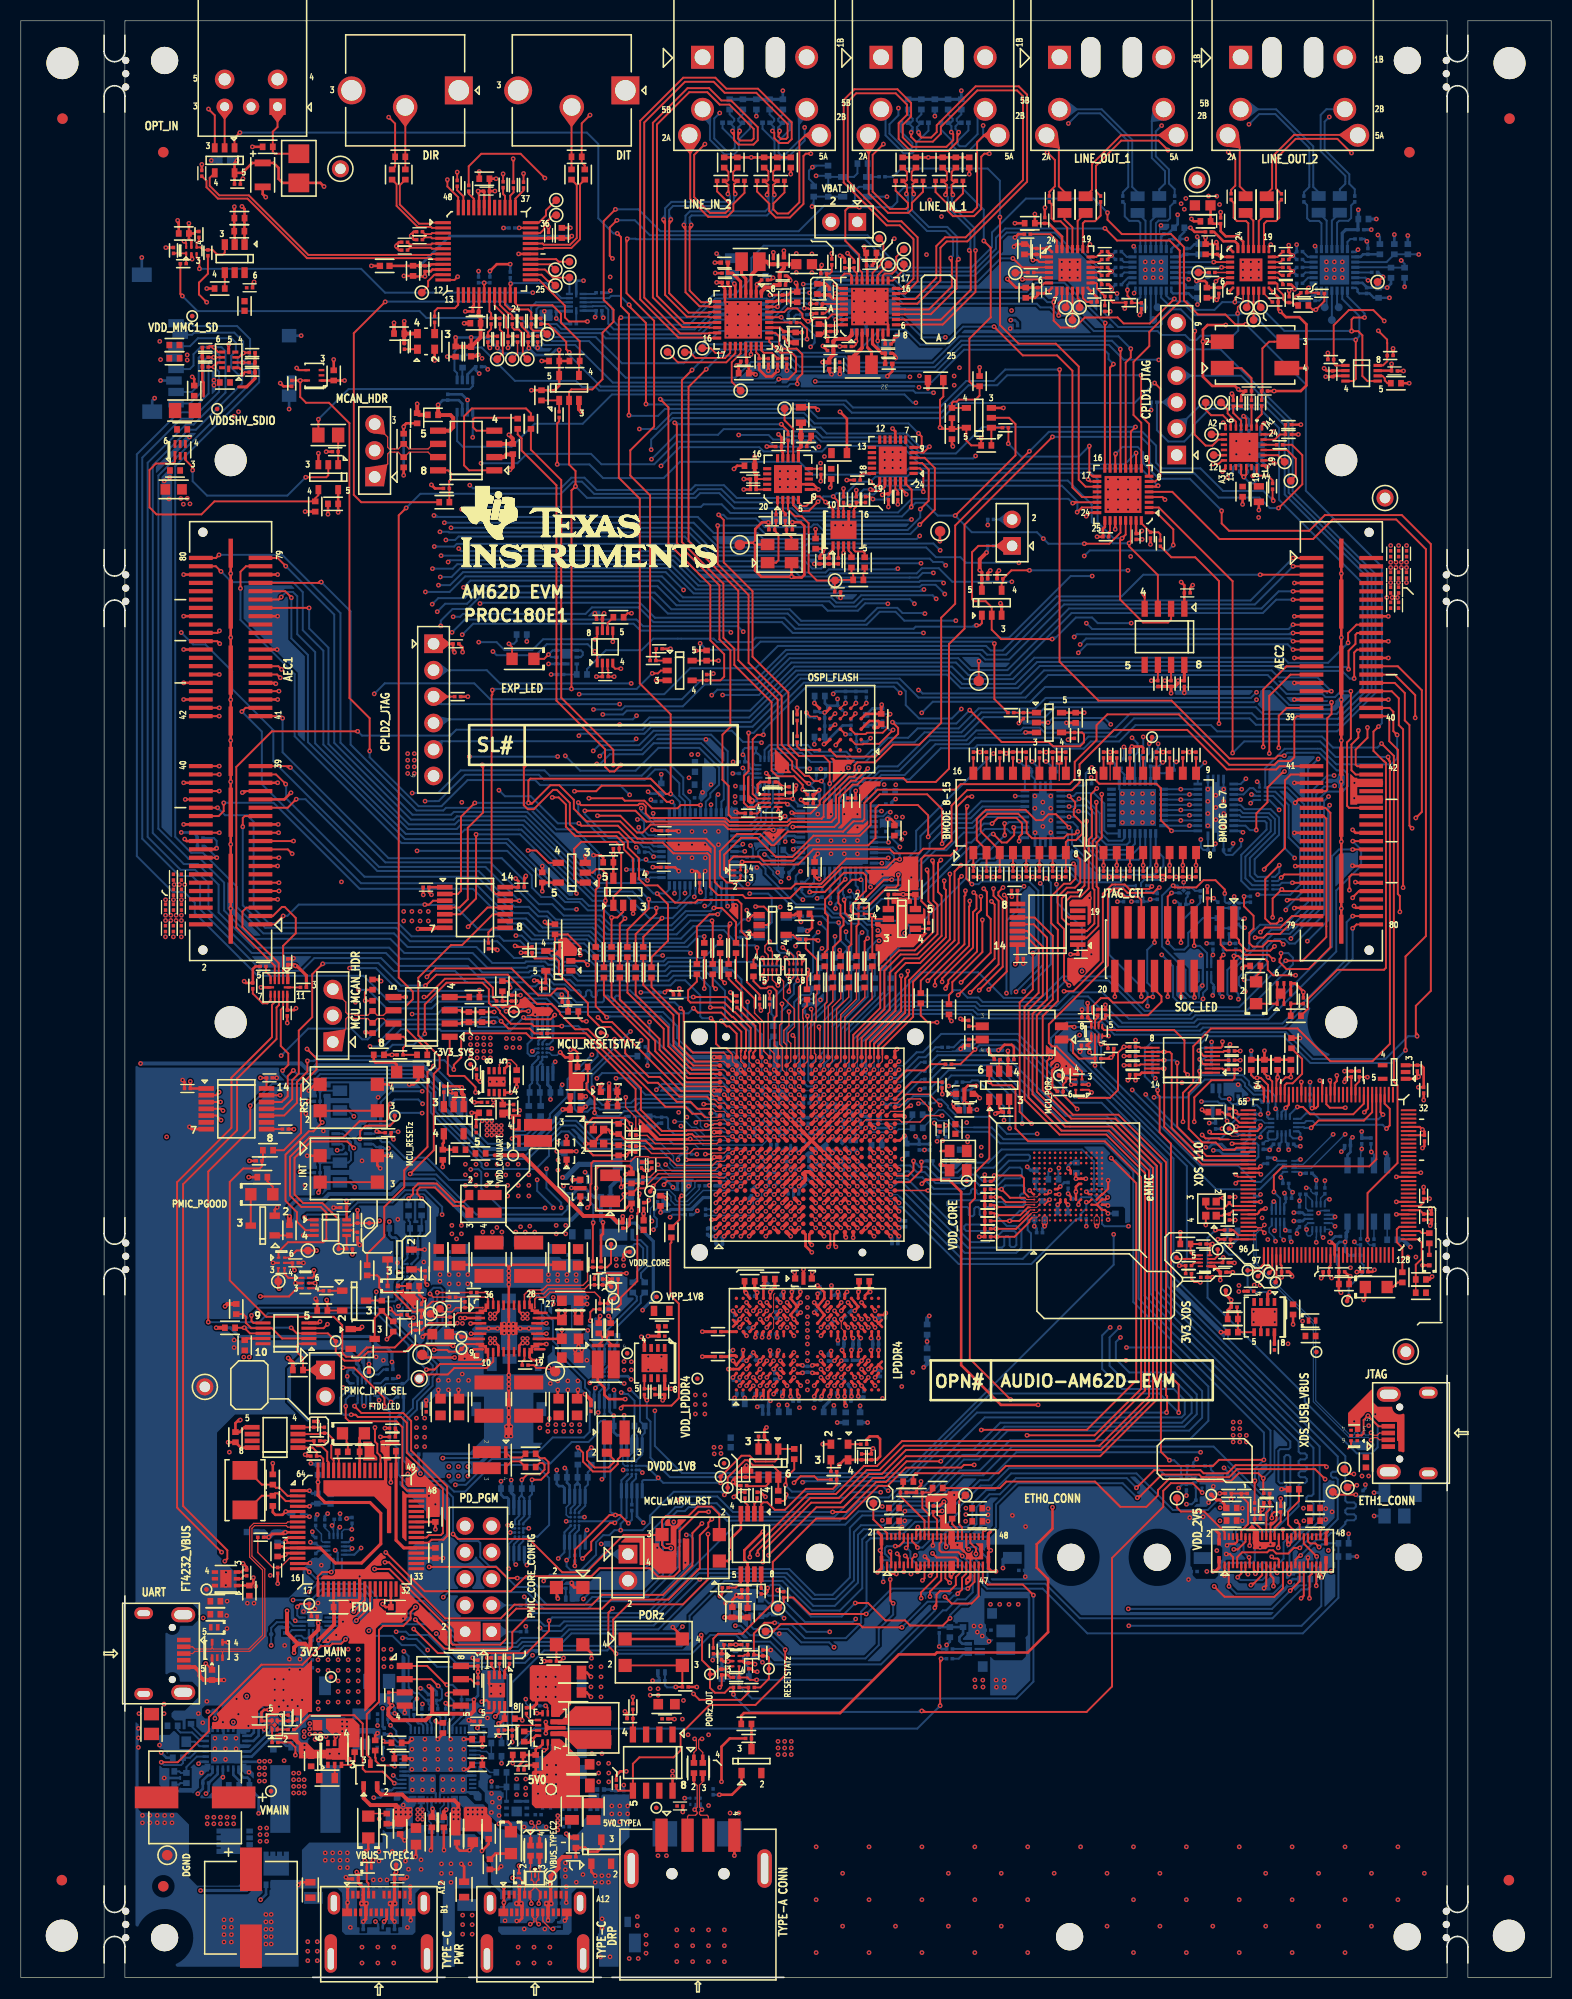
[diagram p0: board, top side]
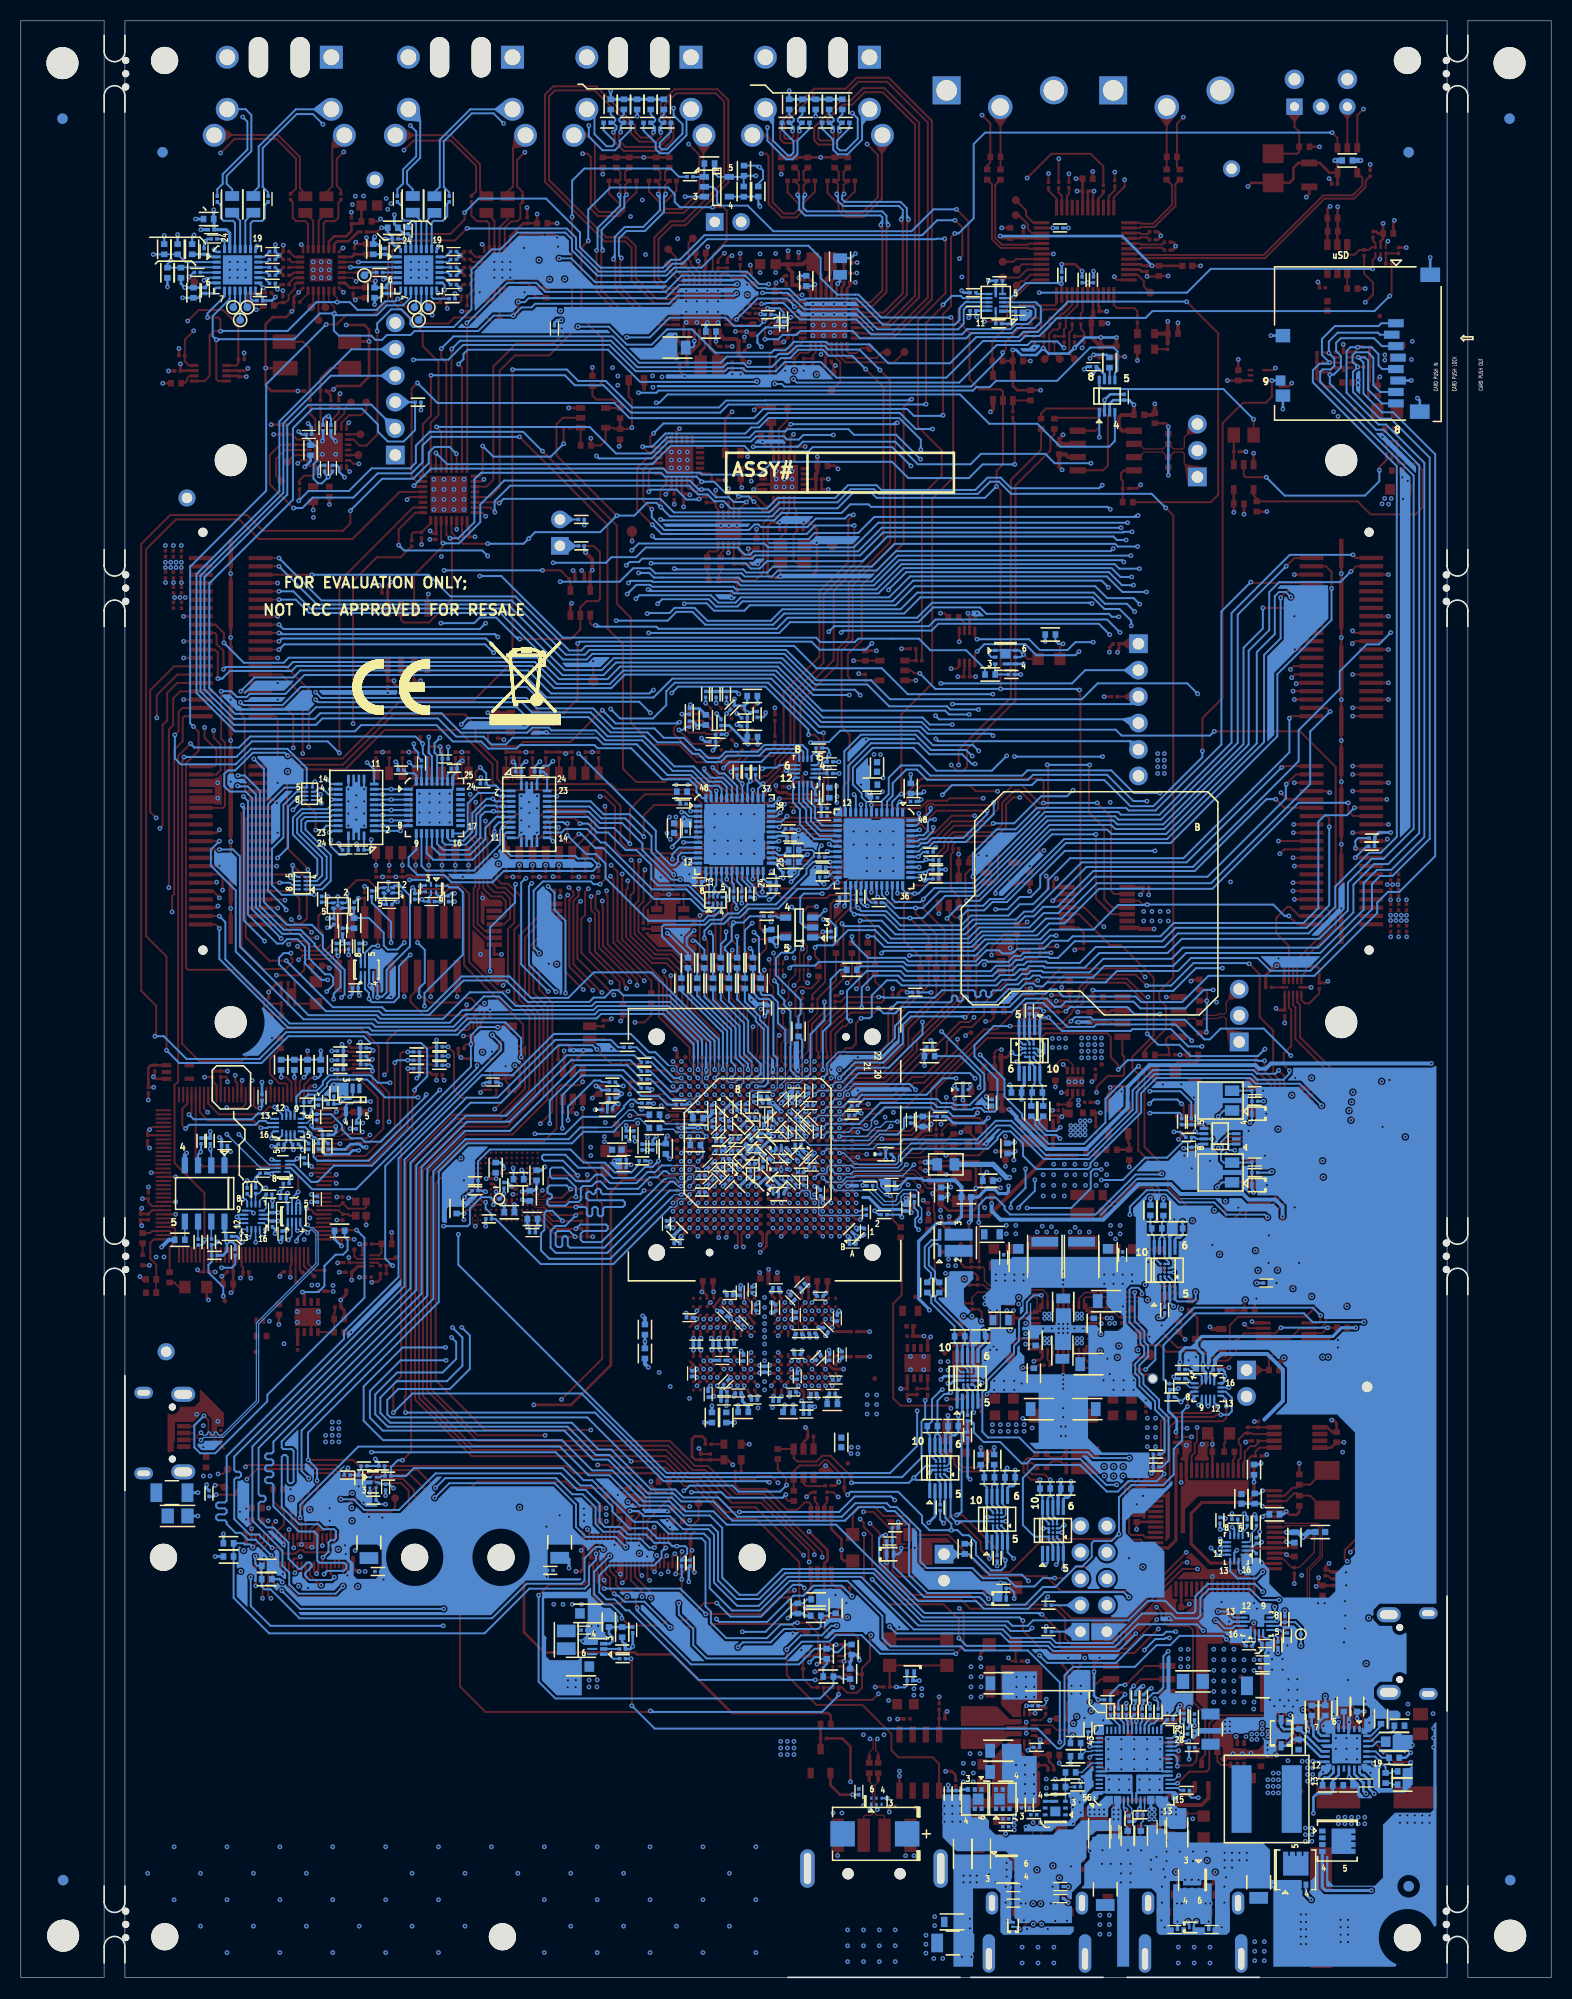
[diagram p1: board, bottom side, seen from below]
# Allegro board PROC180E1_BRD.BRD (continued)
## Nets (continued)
VCC3V3_TA: C136.1 C236.2 C391.2 C393.2 C394.2 C409.2 C529.2 R126.2 R127.2 R128.2 R129.2 R130.2 R131.2 R132.2 R133.2 R134.2 R135.2 R136.2 R137.2 R138.2 R139.2 R140.2 R141.2 R285.1 R439.2 R457.2 R461.2 R507.1 R511.1 R513.1 R516.1 R524.1 R526.1 R578.2 R582.1 R583.1 R643.2 U23.5(VCC) U51.8(VCCB) U81.1(VCCA) U82.27(VCCP) U82.31(VCC) U83.1(VCCA) U107.8(VCCB)
VCC3V3_XDS: C147.1 C192.1 C208.1 C221.1 C222.1 C231.2 C232.1 C234.1 C235.2 C241.1 C243.1 C430.2 C469.2 C473.2 C488.1 C500.2 C515.2 R118.1 R119.1 R236.1 R237.1 R241.1 R246.2 R277.2 R280.1 R306.1 R510.1 R512.1 R515.1 R517.1 R519.1 R520.2 R521.2 R522.2 R523.2 R525.1 R549.2 R551.1 R552.1 TP68.1(TP) U25.8(VCCB) U40.14(VCC) U48.7(VDD#7) U48.8(VDDA) U48.16(VDD#16) U48.26(VDD#26) U48.28(VDD#28) U48.39(VDD#39) U48.47(VDD#47) U48.51(VDD#51) U48.52(VDD#52) U48.69(VDD#69) U48.79(VDD#79) U48.90(VDD#90) U48.101(VDD#101) U48.113(VDD#113) U48.122(VDD#122) U51.1(VCCA) U55.3(OUT1) U55.4(OUT2) U97.2(VCCB) U102.8(VCCB) U107.1(VCCA) U109.8(VCCB)
VCC_0V85: C246.1 R587.1 U56.25(VOUT_LDO3)
VCC_1V8_FT4232: C263.1 C280.2 C281.2 C599.2 U64.12(VCORE#12) U64.37(VCORE#37) U64.49(VREGOUT) U64.64(VCORE#64)
VCC_1V8_IOVDD: C71.1 C74.1 C84.1 C85.1 C109.1 C166.1 C173.1 C340.1 C418.1 R20.1 R23.1 R60.1 R62.1 R67.1 R78.2 R90.2 R162.1 R413.2 R416.2 U7.27(IOVDD) U8.27(IOVDD) U14.5(VCC) U33.5(VCC) U35.5(VCC) U75.5(VCC) U89.5(VCC)
VCC_3V3_AVDD: C52.1 C53.2 C63.1 C68.1 C86.1 C90.1 C97.2 C98.1 FL2.2 L2.1 L3.1 U7.1(AVDD) U7.3(BSTVDD) U8.1(AVDD) U8.3(BSTVDD)
VCC_3V3_FT4232: C262.2 C264.2 C275.2 C285.1 C288.2 C289.2 C575.2 C612.2 C618.2 FL17.2 FL18.2 LD7.2(ANODE) R321.2 R328.2 R333.2 U61.8(VCC) U64.20(VCCIO#20) U64.31(VCCIO#31) U64.42(VCCIO#42) U64.50(VREGIN) U64.56(VCCIO#56) U66.1(OUT) U117.2(VCCB) U125.2(VCCB) U126.2(VCCB)
VCC_3V3_MAIN: C197.1 C199.2 C204.1 C230.2 C253.1 C255.1 C538.1 C546.1 C547.1 C555.1 C561.1 C565.1 C572.1 C576.1 C619.2 C621.2 C624.1 FL15.1 R240.1 R282.1 R302.2 R318.2 R371.1 R643.1 R659.2 R663.2 R668.2 TP80.1(TP) TP102.1(TP) U42.1(VIN1) U42.2(VIN2) U42.4(VBIAS) U46.1(IN) U52.5(VCC) U54.5(VCC) U56.3(VCCA) U56.12(PVIN_B3) U56.16(PVIN_B4) U56.18(VIO) U56.20(PVIN_LDO12) U56.30(PVIN_B2) U56.34(PVIN_B1) U57.10(VCC) U59.8(IN)
VCC_3V3_MAIN_PG: R640.1 R668.1 U54.3(B) U128.21(PG)
VCC_3V3_SYS: C28.1 C33.2 C37.1 C99.1 C113.1 C122.2 C123.1 C126.2 C127.1 C131.1 C132.1 C140.1 C143.1 C145.1 C150.2 C152.1 C153.1 C154.1 C156.1 C159.1 C165.2 C169.1 C178.1 C181.2 C183.1 C184.2 C185.2 C186.2 C187.2 C189.2 C191.2 C194.1 C268.2 C271.1 C274.1 C277.1 C279.1 C293.1 C298.1 C375.1 C377.1 C380.1 C392.2 C398.1 C399.1 C402.1 C403.1 C411.1 C413.1 C414.2 C415.2 C416.2 C419.2 C420.2 C427.1 C455.2 C470.2 C478.2 C498.1 C504.1 C511.2 C519.2 C520.1 C523.2 C525.1 C528.2 C560.1 C598.1 C601.1 C602.1 C604.1 C620.1 FL1.1 FL2.1 FL3.1 J8.1 J11.1 J14.5 J18.44 J18.46 J19.44 J19.46 R17.2 R18.2 R56.1 R58.1 R91.2 R92.2 R98.2 R99.1 R106.2 R115.1 R120.1 R142.1 R180.2 R211.1 R212.1 R220.1 R222.1 R225.1 R251.3 R259.1 R260.2 R288.1 R291.1 R292.2 R301.1 R324.2 R339.1 R342.1 R343.2 R344.1 R347.1 R351.2 R353.1 R354.1 R356.1 R360.1 R362.2 R363.2 R368.1 R396.1 R437.1 R440.2 R455.2 R459.1 R460.1 R469.1 R471.1 R473.1 R480.1 R482.1 R485.2 R533.2 R534.2 R536.2 R550.1 R554.2 R559.1 R597.2 R598.1 R601.2 R602.2 R603.1 R615.1 R616.2 R617.2 R620.2 R625.2 R629.2 R630.2 R638.2 R641.2 R645.1 TP48.1(TP) U2.5(VCC) U4.1(VIN) U11.7(VCCB) U17.3(VCC) U18.21(VCCP) U18.23(VCCI) U19.5(VCC) U21.27(VCCP) U21.31(VCC) U22.1(VDD) U22.3(VREF) U24.7(VCCB) U25.1(VCCA) U29.1(VCCA) U32.14(VCCB) U34.14(VCCB) U36.5(VCC) U37.11(VCCB) U38.3(VCC) U38.5(SHDN/VIO) U39.1(VCCA) U39.8(VCCB) U42.7(VOUT1) U42.8(VOUT2) U44.4(V+) U45.14(VCCB) U49.E6(VCC#E6) U49.F5(VCC#F5) U49.J10(VCC#J10) U49.K9(VCC#K9) U56.9(VMON1) U63.4(V+) U68.5(VCC) U70.8(VCC) U78.11(VCCB) U79.7(VCCB) U80.3(VCCA) U84.1(VCC#1) U84.25(VCC#25) U84.39(VCCIO0#39) U84.46(VCCIO0#46) U85.1(VCC#1) U85.25(VCC#25) U85.39(VCCIO0#39) U85.46(VCCIO0#46) U86.5(VCC) U87.5(VCC) U88.5(VCC) U90.1(VCCA) U90.8(VCCB) U91.6(VS) U92.B1(VS) U93.5(VCC) U97.3(VCCA) U98.8(VCC) U102.1(VCCA) U109.1(VCCA) U110.2(VCCB) U110.3(VCCA) U113.B1(VS) U114.6(VS) U115.B1(VS) U115.B3(A0) U116.2(A0) U116.6(VS) U118.2(A0) U118.6(VS) U119.B1(VS) U119.B3(A0) U120.5(VCC) U121.B1(VS) U121.C3(A1) U122.1(A1) U122.6(VS) U123.B1(VS) U123.B3(A0) U123.C3(A1) U124.1(A1) U124.2(A0) U124.6(VS) U127.6(VIN)
VCC_3V3_SYS_EN: R244.2 R245.2 U42.3(ON)
VCC_3V3_SYS_N: R251.1 R539.2
VCC_3V3_SYS_P: R251.4 R540.2
VCC_5V0: C115.1 C119.1 C128.1 C129.1 C130.1 C133.1 C134.1 C135.1 C170.1 C171.1 C172.1 C174.1 C175.1 C176.1 C297.1 C299.1 C311.1 C313.1 C314.1 C317.1 C318.1 C630.1 C633.1 C639.1 J12.2 J12.4 J12.6 J13.2 J13.4 J13.6 Q9.4(D1) Q9.7(D2) R387.2 R392.1 R543.1 R665.1 R676.1 TP103.1(TP) U16.2(IN) U72.7(VOUT) U74.2(IN1) U74.3(IN2)
VCC_5V0_EN: R647.2 U72.14(EN)
VCC_5V0_FB: C313.2 R391.1 R392.2 U72.5(FB)
VCC_5V0_PG: R388.2 U86.3(B)
VCC_CORE: C226.1 C227.1 C228.1 C229.1 C532.1 C533.1 C534.1 C535.1 C536.1 C537.1 L4.2 L5.2 R265.4 R577.1
VCC_CORE_N: R265.2 R572.2
VCC_CORE_P: R265.3 R571.2
VCC_LM5141: C627.1 D15.2(ANODE) U128.10(VCC)
VCC_SDIO: C108.1 R77.1 U16.5(OUT2) U16.6(OUT1)
VDD1_LPDDR4_1V8: C237.1 C539.1 C543.2 C551.1 C554.1 C571.1 C578.1 C581.1 C588.1 C591.1 C594.2 C596.1 FL16.2 U58.F1(VDD1#F1) U58.F12(VDD1#F12) U58.G4(VDD1#G4) U58.G9(VDD1#G9) U58.T4(VDD1#T4) U58.T9(VDD1#T9) U58.U1(VDD1#U1) U58.U12(VDD1#U12)
VDD_0V85_N: R581.1 R585.2
VDD_0V85_P: R581.4 R584.2
VDD_1V8_N: R311.2 R316.4
VDD_1V8_P: R310.2 R316.1
VDD_2V5: C272.1 C273.1 C276.1 C278.1 C614.1 C615.1 C616.1 J18.4 J18.6 J19.4 J19.6 L11.2 R634.1 R637.2 TP92.1(TP)
VDD_2V5_FB: C615.2 R632.1 R634.2 U127.3(FB)
VDD_CANUART: C224.1 C499.1 R257.2 TP52.1(TP) U47.H9(VDD_CANUART)
VDD_CORE: C441.1 C445.1 C448.1 C460.1 C462.1 C468.1 C477.1 C494.1 C657.1(IN/OUT) C657.3(OUT/IN) C658.1(IN/OUT) C658.3(OUT/IN) C659.1(IN/OUT) C659.3(OUT/IN) C660.1(IN/OUT) C660.3(OUT/IN) C661.1(IN/OUT) C661.3(OUT/IN) C662.1(IN/OUT) C662.3(OUT/IN) C663.1(IN/OUT) C663.3(OUT/IN) FL7.1 FL8.1 FL14.2 R265.1 TP53.1(TP) U47.J9(VDD_CORE#J9) U47.J11(VDD_CORE#J11) U47.J13(VDD_CORE#J13) U47.J15(VDD_CORE#J15) U47.K14(VDD_CORE#K14) U47.L9(VDD_CORE#L9) U47.L11(VDD_CORE#L11) U47.L13(VDD_CORE#L13) U47.M12(VDD_CORE#M12) U47.N11(VDD_CORE#N11) U47.N13(VDD_CORE#N13) U47.P10(VDD_CORE#P10) U47.P14(VDD_CORE#P14) U47.R9(VDD_CORE#R9) U47.R15(VDD_CORE#R15) U47.T16(VDD_CORE#T16) U47.U15(VDD_CORE#U15) U56.4(FB_B1)
VDD_CORE_0V85: R577.2 R581.3 R587.2
VDD_CORE_ALERT: R586.1 U113.A3(ALERT) U114.3(ALERT)
VDD_CORE_N: C524.2 R572.1 U113.D1(BUS) U113.D2(IN-) U114.8(VBUS) U114.9(IN-)
VDD_CORE_P: C524.1 R571.1 U113.D3(IN+) U114.10(IN+)
VDD_CORE_REG_SW1: L4.1 U56.33(SW_B1)
VDD_CORE_REG_SW2: L5.1 U56.31(SW_B2)
VDD_LPDDR4: C238.1 C239.1 C522.1 C526.1 C530.1 C531.1 C540.1 C541.2 C542.1 C544.1 C545.2 C548.1 C549.1 C550.1 C552.1 C553.1 C556.1 C557.1 C558.1 C562.1 C563.1 C564.1 C566.1 C567.1 C568.1 C569.1 C570.1 C573.1 C577.1 C579.1 C580.1 C582.1 C583.1 C584.2 C585.1 C586.1 C587.2 C589.1 C590.1 C595.1 C664.1(IN/OUT) C664.3(OUT/IN) C665.1(IN/OUT) C665.3(OUT/IN) C666.1(IN/OUT) C666.3(OUT/IN) C667.1(IN/OUT) C667.3(OUT/IN) C668.1(IN/OUT) C668.3(OUT/IN) C669.1(IN/OUT) C669.3(OUT/IN) C670.1(IN/OUT) C670.3(OUT/IN) R312.1 R315.1 R327.4 R589.2 R594.2 R595.2 TP83.1(TP) U47.A2(VDDS_DDR#A2) U47.AA1(VDDS_DDR#AA1) U47.AB2(VDDS_DDR#AB2) U47.B1(VDDS_DDR#B1) U47.J7(VDDS_DDR#J7) U47.K8(VDDS_DDR#K8) U47.L7(VDDS_DDR#L7) U47.L8(VDDS_DDR_C) U47.M8(VDDS_DDR#M8) U47.N7(VDDS_DDR#N7) U47.P8(VDDS_DDR#P8) U56.22(FB_B4) U58.A4(VDD2#A4) U58.A9(VDD2#A9) U58.AA3(VDDQ#AA3) U58.AA5(VDDQ#AA5) U58.AA8(VDDQ#AA8) U58.AA10(VDDQ#AA10) U58.AB4(VDD2#AB4) U58.AB9(VDD2#AB9) U58.B3(VDDQ#B3) U58.B5(VDDQ#B5) U58.B8(VDDQ#B8) U58.B10(VDDQ#B10) U58.D1(VDDQ#D1) U58.D5(VDDQ#D5) U58.D8(VDDQ#D8) U58.D12(VDDQ#D12) U58.F3(VDDQ#F3) U58.F5(VDD2#F5) U58.F8(VDD2#F8) U58.F10(VDDQ#F10) U58.H1(VDD2#H1) U58.H5(VDD2#H5) U58.H8(VDD2#H8) U58.H12(VDD2#H12) U58.K1(VDD2#K1) U58.K3(VDD2#K3) U58.K10(VDD2#K10) U58.K12(VDD2#K12) U58.N1(VDD2#N1) U58.N3(VDD2#N3) U58.N10(VDD2#N10) U58.N12(VDD2#N12) U58.R1(VDD2#R1) U58.R5(VDD2#R5) U58.R8(VDD2#R8) U58.R12(VDD2#R12) U58.U3(VDDQ#U3) U58.U5(VDD2#U5) U58.U8(VDD2#U8) U58.U10(VDDQ#U10) U58.W1(VDDQ#W1) U58.W5(VDDQ#W5) U58.W8(VDDQ#W8) U58.W12(VDDQ#W12)
VDD_LPDDR4_ALERT: R619.1 U121.A3(ALERT) U122.3(ALERT)
VDD_LPDDR4_N: C600.2 R599.1 U121.D1(BUS) U121.D2(IN-) U122.8(VBUS) U122.9(IN-)
VDD_LPDDR4_P: C600.1 R600.1 U121.D3(IN+) U122.10(IN+)
VDD_MMC1: C69.1 FL4.1 U4.5(QOD) U4.6(VOUT)
VDD_MMC1_SD: C88.2 C93.2 FL4.2 J26.4(VDD) TP21.1(TP)
VDDA1V8: C254.1 C290.1 FL10.2 R316.2 U56.19(VOUT_LDO1)
VDDA_1V8: C198.1(IN/OUT) C198.3(OUT/IN) C202.1 C423.1 C424.1 C431.1 C439.1 C442.1(IN/OUT) C442.3(OUT/IN) C483.1 C486.1 FL6.1 FL9.1 FL13.1 R316.3 TP79.1(TP) U47.G18(VDDA_TEMP1) U47.L10(VDDA_TEMP2) U47.P16(VDDA_TEMP0) U47.T10(VDDA_1P8_USB)
VDDA_1V8_ALERT: R608.1 U118.3(ALERT) U119.A3(ALERT)
VDDA_1V8_FB1: C456.1 C459.1 C463.1 C464.1 C480.1 C485.1 C501.1 FL13.2 U47.J10(VDDA_MCU) U47.K10(VDDA_PLL4) U47.K13(VDDA_PLL3) U47.M13(VDDA_PLL2) U47.N9(VDDA_PLL0) U47.R11(VDDA_PLL1)
VDDA_1V8_FB2: C206.1 C467.1 FL6.2 U47.T12(VDDA_1P8_CSIRX0)
VDDA_1V8_FB_OSC: C219.1 C508.1 FL9.2 U47.J8(VDDS_OSC0)
VDDA_1V8_N: C597.2 R311.1 U118.8(VBUS) U118.9(IN-) U119.D1(BUS) U119.D2(IN-)
VDDA_1V8_P: C597.1 R310.1 U118.10(IN+) U119.D3(IN+)
VDDA_CORE_CSI: C472.1 C474.1 C475.1 C479.1 FL7.2 U47.T11(VDDA_CORE_CSIRX0)
VDDA_CORE_USB: C487.1 C495.1 C497.1 FL8.2 U47.T9(VDDA_CORE_USB)
VDDA_DDR_PLL0: C211.1 C212.1 C491.1 FL14.1 U47.M9(VDDA_DDR_PLL0)
VDDA_LM5141: C625.2 U128.1(DEMB) U128.2(VDDA) U128.5(DITH) U128.19(FB)
VDDA_SYS_MON: C449.2 R543.2 R545.1 U47.H12(VMON_VSYS)
VDDC_1V2: C233.1 C240.1 C516.2 U48.87(VDDC#87) U48.115(VDDC#115)
VDDIM: C521.1 C527.1 U49.C2(VDDIM)
VDDR_CORE: C214.1(IN/OUT) C214.3(OUT/IN) C447.1 C465.1 C466.1 C481.1(IN/OUT) C481.3(OUT/IN) C490.1 C493.1 C505.1 R272.1 R581.2 TP60.1(TP) U47.J14(VDDR_CORE#J14) U47.K12(VDDR_CORE#K12) U47.M10(VDDR_CORE#M10) U47.M14(VDDR_CORE#M14) U47.P9(VDDR_CORE#P9) U47.P12(VDDR_CORE#P12)
VDDR_CORE_ALERT: R596.1 U115.A3(ALERT) U116.3(ALERT)
VDDR_CORE_N: C559.2 R585.1 U115.D1(BUS) U115.D2(IN-) U116.8(VBUS) U116.9(IN-)
VDDR_CORE_P: C559.1 R584.1 U115.D3(IN+) U116.10(IN+)
VDDSHV_SDIO: C103.2 C201.1 R54.2 R55.2 R57.2 R64.2 R65.2 R66.2 R71.1 R77.2 R243.1 TP35.1(TP) U10.10(VCC)
VDDSHV_SDIO_EN: R19.1 U16.3(EN2) U19.2(B)
VINT_LDO: C249.1 TP74.1(TP) U56.7(VOUT_LDOVINT)
1588_SFD_1: J18.38 TP93.1(TP)
1588_SFD_2: J19.38 TP87.1(TP)
ADCIN1: R679.2 R681.1 U129.6(ADCIN1)
ADCIN2: R678.2 R682.1 U129.10(ADCIN2)
ADDR0_IO_EXP: R107.1 U21.26(ADDR)
ADDR1_IO_EXP: R94.1 U18.18(ADDR)
AUDIO_EXT_REFCLK0: R470.1 R538.2
AUDIO_EXT_REFCLK1: R466.1 R506.2
AUDIO_EXT_REFCLK1__R: R506.1 U47.K17(GPMC0_WPN)
BOOTMODE0: RA5.1 U81.14(B8)
BOOTMODE1: RA5.2 U81.15(B7)
BOOTMODE2: RA5.3 U81.16(B6)
BOOTMODE3: RA5.4 U81.17(B5)
BOOTMODE4: RA6.4 U81.18(B4)
BOOTMODE5: RA6.3 U81.19(B3)
BOOTMODE6: RA6.2 U81.20(B2)
BOOTMODE7: RA6.1 U81.21(B1)
BOOTMODE8: RA7.1 U83.14(B8)
BOOTMODE9: RA7.2 U83.15(B7)
BOOTMODE10: RA7.3 U83.16(B6)
BOOTMODE11: RA7.4 U83.17(B5)
BOOTMODE12: RA1.2 U83.18(B4)
BOOTMODE13: RA2.2 U83.19(B3)
BOOTMODE14: RA1.1 U83.20(B2)
BOOTMODE15: RA2.1 U83.21(B1)
BOOTMODE_I2C_EN: R578.1 U107.5(EN)
BOOTMODE_I2C_SCL: R579.1 R583.2 TP71.1(TP) U82.29(SCL)
BOOTMODE_I2C_SDA: R580.1 R582.2 TP45.1(TP) U82.30(SDA)
BOOTMODEON: R112.2 U23.4(Y) U81.22(O\E\) U83.22(O\E\)
BUF_BOOTMODE_I2C0_SCL: R119.2 U25.7(SCLB) U48.82(PL1)
BUF_BOOTMODE_I2C0_SDA: R118.2 U25.6(SDAB) U48.81(PL0)
BUF_BOOTMODE_I2C_SCL: R552.2 U48.49(PG0) U107.2(SCLA)
BUF_BOOTMODE_I2C_SDA: R551.2 U48.50(PG1) U107.3(SDAA)
BUF_TEST_GPIO1: R519.2 U40.1(1A) U48.74(PM4)
BUF_TEST_GPIO2: R280.2 U48.73(PM5) U51.2(A1)
BUF_TEST_GPIO3: R515.2 U40.3(2A) U48.72(PM6)
BUF_TEST_GPIO4: R510.2 U40.5(3A) U48.71(PM7)
BUF_TEST_PORZN: R512.2 U40.9(4A) U48.77(PM1)
BUF_TEST_POWERDOWN: R525.2 U40.13(6A) U48.78(PM0)
BUF_TEST_WARMRESETN: R517.2 U40.11(5A) U48.76(PM2)
CAN_IO_3V3: C510.1 C512.1 C574.2 FL15.2 R309.2 R322.1 R326.1 R590.2 R592.1 R593.1 TP82.1(TP) U47.H8(VDDSHV_CANUART) U117.3(VCCA)
CAP_VDDS0: C454.1 U47.G13(CAP_VDDS0)
CAP_VDDS1: C434.1 U47.K16(CAP_VDDS1)
CAP_VDDS2: C446.1 U47.T14(CAP_VDDS2)
CAP_VDDS3: C432.1 U47.M16(CAP_VDDS3)
CAP_VDDS4: C507.1 U47.R8(CAP_VDDS4)
CAP_VDDS5: C443.1 U47.G15(CAP_VDDS5)
CAP_VDDS6: C435.1 U47.J16(CAP_VDDS6)
CAP_VDDS_CANUART: C509.1 U47.G8(CAP_VDDS_CANUART)
CAP_VDDS_MCU: C484.1 U47.G10(CAP_VDDS_MCU)
CLK_GEN_XI: R104.1 U20.1(XA)
CLK_GEN_XO: R105.1 U20.2(XB)
CLKOUT0: R336.2 R337.2 U65.1(CLKIN)
CLKOUT_OSC: R336.1 U62.3(OUT)
CLOCK_GENERATOR_SUPPLY: C112.1 C114.1 C116.1 C117.1 C118.1 C120.1 R92.1 U20.10(VDDOB) U20.14(VDDOD) U20.18(VDDOC) U20.20(VDD)
COMP_LM5141: C632.1 R670.1 U128.20(COMP)
CORE_CONFIG: R371.2 SW7.3 TP76.1(TP) U56.8(GPIO3)
CP_GEMAC_CPTS0_HW1TSPUSH: U47.B15(SPI0_D0) U85.2(PL2A)
CP_GEMAC_CPTS0_HW2TSPUSH: U47.E15(SPI0_D1) U85.8(PL3B)
CPLD1_1V8_BANK_SUPPLY: C155.1 C158.1 C406.1 C407.1 C412.1 FL12.2 U84.6(VCCIO3) U84.13(VCCIO2#13) U84.22(VCCIO2#22) U84.30(VCCIO1)
CPLD1_DONE: R142.2 U21.12(P13) U84.37(PT9D)
CPLD1_INTN: R460.2 U21.13(P14) U84.38(PT9C)
CPLD1_JTAGENB: R458.1 U18.3(P02) U84.41(PT9A)
CPLD1_PROGRAMN: R459.2 U18.4(P03) U84.40(PT9B)
CPLD1_TCK: J8.2 U84.45(PT7A)
CPLD1_TDI: J8.4 U84.47(PT6D)
CPLD1_TDO: J8.5 U84.48(PT6C)
CPLD1_TMS: J8.3 R437.2 U84.44(PT7B)
CPLD2_1V8_BANK_SUPPLY: C163.1 C397.1 C400.1 C401.1 C404.1 C405.1 C410.1 FL11.2 U85.6(VCCIO3) U85.13(VCCIO2#13) U85.22(VCCIO2#22) U85.30(VCCIO1)
CPLD2_DONE: R473.2 U21.10(P11) U85.37(PT9D)
CPLD2_INTN: R471.2 U21.11(P12) U85.38(PT9C)
CPLD2_JTAGENB: R467.1 U18.5(P04) U85.41(PT9A)
CPLD2_PROGRAMN: R469.2 U18.6(P05) U85.40(PT9B)
CPLD2_TCK: J11.2 U85.45(PT7A)
CPLD2_TDI: J11.4 U85.47(PT6D)
CPLD2_TDO: J11.5 U85.48(PT6C)
CPLD2_TMS: J11.3 R120.2 U85.44(PT7B)
CPLD/EXP1_MCASP0_ACLKR: J12.78 R174.2 R484.1
CPLD/EXP1_MCASP0_AFSR: J12.80 R189.2 U85.36(PR3C)
CPLD/EXP1_MCASP0_AFSX: J12.79 R173.2 U85.34(PR5A)
CPLD/EXP1_MCASP0_AXR0: J12.67 R188.2 U85.32(PR5C)
CPLD/EXP2_MCASP2_ACLKR: J13.43 R179.1 RA2.4 U33.2(A)
CPLD/EXP2_MCASP2_ACLKX: J13.37 R178.1 RA2.3 U84.23(PB9A)
CPLD/EXP2_MCASP2_AFSR: J13.41 R497.2 RA1.4 U85.21(PB4D)
CPLD/EXP2_MCASP2_AFSX: J13.39 R193.2 RA1.3 U85.24(PB9B)
CPLD/EXP2_MCASP2_AXR0: J13.27 R191.2 RA7.8 U84.14(PB2A)
CPLD/EXP2_MCASP2_AXR1: J13.29 R498.2 RA7.7 U84.15(PB2B)
CPLD/EXP2_MCASP2_AXR3: J13.28 R192.2 RA7.5 U84.16(PB2C)
CPLD/EXP2_MCASP2_AXR4: J13.30 R176.2 RA5.8 U84.17(PB2D)
CPLD/EXP2_MCASP2_AXR14: J13.70 R486.2 R500.2
CPLD/EXP2_MCASP2_AXR15: J13.72 R165.2 R190.2
CPLD_CDCE_CLKOUT_1: R89.1 U84.32(PR5C)
CPLD_CDCE_CLKOUT_2: R95.1 U84.34(PR5A)
CPLD_CLOCKIN: R87.1 U84.33(PR5B)
CPLD_CPSW_RGMII1_BCLK: J18.48 U29.3(A2)
CPLD_CPSW_RGMII1_BCLK_1V8: U29.6(B2) U84.35(PR3D)
CPLD_CPSW_RGMII1_COL: J18.14 U80.7(1A2)
CPLD_CPSW_RGMII1_COL_1V8: U80.14(1B2) U85.15(PB2B)
CPLD_CPSW_RGMII1_CRS: J18.30 U80.6(1A1)
CPLD_CPSW_RGMII1_CRS_1V8: U80.15(1B1) U85.14(PB2A)
CPLD_CPSW_RGMII2_BCLK: J19.48 U29.2(A1)
CPLD_CPSW_RGMII2_BCLK_1V8: U29.7(B1) U84.36(PR3C)
CPLD_CPSW_RGMII2_COL: J19.14 U80.9(2A2)
CPLD_CPSW_RGMII2_COL_1V8: U80.12(2B2) U85.17(PB2D)
CPLD_CPSW_RGMII2_CRS: J19.30 U80.8(2A1)
CPLD_CPSW_RGMII2_CRS_1V8: U80.13(2B1) U85.16(PB2C)
CPLD_ECAP0_APWM_OUT: U47.C16(SPI0_CS1) U85.11(PL5A)
CPLD_ECAP1_APWM_OUT: U47.E14(UART0_RXD) U85.12(PL5B)
CPLD_ECAP2_APWM_OUT: U47.D15(UART0_TXD) U85.7(PL3A)
CPLD_MCASP1_AFSR: J12.41 R169.2 U85.27(PR6C)
CPLD_MCASP1_AFSX: J12.39 R182.2 U85.26(PR6D)
CPLD_MCASP2_AFSR_R: R497.1 U47.T20(GPMC0_AD14)
CPLD_OBSCLK0: R209.2 RA7.6 U84.12(PL5B)
CPLD_OBSCLK0_R: R209.1 U47.R20(GPMC0_AD10)
CPLD_OBSCLK1: R204.2 U84.29(PR6A)
CPLD_UART0_RXD: R361.2 TP97.1(TP) U85.18(PB4A) U126.8(2A1)
CPLD_UART0_TXD: R631.2 TP117.1(TP) U85.19(PB4B) U126.6(1A1)
CPSW_ETH_INTN: R621.1 U32.11(B3)
CPSW_ETH_INTN_1V8: R205.1 U32.4(A3)
CPSW_RGMII1_BRD_CONN_DET: J18.36 R355.2
CPSW_RGMII1_ETH1_CLK: J18.28 R359.2
CPSW_RGMII1_MDC: J18.20 R338.2 R342.2
CPSW_RGMII1_MDIO: J18.22 R340.2 R343.1
CPSW_RGMII1_RD0: J18.23 U47.AB16(RGMII1_RD0)
CPSW_RGMII1_RD1: J18.25 U47.V15(RGMII1_RD1)
CPSW_RGMII1_RD2: J18.27 U47.W15(RGMII1_RD2)
CPSW_RGMII1_RD3: J18.29 U47.V14(RGMII1_RD3)
CPSW_RGMII1_RESETN: J18.12 R373.1 U68.4(Y)
CPSW_RGMII1_RX_DV: J18.45 U47.AA15(RGMII1_RX_CTL)
CPSW_RGMII1_RXC: J18.19 U47.AA16(RGMII1_RXC)
CPSW_RGMII1_TD0: J18.7 R530.2
CPSW_RGMII1_TD1: J18.9 R535.2
CPSW_RGMII1_TD2: J18.11 R537.2
CPSW_RGMII1_TD3: J18.13 R529.2
CPSW_RGMII1_TX_EN: J18.35 U47.W16(RGMII1_TX_CTL)
CPSW_RGMII1_TXC: J18.3 R239.2
CPSW_RGMII2_BRD_CONN_DET: J19.36 R341.2
CPSW_RGMII2_ETH2_CLK: J19.28 R358.2
CPSW_RGMII2_MDC: J19.20 R352.2 R356.2
CPSW_RGMII2_MDIO: J19.22 R345.2 R351.1
CPSW_RGMII2_RD0: J19.23 U47.AA21(RGMII2_RD0)
CPSW_RGMII2_RD1: J19.25 U47.Y20(RGMII2_RD1)
CPSW_RGMII2_RD2: J19.27 U47.AB21(RGMII2_RD2)
CPSW_RGMII2_RD3: J19.29 U47.AB20(RGMII2_RD3)
CPSW_RGMII2_RSTN: J19.12 R607.1 U120.4(Y)
CPSW_RGMII2_RX_DV: J19.45 U47.W18(RGMII2_RX_CTL)
CPSW_RGMII2_RXC: J19.19 U47.AA20(RGMII2_RXC)
CPSW_RGMII2_TD0: J19.7 R509.2
CPSW_RGMII2_TD1: J19.9 R518.2
CPSW_RGMII2_TD2: J19.11 R527.2
CPSW_RGMII2_TD3: J19.13 R528.2
CPSW_RGMII2_TX_EN: J19.35 U47.Y19(RGMII2_TX_CTL)
CPSW_RGMII2_TXC: J19.3 R228.2
CPSW_RGMII2_TXC_R: R228.1 U47.AB19(RGMII2_TXC)
CPSW_RGMII_INTN: J18.10 J19.10 R344.2 R346.1 R346.2 R620.1 R621.2
CPSW_RGMII_TXC_R: R239.1 U47.AB17(RGMII1_TXC)
CS_LM5141: C634.1 R667.1 U128.18(CS)
DAC_LAT_CTRL: R101.2 U18.2(P01)
DEBOUNCE_GPIO_INT_MCU_SOC: C489.2 D11.2 Q7.2(S) R559.2 SW5.2 SW5.3 U98.3(2A)
DEBOUNCE_MCU_RESETZ: C609.2 D12.2 R615.2 SW6.2 SW6.3 U98.1(1A)
DEBOUNCE_SOC_PORZ: C622.2 D14.2 R375.2 SW8.2 SW8.3 U50.1(1A)
DEBOUNCE_SOC_WARMRESETN: C425.2 D10.2 Q6.2(S) R532.2 SW4.2 SW4.3 U50.3(2A)
DIR: R461.1 U81.2(DIR) U83.2(DIR)
DIX4192_MCASP0_ACLKR: R481.2 U85.28(PR6B)
DIX4192_MCASP0_ACLKX: R14.2 U31.4(Y)
DIX4192_MCASP0_AFSR: R11.2 U85.35(PR3D)
DIX4192_MCASP0_AFSX: R15.2 U85.33(PR5B)
DIX4192_MCASP0_AXR0: R16.2 U85.31(PR5D)
DIX4192_MCASP0_AXR1: R13.2 U30.4(Y)
DIX_3V3_SYS: C9.1 C36.1 C39.1 C58.1 C59.1 C339.1 FL3.2 L1.1 R12.1 U1.5(VCC) U3.9(VCC) U3.33(VDD33)
DIX_ADDR0: R40.2 R49.1 R50.2
DIX_ADDR1: R43.2 R47.2 R48.1
DIX_BLS: R417.2 U3.35(BLS)
DIX_INT: U21.8(P07) U78.8(B3)
DIX_INT_1V8: R424.1 U3.23(I\N\T\) U78.4(A3)
DIX_MCLK: R463.2 U3.25(MCLK)
DIX_OP_IN_N: C4.1 U3.8(RX4-)
DIX_OP_IN_P: U1.4(Y) U3.7(RX4+)
DIX_RESETN: R59.1 U3.24(R\S\T\) U13.4(Y)
DIX_RVD_CLK: U3.12(RXCKO) U84.9(PL3C)
DIX_RX1: C8.2 J5.2 R1.1
DIX_RX1_N: C7.1 U3.2(RX1-)
DIX_RX1_P: C8.1 U3.1(RX1+)
DIX_RX2_N: C40.1 U3.4(RX2-)
DIX_RX2_P: C34.1 U3.3(RX2+)
DIX_RX3_N: C44.1 U3.6(RX3-)
DIX_RX3_P: C41.1 U3.5(RX3+)
DIX_TX: C5.2 J6.2 R2.1
DIX_TX_N: C6.1 U3.31(TX-)
DIX_TX_P: C5.1 U3.32(TX+)
DRAIN1: U129.8(DRAIN1_1) U129.15(DRAIN1_2) U129.19(DRAIN1_3) U129.58(DRAIN1_4)
DRAIN2: U129.7(DRAIN2_1) U129.52(DRAIN2_2) U129.56(DRAIN2_3) U129.57(DRAIN2_4)
EEPROM_A0: R370.1 U70.1(A0)
EEPROM_A1: R369.1 U70.2(A1)
EEPROM_A2: R368.2 U70.3(A2)
EEPROM_WP: J20.1 R617.1 U70.7(WP)
EMMC_RSTN: R117.2 U26.4(Y) U49.K5(RST_N)
EN_LM5141_ON: R661.1 U128.23(EN)
EXP1_CLK_IN: J12.33 U84.3(PL2B)
EXP1_CLK_OUT: J12.47 U84.2(PL2A)
EXP1_GPIO0_1: J12.24 U47.K22(OSPI0_LBCLKO)
EXP1_GPIO0_13: J12.32 U47.K20(OSPI0_CSN2)
EXP1_GPIO0_14: J12.34 U47.G20(OSPI0_CSN3)
EXP1_GPIO0_31: J12.38 U47.N22(GPMC0_CLK)
EXP1_GPIO0_32: J12.40 U47.L18(GPMC0_ADVN_ALE)
EXP1_GPIO0_33: J12.42 U47.L17(GPMC0_OEN_REN)
EXP1_GPIO0_34: J12.44 U47.K19(GPMC0_WEN)
EXP1_GPIO0_35: J12.52 U47.L19(GPMC0_BE0N_CLE)
EXP1_GPIO0_37: J12.51 R201.2
EXP1_GPIO0_37_R: R201.1 U47.R18(GPMC0_WAIT0)
EXP1_GPIO0_38: J12.53 U47.R17(GPMC0_WAIT1)
EXP1_I2C2_SCL: J12.18 R465.2 U47.M22(GPMC0_CSN2)
EXP1_I2C2_SDA: J12.20 R464.2 U47.M20(GPMC0_CSN3)
EXP1_MCASP0_ACLKX: J12.77 R172.2 U31.2(A)
EXP1_MCASP0_AXR1: J12.69 R186.2 U30.2(A)
EXP1_MCASP0_AXR2: J12.71 R187.2
EXP1_MCASP0_AXR3: J12.73 R171.2
EXP1_MCASP1_ACLKR: J12.43 R185.2
EXP1_MCASP1_ACLKX: J12.37 R184.2
EXP1_MCASP1_AXR0: J12.27 R496.2
EXP1_MCASP1_AXR1: J12.29 R183.2
EXP1_MCASP1_AXR2: J12.28 R167.2
EXP1_MCASP1_AXR3: J12.30 R168.2
EXP1_TIMESTAMP0_IN: J12.9 U85.4(PL2C)
EXP1_TIMESTAMP1_IN: J12.11 U85.5(PL2D)
EXP2_CLK_IN: J13.33 U84.8(PL3B)
EXP2_CLK_OUT: J13.47 U84.7(PL3A)
EXP2_EHRPWM0_A: J13.3 U47.D16(SPI0_CS0)
EXP2_EHRPWM1_A: J13.5 U47.A17(SPI0_CLK)
EXP2_GPIO0_45: J13.42 U47.U22(GPIO0_45)
EXP2_GPIO0_46: J13.44 U47.U21(GPIO0_46)
EXP2_GPIO0_47: J13.51 U47.U20(GPIO0_47)
EXP2_GPIO0_48: J13.53 U47.U19(GPIO0_48)
EXP2_GPIO0_55: J13.77 U47.W22(GPIO0_55)
EXP2_GPIO0_56: J13.79 U47.W21(GPIO0_56)
EXP2_GPIO0_57: J13.78 U47.W20(GPIO0_57)
EXP2_GPIO0_58: J13.80 U47.W19(GPIO0_58)
EXP2_MCASP2_AXR5: J13.32 R499.2 RA5.7
EXP2_MCASP2_AXR5_R: R499.1 U47.N20(GPMC0_AD1)
EXP2_MCASP2_AXR6: J13.34 R493.2 RA5.6
EXP2_MCASP2_AXR6_R: R493.1 U47.N19(GPMC0_AD2)
EXP2_MCASP2_AXR7: J13.38 R494.2 RA5.5
EXP2_MCASP2_AXR7_R: R494.1 U47.N18(GPMC0_AD3)
EXP2_MCASP2_AXR8: J13.40 R495.2 RA6.5
EXP2_MCASP2_AXR8_R: R495.1 U47.N17(GPMC0_AD4)
EXP2_MCASP2_AXR9: J13.67 R492.2 RA6.6
EXP2_MCASP2_AXR9_R: R492.1 U47.P18(GPMC0_AD5)
EXP2_MCASP2_AXR10: J13.69 R491.2 RA6.7
EXP2_MCASP2_AXR10_R: R491.1 U47.P19(GPMC0_AD6)
EXP2_MCASP2_AXR11: J13.71 R177.2 RA6.8
EXP2_MCASP2_AXR11_R: R177.1 U47.P21(GPMC0_AD7)
EXP2_MCASP2_AXR12: J13.73 R501.2
EXP2_MCASP2_AXR12_R: R501.1 U47.M18(GPMC0_BE1N)
EXP2_MCASP2_AXR13: J13.68 R502.2
EXP2_MCASP2_AXR13_R: R502.1 U47.K18(GPMC0_DIR)
EXP2_MCU_SPI1_CS2: R563.1 U37.8(B3)
EXP2_MCU_SPI1_CS2_1V8: J13.24 U37.4(A3)
EXP2_TIMESTAMP0_IN: J13.9 U85.9(PL3C)
EXP2_TIMESTAMP1_IN: J13.11 U85.10(PL3D)
EXT_CLKOUT0: R170.1 R337.1
EXT_CLKOUT0_R: R170.2 R175.2 U47.B16(EXT_REFCLK1)
EXT_REFCLK1: R175.1 U84.28(PR6B)
EXT_VMON2_1: J18.2 TP95.1(TP)
EXT_VMON2_2: J19.2 TP94.1(TP)
FT4232_CPLD_UART0_RX_3V3: U64.26(BDBUS0) U126.13(2B1)
FT4232_CPLD_UART0_TX_3V3: U64.27(BDBUS1) U126.15(1B1)
FT4232_DO: R321.1 R323.2 U61.4(DO)
FT4232_EECLK: R328.1 U61.2(CLK) U64.62(EECLK)
FT4232_EECS: R333.1 U61.1(CS) U64.63(EECS)
FT4232_EEDATA: R323.1 U61.3(DI) U64.61(EEDATA)
FT4232_MCU_UART0_RX_3V3: U64.48(DDBUS0) U117.13(2B1)
FT4232_MCU_UART0_TX_3V3: U64.52(DDBUS1) U117.15(1B1)
FT4232_REF: R609.2 U64.6(REF)
FT4232_RESET: C282.2 R357.1 U64.14(R\E\S\E\T\)
FT4232_SOC_UART4_RX_3V3: U64.16(ADBUS0) U125.13(2B1)
FT4232_SOC_UART4_TX_3V3: U64.17(ADBUS1) U125.15(1B1)
FT4232_USB_DM: J22.2(D-) U64.7(DM) U67.5(IO2)
FT4232_USB_DP: J22.3(D+) U64.8(DP) U67.3(IO1)
FT4232_USB_VBUS: C287.2 C291.2 C295.1 D3.2 J22.1(VBUS) TP96.1(TP) U66.4(EN) U66.6(IN) U67.1(VCC)
FT4232_WKUP_UART0_RX_3V3: U64.38(CDBUS0) U117.12(2B2)
FT4232_WKUP_UART0_TX_3V3: U64.39(CDBUS1) U117.14(1B2)
FT_PWREN#: R330.1 U64.60(P\W\R\E\N\)
GPIO1_23_INTN: R108.1 R547.2 U79.1(B2)
GPIO1_23_INTN_1V8: U47.Y22(GPIO0_60) U79.4(A2)
GPIO2_BUF_EN: R277.1 R278.2 U51.5(OE)
GPIO_CPSW1_RST: R364.1 U21.2(P01)
GPIO_CPSW2_RST: R604.1 U21.1(P00)
GPIO_DIX_RST: R79.1 U21.6(P05)
GPIO_EMMC_RSTN: R116.1 U21.9(P10)
GPIO_MCU_SOC: R546.1 R547.1 U98.5(2Y)
GPIO_MCU_SOC_INTN: R546.2 R563.2 U47.B9(MCU_MCAN1_RX)
GPIO_OSPI_RSTN: R121.1 U47.G19(OSPI0_CSN1)
GPIO_PCM1_RST: R84.1 U21.17(P20)
GPIO_PCM2_RST: R414.1 U21.19(P22)
HB_LM5141: C629.2 D15.1(CATHODE) U128.11(HB)
HO_LM5141: R671.1 U128.13(HO)
HOL_LM5141: R671.2 U128.14(HOL) U131.4(GATE)
HW/SW_CTRL_SEL: R83.2 R85.1 U15.23(HW_SW_CTRL)
I2C0_SCL_R: R195.1 R200.2 R204.1 U47.D17(I2C0_SCL)
I2C_ADDR0_A0: J18.47 R641.1 R642.2
I2C_ADDR0_A2: J18.37 R638.1 R639.2
I2C_ADDR1_A0: J19.47 R628.2 R630.1
I2C_ADDR1_A2: J19.37 R626.2 R629.1
INA_ALERT: R305.2 R505.2 R586.2 R596.2 R597.1 R608.2 R619.2 TP46.1(TP)
IO_EXP0_INTN: R106.1 R108.2 U21.32(I\N\T\)
IO_EXP1_INTN: R98.1 U18.22(I\N\T\)
IO_EXP_ADDR: R456.1 U82.26(ADDR)
IO_EXP_OPT_EN: R12.2 U1.1(O\E\) U21.7(P06)
IO_EXP_TEST_LED: R441.1 U21.24(P27)
IO_MCAN0_STB: R102.2 U21.21(P24)
IO_MCAN1_STB: R223.2 U21.22(P25)
JTAG_CTI_RTCK: J14.9 R476.1
JTAG_CTI_TCK: J14.11 R485.1 R487.1 U87.1(B) U88.1(B)
JTAG_DIR: R569.2 U110.4(1DIR) U110.5(2DIR)
JTAG_EMU0: J14.13 R211.2 U39.7(B1)
JTAG_EMU1: J14.14 R212.2 U39.6(B2)
JTAG_EMU_RSTN: J14.15 R482.2 U86.6(C)
JTAG_TCK: R483.1 U110.14(1B2)
JTAG_TDI: J14.3 U110.12(2B2)
JTAG_TDIS: J14.4 R490.2
JTAG_TDO: J14.7 U90.7(B1)
JTAG_TMS: J14.1 U110.13(2B1)
JTAG_TRST#: J14.2 R489.2 U110.15(1B1)
LDO_1V8: C303.1 U129.35(LDO_1V8)
LDO_3V3: C292.1 C300.2 C319.2 R374.1 R378.1 R644.1 R646.1 R658.1 R660.1 R664.1 R678.1 R679.1 U69.8(VCC) U71.5(VCC) U129.9(LDO_3V3)
LO_LM5141: R650.1 U128.8(LO)
LOL_LM5141: R649.1 U128.7(LOL)
LPDDR4_CA0: U47.J5(DDR0_A0) U58.H2(CA0_A) U58.R2(CA0_B)
LPDDR4_CA1: U47.J2(DDR0_A1) U58.J2(CA1_A) U58.P2(CA1_B)
LPDDR4_CA2: U47.J4(DDR0_A2) U58.H9(CA2_A) U58.R9(CA2_B)
LPDDR4_CA3: U47.L4(DDR0_A3) U58.H10(CA3_A) U58.R10(CA3_B)
LPDDR4_CA4: U47.J1(DDR0_A4) U58.H11(CA4_A) U58.R11(CA4_B)
LPDDR4_CA5: U47.K5(DDR0_A5) U58.J11(CA5_A) U58.P11(CA5_B)
LPDDR4_CAL0: R573.1 U47.H6(DDR0_CAL0)
LPDDR4_CK_N: U47.L1(DDR0_CK0_N) U58.J9(CK_C_A) U58.P9(CK_C_B)
LPDDR4_CK_P: U47.M1(DDR0_CK0) U58.J8(CK_T_A) U58.P8(CK_T_B)
LPDDR4_CKE0: U47.P3(DDR0_CKE0) U58.J4(CKE0_A) U58.P4(CKE0_B)
LPDDR4_CKE1: U47.P5(DDR0_CKE1) U58.J5(CKE1_A) U58.P5(CKE1_B)
LPDDR4_CS0_A: U47.J6(DDR0_CS0_N) U58.H4(CS0_A)
LPDDR4_CS0_B: U47.M6(DDR0_RAS_N) U58.R4(CS0_B)
LPDDR4_CS1_A: U47.N4(DDR0_CS1_N) U58.H3(CS1_A)
LPDDR4_CS1_B: U47.M5(DDR0_CAS_N) U58.R3(CS1_B)
LPDDR4_DMI0: U47.C2(DDR0_DM0) U58.C3(DMI0_A)
LPDDR4_DMI1: U47.F3(DDR0_DM1) U58.C10(DMI1_A)
LPDDR4_DMI2: U47.U1(DDR0_DM2) U58.Y3(DMI0_B)
LPDDR4_DMI3: U47.W3(DDR0_DM3) U58.Y10(DMI1_B)
LPDDR4_DQ0: U47.A5(DDR0_DQ0) U58.B2(DQ0_A)
LPDDR4_DQ1: U47.B4(DDR0_DQ1) U58.C2(DQ1_A)
LPDDR4_DQ2: U47.B6(DDR0_DQ2) U58.E2(DQ2_A)
LPDDR4_DQ3: U47.D5(DDR0_DQ3) U58.F2(DQ3_A)
LPDDR4_DQ4: U47.C5(DDR0_DQ4) U58.F4(DQ4_A)
LPDDR4_DQ5: U47.C3(DDR0_DQ5) U58.E4(DQ5_A)
LPDDR4_DQ6: U47.B2(DDR0_DQ6) U58.C4(DQ6_A)
LPDDR4_DQ7: U47.A3(DDR0_DQ7) U58.B4(DQ7_A)
LPDDR4_DQ8: U47.E2(DDR0_DQ8) U58.B11(DQ8_A)
LPDDR4_DQ9: U47.F5(DDR0_DQ9) U58.C11(DQ9_A)
LPDDR4_DQ10: U47.E6(DDR0_DQ10) U58.E11(DQ10_A)
LPDDR4_DQ11: U47.G2(DDR0_DQ11) U58.F11(DQ11_A)
LPDDR4_DQ12: U47.G6(DDR0_DQ12) U58.F9(DQ12_A)
LPDDR4_DQ13: U47.G4(DDR0_DQ13) U58.E9(DQ13_A)
LPDDR4_DQ14: U47.E4(DDR0_DQ14) U58.C9(DQ14_A)
LPDDR4_DQ15: U47.D3(DDR0_DQ15) U58.B9(DQ15_A)
LPDDR4_DQ16: U47.T6(DDR0_DQ16) U58.AA2(DQ0_B)
LPDDR4_DQ17: U47.T4(DDR0_DQ17) U58.Y2(DQ1_B)
LPDDR4_DQ18: U47.U5(DDR0_DQ18) U58.V2(DQ2_B)
LPDDR4_DQ19: U47.R5(DDR0_DQ19) U58.U2(DQ3_B)
LPDDR4_DQ20: U47.P2(DDR0_DQ20) U58.U4(DQ4_B)
LPDDR4_DQ21: U47.R3(DDR0_DQ21) U58.V4(DQ5_B)
LPDDR4_DQ22: U47.T2(DDR0_DQ22) U58.Y4(DQ6_B)
LPDDR4_DQ23: U47.U3(DDR0_DQ23) U58.AA4(DQ7_B)
LPDDR4_DQ24: U47.Y2(DDR0_DQ24) U58.AA11(DQ8_B)
LPDDR4_DQ25: U47.V2(DDR0_DQ25) U58.Y11(DQ9_B)
LPDDR4_DQ26: U47.V4(DDR0_DQ26) U58.V11(DQ10_B)
LPDDR4_DQ27: U47.W5(DDR0_DQ27) U58.U11(DQ11_B)
LPDDR4_DQ28: U47.Y4(DDR0_DQ28) U58.U9(DQ12_B)
LPDDR4_DQ29: U47.AA3(DDR0_DQ29) U58.V9(DQ13_B)
LPDDR4_DQ30: U47.AA5(DDR0_DQ30) U58.Y9(DQ14_B)
LPDDR4_DQ31: U47.AB4(DDR0_DQ31) U58.AA9(DQ15_B)
LPDDR4_DQS0_N: U47.C1(DDR0_DQS0_N) U58.E3(DQS0_C_A)
LPDDR4_DQS0_P: U47.D1(DDR0_DQS0) U58.D3(DQS0_T_A)
LPDDR4_DQS1_N: U47.F1(DDR0_DQS1_N) U58.E10(DQS1_C_A)
LPDDR4_DQS1_P: U47.G1(DDR0_DQS1) U58.D10(DQS1_T_A)
LPDDR4_DQS2_N: U47.P1(DDR0_DQS2_N) U58.V3(DQS0_C_B)
LPDDR4_DQS2_P: U47.R1(DDR0_DQS2) U58.W3(DQS0_T_B)
LPDDR4_DQS3_N: U47.Y1(DDR0_DQS3_N) U58.V10(DQS1_C_B)
LPDDR4_DQS3_P: U47.W1(DDR0_DQS3) U58.W10(DQS1_T_B)
LPDDR4_ODT_CA_A: R595.1 U58.G2(ODT_CA_A)
LPDDR4_ODT_CA_B: R594.1 U58.T2(ODT_CA_B)
LPDDR4_RESET_N: R588.2 R589.1 U47.P6(DDR0_RESET0_N) U58.T11(RESET_N)
LPDDR4_ZQ0: R315.2 U58.A5(ZQ0)
LPDDR4_ZQ1: R312.2 U58.A8(ZQ1)
MCAN0_CAN_H: J9.1 R93.1 U17.7(CANH)
MCAN0_CAN_L: J9.3 R88.2 U17.6(CANL)
MCAN0_RX: R81.1 U47.C18(MCAN0_RX)
MCAN0_RX_R: R81.2 U17.4(RXD)
MCAN0_STB: R96.2 R102.1 U17.8(STB)
MCAN0_T: C107.1 R88.1 R93.2
MCAN0_TX: R82.2 U47.B17(MCAN0_TX)
MCAN0_TX_R: R82.1 U17.1(TXD)
MCAN1_CAN_H: J15.1 R215.1 U38.7(CANH)
MCAN1_CAN_L: J15.3 R208.2 U38.6(CANL)
MCAN1_RX_R: R199.2 U38.4(RXD)
MCAN1_STB: R222.2 R223.1 U38.8(STB)
MCAN1_T: C180.1 R208.1 R215.2
MCAN1_TX_R: R273.1 U38.1(TXD)
MCASP0_ACLKR_R: R481.1 U3.48(BCKB)
MCASP0_ACLKX_R: R14.1 U3.37(BCKA)
MCASP0_AFSR_R: R11.1 U3.47(LRCKB)
MCASP0_AFSX_R: R15.1 U3.38(LRCKA)
MCASP0_AXR0_R: R16.1 U3.45(SDOUTB)
MCASP0_AXR1_R: R13.1 U3.39(SDINA)
MCASP2_ACLKR_R: R179.2 U47.T21(GPMC0_AD15)
MCASP2_ACLKX_R: R178.2 U47.R21(GPMC0_AD13)
MCASP2_AFSX_R: R193.1 U47.T22(GPMC0_AD12)
MCASP2_AXR0_R: R191.1 U47.P22(GPMC0_AD8)
MCASP2_AXR1_R: R498.1 U47.R19(GPMC0_AD9)
MCASP2_AXR3_R: R192.1 U47.R22(GPMC0_AD11)
MCASP2_AXR4_R: R176.1 U47.N21(GPMC0_AD0)
MCASP2_AXR14_R: R500.1 U47.M19(GPMC0_CSN0)
MCASP2_AXR15_R: R190.1 U47.M21(GPMC0_CSN1)
MCU_I2C0_SCL: C188.1 R234.1 R296.1 R598.2
MCU_I2C0_SDA: C182.1 R210.1 R294.1 R603.2
MCU_INTN: R299.1 U47.B10(WKUP_CLKOUT0)
MCU_MCAN0_RX: R199.1 U47.E8(MCU_MCAN0_RX)
MCU_MCAN0_TX: R273.2 U47.C7(MCU_MCAN0_TX)
MCU_OSC0_XI: R249.2 R252.2 U47.A12(MCU_OSC0_XI)
MCU_OSC0_XO: R253.2 R254.2 U47.A11(MCU_OSC0_XO)
MCU_PORZ: R238.1 R242.2 TP49.1(TP) U43.4(Y) U47.A7(MCU_PORZ)
MCU_RESETSTATZ: TP47.1(TP) U47.D14(MCU_RESETSTATZ)
MCU_RESETZ: R550.2 TP50.1(TP) U47.C12(MCU_RESETZ) U98.7(1Y)
MCU_SAFETY_ERRORZ_1V8: TP54.1(TP) U32.5(A4) U47.B8(MCU_ERRORN)
MCU_SAFETY_ERRORZ_3V3: R281.1 U32.10(B4)
MCU_SPI0_CLK: R216.2 U45.13(B1)
MCU_SPI0_CLK_1V8: J12.17 U45.2(A1)
MCU_SPI0_CS0: U45.12(B2) U47.E11(MCU_SPI0_CS0)
MCU_SPI0_CS0_1V8: J12.23 U45.3(A2)
MCU_SPI0_D0: U45.11(B3) U47.A15(MCU_SPI0_D0)
MCU_SPI0_D0_1V8: J12.19 U45.4(A3)
MCU_SPI0_D1: U45.10(B4) U47.B12(MCU_SPI0_D1)
MCU_SPI0_D1_1V8: J12.21 U45.5(A4)
MCU_SPI1_CLK: R574.2 U34.13(B1)
MCU_SPI1_CLK_1V8: J13.17 U34.2(A1)
MCU_SPI1_CS0: U34.12(B2) U47.C10(WKUP_UART0_CTSN)
MCU_SPI1_CS0_1V8: J13.23 U34.3(A2)
MCU_SPI1_D0: U34.11(B3) U47.B11(MCU_UART0_CTSN)
MCU_SPI1_D0_1V8: J13.19 U34.4(A3)
MCU_SPI1_D1: U34.10(B4) U47.D10(MCU_UART0_RTSN)
MCU_SPI1_D1_1V8: J13.21 U34.5(A4)
MCU_TIMER_IO1: U37.10(B1) U47.C11(MCU_SPI0_CS1)
MCU_TIMER_IO1_1V8: J12.3 U37.2(A1)
MCU_TIMER_IO2: R570.1 U37.9(B2)
MCU_TIMER_IO2_1V8: J12.5 U37.3(A2)
MCU_UART0_RX_3V3: R326.2 U47.D8(MCU_UART0_RXD) U117.8(2A1)
MCU_UART0_TX_3V3: R592.2 U47.F8(MCU_UART0_TXD) U117.6(1A1)
MIC1_BIAS: C3.1 C329.1 C379.1 R7.1 R8.1 R9.1 R10.1 R405.1 R406.1 R407.1 R408.1 U7.6(MICBIAS)
MIC2_BIAS: C2.1 C330.1 C363.1 R3.1 R4.1 R5.1 R6.1 R409.1 R410.1 R411.1 R412.1 U8.6(MICBIAS)
MMC0_CLK: R558.1 R561.1 R565.2 U49.M6(CLK)
MMC1_CLK: J26.5(CLK) R54.1 R202.1 R207.1 U10.6(IO4)
MMC1_CLK_R: R207.2 U47.E22(MMC1_CLK)
MMC1_CMD: J26.3(CMD) R66.1 U10.1(IO1) U47.C21(MMC1_CMD)
MMC1_D0: J26.7(DAT0) R65.1 U10.8(IO6) U47.B22(MMC1_DAT0)
MMC1_D1: J26.8(DAT1) R57.1 U10.7(IO5) U47.D21(MMC1_DAT1)
MMC1_D2: J26.1(DAT2) R64.1 U10.2(IO2) U47.C22(MMC1_DAT2)
MMC1_D3: J26.2(CD/DAT3) R55.1 U10.3(IO3) U47.D22(MMC1_DAT3)
MMC1_SD_EN: R21.1 U21.4(P03)
MMC1_SD_LS_EN: R17.1 R19.2 U2.4(Y) U4.3(ON)
MMC1_SDCD: J26.9(CD) R70.1 U12.5(IO2) U47.E18(MMC1_SDCD)
MODE_SELECT: R425.1 R426.1 U3.18(CPM)
OPT_RX: MOD1.3(VOUT) U1.2(A)
OSC0: C217.2 U48.88(OSC0) Y5.3
OSC1: C223.2 U48.89(OSC1) Y5.1
OSPI0_CSN0: R206.2 U47.H21(OSPI0_CSN0)
OSPI_CLK: R197.1 R451.1 U28.B2(CK)
OSPI_CS: R206.1 R447.1 U28.C2(CS#)
OSPI_DQ0: R446.1 RA3.1 U28.D3(DQ0)
OSPI_DQ1: R450.1 RA3.2 U28.D2(DQ1)
OSPI_DQ2: R452.1 RA3.3 U28.C4(DQ2)
OSPI_DQ3: R449.1 RA3.4 U28.D4(DQ3)
OSPI_DQ4: R448.1 RA4.1 U28.D5(DQ4)
OSPI_DQ5: R445.1 RA4.2 U28.E3(DQ5)
OSPI_DQ6: R444.1 RA4.3 U28.E2(DQ6)
OSPI_DQ7: R443.1 RA4.4 U28.E1(DQ7)
OSPI_DQS: R453.1 U28.C3(DS)
OSPI_DQS_SOC: R453.2 R454.1 R504.1 U47.L21(OSPI0_DQS)
OSPI_INTN: R123.1 R125.1
OSPI_RSTN: R124.1 U27.4(Y) U28.A4(RESET#)
P2_PP_EXT_ENABLE: R669.1 U129.49(GPIO17/PP_EXT2)
PCM1_ADDR_0: R20.2 R26.1 U7.24(ADDR0_SCLK)
PCM1_ADDR_1: R22.1 R23.2 U7.23(ADDR1_MISO)
PCM1_AREG: C89.1 C378.1 U7.2(AREG)
PCM1_BSTOUT: C92.2 C96.1 U7.5(BSTOUT)
PCM1_DREG: C81.1 C82.1 U7.32(DREG)
PCM1_GPIO1: R34.2 R432.1 U7.28(GPIO1)
PCM1_IN1N: C17.2 R9.2 U7.10(IN1M)
PCM1_IN1P: C18.2 R10.2 U7.9(IN1P)
PCM1_IN2N: C15.2 R7.2 U7.12(IN2M)
PCM1_IN2P: C16.2 R8.2 U7.11(IN2P)
PCM1_IN3N: C334.2 R408.2 U7.14(IN3M)
PCM1_IN3P: C333.2 R407.2 U7.13(IN3P)
PCM1_IN4N: C332.2 R406.2 U7.16(IN4M)
PCM1_IN4P: C331.2 R405.2 U7.15(IN4P)
PCM1_INT: U21.15(P16) U78.10(B1)
PCM1_INT_1V8: R34.1 U78.2(A1)
PCM1_MCASP2_AXR14: R38.2 U7.29(SDOUT)
PCM1_RESETN: R68.2 R78.1 U7.22(SHDNZ) U14.4(Y)
PCM1_VREF: C87.1 U7.7(VREF)
PCM2_ADDR_0: R62.2 R63.1 U8.24(ADDR0_SCLK)
PCM2_ADDR_1: R60.2 R61.1 U8.23(ADDR1_MISO)
PCM2_AREG: C64.1 C368.1 U8.2(AREG)
PCM2_BSTOUT: C54.1 C60.2 U8.5(BSTOUT)
PCM2_IN1N: C13.2 R5.2 U8.10(IN1M)
PCM2_IN1P: C14.2 R6.2 U8.9(IN1P)
PCM2_IN2N: C11.2 R3.2 U8.12(IN2M)
PCM2_IN2P: C12.2 R4.2 U8.11(IN2P)
PCM2_IN3N: C338.2 R412.2 U8.14(IN3M)
PCM2_IN3P: C337.2 R411.2 U8.13(IN3P)
PCM2_IN4N: C336.2 R410.2 U8.16(IN4M)
PCM2_IN4P: C335.2 R409.2 U8.15(IN4P)
PCM2_INT: U21.16(P17) U78.9(B2)
PCM2_INT_1V8: R46.1 U78.3(A2)
PCM2_MCASP2_AXR14: R431.2 R433.1
PCM2_RESETN: R415.2 R416.1 U8.22(SHDNZ) U75.4(Y)
PCM2_VREF: C65.1 U8.7(VREF)
PCM6240_BUF_EN: R488.1 U35.1(OE) U84.10(PL3D) U89.1(OE)
PCM6240_MCASP2_ACLKR: R163.2 U7.30(BCLK) U8.30(BCLK)
PCM6240_MCASP2_AFSR: R468.2 U7.31(FSYNC) U8.31(FSYNC)
PCM6240_MCASP2_AXR14: R38.1 R431.1 U89.2(A)
PCM6240_MCASP2_AXR15: R435.1 U35.2(A)
PD_GPIO0: R674.2 U129.16(GPIO0)
PD_HRESET: C301.1 R662.1 U129.44(HRESET)
PD_I2C_IRQ: R645.2 R655.1 U21.23(P26)
PD_MS_I2C1_IRQ: R660.2 U129.29(I\2\C\1\_\I\R\Q\)
PD_MS_I2C1_SCL: R633.1 R664.2 U129.27(I2C1_SCL)
PD_MS_I2C1_SDA: R627.1 R658.2 U129.28(I2C1_SDA)
PD_S_I2C2_IRQ: R655.2 U129.34(I\2\C\2\_\I\R\Q\)
PD_S_I2C2_SCL: R657.2 U129.32(I2C2_SCL)
PD_S_I2C2_SDA: R656.2 U129.33(I2C2_SDA)
PD_SPI_CLK: J21.7 R652.2 U69.6(CLK)
PD_SPI_MISO: J21.5 R644.2 R654.2 U69.2(DO(IO1))
PD_SPI_MOSI: J21.8 R653.2 U69.5(DI(IO0))
PD_SPI_SS: J21.9 R646.2 R651.2 U69.1(C\S\)
PD_VIN_3V3: C320.2 U129.5(VIN_3V3)
PMIC_ADC_IN: TP84.1(TP) U56.11(GPIO5)
PMIC_EN: R317.2 U56.17(EN/PB/VSENSE)
PMIC_ENABLE: U54.6(C) U57.4(A)
PMIC_I2C_SCL: R297.2 TP72.1(TP) U56.1(SCL_I2C1/SCK_SPI)
PMIC_I2C_SDA: R307.2 TP73.1(TP) U56.2(SDA_I2C1/SDI_SPI)
PMIC_INT_B: R288.2 R299.2 R300.2 TP70.1(TP) U56.27(I\N\T\/EN_DRV)
PMIC_INTN: R300.1 U36.2(A)
PMIC_INTN_1V8: R164.1 R205.2 U36.4(Y) U47.F17(EXTINTN)
PMIC_LPM_EN0: R309.1 TP75.1(TP) U47.D12(PMIC_LPM_EN0) U57.3(A1) U57.8(B0)
PMIC_LPM_SEL: J16.1 R318.1 U57.1(SEL)
PMIC_NSLEEP: U56.10(GPIO4) U57.6(B)
PMIC_POWERGOOD: R290.1 U86.1(A)
PMIC_RSTOUT: R286.1 R290.2 R291.2 TP67.1(TP) U56.28(R\S\T\O\U\T\)
PORT1_15W: R386.1 U71.2(A)
PORT2_15W: R390.1 U71.1(B)
PORZ_OUT: R372.1 R376.2 TP101.1(TP) U2.6(C) U32.12(B2) U68.3(B) U120.3(B)
PORZ_OUT_1V8: J12.1 J13.1 U32.3(A2) U47.F18(PORZ_OUT)
PP1_CABLE: C309.1 U129.25(PP1_CABLE)
PP2_CABLE: C631.1 R665.2 U129.46(PP2_CABLE)
PRI/SEC_REF_SEL: R75.2 R76.1 U15.4(REFSEL)
RES_LM5141: C626.1 U128.24(RES)
RESETSTATZ: R365.1 R366.1 R377.2 R605.1 TP100.1(TP) U2.3(B) U13.2(B) U14.2(B) U18.24(R\E\S\E\T\) U21.28(R\E\S\E\T\) U26.2(B) U27.2(B) U32.13(B1) U75.2(B)
RESETSTATZ_1V8: U15.8(PDN) U32.2(A1) U47.F19(RESETSTATZ) U84.11(PL5A) U85.3(PL2B)
RGMII1_INH: J18.26 R353.2 TP65.1(TP) U52.3(B)
RGMII1_RX_ER: J18.39 TP99.1(TP)
RGMII1_RX_LINK: J18.43 R360.2 TP98.1(TP)
RGMII2_INH: J19.26 R354.2 TP59.1(TP) U52.6(C)
RGMII2_RX_ER: J19.39 TP89.1(TP)
RGMII2_RX_LINK: J19.43 R347.2 TP91.1(TP)
RT_LM5141: R648.1 U128.4(RT)
RXCKI: R39.2 U3.13(RXCKI)
RXCKI_OSC: R39.1 U9.3(OUT)
SEC_REF_N: R74.1 U15.2(SECREF_N)
SEC_REF_P: R73.1 U15.1(SECREF_P)
SEL_XDS: U39.5(OE) U93.4(Y) U97.1(1\O\E\) U97.16(2\O\E\) U109.4(O\E\)
SEL_XDS110_INV: J14.8 R531.2 R536.1 U87.2(A) U88.2(A) U90.4(O\E\) U93.2(A) U102.5(OE) U110.1(1\O\E\) U110.16(2\O\E\)
SIL5351B_VC: C139.1 R110.2 R113.2 TP43.1(TP) U20.3(VC)
SOC_CLKIN: R249.1 R349.2
SOC_DVDD1V8: C196.1(IN/OUT) C196.3(OUT/IN) C200.1 C422.1(IN/OUT) C422.3(OUT/IN) C426.1 C429.1 C433.1 C437.1 C440.1 C444.1 C453.1 C457.1 C461.1 C502.1 C506.1 FL16.1 R334.3 TP86.1(TP) U47.F12(VMON_1P8_SOC) U47.G14(VDDSHV0#G14) U47.H13(VDDSHV0#H13) U47.H16(VDDSHV6#H16) U47.H17(VDDSHV6#H17) U47.K15(VDDSHV1#K15) U47.L15(VDDSHV3#L15) U47.L16(VDDSHV1#L16) U47.M15(VDDSHV3#M15) U47.N15(VDDSHV3#N15) U47.T8(VDDSHV4#T8) U47.U8(VDDSHV4#U8) U56.24(FB_B3)
SOC_DVDD1V8_N: C603.2 R335.1 U123.D1(BUS) U123.D2(IN-) U124.8(VBUS) U124.9(IN-)
SOC_DVDD1V8_P: C603.1 R331.1 U123.D3(IN+) U124.10(IN+)
SOC_DVDD3V3: C210.1(IN/OUT) C210.3(OUT/IN) C450.1 C451.1 C452.1 C458.1 C471.1 C476.1 C482.1(IN/OUT) C482.3(OUT/IN) C492.1 C496.1 R251.2 U47.F9(VMON_3P3_SOC) U47.G11(VDDSHV_MCU#G11) U47.H10(VDDSHV_MCU#H10) U47.R13(VDDSHV2#R13) U47.T13(VDDSHV2#T13) U47.U10(VDDA_3P3_USB) U47.U13(VDDSHV2#U13)
SOC_DVDD3V3_N: C428.2 R539.1 U91.8(VBUS) U91.9(IN-) U92.D1(BUS) U92.D2(IN-)
SOC_DVDD3V3_P: C428.1 R540.1 U91.10(IN+) U92.D3(IN+)
SOC_EMU0: R225.2 SW3.1 U39.2(A1) U47.C13(EMU0) U102.2(A1)
SOC_EMU1: R220.2 SW3.2 U39.3(A2) U47.E10(EMU1) U102.3(A2)
SOC_GPIO1_49: R213.1 U47.D18(MMC1_SDWP)
SOC_I2C0_SCL: J18.40 J19.40 R56.2 R332.1 R622.2 R625.1 U11.8(SCL_B) U18.19(SCL) U20.4(SCL) U21.29(SCL) U22.9(SCL) U25.2(SCLA) U44.1(SCL) U84.43(PT8C) U85.43(PT8C)
SOC_I2C0_SCL_1V8: R51.2 R195.2 U5.7(SCL) U6.7(SCL) U7.25(SCL_MOSI) U8.25(SCL_MOSI) U11.5(SCL_A) U15.12(SCL/GPIO3) U76.7(SCL) U77.7(SCL)
SOC_I2C0_SCL_R1: R332.2 R657.1 TP88.1(TP) U63.1(SCL) U70.6(SCL) U91.1(A1) U91.5(SCL) U92.A1(SCL) U92.C3(A1) U113.A1(SCL) U114.5(SCL) U115.A1(SCL) U116.5(SCL) U118.1(A1) U118.5(SCL) U119.A1(SCL) U119.C3(A1) U121.A1(SCL) U121.B3(A0) U122.2(A0) U122.5(SCL) U123.A1(SCL) U124.5(SCL)
SOC_I2C0_SDA: J18.42 J19.42 R58.2 R350.1 R616.1 R618.2 U11.1(SDA_B) U18.20(SDA) U20.5(SDA) U21.30(SDA) U22.10(SDA) U25.3(SDAA) U44.6(SDA) U84.42(PT8D) U85.42(PT8D)
SOC_I2C0_SDA_1V8: R45.2 R514.2 U5.8(SDA) U6.8(SDA) U7.26(SDA_SSZ) U8.26(SDA_SSZ) U11.4(SDA_A) U15.19(SDA/GPIO2) U76.8(SDA) U77.8(SDA)
SOC_I2C0_SDA_R1: R350.2 R656.1 TP90.1(TP) U63.6(SDA) U70.5(SDA) U91.4(SDA) U92.A2(SDA) U113.A2(SDA) U114.4(SDA) U115.A2(SDA) U116.4(SDA) U118.4(SDA) U119.A2(SDA) U121.A2(SDA) U122.4(SDA) U123.A2(SDA) U124.4(SDA)
SOC_I2C1_SCL: J13.18 R503.2 U47.C17(I2C1_SCL)
SOC_I2C1_SDA: J13.20 R198.2 U47.E17(I2C1_SDA)
SOC_MMC0_CLK: R558.2 U47.AB7(MMC0_CLK)
SOC_MMC0_CMD: R575.2 U47.Y6(MMC0_CMD) U49.M5(CMD)
SOC_MMC0_DAT0: R269.2 U47.AA6(MMC0_DAT0) U49.A3(DAT0)
SOC_MMC0_DAT1: R266.2 U47.AB6(MMC0_DAT1) U49.A4(DAT1)
SOC_MMC0_DAT2: R263.2 U47.Y7(MMC0_DAT2) U49.A5(DAT2)
SOC_MMC0_DAT3: R275.2 U47.AA7(MMC0_DAT3) U49.B2(DAT3)
SOC_MMC0_DAT4: R270.2 U47.Y8(MMC0_DAT4) U49.B3(DAT4)
SOC_MMC0_DAT5: R267.2 U47.W7(MMC0_DAT5) U49.B4(DAT5)
SOC_MMC0_DAT6: R264.2 U47.W9(MMC0_DAT6) U49.B5(DAT6)
SOC_MMC0_DAT7: R262.2 U47.AB8(MMC0_DAT7) U49.B6(DAT7)
SOC_OSPI_CLK: R197.2 U47.L22(OSPI0_CLK)
SOC_OSPI_DQ0: RA3.8 U47.J21(OSPI0_D0)
SOC_OSPI_DQ1: RA3.7 U47.J18(OSPI0_D1)
SOC_OSPI_DQ2: RA3.6 U47.J19(OSPI0_D2)
SOC_OSPI_DQ3: RA3.5 U47.H18(OSPI0_D3)
SOC_OSPI_DQ4: RA4.8 U47.K21(OSPI0_D4)
SOC_OSPI_DQ5: RA4.7 U47.H19(OSPI0_D5)
SOC_OSPI_DQ6: RA4.6 U47.J20(OSPI0_D6)
SOC_OSPI_DQ7: RA4.5 U47.J22(OSPI0_D7)
SOC_PORZ: R480.2 U43.3(B) U86.4(Y)
SOC_PORZ_PB: R268.2 TP55.1(TP) U43.1(A) U50.7(1Y)
SOC_RGMII_MDC: R338.1 R352.1 R548.2
SOC_RGMII_MDIO: R340.1 R345.1 R541.2
SOC_TCK: R534.1 R544.1 R566.1 U47.A14(TCK)
SOC_TDI: R554.1 U47.A16(TDI) U97.6(1A1) U110.9(2A2)
SOC_TDO: R542.1 U90.2(A1) U109.2(A1)
SOC_TMS: R533.1 U47.B14(TMS) U97.8(2A1) U110.8(2A1)
SOC_TRST#: R564.1 U47.F15(TRSTN) U97.9(2A2) U110.6(1A1)
SOC_USB0_DM: L10.4(OUT2) R400.1 U47.AA10(USB0_DM)
SOC_USB0_DP: L10.1(IN1) R399.1 U47.AA9(USB0_DP)
SOC_USB0_DRVVBUS: U24.5(A1) U47.C20(USB0_DRVVBUS)
SOC_USB0_DRVVBUS_3V3: R673.1 R674.1 U24.8(B1)
SOC_USB0_RCALIB: R553.1 U47.W10(USB0_RCALIB)
SOC_USB0_VBUS: R398.1 R560.1 U47.V8(USB0_VBUS)
SOC_USB1_DM: L9.1(IN1) R393.1 U47.Y11(USB1_DM)
SOC_USB1_DP: L9.4(OUT2) R394.1 U47.Y10(USB1_DP)
SOC_USB1_DRVVBUS: U24.4(A2) U47.D19(USB1_DRVVBUS)
SOC_USB1_DRVVBUS_3V3: R379.1 U24.1(B2)
SOC_USB1_RCALIB: R557.1 U47.U7(USB1_RCALIB)
SOC_USB1_VBUS: R384.1 R567.1 U47.V6(USB1_VBUS)
SOC_VDDSHV5_SDIO: C436.1 C438.1 R243.2 U47.G16(VDDSHV5#G16) U47.H15(VDDSHV5#H15)
SOC_WARM_RESETZ: R279.1 TP57.1(TP) U47.E19(RESET_REQZ) U50.5(2Y)
SPI_HOLDN: R374.2 U69.7(H\O\L\D\(IO3))
SPI_WPN: R378.2 U69.3(W\P\(IO2))
SS_LM5141: C628.1 U128.22(SS)
SW_2V5: L11.1 U127.5(SW)
SW_LM5141: C629.1 L12.1 Q11.5(D) U128.12(SW) U131.1(S1) U131.2(S2) U131.3(S3)
SYS_BOOTMODE0: R153.1 SW2.1 U81.10(A8) U82.1(P00)
SYS_BOOTMODE1: R154.1 SW2.2 U81.9(A7) U82.2(P01)
SYS_BOOTMODE2: R155.1 SW2.3 U81.8(A6) U82.3(P02)
SYS_BOOTMODE3: R156.1 SW2.4 U81.7(A5) U82.4(P03)
SYS_BOOTMODE4: R157.1 SW2.5 U81.6(A4) U82.5(P04)
SYS_BOOTMODE5: R158.1 SW2.6 U81.5(A3) U82.6(P05)
SYS_BOOTMODE6: R159.1 SW2.7 U81.4(A2) U82.7(P06)
SYS_BOOTMODE7: R160.1 SW2.8 U81.3(A1) U82.8(P07)
SYS_BOOTMODE8: R145.1 SW1.1 U82.9(P10) U83.10(A8)
SYS_BOOTMODE9: R146.1 SW1.2 U82.10(P11) U83.9(A7)
SYS_BOOTMODE10: R147.1 SW1.3 U82.11(P12) U83.8(A6)
SYS_BOOTMODE11: R148.1 SW1.4 U82.12(P13) U83.7(A5)
SYS_BOOTMODE12: R149.1 SW1.5 U82.13(P14) U83.6(A4)
SYS_BOOTMODE13: R150.1 SW1.6 U82.14(P15) U83.5(A3)
SYS_BOOTMODE14: R151.1 SW1.7 U82.15(P16) U83.4(A2)
SYS_BOOTMODE15: R152.1 SW1.8 U82.16(P17) U83.3(A1)
SYSBOOT_BUF_ENZ: R376.1 R377.1 U23.1(A)
TAD1_ADDR1: R29.2 R37.2 U5.13(ADDR)
TAD1_DREG_OUT: C42.1 C45.1 U5.1(DREG)
TAD1_GPI1: R31.1 U5.12(GPI1)
TAD1_MICBIAS: C66.1 U5.14(MICBIAS)
TAD1_VREF: C38.1 U5.24(VREF)
TAD2_ADDR2: R33.2 R36.2 U77.13(ADDR)
TAD2_DREG_OUT: C356.1 C358.1 U77.1(DREG)
TAD2_GPI1: R429.1 U77.12(GPI1)
TAD2_MICBIAS: C370.1 U77.14(MICBIAS)
TAD2_VREF: C354.1 U77.24(VREF)
TAD3_ADDR3: R30.1 R35.1 U6.13(ADDR)
TAD3_DREG_OUT: C43.1 C46.1 U6.1(DREG)
TAD3_GPI3: R32.1 U6.12(GPI1)
TAD3_MICBIAS: C67.1 U6.14(MICBIAS)
TAD3_VREF: C35.1 U6.24(VREF)
TAD4_ADDR4: R27.1 R28.1 U76.13(ADDR)
TAD4_DREG_OUT: C355.1 C357.1 U76.1(DREG)
TAD4_GPI4: R430.1 U76.12(GPI1)
TAD4_MICBIAS: C369.1 U76.14(MICBIAS)
TAD4_VREF: C353.1 U76.24(VREF)
TAD5212_1_DIN: R479.1 U5.5(DIN)
TAD5212_1_DIN_R: R479.2 U84.18(PB4A)
TAD5212_2_DIN: R478.1 U77.5(DIN)
TAD5212_2_DIN_R: R478.2 U84.19(PB4B)
TAD5212_3_DIN: R477.1 U6.5(DIN)
TAD5212_3_DIN_R: R477.2 U84.20(PB4C)
TAD5212_4_DIN: R475.1 U76.5(DIN)
TAD5212_4_DIN_R: R475.2 U84.21(PB4D)
TAD5212_MCASP2_ACLKX: R418.2 R419.1 R474.1 U5.2(BCLK) U6.2(BCLK) U76.2(BCLK) U77.2(BCLK)
TAD5212_MCASP2_AFSX: R422.2 R423.1 R472.2 U5.3(FSYNC) U6.3(FSYNC) U76.3(FSYNC) U77.3(FSYNC)
TCA6424_EXP_INT: R457.1 U82.32(I\N\T\)
TEST_GPIO1: Q7.1(G) R235.1 R526.2
TEST_GPIO2: R283.1 R285.2 U21.18(P21)
TEST_GPIO3: J10.1 R227.1 R439.1 R516.2 U23.2(B)
TEST_GPIO4: R221.1 R511.2 U82.28(R\E\S\E\T\)
TEST_PORZN: R219.1 R507.2 U43.6(C)
TEST_POWERDOWN: R233.1 R524.2 R647.1 U52.1(A)
TEST_WARMRESETN: Q6.1(G) R224.1 R513.2
TIMER_IO7: J13.52 U47.C15(UART0_RTSN)
TM4C129_TCK: TP66.1(TP) U48.100(PC0/TCK/SWCLK)
TM4C129_TDI: TP64.1(TP) U48.98(PC2/TDI)
TM4C129_TDO: TP62.1(TP) U48.97(PC3/TDO/SWO)
TM4C129_TMS: TP63.1(TP) U48.99(PC1/TMS/SWDIO)
TMP1_ADD0: R226.1 U44.5(ADD0)
TMP1_ADD1: R247.1 U44.3(ADD1)
TMP2_ADD0: R339.2 U63.5(ADD0)
TMP2_ADD1: R325.1 U63.3(ADD1)
TPS65224_EN: Q4.2(S) R303.1 R317.1 TP81.1(TP)
UART4_RXD: R612.2 U47.T19(GPIO0_49) U125.8(2A1)
UART4_TXD: R611.2 U47.U18(GPIO0_50) U125.6(1A1)
UART5_RXD: J12.62 U47.V22(GPIO0_51)
UART5_TXD: J12.60 U47.V21(GPIO0_52)
UART6_RXD: J13.62 U47.V19(GPIO0_53)
UART6_TXD: J13.60 U47.V18(GPIO0_54)
UART_SHIELD: J22.6(SH1) J22.7(SH2) J22.8(SH3) J22.9(SH4) R385.2
USB_TYPEA_EARTH: C656.1 J23.SH1 J23.SH2 R683.1
USB_TYPEA_OC_INDICATION: R396.2 U21.14(P15) U74.5(O\C\)
USB_TYPEACONN_DM: J23.2(D-) L9.2(IN2) R393.2 U130.2(D-)
USB_TYPEACONN_DP: J23.3(D+) L9.3(OUT1) R394.2 U130.1(D+)
USB_TYPEC1_EARTH: C648.1 J24.SH1 J24.SH2 J24.SH3 J24.SH4 R404.1
USB_TYPEC2_EARTH: C651.1 J25.SH1 J25.SH2 J25.SH3 J25.SH4 R403.1
USBC_CONN1_CC1: C307.1 D7.1(CATHODE) J24.A5(CC1) U129.24(C1_CC1)
USBC_CONN1_CC2: C306.1 D17.1(CATHODE) J24.B5(CC2) U129.26(C1_CC2)
USBC_CONN2_CC1: C305.1 D8.1(CATHODE) J25.A5(CC1) U129.45(C2_CC1)
USBC_CONN2_CC2: C312.1 D16.1(CATHODE) J25.B5(CC2) U129.47(C2_CC2)
USBC_CONN2_DM: D9.3(IO2) J25.A7(D-_1) J25.B7(D-_2) L10.3(OUT1) R400.2
USBC_CONN2_DP: D9.2(IO1) J25.A6(D+_1) J25.B6(D+_2) L10.2(IN2) R399.2
VMAIN: C294.1 C296.1 C310.1 C315.1 C328.1 C623.1 C636.1 R380.1 R395.1 R661.2 TP104.1(TP) U72.12(VIN) U73.1(VOUT) U128.15(VIN) U131.5(D1)
VMAIN_EN: R381.1 R382.1 U71.4(Y)
VMAIN_PD: C302.1 C322.1 C323.1 C324.1 U73.6(VIN) U129.1(PP_HV2) U129.11(PP_HV1)
VPHY_3V3_FT4232: C606.2 FL17.1 U64.4(VPHY)
VPLL_3V3_FT4232: C607.2 FL18.1 R357.2 U64.9(VPLL)
VPP_1V8: C218.1 C513.1 C517.1 R304.2 TP69.1(TP) U47.F7(VPP)
VPP_EN: R319.1 U21.5(P04)
VPP_SUPPLY: C247.2 C251.2 R304.1 U59.1(OUT)
VSEL_MMC1_SDIO: R103.2 U16.1(EN1) U19.4(Y)
VSEL_SD_SOC: R86.1 U79.8(B1)
VSEL_SD_SOC_1V8: U47.Y21(GPIO0_59) U79.5(A1)
WD_DISABLE: R281.2 R282.2 TP56.1(TP) U56.29(GPIO6)
WKUP_I2C0_SCL: C245.1 R284.1 R297.1 R301.2
WKUP_I2C0_SCL_RC: R284.2 U47.D13(WKUP_I2C0_SCL)
WKUP_I2C0_SDA: C248.1 R256.1 R259.2 R307.1
WKUP_I2C0_SDA_RC: R256.2 U47.E13(WKUP_I2C0_SDA)
WKUP_LFOSCO_XI: C216.2 R568.1 U47.A8(WKUP_LFOSC0_XI) Y4.1
WKUP_LFOSCO_XO: C213.2 R261.2 R568.2 Y4.2
WKUP_UART0_RX_3V3: R322.2 U47.C9(WKUP_UART0_RXD) U117.9(2A2)
WKUP_UART0_TX_3V3: R593.2 U47.E9(WKUP_UART0_TXD) U117.7(1A2)
XDS110_DIR: R555.2 U97.4(1DIR) U97.5(2DIR)
XDS110_EMU0: R237.2 U48.42(PF0) U102.7(B1)
XDS110_EMU1: R236.2 U48.43(PF1) U102.6(B2)
XDS110_TCK: U48.35(PA2/SSI0CLK) U97.14(1B2)
XDS110_TDI: U48.38(PA5/SSI0XDAT1) U97.15(1B1)
XDS110_TDO: U48.37(PA4/SSI0XDAT0) U109.7(B1)
XDS110_TMS: U48.36(PA3/SSI0FSS) U97.13(2B1)
XDS110_TRST#: U48.40(PA6) U97.12(2B2)
XDS_GPIO1: R235.2 U40.2(1Y)
XDS_GPIO2: R283.2 U51.7(B1)
XDS_GPIO3: R227.2 U40.4(2Y)
XDS_GPIO4: R221.2 U40.6(3Y)
XDS_PORZN: R219.2 U40.8(4Y)
XDS_POWERDOWN: R233.2 U40.12(6Y)
XDS_RSTN: R549.1 R556.1 TP51.1(TP) U48.70(R\S\T\)
XDS_SHIELD: C605.2 J17.6(SH1) J17.7(SH2) J17.8(SH3) J17.9(SH4) R610.2
XDS_USB_DM: J17.2(D-) U48.93(PL7/USB0DM)
XDS_USB_DP: J17.3(D+) U48.94(PL6/USB0DP)
XDS_USB_ID: J17.4(ID) R271.2 U60.2(IO2)
XDS_USB_VBUS: C244.1 C250.1 C267.1 D1.2 J17.1(VBUS) R295.1 R314.1 R576.1 TP78.1(TP) U55.1(IN1) U55.2(IN2) U60.6(VCC)
XDS_VREF: C190.1 C215.2 R241.2 U41.3(CATHODE) U48.9(VREFA+)
XDS_WARMRESETN: R224.2 U40.10(5Y)
ZENER_CLAMP: D2.3(C) R298.1 R308.1
N16848941: R115.2 R116.2 U26.1(A)
N16856152: C270.1 U64.3(OSCO) Y6.2
N16856224: C269.1 U64.2(OSCI) Y6.1
N16857368: C283.2 U66.2(NR/FB)
N16878497: R562.1 TP116.1(TP) U49.H5(DS)
N16880083: R18.1 R21.2 U2.1(A)
N16956459: R121.2 R122.1 U27.1(A)
N16994873: R483.2 U88.4(Y)
N16994875: R476.2 U87.4(Y)
N16995245: C417.1 R487.2
N16997746: R218.1 U48.59(RBAIS)
N17030208: R544.2 U97.7(1A2)
N17031262: LD9.2(ANODE) R402.2
N17078974: J10.2 R438.2
N17269599: R363.1 R366.2 U68.6(C)
N17269609: R362.1 R364.2 R367.1 U68.1(A)
N17378539: LD7.1(CATHODE) R330.2
N17479799: R314.2 U55.8(EN)
N17479805: C243.2 R306.2 R313.1 U55.5(NR/FB)
N17479881: C203.2 R246.1 U48.68(VBAT)
N17481587: LD5.2(ANODE) R287.2
N17481598: C225.2 R576.2 U48.96(PB1/USB0VBUS)
N17481613: R271.1 U48.95(PB0/USB0ID)
N17481619: R289.1 R295.2 U48.1(PD0/AIN15)
N17481621: R232.2 R520.1 U48.60(PK7)
N17481627: R276.1 U48.3(PD2/AIN13)
N17481631: LD3.2(ANODE) R276.2
N17481633: R229.2 R523.1 U48.63(PK4)
N17481635: R231.2 R521.1 U48.61(PK6)
N17481637: R287.1 U48.4(PD3/AIN12)
N17481641: R230.2 R522.1 U48.62(PK5)
N17824845: R654.1 U129.36(SPI_MISO/GPIO8)
N17824852: R653.1 U129.37(SPI_MOSI/GPIO9)
N17824859: R652.1 U129.38(SPI_CLK/GPIO10)
N17824866: R651.1 U129.39(S\P\I\_\S\S\/GPIO11)
N19741013: R390.2 U129.18(GPIO2)
N19806973: R566.2 U110.7(1A2)
N20199452: D4.3(C) R384.2 R389.1
N20506305: L8.1 U72.11(L1)
N20506307: L8.2 U72.9(L2)
N20506359: R387.1 R388.1 U72.2(PG)
N20506388: R666.1 U72.6(FB2)
N20506392: R380.2 U72.1(PS/SYNC)
N20506511: C304.1 U72.3(VAUX)
N21761024: R261.1 U47.A9(WKUP_LFOSC0_XO)
N21784165: R548.1 U47.V12(MDIO0_MDC)
N21784176: R541.1 U47.V13(MDIO0_MDIO)
N22498870: R602.1 R605.2 U120.6(C)
N22498881: R601.1 R604.2 R606.1 U120.1(A)
N22682556: J21.1 R633.2
N22682559: J21.3 R627.2
N24305910: R296.2 U56.36(GPIO2)
N24305927: R294.2 U56.35(GPIO1)
N24306091: R293.1 U54.4(Y)
N24306101: Q4.1(G) R293.2
N24306157: D5.3(K) R308.2
N24306190: Q4.3(D) R298.2
N24307593: R302.1 U57.2(A0) U57.7(B1)
N24478126: C70.1 U4.4(CT)
N24517110: R214.2 SW3.3
N24517112: R217.2 SW3.4
N24582539: R379.2 R383.1 U74.4(EN)
N24591228: R274.2 U50.6(3A)
N24605604: C18.1 J2.5A
N24605606: C16.1 J2.2A
N24605709: R84.2 R90.1 U14.1(A)
N24605835: TP5.1(TP) U7.20(GPIO2)
N24605846: L3.2 U7.4(BSTSW)
N24605909: C333.1 J2.5B
N24606047: TP8.1(TP) U7.19(GPI1)
N24606049: TP9.1(TP) U7.17(GPI2)
N24606166: C331.1 J2.2B
N24612310: R40.1 R41.1 U3.19(C\S\/A0)
N24612323: R42.1 R43.1 U3.21(CDIN/A1)
N24612337: R42.2 TP30.1(TP)
N24612352: R41.2 TP28.1(TP)
N24612373: R44.1 R45.1 U3.22(CDOUT/SDA)
N24612400: R44.2 TP24.1(TP)
N24612414: TP4.1(TP) U3.34(AESOUT)
N24612459: TP16.1(TP) U3.11(L\O\C\K\)
N24612593: R52.2 TP29.1(TP)
N24612656: TP13.1(TP) U3.27(GPO2)
N24612672: TP10.1(TP) U3.28(GPO3)
N24612674: TP7.1(TP) U3.29(GPO4)
N24612683: TP15.1(TP) U3.26(GPO1)
N24612758: R51.1 R52.1 U3.20(CCLK/SCL)
N24612803: TP3.1(TP) U3.36(SYNC)
N24614507: R72.1 R79.2 U13.1(A)
N24847876: R421.1 U77.4(DOUT)
N24847884: C348.1 J3.5B
N24847886: C347.1 J3.2B
N24847888: C347.2 U77.21(OUT2P)
N24847892: C344.2 U77.19(OUT1M)
N24847894: C343.2 U77.22(OUT2M)
N24847910: C348.2 U77.20(OUT1P)
N24847912: TP113.1(TP) U77.11(GPO1)
N24847957: C367.1 U77.15(IN1P)
N24847963: C365.1 U77.16(IN1M)
N24847969: C362.1 U77.17(IN2P)
N24847975: C360.1 U77.18(IN2M)
N24847993: TP112.1(TP) U77.9(GPIO1)
N24847995: TP115.1(TP) U77.10(GPIO2)
N24848039: R24.1 U5.4(DOUT)
N24848041: C25.1 J3.5A
N24848043: C24.1 J3.2A
N24848045: C24.2 U5.21(OUT2P)
N24848047: C23.2 U5.19(OUT1M)
N24848049: C22.2 U5.22(OUT2M)
N24848518: C25.2 U5.20(OUT1P)
N24848523: TP18.1(TP) U5.11(GPO1)
N24848568: C61.1 U5.15(IN1P)
N24848574: C56.1 U5.16(IN1M)
N24848580: C50.1 U5.17(IN2P)
N24848586: C47.1 U5.18(IN2M)
N24848600: R24.2 TP12.1(TP)
N24848612: R421.2 TP109.1(TP)
N24848616: TP17.1(TP) U5.9(GPIO1)
N24848618: TP22.1(TP) U5.10(GPIO2)
N24851304: R420.1 U76.4(DOUT)
N24851306: R420.2 TP14.1(TP)
N24851312: C346.1 J4.5B
N24851314: C345.1 J4.2B
N24851316: C345.2 U76.21(OUT2P)
N24851320: C342.2 U76.19(OUT1M)
N24851322: C341.2 U76.22(OUT2M)
N24851338: C346.2 U76.20(OUT1P)
N24851340: TP111.1(TP) U76.11(GPO1)
N24851385: C366.1 U76.15(IN1P)
N24851391: C364.1 U76.16(IN1M)
N24851397: C361.1 U76.17(IN2P)
N24851403: C359.1 U76.18(IN2M)
N24851421: TP110.1(TP) U76.9(GPIO1)
N24851423: TP114.1(TP) U76.10(GPIO2)
N24851452: R25.1 U6.4(DOUT)
N24851454: R25.2 TP11.1(TP)
N24851456: C27.1 J4.5A
N24851458: C26.1 J4.2A
N24851460: C26.2 U6.21(OUT2P)
N24851462: C21.2 U6.19(OUT1M)
N24851464: C20.2 U6.22(OUT2M)
N24851486: C27.2 U6.20(OUT1P)
N24851488: TP20.1(TP) U6.11(GPO1)
N24851535: C62.1 U6.15(IN1P)
N24851541: C57.1 U6.16(IN1M)
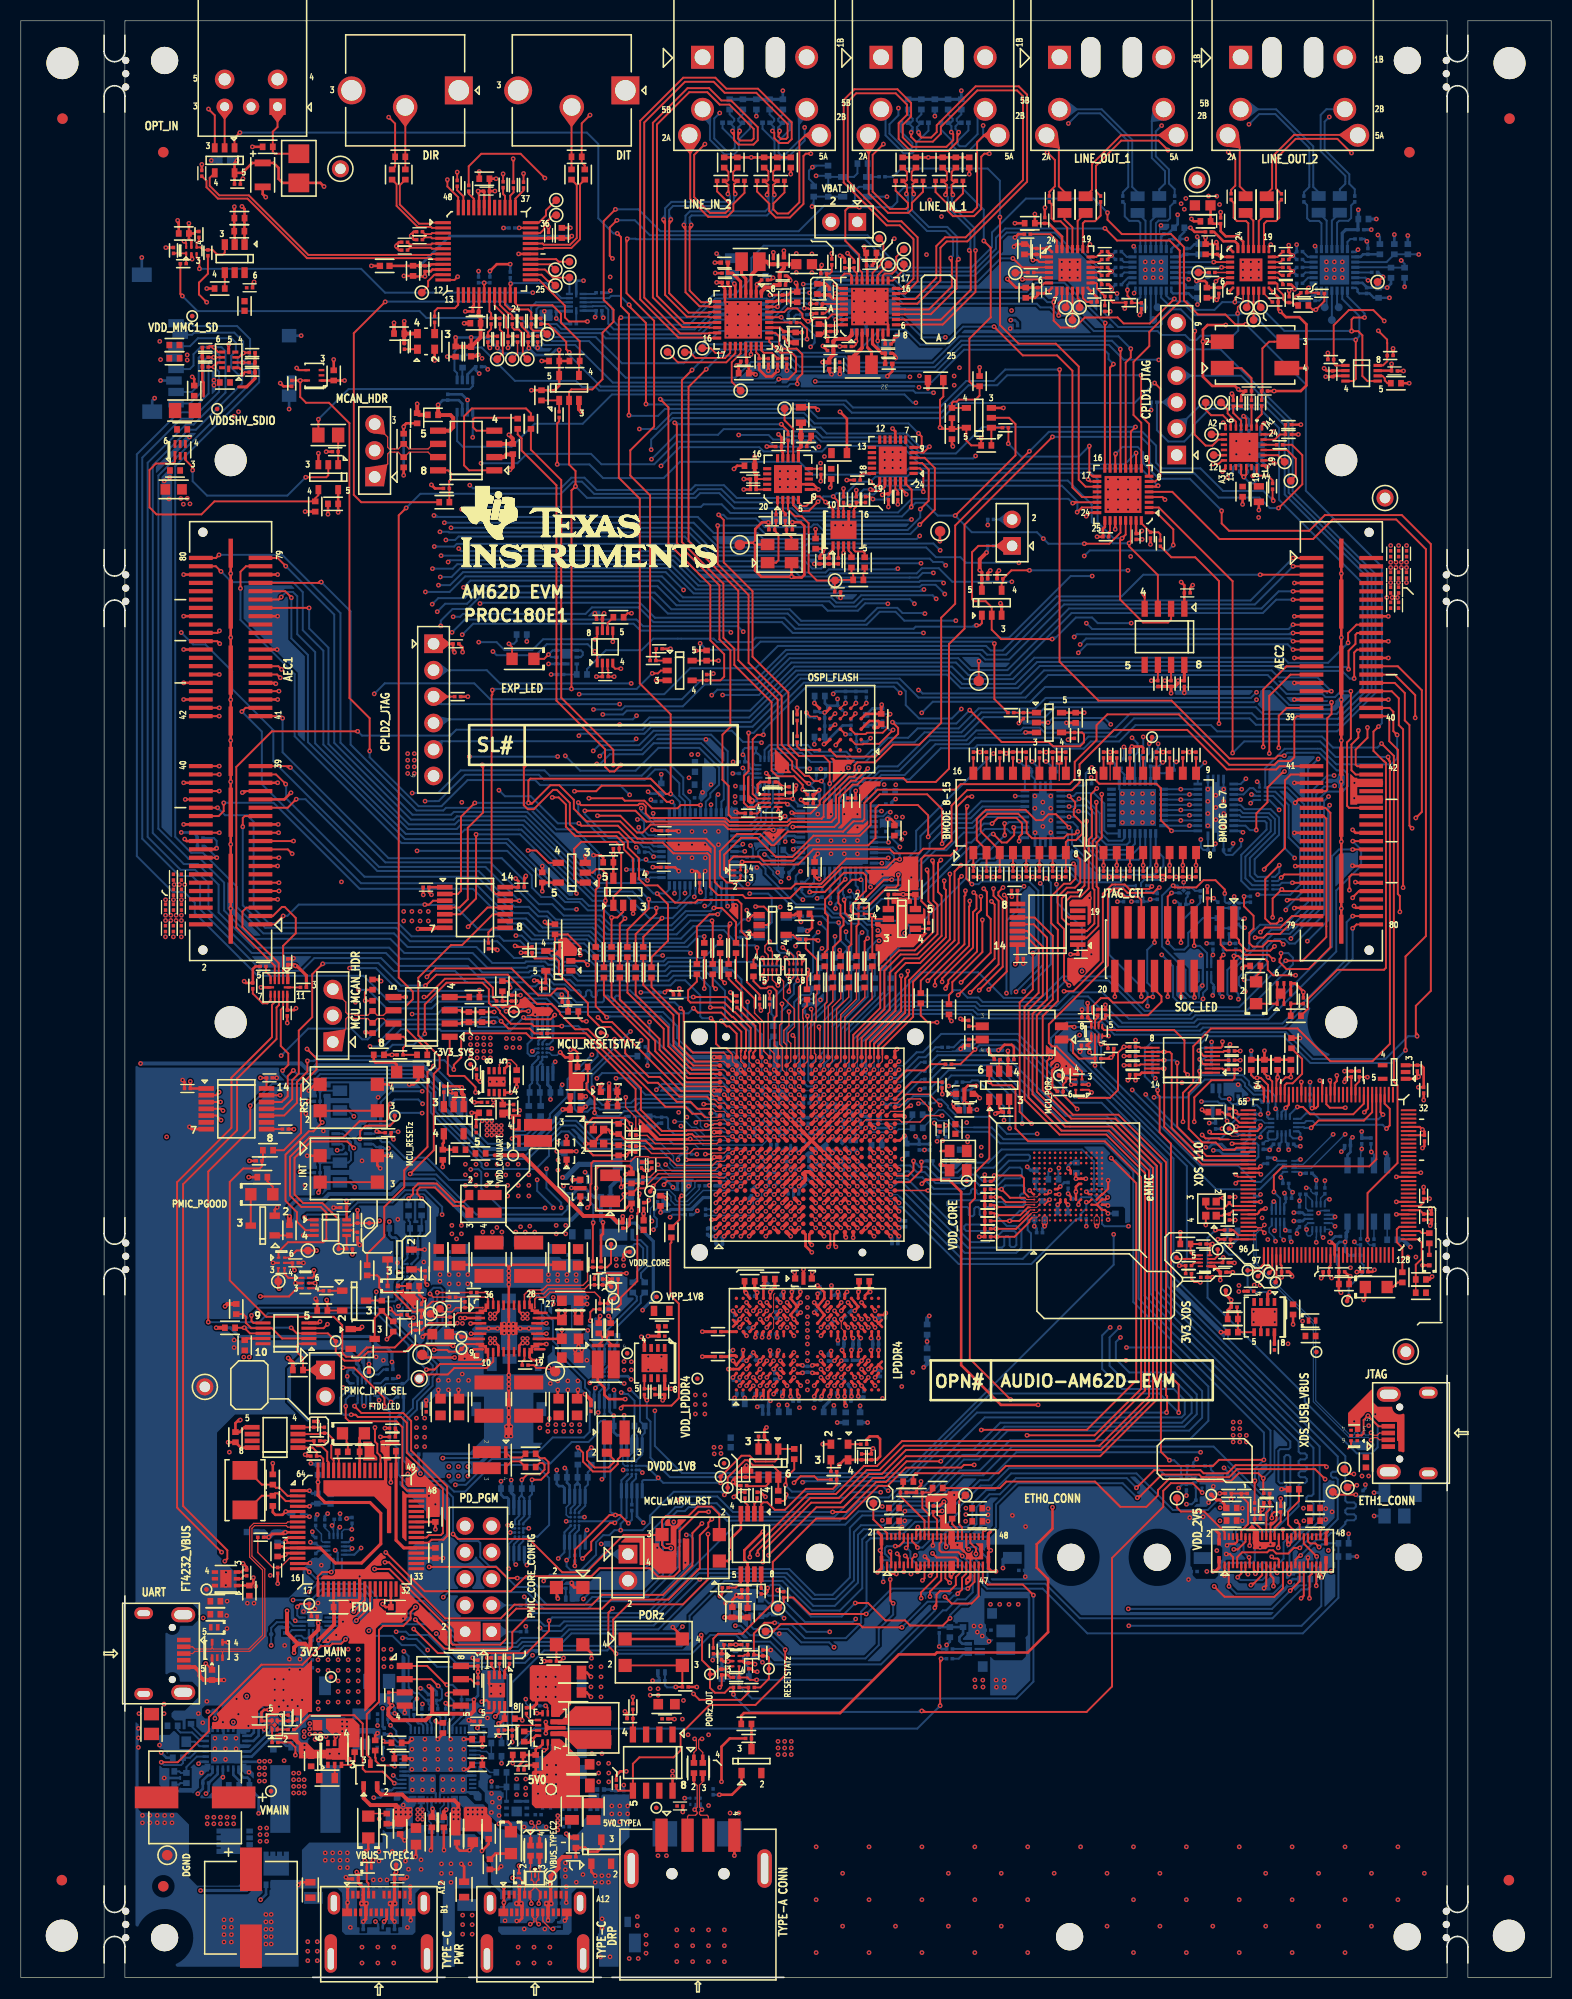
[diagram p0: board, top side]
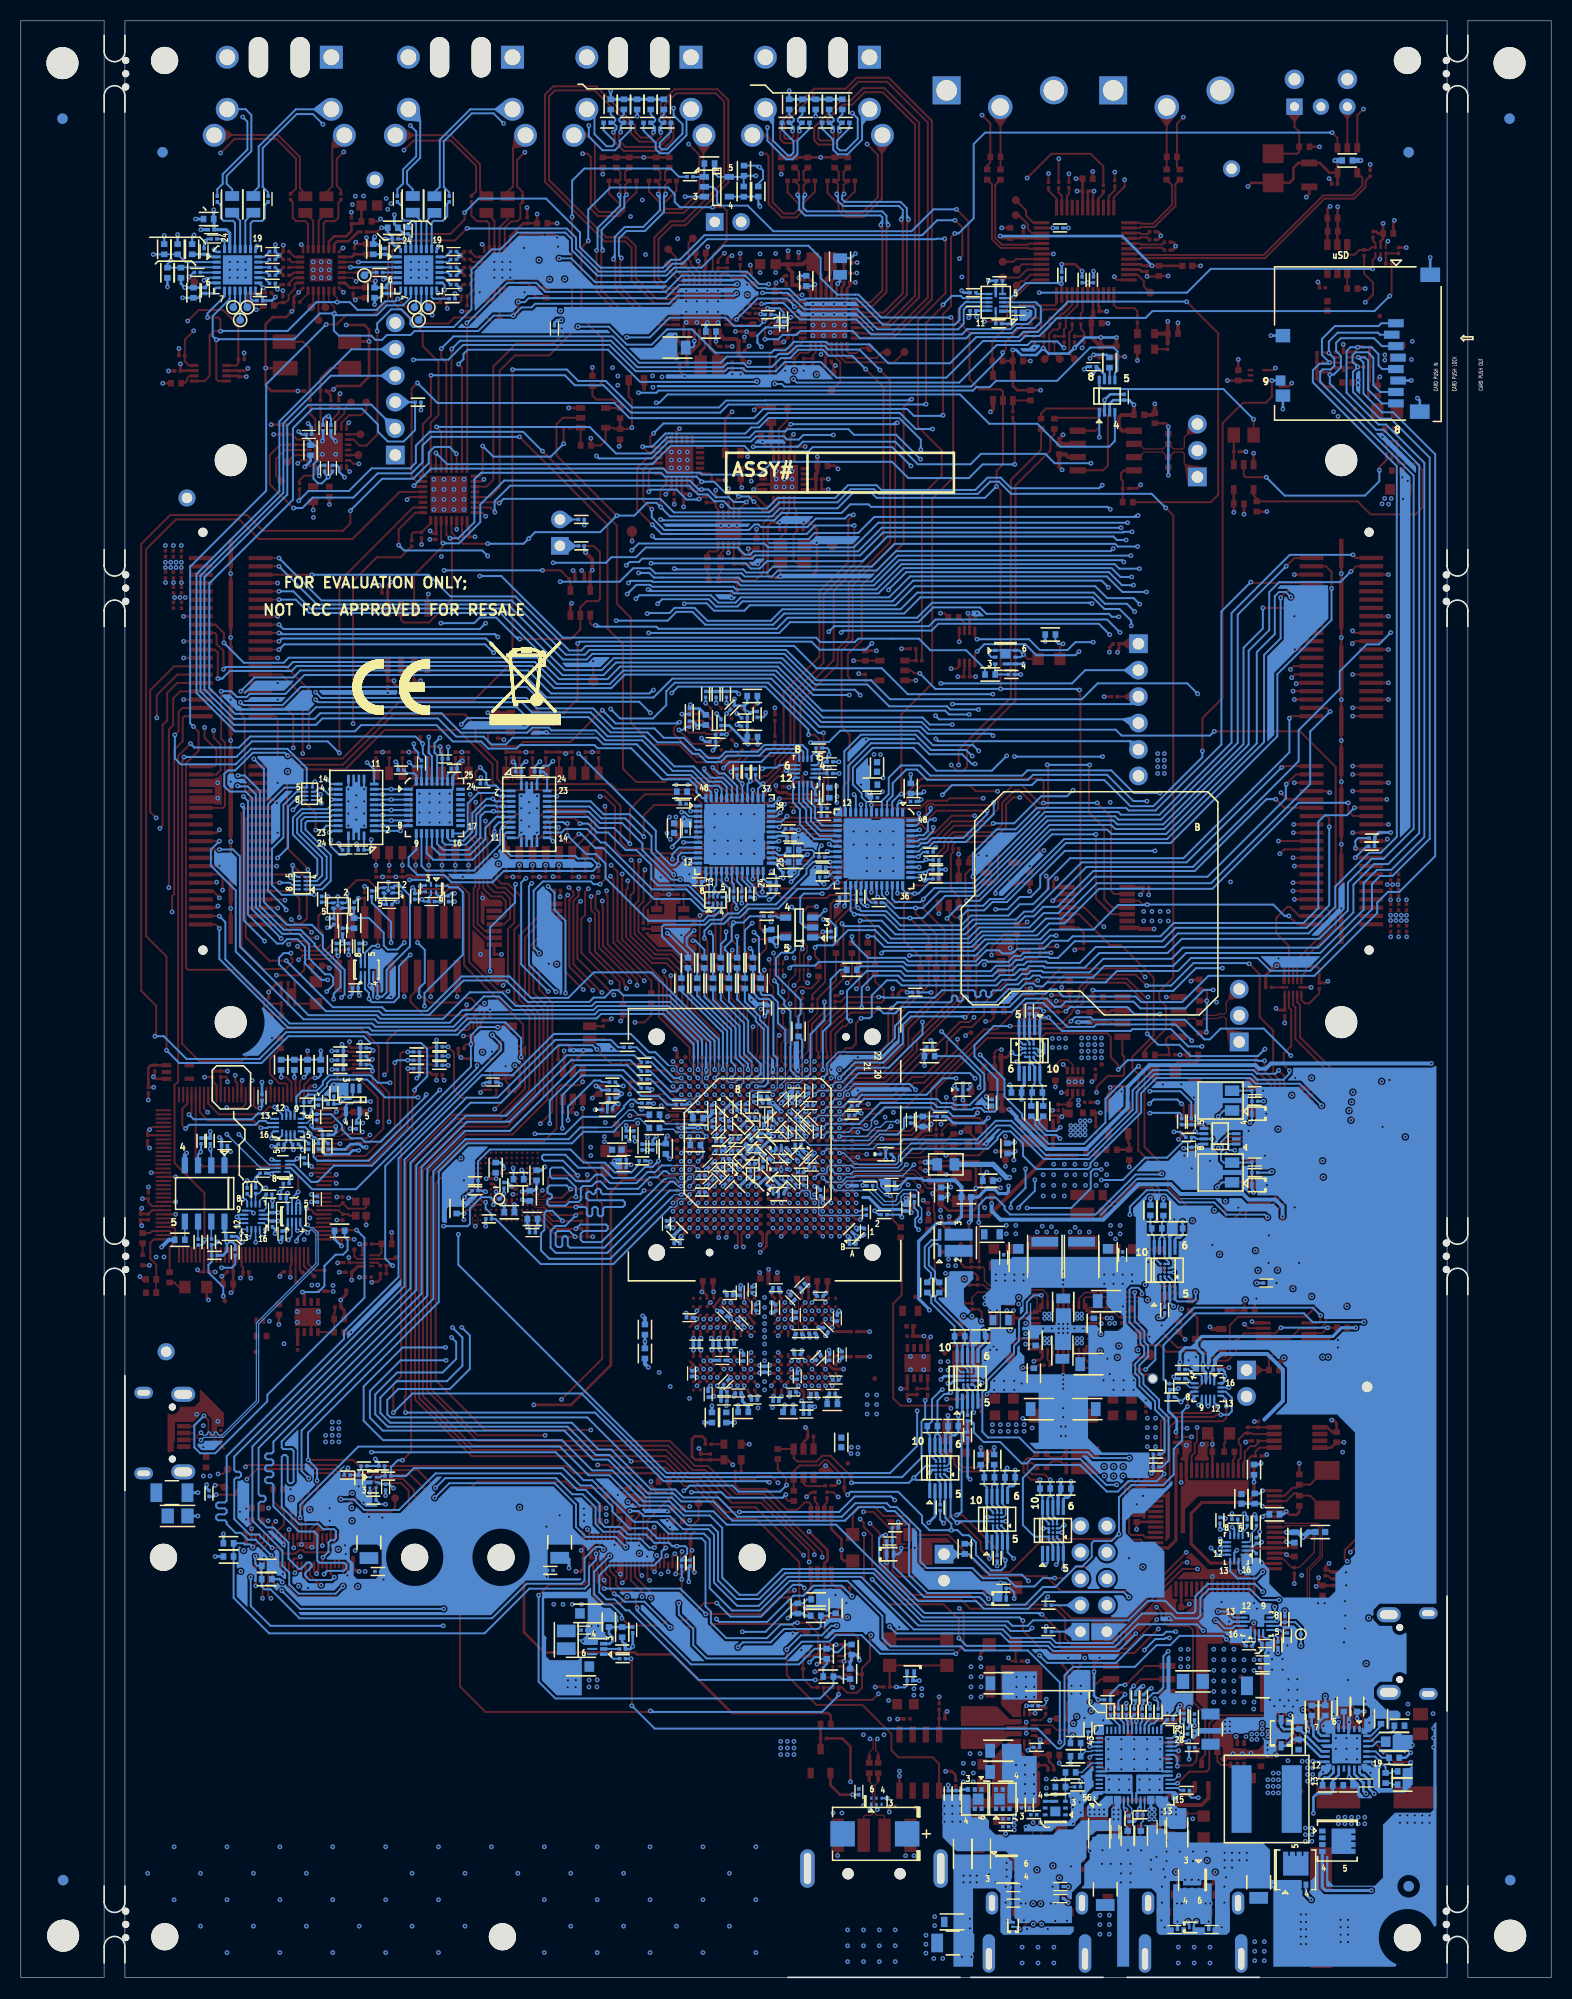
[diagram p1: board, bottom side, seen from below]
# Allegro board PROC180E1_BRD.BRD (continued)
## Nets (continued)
N24851547: C51.1 U6.17(IN2P)
N24851553: C48.1 U6.18(IN2M)
N24851571: TP19.1(TP) U6.9(GPIO1)
N24851573: TP23.1(TP) U6.10(GPIO2)
N25026172: R169.1 U47.G22(MMC2_CMD)
N25026194: R185.1 U47.H22(MMC2_CLK)
N25124626: R496.1 U47.E20(MMC2_DAT0)
N25124643: R183.1 U47.F21(MMC2_DAT1)
N25124756: R182.1 U47.E21(MMC2_SDWP)
N25128465: R167.1 U47.F20(MMC2_DAT2)
N25128467: R168.1 U47.G21(MMC2_DAT3)
N25521527: TP6.1(TP) U7.18(GPIO3)
N25809420: C610.1 J18.SH1 J18.SH2 J18.SH3 J18.SH4 R623.2
N25815350: C611.1 J19.SH1 J19.SH2 J19.SH3 J19.SH4 R624.2
N25906633: R250.2 U98.6(3A)
N26034689: R640.2 U127.1(EN)
N26038083: C635.1 R670.2
N26038197: Q11.4(G) R649.2 R650.2
N26038205: L12.2 R663.1 R667.2
N26038227: C634.2 R659.1 U128.17(VOUT)
N26228423: U52.4(Y) U54.1(A)
N26271323: R386.2 U129.17(GPIO1)
N26451841: R472.1 U85.23(PB9A)
N26451883: R468.1 U85.20(PB4C)
N26455193: R455.1 U80.4(1DIR) U80.5(2DIR)
N26455313: R462.2 U80.1(1\O\E\) U80.16(2\O\E\)
N26461930: R143.1 U29.4(O\E\)
N26517285: R463.1 U84.31(PR5D)
N26567066: R474.2 U84.24(PB9B)
N26593111: R86.2 R91.1 U19.1(A)
N26594023: C193.1 U42.6(CT)
N26608860: R184.1 U47.F22(MMC2_SDCD)
N26609186: R574.1 U47.C8(WKUP_UART0_RTSN)
N27056893: R484.2 U85.29(PR6A)
N27107689: C308.1 U73.3(CT)
N27107697: R382.2 U73.5(EN/UVLO)
N27107782: R395.2 U73.2(QOD)
N27108105: LD8.2(ANODE) R397.2
N27116765: R319.2 R320.1 U59.5(EN)
N27118410: R240.2 U46.3(EN)
N27118414: R255.2 R258.1 U46.4(FB)
N27118438: C207.1 R255.1 R257.1 U46.5(OUT)
N27128284: R329.1 U62.1(OE/NC)
N27128639: R348.1 U65.2(1G)
N27128753: R349.1 U65.3(Y0)
N27128755: R358.1 U65.5(Y2)
N27128757: R359.1 U65.8(Y1)
N27132714: R137.1 SW2.13
N27132716: R136.1 SW2.14
N27132718: R135.1 SW2.15
N27132720: R134.1 SW2.16
N27132816: R131.1 SW1.11
N27132818: R130.1 SW1.12
N27132820: R129.1 SW1.13
N27132822: R128.1 SW1.14
N27132824: R133.1 SW1.9
N27132826: R132.1 SW1.10
N27132828: R127.1 SW1.15
N27132836: R126.1 SW1.16
N27133243: R141.1 SW2.9
N27133247: R140.1 SW2.10
N27133249: R139.1 SW2.11
N27133251: R138.1 SW2.12
N27148451: R125.2 U28.A5(INT#)
N27152136: R530.1 U47.Y17(RGMII1_TD0)
N27152138: R535.1 U47.V16(RGMII1_TD1)
N27152140: R537.1 U47.Y16(RGMII1_TD2)
N27152142: R529.1 U47.AA17(RGMII1_TD3)
N27152150: R509.1 U47.AA19(RGMII2_TD0)
N27152152: R518.1 U47.Y18(RGMII2_TD1)
N27152154: R527.1 U47.AA18(RGMII2_TD2)
N27152156: R528.1 U47.W17(RGMII2_TD3)
N27153825: R188.1 U47.B20(MCASP0_AXR0)
N27153827: R186.1 U47.B18(MCASP0_AXR1)
N27153829: R187.1 U47.B19(MCASP0_AXR2)
N27153831: R171.1 U47.C19(MCASP0_AXR3)
N27153833: R189.1 U47.B21(MCASP0_AFSR)
N27153850: R173.1 U47.A20(MCASP0_AFSX)
N27153866: R172.1 U47.A19(MCASP0_ACLKX)
N27153868: R174.1 U47.A21(MCASP0_ACLKR)
N27154979: R542.2 U47.C14(TDO)
N27158706: R508.2 R514.1 U47.E16(I2C0_SDA)
N27158712: R538.1 U47.F14(UART0_CTSN)
N27161108: D6.3(C) R398.2 R401.1
N27162147: C640.1 Q8.1(S1) Q8.2(S2) Q8.5(S3) Q8.6(S4) Q8.8(S5) Q9.1(S1) Q9.2(S2) Q9.5(S3) Q9.6(S4) Q9.8(S5) R680.1
N27162183: C317.2 C318.2 C638.2 C639.2 C640.2 Q8.3(G) Q9.3(G) R675.2 R676.2 R677.1 R680.2
N27162293: Q10.1(D1) Q10.2(D2) Q10.5(D3) Q10.6(D4) Q10.8(D5) R677.2
N27162479: Q10.3(G) R669.2 R672.1 R673.2
N27166782: R166.2 U32.8(OE)
N27170778: LD6.2(ANODE) R324.1
N27173972: Q1.3(G) R203.2 R213.2
N27173989: Q5.3(G) R441.2 R442.2
N27174010: LD10.1(CATHODE) Q5.1(D1) Q5.2(D2) Q5.5(D3) Q5.6(D4) Q5.8(D5)
N27174034: LD1.1(CATHODE) Q1.1(D1) Q1.2(D2) Q1.5(D3) Q1.6(D4) Q1.8(D5)
N27174097: LD1.2(ANODE) R180.1
N27174144: LD10.2(ANODE) R440.1
N27175754: R95.2 U15.18(OUT2_P)
N27175817: C104.2 R74.2 Y1.1
N27175821: C105.1 R73.2 Y1.3
N27175987: C121.1 C382.1 C383.1 C384.1 C385.1 C386.1 C387.1 R97.1 U15.3(VDD_REF) U15.15(VDDO_34) U15.16(VDDO_12) U15.24(VDD_VCO)
N27176057: TP36.1(TP) U15.7(OUT0)
N27176072: R89.2 U15.22(OUT1_P)
N27176107: TP39.1(TP) U15.21(OUT1_N)
N27176638: TP37.1(TP) U15.11(GPIO4)
N27176640: TP38.1(TP) U15.20(GPIO1)
N27177966: R87.2 U20.13(CLK0)
N27177989: C124.1 R104.2 Y2.1
N27177993: C125.2 R105.2 Y2.3
N27178052: R109.1 U22.2(A0)
N27178112: R99.2 U22.8(A1)
N27178169: R110.1 U22.4(VOUT0)
N27178171: R111.1 U22.5(VOUT1)
N27178190: R111.2 R113.1
N27178282: TP34.1(TP) U20.12(CLK1)
N27178331: R100.1 R101.1 U22.6(L\A\T\/HVC)
N27178482: C110.1 C111.1 R80.1 U20.11(VDDOA)
N27201903: R114.2 U24.6(OE)
N27212070: R248.1 U45.8(OE)
N27212579: R161.1 U34.8(OE)
N27213236: R196.1 U37.12(OE)
N27224404: R432.2 R433.2 R435.2 U8.29(SDOUT)
N27224468: C337.1 J1.5B
N27224561: L2.2 U8.4(BSTSW)
N27224667: C335.1 J1.2B
N27224751: TP27.1(TP) U8.18(GPIO3)
N27224753: TP31.1(TP) U8.20(GPIO2)
N27224897: C14.1 J1.5A
N27225024: C77.1 C78.1 U8.32(DREG)
N27225078: C12.1 J1.2A
N27225127: TP26.1(TP) U8.19(GPI1)
N27225129: TP25.1(TP) U8.17(GPI2)
N27225150: R46.2 U8.28(GPIO1)
N27226002: R413.1 R414.2 U75.1(A)
N27236897: R163.1 U33.4(Y)
N27236901: R486.1 U89.4(Y)
N27236905: R165.1 U35.4(Y)
N27237106: R162.2 U33.1(OE)
N27239473: R591.2 U117.5(2DIR)
N27239479: R590.1 U117.4(1DIR)
N27239926: R635.2 U126.5(2DIR)
N27239932: R636.1 U126.4(1DIR)
N27240077: R613.2 U125.5(2DIR)
N27240083: R614.1 U125.4(1DIR)
N27243596: TP61.1(TP) U51.6(B2)
N27243598: TP58.1(TP) U51.3(A2)
N27248134: R579.2 U107.7(SCLB)
N27248136: R580.2 U107.6(SDAB)
N27283175: R234.2 U47.E12(MCU_I2C0_SCL)
N27283177: R210.2 U47.D9(MCU_I2C0_SDA)
N27283214: C205.2 R252.1 Y3.1
N27283220: C209.2 R253.1 Y3.3
N27283414: R570.2 U47.D7(MCU_MCAN1_TX)
N27283542: R216.1 U47.B13(MCU_SPI0_CLK)
N27289636: R181.2 U37.5(A4)
N27290261: R194.1 U37.7(B4)
N27380200: R427.2 U78.5(A4)
N27380212: R428.1 U78.7(B4)
N27380351: R434.1 U78.12(OE)
N27381124: R436.2 U79.6(OE)
N27417083: R470.2 U84.26(PR6D)
N27417117: R466.2 U84.27(PR6C)
N27566274: LD2.1(CATHODE) Q2.3(COLLECTOR)
N27566278: LD2.2(ANODE) R260.1
N27566306: Q2.1(BASE) R272.2
N27566380: LD4.2(ANODE) R292.1
N27566388: LD4.1(CATHODE) Q3.3(D)
N27566452: C613.2 D13.2 SW7.2
N27570222: R144.2 U30.1(OE) U31.1(OE)
N27570724: R69.2 U11.6(OE)
N27571220: R53.1 U9.1(OE/NC)
N271759124: TP32.1(TP) U15.5(PRIREF_P)
N271759125: TP33.1(TP) U15.6(PRIREF_N)
N275664200: Q3.1(G) R286.2

Pads without a net: D2 2; D4 2; D6 2; J12 13 14 48 54 55 56 59 61 63 64 68 70 72 74; J13 13 14 48 54 55 56 59 61 63 64 74; J14 17 18 19; J21 4 6; J22 4; J24 A2 A3 A6 A7 A8 A10 A11 B2 B3 B6 B7 B8 B10 B11; J25 A2 A3 A8 A10 A11 B2 B3 B8 B10 B11; MOD1 4 5; U3 14 15 40 41 46; U10 4 9; U12 2 3; U15 9 10 13 14 17; U18 1 7 8 10 11 12 13 14 15 16 17; U20 8 9 15 16 17 19; U21 3 20; U25 5; U28 A2 A3 B1 B5 C5; U32 6 9; U34 6 9; U36 1; U41 2 4 5; U45 6 9; U47 AA12 AA13 AA22 AB10 AB11 AB13 AB14 C6 D6 E7 F6 F10 G7 H2 H3 H5 H7 K2 K3 K6 L2 L5 L6 M2 M3 N2 N3 N5 N6 P4 R7 T18 U11 U17 V10 V11 V17 W12 W13 Y13 Y14; U48 2 5 6 11 12 13 14 15 18 19 20 21 22 23 24 25 27 29 30 31 32 33 34 41 44 45 46 53 54 56 57 65 67 75 83 84 85 86 91 92 102 103 104 105 106 107 108 109 110 111 112 116 117 118 119 120 121 123 124 125 126 127 128; U49 A1 A2 A7 A8 A9 A10 A11 A12 A13 A14 B1 B7 B8 B9 B10 B11 B12 B13 B14 C1 C3 C5 C7 C8 C9 C10 C11 C12 C13 C14 D1 D2 D3 D4 D12 D13 D14 E1 E2 E3 E5 E8 E9 E10 E12 E13 E14 F1 F2 F3 F10 F12 F13 F14 G1 G2 G3 G10 G12 G13 G14 H1 H2 H3 H12 H13 H14 J1 J2 J3 J12 J13 J14 K1 K2 K3 K6 K7 K10 K12 K13 K14 L1 L2 L3 L12 L13 L14 M1 M2 M3 M7 M8 M9 M10 M11 M12 M13 M14 N1 N3 N6 N7 N8 N9 N10 N11 N12 N13 N14 P1 P2 P7 P8 P9 P10 P11 P12 P13 P14; U50 2; U55 7; U58 A1 A2 A11 A12 AA1 AA12 AB1 AB2 AB11 AB12 B1 B12 G11 K5 K8 N5 N8; U59 2 3 6 7; U60 1 4 5; U61 6 7; U64 18 19 21 22 23 24 28 29 30 32 33 34 36 40 41 43 44 45 46 53 54 55 57 58 59; U65 7; U66 5; U67 2; U82 17 18 19 20 21 22 23 24; U84 4 5; U92 B2 C2; U93 1; U98 2; U113 B2 C2; U115 B2 C2; U119 B2 C2; U121 B2 C2; U123 B2 C2; U129 21 22 23 30 31 40 41 42 43 48 50 53 54 55; U130 3 5

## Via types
v1: diameter 0.457, hole 0.203, TOP to BOTTOM, 3916 vias

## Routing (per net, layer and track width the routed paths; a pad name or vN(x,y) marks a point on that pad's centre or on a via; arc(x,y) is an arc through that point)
AVDD_3V3_DAC: length 21.1
  TOP w0.254: U5.23 100.01,167.23 98.74,168.5 C29.1 98.35,168.51 C32.1 v1(97.41,169.4) ; FL1.2 114.28,170.22 C31.1 114.51,168.47 C30.1 115.25,167.75 115.74,167.26 116.9,167.26 117.41,166.75 U6.23
  BOTTOM w0.254: U77.23 109.53,167.22 C352.1 110.19,167.48 C350.1 111.12,168.42 v1(111.12,169.33)
  BOTTOM w0.305: v1(128.47,169.81) C349.1 128.44,168.88 C351.1 127.26,167.89 126.93,167.56 U76.23
  vias: v1(114.08,171.13) v1(114.88,171.11) v1(115.15,170.31)
DGND: length 1511.6
  TOP w0.081: 103.1,72.41 v1(103.35,72.16) 103.6,72.41 103.6,72.97 U49.N2 103.1,72.97 103.1,72.41
  TOP w0.102: v1(23.39,23.81) 23.39,23.95 23.68,24.25 U71.3
  TOP w0.145: R48.2 v1(49.64,156.54) ; v1(45.06,156.53) 44.87,156.73 R49.2
  TOP w0.178: v1(98.82,74.71) 98.35,74.23 U49.C4
  TOP w0.191: J14.12 v1(110.17,94.2) ; C6.2 54.17,174.06 53.88,174.34 R2.2 53.88,178.11 v1(54.68,178.91) ; C23.1 103.27,171.57 103.27,174.03 105.69,176.45 109.28,176.45 v1(110.19,175.54) ; v1(98.58,175.34) 99.33,174.59 99.33,172.06 98.79,171.52 C22.1 ; C111.2 75.49,147.24 v1(75.76,147.51) 75.91,147.66 C110.2 ; v1(75.89,175.2) 75.4,175.2 75.18,174.97 75.18,170.36 73.87,169.06 72.52,169.06 71.89,169.68 71.89,170.39 70.72,171.56 C13.1 ; v1(116.7,83.16) 116.66,83.16 116.37,83.45 C203.1 ; v1(115.98,175.36) 116.66,174.68 116.66,172.12 116.26,171.72 C20.1 ; v1(127.82,175.26) 126.46,176.62 122.46,176.62 120.57,174.73 120.57,171.85 C21.1 ; C7.2 35.95,173.97 R1.2 35.95,178.08 v1(35.34,178.7) ; U39.4 v1(104.49,90.43) ; v1(18.02,179.49) 18.63,178.88 U1.3 ; v1(82.86,176.12) 81.82,175.08 81.82,171.55 83.49,169.89 85.02,169.89 85.21,170.08 85.21,170.45 84.03,171.64 C15.1 ; J14.20 v1(105.09,94.2) ; TP44.1 92.01,126.43 v1(92.03,126.45) ; 119.12,62.6 U55.6 ; v1(115.51,74.87) 115.18,74.87 Y5.2 ; v1(65.72,176.12) 64.68,175.08 64.68,171.02 66.19,169.51 67.69,169.51 68.06,169.88 68.06,170.39 66.88,171.57 C11.1 ; C194.2 v1(24.58,86.41) ; Y5.4 v1(113.83,72.28) ; U40.7 115.28,89.3 115.42,89.45 v1(115.42,89.89) ; C17.1 87.87,171.51 89.04,170.34 89.04,169.7 89.54,169.2 91.56,169.2 92.25,169.88 92.25,174.9 92.55,175.2 v1(93.03,175.2) ; J14.16 v1(107.63,94.2) ; J14.10 v1(111.44,94.2)
  TOP w0.203: J18.1 83.21,39.05 83.51,38.75 v1(84.1,38.75) 84.01,38.84 J18.5 ; J18.18 86.41,43.01 v1(86.16,43.25) 86.01,43.1 J18.16 ; J19.34 122.04,41.84 v1(121.77,41.58) 121.64,41.71 J19.32 ; v1(96.9,75.6) 97.28,75.22 U49.A6 ; v1(123.64,40.33) J19.41 ; J19.1 115.64,39.02 115.63,39.02 v1(115.63,38.6) ; J18.24 v1(87.61,41.48) ; J19.16 118.44,41.71 118.84,41.31 v1(119.04,41.31) 119.04,41.68 118.84,41.88 J19.18 ; v1(58.61,81.97) 58.01,82.56 54.94,82.56 54.25,81.87 v1(54.25,80.09) 54.25,79.69 54.98,78.97 C209.1 ; U48.17 v1(134.48,77.3) ; J19.8 116.84,41.85 116.63,41.65 116.01,41.65 v1(115.87,41.5) ; U48.55 v1(123,86.02) ; v1(84.65,43.25) 84.42,43.02 84.42,42.7 84.41,42.69 J18.8 ; v1(104.44,76.57) 104.44,75.75 103.91,75.22 U49.P6 U49.N5 ; U48.48 125.8,86.12 v1(125.74,86.18) ; v1(59.55,81.97) 59.76,81.97 61.2,80.53 64.28,80.53 v1(64.3,80.54) ; C140.2 112.32,133.5 v1(112.57,133.74) ; C266.1 81.7,50.28 C265.2 81.7,50.65 v1(81.86,50.81) ; D8.2 v1(47.86,10.71) ; v1(86.83,40.42) 87.02,40.23 87.04,40.23 87.22,40.06 87.22,39.63 J18.21 ; U29.5 72.75,112 v1(72.77,111.98) ; U48.80 118.95,77.3 v1(119.12,77.14) ; v1(114.46,70.45) 114.24,70.23 114.24,70.2 114.2,70.16 U51.4 ; Y3.4 55.99,81.26 55.33,80.6 55.33,80.43 Y3.2 ; v1(119.41,37.38) 119.64,37.61 J19.21 ; U48.58 121.8,83.82 v1(121.5,83.52) ; v1(86.13,38.96) 86.01,39.08 J18.15 ; v1(116.7,83.16) 116.7,83.12 116.92,82.9 U48.66 ; SW6.4 61.59,40.81 v1(61.14,41.26) ; U24.2 55.86,124.96 C144.2 v1(55.28,124.96) ; U52.2 v1(24.22,68.64) ; J18.41 91.21,38.39 v1(90.97,38.16) ; J18.34 89.61,41.75 89.81,41.55 v1(89.96,41.55) 89.81,41.4 89.52,41.4 89.21,41.72 J18.32 ; J19.31 121.64,38.93 v1(121.83,38.74) 122.04,38.94 J19.33 ; U25.4 107.95,132.8 v1(107.86,132.89) ; R372.2 67.32,28.04 v1(67.12,27.85) ; U58.V1 79.78,55.82 v1(79.79,55.81) ; C230.1 v1(27.15,68.64) ; D9.1 v1(49.39,10.33) ; J18.31 89.21,38.93 v1(89.4,38.74) 89.61,38.94 J18.33 ; C205.1 57.48,81.01 58.13,80.37 60.03,80.37 60.79,79.61 v1(63.92,79.61) ; v1(115.78,40.66) 116.14,40.66 116.44,40.37 J19.5 ; v1(26.5,154.61) 26.7,154.4 U12.4 ; J19.24 v1(120.04,41.59) ; U48.10 v1(132.12,74.5) ; J19.17 118.84,39.02 v1(118.59,38.77) 118.44,38.92 J19.15 ; R365.2 v1(72.03,31.44)
  TOP w0.229: U3.44 44.01,171.51 v1(43.92,171.6) ; U5.A4 102.49,166.28 v1(102.69,166.48) ; v1(98.65,166.14) 98.6,166.09 C45.2 97.53,166.11 97.07,166.11 96.67,166.51 C42.2 ; R37.1 v1(104.64,160.04) ; v1(38.82,163.4) 37.73,163.4 C59.2 v1(36.79,163.45) ; R36.1 107.63,159.84 v1(107.48,159.69)
  TOP w0.254: U42.5 46.47,87.29 v1(46.88,87.7) ; C319.1 39.48,12.3 v1(39.38,12.2) ; v1(67.86,160.76) 67.64,160.98 U8.8 67.64,162.23 67.36,162.51 C65.2 ; U72.4 49.49,23.21 v1(49.09,22.82) 48.82,22.54 48.46,22.54 C304.2 ; SW5.1 v1(27.51,78.93) ; C63.2 73.65,163.46 73.9,163.2 v1(73.9,163.02) 73.71,163.02 73.45,162.77 C68.2 ; C212.2 60.36,77.5 v1(60.12,77.5) 59.88,77.5 C211.2 ; U64.51 C263.2 ; v1(78.36,158.12) C81.2 77.31,158.12 v1(77.29,158.1) 77.23,158.1 76.98,157.85 C82.2 ; C224.2 58.16,71.97 58.48,72.29 58.48,72.88 v1(58.65,73.05) ; C300.1 22.11,24.64 21.86,24.38 v1(21.86,24.15) ; v1(51.8,88.86) 52.29,88.38 C188.2 ; U61.5 21.48,52.84 21.03,52.38 C262.1 20.62,53.24 20.92,53.54 v1(21.08,53.54) ; v1(95.49,167.15) 95.81,167.46 C38.2 ; v1(84.88,80.84) 84.43,80.39 U47.AB12 ; v1(83.08,158.98) 83.31,158.76 U7.8 ; C29.2 98.36,170 v1(98.38,170.02) ; U36.3 52.25,98.6 v1(51.96,98.88) ; v1(70.74,29.36) 70.44,29.36 70.16,29.64 C293.2 ; v1(38.66,103.99) 38.64,104.01 C164.2 ; C195.2 15.72,86.02 v1(15.54,86.2) ; v1(74.44,143.17) 74.71,143.44 U20.7 76.11,143.44 v1(76.61,142.94) U20.6 ; U58.G12 v1(72.96,64.83) ; C55.2 81.94,164.63 v1(81.94,164.87) 82.19,165.12 C49.2 ; J13.22 v1(131.36,128.35) ; v1(134.64,79.66) 134.82,79.85 C208.2 ; C92.1 83.78,156.02 84.04,155.77 v1(84.04,155.57) ; v1(80.11,64.03) U58.W11 80.11,64.83 U58.V12 ; C104.1 117.64,152.4 ; 117.64,152.4 117.11,152.4 v1(116.95,152.56) 116.63,152.88 114.44,152.88 113.55,153.77 v1(113.55,157.15) ; 117.64,152.4 117.23,151.98 R76.2 ; J12.31 25.31,113.16 v1(25.95,113.8) ; U58.C1 v1(70.36,56.83) ; J24.B1 v1(37.44,5.48) ; C145.2 42.43,127.75 v1(42.43,127.31) ; U45.7 16.41,81.49 v1(16.2,81.71) ; R217.1 90.63,89.54 v1(90.28,89.19) ; U64.10 25.67,42.25 25.41,42 v1(25.41,41.83) 25.49,41.75 U64.11 ; J12.26 v1(15.64,110.76) ; J13.16 v1(131.36,130.75) ; v1(69.44,143.94) C118.2 C120.2 v1(69.44,142.94) ; v1(53.25,64.06) 53.25,63.46 C246.2 53.89,63.46 v1(53.89,64.06) ; v1(95.88,105.73) 95.69,105.73 95.67,105.72 R148.2 ; C288.1 31.02,35.8 31.28,36.06 v1(31.65,36.06) ; U66.3 21.19,38.94 21.39,39.14 C283.1 21.71,39.39 v1(21.33,39.76) ; v1(33.13,12.08) 33.38,12.33 LD8.1 ; C303.2 40.54,23.37 v1(40.05,22.88) ; U69.4 v1(36.87,25.41) ; C292.2 43.62,30.47 v1(43.39,30.69) ; J17.5 130.61,53.59 v1(130.1,54.09) ; v1(45.92,14.75) 46.11,14.94 46.82,14.94 47.07,14.69 LD9.1 ; v1(128.98,65.08) 129.14,65.24 LD5.1 ; v1(54.39,64.68) 53.89,64.68 C242.2 53.89,65.32 v1(54.39,65.32) ; v1(46.87,62.33) v1(46.44,62.33) v1(45.78,62.33) ; v1(46.87,62.33) v1(46.87,62.76) U56.32 v1(46.87,66.56) v1(46.87,66.99) v1(46.87,67.42) v1(46.87,67.86) 46.87,68.2 ; v1(46.87,62.33) v1(47.3,62.33) v1(47.97,62.33) ; v1(46.87,62.33) v1(46.87,61.9) U56.14 v1(46.87,57.85) v1(46.87,57.42) v1(46.87,56.99) v1(46.87,56.55) 46.87,55.52 ; U35.3 70.25,100.14 v1(69.95,100.44) ; U27.3 v1(96.52,119.59) ; R147.2 v1(93.4,105.72) R146.2 ; C54.2 v1(66.67,164.73) ; v1(37.39,7.18) J24.A12 v1(37.39,8.7) ; SW8.1 SW8.4 63.55,32.72 v1(62.62,33.64) ; U58.K2 v1(74.91,56.83) ; J13.36 v1(131.36,122.75) ; R250.1 35.57,80.73 v1(35.8,80.5) ; C42.2 95.64,166.51 v1(95.4,166.27) ; C218.2 61.5,75.03 61.78,75.03 v1(61.99,74.82) ; U5.A2 v1(98.62,161.88) 98.5,161.77 C72.2 97.68,161.6 97.42,161.35 C75.2 ; v1(58.66,73.69) C216.1 58.62,74.35 57.93,73.66 55.51,73.66 55.26,73.91 v1(55.26,75.82) 55.26,77.68 55.51,77.94 58.48,77.94 58.66,77.76 C213.1 58.21,77.25 v1(58.1,77.14) ; C244.2 v1(122.21,62.72) ; 122.14,163.89 121.79,164.24 C57.2 ; 122.14,163.89 121.79,163.54 C62.2 ; 122.14,163.89 v1(122.17,163.89) ; J12.45 v1(24.67,122.76) ; v1(77.23,162.62) 77.41,162.62 77.66,162.37 C74.2 ; v1(83.09,63.81) 83.08,63.81 82.9,63.63 U58.AB10 ; v1(104.79,162.16) 104.79,162.36 104.53,162.62 C66.2 ; C4.2 v1(17.39,174.16) ; C32.2 v1(95.48,168.51) ; C124.2 71.86,139.71 v1(71.8,139.77) 71.18,139.77 70.55,139.13 v1(70.55,137.82) ; v1(16.46,165.07) 16.46,165.29 16.38,165.36 U2.2 ; 46.87,68.2 46.62,68.46 42.13,68.46 C227.2 ; 46.87,68.2 47.13,68.46 51.61,68.46 C228.2 ; v1(67.09,17.54) 68.3,17.54 69.23,18.47 D4.1 ; v1(79.95,61.41) 79.78,61.57 U58.V8 ; C40.2 37.75,166.93 37.5,167.19 v1(37.5,167.31) 37.5,167.44 37.75,167.7 C34.2 ; v1(83.56,100.12) 83.33,100.35 U33.3 ; v1(15.06,168.79) 15.17,168.69 C37.2 ; v1(34.6,95.7) 34.45,95.86 C180.2 ; U58.A3 v1(68.41,57.63) ; 50.43,23.67 v1(50.43,23.44) ; 50.43,23.67 50.43,24.28 ; 50.43,23.67 50.72,23.96 50.74,23.96 ; U38.2 42.24,91.63 42.37,91.76 C184.1 C185.1 v1(45.41,91.76) ; v1(75.56,100.51) 75.58,100.53 75.71,100.53 76,100.82 76,101.93 C173.2 ; C178.2 v1(96.29,97.37) ; v1(77.04,156.72) 77.48,156.28 C90.2 ; v1(54.77,26.94) 54.34,27.36 C296.2 ; U18.9 84,148.52 v1(83.73,148.78) ; v1(122.17,165.41) 122.14,165.41 ; 122.14,165.41 121.79,165.76 C48.2 v1(121.79,166.4) ; 122.14,165.41 121.79,165.06 C51.2 ; v1(56.51,85.86) C196.2 v1(56.51,84.28) ; v1(53.25,60.29) 53.25,59.86 C254.2 53.89,59.86 v1(53.89,60.28) ; v1(48.17,24.69) 48,24.85 C298.2 ; v1(28.32,65.19) 28.47,65.04 R303.2 ; v1(70.55,137.82) 70.53,137.8 70.53,135.15 71.13,134.55 v1(74.03,134.55) ; v1(70.55,137.82) 70.72,137.65 Y2.4 ; v1(70.55,137.82) 69.27,137.82 TP42.1 ; v1(40.96,155.7) 40.97,155.69 C91.2 ; 50.43,24.28 50.74,23.96 ; 50.43,24.28 v1(50.43,24.52) ; 50.74,23.96 U72.10 ; U68.2 67.97,30.38 v1(67.93,30.34) 67.49,30.34 R367.2 ; R31.2 103.38,161.41 v1(102.92,161.87) U5.A3 ; C181.1 v1(50,94.99) ; U11.2 126.05,154.35 C101.2 125.43,154.33 v1(125.19,154.58) ; R258.2 v1(40.53,77.85) ; U58.N4 76.07,58.83 v1(76.03,58.79) ; v1(43.92,171.6) C19.2 44.51,171.54 U3.43 ; C307.2 34.04,23.23 v1(34.26,23.45) ; C186.1 v1(101.93,92.98) ; 119.12,62.6 119.44,62.92 U55.9 119.95,63.43 v1(120.45,62.93) ; U28.E5 v1(76.22,122.41) ; v1(35.24,78.93) SW5.4 34.25,77.99 v1(34.53,77.71) ; U58.T1 v1(78.48,55.81) ; C240.2 127.58,67.23 v1(127.7,67.34) 127.59,67.34 C233.2 ; C105.2 v1(120.38,152.39) 122.95,152.39 123.49,152.93 v1(123.49,154.6) ; v1(74.03,134.55) 74.1,134.48 75.01,134.48 75.26,134.74 75.26,139.43 74.9,139.79 v1(74.11,139.79) C125.1 ; v1(74.03,134.55) Y2.2 ; C282.1 v1(24.67,37.82) ; C209.1 v1(58.14,78.97) 58.46,79.28 R254.1 ; U64.47 v1(39.2,46.25) ; R245.1 46.79,82.87 v1(47,82.66) ; v1(31.39,8.7) J24.A1 v1(31.39,7.18) 31.34,7.13 J24.B12 ; R85.2 v1(122.71,148.22) ; J12.57 v1(24.62,127.56) ; Y3.4 56.44,81.44 v1(56.7,81.18) 56.87,81.01 C205.1 ; C249.2 38.85,61.79 v1(38.6,61.53) ; v1(93.61,82.96) 93.76,83.11 R247.2 93.98,83.5 U44.2 ; U58.K11 v1(74.91,64.83) ; U58.K11 U58.J12 74.07,65.37 74.07,65.84 v1(74.06,65.85) ; U58.K11 U58.J10 v1(74.26,63.23) U58.K9 ; C294.2 54.36,29.27 v1(54.77,28.87) ; v1(55.01,107.79) 55.71,107.79 55.94,107.57 C157.2 ; v1(37.56,20.95) 37.48,21.03 C309.2 ; v1(128.06,102.92) 128.23,102.75 J13.76 ; U64.35 39.12,40.25 39.14,40.27 C281.1 v1(40.55,40.27) ; R203.1 v1(123.2,94.65) 123.2,94.7 122.41,95.48 Q1.4 Q1.7 ; C100.2 68.95,154.64 v1(68.75,154.84) 68.91,154.84 69.16,155.1 C95.2 ; v1(26.65,8.87) 26.91,9.13 R404.2 ; v1(69.66,65.76) 69.65,65.7 U58.C12 ; R373.2 68.17,28.81 67.93,29.05 R372.2 ; J13.49 122.73,113.15 v1(122.41,112.83) ; U58.Y8 v1(80.76,62.43) U58.W9 ; U49.E7 99.6,75.72 v1(99.85,75.97) ; U58.D2 v1(70.36,57.63) ; v1(37.42,62.63) 37.48,62.63 37.57,62.72 C248.2 38.12,62.72 38.28,62.88 C245.2 ; v1(43.25,61.83) U56.6 ; R143.2 68.79,111.84 v1(68.65,111.98) ; v1(55.17,9.76) 54.8,10.14 D6.1 ; C231.1 121.86,67.78 122.12,67.52 v1(122.12,67.33) ; v1(76.93,164.5) 76.84,164.41 R26.2 ; R30.2 v1(121.83,162.04) ; C207.2 43.74,82.78 C204.2 v1(43.31,83.05) ; v1(122.34,162.16) 122.29,162.21 122.29,162.36 122.03,162.62 C67.2 ; SW6.1 67.92,39.99 68.17,40.24 v1(68.17,41.07) 68.17,42.09 69.16,43.08 U65.4 ; C290.2 68.35,36.26 68.75,36.66 v1(68.75,36.72) 68.99,36.48 C286.1 C284.1 ; J12.81 v1(20.16,102.69) J12.82 v1(20.16,108.85) J12.83 v1(20.16,114.86) J12.84 v1(20.16,118.82) J12.85 v1(20.16,122.74) J12.86 v1(20.16,128.72) J12.87 v1(20.16,134.86) J12.88 ; U58.D4 v1(71.01,59.23) U58.E5 ; v1(54.25,83.64) 53.97,83.36 C201.2 ; R63.2 v1(73.58,154.35) ; U64.1 v1(27.72,46.75) ; U58.J1 v1(73.93,55.81) ; U57.9 21.66,61.36 C253.2 ; v1(37.56,22.88) 37.22,22.53 C306.2 ; J13.81 v1(126.84,134.86) J13.82 v1(126.84,128.72) J13.83 v1(126.84,122.74) J13.84 v1(126.84,118.82) J13.85 v1(126.84,114.86) J13.86 v1(126.84,109.11) J13.87 v1(126.84,102.69) J13.88 ; C151.1 73.25,114.37 v1(73.21,114.33) 72.71,114.83 C150.1 ; TP41.1 88.28,138.89 v1(88.28,137.97) ; v1(83.24,111.27) 83.59,111.27 83.91,110.95 C155.2 ; U58.E1 71.33,55.8 v1(71.2,55.67) ; v1(71.63,52.82) 71.42,52.61 71.42,51.98 R325.2 71.42,51.81 71.81,51.42 U63.2 ; U15.A2 115.72,149.13 v1(115.49,149.35) ; U58.D9 v1(70.36,62.43) U58.C8 ; C139.2 v1(78.74,132.52) ; U58.G3 v1(72.96,57.63) ; v1(37.92,11.57) 37.96,11.61 C324.2 ; U22.7 79.52,139.72 v1(79.75,139.49) ; U58.Y12 81.08,65.49 81.44,65.85 v1(81.59,65.85) ; C50.2 104.39,165.06 104.74,165.41 ; v1(40.65,12.21) 40.63,12.24 C320.1 ; C109.2 89.44,147.17 v1(89.53,147.07) ; R68.1 92.1,154.66 v1(92.1,154.67) ; C322.2 43.42,12.53 v1(43.1,12.21) 43.05,12.16 42.17,12.16 41.89,12.44 C325.2 ; v1(68.5,144.91) 68.81,145.21 C114.2 ; C215.1 v1(134.75,75.92) ; D7.2 33.67,11.08 v1(33.84,11.26) ; U3.16 43.51,160.6 43.42,160.51 C79.2 v1(42.69,160.05) ; v1(123.49,154.6) 123.49,158.81 122.81,159.49 121.52,159.49 v1(120.97,160.05) 120.78,160.24 R32.2 120.78,161.41 v1(120.32,161.87) U6.A3 ; v1(123.49,154.6) 123.3,154.6 123.29,154.59 Y1.4 ; C316.2 63.6,15.89 v1(63.58,15.88) ; R145.2 v1(92.09,105.72) ; C323.2 44.94,12.8 v1(44.29,12.14) ; R355.1 89.46,46.15 v1(89.65,46.34) ; v1(72.77,60.23) 72.63,60.09 U58.G5 ; v1(92.95,89.07) 92.95,88.89 93.5,88.34 R226.2 ; U70.4 44.98,28.21 v1(45.18,28) ; R381.2 26.52,25.97 v1(26.59,26.05) ; C126.1 v1(107.71,138.14) ; U58.N2 v1(76.21,56.83) ; J12.36 v1(15.64,114.76) ; R230.1 R231.1 R232.1 ; R230.1 R229.1 ; R230.1 v1(119.46,89.01) ; C206.2 88.03,81.78 v1(87.74,82.07) ; U50.4 v1(27.12,71.27) ; R274.1 32.34,70.57 v1(32.55,70.36) ; R109.2 C132.2 C131.2 76.22,135.79 v1(76.22,135.79) ; v1(135.38,72.21) 135.51,72.34 C222.2 C221.2 ; R152.2 v1(99.73,105.72) R151.2 ; LD3.1 v1(134.65,68.4) ; C257.2 42.04,55.64 v1(42.04,56.44) ; v1(127.91,106.79) 127.95,106.75 J13.66 ; C94.2 v1(50.02,155.28) ; C321.2 36.43,13.59 v1(36.87,13.15) ; C156.2 63.13,110.15 v1(63.2,110.08) ; J13.26 v1(131.36,126.75) ; v1(115.75,158.73) 113.99,158.73 113.55,158.3 v1(113.55,157.15) ; v1(128.33,67.76) 128.34,67.78 C234.2 ; U19.3 v1(28.58,146.42) ; v1(128.1,114.75) 128.1,114.75 J13.46 ; J13.57 v1(122.33,109.95) ; C232.2 125.09,67.35 v1(124.91,67.17) ; 104.74,165.41 104.39,165.76 C47.2 ; 104.74,165.41 v1(104.77,165.41) ; J12.22 15.93,109.16 v1(15.74,109.35) ; U62.2 v1(77.03,51.21) ; U64.13 25.55,40.75 v1(25.41,40.61) 25.23,40.43 C280.1 ; C214.2 52.91,75.82 v1(52.89,75.84) ; C98.2 77.65,154.23 v1(77.88,154) ; J12.58 v1(15.64,127.56) ; U15.A4 119.61,145.23 v1(119.73,145.11) ; J12.35 v1(24.67,114.76) ; J12.65 v1(24.67,130.76) ; v1(40.11,56.44) 40.11,55.79 C256.2 ; C1.2 v1(22.24,175.85) ; U49.J5 v1(101.35,75.47) 101.35,75.94 101.63,76.22 U49.K8 ; R103.1 v1(27.31,140.81) ; R156.2 R157.2 109.31,105.72 109.48,105.89 109.86,105.89 110.03,105.72 R158.2 v1(110.98,105.72) R159.2 v1(112.25,105.72) R160.2 ; C190.2 134.14,86.63 v1(134.26,86.5) 134.08,86.32 U41.1 ; C10.2 44.03,173.48 v1(44.03,173.48) ; C2.2 v1(73.96,173.23) ; J18.17 86.41,39.24 v1(86.13,38.96) ; v1(103.37,138.39) R107.2 103.94,139.15 104.13,139.34 U21.25 ; C61.2 104.39,163.54 104.74,163.89 ; C187.1 101.87,89.05 v1(101.74,88.92) ; v1(76.53,66.46) 77.18,65.81 U58.P12 U58.N11 ; U58.P3 v1(76.86,58.43) ; v1(42.31,10.9) 42.58,10.63 R403.2 ; C182.2 52.01,94.35 v1(51.96,94.4) ; v1(83.23,153.82) 83.71,154.3 C96.2 ; v1(125.71,70.64) 125.92,70.64 126.2,70.36 U48.114 ; v1(106.34,86.18) 106.51,86.36 C192.2 ; v1(74.94,113.12) 75.3,112.77 C154.2 ; U48.64 119.4,85.38 119.15,85.63 v1(118.76,85.63) ; U58.D11 v1(70.36,64.03) ; U28.C1 81.5,120.69 82.35,120.69 C149.1 ; U47.R6 v1(78.76,75.19) ; C116.2 76.86,143.76 v1(76.83,143.73) ; Y3.2 v1(54.25,80.09) ; U28.B3 v1(78.28,118.38) ; C153.2 80.2,111.91 v1(80.36,111.74) ; v1(53.36,79.36) C210.2 v1(51.48,79.36) ; v1(27.79,39.8) 27.74,39.75 U64.15 ; C76.2 114.67,161.35 v1(114.87,161.15) 115.08,161.35 C73.2 ; J13.31 v1(122.33,124.35) ; C162.2 v1(50.09,106.75) ; J23.4 v1(68.54,11.69) ; v1(113.55,157.15) 114.05,157.15 114.07,157.13 Y1.2 ; U58.N9 U58.P10 U58.N11 ; J13.50 128.21,113.15 v1(128.08,113.28) ; v1(78.66,156.67) C89.2 ; v1(122.32,102.72) 122.35,102.75 J13.75 ; v1(42.54,19.98) 42.91,19.98 C312.2 ; v1(24.63,73.97) 24.38,73.72 Q2.2 ; C87.2 83.88,157.2 83.88,157.48 84.08,157.69 v1(84.16,157.69) ; v1(63.92,78.54) 66.36,78.54 v1(66.61,78.79) ; C146.2 65.33,127.47 65.31,127.44 v1(64.82,127.44) ; v1(115.42,144.66) 115.72,144.95 U15.A3 ; U3.10 39.54,164.07 39.36,163.89 38.84,163.89 C58.2 v1(38.82,163.4) ; U4.2 20.54,167.7 C33.1 20.5,168.99 C28.2 v1(20.51,170.1) ; U49.G5 100.35,74.47 v1(100.6,74.22) ; v1(71.21,61.48) 71.21,61.91 U58.E8 ; U58.T12 v1(78.48,65.85) ; C60.1 66.72,163.72 v1(66.7,163.73) ; v1(93.91,89.07) 93.97,89.07 94.49,89.59 95.17,89.59 95.39,89.38 C189.1 ; C69.2 22.26,162.73 v1(22.41,162.87) ; R71.2 16.66,153.56 v1(16.46,153.76) ; R370.2 v1(46.39,30.69) R369.2 ; C36.2 v1(52.79,168.07) ; J13.45 v1(122.33,114.75) ; U58.G10 v1(72.96,64.03) ; U3.30 v1(47.81,165.57) ; R155.2 R154.2 v1(104.55,105.72) R153.2 ; R150.2 v1(97.2,105.72) R149.2 ; C122.1 v1(83.34,141.26) ; v1(82.38,61.41) U58.AB8 ; J12.46 v1(15.64,122.76) ; U58.Y1 v1(80.76,56.83) U58.W2 ; v1(52.91,37.89) 52.91,37.7 53.16,37.45 SW7.1 ; U37.6 v1(23.06,95.1) ; C41.2 36.32,166.7 36.07,166.44 v1(36.07,166.31) 36.07,166.19 36.32,165.93 C44.2 ; C225.1 v1(114.98,70.9) ; C84.2 v1(73.71,157.12) ; U58.T5 v1(78.16,59.23) ; C31.2 112.67,168.7 v1(112.44,168.93) ; R278.1 v1(114.46,70.45) ; v1(119.4,149.27) 119.22,149.09 U15.A1 ; U58.K4 75.05,58.83 v1(75.09,58.79) ; C152.2 79.42,112.07 v1(79.09,111.74) ; v1(53.51,56.44) 53.51,55.66 C259.2 ; C199.1 v1(43.56,84.06) ; C159.2 62.83,106.64 v1(63.2,106.27) ; U26.3 v1(61.03,124.6) ; C270.2 24.2,44.69 24.45,44.43 25.13,44.43 v1(25.45,44.75) U64.5 ; U58.AB3 v1(82.06,57.63) ; v1(21.45,95.69) 21.61,95.53 R194.2 22.29,95.53 22.29,96.87 22.54,97.12 R181.1 ; C169.2 v1(113.98,104.81) ; v1(122.42,106.75) J13.65 ; C123.2 v1(29.5,140.55) ; C163.2 65.19,106.02 64.93,106.27 v1(64.47,106.27) ; C305.2 v1(42.54,22.88) ; U72.15 v1(49.57,25.36) ; U9.2 v1(39.75,155.33) ; v1(72.26,163.27) 72.05,163.07 C64.2 ; v1(76.55,107.93) 76.25,107.63 C158.2 ; C197.2 41.43,84.92 v1(41.26,85.09) ; U58.J3 v1(74.26,58.43) ; v1(104.43,74.14) 104.35,74.22 U49.P4 ; U58.A10 v1(68.41,64.03) ; U31.3 v1(58.81,102.19) ; C86.2 v1(77.49,157.6) ; 104.74,163.89 104.39,164.24 C56.2 ; 104.74,163.89 v1(104.77,163.89) ; C258.2 51.58,55.66 v1(51.58,56.44) ; U10.5 v1(19.97,156.87) ; U34.7 102.39,103.11 102.65,103.37 v1(102.65,103.69) ; C148.2 v1(100.44,120.51) ; R94.2 v1(79.33,143.84) ; U58.T3 v1(78.16,57.63) ; v1(78.48,61.19) U58.T8 ; C268.1 69.61,49.06 v1(69.7,49.15) ; R218.2 122.86,90.24 v1(122.87,90.23) ; v1(71.36,66.44) 71.36,66.41 71.33,66.38 U58.E12 ; v1(85.53,105.67) 85.93,105.27 C166.2 ; U30.3 v1(54.22,107.74) ; v1(54.82,30.65) 54.82,31.12 SW7.4 ; R22.2 79.14,165.14 78.89,165.39 v1(78.69,165.39) ; C39.2 v1(50.69,168.18) ; U58.V5 v1(79.78,60.25) ; Q3.2 v1(38.78,69.91) ; U58.Y5 v1(80.76,59.23) U58.W4 ; v1(91.77,85.64) 91.74,85.67 90.97,85.67 90.64,85.33 C198.2 v1(90.64,84.01) 90.95,84.01 91.13,83.83 C202.2 ; C9.2 23.23,171.31 v1(23.53,171.02) ; J13.15 v1(122.33,130.75) ; C252.2 v1(53.57,60.6) ; C35.2 112.75,167.68 v1(112.36,168.08) ; U58.C5 v1(69.71,59.23) ; R61.2 v1(71.8,154.35) ; U58.G1 v1(72.31,56.03) ; C43.2 114.65,166.51 v1(114.83,166.7) 114.95,166.58 C46.2 ; C191.1 43.78,86.3 44.03,86.04 v1(44.12,86.04) ; C183.2 v1(25.59,91.68) ; J25.B1 52.44,5.65 v1(52.25,5.45) ; v1(71.96,161.62) C78.2 73.69,161.62 73.98,161.91 C77.2 74.58,162.66 v1(74.45,162.79) ; C70.2 v1(17.86,162.24) ; v1(26.38,66.7) 26.38,66.7 U54.2 ; J12.66 v1(15.64,130.76) ; v1(37.31,85.78) 37.74,85.78 38.2,86.24 LD6.1 ; U64.25 v1(32.54,38.51) ; v1(43.03,24.7) 43.13,24.6 C301.2 ; R202.2 68.49,94.29 v1(68.16,94.63) ; C117.2 77.84,143.22 v1(77.74,143.12) ; v1(71.66,147.06) C112.2 ; J12.75 v1(24.67,134.76) ; U58.G8 72.63,61.51 v1(72.66,61.48) ; v1(120.06,166.46) 119.89,166.28 U6.A4 ; C275.1 v1(39.82,45.44) ; R313.2 v1(115.27,61.98) ; R238.2 v1(100.43,87.54) ; U6.A2 v1(116.02,161.88) ; v1(102.83,98.28) C177.2 ; C217.1 v1(116.65,74.96) ; v1(116.05,166.14) U6.A1 ; R27.2 v1(122.54,161.42) ; R341.1 v1(121.1,46.89) ; U58.T10 v1(78.16,64.03) ; R391.2 v1(47.25,20.58) ; SW4.1 28.27,85.79 v1(27.66,85.18) ; C261.2 v1(38.93,55.42) ; J13.58 128.22,109.95 v1(127.93,110.24) ; C193.2 v1(47.63,85.54) ; C127.2 v1(76.34,139.12) ; v1(82.38,60.25) U58.AB5 ; R214.1 90.42,91.93 v1(90.26,92.09) ; J12.50 v1(15.64,124.36) ; U14.3 v1(94.39,150.77) ; J13.35 v1(122.33,122.75) ; C165.1 48.35,105.66 v1(48.51,105.81) ; J25.B12 46.39,6.29 v1(46.39,7.18) J25.A1 v1(46.39,8.7) ; C264.1 v1(33.52,51.22) ; C269.2 v1(24.2,49.39) ; v1(98.65,166.14) U5.A1 ; C121.2 v1(117.36,141.5) ; C102.1 v1(30.05,155.42) ; J12.7 v1(24.67,103.56) ; J12.25 v1(24.73,110.76) ; U58.N11 v1(76.21,64.83) ; C143.2 55.3,130.88 v1(55.14,131.05) ; v1(100.62,77.72) 100.85,77.49 U49.H10 ; C223.1 v1(116.65,72.75) ; J25.A12 v1(52.39,7.18) ; J12.76 v1(15.64,134.76) ; C220.1 v1(30.04,73.94) ; C3.2 v1(91.1,173.23) ; v1(24.5,124.27) 24.41,124.36 J12.49 ; J13.7 v1(122.33,133.95) ; U43.2 v1(102.57,85.76) ; C30.2 v1(115.25,169.58) ; U47.T5 v1(79.56,74.39) ; SW4.4 v1(35.53,85.79) ; U58.P1 v1(76.92,55.81) ; U67.4 v1(19.9,32.19) ; R320.2 C255.2 ; J13.25 v1(122.33,126.75) ; C99.2 v1(132.82,154.32) ; R100.2 v1(80.25,142.87) ; J12.15 v1(24.67,106.76)
  TOP w0.305: U47.Y12 v1(82.76,80.79) ; U59.4 59.89,61.24 v1(59.6,61.53) ; R383.2 58.23,25.34 v1(58.03,25.54) ; v1(56.51,84.28) 56.34,84.11 C200.2 ; U47.T1 79.16,71.17 v1(79.25,71.08) ; C289.1 36.52,34.67 v1(36.72,34.47) ; C179.2 26.14,97.84 v1(26.19,97.9) ; v1(81.59,65.85) 81.49,65.95 C239.2 ; v1(82,120.07) 82.32,120.07 C149.1 ; C238.2 69.52,65.9 v1(69.66,65.76) ; C236.1 v1(114.47,67.25) ; C327.2 31.39,9.45 v1(31.23,9.61) ; U60.3 128.38,53.11 v1(128.08,53.41) ; C263.2 v1(35.04,51.11) ; C65.2 v1(66.84,162.83) ; v1(60.32,74.65) 60.08,74.42 C219.2 ; C237.2 71.45,66.53 v1(71.36,66.44) ; R112.1 93.77,134.97 v1(93.95,135.15) ; v1(61.66,55.43) 61.84,55.62 C255.2 ; v1(28.74,63) 28.69,63 28.56,62.86 U57.5 ; C299.2 62.76,24.83 v1(62.79,24.8) ; v1(60.24,61.6) C251.1 61.3,62.48 C247.1 ; v1(73.96,75.99) U47.K7 v1(74.76,76.79) ; v1(75.18,68.02) C664.2 ; C147.2 v1(111.76,123.4) ; U47.R6 v1(77.96,75.19) ; U47.AB18 v1(84.36,85.59) ; C326.2 36.92,9.46 v1(37.09,9.62) ; v1(94.1,132.01) 94.21,131.9 U23.3 ; U47.D4 v1(69.16,73.59) ; v1(135.56,67.32) 135.28,67.04 R289.2 ; U47.AB22 83.96,88.98 v1(84.16,89.18) ; v1(93.12,135.15) 92.87,134.9 C136.2 ; C43.2 v1(113.8,167.13) ; C241.2 117.46,65.91 117.46,65.91 ; U47.U2 v1(80.36,71.99) ; U47.E5 v1(69.96,74.39) ; U47.AB5 v1(84.36,74.39) ; C53.1 v1(72.28,165.72) ; U47.AB3 v1(84.36,72.79) ; U47.W11 v1(81.96,79.19) ; C235.1 v1(116.42,67.74)
  TOP w0.356: U47.B7 v1(67.56,75.99) ; U47.J17 v1(73.16,84.79) ; U47.N1 v1(77.16,71.19) ; U47.N8 v1(77.16,76.79) ; U47.R10 v1(78.76,78.39) ; U47.Y15 v1(82.76,83.19) ; 46.87,52.22 46.87,52.2 v1(47.08,51.99) ; 46.87,52.22 v1(46.64,51.99) ; 46.87,52.22 46.87,53.11 ; U47.N12 v1(77.16,80.79) ; U47.U14 v1(80.36,82.39) ; U47.W14 v1(81.96,81.59) ; U47.Y9 v1(82.76,77.59) ; U47.P17 v1(77.96,84.79) ; U47.G9 v1(71.56,77.59) ; U47.A18 v1(66.6,85.19) ; U47.AA2 v1(83.56,71.99) ; U47.W4 v1(81.96,73.59) ; U47.F4 v1(70.76,73.59) ; U47.AA14 v1(83.56,81.59) ; v1(46.64,51.99) v1(47.08,51.99) ; v1(46.64,51.99) v1(46.64,52.91) 46.87,53.14 ; v1(47.08,51.99) v1(47.08,52.91) 46.87,53.11 ; 46.87,53.14 46.87,53.11 ; 46.87,53.14 v1(46.87,53.82) v1(46.87,54.67) 46.87,55.52 ; U47.D11 v1(69.16,79.19) ; U47.L3 v1(74.76,72.79) ; U47.M17 v1(76.36,84.79) ; U47.A6 v1(66.76,75.19) ; U47.Y5 v1(82.76,74.39) ; U47.N10 v1(77.16,78.39) ; v1(73.96,71.99) U47.K1 v1(74.76,71.99) ; U47.T17 v1(79.56,84.79) ; U47.P20 v1(77.96,87.19) ; U47.V1 v1(81.16,71.99) U47.W2 ; U47.AB15 84.77,82.79 v1(84.88,82.69) ; v1(78.76,72.79) U47.T3 ; U47.L12 v1(74.76,80.79) ; U47.F16 v1(70.76,83.99) ; U47.L20 v1(74.76,87.19) ; U47.G5 v1(71.56,74.39) ; U47.H1 v1(72.36,71.99) ; U47.F11 v1(70.76,79.19) ; U47.G12 v1(71.56,80.79) ; U47.R16 v1(78.76,83.99) ; U47.C4 v1(68.36,73.59) ; U47.P13 v1(77.96,81.59) ; U47.E1 v1(69.96,71.19) ; U47.W8 v1(81.96,76.79) ; U47.F13 v1(70.76,81.59) ; C260.2 54.77,55.45 v1(54.19,56.02) ; U47.P7 v1(77.96,75.99) ; U47.N16 v1(77.16,83.99) ; U47.J3 v1(73.16,72.79) ; U47.L14 v1(74.76,82.39) ; U47.J12 v1(73.16,80.79) ; U47.B3 v1(67.56,72.79) ; U47.K4 v1(73.96,73.59) ; U47.Y3 v1(82.76,72.79) ; U47.H4 v1(72.36,73.59) ; U47.AB1 v1(84.36,71.19) ; U47.A22 v1(66.6,88.39) ; U47.D20 v1(69.16,87.19) ; U47.AA8 v1(83.56,76.79) ; U47.P11 v1(77.96,79.19) ; U47.AB9 v1(84.36,77.59) ; U47.AA11 v1(83.56,79.19) ; U47.V9 v1(81.16,77.59) ; U47.H14 v1(72.36,82.39) ; U47.U6 v1(80.36,75.19) ; U47.H11 v1(72.36,79.19) ; U47.G3 v1(71.56,72.79) ; U47.A1 v1(66.76,71.19) ; U47.D2 v1(69.16,71.99) ; U47.E3 v1(69.96,72.79) ; U47.R12 v1(78.76,80.79) ; U47.A4 v1(66.76,73.59) ; U47.R4 v1(78.76,73.59) ; U47.T5 v1(78.76,74.39) ; U47.W6 v1(81.96,75.19) ; U47.G17 v1(71.56,84.79) ; U47.U4 v1(80.36,73.59) ; U47.AA4 v1(83.56,73.59) ; U47.K9 v1(73.96,77.59) ; U47.V3 v1(81.16,72.79) ; U47.H20 v1(72.36,87.19) ; U47.A13 v1(66.6,81.19) ; U47.V5 v1(81.16,74.39) ; U47.U9 v1(80.36,77.59) ; U47.P15 v1(77.96,83.19) ; U47.R2 v1(78.76,71.99) ; U47.T15 v1(79.56,83.19) ; U47.V7 v1(81.16,75.99) ; U47.M4 v1(76.36,73.59) ; U47.M7 v1(76.36,75.99) ; U47.M11 v1(76.36,79.19) ; U47.U16 v1(80.36,83.99) ; U47.N14 v1(77.16,82.39) ; U47.T7 v1(79.56,75.99) ; U47.A10 v1(66.61,78.79) ; U47.V20 v1(81.16,87.19) ; U47.F2 v1(70.76,71.99) ; U47.B5 v1(67.56,74.39) ; U47.K11 v1(73.96,79.19) ; U47.R14 v1(78.76,82.39) ; U47.U12 v1(80.36,80.79)
  TOP w0.381: C80.2 v1(42.58,158.9) ; v1(73.71,157.12) 73.77,157.06 74.12,157.06 74.12,157.05 C85.2 ; C97.1 v1(78.66,154.02) ; v1(19.51,28.56) C295.2 17.57,28.56 17.16,28.97 17.16,29.36 16.71,29.81 J22.5 ; D2.1 32.57,62.28 v1(32.78,62.48) ; U32.7 39.68,100.83 39.57,100.72 v1(38.14,100.72) ; C106.1 38.24,150.11 C107.2 v1(38.07,151.16) ; U13.3 53.61,150.64 v1(53.86,150.39) ; v1(77.23,162.62) 77.17,162.69 C71.2 ; U17.2 46.39,146.04 46.65,146.3 47.23,146.3 C113.2 47.26,145.11 v1(46.98,144.83) ; C52.2 v1(73.3,165.87) ; C83.2 v1(35.85,158.95) ; U46.2 41.58,84.37 41.8,84.59 C197.2
  L03_SIG01 w0.102: v1(43.25,61.83) 44.26,62.84 44.26,64.72 45.25,65.72 45.25,66.96 47.1,68.81 47.1,71.78 50.07,74.74 55,74.74 57.07,72.67 59.71,72.67 61.36,74.32 61.36,76.42 61.55,76.61 62.1,76.61 62.14,76.64 62.44,76.95 63.19,76.95 64.53,78.29 64.53,79.24 64.87,79.58 71.97,79.58 v1(72.36,79.19)
  BOTTOM w0.102: v1(81.96,76.79) 81.84,76.91
  BOTTOM w0.127: v1(111.7,105.2) U87.3
  BOTTOM w0.14: v1(98.93,109.98) 98.93,109.84 99.29,109.48 U83.11
  BOTTOM w0.152: v1(36.17,68.64) 36.17,68.53 36.57,68.14 36.57,68.14 36.58,68.13 U113.C1 ; v1(49.13,88.96) 49.39,89.23 U92.B3 ; v1(51.8,88.86) 51.52,88.58 51.02,88.58 50.77,88.83 U92.C1 ; U118.7 58.19,50.38 57.83,50.01 57.83,49.34 58.02,49.14 U119.C1 ; U122.7 52.72,45.47 52.39,45.15 52.39,44.43 52.62,44.21 U121.C1 ; v1(66.76,73.59) 66.35,73.59 66.16,73.79 R573.2
  BOTTOM w0.191: C342.1 123.25,171.48 123.77,172 123.77,172.19 123.77,175.74 120.5,179 118.96,179 v1(117.97,178.02) ; v1(75.29,177.72) 75.29,176.45 73.49,174.65 72.89,174.65 72.4,175.15 72.4,176.43 71.25,177.58 C336.1 ; U83.13 97.42,109.96 v1(97.43,109.98) ; v1(99.71,116.78) 99.48,116.55 C394.1 ; U126.7 26.45,34.16 v1(26.36,34.25) ; v1(114.02,114.14) 114.03,114.15 U81.12 ; U80.10 73.38,116.05 v1(73.49,115.95) 73.19,115.65 U80.11 ; U83.12 98.92,109.96 v1(98.93,109.98) ; C340.2 76.19,174.05 v1(76.04,173.9) 75.7,173.57 75.7,172.78 76.16,172.32 R415.1 ; v1(27.15,35.15) 27.26,35.26 27.53,35.26 27.67,35.13 U126.9 ; C343.1 110.83,171.77 110.28,172.33 110.28,172.52 110.28,173.68 109.02,174.95 109.02,177.33 v1(109.58,177.89) ; C414.1 v1(106.68,103.35) ; U89.3 70.45,101.8 v1(69.73,102.52) ; C352.2 109.77,168.04 v1(109.51,168.3) ; v1(109.67,105.43) 107.91,105.43 107.6,105.12 U86.2 ; v1(116.45,108.93) 116.45,108.65 C408.2 ; R569.1 122.87,74.65 v1(122.82,74.6) ; C415.1 111.09,103.33 v1(110.82,103.33) ; v1(104.58,116.86) 104.85,116.86 105.1,116.61 R456.2 105.1,115.81 105.51,115.4 U82.25 105.51,114.14 105.82,113.84 v1(105.82,113.71) ; v1(92.44,177.9) 92.44,176.84 91.13,175.53 89.92,175.53 89.47,175.97 89.47,176.42 88.39,177.5 C332.1 ; C341.1 128.13,171.77 127.61,172.3 127.61,172.49 127.61,173.22 125.24,175.59 125.24,178.27 v1(125.69,178.72) ; C344.1 105.85,171.48 106.37,172 106.37,176.37 103.67,179.07 101.6,179.07 v1(100.62,178.1) ; C409.1 114.59,108.75 v1(114.75,108.9) ; U81.11 113.06,116.02 v1(113.73,116.7) ; C395.2 97.64,116.29 v1(97.14,116.8) ; v1(67.13,179.1) 66.61,178.58 66.61,176.66 67.75,175.51 68.33,175.51 68.59,175.77 68.59,176.47 67.41,177.65 C338.1 ; U75.3 v1(83.2,171.07) ; v1(84.3,179.58) 84.3,178.88 83.44,178.03 83.44,177.12 84.94,175.62 85.44,175.62 85.63,175.81 85.63,176.23 84.55,177.31 C334.1 ; v1(46.77,43.44) 46.92,43.44 47.22,43.13 U123.C1 ; v1(115.54,114.14) 115.53,114.15 U81.13 ; C393.1 108.51,116.91 108.82,117.21 108.82,117.65 109.25,118.08 v1(109.25,118.51) ; C391.1 v1(105.95,118.21) ; U88.3 v1(116.55,103.83)
  BOTTOM w0.203: C612.1 28.63,40.16 29.07,40.6 U125.1 ; v1(113.49,95.28) 113.49,95.29 113.55,95.35 U90.3 ; U102.4 120.67,78.44 v1(120.46,78.65) ; U109.6 120.56,74.33 v1(120.36,74.53) 120.16,74.33 U109.5 ; U110.11 126.04,72.86 v1(126.24,73.06) 126.04,73.26 U110.10 ; v1(104.43,74.14) 104.65,74.36 C518.2 ; U126.14 v1(30.94,34.16) ; v1(42.54,19.98) 42.74,19.78 U129.51 ; U126.10 28.07,35.22 v1(28.26,35.41) 28.26,35.41 28.47,35.2 U126.11 ; U129.20 37.36,19.78 v1(37.56,19.98) ; U125.11 31.63,41 v1(31.83,41.2) 31.63,41.4 U125.10 ; v1(52.25,5.45) 52.09,5.29 D16.2 ; U97.11 v1(121.5,83.52) 121.1,83.12 U97.10 ; U125.14 30.44,40.79 v1(30.2,41.03) ; U125.7 30.44,43.04 v1(30.65,43.25) ; v1(29.51,32.39) 29.4,32.39 28.87,32.92 U126.1 ; v1(34.07,5.35) 34.32,5.1 D17.2 ; U116.7 55.56,58.94 55.29,58.67 54.63,58.67 54.37,58.92 v1(54.37,59.28) 53.81,59.28 53.61,59.08 53.61,58.79 54.64,57.75 U115.C1 ; U117.10 33.16,55.08 v1(32.96,54.88) 32.76,55.08 U117.11 ; v1(28.87,39.59) 28.91,39.55 29.44,39.55 29.64,39.74 U125.16 ; v1(32.68,41.25) 32.04,40.6 U125.12 ; v1(120.42,71.73) 120.56,71.86 U109.3 ; v1(71.24,30.27) 70.75,30.76 70.27,30.76 70.1,30.59 R639.1 69.58,30.1 69.93,29.76 R642.1 ; C396.1 v1(68.38,115.65) ; v1(114.55,47.16) R606.2 114.54,47.7 114.05,47.7 113.9,47.55 U120.2 ; U90.6 113.55,97.98 v1(113.35,98.18) 113.15,97.98 U90.5 ; v1(28.54,35.96) 28.95,35.55 28.95,35.18 28.87,35.1 U126.12 ; U130.4 v1(63.76,17.21) ; C511.1 121.78,75.8 v1(122.16,75.42) 122.06,75.32 C515.1 ; U125.9 31.48,41.8 v1(31.8,42.11) ; v1(30.3,32.89) 30.3,33.16 30.09,33.36 U126.16 ; v1(99.71,77.75) 99.67,77.71 C504.2 ; C392.1 v1(68.42,116.77) ; v1(67.7,35.96) R628.1 69.14,35.96 69.49,36.31 R626.1 ; R607.2 113.86,45.84 v1(114.09,45.61) ; U117.1 32.36,57.63 31.92,58.07 C575.1 ; v1(93,32.28) 92.76,32.04 U127.4 ; C637.2 v1(67.09,17.54)
  BOTTOM w0.229: C360.2 v1(104.77,165.41) C362.2 ; C354.2 v1(111.99,167) ; C354.2 111.32,166.56 111.09,166.33 110.81,166.33 110.51,166.04 U77.A1 ; C354.2 111.32,167.24 111.76,167.67 C350.2 v1(112.36,168.08) ; v1(106.9,166.3) 107.06,166.14 U77.A4 ; U77.A2 110.51,161.93 110.67,161.77 C372.2 112.17,161.77 112.59,161.35 C374.2 v1(113.02,160.7) ; C366.2 v1(122.17,163.89) C364.2 ; C384.2 119.05,148.92 v1(119.4,149.27) ; C367.2 v1(104.77,163.89) C365.2 ; C357.2 129.39,166.67 v1(129.3,166.77) 129.07,167 C353.2 ; v1(131.47,161.35) C373.2 129.97,161.35 129.55,161.77 C371.2 128.57,161.77 128.4,161.93 128.4,162.16 128.26,162.31 U76.A2 ; U77.A3 107.06,162.05 106.94,161.93 v1(106.94,161.8) ; C386.2 118.25,145.25 118.46,145.04 118.46,144.37 118.33,144.24 v1(118.33,144.24) ; U76.A1 128.22,165.76 v1(128.44,165.98) ; v1(104.79,162.16) 104.79,162.25 C370.2 ; v1(102.57,85.76) 102.32,86.01 C421.1 ; U114.2 37.63,64.68 v1(37.85,64.46) 38.13,64.74 U114.1 ; v1(124.32,166.32) 124.46,166.18 U76.A4 ; C387.2 116.63,145.25 116.43,145.06 116.43,144.64 v1(115.9,144.1) ; v1(118.03,147.59) 117.97,147.65 C382.2 ; C383.2 117.21,148.04 v1(116.76,147.59) ; R430.2 123.76,161.31 123.99,161.54 124.23,161.54 124.46,161.77 U76.A3 ; C359.2 v1(122.17,165.41) C361.2 ; v1(113,167.21) 113.15,167.06 C356.2 112.74,166.51 112.32,166.09 C358.2 ; v1(38.71,68.71) 38.12,68.13 U113.C3 U113.B3 ; C355.2 130.55,167.2 v1(130.36,167.39) ; v1(122.34,162.16) 122.55,162.38 C369.2 ; U114.7 36.63,71.16 36.38,71.41 36.38,71.95 C525.2 36.38,72.64 v1(36.21,72.81) ; R429.2 v1(105.29,161.76)
  BOTTOM w0.254: v1(27.72,46.75) 27.99,46.49 C606.1 ; R591.1 36.08,57.51 v1(36.27,57.7) ; U116.7 55.56,60.71 55.31,60.97 C560.2 ; 76.33,79.19 75.93,79.59 ; 75.93,79.59 C477.2 ; 75.93,79.59 C663.2 74.76,80.77 v1(74.76,80.79) ; C423.2 91.2,85.23 91.6,85.64 v1(91.77,85.64) ; C398.2 v1(61.52,115.57) ; C475.2 86.29,80.44 v1(85.94,80.79) ; C475.2 85.1,80.04 R557.2 ; C475.2 C474.2 ; v1(25.34,31.88) R635.1 ; v1(90,78.44) 89.87,78.57 C487.2 C497.2 ; C509.2 71.68,76.11 v1(71.56,75.99) ; U117.16 31.61,57.07 31.36,57.32 v1(31.36,57.74) 31.36,58.19 31.54,58.37 C575.1 ; C581.2 79.74,56.54 79.48,56.81 C580.2 ; C644.2 43.42,12.53 v1(43.1,12.21) 42.37,12.21 41.9,12.69 C642.2 ; v1(84.03,113.19) 83.93,113.19 83.65,112.91 C403.2 ; C411.2 v1(72.71,106.14) ; C416.1 117.27,100.83 v1(117.56,100.83) ; v1(112.16,38.21) 112.43,38.47 R624.1 ; C464.2 C463.2 v1(88.85,81.84) ; v1(17.47,24.46) 17.47,24.14 U128.A1 ; v1(69.71,59.23) 69.66,59.28 C568.2 ; C405.2 70.11,112.31 C404.2 70.11,112.54 70.25,112.68 v1(70.25,113.06) 70.26,113.06 R462.1 ; R438.1 v1(92.88,139.52) ; R622.1 122.51,39.15 122.24,39.15 v1(121.83,38.74) ; C529.1 126.24,71.17 v1(125.71,70.64) ; U118.7 58.19,52.19 57.93,52.44 C598.2 57.93,53.98 v1(57.95,53.99) ; C626.2 v1(17.05,25.34) ; v1(113.82,79.74) 114.14,79.74 114.44,80.04 115.33,80.04 115.83,79.54 R556.2 ; C388.2 76.25,122.45 v1(76.22,122.41) ; v1(76.21,64.83) 76.4,64.64 C548.2 ; C574.1 34,58.65 34.63,59.27 v1(34.83,59.27) ; C607.1 25.35,41.77 v1(25.41,41.83) ; 74.38,82.01 v1(74.76,82.39) ; R666.2 49.15,22.77 v1(49.09,22.82) ; R564.2 v1(124.44,76.58) 124.44,76.84 C500.1 ; v1(72.36,79.19) C482.2 ; v1(52.39,8.7) 52.31,8.61 C650.2 ; v1(79.56,83.19) C658.2 v1(78.76,83.99) ; U132.3 v1(53.36,9.13) ; v1(20.68,21.95) 20.93,22.2 U128.9 ; C643.2 36.85,13.13 v1(36.87,13.15) 37.22,13.15 37.48,13.41 C641.2 ; R562.2 100.23,76.36 v1(99.85,75.97) ; v1(96.49,38.49) 96.49,39.04 R623.1 ; C376.2 v1(50.29,160.06) ; C617.1 27.22,31.66 27.15,31.59 v1(27.15,31.18) ; C420.1 115.15,94.46 v1(115.41,94.2) ; v1(104.44,76.57) 104.41,76.53 R561.2 ; Q10.7 Q10.4 ; v1(20.9,25.28) 20.91,25.26 U128.6 ; v1(55.95,159.43) 55.81,159.57 C375.2 ; C330.2 v1(70.65,178.8) ; v1(41.13,64.47) 41.13,64.52 41.58,64.96 C546.2 ; v1(116.93,85.75) R531.1 116.4,85.21 116.22,85.4 U93.3 ; R648.2 20.49,26.51 v1(20.72,26.74) ; C510.2 63.76,76.38 v1(64.15,76) 63.84,75.69 C512.2 ; C368.2 72.07,163.47 v1(72.26,163.27) ; C635.2 v1(13.77,19.15) C632.2 ; U122.7 52.72,47.27 52.46,47.53 C601.2 52.46,48.71 v1(52.25,48.92) ; U132.2 53.74,10.33 54,10.08 v1(54,9.87) ; v1(84.36,71.19) U47.AB1 v1(83.56,71.99) ; R430.2 122.87,161.09 v1(122.54,161.42) ; R632.2 91.36,34.63 C614.2 ; C523.1 122.58,71.85 v1(122.58,71.45) ; v1(60.52,113.13) 60.69,112.96 C402.2 ; C429.2 75.88,84.14 C437.2 ; C419.1 113.92,99.32 v1(113.9,99.33) ; v1(73.96,79.19) C657.2 73.96,79.89 ; C377.2 95.32,158.12 v1(95.04,158.4) ; C656.2 55.98,4.56 v1(55.84,4.71) ; R683.2 56.13,5.32 v1(55.84,5.62) ; v1(42.4,57.95) 42.54,58.09 42.82,58.09 C572.2 43.12,59.44 v1(42.63,59.44) ; v1(46.39,8.7) 46.41,8.72 C649.2 ; D11.1 v1(27.3,76.11) ; C379.2 84.73,157.12 v1(84.16,157.69) ; v1(56.97,56.42) 57.06,56.34 U116.1 ; U128.A3 v1(21.91,19.7) ; R451.2 82.45,120.67 82.06,120.29 82.06,120.13 v1(82,120.07) 81.76,120.31 C389.2 ; v1(96.51,43.3) C610.2 v1(95.24,44.38) ; U91.2 49.61,92.32 49.43,92.5 v1(49.41,92.5) ; v1(115.38,81.53) 115.36,81.51 C455.1 ; v1(83.24,111.27) 83.09,111.12 C406.2 ; v1(56.63,162.04) 56.43,161.84 R428.2 ; U133.2 v1(34.52,9.36) ; R504.2 75.41,93.51 76.42,93.51 v1(76.81,93.9) ; C417.2 116.08,99.36 v1(116.13,99.32) ; v1(12.85,151.71) 12.62,151.48 J26.SH2 ; R681.2 40.68,12.24 v1(40.65,12.21) ; 80.12,77.33 80.12,77.35 v1(80.36,77.59) ; 67.13,71.57 C669.2 ; C538.2 v1(26.38,66.7) ; C666.2 74.21,75.75 v1(73.96,75.99) U47.K7 v1(74.76,76.79) 75.46,76.79 C665.2 76.25,75.99 v1(76.36,75.99) ; v1(46.39,7.18) 46.77,7.56 C652.2 ; C579.2 68.45,57.38 68.41,57.43 v1(68.41,57.63) ; C436.2 53.99,83.76 54.09,83.66 54.18,83.66 54.2,83.64 v1(54.25,83.64) ; C449.1 61.24,82.06 60.91,81.73 R545.2 59.79,81.73 v1(59.55,81.97) ; Q6.3 34.01,84.23 v1(34.32,84.54) ; C599.1 27.97,49.26 v1(27.86,49.38) ; v1(50.86,57.05) 50.37,57.54 C576.2 ; C410.2 70.29,106.62 v1(70.7,106.62) ; v1(119.95,79.49) 119.99,79.52 119.99,79.68 120.33,80.03 C470.1 ; C431.2 90.46,84.19 v1(90.64,84.01) 90.66,83.99 C442.2 ; v1(58.62,57.43) 58.31,57.75 U115.C3 ; D14.1 61.19,28.91 61.31,28.79 C622.1 v1(60.69,28.5) ; C501.2 77.04,76.91 v1(77.16,76.79) 77.38,76.57 U47.P7 v1(77.96,75.99) ; R426.2 v1(43.97,163.92) ; v1(29.48,44.55) 29.2,44.27 R613.1 ; J26.SH1 v1(11.62,165.22) ; v1(122.04,70.66) 121.91,70.79 C528.1 ; C469.1 122.47,79.84 v1(122.91,79.84) ; v1(32.77,78.44) 32.85,78.35 Q7.3 ; v1(123.84,86) C430.1 ; U132.1 v1(52.31,10.98) ; C609.1 63.84,40.66 D12.1 v1(63.83,39.83) ; v1(39.38,12.2) 39.41,12.22 R682.2 ; C329.2 v1(87.8,178.8) ; R488.2 69.93,100.46 v1(69.95,100.44) ; C628.2 13.65,22.64 v1(13.32,22.31) ; U128.16 v1(19.41,19.22) 18.99,18.81 C636.2 ; v1(66.29,114.58) C397.2 65.7,114.05 v1(65.49,113.84) 65.28,113.62 C401.2 ; C602.2 v1(111.96,46.28) ; 24.61,25.44 24.43,25.44 24.18,25.18 C627.2 ; J26.6 v1(13.42,153.4) ; v1(27.79,39.8) 27.79,39.9 28.04,40.16 C612.1 ; C413.2 68.35,103.26 v1(68.68,102.93) ; D13.1 53.03,36.85 52.91,36.97 C613.1 v1(52.91,37.89) ; R662.2 44.5,24.58 v1(44.82,24.91) ; U133.3 v1(35.17,9.36) ; R422.1 v1(132.92,162.4) ; C476.2 51.69,79.15 v1(51.48,79.36) ; v1(116.13,99.32) R489.1 ; v1(116.13,99.32) R490.1 ; v1(119.73,145.11) 119.17,145.66 C385.2 ; v1(66.83,165.59) 67.27,165.16 C363.2 ; C505.2 54.59,76.95 v1(54.2,77.35) ; C527.2 97.58,71.93 v1(97.35,72.16) 97.37,72.18 C521.2 ; v1(120.46,78.65) 120.37,78.74 C488.2 ; v1(77.16,78.39) 77.38,78.62 C660.2 77.74,78.97 v1(77.96,79.19) ; v1(74.06,65.85) 74.19,65.99 C540.2 ; v1(50.69,126.18) Q5.4 Q5.7 ; C625.1 v1(17.87,26.51) ; C489.1 27.62,78.32 27.51,78.43 v1(27.51,78.93) ; R610.1 v1(129.99,44.32) ; U128.A4 v1(17.35,19.65) ; C359.2 v1(122.55,166.46) ; C390.2 76.24,118.66 76.22,118.64 v1(76.22,118.45) ; C422.2 v1(56.51,84.28) ; v1(29.51,32.39) 29.51,32.05 C618.1 ; C516.1 118.91,75.04 v1(119.08,75.21) ; v1(82.77,105.96) 82.77,105.42 82.6,105.25 C412.2 ; v1(100.6,74.22) 100.57,74.19 C520.2 ; v1(61.99,74.82) 61.99,74.82 61.99,74.19 C517.2 ; C514.2 98.71,74.59 v1(98.82,74.71) ; v1(77.96,81.59) 77.74,81.81 77.74,81.82 C659.2 v1(77.16,82.39) ; J26.SH3 v1(26.93,157.71) ; v1(52.39,7.18) 52.34,7.12 C653.2 ; v1(76.03,58.79) 75.94,58.7 C573.2 75.18,58.7 v1(75.09,58.79) ; C472.2 78.89,80.29 C466.2 ; R609.1 25.7,44.48 25.45,44.73 v1(25.45,44.75) ; R618.1 v1(128.33,40.43) ; D10.1 v1(27.37,82.97) ; U128.3 v1(19.41,24.51) ; C555.2 v1(44.94,62.33) ; C478.1 v1(34.53,77.71) ; v1(44.85,154.48) 44.6,154.73 C380.2 ; v1(43.15,10.9) 42.83,10.58 C651.2 ; v1(63.92,79.61) C481.2 ; v1(59.11,108.56) 59.36,108.3 R467.2 ; v1(28,42.81) 28,42.49 28.25,42.24 C608.1 ; C605.1 v1(129.99,46.56) ; v1(80.36,80.79) 80.24,80.67 C467.2 ; U79.2 v1(42.91,151.53) 42.36,152.08 C381.2 ; R418.1 v1(133.23,167.33) ; v1(72.3,109.51) 72.34,109.54 C407.2 ; R458.2 78.5,116.09 v1(78.8,115.8) ; C532.2 41.16,68.66 ; v1(54.05,162.99) R427.1 53.35,162.91 U78.6 ; C631.2 v1(46.17,20.56) ; R417.1 v1(46.36,168.06) ; R442.1 v1(50.94,125.16) ; U128.A2 v1(21.86,24.15) ; v1(113.56,44.24) C611.2 113.17,43.28 v1(112.28,44.16) ; C519.1 v1(122.82,74.6) ; C425.1 v1(27.66,85.18) ; J26.SH4 v1(25.77,150.66) ; U133.1 v1(33.87,9.36)
  BOTTOM w0.305: C493.2 78.49,78.13 v1(78.76,78.39) ; C459.2 v1(77.16,80.79) 77.16,80.77 C468.2 ; C440.2 77.28,83.87 v1(77.16,83.99) ; v1(78.76,78.39) 78.98,78.61 C486.2 ; v1(78.76,78.39) C494.2 ; C446.2 79.73,83.02 v1(79.56,83.19) ; v1(81.16,77.59) 80.97,77.78 80.97,77.81 ; R557.2 85.05,80.68 v1(84.88,80.84) ; v1(71.21,61.48) 71.21,61.79 C557.2 ; R555.1 119.9,79.54 v1(119.95,79.49) ; v1(72.96,64.03) 72.84,63.91 C551.2 ; v1(82.76,83.19) 82.44,82.88 C448.2 ; v1(76.53,66.46) 76.66,66.34 C541.1 ; v1(73.16,84.79) 73.4,84.55 C434.2 ; v1(73.16,84.79) 72.94,85.01 C426.2 ; v1(73.16,84.79) 72.91,84.54 C435.2 ; v1(74.76,82.39) 74.96,82.59 C444.2 C450.2 ; C477.2 76.33,79.54 76.33,79.38 76.36,79.35 v1(76.36,79.19) 75.66,79.19 C483.2 75.7,78.87 C491.2 ; v1(71.2,55.67) 71.12,55.75 C585.2 ; C595.2 v1(81.34,53.3) ; v1(29.06,81.31) 29.3,81.55 U98.4 ; R553.2 82.7,80.73 v1(82.76,80.79) ; C506.2 v1(81.16,75.99) ; C567.2 68.1,60.12 68.27,60.12 v1(68.41,60.25) ; C566.2 72.77,59.93 v1(72.77,60.23) ; C458.2 v1(80.36,80.79) ; v1(72.96,64.83) 72.91,64.83 C545.1 ; v1(72.36,79.19) 72.6,79.44 C471.2 ; C539.2 71.53,66.44 v1(71.36,66.44) ; C438.2 70.88,83.87 v1(70.76,83.99) ; C530.2 84.24,71.07 v1(84.36,71.19) ; C461.2 v1(71.56,80.79) ; v1(70.36,62.43) 70.32,62.39 C556.2 ; v1(80.11,64.03) 79.73,64.03 C550.2 ; C553.2 68.57,63.87 v1(68.41,64.03) ; C522.2 84.48,72.67 v1(84.36,72.79) ; v1(72.96,57.63) 72.78,57.45 C578.2 ; C507.2 v1(79.56,75.99) ; C503.2 96.99,77.54 v1(96.67,77.86) ; U124.7 47.36,46.3 47.11,46.55 C604.2 v1(47.11,47.77) ; C583.2 78.36,55.93 v1(78.48,55.81) ; C582.2 72.5,56.22 v1(72.31,56.03) ; C596.2 v1(78.42,53.3) ; C460.2 73.02,80.79 v1(73.16,80.79) C456.2 73.41,81.05 ; C496.2 v1(71.56,77.59) C499.2 ; v1(77.16,82.39) 77.04,82.51 C447.2 ; C513.2 69.96,74.85 v1(69.96,74.39) ; v1(77.96,83.19) 78.08,83.31 C439.2 ; v1(70.74,54.8) 70.89,54.8 70.96,54.88 C591.2 C594.1 ; v1(71.01,59.23) 70.95,59.29 C570.2 ; C571.2 80.72,59.27 v1(80.76,59.23) ; C508.2 v1(72.36,75.99) ; C542.2 78.14,65.51 v1(78.48,65.85) 78.63,65.71 C543.1 ; v1(76.92,55.81) 76.81,55.7 C587.1 ; v1(77.16,78.39) 77.16,78.26 C490.2 ; v1(80.36,82.39) 80.48,82.27 C451.2 ; C457.2 70.67,81.5 v1(70.76,81.59) C453.2 ; C462.2 75.03,81.07 v1(74.76,80.79) C465.2 ; v1(79.95,61.41) 79.94,61.4 C564.2 79.94,60.41 v1(79.78,60.25) ; 81.84,76.91 R560.2 ; v1(66.76,71.19) C669.2 ; v1(66.76,71.19) 66.13,71.19 C526.2 ; v1(66.76,71.19) 66.76,70.51 C531.2 ; v1(82.38,61.41) 82.39,61.4 C563.2 82.39,60.26 v1(82.38,60.25) ; v1(75.56,100.51) 75.42,100.65 C418.2 ; C558.2 72.66,61.71 v1(72.66,61.48) ; v1(70.76,79.19) 70.94,79.01 C484.2 ; C433.2 v1(71.56,84.79) 71.44,84.91 C424.2 ; v1(78.76,82.39) 78.88,82.27 C452.2 ; v1(74.91,64.83) 74.71,64.83 C549.2 ; v1(77.51,62.43) 77.51,62.5 C554.2 ; C588.2 79.74,55.76 v1(79.79,55.81) 79.74,55.85 C581.2 ; C432.2 76.48,84.67 v1(76.36,84.79) 76.21,84.65 C429.2 ; v1(100.62,77.72) 100.62,77.97 100.93,78.27 C498.2 ; C562.2 78.5,61.18 v1(78.48,61.19) ; v1(80.76,56.83) 80.98,56.61 C586.2 ; v1(81.05,158.98) 81.21,158.83 C378.2 ; C485.2 v1(73.96,79.19) ; C655.2 31.86,4.59 v1(31.65,4.79) ; C443.2 v1(72.36,82.39) ; v1(72.36,82.39) 72.54,82.57 C445.2 ; v1(72.36,82.39) C454.2 ; v1(126.84,79.32) 127.16,79.63 C473.1 ; v1(81.96,75.19) 81.84,75.31 R567.2 ; C351.2 v1(129.72,167.89) ; C544.2 69.66,65.72 v1(69.66,65.76) ; C584.1 68.77,55.88 v1(68.56,55.67) C590.2 ; v1(83.09,63.81) 83.06,63.78 C552.2 ; C654.2 36.93,4.59 v1(37.14,4.79) ; C479.2 80.24,79.31 v1(80.36,79.19) ; C466.2 78.64,80.67 v1(78.76,80.79) ; v1(50.88,84.34) 50.87,84.35 C427.2 50.87,85.49 50.61,85.75 U91.7 ; v1(82.06,57.63) 82.15,57.72 C577.2 ; C441.2 80.57,83.78 v1(80.36,83.99) ; C480.2 78.08,79.31 v1(77.96,79.19) ; C589.2 74.18,55.56 v1(73.93,55.81) ; v1(80.36,77.59) 80.14,77.81 C495.2 ; v1(78.16,59.23) 78.13,59.21 C569.2 ; C349.2 v1(130.21,168.92)
  BOTTOM w0.381: v1(87.26,63.54) 87.05,63.33 R588.1 ; v1(131.07,79.19) 131.25,79.01 U107.4 ; C561.2 49.45,61.69 v1(48.8,62.33)
  BOTTOM w0.508: C339.2 v1(18.29,174.54)
  vias: v1(11.29,23.92) v1(11.29,23) v1(11.29,22.09) v1(11.68,15.56) v1(11.68,14.85) v1(12.39,15.56) v1(12.39,14.85) v1(13.1,15.56) v1(13.1,14.85) v1(13.34,157.17) v1(13.43,155.42) v1(13.77,143.76) v1(13.81,15.56) v1(13.81,14.85) v1(13.9,103.52) v1(13.89,99.96) v1(14.23,142.02) v1(14.29,144.1) v1(14.53,15.56) v1(14.53,14.85) v1(14.66,103.52) v1(14.65,99.96) v1(15.42,103.52) v1(15.42,99.96) v1(16.2,147.98) v1(18.55,153.44) v1(18.55,152.96) v1(18.64,22.97) v1(18.64,21.95) v1(18.64,20.94) v1(19.52,5.52) v1(19.52,4.81) v1(19.52,4.1) v1(19.52,3.39) v1(19.71,38.91) v1(19.69,37.66) v1(19.66,22.97) v1(19.66,21.95) v1(19.66,20.94) v1(19.81,36.14) v1(19.78,34.75) v1(19.8,33.51) v1(20.03,50.45) v1(20.23,5.52) v1(20.23,4.81) v1(20.23,4.1) v1(20.23,3.39) v1(20.49,61.22) v1(20.49,60.5) v1(20.68,22.97) v1(21.76,35.94) v1(22.4,35.94) v1(23.54,6.04) v1(23.54,5.33) v1(23.54,4.62) v1(23.54,3.9) v1(23.54,3.19) v1(23.96,38.61) v1(24.05,6.04) v1(24.05,5.33) v1(24.05,4.62) v1(24.05,3.9) v1(24.05,3.19) v1(24.39,28.64) v1(24.39,27.63) v1(24.39,26.61) v1(24.8,26.01) v1(25.23,28.63) v1(25.23,27.61) v1(25.23,26.6) v1(25.63,26.05) v1(25.8,30.57) v1(25.8,29.55) v1(26.05,26.64) v1(26.81,30.57) v1(26.81,29.55) v1(27.02,26.64) v1(27.25,22.31) v1(27.24,21.85) v1(27.24,21.39) v1(28.84,21.53) v1(29.24,11.96) v1(29.24,11.25) v1(29.68,21.48) v1(29.95,11.96) v1(29.95,11.25) v1(30.57,21.48) v1(30.66,11.96) v1(30.66,11.25) v1(30.66,10.54) v1(30.8,105.24) v1(30.87,24.57) v1(30.88,24.11) v1(30.87,23.64) v1(31.33,24.55) v1(31.33,24.09) v1(31.33,23.63) v1(31.37,11.96) v1(31.37,11.25) v1(31.37,10.54) v1(32.14,93.68) v1(34.13,59.6) v1(34.43,15.22) v1(34.4,12.08) v1(34.4,11.16) v1(35.67,12.08) v1(36.94,12.08) v1(36.94,11.16) v1(37.24,10.38) v1(37.56,21.91) v1(38.45,11.28) v1(38.45,10.37) v1(38.81,22.88) v1(38.81,21.91) v1(38.81,20.95) v1(38.81,19.98) v1(40.11,57.35) v1(40.05,21.91) v1(40.05,20.95) v1(40.05,19.98) v1(40.26,67.51) v1(40.25,66.87) v1(40.41,10.9) v1(40.41,9.98) v1(40.41,9.12) v1(41.08,57.35) v1(41.08,56.44) v1(41.15,67.51) v1(41.15,66.62) v1(41.3,22.88) v1(41.3,21.91) v1(41.3,20.95) v1(41.3,19.98) v1(41.32,10.9) v1(41.32,9.98) v1(41.32,9.12) v1(42.04,67.51) v1(42.04,66.62) v1(42.04,57.35) v1(42.54,21.91) v1(42.54,20.95) v1(42.93,67.51) v1(42.93,66.62) v1(43.01,57.35) v1(45.08,86.05) v1(45.18,27.24) v1(45.21,17.67) v1(45.2,15.84) v1(45.29,16.82) v1(45.72,86.05) v1(45.94,16.35) v1(45.94,15.54) v1(45.98,17.22) v1(46.07,28) v1(46.07,27.24) v1(46.35,86.05) v1(46.44,62.76) v1(46.44,61.9) v1(47.3,62.76) v1(47.3,61.9) v1(47.63,19.05) v1(47.63,17.55) v1(48.35,14.43) v1(48.35,4.64) v1(48.49,19.05) v1(48.49,18.18) v1(48.49,17.55) v1(50.33,4.64) v1(50.46,14.43) v1(50.68,67.51) v1(50.68,66.94) v1(51.57,67.51) v1(51.57,66.94) v1(51.58,57.3) v1(52.31,10.33) v1(52.31,9.68) v1(52.46,67.51) v1(52.46,66.94) v1(52.54,57.3) v1(52.54,56.44) v1(53.35,67.51) v1(53.35,66.94) v1(53.51,57.3) v1(54.77,29.83) v1(54.77,27.9) v1(54.86,21.49) v1(55.17,9.13) v1(55.5,20.56) v1(55.51,19.63) v1(55.51,18.78) v1(55.73,29.83) v1(55.73,28.87) v1(55.73,27.9) v1(55.73,26.94) v1(55.68,1.97) v1(55.82,21.49) v1(55.81,9.76) v1(55.81,9.13) v1(56.44,9.76) v1(56.44,9.13) v1(56.46,20.56) v1(56.47,19.63) v1(56.47,18.78) v1(56.61,163.35) v1(56.6,1.97) v1(60.27,59.64) v1(60.27,58.37) v1(61.54,59.64) v1(61.54,58.37) v1(63.2,108.81) v1(63.2,107.54) v1(63.55,24.8) v1(63.65,26.6) v1(64.09,23.3) v1(64.47,110.08) v1(64.47,108.81) v1(64.47,107.54) v1(65.74,110.08) v1(65.74,108.81) v1(65.74,107.54) v1(65.74,106.27) v1(65.81,118.93) v1(66.06,23.3) v1(66.06,16.5) v1(67.01,110.08) v1(67.01,108.81) v1(67.86,159.74) v1(67.86,158.72) v1(67.86,157.71) v1(68.13,15.78) v1(68.64,114.44) v1(68.88,160.76) v1(68.88,159.74) v1(68.88,158.72) v1(68.88,157.71) v1(68.98,15.78) v1(69.9,160.76) v1(69.9,159.74) v1(69.9,158.72) v1(69.9,157.71) v1(70.91,160.76) v1(70.91,159.74) v1(70.91,158.72) v1(70.91,157.71) v1(71.56,73.59) v1(72.92,144.7) v1(72.92,143.93) v1(72.92,143.17) v1(72.86,33.01) v1(73.16,73.59) v1(73.61,62.43) v1(73.68,144.7) v1(73.68,143.93) v1(73.68,143.17) v1(74.44,144.7) v1(74.44,143.93) v1(74.79,54.73) v1(75.56,62.15) v1(76.19,54.7) v1(76.4,12.53) v1(76.4,7.45) v1(76.4,2.37) v1(76.55,111.74) v1(76.55,109.2) v1(77.82,111.74) v1(77.82,109.2) v1(77.82,107.93) v1(78.23,139.49) v1(78.94,9.99) v1(78.94,4.91) v1(78.99,139.49) v1(79.09,109.2) v1(79.09,107.93) v1(79.67,141.36) v1(80.03,162.03) v1(80.03,161.02) v1(80.03,160) v1(80.03,158.98) v1(80.36,110.47) v1(80.36,109.2) v1(80.36,107.93) v1(81.05,162.03) v1(81.05,161.02) v1(81.05,160) v1(81.48,12.53) v1(81.48,7.45) v1(81.48,2.37) v1(82.07,162.03) v1(82.07,161.02) v1(82.07,160) v1(82.07,158.98) v1(82.77,55.61) v1(82.98,146.53) v1(82.98,145.77) v1(82.98,145.01) v1(83.08,162.03) v1(83.08,161.02) v1(83.08,160) v1(83.74,146.53) v1(83.74,145.77) v1(83.74,145.01) v1(83.9,167.03) v1(84.04,114.56) v1(84.02,4.91) v1(84.5,146.53) v1(84.5,145.77) v1(84.5,145.01) v1(84.62,56.76) v1(84.92,44.78) v1(84.9,43.86) v1(85.51,38.75) v1(85.68,58.11) v1(86.56,12.53) v1(86.56,7.45) v1(86.56,2.37) v1(87,165.5) v1(87.29,170.75) v1(88.43,169.16) v1(89.1,9.99) v1(89.1,4.91) v1(91.55,33.75) v1(91.64,12.53) v1(91.64,7.45) v1(91.64,2.37) v1(91.88,33.17) v1(92.19,33.74) v1(92.36,32.79) v1(92.92,45.03) v1(92.89,44.43) v1(92.9,43.82) v1(93.68,28.55) v1(93.71,27.88) v1(94.18,9.99) v1(94.18,4.91) v1(94.45,28.53) v1(94.47,27.87) v1(96.72,12.53) v1(96.72,7.45) v1(96.72,2.37) v1(97.41,113.48) v1(97.41,112.31) v1(98.15,111.87) v1(98.17,112.9) v1(98.17,110.56) v1(98.93,113.48) v1(98.93,112.31) v1(98.93,111.14) v1(99.26,9.99) v1(99.99,164.8) v1(99.99,164.04) v1(99.99,163.28) v1(100.75,164.8) v1(100.75,164.04) v1(100.75,163.28) v1(101.51,164.8) v1(101.51,164.04) v1(101.51,163.28) v1(101.8,12.53) v1(104.34,9.99) v1(104.34,4.91) v1(104.43,143.91) v1(104.43,142.94) v1(104.43,141.97) v1(104.43,141.01) v1(105.39,143.91) v1(105.39,142.94) v1(105.39,141.97) v1(105.39,141.01) v1(105.82,112.87) v1(105.82,111.91) v1(105.82,110.94) v1(106.36,143.91) v1(106.36,142.94) v1(106.36,141.97) v1(106.36,141.01) v1(106.61,136.5) v1(106.78,113.71) v1(106.78,112.87) v1(106.78,111.91) v1(106.78,110.94) v1(106.88,12.53) v1(106.88,7.45) v1(106.88,2.37) v1(107.33,143.91) v1(107.33,142.94) v1(107.33,141.97) v1(107.33,141.01) v1(107.75,113.71) v1(107.75,112.87) v1(107.75,111.91) v1(107.75,110.94) v1(108.01,164.8) v1(108.01,164.04) v1(108.01,163.28) v1(108.71,113.71) v1(108.71,112.87) v1(108.71,111.91) v1(108.71,110.94) v1(108.77,164.8) v1(108.77,164.04) v1(108.77,163.28) v1(109.42,9.99) v1(109.42,4.91) v1(109.53,164.8) v1(109.53,164.04) v1(109.53,163.28) v1(111.96,12.53) v1(111.96,7.45) v1(111.96,2.37) v1(114.02,112.97) v1(114.02,111.8) v1(114.02,110.64) v1(114.5,4.91) v1(114.78,113.56) v1(114.78,112.39) v1(114.78,111.22) v1(115.54,112.97) v1(115.54,111.8) v1(115.54,110.64) v1(116.76,146.32) v1(117.01,66.47) v1(117,65.88) v1(117.04,12.53) v1(117.04,7.45) v1(117.04,2.37) v1(117.34,45.07) v1(117.33,43.86) v1(117.39,164.8) v1(117.39,164.04) v1(117.39,163.28) v1(118.03,146.32) v1(118.15,164.8) v1(118.15,164.04) v1(118.15,163.28) v1(118.42,63.95) v1(118.42,62.93) v1(118.91,164.8) v1(118.91,164.04) v1(118.91,163.28) v1(119.23,72.96) v1(119.58,9.99) v1(119.58,4.91) v1(119.78,70.88) v1(120.45,63.95) v1(121.72,60.86) v1(122.12,12.53) v1(122.12,7.45) v1(122.12,2.37) v1(123.12,63.04) v1(124.66,9.99) v1(124.66,4.91) v1(125.34,45.03) v1(125.34,43.99) v1(125.41,164.8) v1(125.41,164.04) v1(125.41,163.28) v1(125.95,44.72) v1(126.17,164.8) v1(126.17,164.04) v1(126.17,163.28) v1(126.93,164.8) v1(126.93,164.04) v1(126.93,163.28) v1(127.2,12.53) v1(127.2,7.45) v1(127.2,2.37) v1(128.83,48.16) v1(129.47,53) v1(129.47,50.93) v1(129.46,48.16) v1(129.74,9.99) v1(129.74,4.91) v1(131.58,137.55) v1(131.58,133.99) v1(132.35,137.55) v1(132.34,133.99) v1(132.28,12.53) v1(132.28,7.45) v1(133.11,137.55) v1(133.1,133.99) v1(133.24,69.2) v1(134,69.2) v1(134.82,9.99)
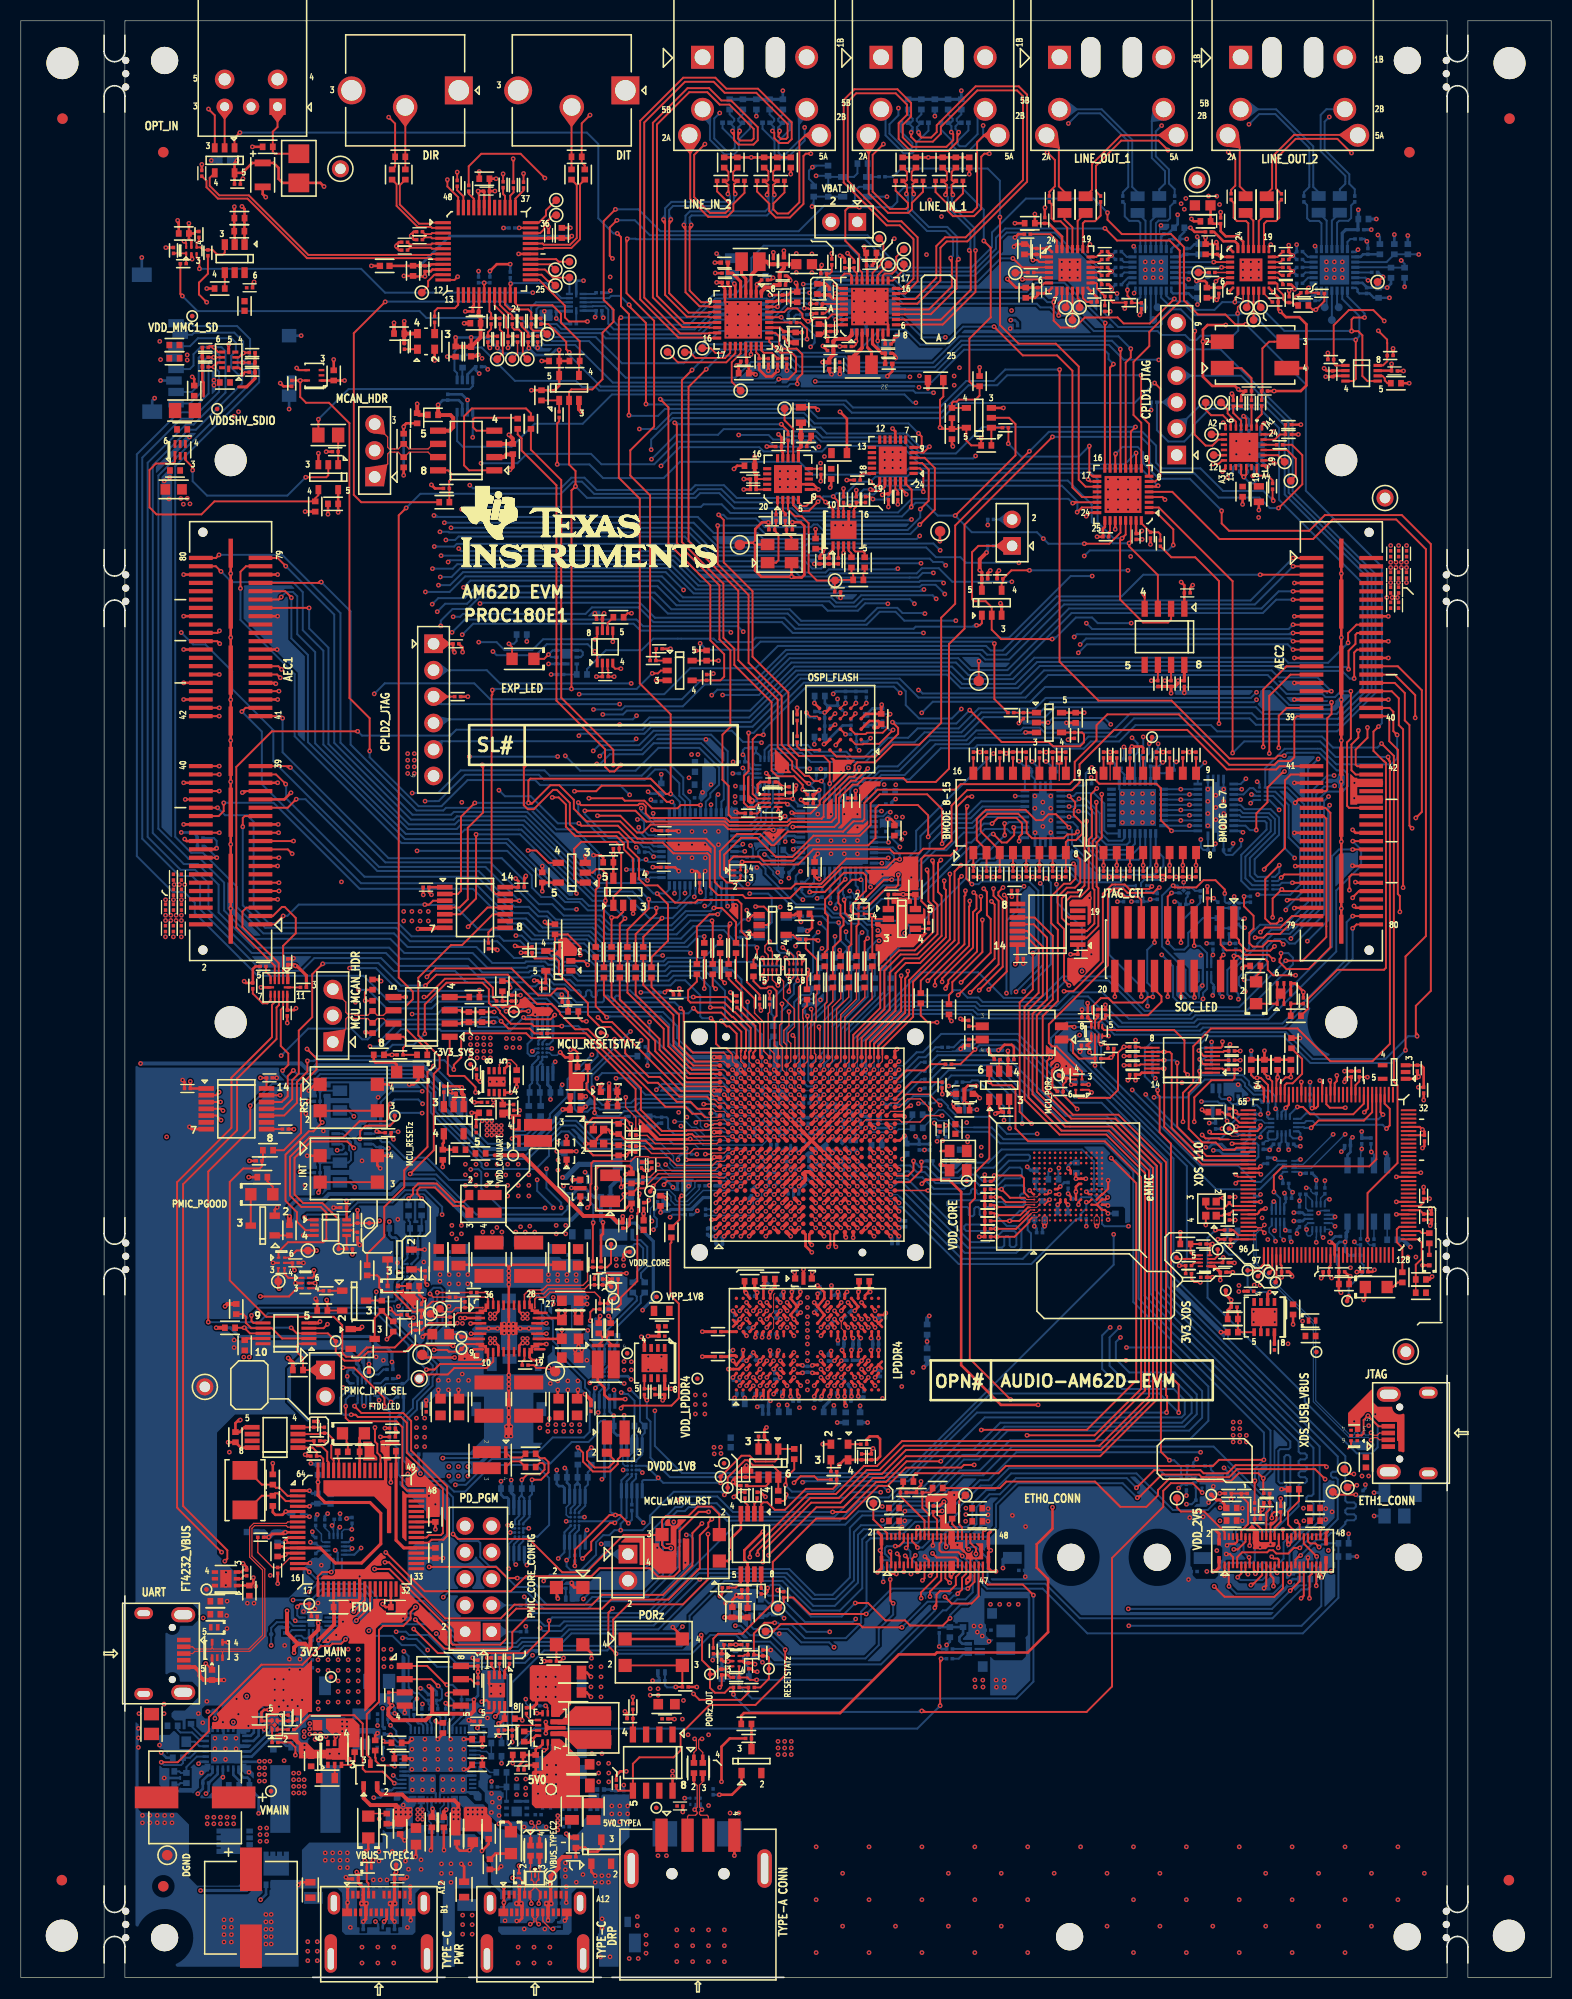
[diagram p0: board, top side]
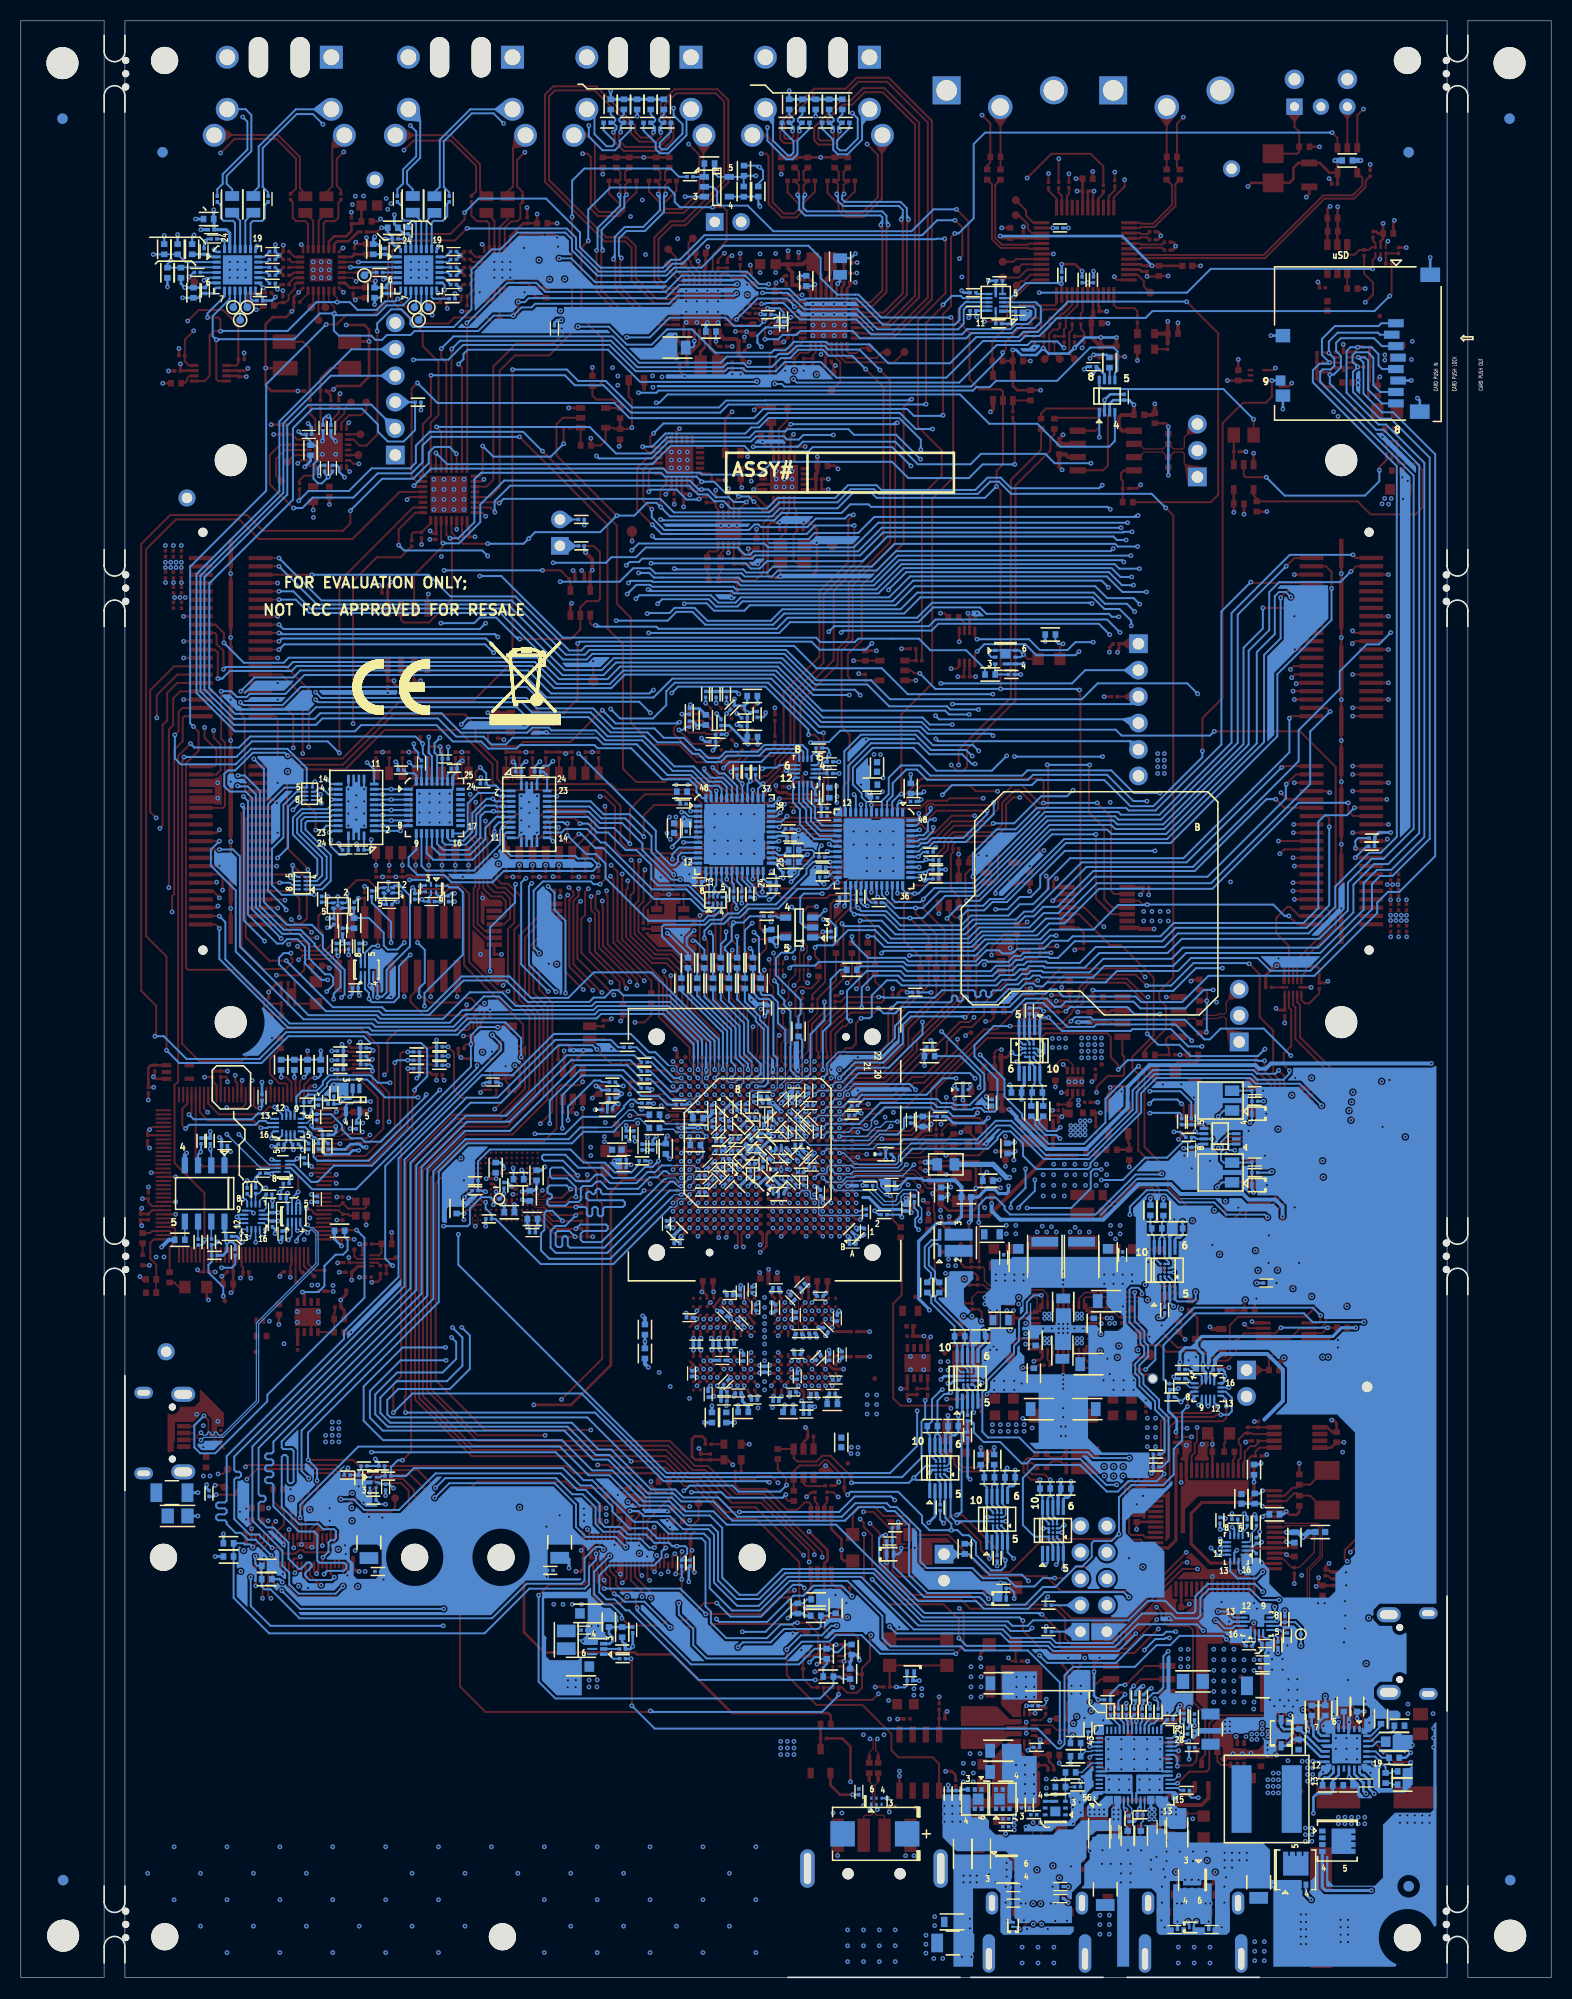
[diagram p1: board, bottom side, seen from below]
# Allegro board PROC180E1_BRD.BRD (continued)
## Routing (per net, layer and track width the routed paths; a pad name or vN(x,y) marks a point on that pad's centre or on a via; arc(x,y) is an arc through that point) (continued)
DVDD1V8_ALERT: length 43
  TOP w0.191: R305.1 36.06,63.64 v1(35.48,64.22)
  L03_SIG01 w0.076: v1(35.48,64.22) 35.48,62.27 36.87,60.89 36.87,56.94 37.17,56.64 v1(37.17,48.37)
  BOTTOM w0.191: v1(37.17,48.37) 37.87,47.66 40.62,47.66 41.62,46.66 42.68,46.66 45.24,49.22 49.5,49.22 50.75,47.97 50.75,43.45 49.63,42.33 U123.A3 48.26,41.91 47.86,41.51 U124.3
DVDD3V3: length 44.9
  TOP w0.14: C252.1 v1(51.97,62.21) ; R244.1 v1(47.91,83.29)
  TOP w0.254: U56.21 51.96,61.33 C252.1
  L03_SIG01 w0.076: v1(51.97,62.21) 51.12,61.35 49.88,61.35 48.89,60.36 44.86,60.36 44.68,60.54 42.25,60.54 41.79,60.09 41.29,60.09 40.95,60.42 40.95,63.16 43.68,65.89 43.68,73.35 42.13,74.9 42.13,80.75 44.67,83.29 v1(47.91,83.29)
DVDD3V3_ALERT: length 3.1
  BOTTOM w0.191: U92.A3 49.71,89.97 50.11,90.37 U91.3 R505.1
V3V3_OPTICAL: length 7.1
  TOP w0.191: L1.2 24.4,175.19 24.2,175.38 C1.1 24.2,177.31 24.66,177.76 MOD1.1
VBAT_IN: length 37.5
  TOP w0.254: v1(81.02,166.26) 81.02,165.86 C49.1 81.21,164.92 81.23,164.9 C55.1 81.23,164.14 81.31,164.06 U7.21 ; v1(70.58,153.98) 70.45,154.12 C100.1 69.93,154.63 69.72,154.84 C95.1 69.72,155.6 69.64,155.68 U8.21
  L04_PWR1 w0.381: v1(81.02,166.26) 81.9,166.26 84.99,163.17 84.99,154.53 83.66,153.21 80.68,153.21 79.2,151.73 76.23,151.73 75.6,152.37 71.61,152.37 70.62,153.36 70.62,153.94 v1(70.58,153.98)
VBUS_5V0_TYPEA: length 7.4
  TOP w0.254: v1(67.3,18.78) 67.3,22.16 68.09,22.95 R389.2 ; U74.8 v1(62.6,19.35)
  vias: v1(61.21,11.68) v1(62.01,11.68) v1(62.6,19.81)
VBUS_TYPEC1: length 19
  TOP w0.305: TP107.1 v1(36.05,10.12) 35.89,9.96 C326.1 J24.A9 35.89,7.13 35.64,6.88 J24.B4 35.64,5.6 v1(35.89,5.35) ; v1(32.89,5.35) 33.14,5.6 J24.B9 33.14,6.88 32.89,7.13 J24.A4 32.89,8.59 32.42,9.06 C327.1 32.42,9.95 v1(32.26,10.11)
  TOP w0.381: R397.1 C321.1 ; v1(36.5,16.1) 36.06,16.55 33.59,16.55 32.93,17.21 D5.1
  BOTTOM w0.305: C654.1 v1(35.89,5.35) ; C655.1 v1(32.89,5.35)
  vias: v1(32.73,7.09) v1(33.19,7.09) v1(35.48,7.09) v1(35.94,7.09) v1(36.04,16.1) v1(36.04,15.65) v1(36.5,15.65) v1(36.74,16.55) v1(36.95,16.1) v1(36.95,15.65) v1(37.41,16.1) v1(37.41,15.65)
VBUS_TYPEC2: length 21.7
  TOP w0.254: v1(48.07,7.09) 48.14,7.01 J25.B9 48.14,5.68 47.88,5.41 v1(47.63,5.41) ; v1(46.14,10.65) 45.85,10.37 R402.1 ; 47.89,7.37 v1(47.61,7.09)
  TOP w0.305: v1(50.89,8.7) J25.A9 50.89,7.09 50.64,6.84 J25.B4 v1(50.64,5.48) ; 47.89,7.37 J25.A4 v1(47.89,8.7)
  TOP w0.381: v1(42.03,16.1) 42.03,16.62 41.64,17 37.19,17 36.63,17.56 34.58,17.56 34.23,17.92 D5.2 ; v1(50.89,8.7) TP108.1 51.66,10.49 51.66,11.19 52.04,11.57 R401.2
  vias: v1(41.57,16.1) v1(41.57,15.65) v1(41.57,15.19) v1(42.03,15.65) v1(42.03,15.19) v1(46.51,5.44) v1(50.48,7.09) v1(50.94,7.09) v1(56.77,16.47) v1(56.77,15.7) v1(56.77,14.94) v1(57.53,16.47) v1(57.53,15.7) v1(57.53,14.94) v1(58.29,16.47) v1(58.29,15.7) v1(58.29,14.94)
VCC1V1:
  vias: v1(49.86,52.79) v1(50.63,53.09) v1(50.63,52.45) v1(50.76,53.69) v1(51.39,53.09) v1(51.39,52.45) v1(52.15,53.09) v1(52.15,52.45) v1(52.91,53.09) v1(52.91,52.45) v1(53.68,53.09) v1(53.68,52.45)
VCC1V1_N: length 7.6
  TOP w0.191: R327.3 57.98,50.4 57.34,49.76 57.34,49.31 56.62,48.6 54.95,48.6 54.01,49.53 54.01,50.4 v1(53.5,50.91)
  BOTTOM w0.191: R599.2 v1(53.5,50.91)
VCC1V1_P: length 6.3
  TOP w0.191: R327.2 56.96,49.74 56.96,49.47 56.46,48.98 55.11,48.98 54.39,49.69 54.39,50.49 v1(54.8,50.89)
  BOTTOM w0.191: R600.2 v1(54.8,50.89)
VCC1V8_CLKBUF: length 29.8
  TOP w0.254: v1(71.29,42.82) 69.5,41.02 69.5,40.08 69.81,39.76 U65.6 C284.2 C286.2 FL10.1 ; v1(71.53,46.16) 71.51,46.16 71.06,46.61 R348.2 ; R329.2 81.25,51.68 81.54,51.97 82.28,51.97 82.54,51.71 82.54,50.05 82.21,49.72 C265.1 81.7,49.72 C266.2 80.76,49.71 U62.4 79.09,49.71 v1(78.61,49.23)
  L03_SIG01 w0.254: v1(71.29,42.82) 71.53,43.05 v1(71.53,46.16) 71.53,47.68 73.08,49.23 v1(78.61,49.23)
VCC1V8_SYS: length 169.5
  TOP w0.191: v1(98.85,75.47) 98.6,75.22 U49.C6 ; R35.2 124.09,160.21 v1(124.4,160.21) 125.21,161.02 R28.2 ; U5.6 98.34,162.78 97.89,162.33 C72.1 ; R29.1 104.69,161.08 104.88,160.89 R33.1 106.14,160.42 v1(106.04,160.32)
  TOP w0.203: v1(104.42,73.38) 104.42,73.44 104.14,73.72 U49.P3 U49.N4 ; v1(66.52,125.25) 66.43,125.16 R117.1 ; U24.3 56.36,125.63 56.42,125.57 C144.1 v1(57,124.96) ; v1(58.66,131.05) 58.28,131.05 R114.1 ; U49.N4 U49.P5 104.19,74.72 v1(104.39,74.93) ; U49.N4 U49.M4 ; v1(67.02,126.49) C146.1 64.49,126.49 U26.5
  TOP w0.254: U11.3 126.32,153.85 126.11,153.85 C101.1 v1(125.34,153.77) ; v1(61.87,94.63) 62.07,94.83 62.43,94.83 62.69,94.57 R198.1 ; R361.1 28.47,34.12 v1(28.57,34.02) ; U28.B4 77.27,118.47 v1(77.15,118.47) ; U32.1 C164.1 39.2,104.25 v1(39.45,104) ; R375.1 64.93,27.9 v1(64.94,27.89) ; v1(45.77,98.7) 45.66,98.81 R166.1 ; R97.2 v1(118.92,140.96) ; v1(99.54,87.59) 99.06,87.11 99.06,85.6 R242.1 ; v1(24.92,153.15) 25.23,152.84 R70.2 ; U6.6 115.86,162.78 115.41,162.33 C73.1 C76.1 113.92,162.78 113.73,162.97 v1(112.93,162.97) ; U34.1 101.53,99.21 C177.1 v1(100.83,98.28) ; R122.2 95.87,120.5 v1(95.87,120.5) ; v1(74.47,114.5) 74.47,114.07 74.22,113.81 C151.2 73.45,113.81 73.27,113.64 U29.8 ; U28.E4 77.32,121.51 v1(77.21,121.51) ; v1(43.95,155.87) 43.8,155.72 FL5.1 ; v1(39.43,143.38) 39.78,143.04 R96.1 ; R248.2 26.23,81.49 v1(26.24,81.48) ; R83.1 v1(122.96,149.17) ; v1(116.33,152.14) 116.46,152.01 R75.1 ; v1(31.29,74.59) C220.2 31.29,73.94 U50.8 ; v1(16.28,86.07) C195.1 U45.1 ; v1(102.14,121.49) C148.1 U27.5 ; 50.5,63.83 U56.26 ; C72.1 C75.1 95.59,162.33 v1(94.76,163.16) ; v1(76.56,150.58) 76.31,150.83 R80.2 ; v1(47.99,94.36) 47.73,94.36 47.73,94.35 R200.1 ; R262.1 v1(92.59,77.11) ; U28.D1 81.19,121.38 C149.2 ; R263.1 R264.1 R266.1 R267.1 R269.1 R270.1 R275.1 v1(92.06,71.14) ; U12.1 C102.2 v1(31.1,153.4) ; v1(50.34,101.39) 50.55,101.17 R164.2 ; R124.2 100.72,119.03 v1(100.59,118.9) ; R268.1 v1(32.34,73.69) ; v1(31.85,69.46) R279.2 ; v1(95.2,103.81) 95.17,103.84 R161.2 ; R69.1 v1(133.37,153.14) ; U43.5 v1(100.89,85.76)
  TOP w0.305: v1(82.69,122.26) 82.69,122.04 82.65,121.99 C149.2 ; U37.1 C179.1 26.26,97.28 v1(26.37,97.17) 26.5,97.17 27.43,96.25 R196.2 ; R123.2 v1(74.57,121.97)
  TOP w0.381: v1(25.57,35.2) 25.57,35.2 25.57,33.09 26.61,32.05 ; v1(28.57,34.02) 28.57,34.02 28.57,33.38 27.82,32.63 v1(27.82,31.52) 27.3,32.05 26.61,32.05 ; v1(26.25,31.18) 26.25,31.68 26.61,32.05 ; v1(40.08,151.06) C106.2 40.1,150.09 41.26,150.09 41.54,149.81 41.54,148.92 41.2,148.58 U17.5 ; 87.13,152.6 R67.2
  L03_SIG01 w0.254: v1(27.82,41.8) 28.32,41.3 28.32,38 29.06,37.26 29.06,34.52 v1(28.57,34.02)
  L05_SIG02 w0.381: v1(14.73,104.98) 14.73,109.3 v1(15.41,109.99)
  BOTTOM w0.191: v1(95.88,116.83) 96.32,116.39 96.79,116.39 97.08,116.1 C395.1 ; U81.24 C408.1 115.53,108.08 115.79,107.83 116.4,107.83 117.22,108.65 v1(117.22,109.25) ; C395.1 96.79,115.82 96.45,115.48 U83.23 ; C395.1 97.08,115.41 97.42,115.08 U83.24 ; v1(117.39,110) 117.25,110.14 U81.23 ; R565.1 103.65,75.57 103.96,75.27 104.05,75.27 v1(104.39,74.93) ; U80.2 C396.2
  BOTTOM w0.203: U125.3 28.61,41.4 C608.2 ; U126.3 28.07,32.34 C617.2 ; C396.2 69.57,115.97 v1(69.36,116.18)
  BOTTOM w0.254: U79.3 42.41,151.17 42.07,151.52 C381.1 40.53,151.52 v1(40.08,151.06) ; v1(78.03,123.29) 78.27,123.53 R445.2 R444.2 R443.2 ; R423.2 131.61,162.7 v1(131.24,162.33) C373.1 C371.1 129.27,162.38 128.87,162.78 U76.6 ; v1(31.29,44.07) 31.39,44.17 R612.1 ; 77.47,122.16 77.23,122.4 C388.1 ; 77.47,122.16 78.41,122.16 R446.2 v1(78.45,122.81) ; 77.47,122.16 77.47,121.77 v1(77.21,121.51) ; R631.1 v1(25.57,35.2) ; C617.2 27.78,31.66 27.82,31.62 v1(27.82,31.52) ; R532.1 27.64,84.16 v1(27.63,84.17) ; v1(100.89,85.76) 101.14,86.01 C421.2 ; R454.2 81.28,118.71 v1(81.62,119.05) ; v1(102.35,72.16) 102.35,72.84 R575.1 ; v1(98.85,75.47) 98.75,75.57 C514.1 97.72,75.57 97.46,75.82 C503.1 ; v1(112.93,162.97) 113.02,162.88 C374.1 C372.1 111.87,162.59 111.68,162.78 U77.6 ; C608.2 28.05,41.68 27.93,41.8 v1(27.82,41.8) ; R508.1 59.43,89.85 v1(59.59,90.01) ; v1(77.21,121.51) 76.77,121.51 76.68,121.61 R448.2 ; v1(77.21,121.51) R449.2 77.22,120.98 R452.2 C390.1 77.22,118.54 v1(77.15,118.47) 78.94,120.27 R450.2 ; R434.2 52.01,158.86 51.63,159.24 51.55,159.24 v1(51.43,159.36) C376.1 51.45,160.07 U78.1 ; C518.1 v1(104.42,73.38) ; v1(61.87,94.63) R503.1 ; R614.2 28.32,44.31 v1(28.48,44.47) ; v1(43.95,155.87) 42.68,155.87 R436.1 ; R419.2 v1(131.94,167.42) ; R611.1 v1(30.66,44.55) ; R636.2 v1(26.25,31.18) ; R465.1 16.97,109.42 R464.1 16.94,109.61 16.56,109.99 v1(15.41,109.99) ; v1(82.69,122.26) 82.79,122.16 R447.2 81.81,121.9 C389.1
  vias: v1(15.23,104.98) v1(15.74,104.98) v1(36.78,102.4) v1(36.78,101.48) v1(37.56,102.4) v1(37.56,101.48) v1(38,53.72) v1(38,52.8) v1(38,51.89) v1(38,50.98) v1(38.35,102.4) v1(38.35,101.48) v1(38.79,53.72) v1(38.79,52.8) v1(38.79,51.89) v1(38.79,50.98) v1(39.14,102.4) v1(39.14,101.48) v1(44.31,155.53) v1(51.14,65.32) v1(51.14,64.68) v1(64.43,117.47) v1(65.04,117.48) v1(84.08,111.47) v1(84.69,111.46) v1(85.41,153.75) v1(86.32,153.85) v1(86.28,152.75) v1(95.16,160.13) v1(104.44,72.79) v1(118.9,140.25) v1(131.21,132.55) v1(131.72,132.55) v1(132.23,132.55)
VCC1V8_SYS_N: length 2.5
  TOP w0.191: R334.4 46.58,49.02 47.13,49.57 47.93,49.57 R335.2
VCC1V8_SYS_P: length 2.3
  TOP w0.191: R334.1 46.58,50.43 47.06,49.95 48.13,49.95 R331.2
VCC1V8_VDD18: length 67
  TOP w0.145: R47.1 48.73,156.58 v1(48.8,156.51)
  TOP w0.254: v1(50.09,104.34) C162.1 U30.5 ; U3.42 C19.1 ; C19.1 45.01,172.79 C10.1 v1(45.65,172.79) ; C19.1 v1(45.54,171.6) ; U31.5 C157.1 v1(56.92,107.91) R144.1 ; C94.1 R59.2 ; C94.1 v1(51.72,156.34) ; C94.1 51.71,155.27 U13.5 51.71,152.9 51.28,152.47 R72.2 v1(49.04,152.47) ; v1(47.01,164.58) 45.72,164.58 v1(45.06,163.92) ; R50.1 v1(45.78,156.54) ; U3.17 44.01,160.08 C79.1
  TOP w0.305: FL5.2 v1(43.26,157.55)
  TOP w0.381: v1(41.76,157.54) C91.1 41.79,156.64 FL5.2 44.16,157.55 C80.1 44.16,159.47 43.98,159.66 C79.1 ; C83.1 36.83,156.99 R53.2 ; C83.1 v1(36.83,159.1) ; C83.1 U9.4
  L03_SIG01 w0.254: v1(36.83,159.1) 40.2,159.1 v1(41.76,157.54) ; v1(45.65,172.79) 45.65,171.71 v1(45.54,171.6) 45.06,171.12 v1(45.06,163.92) 45.06,159.95 45.83,159.17 45.83,156.59 v1(45.78,156.54)
  BOTTOM w0.254: R425.2 v1(45.06,163.92) ; v1(51.72,156.34) 51.39,156.34 50.9,155.85 49.46,155.85 v1(48.8,156.51) 48.28,155.99 46.33,155.99 v1(45.78,156.54) 44.78,157.54 v1(41.76,157.54) ; R424.2 v1(47.01,164.58)
VCC2V5_PG: length 1.5
  BOTTOM w0.191: U127.2 R637.1
VCC3V3_TA: length 61.6
  TOP w0.229: R285.1 112.45,67.09 112.73,66.82 113.25,66.82 v1(113.3,66.77)
  TOP w0.254: R128.2 94.52,117.71 v1(94.66,117.57) 94.79,117.71 R129.2 R130.2 ; R141.2 v1(112.25,117.71) R140.2 ; R139.2 v1(109.71,117.71) R138.2 ; R136.2 106.54,118.05 v1(106.72,118.24) 107.67,118.24 107.81,118.1 R137.2 ; R127.2 v1(92.11,117.71) R126.2 ; R133.2 R132.2 v1(98.48,117.71) R131.2 ; R134.2 v1(104.63,117.71) R135.2
  TOP w0.305: U23.5 92.31,134.34 C136.1 92.31,134.98 v1(92.11,135.19) ; 113.29,66.76 v1(113.3,66.77)
  TOP w0.381: v1(92.11,135.19) 92.11,136.22 v1(92.76,136.87)
  L03_SIG01 w0.381: v1(92.11,117.71) 92.11,124.7 92.7,125.29 92.7,134.59 v1(92.11,135.19)
  BOTTOM w0.191: v1(109.7,116.72) 109.31,116.34 C393.2 U82.31 ; v1(102.81,115.27) 102.85,115.23 R461.2 ; U82.27 C391.2 106.51,117.45 106.72,117.66 v1(106.72,118.24) ; v1(113.35,109.31) 113.35,108.55 113.6,108.3 C409.2 U81.1 ; v1(98.47,116.8) 98.55,116.8 98.92,116.43 C394.2 U83.1 ; v1(110.99,116.77) 110.77,116.55 R457.2
  BOTTOM w0.254: v1(92.76,136.87) 92.88,136.99 R439.2 ; v1(127.2,70.64) 127.2,70.66 127.32,70.77 C529.2 ; v1(127.2,70.64) 127.2,69.74 127.58,69.36 R583.1 ; v1(127.2,70.64) 126.66,70.64 126.41,70.39 R582.1 ; v1(107.07,90.04) R507.1 R513.1 R524.1 ; R526.1 R516.1 R511.1 116.02,89.5 v1(116.15,89.64)
  BOTTOM w0.33: C529.2 127.32,71.53 127.44,71.65 U107.8
  BOTTOM w0.381: R578.2 132.78,70.86 v1(133.48,70.15)
  vias: v1(34.86,31.51) v1(34.88,30.6) v1(34.88,29.83) v1(35.57,31.51) v1(35.59,30.6) v1(35.59,29.83)
VCC3V3_XDS: length 65.8
  TOP w0.191: v1(116.75,81.74) 116.79,81.7 U48.69
  TOP w0.203: U48.16 v1(132.12,76.9) ; U48.7 v1(132.12,73.3) ; U48.26 C208.1 ; C231.2 121.11,68.37 121,68.47 U48.101 ; U48.90 118.55,73.3 118.57,73.32 118.77,73.32 118.93,73.48 118.93,73.57 119.12,73.75 119.46,73.75 v1(119.57,73.86) ; v1(119.08,77.9) 118.88,77.7 U48.79 ; C232.1 125.65,68.22 125.8,68.37 U48.113 ; U48.28 134.38,81.7 v1(134.64,81.44) ; U48.51 124.6,83.7 124.4,83.49 v1(124.03,83.49) 124.2,83.67 U48.52 ; U48.39 129.4,83.46 v1(129.05,83.11) ; U48.8 134.38,73.7 C221.1 ; v1(126.41,86.65) 126.41,86.11 126.2,85.9 U48.47 ; U48.122 C234.1
  TOP w0.254: v1(113.46,83.36) 113.69,83.13 R246.2 ; R237.1 R236.1 v1(127.15,87.05) ; v1(135.38,73.89) 135.51,73.76 C222.1 C221.1 ; U40.14 107.67,86.9 107.49,86.72 107.07,86.72 C192.1 v1(107.07,86.18) ; C232.1 125.65,67.43 v1(125.91,67.18) ; R241.1 v1(134.75,84.27) ; v1(130.02,67.97) 129.83,67.78 C234.1 ; v1(134.64,81.44) 134.82,81.25 C208.1 ; C231.2 v1(121.11,67.25)
  TOP w0.305: U51.1 114.64,68.31 C235.2 v1(115.21,66.98) ; TP68.1 115.74,65.6 v1(116.27,65.08) C243.1 115.93,64.05 R306.1 ; R277.2 v1(111.38,71.57) ; v1(116.58,68.63) 116.55,68.66 R280.1 ; R119.1 R118.1 ; R119.1 110.87,124.01 111.15,124.29 v1(111.15,124.57) C147.1 U25.8 ; R119.1 v1(110.49,123.36)
  BOTTOM w0.178: v1(122.9,77.19) 122.7,77.39 U102.8
  BOTTOM w0.191: R523.2 R522.2 R521.2 R520.2 ; U97.2 121.5,80.25 C469.2
  BOTTOM w0.203: v1(121.38,75.34) 121.5,75.22 C515.2 121.5,74.84 121.5,74.45 121.36,74.31 U109.8
  BOTTOM w0.254: v1(124.03,83.49) 123.84,83.69 C430.2 ; C473.2 127.72,79.29 127.44,79.01 U107.1 ; R512.1 R517.1 R525.1 108.71,86.64 v1(108.97,86.37) ; v1(116.75,81.74) 116.72,81.71 116.72,81.19 116.97,80.93 R549.2 ; v1(121.78,79.5) 121.71,79.57 C469.2 ; C500.2 122.97,77.25 v1(122.9,77.19) ; C488.1 119.36,78.18 v1(119.08,77.9) ; R519.1 R515.1 R510.1
  BOTTOM w0.305: C473.2 127.72,80.49 v1(127.92,80.69) ; R551.1 R552.1 v1(128.8,81.26) ; v1(114.38,89.86) 114.38,89.3 R510.1 ; R523.2 v1(118.19,89.01)
  vias: v1(118.48,66.51) v1(119.04,66.49)
VCC_0V85: length 4.7
  TOP w0.254: v1(52.29,64.05) 52.29,63.46 C246.1 51.65,63.46 v1(51.65,64.05) ; U56.25 51.84,63.33 52.1,63.59
VCC_1V8_FT4232: length 36.8
  TOP w0.254: U64.37 C281.2 ; U64.64 v1(28.54,47.57) ; U64.49 36.04,50.53 C263.1 ; C280.2 25.13,41.41 25.29,41.25 U64.12
  TOP w0.305: v1(28.54,47.57) 28.54,46.29 29.22,45.61 33.54,45.61 34.58,44.57 34.58,41.65 32.73,39.8 30.2,39.8 28.75,41.25 U64.12 ; U64.37 36.78,41.25 36.04,41.99 U64.49
  BOTTOM w0.254: C599.2 v1(28.54,47.57)
VCC_1V8_IOVDD: length 103.3
  TOP w0.191: R23.1 80.03,165.01 v1(79.41,165.63) ; v1(92.24,147.86) R90.2 91.3,147.17 90.82,147.64 U14.5 90.07,148.87 89.95,148.75 C109.1 88.42,148.75 v1(88.3,148.88) 88.3,151.55 88.61,151.86 R67.1 ; R20.1 v1(77.9,165.61)
  TOP w0.254: C109.1 R78.2 ; R60.1 70.91,154.47 71.58,153.8 72.14,153.8 v1(72.69,154.35) R62.1 ; v1(74.94,101.4) 74.78,101.55 C173.1 74.42,102.17 74.29,102.04 U35.5 ; U8.27 72.91,158.48 C84.1 74.35,158.11 C85.1 v1(75.03,158.03) ; U33.5 C166.1
  TOP w0.305: U7.27 78.02,161.26 77.66,161.62 C74.1 v1(77.2,161.63) 76.59,161.63 C71.1 ; R162.1 v1(84.75,104.04) 84.78,104.02 C166.1
  L03_SIG01 w0.254: v1(89.66,152.95) 89.55,153.06 87.34,153.06 86.4,152.11 85.54,152.11 85.06,151.63 85.06,147.97 85.72,147.31 85.72,142.18 84.83,141.28 84.83,127.5 87.02,125.31 87.02,110.56 86,109.55 86,104.7 85.34,104.04 v1(84.75,104.04)
  L04_PWR1 w0.508: v1(79.41,165.63) 79.41,166.22 79.04,166.59 78.25,166.59 77.9,166.24 v1(77.9,165.61) 77.9,164.46 78.92,163.45 78.92,160.96 78.54,160.59 77.67,160.59 77.2,161.06 v1(77.2,161.63)
  BOTTOM w0.191: 77.56,173.05 C340.1 v1(76.39,173.07) ; 77.56,173.05 77.64,172.97 U75.5 80.02,172.97 80.36,173.3 R413.2 ; 77.56,173.05 R416.2
  BOTTOM w0.254: v1(74.41,99.07) 74.9,99.56 C418.1 74.67,99.9 U89.5
  vias: v1(89.65,153.84) v1(90.16,154.63)
VCC_3V3_AVDD: length 31.7
  TOP w0.305: 70.14,163.52 U8.3 ; 80.81,156.55 U7.3
  TOP w0.381: 70.14,163.52 70.93,164.31 L2.1 71.64,164.82 71.89,164.57 C53.2 C52.1 ; 80.81,156.55 80.01,155.75 L3.1 ; C52.1 74.49,164.57 FL2.2 ; C52.1 73.3,164.2 72.89,163.79 C63.1 C68.1 72.35,162.57 72.12,162.34 71.52,162.34 71.14,161.96 U8.1 ; U7.1 79.81,157.78 79.43,157.4 78.29,157.4 C86.1 C90.1 78.05,155.89 77.65,155.49 C98.1 v1(77.02,155.17)
  L04_PWR1 w0.381: v1(74.49,165.61) v1(74.49,163.79) 74.67,163.61 75.2,163.61 76.47,162.33 76.47,155.71 v1(77.02,155.17)
VCC_3V3_FT4232: length 39.9
  TOP w0.254: R333.2 27.45,50.07 v1(27.31,50.21) ; U66.1 21.95,37.64 C285.1 22.08,37.64 22.34,37.89 v1(22.34,38.4) ; R328.2 29.23,51.54 v1(29.36,51.42) ; v1(39.82,43.04) C275.2 U64.42 ; 30.09,35.02 30.09,35.08 30.04,35.12 C288.2 U64.20 ; v1(34.76,35.86) 35.06,35.57 C289.2 U64.31 ; LD7.2 32.54,51.81 v1(32.54,51.21) C264.2 U64.56 ; v1(19.91,51.4) C262.2 21.13,50.89 U61.8 ; U64.50 v1(35.54,47.54) ; R321.2 v1(28.51,53.4)
  TOP w0.381: v1(28.6,32.39) 30.09,33.88 30.09,35.02
  BOTTOM w0.203: U125.2 28.61,41 C612.2 ; C575.2 32.76,58.09 U117.2 ; U126.2 28.47,32.52 v1(28.6,32.39)
  BOTTOM w0.254: 32.28,58.95 32.48,58.74 C575.2 ; C618.2 28.6,32 v1(28.6,32.39)
  BOTTOM w0.381: 32.28,58.95 32.28,59.34 31.73,59.89 27.27,59.89 25.77,58.39 25.77,55.37 27.56,53.58
  vias: v1(22.57,37.56)
VCC_3V3_MAIN: length 53.1
  TOP w0.203: v1(26.29,67.93) 26.29,68.13 26.09,68.32 C230.2 U52.5
  TOP w0.254: R240.1 42.25,85.6 v1(42.36,85.49) ; U56.30 47.87,63.98 48.13,63.73 v1(48.22,63.73) ; U56.16 47.87,60.68 48.13,60.93 v1(48.22,60.93) ; U56.3 v1(42.66,63.33) v1(42.22,63.33) ; v1(41.67,59.55) 38.81,59.55 TP80.1 ; R282.1 55.73,71.24 55.92,71.42 v1(55.92,72.53) ; v1(45.53,60.93) 45.62,60.93 45.87,60.68 U56.12 ; U54.5 v1(28.28,66.7) ; U56.18 48.87,59.55 49.13,59.3 49.58,59.3 v1(49.69,59.18) ; U42.4 v1(47.06,85) ; v1(45.53,63.73) 45.62,63.73 45.87,63.98 U56.34 ; v1(50.49,60.83) U56.20
  TOP w0.305: R371.1 v1(50.28,30.37) ; U59.8 C255.1 v1(62.48,56.54)
  TOP w0.381: R318.2 26.13,59.04 v1(25.68,59.49) ; v1(19.62,64.46) 19.85,64.69 R302.2 ; v1(42.36,85.49) C197.1 42.53,84.75 U46.1
  L04_PWR1 w0.508: v1(62.48,56.54) 62.1,56.92 60.36,56.92 59.32,57.97 59.32,59.74 59.06,60 56.57,60 54.7,58.13 52.6,58.13 51.92,58.81 51.92,60.15 51.24,60.83 v1(50.49,60.83)
  BOTTOM w0.254: C538.1 v1(28.28,66.7) ; v1(13.49,21.59) 13.98,21.09 R668.2 ; v1(49.69,59.18) 49.73,59.14
  BOTTOM w0.305: v1(52.13,76.02) 52.13,75.48 52.32,75.29 53.06,75.29 53.45,75.69 54.31,75.69 55.04,74.96 FL15.1
  BOTTOM w0.381: FL15.1 55.72,72.72 v1(55.92,72.53)
  vias: v1(21.42,59.58) v1(21.94,59.58) v1(28.55,30.51) v1(28.55,29.49) v1(28.55,26.44) v1(28.58,25.77) v1(29.51,30.51) v1(29.51,29.49) v1(29.51,26.44) v1(30.48,31.52) v1(30.48,30.51) v1(30.48,29.49) v1(30.48,28.47) v1(30.48,27.46) v1(30.48,26.44) v1(31.44,31.52) v1(31.44,30.51) v1(31.44,29.49) v1(31.44,28.47) v1(31.44,27.46) v1(31.44,26.44) v1(32.41,31.52) v1(32.41,30.51) v1(32.41,29.49) v1(32.41,28.47) v1(32.41,27.46) v1(32.41,26.44) v1(41.93,62.84) v1(42.42,62.82) v1(44.32,82.29) v1(44.78,82.29) v1(44.78,81.83) v1(44.78,81.37) v1(44.78,80.92) v1(45.1,63.73) v1(45.1,63.3) v1(45.1,61.37) v1(45.1,60.93) v1(45.23,82.29) v1(45.23,81.83) v1(45.23,81.37) v1(45.23,80.92) v1(45.4,84.26) v1(45.4,83.79) v1(45.53,63.3) v1(45.53,61.37) v1(45.69,81.83) v1(45.69,81.37) v1(45.69,80.92) v1(46.15,81.83) v1(46.15,81.37) v1(46.15,80.92) v1(48.22,63.3) v1(48.22,61.37) v1(48.65,63.73) v1(48.65,63.3) v1(48.65,61.37) v1(48.65,60.93)
VCC_3V3_MAIN_PG: length 154
  TOP w0.191: v1(88.31,26.09) 88.31,30.53 v1(88.39,30.61) ; v1(31.2,32.47) 30.78,32.05 29.92,32.05 29.69,31.82 28.84,31.82 27.05,30.03 23.11,30.03 18.07,24.99 18.07,23.66 15.07,20.66 v1(13.49,20.66) ; U54.3 26.55,66.2 25.76,65.41 v1(23.01,65.41)
  L03_SIG01 w0.076: v1(13.49,20.66) 16.07,23.25 16.07,25.48 18.42,27.82 18.42,41.76 23.01,46.35 v1(23.01,65.41)
  BOTTOM w0.191: v1(31.2,32.47) 31.54,32.8 35.7,32.8 36.59,31.91 37.9,31.91 39.98,29.83 45.93,29.83 46.74,29.01 46.74,22.4 47.16,21.99 47.43,21.99 49.33,23.89 86.11,23.89 v1(88.31,26.09) ; v1(13.49,20.66) 13.76,20.39 15.39,20.39 15.58,20.58 R668.1 16.25,21.09 16.86,21.7 U128.21 ; R640.1 v1(88.39,30.61)
VCC_3V3_SYS: length 242
  TOP w0.191: v1(23.02,86.41) C194.1 U45.14 ; J14.5 C169.1
  TOP w0.254: v1(85.05,142.47) 85.05,142.52 84.5,143.07 U18.23 ; v1(104.18,93.43) 104.18,93.02 R212.1 R211.1 ; U11.7 131.64,154.35 C99.1 v1(131.67,155.01) ; v1(30.48,140.74) C123.1 U19.5 ; U21.31 C126.2 107.42,138.7 v1(107.68,138.96) ; v1(49.32,95.76) 49.65,95.76 49.85,95.55 C181.2 50.42,95.96 50.43,95.97 U36.5 ; U2.5 16.38,166.8 16.15,167.03 C37.1 ; v1(43.32,60.15) 43.5,60.33 U56.9 ; R56.1 v1(131.81,156.48) ; v1(88.67,45.68) 88.27,45.28 R353.1 ; R362.2 v1(68.68,31.96) R363.2 ; R180.2 117.58,97.17 v1(117.36,96.95) ; U22.3 79.02,136.87 v1(79.04,136.85) ; U39.8 102.83,91.86 C186.2 102.49,93.57 v1(102.47,93.59) ; R324.2 v1(35.65,88.62) R222.1 ; C37.1 v1(16.15,168.5) ; C37.1 16.63,167.53 16.82,167.72 R17.2 ; R368.1 v1(44.8,30.69) ; R58.1 v1(125.55,156.05) ; R225.1 104.62,88.26 v1(104.73,88.37) 104.98,88.62 104.98,89 104.98,89.01 R220.1 ; v1(13.92,166.17) 13.93,166.18 R18.2 ; R360.1 72.95,37.04 72.81,37.19 v1(72.69,37.19) ; R288.1 56.81,67.08 v1(56.37,67.08) R291.1 ; U22.1 78.02,137.13 77.63,136.74 C132.1 C131.1 76.74,136.56 77.13,136.95 v1(77.13,137.25) C127.1 ; U21.27 v1(105.13,139.11) ; U25.1 C140.1 111.76,133.73 v1(111.46,134.04) ; R260.2 v1(21.88,76.87) ; v1(56.02,131.05) 55.86,130.88 C143.1 U24.7 ; v1(102.3,76.72) U49.K9 v1(101.35,76.72) U49.J10 ; v1(45.88,24.38) 46.01,24.38 C298.1 U70.8 ; v1(102.65,88.88) 102.65,89.33 C187.2 102.83,89.94 U39.1 ; v1(71.6,115.68) 71.91,115.38 C150.2 71.05,114.83 70.78,114.57 70.78,113.87 71.01,113.64 U29.1 ; R92.2 79.35,149.73 v1(78.68,150.4) ; U49.E6 v1(99.74,75.22) ; C156.1 61,110.15 60.92,110.23 v1(60.66,110.23) ; U34.14 C178.1 95.69,97.85 95.69,97.5 v1(95.52,97.33) ; U32.14 C165.2 47.79,105.3 47.54,105.56 v1(47.53,105.56) ; R115.1 v1(62.4,127.63) ; R91.2 v1(29.33,146.57) ; U38.5 v1(36.97,94.17) ; C154.1 76.11,112.78 R142.1 76.24,113.62 v1(76.7,114.07) ; v1(21.24,170.13) 21.49,169.88 C28.1 21.48,168.99 C33.2 21.49,167.73 U4.1 ; J11.1 41.1,128.12 41.11,128.11 C145.1 41.52,127.43 v1(41.66,127.29) ; U63.4 C268.2 68.68,48.05 68.42,47.79 v1(68.42,47.58) 68.77,47.24 R339.1 ; v1(45.47,92.74) C185.2 C184.2 42.38,92.74 42.22,92.9 U38.3 ; C152.1 C153.1 v1(80.2,113.98) ; R99.1 v1(79.02,143.03) ; v1(94.81,89) 94.83,88.99 C189.2 94.83,87.15 U44.4 ; v1(82.74,142.42) 82.83,142.51 C122.2 83.5,142.68 U18.21 ; U49.F5 99.85,74.47 v1(99.6,74.22) ; v1(26.43,93.09) 26.26,92.92 C183.1 U37.11 ; v1(86.47,47.64) 86.47,47.27 86.04,46.84 R343.2 R342.1 ; C159.1 60.72,106.64 v1(60.7,106.65) ; R120.1 v1(42.94,123.04) ; R344.1 v1(115.16,46.49) ; R356.1 119.07,44.77 v1(119.24,44.94) 119.4,45.1 R351.2 ; U68.5 69.33,30.38 69.51,30.2 C293.1 70.41,30.2 v1(70.53,30.08) ; R354.1 v1(121.02,45.99) ; R98.2 v1(84.24,141.51) ; C169.1 v1(114.57,103.67) ; R292.2 38.25,65.62 v1(38.78,65.09) 38.47,64.78 R301.1 ; R396.1 57.2,19.41 57.57,19.79 v1(58.16,19.79) ; FL3.1 v1(33.67,164.42) ; R106.2 v1(108.51,137.66) ; R259.1 v1(21.96,78.44)
  TOP w0.381: v1(46.88,148.19) 47.26,147.82 C113.1 U17.3
  L03_SIG01 w0.305: v1(54.46,62.15) 53.18,62.15 51.1,60.07 43.39,60.07 v1(43.32,60.15)
  L06_PWR2 w0.381: v1(57.96,57.05) 57.91,57.05 57.6,57.35 54.95,57.35 54.71,57.11 v1(54.65,57.11) 54.65,57.12 52.37,59.4 52.37,61.5 53.12,62.25 54.36,62.25 v1(54.46,62.15)
  BOTTOM w0.178: U102.1 121.32,77.39 121.02,77.09 v1(121.02,76.84)
  BOTTOM w0.191: U97.3 121.1,80.25 C470.2 ; U86.5 107.6,103.99 107.83,103.76 C414.2 108.27,103.35 v1(108.48,103.56) R480.1 ; R485.2 114.95,103.29 v1(114.57,103.67) ; R482.1 v1(105.33,103.34) ; U88.5 C416.2 v1(117.55,101.72) ; U87.5 112.09,103.82 111.91,103.64 C415.2 112.2,103.08 v1(112.49,103.37) ; C504.1 98.69,77.37 v1(98.89,77.56)
  BOTTOM w0.203: R550.1 35.63,81.23 v1(36.25,81.23) ; U80.3 70.76,116.05 70.75,116.06 70.18,116.06 69.97,116.27 69.97,116.57 69.77,116.77 C392.2 69.55,117.26 v1(69.36,117.45) 69.36,117.9 69.56,118.1 R455.2 ; U109.1 121.36,71.88 v1(121.46,71.78) ; v1(48.8,43.13) U123.C3 U123.B3 ; U124.1 48.86,39.85 v1(48.61,39.6) 48.36,39.85 U124.2 ; C420.2 114.59,95.34 114.35,95.58 U90.1 ; U110.3 123.31,73.26 ; U98.8 33.84,80.05 34.14,79.75 34.52,79.75 C478.2 34.8,79.74 34.96,79.58 35.26,79.58 v1(35.32,79.65) ; v1(111.21,46.99) 111.59,47.37 C602.1 112.44,47.37 112.62,47.55 U120.5 ; R601.2 R602.2 112.62,49.46 v1(112.95,49.79) ; U90.8 114.35,98.05 v1(114.51,98.21) ; U110.2 123.34,72.86 ; R559.1 26.92,77.3 v1(26.82,77.4) ; U123.B1 v1(47.01,42.73)
  BOTTOM w0.254: U122.1 54.22,42.8 v1(54.39,42.97) ; R471.1 v1(58.16,106.42) ; R471.1 R473.1 ; R471.1 R469.1 ; R533.2 118.99,84.35 R534.2 v1(117.87,84.35) 117.67,84.35 117.49,84.17 R536.2 ; U85.25 C413.1 67.79,103 v1(67.9,102.9) ; R554.2 118.22,79.55 117.97,79.29 117.97,79.23 117.79,79.05 117.21,79.05 117.17,79.09 115.46,79.09 115.11,79.45 v1(114.55,79.45) ; C377.1 95.75,158.95 95.49,159.2 v1(95.09,159.2) ; C427.1 51.85,85.59 v1(52.01,85.75) ; v1(129.15,47.33) 129.15,46.99 R347.1 ; v1(54.65,57.11) 54.71,57.11 54.94,57.35 U115.B1 ; v1(54.46,62.15) 54.33,62.02 C560.1 54.33,61.07 55.06,60.34 U116.6 ; U118.2 59.19,44.28 v1(59.8,43.67) ; R616.2 v1(127.54,42.61) ; U119.B3 59.45,48.74 v1(59.7,48.49) ; R459.1 v1(76.84,116.09) R460.1 ; U115.B3 57.35,57.35 57.65,57.05 v1(57.96,57.05) ; C470.2 120.89,79.57 v1(120.82,79.5) ; v1(51.33,87.96) 51.11,87.73 U91.6 ; U92.B1 v1(51,89.23) ; v1(60.25,113.9) 60.44,113.72 C398.1 ; v1(122.28,73.46) C519.2 123.11,73.46 123.31,73.26 ; R597.2 56.06,48.09 v1(55.82,47.84) ; U124.6 46.86,45.94 46.71,46.09 46.41,46.09 46.13,46.37 C604.1 v1(46.13,47.66) ; v1(82.84,37.99) 82.84,39.4 R620.2 ; U113.B1 v1(36.26,67.73) ; U122.6 52.22,47.02 52.05,47.19 51.69,47.19 51.48,47.4 C601.1 v1(51.48,48.74) ; U78.11 55.25,160.12 C375.1 55.25,159.58 v1(55.16,159.49) ; U121.C3 v1(54.14,44.21) ; 123.34,72.86 123.14,72.65 C523.2 v1(122.28,72.65) ; v1(73.77,105.59) 73.8,105.62 C411.1 74.26,106.6 74.26,106.78 74.51,107.04 U84.25 ; R598.1 38.22,49.03 R603.1 38.23,48.56 v1(38.39,48.4) ; R440.2 v1(48.6,128.33) ; v1(60.66,110.23) 60.74,110.15 C156.1 ; R645.1 38.55,27.77 v1(38.39,27.77) ; U84.39 v1(76.7,114.07) ; R437.1 v1(108.57,150.56) ; U114.6 36.13,70.92 35.99,71.06 35.65,71.06 35.4,71.32 C525.1 v1(35.4,72.6) ; C419.2 v1(114.51,98.21) ; C511.2 121.22,76.64 v1(121.02,76.84) ; U119.B1 v1(57.85,48.74) ; U116.2 56.56,54.35 v1(56.95,53.96) 56.95,53.95 C598.1 56.95,52.38 57.26,52.07 57.57,52.07 57.69,51.95 U118.6 ; C420.2 114.59,94.43 v1(114.49,94.33) ; v1(114.15,82.07) C455.2 114.77,82.35 114.47,82.64 U93.5 ; v1(44.04,154.07) 43.7,154.4 C380.1 43.65,154.73 42.91,153.99 U79.7 ; v1(55.74,41.63) 56.32,41.63 R617.2 ; v1(121.89,37.97) 122.18,38.26 R625.2 ; R615.1 v1(62.72,43.76) ; U85.39 v1(60.7,106.65) ; C528.2 121.55,71.69 v1(121.46,71.78) ; C153.1 v1(80.2,113.98) ; U121.B1 v1(52.39,43.81)
  BOTTOM w0.305: R641.2 67.35,30.31 67.2,30.46 R638.2 66.76,30.99 66.46,30.68 v1(66.46,30.47) ; R630.2 71.67,34.73 71.88,34.95 R629.2 72.86,34.95 v1(73.31,34.5)
  BOTTOM w0.381: v1(99.6,74.22) 99.59,74.21 C520.1
  vias: v1(37.16,117.56) v1(37.16,116.93) v1(37.16,116.29) v1(37.16,115.66) v1(37.8,117.56) v1(37.8,116.93) v1(37.8,116.29) v1(37.8,115.66) v1(42.36,112.88) v1(43.2,90.24) v1(43.2,89.6) v1(43.2,88.97) v1(43.2,88.33) v1(43.83,90.24) v1(43.83,89.6) v1(43.83,88.97) v1(43.83,88.33) v1(44.47,90.24) v1(44.47,89.6) v1(44.47,88.97) v1(44.47,88.33) v1(45.1,90.24) v1(45.1,89.6) v1(45.1,88.97) v1(45.1,88.33) v1(46.65,90.19) v1(46.63,89.33) v1(47.28,90.19) v1(47.27,89.33) v1(47.92,90.19) v1(47.9,89.33) v1(72.74,22.67) v1(72.74,22.03) v1(72.74,21.4) v1(73.37,22.67) v1(73.37,22.03) v1(73.37,21.4) v1(74.01,22.67) v1(74.01,22.03) v1(74.01,21.4) v1(75.99,165.57) v1(75.99,163.77) v1(82.93,114.58) v1(90.78,45.07) v1(90.77,44.46) v1(90.75,43.82) v1(91.64,28.57) v1(91.67,27.9) v1(92.4,28.55) v1(92.42,27.89) v1(111.45,170.39) v1(111.76,169.86) v1(111.91,170.89) v1(116.45,53.34) v1(116.45,52.7) v1(116.45,52.07) v1(116.45,51.43) v1(117.09,53.34) v1(117.09,52.7) v1(117.09,52.07) v1(117.09,51.43) v1(117.72,52.07) v1(117.72,51.43) v1(123.2,45.07) v1(123.24,43.86)
VCC_3V3_SYS_EN: length 2.3
  TOP w0.191: U42.3 45.97,84.54 46.28,84.22 R245.2 R244.2
VCC_3V3_SYS_N: length 5
  TOP w0.191: v1(47.18,80.58) 47.38,80.77 47.65,80.77 47.85,80.57 R251.1
  BOTTOM w0.191: v1(47.18,80.58) 47.53,80.92 48.58,80.92 49.56,81.9 49.56,82.37 49.92,82.73 R539.2
VCC_3V3_SYS_P: length 4.4
  TOP w0.191: R251.4 47.85,81.68 47.63,81.46 47.36,81.46 v1(47.16,81.66)
  BOTTOM w0.191: v1(47.16,81.66) 47.51,81.31 48.42,81.31 49.18,82.06 49.18,82.21 49.18,82.34 R540.2
VCC_5V0: length 52.9
  TOP w0.254: C313.1 48.33,20.18 48.53,20.38 R392.1 49.45,19.7 v1(49.68,19.47) ; R387.2 45.87,23.29 v1(45.96,23.21)
  L06_PWR2 w0.508: v1(54.06,82.56) 54.06,82.61 49.95,86.72 43.22,86.72 43.09,86.59 32.32,86.59 27.83,82.1 20.31,82.1 18.95,80.74 v1(14.01,80.74)
  BOTTOM w0.254: R665.1 46.17,22.99 v1(45.96,23.21) ; R543.1 58.08,82.71 57.43,82.06 54.56,82.06 v1(54.06,82.56)
  vias: v1(13.9,102.03) v1(13.9,101.53) v1(14.41,102.03) v1(14.41,101.53) v1(14.92,102.03) v1(14.92,101.53) v1(15.37,142.07) v1(15.42,102.03) v1(15.42,101.53) v1(15.61,141.52) v1(15.99,142.08) v1(16.25,141.55) v1(49.68,18.56) v1(49.68,17.65) v1(50.54,20.39) v1(50.54,19.47) v1(50.54,18.56) v1(50.54,17.65) v1(51.41,20.39) v1(51.41,19.47) v1(51.41,18.56) v1(51.41,17.65) v1(60.45,27.73) v1(60.46,27.1) v1(61.21,27.72) v1(61.22,27.1) v1(131.58,135.95) v1(131.58,135.44) v1(132.09,135.95) v1(132.09,135.44) v1(132.6,135.95) v1(132.6,135.44) v1(133.11,135.95) v1(133.11,135.44)
VCC_5V0_EN: length 1.4
  TOP w0.14: U72.14 50.62,25.87 v1(50.4,26.09)
  BOTTOM w0.14: R647.2 v1(50.4,26.09)
VCC_5V0_FB: length 4.4
  TOP w0.254: C313.2 47.77,20.28 48.23,20.74 R391.1 R392.2 49.45,21.9 49.65,22.1 49.83,22.1 50.12,22.39 U72.5
VCC_5V0_PG: length 157.1
  TOP w0.14: R388.2 v1(47.2,22.59)
  TOP w0.191: v1(100.2,94.73) 101.1,94.73 103.93,97.56 103.93,104.1 104.82,104.98 105.13,104.98 106.04,104.98 106.46,104.56 108.4,104.56 v1(108.64,104.81)
  L03_SIG01 w0.076: v1(100.2,94.73) 98.42,92.96 98.42,84.91 101.97,81.36 101.97,79.44 103.81,77.6 103.81,59.08 112.45,50.44 v1(113.33,50.44)
  BOTTOM w0.191: v1(108.64,104.81) 108.56,104.89 U86.3 ; v1(113.33,50.44) 95.62,50.44 92.94,47.76 92.11,47.76 88.11,43.76 85.91,43.76 84.78,42.62 81.38,42.62 80.82,42.07 80.82,37.38 78.68,35.23 76,35.23 73.15,38.08 67.59,38.08 64.24,34.73 64.24,32.58 63.46,31.8 56.73,31.8 56.33,31.4 50.27,31.4 47.2,28.32 v1(47.2,22.59)
VCC_CORE:
  vias: v1(41.41,72.24) v1(41.41,71.42) v1(41.85,70.94) v1(42.32,72.24) v1(42.32,71.42) v1(44.38,71.6) v1(45.29,71.6) v1(45.73,72.04) v1(46.21,71.6) v1(47.54,71.6) v1(48,72.1) v1(48.45,71.6) v1(48.89,72.16) v1(49.37,71.6) v1(51.42,72.24) v1(51.42,71.42) v1(52.34,72.24) v1(52.34,71.42)
VCC_CORE_N: length 8.5
  TOP w0.191: R265.2 43.08,75.04 42.53,74.49 41.7,74.49 39.94,76.26 38.18,76.26 37.67,75.76 37.67,75.24 v1(37.24,74.81)
  BOTTOM w0.191: R572.2 v1(37.24,74.81)
VCC_CORE_P: length 7.8
  TOP w0.191: v1(38.5,74.83) 38.09,75.24 38.09,75.63 38.33,75.88 39.78,75.88 41.55,74.11 42.5,74.11 43.08,73.53 R265.3
  BOTTOM w0.191: R571.2 v1(38.5,74.83)
VCC_LM5141: length 6
  BOTTOM w0.254: U128.10 22.03,21.7 C627.1 25.69,23.85 25.95,24.11 D15.2
VDD1_LPDDR4_1V8: length 11.6
  TOP w0.254: U58.F12 v1(71.98,65.85) ; v1(79.36,65.85) 79.13,65.62 U58.U12 ; v1(72,55.39) 71.79,55.6 71.79,56.24 U58.F1 ; U58.G9 v1(72.96,63.23) ; v1(79.24,54.91) 79.13,55.01 v1(79.13,55.81) U58.U1 ; U58.T4 v1(78.81,59.23) ; U58.G4 v1(72.31,58.43) ; U58.T9 v1(78.16,63.23)
  TOP w0.305: v1(71.98,65.85) 72.43,66.3 C237.1
  BOTTOM w0.305: C543.2 79.19,65.67 v1(79.36,65.85) ; C539.1 71.98,66.1 v1(71.98,65.85) ; v1(72,55.39) 71.82,55.2 C591.1 C594.2 ; C551.1 72.84,63.35 v1(72.96,63.23) ; v1(78.81,59.23) 78.85,59.27 C571.1 ; C554.1 78.16,63.15 v1(78.16,63.23) ; C578.1 72.42,58.32 v1(72.31,58.43)
VDD_0V85_N: length 5.4
  BOTTOM w0.191: R585.2 59.19,67.17 59.19,67.81 59.78,68.4 59.78,70.03 59.37,70.45 58.95,70.45 58.74,70.24 R581.1
VDD_0V85_P: length 5.9
  BOTTOM w0.191: R581.4 58.74,71.02 58.93,70.83 59.53,70.83 60.17,70.18 60.17,68.26 59.57,67.65 59.57,67.2 59.92,66.85 R584.2
VDD_1V8_N: length 1.7
  TOP w0.191: R316.4 56.85,60.7 56.3,61.25 56.3,61.51 R311.2
VDD_1V8_P: length 1.5
  TOP w0.191: R316.1 55.41,60.7 55.87,61.15 55.87,61.51 R310.2
VDD_2V5: length 5.6
  TOP w0.254: 115.2,45.86 115.61,45.45 115.61,44.91
  TOP w0.305: TP92.1 114.85,45.86 115.2,45.86
  BOTTOM w0.254: C615.1 v1(88.22,31.78) 88.47,31.53 88.92,31.53 R637.2 v1(88.93,31.93) 89.24,32.24 R634.1
  vias: v1(82.75,45.23) v1(82.75,43.9) v1(93.14,35.83) v1(94.03,35.83) v1(94.92,35.83) v1(95.81,35.83) v1(115.2,45.11) v1(115.18,43.85)
VDD_2V5_FB: length 4.7
  BOTTOM w0.254: C615.2 R634.2 R632.1 90.51,33.03 90.16,32.68 90.16,32.31 90.43,32.04 U127.3
VDD_CANUART: length 28.8
  TOP w0.356: U47.H9 v1(72.36,77.59)
  TOP w0.381: v1(57.82,73.1) C224.1 57.33,72.53 56.71,73.14 54.06,73.14 48.23,78.97 45.51,78.97
  L06_PWR2 w0.165: 67.19,77.19 71.96,77.19 v1(72.36,77.59)
  L06_PWR2 w0.381: 67.19,77.19 66.08,77.19 65.55,76.66 62.02,76.66 62,76.68 61.54,76.68 61.52,76.66 60.3,76.66
  BOTTOM w0.305: C499.1 72.36,77.35 v1(72.36,77.59)
VDD_CORE: length 62
  TOP w0.254: U56.4 43.23,62.83 v1(43.2,62.8)
  TOP w0.356: U47.J13 v1(73.16,81.59) ; U47.M12 v1(76.36,80.79) U47.N13 v1(77.16,81.59) U47.P14 v1(77.96,82.39) U47.R15 v1(78.76,83.19) U47.T16 v1(79.56,83.99) ; U47.M12 U47.N11 v1(77.16,79.19) U47.P10 v1(77.96,78.39) U47.R9 v1(78.76,77.59) ; U47.M12 U47.L13 v1(74.76,81.59) U47.K14 v1(73.96,82.39) U47.J15 v1(73.16,83.19) ; U47.M12 U47.L11 v1(74.76,79.19) ; U47.J11 v1(73.16,79.19) ; U47.U15 v1(80.36,83.19) ; U47.L9 v1(74.76,77.59) ; U47.J9 v1(73.16,77.59)
  L04_PWR1 w0.508: v1(43.2,62.8) 43.46,63.06 43.46,65.82 46.26,68.62 53.14,68.62 55.93,65.83 57.77,65.83 58.9,66.96 58.9,70.1 56.91,72.09 56.91,73.57
  BOTTOM w0.254: v1(79.56,83.99) C658.1 ; v1(77.96,82.39) C659.1 ; C659.3 v1(77.16,81.59) ; v1(78.76,83.19) C658.3
  BOTTOM w0.305: 80.37,83.19 80.85,82.7 81.28,82.7 C448.1 ; 80.37,83.19 80.61,83.19 C441.1 ; 80.37,83.19 v1(80.36,83.19) ; C477.1 76.96,79.47 76.96,79.39 v1(77.16,79.19) ; v1(74.76,81.59) 74.86,81.7 C661.1 ; v1(73.96,82.39) 74.05,82.39 C661.3 ; v1(73.16,81.59) 73.02,81.59 C460.1 ; C462.1 76.08,81.07 v1(76.36,80.79) 75.94,80.38 75.86,80.38 ; C662.3 73.2,77.63 v1(73.16,77.59) ; v1(78.76,77.59) 78.77,77.58 C494.1 ; C662.1 74.72,77.63 v1(74.76,77.59) ; v1(73.16,83.19) 72.99,83.02 C445.1 ; C657.1 74.46,79.49 v1(74.76,79.19) 74.76,79.28 C663.3 ; C657.3 73.16,79.4 v1(73.16,79.19)
  BOTTOM w0.508: 77.16,79.8 77.07,79.72 77.06,79.72 76.93,79.59 C477.1 ; 77.16,79.8 v1(77.16,79.19) ; 77.16,79.8 C468.1 ; v1(52.04,76.85) 52.35,76.85 53.6,78.1 FL14.2
  vias: v1(42.7,78.11) v1(42.7,77.1) v1(42.7,76.08) v1(43.72,78.11) v1(43.72,77.1) v1(43.72,76.08) v1(44.74,78.11) v1(44.74,77.1) v1(44.74,76.08) v1(45.75,78.11) v1(45.75,77.1) v1(45.75,76.08) v1(46.58,77.08) v1(46.77,78.11) v1(46.77,76.08) v1(46.77,75.06) v1(47.78,78.11) v1(47.78,77.1) v1(47.78,76.08) v1(47.78,75.06) v1(48.8,77.1) v1(48.8,76.08) v1(48.8,75.06) v1(90.94,80.77) v1(90.94,80.26)
VDD_CORE_ALERT: length 3.1
  BOTTOM w0.191: U113.A3 37.53,67.01 37.13,66.61 U114.3 R586.1
VDD_CORE_N: length 6.6
  BOTTOM w0.191: R572.1 37.24,72.7 37.39,72.56 C524.2 37.39,71.28 37.36,71.25 ; U114.9 37.63,70.99 37.36,71.25 ; U113.D2 U113.D1 36.73,68.71 37.13,69.11 U114.8 37.13,71.02 37.36,71.25
VDD_CORE_P: length 5.1
  BOTTOM w0.191: R571.1 38.5,72.08 C524.1 38.37,71.46 38.13,71.22 38.13,70.13 U114.10 38.13,69.13 U113.D3
VDD_LPDDR4: length 124.6
  TOP w0.102: U58.U8 78.81,62.35 v1(78.81,63.23) ; 72.44,65.71 72.31,65.58 72.31,63.96 U58.F10 72.31,63.31 72.31,62.35 U58.F8
  TOP w0.254: U58.H8 73.28,61.59 ; v1(80.46,65.85) 80.43,65.83 U58.W12 ; U58.AB4 v1(82.06,58.43) U58.AA3 ; U58.AB4 82.73,58.48 ; U58.AB4 82.71,59.16 ; v1(80.68,61.41) 80.43,61.66 U58.W8 ; v1(77.69,55.81) 77.83,55.96 U58.R1 ; U58.B8 v1(69.71,61.63) ; U58.AB9 82.73,62.48 ; U58.AB9 v1(82.06,63.23) U58.AA10 ; U58.AB9 82.71,63.16 ; U58.K3 75.04,58.03 v1(75.09,58.07) ; v1(76.03,58.07) 76.07,58.03 U58.N3 ; U58.W1 80.43,55.82 v1(80.44,55.81) ; U58.K1 74.58,55.94 v1(74.71,55.81) ; U58.W5 80.43,60.06 v1(80.62,60.25) ; U58.U5 79.13,59.86 78.87,60.13 v1(78.87,60.25) ; U58.U8 79.13,61.42 v1(79.14,61.41) ; U58.U3 v1(78.81,57.63) ; v1(71.86,61.48) 71.86,61.91 U58.F8 ; v1(77.86,66.46) 77.85,66.46 77.83,66.45 U58.R12 ; U58.D8 70.56,61.91 v1(70.56,61.48) ; U56.22 v1(50.49,61.83) ; v1(81.66,60.25) 81.73,60.18 U58.AA5 ; v1(71.97,60.23) 71.98,60.21 U58.F5 ; U58.D12 70.68,65.74 v1(70.73,65.79) ; U58.A9 68.4,63.17 ; U58.A9 68.41,62.51 ; U58.A9 v1(69.06,63.23) U58.B10 ; U58.N1 v1(76.21,55.81) ; U58.B3 v1(69.06,57.63) ; U58.AA8 81.73,61.48 v1(81.66,61.41) ; 73.28,59.87 U58.H5 ; U58.R8 77.83,61.59 ; U58.N10 v1(76.21,63.86) ; U58.K12 74.86,65.5 74.86,65.82 v1(74.89,65.85) ; U58.D5 v1(70.36,60.03) ; v1(73.16,55.81) 73.28,55.94 U58.H1 ; U58.U10 v1(78.81,63.23) ; U58.F3 v1(71.66,57.63) ; U58.H12 73.28,65.83 v1(73.26,65.85) ; U58.K10 v1(74.91,63.86) ; U58.F10 v1(71.66,63.23) ; v1(69.38,60.25) U58.B5 U58.A4 v1(68.41,59.23) ; U58.N12 v1(76.53,65.66) ; U58.R5 v1(77.83,60.18)
  TOP w0.305: v1(76.03,67.71) 75.98,67.66 C664.3 ; U47.AB2 v1(84.36,71.99) ; v1(74.33,67.71) 74.38,67.66 C664.1 ; v1(80.46,65.85) 80.51,65.91 C239.1 ; v1(65.46,59.63) R315.1 ; v1(70.73,65.79) 70.5,66.02 C238.1 ; U58.D1 70.68,55.88 v1(70.47,55.67) ; U47.AA1 v1(83.56,71.19) ; U47.A2 v1(66.76,71.99) ; v1(65.46,62.03) R312.1 ; U47.B1 v1(67.56,71.19)
  TOP w0.356: v1(74.76,75.99) U47.L7 75.35,76.58 75.35,77 U47.L8 75.35,77.38 75.77,77.38 U47.M8 v1(76.36,76.79) U47.N7 v1(77.16,75.99) ; U47.K8 v1(73.96,76.79) U47.J7 v1(73.16,75.99) ; U47.P8 v1(77.96,76.79)
  L04_PWR1 w0.102: v1(50.49,61.83) 50.75,61.57
  L04_PWR1 w0.152: 50.75,61.57 58.5,61.57 61,64.06 61,71.37 61.64,72.01 61.64,72.97 62.88,74.22 63.27,74.22 66.25,77.19 U47.P8 v1(77.96,76.79)
  L04_PWR1 w0.457: v1(76.36,76.79) v1(77.16,75.99) v1(77.96,76.79) ; v1(73.16,75.99) v1(73.96,76.79) v1(74.76,75.99)
  BOTTOM w0.254: v1(76.03,58.07) 75.97,58.14 C573.1 75.15,58.14 v1(75.09,58.07) ; C665.3 76.16,76.79 v1(76.36,76.79) v1(77.16,75.99) ; C670.1 v1(84.36,71.99) ; C668.1 v1(77.96,76.79) ; v1(76.21,63.86) 76.4,64.05 C548.1 ; C666.3 73.71,75.44 v1(73.16,75.99) v1(73.96,76.79) ; C540.1 74.75,65.99 v1(74.89,65.85) ; C665.1 75.18,75.99 v1(74.76,75.99) 74.76,75.3 C666.1 ; v1(69.06,57.63) 69.06,57.57 69.03,57.54 69.03,57.39 C579.1 ; C670.3 v1(83.56,71.19)
  BOTTOM w0.305: v1(70.73,65.79) 70.73,65.68 C544.1 ; v1(73.26,65.85) 73.04,65.63 C545.2 ; C566.1 71.97,59.99 v1(71.97,60.23) ; 66.65,71.79 66.65,71.88 v1(66.76,71.99) 66.04,71.99 C526.1 ; v1(81.66,60.25) 81.83,60.42 C563.1 81.83,61.24 v1(81.66,61.41) ; C522.1 84.48,72.11 v1(84.36,71.99) ; C556.1 69.48,61.86 v1(69.71,61.63) ; v1(68.41,59.23) 68.1,59.54 C567.1 ; v1(80.62,60.25) 80.5,60.38 C564.1 80.5,61.22 v1(80.68,61.41) ; C558.1 71.86,61.71 v1(71.86,61.48) ; v1(77.83,60.18) 77.57,59.91 C569.1 ; C584.2 69.33,55.88 v1(69.54,55.67) C590.1 ; C542.1 77.9,66.42 v1(77.86,66.46) ; C570.1 70.18,59.85 v1(70.36,60.03) ; v1(74.91,63.86) 74.68,63.86 C549.1 ; v1(82.06,63.23) 82.2,63.37 C552.1 ; v1(78.81,57.63) 79.07,57.37 C580.1 ; v1(67.56,71.19) 67.45,71.08 ; 67.45,71.08 C669.1 ; 67.45,71.08 67.4,71.04 67.4,70.45 C531.1 ; v1(69.38,60.25) 69.31,60.18 C568.1 ; v1(80.44,55.81) 80.51,55.74 C586.1 ; v1(70.47,55.67) 70.56,55.75 C585.1 ; C595.1 v1(80.62,54.91) ; v1(76.21,55.81) 76.25,55.77 C587.2 ; C582.1 73.1,55.86 v1(73.16,55.81) ; C553.1 68.86,63.03 v1(69.06,63.23) ; C577.1 82.2,58.28 v1(82.06,58.43) ; v1(70.56,61.48) 70.56,61.7 C557.1 ; v1(73.61,54.99) 73.66,54.95 73.66,54.44 R595.2 ; C550.1 79.07,63.49 v1(78.81,63.23) ; R594.2 77.12,54.79 77.69,55.35 v1(77.69,55.81) 77.8,55.92 C583.1 ; v1(78.87,60.25) 78.87,60.38 79.06,60.57 C562.1 79.06,61.33 v1(79.14,61.41) ; v1(74.71,55.81) 74.74,55.78 C589.1 ; v1(76.53,65.66) 76.65,65.78 C541.2 ; C530.1 83.68,71.07 v1(83.56,71.19)
  BOTTOM w0.381: v1(86.72,58.6) 87.05,58.93 R589.2
  vias: v1(64.79,55.95) v1(64.79,55.03) v1(64.79,54.12) v1(65.7,55.95) v1(65.7,55.03) v1(65.7,54.12)
VDD_LPDDR4_ALERT: length 3
  BOTTOM w0.191: U121.A3 53.62,42.99 53.22,42.59 U122.3 R619.1
VDD_LPDDR4_N: length 8.2
  BOTTOM w0.191: 53.48,47.54 53.22,47.28 U122.8 53.22,45.43 52.82,45.03 U121.D1 ; 53.48,47.54 C600.2 53.48,49.22 R599.1 ; 53.48,47.54 53.72,47.3 U122.9 53.72,45.39 53.22,44.89 U121.D2
VDD_LPDDR4_P: length 5.1
  BOTTOM w0.191: R600.1 54.8,48.85 54.46,48.51 C600.1 54.47,48.02 54.47,47.33 54.22,47.08 U122.10 54.22,45.3 53.62,44.7 U121.D3
VDD_MMC1_SD:
  vias: v1(15.98,155.87) v1(15.98,155.36)
VDDA1V8: length 34.9
  TOP w0.254: 50.3,60.33 U56.19 ; R316.2 55.41,57.29 56.06,56.64 56.06,55.96 56.47,55.55 v1(58.07,55.55)
  TOP w0.381: v1(67.59,34.58) C290.1 FL10.2
  L05_SIG02 w0.381: v1(67.59,34.58) 67.6,34.58 69.38,36.36 69.38,43.61 59.06,53.93 59.06,54.55 v1(58.07,55.55)
VDDA_1V8: length 9.1
  TOP w0.305: C198.1 v1(89.29,84.88) ; v1(89.59,83.9) 89.59,83.61 89.89,83.3 C202.1 ; v1(92.11,84.47) 91.7,84.88 C198.3
  TOP w0.356: U47.L10 v1(74.76,78.39) ; U47.G18 v1(71.56,85.59) ; U47.T10 v1(79.56,78.39) ; U47.P16 v1(77.96,83.99)
  BOTTOM w0.254: v1(89.59,83.9) 89.89,83.9 90.16,83.62 C442.3 ; C431.1 89.7,84.47 v1(89.29,84.88) 89.65,85.23 C423.1 ; C442.1 v1(91.84,83.35)
  BOTTOM w0.305: v1(71.56,85.59) 71.44,85.47 C424.1 ; C486.1 79.54,78.41 v1(79.56,78.39) ; v1(77.96,83.99) 78.08,83.87 C439.1 ; v1(74.76,78.39) 74.86,78.39 C483.1
  vias: v1(57.94,59.16) v1(57.94,58.33) v1(58.65,59.14) v1(58.64,58.35) v1(90.86,82.11) v1(92.25,78.94) v1(92.26,79.75)
VDDA_1V8_ALERT: length 3.1
  BOTTOM w0.191: U119.A3 59.09,47.92 58.69,47.52 U118.3 R608.1
VDDA_1V8_FB1: length 10.9
  TOP w0.254: U47.K13 v1(73.96,81.59) ; U47.N9 v1(77.16,77.59) ; U47.J10 v1(73.16,78.39) ; U47.M13 v1(76.36,81.59) ; U47.K10 v1(73.96,78.39) ; U47.R11 v1(78.76,79.19)
  L06_PWR2 w0.152: v1(76.36,81.59) 76.36,81.59 75.96,81.99 74.36,81.99 v1(73.96,81.59) 73.98,81.59 74.38,81.19 U47.M13 v1(76.36,81.59)
  BOTTOM w0.305: v1(77.16,77.59) 77.03,77.59 C501.1 ; C456.1 v1(73.96,81.59) ; v1(73.16,78.39) C485.1 73.46,78.39 v1(73.96,78.39) ; C480.1 78.64,79.31 v1(78.76,79.19) ; C459.1 v1(76.36,81.59)
  vias: v1(88.01,80.32) v1(88.54,80.37)
VDDA_1V8_FB2: length 8.8
  TOP w0.356: U47.T12 v1(79.56,80.79)
  L06_PWR2 w0.381: v1(86.8,80.71) 86.35,80.25 80.1,80.25 v1(79.56,80.79)
  BOTTOM w0.254: C467.1 79.68,80.67 v1(79.56,80.79)
VDDA_1V8_FB_OSC: length 2
  TOP w0.305: C219.1 v1(59.82,73.36)
  TOP w0.356: U47.J8 v1(73.16,76.79)
  TOP w0.381: FL9.2 v1(59.82,73.36)
  BOTTOM w0.305: C508.1 v1(73.16,76.79)
VDDA_1V8_N: length 21.2
  TOP w0.191: v1(56.45,63.53) 56.66,63.32 R311.1
  L03_SIG01 w0.076: v1(57.67,56.18) 57.67,56.34 57.24,56.77 57.24,63.91 57.03,64.12 56.37,64.12 56.19,63.94 56.19,63.83 56.45,63.56 v1(56.45,63.53)
  BOTTOM w0.191: U119.D2 58.69,49.82 59.19,50.32 U118.9 59.19,52.04 58.96,52.26 ; U119.D1 58.29,49.96 58.69,50.36 U118.8 58.69,51.99 58.96,52.26 ; 58.96,52.26 58.95,52.28 C597.2 58.95,55.39 58.3,56.04 57.81,56.04 v1(57.67,56.18)
VDDA_1V8_P: length 19.3
  TOP w0.191: R310.1 55.51,63.4 v1(55.65,63.53)
  L03_SIG01 w0.076: v1(55.65,63.53) 55.94,63.83 55.94,63.98 56.35,64.39 57.05,64.39 57.42,64.02 57.42,56.99 57.9,56.51 58.43,56.51 v1(58.47,56.47)
  BOTTOM w0.191: U119.D3 59.09,49.63 59.69,50.23 U118.10 59.69,52.07 59.93,52.31 C597.1 59.48,53.41 59.48,55.53 58.54,56.47 v1(58.47,56.47)
VDDA_CORE_CSI: length 11
  TOP w0.254: 88.36,79.36 88.39,79.38 FL7.2 89.29,79.38
  TOP w0.356: U47.T11 v1(79.56,79.19)
  L06_PWR2 w0.381: v1(79.56,79.19) 80.08,79.72 86.57,79.72 v1(86.8,79.48)
  BOTTOM w0.254: C475.1 v1(86.8,79.48) C474.1 ; C472.1 79.29,79.46 v1(79.56,79.19)
  BOTTOM w0.305: C479.1 79.68,79.31 v1(79.56,79.19)
VDDA_CORE_USB: length 13.3
  TOP w0.254: v1(88.37,78.06) 88.46,77.98 88.78,77.98 89.16,77.6 89.21,77.6 89.29,77.53
  TOP w0.356: U47.T9 v1(79.56,77.59)
  L04_PWR1 w0.165: 84.52,77.99 79.96,77.99 v1(79.56,77.59) 79.96,77.19 84.87,77.19
  BOTTOM w0.254: C487.1 C497.1
  BOTTOM w0.305: v1(79.56,77.59) 79.58,77.61 C495.1
VDDA_DDR_PLL0: length 22.7
  TOP w0.305: C211.1 v1(60.12,78.31) C212.1
  TOP w0.356: U47.M9 v1(76.36,77.59)
  L06_PWR2 w0.165: 67.04,77.99 75.33,77.99 75.73,77.59 v1(76.36,77.59) 75.16,78.79 67.75,78.79 67.42,78.46
  BOTTOM w0.305: v1(76.36,77.59) 75.95,77.59 C491.1
  BOTTOM w0.508: v1(60.12,78.31) 59.11,78.31 58.9,78.1
VDDA_LM5141: length 2.8
  BOTTOM w0.254: v1(17.96,25.53) C625.2 v1(18.64,24.87) ; U128.19 17.25,20.7 v1(17.07,20.53) ; U128.5 v1(20.41,24.51)
VDDA_SYS_MON: length 16
  TOP w0.191: U47.H12 v1(72.36,80.79)
  BOTTOM w0.132: v1(72.36,80.79) 71.96,80.4 71.67,80.4 71.23,79.95
  BOTTOM w0.14: 71.23,79.95 65.53,79.95 64.51,80.98 63.79,80.98
  BOTTOM w0.191: R543.2 R545.1 60.9,82.71 60.98,82.62 C449.2 62.04,82.62 62.17,82.49 62.17,81.59 62.78,80.98 63.79,80.98
VDDC_1V2: length 21.5
  TOP w0.203: v1(119.09,74.5) U48.87 ; U48.115 126.6,68.35
  TOP w0.254: 126.6,68.35 C233.1 C240.1 126.6,65.98 v1(126.81,65.77)
  L05_SIG02 w0.381: v1(126.81,65.77) 126.81,67.9 125.91,68.8 119.7,68.8 118.58,69.92 118.58,73.8 119.09,74.3 v1(119.09,74.5)
  BOTTOM w0.254: v1(119.09,74.5) 119.07,74.48 C516.2
VDDIM: length 3.9
  TOP w0.081: 98.6,72.97 U49.C2 98.1,72.97 98.1,72.41 v1(98.35,72.16) 98.6,72.41 98.6,72.97
  BOTTOM w0.254: C521.1 v1(98.35,72.16) 98.14,71.95 C527.1
VDDR_CORE: length 47.4
  TOP w0.254: v1(57.9,68.97) 57.9,69.44 58.15,69.69 TP60.1 ; C214.1 v1(53.74,74.33)
  TOP w0.305: C214.3 v1(53,76.62)
  TOP w0.356: U47.M14 v1(76.36,82.39) ; U47.P9 v1(77.96,77.59) ; U47.J14 v1(73.16,82.39) ; U47.P12 v1(77.96,80.79) ; U47.K12 v1(73.96,80.79) ; U47.M10 v1(76.36,78.39)
  TOP w0.508: R272.1 v1(25.8,73.08)
  L05_SIG02 w0.381: v1(53,76.62) 53.41,76.62 53.82,76.21 53.82,74.41 v1(53.74,74.33)
  L06_PWR2 w0.152: 74.56,80.29 74.06,80.79 v1(73.96,80.79) 73.9,80.79 73.46,81.24 73.37,81.24 73.32,81.19 ; v1(76.36,82.39) 76.23,82.39 75.8,82.83
  BOTTOM w0.191: C481.1 v1(64.94,79.08)
  BOTTOM w0.254: C481.3 63.13,78.79 v1(63.13,78.54)
  BOTTOM w0.305: v1(76.36,82.39) 76.48,82.51 C447.1 ; v1(77.96,80.79) 78.08,80.67 C466.1 ; v1(76.36,78.39) 76.36,78.26 C490.1 ; C505.1 53.52,76.62 v1(53,76.62) ; C465.1 v1(73.96,80.79) ; C493.1 v1(77.96,77.59)
  BOTTOM w0.381: v1(53.74,74.33) 53.74,73.63 52.9,72.79 43.02,72.79 39.62,76.19 36.56,76.19 35.63,75.26 29.6,75.26 29.06,74.72 26.49,74.72 25.8,74.03 v1(25.8,73.08)
  vias: v1(57.19,68.99) v1(57.21,68.36) v1(57.9,68.37)
VDDR_CORE_ALERT: length 3.1
  BOTTOM w0.191: U115.A3 56.46,56.6 56.06,56.2 U116.3 R596.1
VDDR_CORE_N: length 12.4
  BOTTOM w0.191: 56.3,60.95 56.56,60.68 U116.9 56.56,58.88 56.06,58.38 U115.D2 ; 56.3,60.95 56.06,60.71 U116.8 56.06,58.87 55.66,58.47 U115.D1 ; 56.3,60.95 56.32,60.97 C559.2 56.32,62.17 59.17,65.02 59.17,65.4 R585.1
VDDR_CORE_P: length 9.2
  BOTTOM w0.191: U115.D3 56.72,58.15 57.06,58.49 U116.10 57.06,60.75 57.3,60.99 C559.1 57.3,62.53 59.55,64.78 59.55,65.41 R584.1
VDDSHV_SDIO: length 128.1
  TOP w0.254: 17.56,151.89 17.56,153.2 17.44,153.31 R65.2
  TOP w0.305: 20.92,152.79 21.69,152.79 22.5,153.6 R66.2 22.49,154.21 R64.2 22.5,155.14 R55.2 ; R54.2 R57.2 R65.2
  TOP w0.381: 52.78,83.39 C201.1 ; 52.78,83.39 52.07,83.39 v1(52.05,83.37) ; 52.78,83.39 R243.1
  L05_SIG02 w0.381: v1(20.91,150.41) v1(20.47,149.97) 15.07,149.97 11.3,146.2 11.3,88 v1(11.51,87.79)
  BOTTOM w0.381: v1(52.05,83.37) 51.36,82.68 51.36,82.48 48.45,79.58 44.65,79.58 40.68,83.54 40.68,84.86 40.68,85.54 38.59,87.63 28.4,87.63 28.06,87.29 27.42,87.29 26.92,87.79 v1(11.51,87.79)
VDDSHV_SDIO_EN: length 41.2
  TOP w0.191: v1(17.86,160.92) 17.11,161.67 17.11,162.81 17.97,163.67 R19.1 ; U19.2 29.53,144.3 29.34,144.11 v1(27.37,144.11) ; v1(16.5,144.79) 16.5,145.08 15.81,145.78 U16.3
  L03_SIG01 w0.076: v1(16.5,144.79) 16.5,147.28 17.32,148.1 17.32,149.88 19.37,151.92 19.37,159.41 v1(17.86,160.92)
  BOTTOM w0.191: v1(16.5,144.79) 16.5,143.73 17.89,142.35 25.6,142.35 v1(27.37,144.11)
VINT_LDO: length 3.2
  TOP w0.14: TP74.1 42.07,61.79 C249.1
  TOP w0.254: TP74.1 42.78,61.53 42.99,61.33 U56.7
1588_SFD_1: length 4.3
  TOP w0.191: TP93.1 90.14,45.72 90.14,43.5 90.41,43.24 J18.38
1588_SFD_2: length 17
  TOP w0.191: J19.38 122.84,43.51 122.54,43.81 v1(122.51,43.81) ; TP87.1 127.61,48.35 v1(128.05,48.35)
  L03_SIG01 w0.076: v1(128.05,48.35) 126.55,46.85 126.55,43.62 125.31,42.39 121.19,42.39 120.84,42.74 120.84,43.37 121.27,43.81 v1(122.51,43.81)
ADCIN1: length 3.7
  BOTTOM w0.14: R681.1 40.68,14.35 40.98,14.65 40.98,15.38 40.84,15.52 R679.2 40.29,15.78 40.29,16.21 40.65,16.57 U129.6
ADCIN2: length 3.1
  BOTTOM w0.14: U129.10 39.05,16.03 39.21,15.88 R678.2 39.21,14.99 39.41,14.79 R682.1
ADDR0_IO_EXP: length 1.6
  TOP w0.191: R107.1 104.5,138.83 104.63,138.96 U21.26
ADDR1_IO_EXP: length 1.7
  TOP w0.191: R94.1 80.63,144.29 80.81,144.48 U18.18
AUDIO_EXT_REFCLK0: length 79.5
  L03_SIG01 w0.076: v1(71.43,107.88) 71.43,107.92 71.33,108.02 71.33,109.68 70.71,110.3 70.71,118.18 v1(71.15,118.61) ; v1(54.98,117.82) 54.72,117.56 54.72,115.43 55.96,114.2 55.96,104.81 55.44,104.29 55.44,101.41 58.55,98.31 58.55,90.88 v1(58.56,90.87)
  BOTTOM w0.191: v1(71.15,118.61) 71.08,118.68 69.37,118.68 68.29,119.76 60.78,119.76 59.39,118.37 55.53,118.37 v1(54.98,117.82) ; R538.2 65.99,84.38 59,84.38 58.6,83.99 57.47,83.99 57.29,83.81 55.86,83.81 54.45,85.22 54.45,86.76 58.47,90.78 58.47,90.78 v1(58.56,90.87) ; R470.1 71.57,107.87 71.44,107.87 v1(71.43,107.88)
AUDIO_EXT_REFCLK1: length 21.8
  L03_SIG01 w0.076: v1(72.95,102.83) 72.95,105.17 v1(73.02,105.24)
  BOTTOM w0.191: v1(73.02,105.24) 73,105.24 72.28,105.97 72.28,106.23 70.82,107.69 70.82,108.13 70.99,108.31 R466.1 ; R506.2 72.3,92.35 72.1,92.55 72.1,93.9 74.47,96.27 74.47,97.92 73.96,98.43 72.9,98.43 72.63,98.7 72.63,102.5 v1(72.95,102.83)
AUDIO_EXT_REFCLK1__R: length 7.8
  TOP w0.132: U47.K17 v1(73.96,84.79)
  BOTTOM w0.102: 71.95,88.32 71.95,86.17 72.15,85.97 73.32,85.97 73.54,85.75 73.54,85.21 v1(73.96,84.79)
  BOTTOM w0.191: R506.1 71.95,90.05 71.95,88.32
BOOTMODE0: length 7.1
  L03_SIG01 w0.076: v1(117.68,115.14) 117.19,115.14 116.53,114.49 116.53,113.13 117.09,112.57 117.9,112.57 v1(118.13,112.8)
  BOTTOM w0.191: v1(117.68,115.14) 117.17,114.64 U81.14 ; v1(118.13,112.8) 118.13,112.82 118.41,113.1 RA5.1
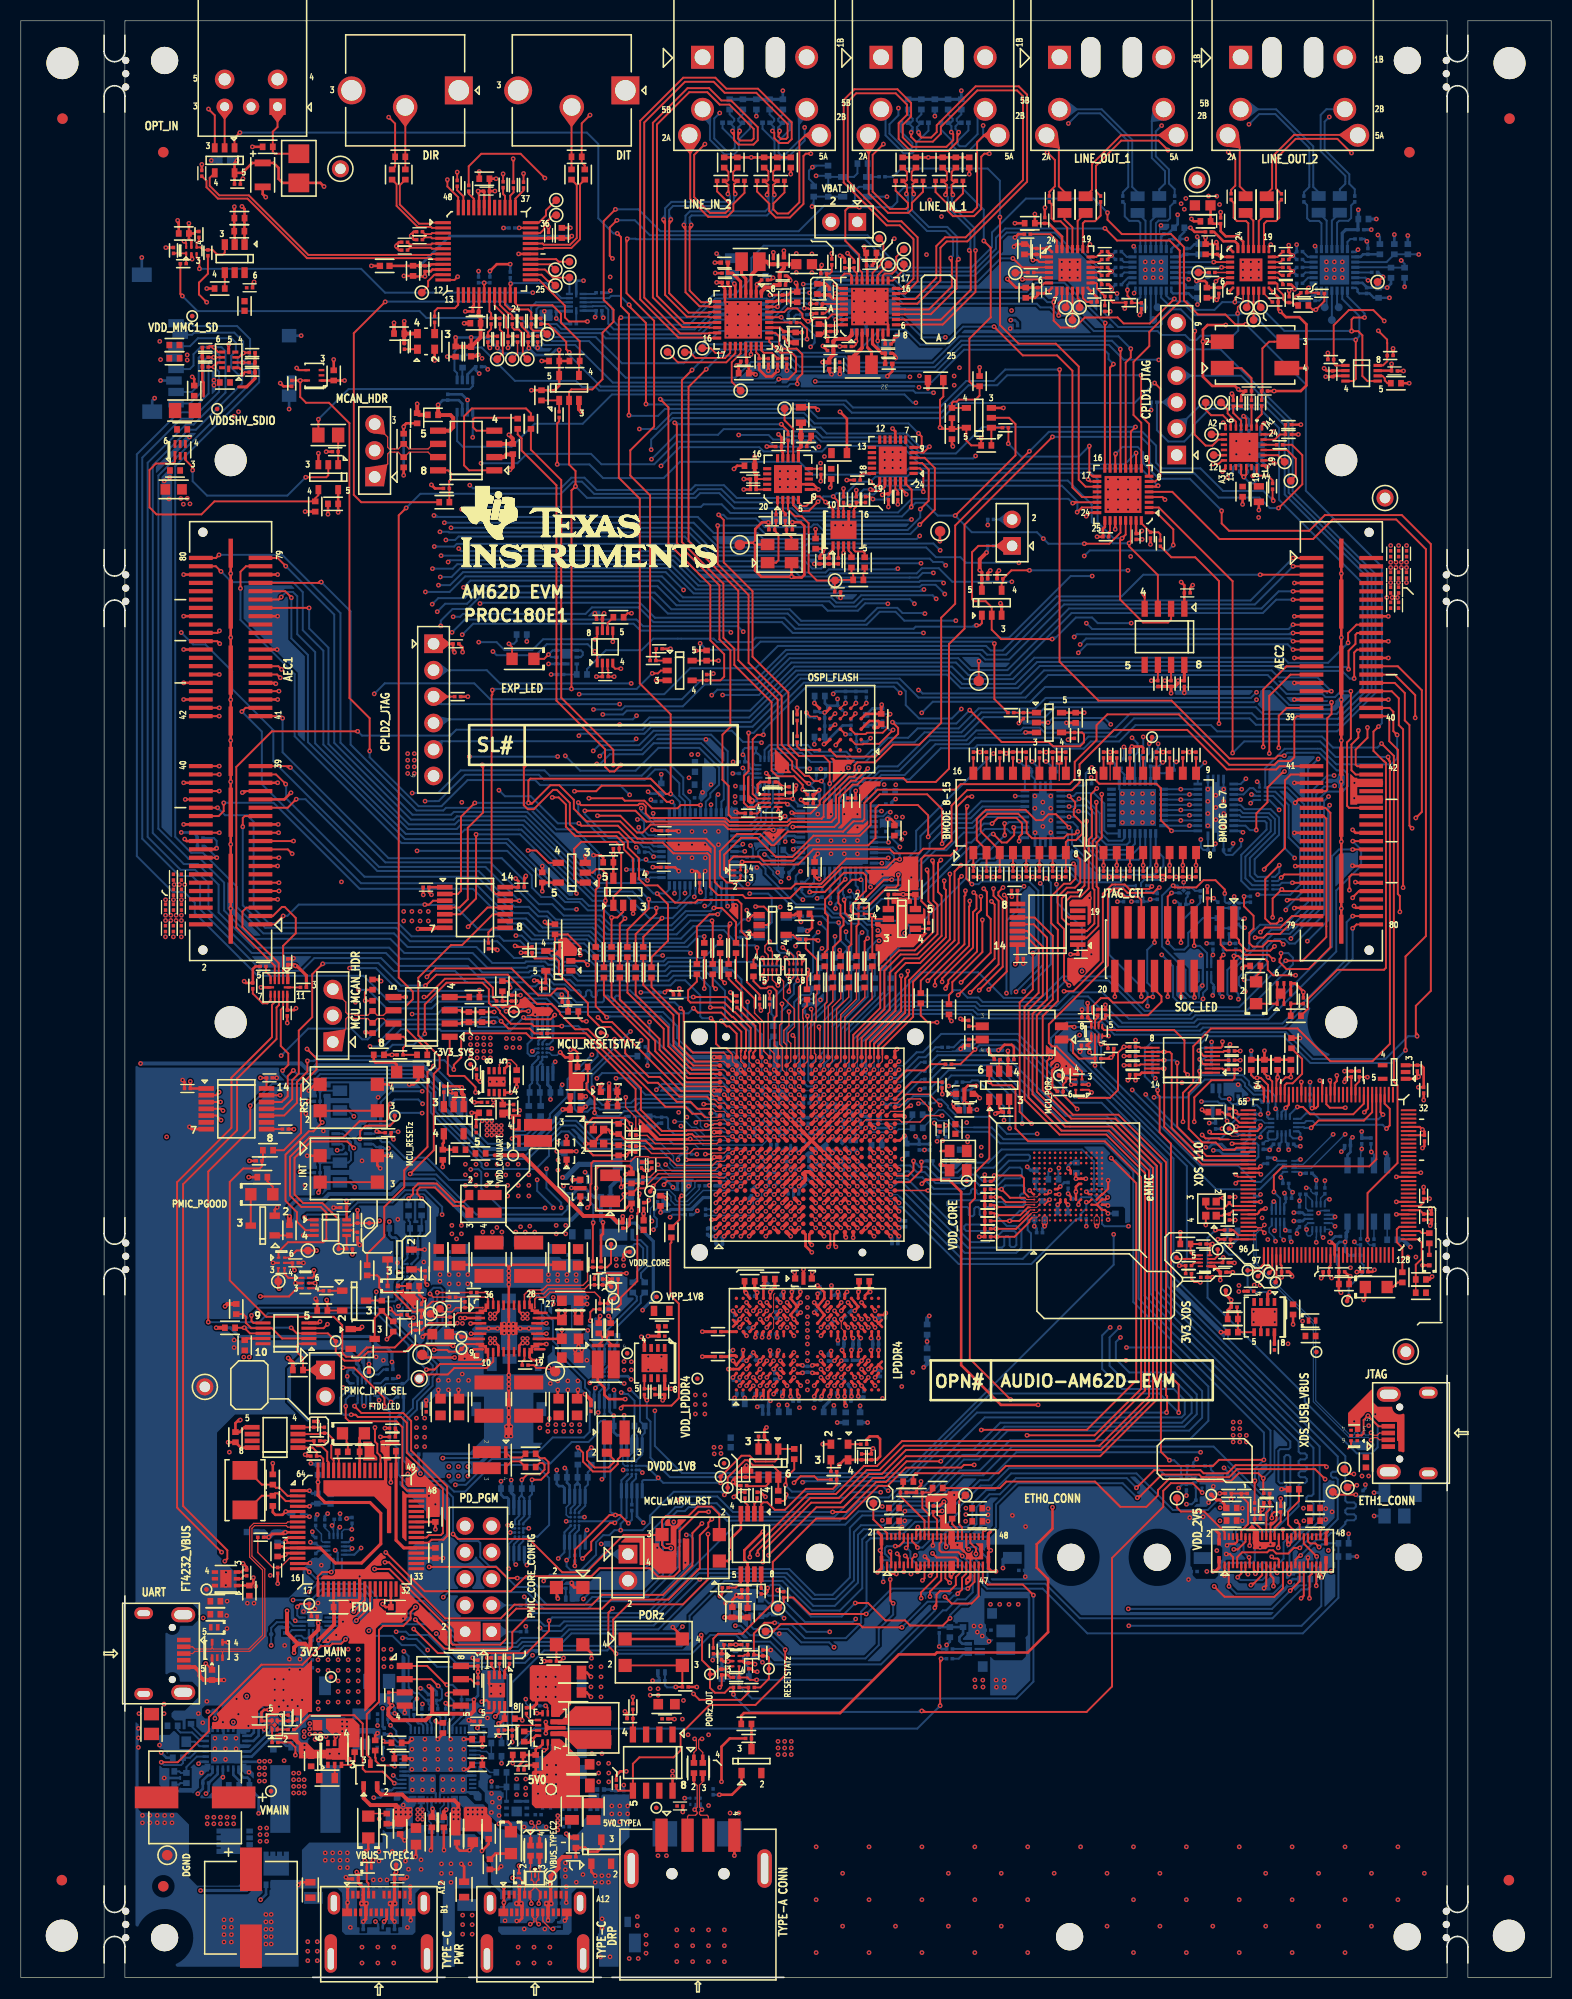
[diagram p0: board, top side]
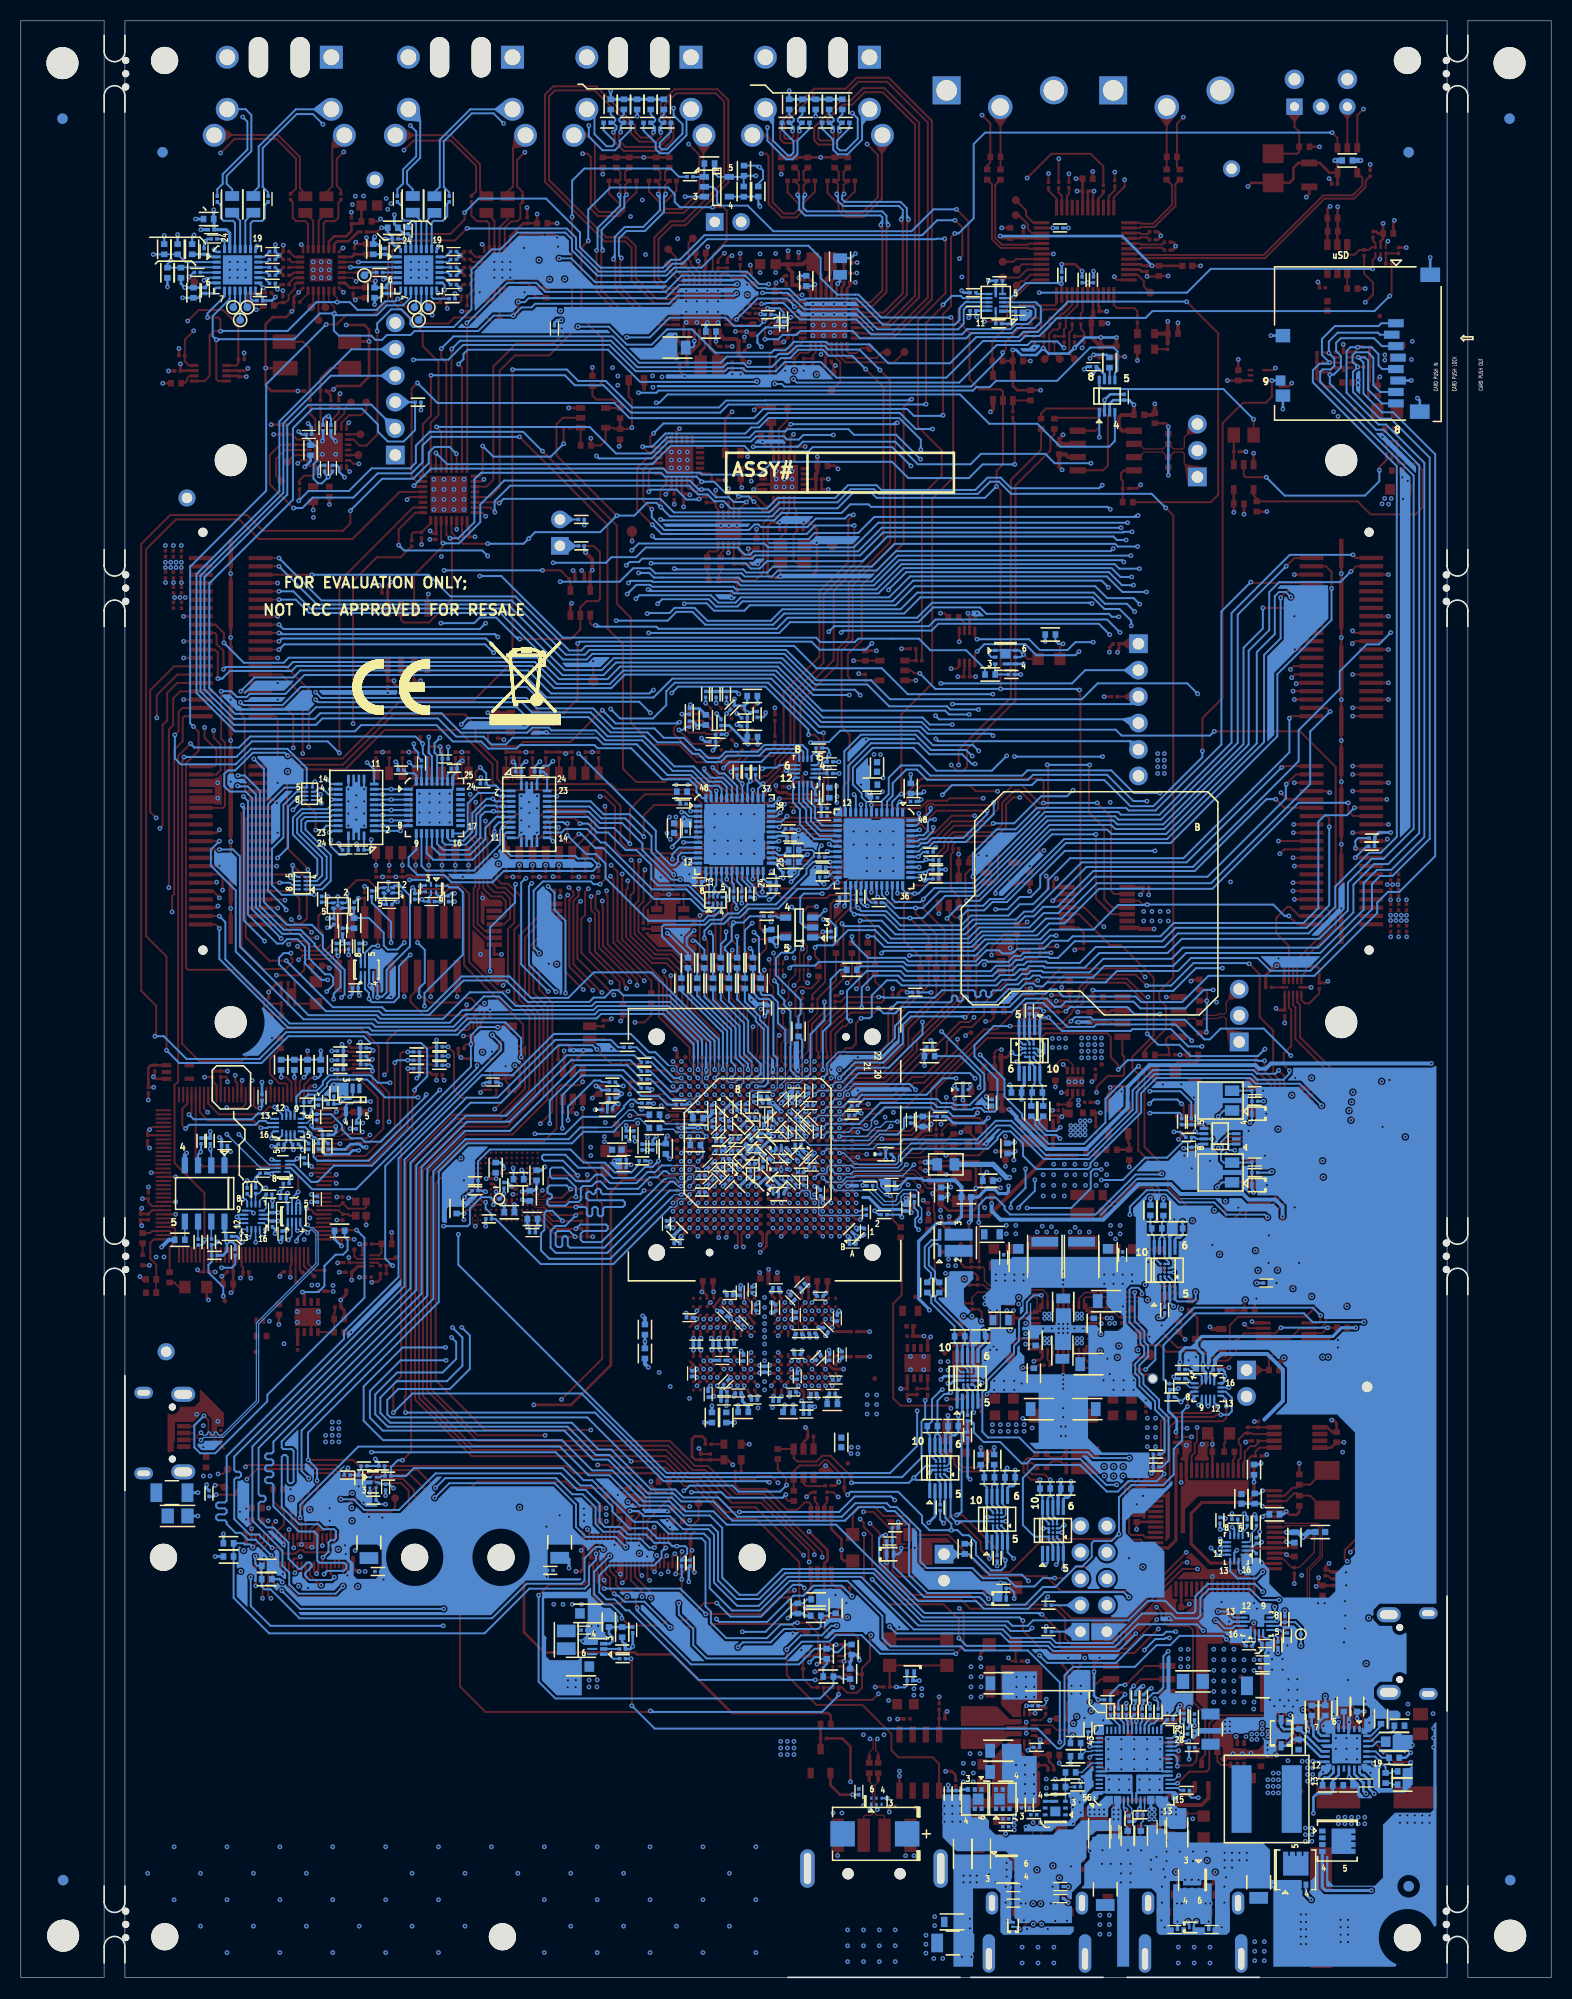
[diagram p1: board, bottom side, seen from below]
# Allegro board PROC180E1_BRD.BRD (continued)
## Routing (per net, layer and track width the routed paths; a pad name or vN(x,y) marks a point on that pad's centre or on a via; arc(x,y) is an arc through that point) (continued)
BOOTMODE1: length 2.7
  L03_SIG01 w0.076: v1(117.27,114.14) 117.7,114.14 v1(118.2,113.64)
  BOTTOM w0.191: U81.15 v1(117.27,114.14) ; RA5.2 118.34,113.5 v1(118.2,113.64)
BOOTMODE2: length 2.9
  BOTTOM w0.191: RA5.3 118.73,113.9 118.39,114.24 118.05,114.24 117.44,113.64 U81.16
BOOTMODE3: length 4.8
  L03_SIG01 w0.076: v1(117.17,113.14) 116.86,113.45 116.86,114.32 117.14,114.6 118.5,114.6 v1(118.76,114.86)
  BOTTOM w0.191: v1(118.76,114.86) 118.98,114.64 RA5.4 ; U81.17 v1(117.17,113.14)
BOOTMODE4: length 12.5
  BOTTOM w0.191: RA6.4 118.8,105.72 118.52,106 118.52,107.42 120.86,109.76 120.86,111.42 120.05,112.23 117.56,112.23 117.14,112.64 U81.18
BOOTMODE5: length 12.6
  BOTTOM w0.191: U81.19 117.1,112.14 117.4,111.84 119.89,111.84 120.46,111.28 120.46,109.93 118.05,107.52 118.05,105.85 118.59,105.32 RA6.3
BOOTMODE6: length 12.7
  BOTTOM w0.191: U81.20 117.07,111.64 117.24,111.46 119.74,111.46 120.06,111.14 120.06,110.1 117.63,107.66 117.63,105.58 118.29,104.92 RA6.2
BOOTMODE7: length 12.6
  BOTTOM w0.191: RA6.1 118.05,104.52 117.23,105.34 117.23,107.83 119.66,110.26 119.66,110.9 119.48,111.08 117.08,111.08 117.03,111.14 U81.21
BOOTMODE8: length 22.2
  TOP w0.191: v1(95.89,109.14) 95.89,109.57 96.17,109.85 96.17,110.85 95.63,111.39 93.84,111.39 v1(93.29,110.84)
  BOTTOM w0.191: U83.14 96.22,109.48 v1(95.89,109.14) ; v1(93.29,110.84) 92.5,110.84 91.65,109.98 90.59,109.98 88.89,108.29 87.87,108.29 86.43,106.85 86.43,105.53 85.81,104.91 82.86,104.91 81.18,103.22 RA7.1
BOOTMODE9: length 19.5
  BOTTOM w0.191: U83.15 95.06,109.98 94.72,110.32 92.6,110.32 91.3,109.02 90.88,109.02 86.38,104.52 83.07,104.52 82.2,103.64 82.18,103.64 81.34,102.8 80.67,102.8 80.51,102.96 80.51,102.97 80.48,103 RA7.2
BOOTMODE10: length 21.5
  TOP w0.191: v1(95.37,110.48) 95.38,110.48 95.42,110.44 95.42,109.73 94.71,109.02 94.23,109.02 v1(93.41,109.84)
  BOTTOM w0.191: v1(93.41,109.84) 93.39,109.82 93.16,109.82 91.83,108.49 91.07,108.49 86.18,103.6 82.68,103.6 81.49,102.42 80.46,102.42 80.08,102.79 RA7.3 ; v1(95.37,110.48) 95.38,110.48 95.38,110.48 U83.16
BOOTMODE11: length 23.2
  TOP w0.191: v1(94.5,110.85) 94.5,109.73 v1(94.51,109.72)
  BOTTOM w0.191: v1(94.5,110.85) 94.78,110.85 94.9,110.98 U83.17 ; v1(94.51,109.72) 92.7,107.91 91.75,107.91 90.84,106.99 90.84,105.62 86.71,101.5 81.45,101.5 80.97,101.98 80.33,101.98 79.68,102.63 RA7.4
BOOTMODE12: length 41.7
  TOP w0.191: RA1.2 68.13,105.85 67.56,106.42 67.56,107.85 69.17,109.46 70.71,109.46 72.54,107.63 74.11,107.63 76.15,109.67 80.6,109.67 81.63,110.71 81.63,112.78 82.5,113.65 87.06,113.65 88.49,112.21 v1(88.49,108.9)
  BOTTOM w0.191: U83.18 92.51,111.48 91.44,110.42 90.01,110.42 v1(88.49,108.9)
BOOTMODE13: length 20.4
  TOP w0.191: v1(83.66,105.45) 82.93,105.45 80.47,102.99 RA2.2
  BOTTOM w0.191: U83.19 92.44,111.98 91.36,110.9 89.26,110.9 87.29,108.93 87.29,108.29 84.45,105.45 v1(83.66,105.45)
BOOTMODE14: length 37.6
  TOP w0.191: v1(87.16,109.56) 87.16,111.63 86.16,112.62 82.42,112.62 82.1,112.3 82.1,109.45 81.4,108.75 75.71,108.75 74.23,107.27 71.34,107.27 70.95,107.66 68.46,107.66 68.05,107.26 68.05,106.54 68.24,106.35 RA1.1
  BOTTOM w0.191: U83.20 92.37,112.48 91.24,111.34 88.94,111.34 v1(87.16,109.56)
BOOTMODE15: length 21.2
  TOP w0.191: RA2.1 81.18,102.71 83.18,104.71 84.03,104.71 84.28,104.95 v1(84.28,105.93)
  BOTTOM w0.191: U83.21 92.26,112.98 91.03,111.74 88.52,111.74 86.42,109.64 86.42,108.06 v1(84.28,105.93)
BOOTMODE_I2C_EN: length 1.7
  BOTTOM w0.14: U107.5 R578.1
BOOTMODE_I2C_SCL: length 93.8
  TOP w0.191: TP71.1 127.4,65.28 v1(127.55,65.44)
  L03_SIG01 w0.076: v1(125.72,112.61) 124.8,112.61 123.75,113.66 123.75,117.46 124.26,117.96 128.59,117.96 129.79,119.16 129.79,120.32 129.36,120.75 118.34,120.75 116.76,119.17 v1(107.81,119.17) ; v1(123.58,99.54) 123.58,96.15 122.47,95.05 122.47,87.92 124.24,86.15 124.24,85.47 125.59,84.11 125.59,78.97 128.09,76.47 v1(128.09,70.66)
  BOTTOM w0.14: R579.1 128.38,70.38 v1(128.09,70.66)
  BOTTOM w0.191: v1(107.81,119.17) 107.81,117.62 107.51,117.32 U82.29 ; v1(123.58,99.54) 125.58,101.54 125.58,112.47 v1(125.72,112.61) ; R579.1 R583.2 128.68,68.73 128.98,68.43 128.98,67.73 127.55,66.3 v1(127.55,65.44)
BOOTMODE_I2C_SDA: length 84
  TOP w0.191: v1(130.7,118.52) 131.89,117.34 131.89,86.04 132.24,85.69 132.24,78.23 129.36,75.35 v1(129.36,70.86) ; v1(108.39,118.51) 108.39,118.65 108.66,118.92 TP45.1
  L03_SIG01 w0.076: v1(129.36,70.86) 129.45,70.78 129.45,69.9 v1(127.72,68.17)
  BOTTOM w0.14: R580.1 129.57,70.35 129.36,70.56 v1(129.36,70.86)
  BOTTOM w0.191: v1(130.7,118.52) 130.33,118.14 126.04,118.14 124.98,119.2 109.08,119.2 v1(108.39,118.51) 108.39,117.58 108.01,117.2 U82.30 ; v1(127.72,68.17) 126.73,68.17 126.41,68.5 R582.2
BOOTMODEON: length 97.9
  TOP w0.191: v1(96.89,135.17) 95.15,135.17 R112.2 94.33,134.04 94.21,133.92 U23.4 ; v1(118.68,110.21) 118.68,111.82 119.75,112.9 119.75,114.3 121.3,115.85 v1(121.39,115.85)
  L03_SIG01 w0.076: v1(106.35,135.16) 106.35,133.31 117.56,122.1 130.99,122.1 132.67,120.43 132.67,117.23 127.65,112.22 124.21,112.22 121.39,115.04 v1(121.39,115.85) ; v1(96.89,135.17) 96.91,135.14 96.91,118.42 96.66,118.17 96.66,114.63 v1(95.51,113.48)
  BOTTOM w0.191: U83.22 v1(95.51,113.48) ; U81.22 117.63,110.64 118.06,110.21 v1(118.68,110.21) ; v1(106.35,135.16) 106.34,135.17 v1(96.89,135.17)
BUF_BOOTMODE_I2C0_SCL: length 90.3
  TOP w0.14: U48.82 116.92,76.5 v1(116.7,76.28)
  TOP w0.191: v1(109.89,124.57) R119.2 U25.7
  L03_SIG01 w0.076: v1(126.15,115.46) 130.15,115.46 131.8,117.11 131.8,120.66 130.63,121.83 112.63,121.83 v1(109.89,124.57) ; v1(116.7,76.28) 117.09,76.67 117.09,80.23 116.36,80.96 115.39,80.96 114.9,81.45 114.9,88.13 112.17,90.86 112.17,94.51 112.54,94.88 116.03,94.88 v1(116.96,93.96)
  BOTTOM w0.191: v1(116.96,93.96) 116.96,94.48 116.3,95.14 116.3,96.64 118.78,99.13 118.78,99.3 120.12,100.64 121.74,100.64 124.04,102.93 124.04,114 125.5,115.46 v1(126.15,115.46)
BUF_BOOTMODE_I2C0_SDA: length 89
  TOP w0.14: U48.81 116.92,76.9 v1(116.7,77.12)
  TOP w0.191: v1(108.59,124.57) R118.2 U25.6
  L03_SIG01 w0.076: v1(117.51,95.83) 113.09,95.83 111.86,94.6 111.86,90.88 114.72,88.02 114.72,81.38 115.32,80.78 116.28,80.78 116.85,80.21 116.85,77.64 116.7,77.49 v1(116.7,77.12) ; v1(108.59,124.57) 111.6,121.56 130.42,121.56 131.47,120.5 131.47,118.13 129.82,116.47 126.3,116.47 125.62,115.79 v1(125.62,113.44)
  BOTTOM w0.191: v1(117.51,95.83) 118.13,95.83 119.7,97.4 119.7,98.99 120.45,99.74 121.41,99.74 121.84,99.31 122.39,99.31 125.18,102.11 125.18,113 v1(125.62,113.44)
BUF_BOOTMODE_I2C_SCL: length 9.6
  TOP w0.191: U48.49 125.4,83.88 125.74,83.54 v1(127.23,83.54)
  L03_SIG01 w0.076: v1(127.23,83.54) 127.23,82.07 128.8,80.49 v1(128.8,79.59)
  BOTTOM w0.14: R552.2 v1(128.8,79.59) 128.71,79.49 U107.2
BUF_BOOTMODE_I2C_SDA: length 17.2
  TOP w0.191: v1(124.78,86.15) 125,85.93 U48.50
  L03_SIG01 w0.076: v1(129.72,79.29) 129.86,79.44 129.86,86.95 129.36,87.45 126.07,87.45 v1(124.78,86.15)
  BOTTOM w0.191: U107.3 129.98,79.04 v1(129.72,79.29) 129.69,79.33 R551.2
BUF_TEST_GPIO1: length 15
  TOP w0.191: U40.1 113.39,86.9 v1(113.22,87.07) 113.22,86 112.18,84.96 112.18,81.51 113.5,80.19 114.78,80.19 115.48,79.5 116.58,79.5 116.77,79.7 U48.74
  BOTTOM w0.191: v1(113.22,87.07) 113.22,87.49 113.41,87.68 R519.2
BUF_TEST_GPIO2: length 14.9
  TOP w0.191: v1(116.33,80.08) 116.35,80.1 U48.73 ; U51.2 R280.2 115.5,68.73 v1(115.5,69.16)
  L03_SIG01 w0.076: v1(115.5,69.16) 115.5,72.95 115.12,73.33 115.12,78.91 116.3,80.08 v1(116.33,80.08)
BUF_TEST_GPIO3: length 14.8
  TOP w0.081: 116.03,80.5 U48.72
  TOP w0.191: U40.3 113.72,87.7 113.7,87.73 113.58,87.73 113.42,87.89 113.42,88 v1(113.24,88.19) ; 116.03,80.5 115.17,80.5 115.07,80.59 113.8,80.59 v1(113.47,80.93)
  L03_SIG01 w0.076: v1(113.24,88.19) 114.26,87.16 114.26,83.03 113.47,82.24 v1(113.47,80.93)
  BOTTOM w0.191: R515.2 113.8,88.4 113.59,88.19 v1(113.24,88.19)
BUF_TEST_GPIO4: length 14.8
  TOP w0.081: 116.18,80.92 116.3,80.81 116.93,80.81 117.02,80.9 U48.71
  TOP w0.191: U40.5 113.68,88.5 113.66,88.53 113.58,88.53 113.42,88.69 113.42,88.76 v1(113.16,89.03) ; v1(114.18,81.21) 114.38,81.02 116.09,81.02 116.18,80.92
  L03_SIG01 w0.076: v1(113.16,89.03) 114.55,87.64 114.55,81.58 v1(114.18,81.21)
  BOTTOM w0.191: v1(113.16,89.03) 113.41,89.28 R510.2
BUF_TEST_PORZN: length 18.3
  TOP w0.191: U48.77 113.65,78.5 110.55,81.6 110.55,88.71 110.36,88.9 v1(109.83,88.9) U40.9
  BOTTOM w0.145: R512.2 v1(109.83,88.9)
BUF_TEST_POWERDOWN: length 16.9
  TOP w0.191: U48.78 113.45,78.1 109.83,81.72 v1(109.83,87.3) U40.13
  BOTTOM w0.145: R525.2 v1(109.83,87.3)
BUF_TEST_WARMRESETN: length 17.2
  TOP w0.191: v1(111.08,87.86) 111.08,81.71 113.89,78.9 U48.76 ; U40.11 v1(109.83,88.1)
  BOTTOM w0.145: R517.2 v1(109.83,88.1)
  BOTTOM w0.191: v1(109.83,88.1) 110.83,88.1 v1(111.08,87.86)
CAN_IO_3V3: length 103.7
  TOP w0.254: R322.1 35.97,52.47 v1(36.05,52.38) 35.97,52.3 R326.1
  TOP w0.356: U47.H8 v1(72.36,76.79)
  TOP w0.381: v1(33.44,58.92) TP82.1 ; R309.2 v1(18.76,62.4)
  L03_SIG01 w0.14: v1(72.36,76.79) 71.96,76.4 70.56,76.4 70.34,76.61 70.34,77.8 70.15,77.99 69.71,77.99 69.55,78.15 69.55,78.63 69.39,78.79 67.25,78.79 66.71,78.26
  L03_SIG01 w0.305: 66.71,78.26 65.36,76.91 64.19,76.91 63.18,75.9 v1(62.64,75.9)
  L04_PWR1 w0.381: v1(33.44,58.92) 33.44,60.08 33.84,60.48 36.11,60.48 36.55,60.91 41.01,60.91 41.3,61.2 41.75,61.2 42.04,60.91 43.4,60.91 44.13,61.64 44.13,65.25 44.7,65.83 47.16,65.83 47.56,66.22 54.34,66.22 56.47,64.09 v1(59.72,64.09)
  L05_SIG02 w0.508: v1(35.81,56.58) 35.65,56.74 v1(35.65,59.12)
  BOTTOM w0.254: v1(36.05,52.38) 35.97,52.47 35.97,53.61 36.78,54.42 36.78,55.73 R593.1 36.75,56.04 36.63,56.16 R592.1 35.92,56.47 v1(35.81,56.58) ; 59.85,76.56 60.29,76.56 60.48,76.75 61.84,76.75 62.64,75.95 v1(62.64,75.9) 62.64,75.88 62.83,75.69 C512.1 C510.1
  BOTTOM w0.305: v1(59.72,64.09) 59.72,64.15 60.75,65.19 60.75,70.71 59.01,72.45 57.26,72.45 56.64,73.07 FL15.2 ; 34.04,60.47 35.19,60.47 35.65,60.01 v1(35.65,59.12) 35.73,59.03 R590.2 ; 34.04,60.47 34.04,61.08 33.56,61.56 20.97,61.56 20.14,62.4 v1(18.76,62.4) ; 34.04,60.47 33.44,59.88 v1(33.44,58.92) C574.2 33.16,58.09 U117.3
  BOTTOM w0.381: FL15.2 56.64,75.95 57.26,76.56 59.85,76.56
CAP_VDDS0: length 0.8
  TOP w0.356: U47.G13 v1(71.56,81.59)
  BOTTOM w0.381: C454.1 v1(71.56,81.59)
CAP_VDDS1: length 0.8
  TOP w0.356: U47.K16 v1(73.96,83.99)
  BOTTOM w0.305: v1(73.96,83.99) 73.82,84.13 C434.1
CAP_VDDS2: length 0.8
  TOP w0.356: U47.T14 v1(79.56,82.39)
  BOTTOM w0.305: v1(79.56,82.39) 79.63,82.46 C446.1
CAP_VDDS3: length 0.9
  TOP w0.356: U47.M16 v1(76.36,83.99)
  BOTTOM w0.305: C432.1 76.48,84.11 v1(76.36,83.99)
CAP_VDDS4: length 0.9
  TOP w0.356: U47.R8 v1(78.76,76.79)
  BOTTOM w0.305: C507.1 v1(78.76,76.79)
CAP_VDDS5: length 0.7
  TOP w0.356: U47.G15 v1(71.56,83.19)
  BOTTOM w0.305: 71.66,83.09 v1(71.56,83.19)
CAP_VDDS6: length 0.8
  TOP w0.356: U47.J16 v1(73.16,83.99)
  BOTTOM w0.305: C435.1 73.15,83.98 v1(73.16,83.99)
CAP_VDDS_CANUART: length 0.9
  TOP w0.356: U47.G8 v1(71.56,76.79)
  BOTTOM w0.254: C509.1 71.68,76.67 v1(71.56,76.79)
CAP_VDDS_MCU: length 0.9
  TOP w0.356: U47.G10 v1(71.56,78.39)
  BOTTOM w0.305: C484.1 71.51,78.39 v1(71.56,78.39)
CLK_GEN_XI: length 1.5
  TOP w0.191: R104.1 72.54,141.04 72.69,141.19 U20.1
CLK_GEN_XO: length 1.5
  TOP w0.191: U20.2 73.19,140.91 73.43,140.67 R105.1
CLKOUT0: length 10.8
  TOP w0.191: R336.2 R337.2 78.37,47.29 78,46.92 75.41,46.92 73.39,44.91 72.42,44.91 71.7,45.63 71.3,45.63 71.11,45.44 U65.1
CLKOUT_OSC: length 1.1
  TOP w0.191: R336.1 U62.3
CLOCK_GENERATOR_SUPPLY: length 9
  TOP w0.191: U20.10 C116.1 ; U20.20 C120.1 ; U20.18 C118.1
  TOP w0.254: v1(72.78,148.24) 73.07,147.95 C112.1 73.07,146.67 73.19,146.55 U20.14
  TOP w0.305: C118.1 C120.1
  TOP w0.381: v1(70.49,146.09) C114.1 70.49,144.58 70.63,144.44 C118.1
  vias: v1(76.82,145.47) v1(77.19,146.1)
COMP_LM5141: length 4.1
  BOTTOM w0.191: C632.1 15.23,19.78 15.37,19.64 R670.1 15.91,20.2 16.91,21.2 U128.20
CORE_CONFIG: length 45.7
  TOP w0.191: SW7.3 R371.2 51.82,30.37 v1(52.13,30.68) ; v1(39.68,60.27) 40.95,60.27 41.12,60.11 42.06,60.11 TP76.1 42.79,60.83 U56.8
  L03_SIG01 w0.076: v1(52.13,30.68) 55.08,33.63 55.08,40.25 53.47,41.85 51.13,41.85 40.68,52.3 40.68,58.89 39.68,59.89 v1(39.68,60.27)
CP_GEMAC_CPTS0_HW1TSPUSH: length 51.3
  TOP w0.102: U47.B15 67.56,83.19 66.73,83.19 66.48,83.44 66.32,83.44
  TOP w0.191: v1(53.18,113.95) 55.27,113.95 55.8,114.48 60.49,114.48 62.05,112.92 v1(62.54,112.92) ; v1(57.02,90.13) 57.02,89.16 60.24,85.94 61.18,85.94 63.01,84.11 64.32,84.11 64.99,83.44 66.32,83.44
  L03_SIG01 w0.076: v1(57.02,90.13) 57.02,98.63 54.57,101.08 54.57,107.89 53.18,109.29 v1(53.18,113.95)
  BOTTOM w0.191: v1(62.54,112.92) 62.79,112.67 U85.2
CP_GEMAC_CPTS0_HW2TSPUSH: length 72
  TOP w0.132: U47.E15 v1(69.96,83.19)
  L03_SIG01 w0.076: v1(57.17,86.37) 56.75,86.79 54.56,86.79 53.46,87.89 53.46,89.92 53.1,90.28 53.1,96.88 54.17,97.95 54.17,98.37 52.42,100.12 52.42,104.85 52.78,105.21 52.78,113.45 52.29,113.93 v1(52.29,117.35)
  BOTTOM w0.14: v1(69.96,83.19) 69.56,83.59 68.08,83.59
  BOTTOM w0.191: v1(52.29,117.35) 53.73,115.92 59.05,115.92 61.25,118.11 65.17,118.11 67.07,116.21 67.07,114.57 66.23,113.73 66.23,113.37 65.79,112.94 U85.8 ; v1(57.17,86.37) 58.42,86.37 60,84.78 66.22,84.78 66.66,84.34 67.34,84.34 68.08,83.59
CPLD1_1V8_BANK_SUPPLY: length 5.7
  TOP w0.254: C158.1 76.25,105.76 76.5,105.51 v1(76.7,105.51)
  BOTTOM w0.254: U84.22 v1(76.7,105.51) ; v1(81.62,104.74) 81.61,104.74 C412.1 81.45,105.25 81.2,105.5 U84.13 ; U84.30 74.45,109.54 74.45,109.55 74.41,109.55 74.31,109.66 73.52,109.66 C407.1 73.41,109.12 v1(73.43,109.1)
  vias: v1(84.61,109.32) v1(84.92,109.92)
CPLD1_DONE: length 105.4
  TOP w0.191: v1(64.48,154.41) 63.5,153.43 63.5,137.88 67.49,133.89 67.49,128.69 68.54,127.64 68.54,126.08 72.12,122.5 72.12,117.41 72.12,115.93 72.66,115.39 74.27,115.39 75.1,114.55 v1(75.1,114.09) 75.55,113.65 R142.2 ; U21.12 106.13,155.12 106.62,155.61 v1(106.62,156.46)
  BOTTOM w0.191: v1(106.62,156.46) 105.44,157.64 90.14,157.64 87.61,155.11 79.77,155.11 79.19,155.69 74.48,155.69 74.24,155.94 73.3,155.94 72.5,156.74 69.79,156.74 69.43,156.38 66.44,156.38 v1(64.48,154.41) ; v1(75.1,114.09) 75.4,114.09 75.7,113.8 U84.37
CPLD1_INTN: length 102.7
  TOP w0.191: v1(75.7,114.68) 75.51,114.68 74.09,116.1 74.09,116.79 72.7,118.19 72.7,122.75 68.92,126.53 68.92,133.2 64.14,137.98 64.14,152.78 v1(65.84,154.49) ; v1(105.61,156.42) 105.63,156.41 U21.13
  BOTTOM w0.191: R460.2 76.42,115.09 76.01,114.68 v1(75.7,114.68) 76.2,114.19 U84.38 ; v1(105.61,156.42) 104.81,157.23 90.32,157.23 87.77,154.68 79.53,154.68 79.14,155.07 77.56,155.07 77.2,154.72 74.84,154.72 74,155.56 73.11,155.56 72.31,156.36 69.95,156.36 69.37,155.78 67.14,155.78 v1(65.84,154.49)
CPLD1_JTAGENB: length 61.4
  TOP w0.191: v1(77.7,114.66) 77.7,116.74 77.11,117.32 74.75,117.32 73.73,118.35 73.73,123.42 70.29,126.87 70.29,133.16 67.52,135.93 67.52,140.01 v1(67.03,140.5) ; v1(86.4,141.04) 87.21,141.86 87.21,144.84 86.57,145.48 U18.3
  BOTTOM w0.191: v1(86.4,141.04) 86.4,140.26 85.18,139.04 77.06,139.04 76.53,139.58 76.15,139.58 75.9,139.32 71.45,139.32 70.63,140.15 67.84,140.15 67.48,140.5 v1(67.03,140.5) ; R458.1 78.2,115.16 v1(77.7,114.66) U84.41
CPLD1_PROGRAMN: length 60.5
  TOP w0.191: v1(76.91,114.92) 76.19,114.92 75.69,115.42 75.32,115.42 74.53,116.2 74.53,116.95 73.08,118.4 73.08,123.1 69.9,126.28 69.9,132.8 66.94,135.77 v1(66.94,139.48) ; v1(86.34,139.56) 87.8,141.01 87.8,144.99 86.82,145.98 U18.4
  BOTTOM w0.191: v1(66.94,139.48) 70.69,139.48 71.51,138.66 85.45,138.66 v1(86.34,139.56) ; U84.40 77.2,114.63 v1(76.91,114.92) 77.31,115.32 R459.2
CPLD1_TCK: length 96.1
  BOTTOM w0.191: J8.2 113.33,151.08 119.4,151.08 121.4,149.07 121.4,142.45 129.37,134.49 129.37,123.74 126.53,120.91 118.78,120.91 118.24,121.44 106.6,121.44 104.74,119.57 98.35,119.57 97.87,120.05 96.3,120.05 96.03,119.79 91.78,119.79 90.83,118.84 87.32,118.84 84.38,115.9 84.07,115.9 82.5,115.9 81.06,114.47 80,114.47 79.68,114.15 79.68,113.3 U84.45
CPLD1_TDI: length 96.4
  BOTTOM w0.191: J8.4 117.22,153.86 121.78,149.3 121.78,142.61 129.75,134.65 129.75,123.55 126.53,120.33 118.64,120.33 118.02,120.94 106.92,120.94 105.17,119.19 102.55,119.19 101.8,118.45 100.4,118.45 99.76,119.09 91.68,119.09 91.05,118.46 87.85,118.46 84.89,115.5 83.91,115.5 82.65,115.5 81.19,114.04 80.89,114.04 80.7,113.85 U84.47
CPLD1_TDO: length 97.6
  BOTTOM w0.191: J8.5 115.24,156.4 122.17,149.48 122.17,142.77 130.13,134.81 130.13,123.39 126.44,119.7 114.91,119.7 114.31,120.3 107.07,120.3 105.5,118.73 102.79,118.73 102.1,118.04 99.39,118.04 99.05,118.38 91.89,118.38 91.59,118.08 88.37,118.08 85.38,115.09 83.75,115.09 82.79,115.09 82.1,114.4 82.1,113.85 81.54,113.29 U84.48
CPLD1_TMS: length 102.8
  BOTTOM w0.191: U84.44 79.2,114.35 79.7,114.86 80.9,114.86 82.38,116.33 84.23,116.33 87.11,119.22 90.63,119.22 92.47,121.07 98.4,121.07 99.35,122.02 118.65,122.02 119.29,121.38 126.4,121.38 128.9,123.87 128.9,133.91 120.86,141.95 120.86,148.83 119,150.7 114.22,150.7 112.69,149.17 112.69,148.49 111.75,147.54 110.22,147.54 109.13,148.64 R437.2 J8.3
CPLD2_1V8_BANK_SUPPLY: length 3.2
  TOP w0.191: v1(65.29,104.24) 65.19,104.34 C163.1
  BOTTOM w0.191: v1(69.69,106.26) C410.1 U85.22 ; U85.30 v1(65.29,104.24)
  vias: v1(64.18,115.24) v1(64.24,113.91) v1(68.61,113.45) v1(68.62,112.86)
CPLD2_DONE: length 93.3
  TOP w0.191: U21.10 v1(107.13,146.45)
  L03_SIG01 w0.076: v1(60.19,105.38) 61.67,106.86 61.67,114.62 60.61,115.68 60.61,123.74 60.26,124.09 60.26,143.96 v1(61.49,145.2)
  BOTTOM w0.191: U85.37 60.47,105.65 v1(60.19,105.38) 60.04,105.53 R473.2 ; v1(61.49,145.2) 63.3,147 70.94,147 71.35,146.59 76.96,146.59 77.5,147.13 84.58,147.13 86.34,145.37 106.05,145.37 v1(107.13,146.45)
CPLD2_INTN: length 97.7
  TOP w0.191: v1(107.07,148.95) 106.63,148.5 U21.11
  L03_SIG01 w0.076: v1(60.58,145.84) 59.97,145.24 59.97,123.91 60.31,123.57 60.31,115.62 61.49,114.43 61.49,106.94 60.66,106.1 v1(60.11,106.1)
  BOTTOM w0.191: U85.38 60.16,106.15 v1(60.11,106.1) 59.79,106.42 R471.2 ; v1(107.07,148.95) 105.81,148.95 105.81,148.94 92.37,148.94 89.82,146.4 86.46,146.4 84.92,147.93 84.61,147.93 84.61,147.93 77.01,147.93 76.43,148.51 73.57,148.51 73.35,148.73 67.51,148.73 66.97,148.19 62.92,148.19 v1(60.58,145.84)
CPLD2_JTAGENB: length 73.6
  TOP w0.191: v1(87.28,147.05) 86.71,146.48 U18.5
  L03_SIG01 w0.076: v1(60.78,107.65) 61.31,108.19 61.31,114.16 60.1,115.37 60.1,123.43 59.7,123.84 59.7,145.91 v1(60.55,146.76)
  BOTTOM w0.191: R467.1 60.34,108.1 v1(60.78,107.65) U85.41 ; v1(60.55,146.76) 60.55,147.73 62.62,149.8 73.02,149.8 75.18,149.8 76.08,148.9 76.82,148.9 77.41,148.31 84.45,148.31 84.45,148.31 84.76,148.31 85.08,148.31 86.35,147.05 v1(87.28,147.05)
CPLD2_PROGRAMN: length 75.2
  TOP w0.191: U18.6 86.34,146.98 86.53,147.17 86.53,148.02 v1(86.22,148.33)
  L03_SIG01 w0.076: v1(60.05,107.39) 60.05,108.37 61.14,109.46 61.14,113.85 59.81,115.18 59.81,123.28 59.42,123.68 v1(59.42,148.74)
  BOTTOM w0.191: U85.40 60.29,107.15 v1(60.05,107.39) 60,107.34 R469.2 ; v1(59.42,148.74) 61.02,148.74 62.57,150.29 75.23,150.29 76.24,149.28 85.28,149.28 v1(86.22,148.33)
CPLD2_TCK: length 36.5
  L03_SIG01 w0.076: v1(59.22,111.24) 58.96,111.5 58.96,113.17 59.17,113.38 59.17,118.11 58.63,118.65 v1(58.63,124.3)
  BOTTOM w0.191: U85.45 60.94,109.65 60.88,109.72 60.29,109.72 59.87,110.14 59.87,111.01 59.65,111.24 v1(59.22,111.24) ; v1(58.63,124.3) 46.03,124.3 44.76,125.58 J11.2
CPLD2_TDI: length 31.7
  L03_SIG01 w0.076: v1(59.14,121.2) 59.6,120.75 v1(59.6,112.32)
  BOTTOM w0.191: v1(59.14,121.2) 58.79,120.85 40,120.85 J11.4 ; v1(59.6,112.32) 59.6,112.03 60.97,110.65 U85.47
CPLD2_TDO: length 30.1
  L03_SIG01 w0.076: v1(59.11,118.98) 59.38,118.71 59.38,113.2 59.19,113 59.19,112.11 59.55,111.75 60.66,111.75 v1(60.74,111.83)
  BOTTOM w0.191: U85.48 60.91,111.15 60.74,111.32 60.74,111.82 v1(60.74,111.83) ; J11.5 40.44,118.75 58.88,118.75 v1(59.11,118.98)
CPLD2_TMS: length 36
  TOP w0.191: J11.3 R120.2
  L03_SIG01 w0.076: v1(59.36,110.48) 58.7,111.14 58.7,113.2 58.95,113.45 58.95,117.9 58.43,118.42 58.43,121.41 v1(57.52,122.32)
  BOTTOM w0.191: U85.44 60.82,109.15 60.65,109.33 60.37,109.33 60.36,109.34 60.13,109.34 59.36,110.11 v1(59.36,110.48) ; v1(57.52,122.32) 40.36,122.32 J11.3
CPLD/EXP1_MCASP0_ACLKR: length 72.9
  TOP w0.191: J12.78 18.73,135.56 v1(19.23,135.06) ; v1(61.59,101.76) 59.79,99.96 R174.2
  BOTTOM w0.191: R484.1 64.08,103.24 62.6,101.76 v1(61.59,101.76) 60.35,101.76 58.21,103.89 55.01,103.89 48.19,110.71 42.26,110.71 41.86,110.31 37.17,110.31 29.06,118.43 29.06,127.45 27.08,129.43 27.08,133.08 26.12,134.04 20.26,134.04 v1(19.23,135.06)
CPLD/EXP1_MCASP0_AFSR: length 74.8
  TOP w0.191: J12.80 18.74,136.36 v1(19.04,136.66) ; v1(61.13,104.11) 62.17,103.07 62.17,99.59 60.58,98 R189.2
  BOTTOM w0.191: v1(19.04,136.66) 25.11,136.66 30.7,131.06 30.7,118.61 37.63,111.69 41.33,111.69 41.59,111.96 48.64,111.96 55.47,105.13 59.76,105.13 60.76,104.13 61.11,104.13 v1(61.13,104.11) 61.14,104.13 61.9,104.13 62.29,104.52 U85.36
CPLD/EXP1_MCASP0_AFSX: length 68.3
  TOP w0.191: v1(60.31,103.58) 60.31,102.67 58.27,100.63 R173.2 ; J12.79 24.66,136.36 v1(25.45,135.57)
  BOTTOM w0.191: U85.34 63.29,103.6 63,103.3 60.58,103.3 v1(60.31,103.58) 59.24,104.64 55.39,104.64 48.5,111.54 41.89,111.54 41.58,111.22 37.48,111.22 30.11,118.59 30.11,130.91 v1(25.45,135.57)
CPLD/EXP1_MCASP0_AXR0: length 68.1
  TOP w0.191: v1(61.05,102.73) 61.05,102.2 59.06,100.21 R188.2 ; v1(27.7,131.56) J12.67
  BOTTOM w0.191: v1(27.7,131.56) 27.7,129.58 29.55,127.73 29.55,118.48 37.27,110.76 41.68,110.76 42.06,111.14 48.36,111.14 55.19,104.31 58.78,104.31 60.35,102.73 v1(61.05,102.73) 63.02,102.73 64.29,104.01 U85.32
CPLD/EXP2_MCASP2_ACLKR: length 60.5
  TOP w0.191: J13.43 121.98,115.55 121.42,115 121.42,108.5 119.43,106.5 v1(119.43,106.43) ; v1(81.75,102.02) 82.1,101.68 U33.2 ; v1(81.75,102.02) 81.75,100.9 81.79,100.86 R179.1 ; v1(81.75,102.02) 81.61,102.16 RA2.4
  L03_SIG01 w0.076: v1(119.43,106.43) 118.8,105.8 114.15,105.8 113.04,104.69 113.04,103.06 112.85,102.87 97.54,102.87 96.04,101.37 95.05,101.37 94.09,100.41 87.01,100.41 85.39,102.02 v1(81.75,102.02)
CPLD/EXP2_MCASP2_ACLKX: length 89.4
  TOP w0.191: v1(120.83,118.11) 120.83,121.2 121.59,121.95 J13.37 ; v1(75.77,104.26) 77.22,104.26 79.07,106.11 80.91,106.11 81.19,105.82 81.19,104.4 79.72,102.92 79.72,102.42 79.97,102.16 RA2.3 80.47,101.18 80.27,100.98 R178.1
  L03_SIG01 w0.076: v1(120.83,118.11) 120.35,118.59 119.01,118.59 115.55,115.13 106.42,115.13 105.29,113.99 105.29,109.18 103.34,107.23 103.34,106.85 100.22,103.73 97.1,103.73 95.57,102.2 95.11,102.2 87.46,102.2 86.3,103.36 83.92,103.36 81.94,105.34 81.94,106.09 82.39,106.55 83.03,106.55 83.32,106.83 83.32,107.01 82.85,107.48 81.69,107.48 78.46,104.25 78.46,103.18 78.68,102.97 78.68,102.43 78.44,102.2 77.32,102.2 75.77,103.75 v1(75.77,104.26)
  BOTTOM w0.191: v1(75.77,104.26) 75.77,104.8 76.2,105.23 U84.23
CPLD/EXP2_MCASP2_AFSR: length 91.5
  TOP w0.191: RA1.4 69.13,107.01 v1(69.28,107.15) 70.93,107.15 71.16,106.92 74.67,106.92 76.12,108.37 83.48,108.37 83.88,107.98 86.25,107.98 86.69,108.42 88.66,108.42 89.4,109.16 89.4,112.56 90.9,114.05 100.97,114.05 101.69,114.78 101.69,116.53 105,119.84 112.04,119.84 115.84,116.04 120.59,116.04 120.9,116.35 J13.41
  BOTTOM w0.191: U85.21 v1(69.28,107.15) 70.89,107.15 71.53,106.51 71.53,106.01 74.47,103.07 77.22,103.07 78.08,102.21 79.07,102.21 79.67,101.6 80.81,101.6 81.29,101.12 85.21,101.12 85.4,100.93 85.4,100.01 83.55,98.15 R497.2
CPLD/EXP2_MCASP2_AFSX: length 96.8
  TOP w0.191: R193.2 81.05,99.53 v1(81.34,99.82) ; RA1.3 69.13,105.57 68.73,105.17 v1(68.54,105.17) 68.34,105.17 68.31,105.18 67.83,105.18 67.15,105.86 67.15,108.2 68.79,109.84 71.02,109.84 72.1,108.76 72.37,108.76 73.67,110.07 78.99,110.07 79.97,111.05 80.84,111.05 81.03,111.24 81.03,112.83 82.29,114.1 89.74,114.1 90.27,114.63 100.74,114.63 101.24,115.12 101.24,116.77 103.33,118.86 103.33,120.29 104.36,121.33 111.23,121.33 116.07,116.49 120.43,116.49 120.78,116.84 121.95,116.84 122.33,117.22 122.33,120.91 122.57,121.15 J13.39
  BOTTOM w0.191: v1(81.34,99.82) 81.34,100.53 80.65,101.22 79.44,101.22 78.85,101.81 77.92,101.81 77.06,102.67 74.26,102.67 72.37,104.56 69.53,104.56 68.92,105.17 v1(68.54,105.17) U85.24
CPLD/EXP2_MCASP2_AXR0: length 74.6
  TOP w0.191: v1(119.34,118.19) 119.34,123.72 121.57,125.95 J13.27 ; v1(80.7,105.44) 79.84,105.44 78.53,104.13 78.53,103.2 78.73,103 78.73,102.03 79.03,101.73 79.03,101.09 78.74,100.8 78.74,99.68 78,98.94 R191.2
  L03_SIG01 w0.076: v1(119.34,118.19) 115.79,114.64 107.16,114.64 106.38,113.86 106.38,109.84 103.54,107 103.54,106.66 100.42,103.54 97.21,103.54 95.66,101.99 95.02,101.99 87.29,101.99 86.16,103.13 82.64,103.13 80.7,105.07 v1(80.7,105.44)
  BOTTOM w0.191: U84.14 v1(80.7,105.44) 80.88,105.26 RA7.8
CPLD/EXP2_MCASP2_AXR1: length 77.5
  TOP w0.191: J13.29 121.96,125.15 119.92,123.11 v1(119.92,117.57)
  L03_SIG01 w0.076: v1(82.32,100.57) 81.37,100.57 78.64,103.29 78.64,103.61 78.93,103.9 80.01,103.9 v1(80.4,104.29) 82.05,102.64 85.65,102.64 87.15,101.14 94.27,101.14 94.93,101.79 94.94,101.79 95.8,101.79 97.35,103.34 100.78,103.34 103.61,106.16 115.91,106.16 119.92,110.18 v1(119.92,117.57)
  BOTTOM w0.191: v1(82.32,100.57) 83.04,99.85 83.04,99.13 82.03,98.12 R498.2 ; RA7.7 80.48,104.2 v1(80.4,104.29) 80.4,104.71 80.2,104.91 U84.15
CPLD/EXP2_MCASP2_AXR3: length 91.1
  TOP w0.191: J13.28 132.27,125.95 134.58,123.64 134.58,111.96 v1(134,111.38) ; v1(79.08,103.52) 79.17,103.43 79.17,102.28 79.78,101.67 79.78,99.24 79.53,98.99 R192.2
  L03_SIG01 w0.076: v1(134,111.38) 130.57,107.96 127.77,107.96 127.72,108.01 118.09,108.01 116.07,105.98 113.46,105.98 111.24,103.75 108.85,103.75 108.07,104.53 102.46,104.53 101.07,103.14 97.48,103.14 95.93,101.59 95.01,101.59 94.15,100.72 87.07,100.72 85.36,102.43 80.17,102.43 v1(79.08,103.52)
  BOTTOM w0.191: U84.16 79.68,106.27 79.68,105.31 78.98,104.6 78.98,104.05 79.08,103.94 v1(79.08,103.52) 79.12,103.52 79.38,103.77 RA7.5
CPLD/EXP2_MCASP2_AXR4: length 101.9
  TOP w0.191: v1(79.2,105.49) 77.25,103.55 77.25,102.26 77.51,102 77.51,98.77 77.22,98.48 R176.2 ; J13.30 131.97,125.15 133.94,123.18 v1(133.94,120.99)
  L03_SIG01 w0.076: v1(79.2,105.49) 79.2,105.63 81.67,108.11 83.51,108.11 83.78,107.84 83.78,106.37 83.15,105.74 83.15,104.56 84.16,103.54 88.96,103.54 90.11,102.4 95.19,102.4 95.48,102.4 96.99,103.91 100,103.91 103.14,107.04 103.14,107.32 105.11,109.29 105.11,114.07 106.46,115.42 115.49,115.42 118.99,118.92 120.82,118.92 121.23,118.51 121.23,117.78 120.87,117.42 v1(120.87,112.15) 121.21,111.82 128.01,111.82 133.94,117.75 v1(133.94,120.99)
  BOTTOM w0.191: RA5.8 119.92,113.1 v1(120.87,112.15) ; U84.17 v1(79.2,105.49)
CPLD/EXP2_MCASP2_AXR14: length 64.4
  TOP w0.191: J13.70 128.3,105.15 128.24,105.21 v1(128.19,105.21)
  L03_SIG01 w0.076: v1(128.19,105.21) 123.23,105.21 122.12,104.09 120.82,104.09 120.3,104.62 116.37,104.62 116.04,104.28 116.04,103.87 114.18,102.01 97.96,102.01 96.52,100.57 95.59,100.57 93.99,98.97 81.41,98.97 79.05,101.33 v1(78.56,101.33)
  BOTTOM w0.191: R486.2 76.99,101.93 77.59,101.33 v1(78.56,101.33) 78.71,101.18 78.71,99.62 79.35,98.98 79.35,98.69 78.98,98.32 R500.2
CPLD/EXP2_MCASP2_AXR15: length 62.2
  TOP w0.191: v1(76.59,99.61) 76.47,99.73 R165.2 75.4,98.84 76.48,97.75 R190.2 ; v1(127.93,103.71) 127.93,103.75 128.53,104.35 J13.72
  L03_SIG01 w0.076: v1(76.59,99.61) 78.54,99.61 80.13,98.02 94.61,98.02 96.15,99.56 97.35,99.56 98.79,101 114.65,101 116.29,102.65 120.8,102.65 121.3,102.14 122.56,102.14 124.13,103.71 v1(127.93,103.71)
CPLD_CDCE_CLKOUT_1: length 89.6
  TOP w0.191: R89.1 122.1,147.23 123.09,146.23 123.09,143.44 v1(120.81,141.15) ; v1(99.09,147.99) 90.65,139.55 90.65,129.57 89.16,128.08 89.16,116.11 87.88,114.84 85.14,114.84 84.77,115.2 80.97,115.2 80.35,114.59 79.9,114.59 78.63,113.31 78.59,113.27 78.59,111.2 78.59,111.2 78.59,110.96 78.14,110.51 v1(74.15,110.51)
  BOTTOM w0.191: v1(120.81,141.15) 119.97,141.15 118.97,142.15 115.06,142.15 112.73,144.49 109.47,144.49 108.42,145.54 108.42,147.15 107.58,147.99 v1(99.09,147.99) ; U84.32 74.17,110.54 v1(74.15,110.51)
CPLD_CDCE_CLKOUT_2: length 78.2
  TOP w0.191: R95.1 120.24,141.92 v1(120.31,141.85) ; v1(96.88,146.61) 89.75,139.48 89.75,131.96 88.4,130.61 88.4,120.52 86.3,118.42 83.77,118.42 82.08,116.72 80.36,116.72 80.09,116.45 80.09,116.42 80.09,116.42 80.09,116.04 80.09,116.04 80.09,115.94 79.88,115.73 79.43,115.73 76.74,113.04 76.74,112.68 75.87,111.82 74.25,111.82 74.18,111.89 v1(74.05,111.89)
  BOTTOM w0.191: v1(74.05,111.89) 74.05,111.87 74.19,111.73 74.38,111.54 U84.34 ; v1(96.88,146.61) 98.75,148.48 107.72,148.48 109.05,147.15 109.05,145.5 109.59,144.96 113.31,144.96 115.48,142.79 119.36,142.79 v1(120.31,141.85)
CPLD_CLOCKIN: length 59.3
  TOP w0.191: v1(73.41,111.55) 73.25,111.4 68.27,111.4 67.99,111.68 67.99,114.45 67.39,115.05 67.39,119.37 68.16,120.13 68.16,127.48 67.1,128.53 67.1,133.72 63.02,137.81 63.02,149.13 v1(62.8,149.35) ; v1(73.05,149.21) 73.69,148.56 R87.1
  BOTTOM w0.191: v1(73.41,111.55) 73.92,111.04 U84.33 ; v1(62.8,149.35) 62.94,149.21 v1(73.05,149.21)
CPLD_CPSW_RGMII1_BCLK: length 124.4
  TOP w0.191: J18.48 92.41,42.84 v1(92.58,43.01) ; v1(69.9,119.56) 69.9,115.88 69.46,115.43 69.46,112.83 69.85,112.43 70.47,112.43 70.88,112.84 U29.3 ; v1(97.09,82.01) 95.94,83.16 95.94,93.64 97.21,94.9 v1(97.21,98.4) ; v1(90.9,112.5) 90.83,112.43 90.83,105.55 v1(91.36,105.02)
  L03_SIG01 w0.076: v1(92.58,43.01) 92.98,43.01 93.99,44.02 93.99,55.11 96.69,57.82 96.69,71.63 96.48,71.83 96.48,76.8 97.08,77.4 97.08,82 v1(97.09,82.01) ; v1(90.34,121.85) 90.19,121.7 90.19,113.21 v1(90.9,112.5)
  BOTTOM w0.191: v1(97.21,98.4) 97.74,98.93 97.74,104.4 96.85,105.28 92.25,105.28 91.99,105.02 v1(91.36,105.02) ; v1(90.34,121.85) 89.43,120.93 86.29,120.93 85,122.22 85,123.55 84.18,124.38 75.21,124.38 70.39,119.56 v1(69.9,119.56)
CPLD_CPSW_RGMII1_BCLK_1V8: length 2.5
  TOP w0.191: U29.6 73.45,112.84 73.59,112.7 v1(73.64,112.7)
  BOTTOM w0.191: U84.35 74.5,112.04 73.84,112.7 v1(73.64,112.7)
CPLD_CPSW_RGMII1_COL: length 190.2
  TOP w0.191: v1(86.13,41.28) 86.13,41.37 85.61,41.89 J18.14 ; v1(107.16,47.02) 108.86,48.72 113.32,48.72 113.61,48.43 115.91,48.43 116.69,49.21 125.25,49.21 v1(125.42,49.04)
  L03_SIG01 w0.076: v1(125.42,49.04) 125.95,49.57 125.95,62.76 132.27,69.08 132.27,70.65 132.71,71.09 132.71,86.75 134.53,88.57 134.53,121.5 131.92,124.11 124.43,124.11 123.65,123.32 121.66,123.32 121.33,123 118.95,123 v1(118.69,122.74)
  BOTTOM w0.191: U80.7 71.84,117.73 72.13,118.01 75.41,118.01 76.07,117.36 79.14,117.36 79.76,116.74 81.11,116.74 81.91,117.54 82.5,117.54 83.6,118.64 85.84,118.64 86.8,119.6 90.35,119.6 92.27,121.52 97.9,121.52 98.87,122.5 118.45,122.5 v1(118.69,122.74) ; v1(86.13,41.28) 86.61,41.28 87.48,42.15 88.87,42.15 89.53,42.81 91.06,42.81 91.8,43.54 91.8,45.16 93.04,46.4 94.04,46.4 95.59,47.95 106.23,47.95 v1(107.16,47.02)
CPLD_CPSW_RGMII1_COL_1V8: length 6.8
  BOTTOM w0.191: U85.15 70.17,110.15 71.1,111.08 71.1,112.28 71.84,113.02 U80.14
CPLD_CPSW_RGMII1_CRS: length 190.5
  TOP w0.191: J18.30 88.81,41.41 v1(88.89,41.34) ; v1(107.24,46.07) 107.37,46.07 109.6,48.3 113.19,48.3 113.44,48.04 116.06,48.04 116.84,48.82 124.32,48.82 v1(125.29,47.86)
  L03_SIG01 w0.076: v1(118.69,123.45) 118.95,123.2 121.25,123.2 121.57,123.53 123.56,123.53 124.38,124.34 131.94,124.34 134.81,121.47 134.81,88.41 132.94,86.55 132.94,70.68 132.68,70.42 132.68,68.22 126.49,62.04 126.49,49.06 v1(125.29,47.86)
  BOTTOM w0.191: v1(88.89,41.34) 89.86,42.31 92.72,42.31 93.67,43.26 93.67,45.42 95.72,47.47 105.84,47.47 v1(107.24,46.07) ; U80.6 71.44,117.91 71.93,118.4 75.57,118.4 76.22,117.74 79.3,117.74 79.92,117.13 80.96,117.13 81.09,117.26 81.76,117.92 82.16,117.92 83.31,119.08 85.23,119.08 86.14,119.98 90.09,119.98 92.01,121.9 97.43,121.9 98.44,122.91 118.15,122.91 v1(118.69,123.45)
CPLD_CPSW_RGMII1_CRS_1V8: length 6.1
  BOTTOM w0.191: U85.14 70.02,110.65 70.7,111.34 70.7,112.41 71.44,113.15 U80.15
CPLD_CPSW_RGMII2_BCLK: length 169.8
  TOP w0.191: v1(124.84,43.11) J19.48 ; v1(71.33,119.36) 70.73,119.36 70.3,118.93 70.3,113.69 70.76,113.24 U29.2
  L03_SIG01 w0.076: v1(124.84,43.11) 124.65,43.29 124.65,61.91 131.67,68.93 131.67,94.97 125.55,101.09 120.37,101.09 119.34,102.11 116.78,102.11 115,100.33 99.5,100.33 98.12,98.95 96.51,98.95 95.05,97.49 77.77,97.49 76.33,98.93 76.33,98.94 76.33,99.24 76.33,99.24 76.18,99.38 76.18,103.05 75.43,103.81 75.43,104.09 75.41,104.11 75.41,104.41 75.75,104.75 76.44,104.75 78.43,106.74 78.43,111.89 79.94,113.4 80.9,113.4 84.79,117.29 84.79,123.07 v1(84.47,123.38)
  BOTTOM w0.191: v1(84.47,123.38) 83.86,123.99 75.47,123.99 71.33,119.86 v1(71.33,119.36)
CPLD_CPSW_RGMII2_BCLK_1V8: length 2.5
  TOP w0.191: U29.7 74.11,113.24 74.13,113.21 v1(74.16,113.21)
  BOTTOM w0.191: v1(74.16,113.21) 74.16,113.19 74.81,112.54 U84.36
CPLD_CPSW_RGMII2_COL: length 144.1
  TOP w0.191: v1(118.04,41.47) J19.14
  L03_SIG01 w0.076: v1(118.04,41.47) 118.46,41.47 124.02,47.03 124.02,64.71 126.69,67.38 126.69,68.7 128.7,70.71 128.7,76.67 130.13,78.11 130.13,94.76 124.3,100.58 120.32,100.58 120.1,100.8 118.27,100.8 117.39,99.92 100.01,99.92 96.85,96.76 85.66,96.76 85.37,97.06 77.84,97.06 77.69,97.06 75.97,98.78 75.97,99.09 75.97,99.09 75.8,99.26 75.8,99.7 74.48,101.02 74.48,104.42 76.95,106.89 76.95,112.31 78.2,113.56 78.2,115.77 77.48,116.49 76.17,116.49 v1(75.78,116.1)
  BOTTOM w0.191: v1(75.78,116.1) 75.67,116.21 74.4,116.21 74.16,116.45 U80.9
CPLD_CPSW_RGMII2_COL_1V8: length 9.4
  BOTTOM w0.191: U80.12 72.65,115.25 72.84,115.06 72.84,114.6 72.76,114.52 72.76,114.14 72.84,114.07 72.84,112.87 72.17,112.2 72.17,110.76 70.74,109.34 69.21,109.34 69.03,109.15 U85.17
CPLD_CPSW_RGMII2_CRS: length 145.5
  TOP w0.191: J19.30 v1(121.24,43.02)
  L03_SIG01 w0.076: v1(121.24,43.02) 121.24,43.02 123.42,43.02 124.43,44.04 124.43,64.18 127.1,66.85 127.1,68.59 128.94,70.43 128.94,76.43 130.42,77.91 130.42,95.06 124.69,100.8 120.35,100.8 119.92,101.23 116.16,101.23 115.05,100.11 99.68,100.11 96.51,96.94 85.73,96.94 85.44,97.24 77.77,97.24 76.15,98.85 76.15,99.02 76.15,99.02 76.15,99.16 76.15,99.16 75.98,99.33 75.98,101.82 74.7,103.1 74.7,104.39 77.16,106.85 77.16,112.08 79.5,114.42 v1(79.5,116.18)
  BOTTOM w0.191: U80.8 72.24,117.49 72.38,117.63 75.01,117.63 75.88,116.76 78.92,116.76 v1(79.5,116.18)
CPLD_CPSW_RGMII2_CRS_1V8: length 7.5
  BOTTOM w0.191: U80.13 72.24,112.86 71.86,112.48 71.56,112.17 71.56,110.96 70.25,109.65 U85.16
CPLD_ECAP0_APWM_OUT: length 60.6
  TOP w0.132: U47.C16 v1(68.36,83.99)
  L03_SIG01 w0.076: v1(68.36,83.99) 66.88,83.99 65.86,85.02 62.88,85.02 61.79,86.1 60.93,86.1 59.16,87.87 59.16,93.62 58.91,93.88 58.91,98.5 55.8,101.61 55.8,103.78 56.31,104.29 56.31,115.59 v1(55.33,116.57)
  BOTTOM w0.191: v1(55.33,116.57) 55.65,116.57 56.58,117.5 59.73,117.5 60.79,118.56 65.34,118.56 67.52,116.38 67.52,113.16 67.29,112.94 U85.11
CPLD_ECAP1_APWM_OUT: length 65.9
  TOP w0.132: U47.E14 v1(69.96,82.39)
  L03_SIG01 w0.076: v1(55.61,117.32) 55.33,117.32 54.93,116.92 54.93,115.47 56.13,114.27 56.13,104.73 55.62,104.22 55.62,101.54 58.73,98.43 58.73,93.8 58.98,93.55 58.98,87.79 60.98,85.79 61.85,85.79 62.8,84.84 65.77,84.84 67.04,83.57 69.31,83.57 69.58,83.3 69.58,82.77 v1(69.96,82.39)
  BOTTOM w0.191: v1(55.61,117.32) 56.21,117.92 59.58,117.92 61.05,119.38 66.31,119.38 67.9,117.78 67.9,112.51 67.79,112.4 U85.12
CPLD_ECAP2_APWM_OUT: length 54.1
  TOP w0.132: U47.D15 v1(69.16,83.19)
  TOP w0.191: v1(54.56,113.27) 57.78,113.27 58.01,113.04 59.89,113.04 60.63,112.31 63.08,112.31 63.39,112.62 v1(65.29,112.62)
  L03_SIG01 w0.076: v1(54.56,113.27) 53.78,112.49 53.78,111.75 54.53,111 54.53,109.31 55.36,108.48 55.36,107.39 54.84,106.86 54.84,101.15 57.8,98.18 57.8,88.14 60.15,85.79 60.15,85.35 61.13,84.38 65.67,84.38 67.23,82.82 68.78,82.82 v1(69.16,83.19)
  BOTTOM w0.191: U85.7 v1(65.29,112.62)
CPLD_MCASP1_AFSR: length 62
  TOP w0.191: R169.2 68.7,101.37 67.34,102.73 v1(66.57,102.73) ; v1(25.14,120.96) 24.95,121.16 J12.41
  BOTTOM w0.191: U85.27 66.79,102.92 66.6,102.73 v1(66.57,102.73) 66.27,102.43 63.86,102.43 62.49,101.06 56.68,101.06 55.74,102 52.15,102 51.05,103.09 49.77,103.09 48.3,104.56 48.3,105.42 46.2,107.51 35.32,107.51 25.14,117.69 v1(25.14,120.96)
CPLD_MCASP1_AFSX: length 60.1
  TOP w0.191: v1(66.95,102.12) 66.14,102.12 64.94,100.92 R182.2 ; v1(25.89,116.23) 25.76,116.36 J12.39
  BOTTOM w0.191: U85.26 67.29,102.47 v1(66.95,102.12) 66.5,102.12 66.43,102.05 64.05,102.05 62.63,100.62 56.53,100.62 55.54,101.62 51.39,101.62 50.62,102.39 49.82,102.39 45.09,107.11 35.01,107.11 v1(25.89,116.23)
CPLD_MCASP2_AFSR_R: length 10
  TOP w0.132: U47.T20 v1(79.56,87.19)
  BOTTOM w0.191: R497.1 83.55,94.75 79.56,90.76 v1(79.56,87.19)
CPLD_OBSCLK0: length 29.8
  TOP w0.191: R209.2 89.15,94.37 89.48,94.7 89.48,95.61 92.36,98.5 v1(92.36,101.59)
  L03_SIG01 w0.076: v1(82.71,107.04) 81.61,107.04 79.62,105.04 v1(79.62,104.37) 79.93,104.68 80.59,104.68 82.35,102.92 85.95,102.92 87.28,101.59 v1(92.36,101.59)
  BOTTOM w0.191: RA7.6 80.08,103.98 79.7,104.37 v1(79.62,104.37) ; U84.12 v1(82.71,107.04)
CPLD_OBSCLK0_R: length 14.7
  TOP w0.132: U47.R20 v1(78.76,87.19)
  TOP w0.191: v1(89.39,91.87) 89.15,92.11 R209.1
  L03_SIG01 w0.076: v1(89.39,91.87) 88.94,92.33 83.09,92.33 78.76,87.99 v1(78.76,87.19)
CPLD_OBSCLK1: length 147.3
  TOP w0.191: R204.2 45.34,94.15 45.34,95.08 44.48,95.93 44.24,95.93 40.74,95.93 38.98,94.17 v1(38.73,94.17)
  L03_SIG01 w0.076: v1(38.73,94.17) 38.45,94.45 38.45,97.64 44.2,103.39 44.2,113.52 43.58,114.14 43.58,122.46 44.44,123.32 44.44,130.62 43.64,131.42 43.64,141.04 44.55,141.94 44.55,145.11 v1(44.21,145.46) ; v1(74.17,109.15) 74.75,109.74 74.75,112.34 75.41,113 75.41,113.26 75.17,113.5 74.57,113.5 73.86,114.21 73.86,115.12 74.41,115.67 74.41,117.3 75.09,117.98 78.79,117.98 81.87,121.07 81.87,123.01 75.82,129.06 75.82,146.2 v1(76.66,147.04)
  BOTTOM w0.191: U84.29 74.28,109.04 v1(74.17,109.15) ; v1(44.21,145.46) 47.7,145.46 48.6,146.36 54.77,146.36 55.77,145.36 60.85,145.36 63.01,147.53 71.88,147.53 72.37,147.04 v1(76.66,147.04)
CPLD_UART0_RXD: length 154
  TOP w0.191: v1(26.55,35.58) 26.85,35.88 TP97.1 27.71,35.45 27.71,35.23 27.91,35.02 R361.2
  L03_SIG01 w0.076: v1(26.55,35.58) 26.55,65.61 25.41,66.76 25.41,82.89 27.09,84.57 27.09,99.76 41.22,113.9 41.22,127.8 v1(42.4,128.98) ; v1(68.2,129.21) 68.2,121.4 67.2,120.4 67.2,114.83 67.38,114.65 67.38,110.84 v1(69.35,108.86)
  BOTTOM w0.191: v1(69.35,108.86) 69.14,108.65 U85.18 ; v1(26.55,35.58) 26.55,34.76 26.74,34.56 U126.8 ; v1(68.2,129.21) 68.03,129.38 59.52,129.38 58.86,130.04 43.46,130.04 v1(42.4,128.98)
CPLD_UART0_TXD: length 163.5
  L03_SIG01 w0.076: v1(24.05,31.88) 25.07,32.9 25.07,38.15 24.32,38.9 24.32,47.77 23.81,48.28 23.81,82.05 26.86,85.1 26.86,100.08 40.97,114.19 40.97,128.75 v1(41.42,129.21) ; v1(69.4,129.27) 69.4,121.99 67.46,120.05 67.46,115.1 67.62,114.94 67.62,111.17 69.73,109.06 69.73,108.37 v1(69.54,108.17)
  BOTTOM w0.191: U126.6 26.18,33.76 25.82,34.12 R631.2 24.59,34.12 24.05,33.57 TP117.1 v1(24.05,31.88) ; U85.19 69.52,108.15 v1(69.54,108.17) ; v1(41.42,129.21) 42.65,130.44 59.13,130.44 59.77,129.8 68.87,129.8 v1(69.4,129.27)
CPSW_ETH_INTN: length 121.4
  TOP w0.191: v1(83.51,38.23) 83.51,36.21 v1(83.8,35.93) ; U32.11 44.83,102.78 42.98,100.92 v1(42.96,100.92) ; v1(57.18,31.08) 56.44,31.82 56.44,35.03 v1(56.85,35.44)
  L03_SIG01 w0.076: v1(42.96,100.92) 42.41,100.37 42.41,100.35 40.87,98.81 40.87,79.52 41.23,79.16 41.23,74.71 42.72,73.22 42.72,68.31 42.49,68.08 42.49,66.45 40.42,64.38 40.42,59.73 41.36,58.8 42.37,58.8 44.02,57.15 44.02,50.8 46.61,48.2 46.61,47.71 51.62,42.7 53.33,42.7 55.64,40.38 55.64,36.65 v1(56.85,35.44)
  BOTTOM w0.191: v1(83.51,38.23) 83.51,39.03 83.53,39.04 R621.1 ; v1(57.18,31.08) 64.45,31.08 66.25,32.88 68.7,32.88 69.33,32.25 71.98,32.25 73.59,30.63 81.13,30.63 82.41,31.92 82.41,33.47 83.8,34.85 v1(83.8,35.93)
CPSW_ETH_INTN_1V8: length 63.2
  TOP w0.191: R205.1 70.96,94.4 69.74,95.62 69.74,99.95 69.22,100.48 69.22,103.12 68.84,103.5 65.03,103.5 64.78,103.24 62.83,103.24 61.18,104.9 59.99,104.9 59.38,105.51 59.38,107.49 58.31,108.56 58.31,109.14 57.43,110.01 53.48,110.01 52.74,110.76 52.74,112.83 51.49,114.08 51.12,114.08 49.26,112.22 48.7,112.22 48.32,112.6 48.32,112.63 48.32,112.63 48.32,113 48.32,113.01 48.32,116.4 v1(48.41,116.49) ; v1(44.33,116.48) 44.4,116.41 44.4,111.9 42.93,110.43 42.93,103.56 42.15,102.78 U32.4
  BOTTOM w0.191: v1(44.33,116.48) 48.4,116.48 v1(48.41,116.49)
CPSW_RGMII1_BRD_CONN_DET: length 2
  TOP w0.191: R355.2 89.46,43.55 90.01,43 J18.36
CPSW_RGMII1_ETH1_CLK: length 33.6
  TOP w0.191: v1(89.26,34.49) 88.56,33.79 85.43,33.79 84.93,34.29 83.05,34.29 81.38,35.96 v1(80.15,35.96) ; v1(71.73,37.4) 71.74,37.39 71.74,37.02 71.55,36.83 R359.2 ; J18.28 88.41,41.82 88.24,41.66 88.24,41.03 88.43,40.84 90.06,40.84 v1(90.43,40.47)
  BOTTOM w0.191: v1(71.73,37.4) 72.04,37.71 72.85,37.71 75.89,34.66 78.84,34.66 v1(80.15,35.96) ; v1(89.26,34.49) 89.26,34.81 90.26,35.81 90.93,35.81 91.93,36.81 91.93,38.97 v1(90.43,40.47)
CPSW_RGMII1_MDC: length 6.4
  TOP w0.191: J18.20 86.81,43.89 84.49,46.21 R342.2 84.49,46.91 84.76,47.17 R338.2
CPSW_RGMII1_MDIO: length 5.8
  TOP w0.191: J18.22 87.21,44.48 86.6,45.09 R343.1 87.39,46.57 87.58,46.77 R340.2
CPSW_RGMII1_RD0: length 74.2
  TOP w0.14: U47.AB16 84.4,83.59 85.2,84.39 86.4,84.39 87.37,83.42 v1(87.37,83.37)
  TOP w0.191: v1(87.34,38.59) 87.61,38.86 J18.23
  L03_SIG01 w0.076: v1(87.37,83.37) 87.37,84.44 87.44,84.52 87.74,84.52 87.83,84.43 87.83,83.61 88.12,83.31 88.75,83.31 89.24,82.82 91.26,82.82 93.35,80.72 93.35,78.08 93.05,77.77 93.05,58.25 81.55,46.75 81.55,37.69 81.99,37.25 84.28,37.25 84.71,37.68 88.01,37.68 88.92,38.59 88.92,39.03 88.79,39.16 86.86,39.16 86.71,39.01 86.71,38.72 86.84,38.59 v1(87.34,38.59)
CPSW_RGMII1_RD1: length 73.7
  TOP w0.132: U47.V15 v1(81.16,83.19)
  TOP w0.191: J18.25 88.01,38.51 86.47,36.97 86.47,36.44 v1(86.49,36.42)
  L03_SIG01 w0.076: v1(81.16,83.19) 81.79,82.56 83.22,82.56 83.97,83.32 84.85,83.32 87.08,81.09 89.33,81.09 90.13,80.3 90.13,79.12 90.98,78.27 90.98,58.28 80.57,47.87 80.57,36.16 83.55,33.17 85.22,33.17 86.49,34.44 v1(86.49,36.42)
CPSW_RGMII1_RD2: length 73.6
  TOP w0.132: U47.W15 v1(81.96,83.19)
  TOP w0.191: J18.27 88.41,38.14 87.33,37.06 v1(87.33,36.58)
  L03_SIG01 w0.076: v1(81.96,83.19) 82.34,82.82 82.97,82.82 83.76,83.6 84.9,83.6 87.11,81.39 89.43,81.39 90.46,80.36 90.46,79.38 91.56,78.27 91.56,58.39 80.8,47.62 80.8,36.28 82.98,34.1 85.54,34.1 85.83,34.38 85.83,36.66 86,36.84 86.92,36.84 87,36.92 87.24,36.92 87.33,36.83 v1(87.33,36.58)
CPSW_RGMII1_RD3: length 73.6
  TOP w0.132: 84.39,82.39 81.16,82.39 U47.V14
  TOP w0.14: v1(88.5,82.78) 86.99,82.78 86.38,82.17 84.62,82.17 84.39,82.39
  TOP w0.191: J18.29 88.81,38.33 v1(89.23,37.9)
  L03_SIG01 w0.076: v1(88.5,82.78) 88.73,82.54 91.19,82.54 92.85,80.89 92.85,78.57 92.17,77.89 92.17,76.65 92.78,76.04 92.78,58.46 81.32,46.99 81.32,37.42 81.85,36.88 84.65,36.88 85.16,37.4 89.53,37.4 89.69,37.56 89.69,37.72 89.51,37.9 v1(89.23,37.9)
CPSW_RGMII1_RESETN: length 37.7
  TOP w0.191: v1(85.04,41.25) 85.21,41.42 J18.12 ; v1(70.68,28.57) 70.04,28.57 69.8,28.81 R373.1 69,29.15 69,29.15 U68.4
  BOTTOM w0.191: v1(70.68,28.57) 81.89,28.57 88.57,35.25 88.9,35.25 89.95,36.31 90.75,36.31 91.43,37 91.43,38.62 90.48,39.57 86.17,39.57 85.45,40.29 85.45,40.9 85.1,41.25 v1(85.04,41.25)
CPSW_RGMII1_RX_DV: length 74
  TOP w0.132: U47.AA15 83.56,83.19 84.74,83.19 85.29,83.74 v1(85.49,83.74)
  TOP w0.191: J18.45 92.01,36.6 91.32,35.91 89.41,35.91 v1(88.76,36.55)
  L03_SIG01 w0.076: v1(85.49,83.74) 86.48,82.75 87.93,82.75 88.42,82.26 89.61,82.26 90.33,81.54 90.8,81.54 91.8,80.55 91.8,76.63 92.53,75.9 92.53,58.79 81.03,47.28 81.03,37.29 81.69,36.63 84.88,36.63 85.41,37.16 88.15,37.16 v1(88.76,36.55)
CPSW_RGMII1_RXC: length 73.6
  TOP w0.132: U47.AA16 83.56,83.99 84.2,83.99
  TOP w0.14: 84.2,83.99 85.04,84.84 87.26,84.84 v1(88.32,83.78)
  TOP w0.191: v1(86.6,38.13) 86.81,38.34 J18.19
  L03_SIG01 w0.076: v1(86.6,38.13) 84.33,38.13 83.74,37.55 82.09,37.55 81.86,37.77 81.86,46.46 94.19,58.79 94.19,59.6 93.99,59.81 93.48,59.81 93.36,59.93 93.36,60.1 93.48,60.22 94.05,60.22 94.19,60.36 94.19,60.53 94.1,60.62 93.48,60.62 93.36,60.74 93.36,60.91 93.48,61.03 94.05,61.03 94.19,61.17 94.19,61.34 94.1,61.44 93.48,61.44 93.36,61.55 93.36,61.72 93.48,61.84 94.05,61.84 94.19,61.98 94.19,62.15 94.1,62.25 93.48,62.25 93.36,62.37 93.36,62.54 93.48,62.65 94.05,62.65 94.19,62.8 94.19,74.93 94.68,75.42 94.68,76.04 94.2,76.52 94.2,80.31 91.41,83.1 90.89,83.1 89.41,83.1 88.73,83.78 v1(88.32,83.78)
CPSW_RGMII1_TD0: length 64.4
  TOP w0.191: J18.7 84.41,40.46 v1(84.18,40.69)
  L03_SIG01 w0.076: v1(96.19,82.01) 96.19,82.34 95.5,83.02 94.32,83.02 94.01,82.72 94.01,81.54 94.76,80.79 94.76,77.19 95.56,76.39 95.56,72.38 95,71.82 95,58.43 85.34,48.76 85.34,42.48 84.55,41.69 84.55,41.07 v1(84.18,40.69)
  BOTTOM w0.191: v1(96.19,82.01) 96.19,84.25 93.3,87.14 89.11,87.14 R530.2
CPSW_RGMII1_TD1: length 64.9
  TOP w0.191: J18.9 84.81,38.97 v1(84.82,38.96)
  L03_SIG01 w0.076: v1(97.63,81.04) 97.36,80.77 97.36,74.2 96.87,73.71 96.87,71.87 97.08,71.65 97.08,44.3 97.12,44.26 97.12,43.18 95.53,41.59 94.37,41.59 92.21,39.43 85.37,39.43 84.89,38.96 v1(84.82,38.96)
  BOTTOM w0.191: v1(97.63,81.04) 97.62,81.03 94.73,81.03 93.09,82.66 89.95,82.66 89.05,83.56 89.05,83.72 88.44,84.33 88.1,84.33 87.75,83.98 R535.2
CPSW_RGMII1_TD2: length 70.2
  TOP w0.191: J18.11 85.21,40.24 v1(84.95,40.5)
  L03_SIG01 w0.076: v1(84.95,40.5) 85.6,41.15 85.6,43.81 85.73,43.94 86.53,43.94 86.67,44.08 86.67,44.27 86.53,44.4 85.73,44.4 85.6,44.53 85.6,44.72 85.73,44.86 86.53,44.86 86.67,44.99 86.67,45.18 86.53,45.31 85.73,45.31 85.6,45.45 85.6,45.64 85.73,45.77 86.53,45.77 86.67,45.9 86.67,46.09 86.53,46.23 85.73,46.23 85.6,46.36 85.6,46.55 85.73,46.69 86.53,46.69 86.67,46.82 86.67,47.01 86.53,47.14 85.73,47.14 85.6,47.28 85.6,48.57 95.28,58.25 95.28,71.72 95.79,72.24 95.79,76.56 95.29,77.07 95.29,81.25 v1(94.99,81.56)
  BOTTOM w0.191: R537.2 84.91,83.84 85.72,84.66 87.39,84.66 89.37,86.64 93.11,86.64 94.99,84.76 v1(94.99,81.56)
CPSW_RGMII1_TD3: length 64.4
  TOP w0.191: J18.13 85.61,40.22 v1(85.93,40.54)
  L03_SIG01 w0.076: v1(85.93,40.54) 86.15,40.54 87.07,41.45 87.07,43.2 87.19,43.32 87.79,43.32 87.9,43.44 87.9,43.6 87.79,43.72 87.19,43.72 87.07,43.84 87.07,44.01 87.19,44.13 87.79,44.13 87.9,44.25 87.9,44.42 87.79,44.54 87.19,44.54 87.07,44.66 87.07,44.82 87.19,44.94 87.79,44.94 87.9,45.06 87.9,45.23 87.79,45.35 87.19,45.35 87.07,45.47 87.07,45.64 87.19,45.76 87.79,45.76 87.9,45.88 87.9,46.04 87.79,46.16 87.19,46.16 87.07,46.28 87.07,46.45 87.19,46.57 87.79,46.57 87.9,46.69 87.9,46.86 87.79,46.98 87.19,46.98 87.07,47.09 87.07,47.26 87.19,47.38 87.79,47.38 87.9,47.5 87.9,47.67 87.79,47.79 87.19,47.79 87.07,47.91 87.07,48.08 87.19,48.19 87.79,48.19 87.9,48.31 87.9,48.48 87.79,48.6 87.19,48.6 87.07,48.72 87.07,49.63 95.51,58.06 95.51,71.46 96.02,71.97 96.02,76.77 95.66,77.13 95.66,81.85 95.17,82.34 v1(94.44,82.34)
  BOTTOM w0.191: v1(94.44,82.34) 94.44,83.66 91.93,86.16 91.35,86.16 91.19,86 90.45,86 R529.2
CPSW_RGMII1_TX_EN: length 73.1
  TOP w0.132: U47.W16 v1(81.96,83.99)
  TOP w0.191: v1(87.57,40.73) 87.98,40.33 89.82,40.33 90.01,40.14 J18.35
  L03_SIG01 w0.076: v1(81.96,83.99) 82.37,84.41 82.37,84.94 82.64,85.21 84.84,85.21 85.85,86.22 91.83,86.22 94.27,83.78 95.25,83.78 96.66,82.37 96.66,79.4 96.01,78.75 96.01,77.27 96.25,77.02 96.25,71.76 95.73,71.24 95.73,57.64 90.16,52.07 90.16,49.19 90.3,49.05 90.96,49.05 91.1,48.92 91.1,48.71 90.99,48.6 90.29,48.6 90.16,48.46 90.16,48.27 90.3,48.14 90.96,48.14 91.1,48 91.1,47.81 90.96,47.68 90.29,47.68 90.16,47.55 90.16,47.36 90.3,47.22 90.96,47.22 91.1,47.09 91.1,46.9 90.96,46.77 90.29,46.77 90.16,46.63 90.16,46.45 90.3,46.31 90.96,46.31 91.1,46.17 91.1,45.98 90.96,45.85 90.28,45.85 90.16,45.74 90.16,43.32 v1(87.57,40.73)
CPSW_RGMII1_TXC: length 68
  TOP w0.191: v1(83.49,40.91) 83.54,40.86 83.54,40.81 83.61,40.74 J18.3 ; v1(88.52,84.84) 88.49,84.87 R239.2
  L03_SIG01 w0.076: v1(83.49,40.91) 83.49,41.78 84.2,42.49 84.2,43.95 84.32,44.07 84.52,44.07 84.64,44.18 84.64,44.35 84.52,44.47 84.32,44.47 84.2,44.59 84.2,45.51 84.32,45.63 84.83,45.63 84.95,45.75 84.95,45.91 84.83,46.03 84.32,46.03 84.2,46.15 84.2,46.32 84.32,46.44 84.83,46.44 84.95,46.56 84.95,46.73 84.83,46.85 84.32,46.85 84.2,46.96 84.2,47.13 84.32,47.25 84.83,47.25 84.95,47.37 84.95,47.54 84.83,47.66 84.32,47.66 84.2,47.78 84.2,48.17 94.47,58.45 94.47,72.9 95.27,73.7 95.27,74.23 95.13,74.36 94.73,74.36 94.57,74.52 94.57,74.66 94.73,74.82 95.13,74.82 95.27,74.95 95.27,76 94.47,76.8 94.47,80.61 92.54,82.54 92.54,83.98 92.84,84.28 92.84,84.65 92.38,85.12 91.76,85.12 91.1,84.45 90.82,84.45 90.64,84.64 90.64,85.74 90.5,85.87 90.15,85.87 90.01,85.73 90.01,84.64 89.71,84.35 88.33,84.35 87.57,85.1 87.57,85.43 87.73,85.58 88.52,85.58 88.77,85.32 88.77,85.09 v1(88.52,84.84)
CPSW_RGMII2_BRD_CONN_DET: length 5.3
  TOP w0.191: J19.36 122.44,42.78 121.73,43.49 121.73,44.71 122.78,45.76 122.78,46.88 R341.2
CPSW_RGMII2_ETH2_CLK: length 75.9
  TOP w0.191: v1(67.16,36.62) 67.38,36.84 R358.2 ; J19.28 120.84,41.31 v1(120.79,41.26)
  L03_SIG01 w0.076: v1(120.79,41.26) 121.54,42.01 124.66,42.01 125.17,41.5 125.17,39.84 125.38,39.63 125.38,37.68 124.8,37.11 123.05,37.11 121.36,35.41 114.31,35.41 113.43,36.29 105.15,36.29 99.91,31.06 87.84,31.06 86.37,32.53 83.68,32.53 81.79,34.43 v1(80.19,34.43)
  BOTTOM w0.191: v1(67.16,36.62) 68.16,37.63 70.85,37.63 71.81,36.66 72.79,36.66 75.31,34.14 79.91,34.14 v1(80.19,34.43)
CPSW_RGMII2_MDC: length 3
  TOP w0.191: R352.2 R356.2 118.51,43.7 119.24,42.97 J19.20
CPSW_RGMII2_MDIO: length 4.3
  TOP w0.191: J19.22 119.64,44.63 119.96,44.95 R351.1 R345.2
CPSW_RGMII2_RD0: length 84.2
  TOP w0.132: U47.AA21 v1(83.56,87.99)
  TOP w0.191: J19.23 120.04,38.62 120.32,38.34 v1(120.32,37.57)
  L03_SIG01 w0.076: v1(83.56,87.99) 83.95,88.39 84.5,88.39 84.8,88.09 94.85,88.09 101.74,81.2 101.74,79.31 103.13,77.92 103.13,72.73 102.93,72.53 102.93,71.32 103.06,71.19 103.38,71.19 103.51,71.05 103.51,70.86 103.38,70.73 103.06,70.73 102.93,70.59 102.93,70.4 103.06,70.27 103.38,70.27 103.51,70.14 103.51,69.95 103.38,69.81 103.06,69.81 102.93,69.68 102.93,69.49 103.06,69.36 103.38,69.36 103.51,69.22 103.51,69.03 103.38,68.9 103.06,68.9 102.93,68.77 102.93,68.58 103.06,68.44 103.38,68.44 103.51,68.31 103.51,68.12 103.38,67.99 103.06,67.99 102.93,67.85 102.93,67.66 103.06,67.53 103.38,67.53 103.51,67.39 103.51,67.2 103.38,67.07 103.06,67.07 102.93,66.94 102.93,66.75 103.06,66.61 103.38,66.61 103.51,66.48 103.51,66.29 103.38,66.16 103.06,66.16 102.93,66.02 102.93,65.83 103.06,65.7 103.26,65.7 103.4,65.55 103.4,65.4 103.25,65.24 103.06,65.24 102.93,65.11 102.93,59.15 113.9,48.18 113.9,46.92 114.68,46.14 114.68,44.95 114.94,44.68 115.87,44.68 116.22,44.33 116.22,44.16 115.93,43.87 115.93,43.7 117.61,42.02 117.61,41.17 117.92,40.86 120.36,40.86 121.09,40.12 121.09,38.35 v1(120.32,37.57)
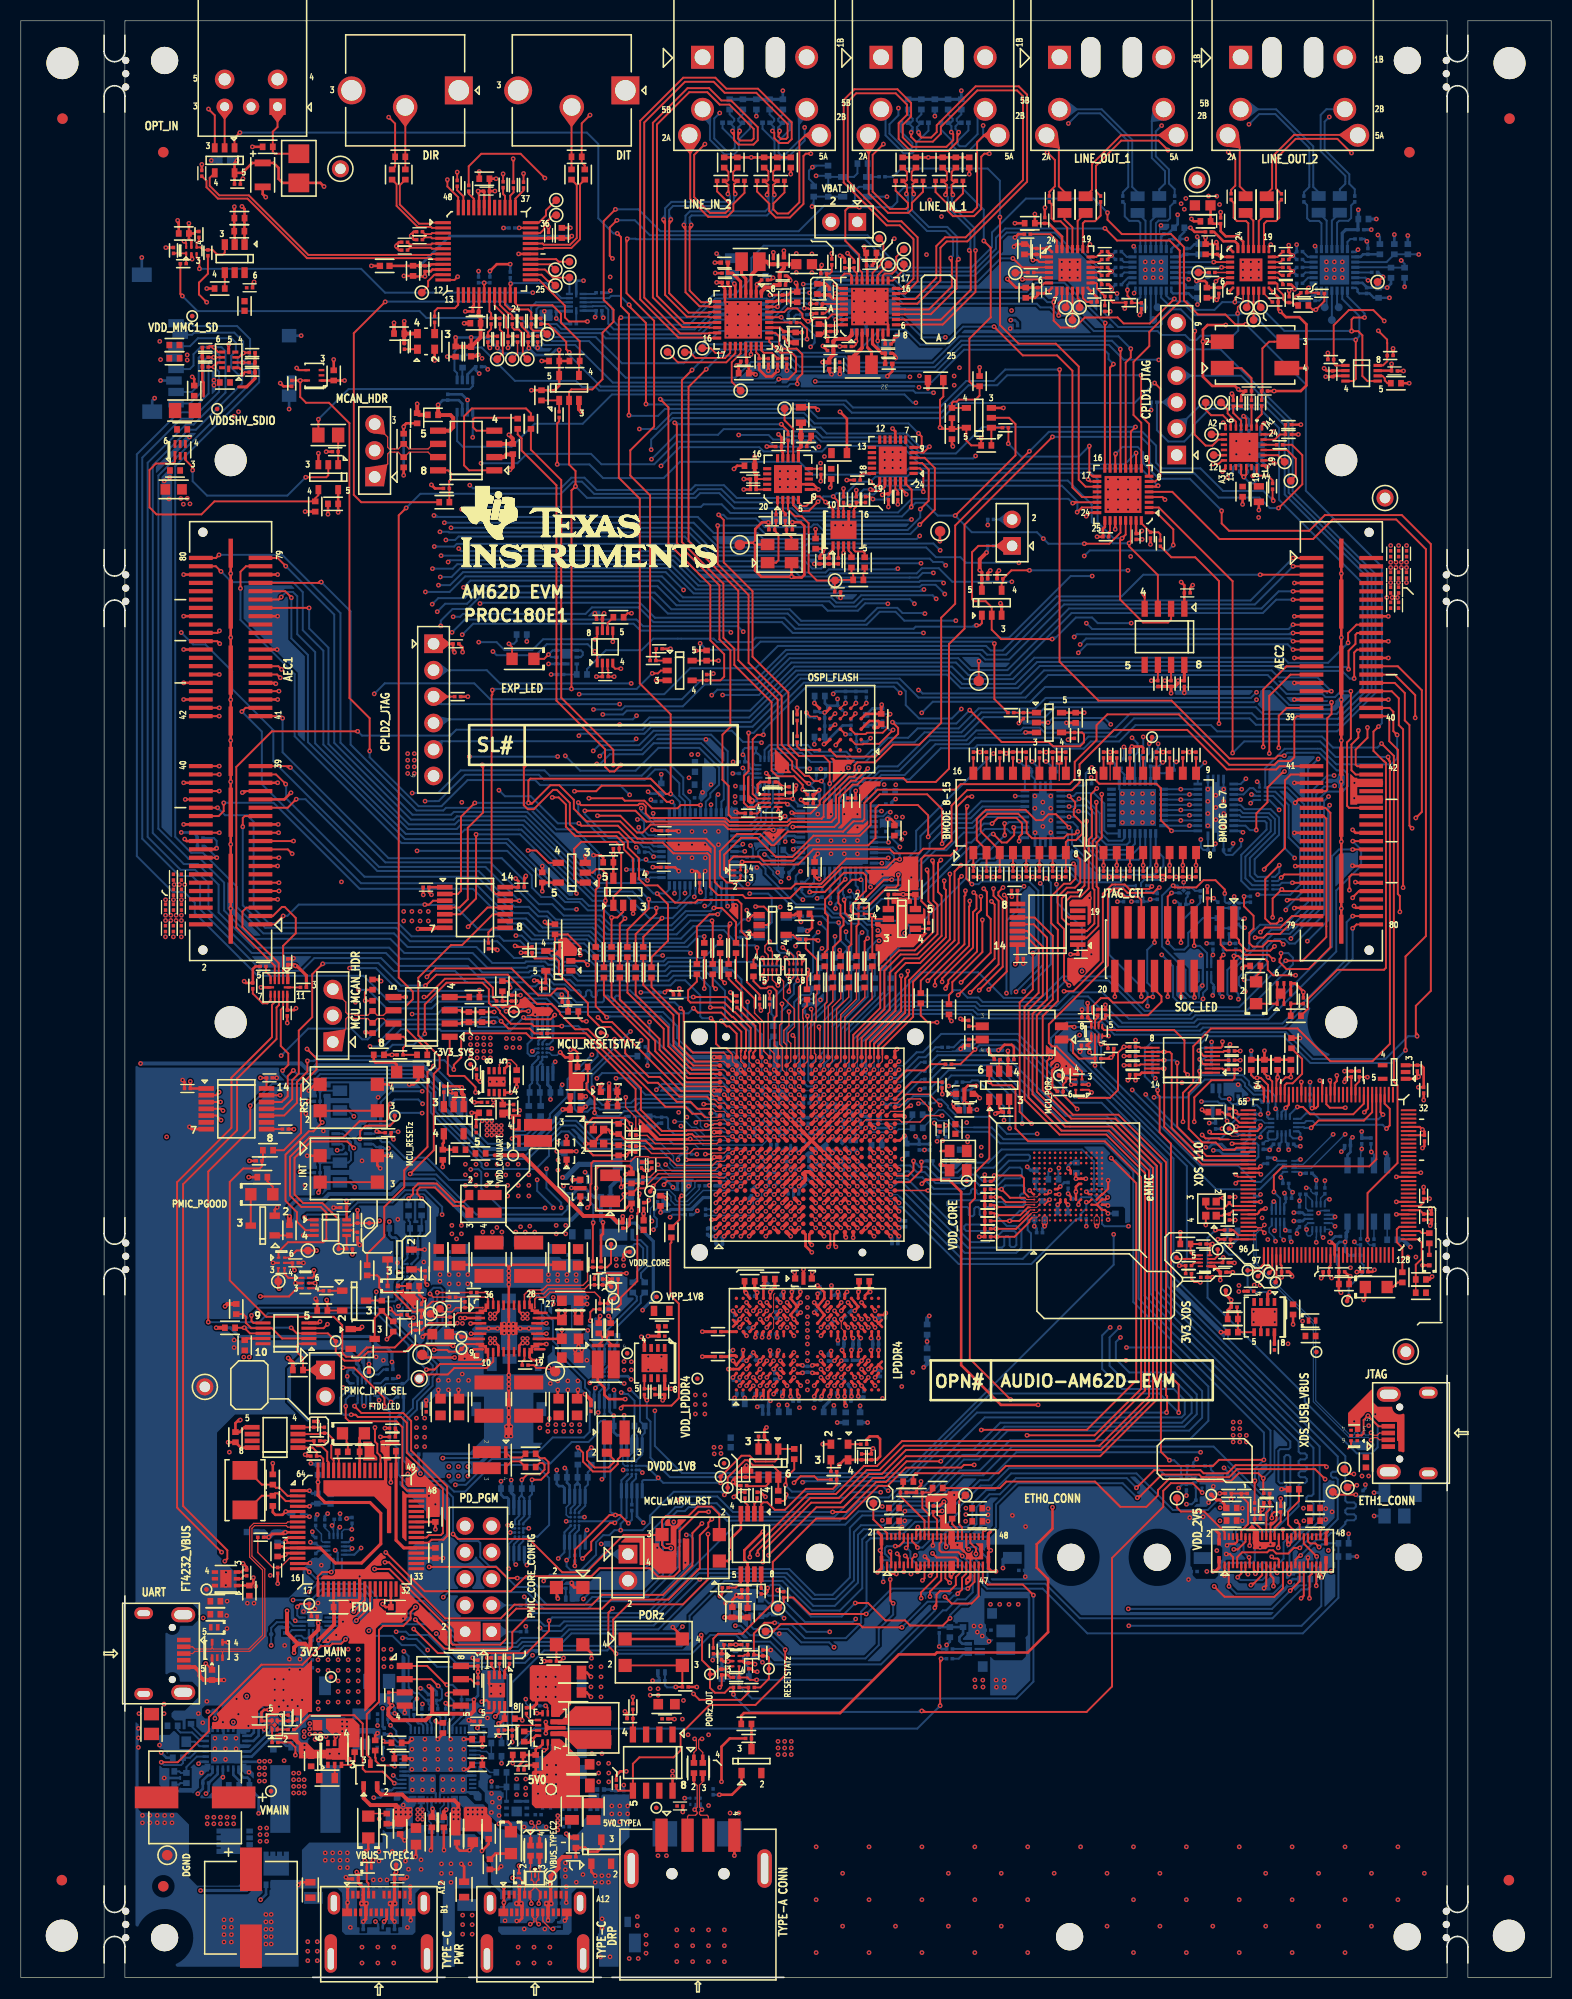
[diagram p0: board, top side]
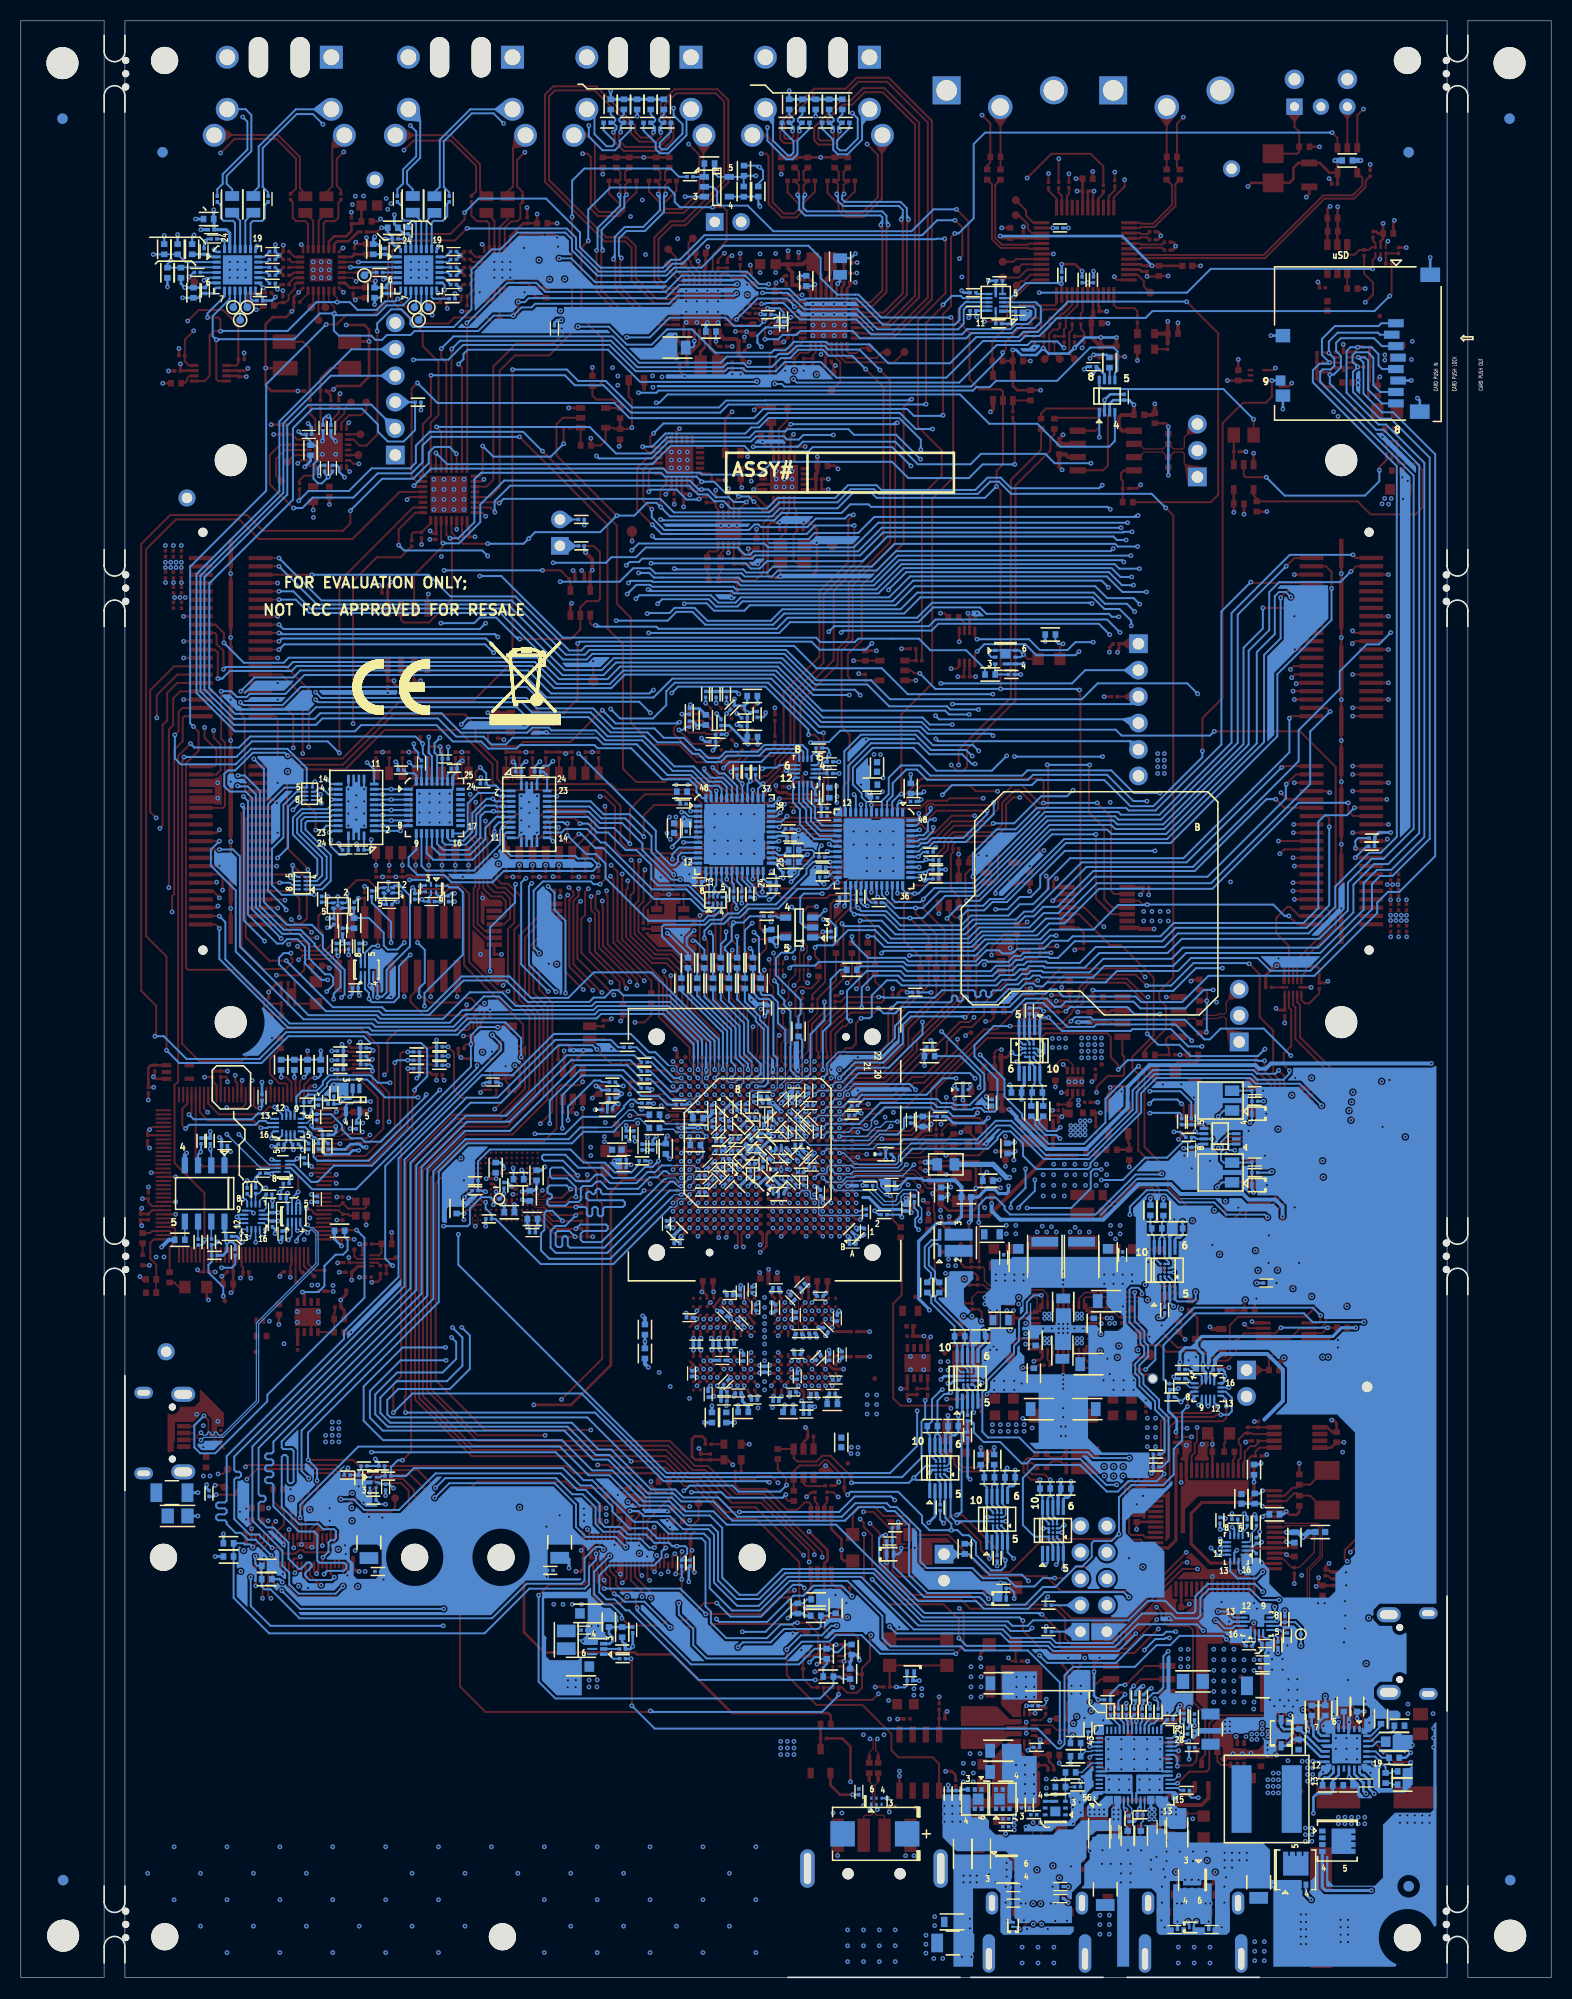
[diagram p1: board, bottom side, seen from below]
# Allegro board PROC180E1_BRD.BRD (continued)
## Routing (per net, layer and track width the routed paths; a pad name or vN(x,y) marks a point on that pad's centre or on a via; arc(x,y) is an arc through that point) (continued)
CPSW_RGMII2_RD1: length 83.7
  TOP w0.132: U47.Y20 v1(82.76,87.19)
  TOP w0.191: v1(120.67,38.86) 120.44,39.09 J19.25
  L03_SIG01 w0.076: v1(120.67,38.86) 119.98,39.55 117.66,39.55 117.06,40.16 117.06,41.66 115.94,42.78 114.87,42.78 114.22,43.42 114.22,44.3 112.47,46.05 112.47,48.45 102.71,58.22 102.54,58.22 102.22,57.9 102.05,57.9 101.93,58.02 101.93,58.18 102.25,58.5 102.25,58.67 102.13,58.79 101.96,58.79 101.64,58.47 101.48,58.47 101.36,58.59 101.36,58.76 101.67,59.08 101.67,59.25 101.56,59.37 101.39,59.37 101.07,59.05 100.9,59.05 100.78,59.17 100.78,59.33 101.1,59.65 101.1,59.82 100.5,60.42 100.5,64.78 101.02,65.3 101.02,66.88 101.16,67.02 101.33,67.02 101.46,67.15 101.46,67.34 101.33,67.47 101.16,67.47 101.02,67.61 101.02,67.8 101.16,67.93 101.33,67.93 101.46,68.06 101.46,68.25 101.33,68.39 101.16,68.39 101.02,68.52 101.02,68.71 101.16,68.85 101.33,68.85 101.46,68.98 101.46,69.17 101.33,69.3 101.16,69.3 101.02,69.44 101.02,69.63 101.16,69.76 101.37,69.76 101.51,69.89 101.51,70.08 101.37,70.22 101.16,70.22 101.02,70.35 101.02,70.54 101.16,70.67 101.37,70.67 101.51,70.81 101.51,71 101.37,71.13 101.16,71.13 101.02,71.27 101.02,71.45 101.16,71.59 101.37,71.59 101.51,71.72 101.51,71.91 101.37,72.05 101.16,72.05 101.02,72.18 101.02,72.37 101.16,72.5 101.37,72.5 101.51,72.64 101.51,72.81 101.36,72.96 101.16,72.96 101.02,73.09 101.02,74.48 101.87,75.32 101.87,77.56 100.96,78.47 100.96,81.19 94.62,87.53 84.62,87.53 84.55,87.6 83.17,87.6 v1(82.76,87.19)
CPSW_RGMII2_RD2: length 83.5
  TOP w0.132: U47.AB21 v1(84.36,87.99)
  TOP w0.191: J19.27 120.84,40.13 120.73,40.23 120.32,40.23 v1(120.15,40.4)
  L03_SIG01 w0.076: v1(84.36,87.99) 84.52,87.99 84.7,87.81 94.73,87.81 101.28,81.26 101.28,79.36 102.9,77.75 102.9,74.24 101.92,73.26 101.92,71.38 102.05,71.24 102.31,71.24 102.44,71.11 102.44,70.92 102.31,70.79 102.05,70.79 101.92,70.65 101.92,70.46 102.05,70.33 102.31,70.33 102.44,70.2 102.44,70.01 102.31,69.87 102.05,69.87 101.92,69.74 101.92,69.55 102.05,69.42 102.31,69.42 102.44,69.28 102.44,69.09 102.31,68.96 102.05,68.96 101.92,68.83 101.92,68.64 102.05,68.5 102.31,68.5 102.44,68.37 102.44,68.18 102.31,68.04 102.05,68.04 101.92,67.91 101.92,67.72 102.05,67.59 102.31,67.59 102.44,67.45 102.44,67.26 102.31,67.13 102.05,67.13 101.92,67 101.92,66.81 102.05,66.67 102.31,66.67 102.44,66.54 102.44,66.35 102.31,66.22 102.05,66.22 101.92,66.08 101.92,64.69 101.8,64.57 101.38,64.57 101.27,64.46 101.27,64.26 101.38,64.16 101.8,64.16 101.92,64.04 101.92,63.87 101.8,63.76 101.38,63.76 101.26,63.64 101.26,63.47 101.38,63.35 101.8,63.35 101.92,63.23 101.92,63.06 101.8,62.94 101.38,62.94 101.26,62.82 101.26,62.65 101.38,62.54 101.8,62.54 101.92,62.42 101.92,62.25 101.8,62.13 101.38,62.13 101.26,62.01 101.26,61.84 101.38,61.72 101.8,61.72 101.92,61.6 101.92,61.44 101.8,61.32 101.38,61.32 101.26,61.2 101.26,61.03 101.38,60.91 101.8,60.91 101.92,60.79 101.92,59.55 112.82,48.65 112.82,46.25 114.63,44.45 114.63,43.77 115.16,43.24 115.84,43.24 117.37,41.71 117.37,40.24 117.78,39.83 120.05,39.83 120.15,39.93 v1(120.15,40.4)
CPSW_RGMII2_RD3: length 83.6
  TOP w0.132: U47.AB20 v1(84.36,87.19)
  TOP w0.191: J19.29 121.24,37.38 120.41,36.56 115.63,36.56 v1(114.63,37.56)
  L03_SIG01 w0.076: v1(84.36,87.19) 84.41,87.25 94.51,87.25 100.18,81.57 100.18,76.81 100.39,76.6 100.39,75.81 100.16,75.58 100.16,71.87 100.05,71.76 100.05,71.51 100.19,71.38 100.42,71.38 100.56,71.24 100.56,71.05 100.42,70.92 100.19,70.92 100.05,70.78 100.05,70.6 100.19,70.46 100.42,70.46 100.56,70.33 100.56,70.14 100.42,70 100.19,70 100.05,69.87 100.05,69.68 100.19,69.55 100.42,69.55 100.56,69.41 100.56,69.22 100.42,69.09 100.19,69.09 100.05,68.96 100.05,68.77 100.19,68.63 100.42,68.63 100.56,68.5 100.56,68.31 100.42,68.18 100.19,68.18 100.05,68.04 100.05,67.85 100.19,67.72 100.42,67.72 100.56,67.58 100.56,67.4 100.42,67.26 100.19,67.26 100.05,67.13 100.05,66.94 100.19,66.8 100.42,66.8 100.57,66.65 100.57,66.5 100.42,66.35 100.19,66.35 100.05,66.21 100.05,66.02 100.19,65.89 100.48,65.89 100.57,65.8 100.57,65.51 100.49,65.43 100.19,65.43 100.05,65.3 100.05,58.96 110.68,48.33 110.68,45.01 113.36,42.34 113.36,38.83 v1(114.63,37.56)
CPSW_RGMII2_RSTN: length 11.2
  TOP w0.191: v1(116.51,41.11) 116.9,41.11 117.64,41.85 J19.12
  L03_SIG01 w0.076: v1(116.51,41.11) 116.51,41.66 115.85,42.32 114.59,42.32 112.97,43.95 112.97,44.45 v1(111.97,45.45)
  BOTTOM w0.191: U120.4 112.87,47.04 R607.1 112.48,45.45 v1(111.97,45.45)
CPSW_RGMII2_RX_DV: length 83.9
  TOP w0.132: U47.W18 v1(81.96,85.59)
  TOP w0.191: J19.45 v1(124.44,37.61)
  L03_SIG01 w0.076: v1(81.96,85.59) 82.37,86 84.93,86 85.59,86.66 93.65,86.66 98.13,82.17 98.13,78.71 97.93,78.5 97.93,59.92 110.04,47.8 110.04,44.86 112.63,42.27 112.63,38.4 114.35,36.68 122.1,36.68 123.03,37.61 v1(124.44,37.61)
CPSW_RGMII2_RXC: length 83.6
  TOP w0.132: U47.AA20 v1(83.56,87.19)
  TOP w0.191: v1(118.15,37.68) 118.28,37.68 119.24,38.64 J19.19
  L03_SIG01 w0.076: v1(118.15,37.68) 116.88,37.68 116.48,38.08 115.82,38.08 114.88,37.14 114.45,37.14 112.85,38.74 112.85,42.4 110.35,44.91 110.35,48.06 98.91,59.51 98.91,65.06 99.04,65.2 99.42,65.2 99.56,65.33 99.56,65.52 99.42,65.65 99.04,65.65 98.91,65.79 98.91,65.98 99.04,66.11 99.42,66.11 99.56,66.24 99.56,66.43 99.42,66.57 99.04,66.57 98.91,66.7 98.91,66.89 99.04,67.02 99.42,67.02 99.56,67.16 99.56,67.35 99.42,67.48 99.04,67.48 98.91,67.62 98.91,67.81 99.04,67.94 99.42,67.94 99.56,68.07 99.56,68.26 99.42,68.4 99.04,68.4 98.91,68.53 98.91,68.72 99.04,68.85 99.39,68.85 99.51,68.98 99.51,69.16 99.36,69.31 99.04,69.31 98.91,69.44 98.91,69.63 99.04,69.77 99.37,69.77 99.48,69.88 99.48,70.09 99.35,70.23 99.04,70.23 98.91,70.36 98.91,70.55 99.04,70.68 99.36,70.68 99.47,70.79 99.47,71 99.33,71.14 99.04,71.14 98.91,71.27 98.91,72.47 98.34,73.04 98.34,78.18 98.94,78.78 98.94,82.42 94.39,86.97 85.19,86.97 84.9,86.68 84.07,86.68 v1(83.56,87.19)
CPSW_RGMII2_TD0: length 80.5
  TOP w0.191: v1(122.86,41.25) 122.28,41.25 121.74,40.71 120.59,40.71 120.28,41.03 119.92,41.03 119.72,40.83 117.31,40.83 116.84,40.35 J19.7
  BOTTOM w0.191: R509.2 89.6,89.35 90.31,90.06 95.66,90.06 101.21,84.51 104.18,84.51 110.15,78.54 110.15,66.38 126.5,50.03 126.5,48.74 126.33,48.57 126.01,48.57 125.84,48.41 125.84,48.17 126.01,48 126.33,48 126.5,47.83 126.5,44.02 125.01,42.54 124.14,42.54 v1(122.86,41.25)
CPSW_RGMII2_TD1: length 81.6
  TOP w0.191: v1(116.88,38.43) 117.24,38.79 J19.9
  BOTTOM w0.191: R518.2 88.06,88.58 94.55,88.58 100.36,82.77 104.27,82.77 109.01,78.03 109.01,66.02 124.16,50.86 124.16,46.43 124,46.26 123.66,46.26 123.49,46.09 123.49,45.86 123.66,45.69 124,45.69 124.16,45.52 124.16,44 123.38,43.22 122.74,43.22 121.58,42.05 121.57,42.05 121.3,41.78 121.3,40.22 120.32,39.24 120.08,39.24 119.47,39.85 119.23,39.85 119.06,39.69 119.06,39.45 119.68,38.84 119.68,38.6 119.24,38.16 117.15,38.16 v1(116.88,38.43)
CPSW_RGMII2_TD2: length 82.3
  TOP w0.191: v1(117.87,38.73) 117.64,38.96 J19.11
  BOTTOM w0.191: R527.2 88.45,88.1 94.16,88.1 100.07,82.2 104.14,82.2 108.52,77.82 108.52,65.67 122.74,51.44 122.74,50.5 122.91,50.33 123.36,50.33 123.52,50.16 123.52,49.93 123.36,49.76 122.91,49.76 122.74,49.59 122.74,49.35 122.91,49.19 123.36,49.19 123.52,49.02 123.52,48.78 123.36,48.62 122.91,48.62 122.74,48.45 122.74,48.21 122.91,48.04 123.36,48.04 123.52,47.88 123.52,47.64 123.36,47.47 122.91,47.47 122.74,47.31 122.74,45.26 120.31,42.83 118.84,42.83 118.53,42.52 118.53,40.04 118.31,39.82 115.93,39.82 115.74,39.62 115.74,39.3 115.99,39.05 117.55,39.05 v1(117.87,38.73)
CPSW_RGMII2_TD3: length 80.7
  TOP w0.191: J19.13 118.04,40.16 117.98,40.21 v1(117.98,40.35)
  BOTTOM w0.191: R528.2 88.75,87.62 93.71,87.62 100.03,81.31 104.31,81.31 107.94,77.67 107.94,65.48 121.94,51.48 121.94,50.91 121.77,50.74 120.97,50.74 120.8,50.57 120.8,47.64 120.97,47.47 121.2,47.47 121.37,47.64 121.37,50 121.54,50.17 121.77,50.17 121.94,50 121.94,45.18 120.28,43.52 118.43,43.52 117.96,43.06 116.93,43.06 116.73,42.85 116.73,42.19 116.93,41.99 117.23,41.99 117.45,41.77 117.45,40.88 v1(117.98,40.35)
CPSW_RGMII2_TX_EN: length 87.4
  TOP w0.132: U47.Y19 v1(82.76,86.39)
  TOP w0.191: v1(122.94,40.53) 122.85,40.53 122.44,40.12 J19.35
  BOTTOM w0.102: 84.83,87.65 84.75,87.57 84.14,87.57 83.98,87.41 83.98,87.03 83.74,86.8 83.16,86.8 v1(82.76,86.39)
  BOTTOM w0.191: 84.83,87.65 86.05,88.87 86.65,88.87 88.41,90.63 95.79,90.63 99.76,86.67 102.72,86.67 110.72,78.67 110.72,67.28 115.96,62.05 115.96,61.33 127.23,50.06 127.23,45.79 127.4,45.62 128.07,45.62 128.23,45.45 128.23,45.22 128.07,45.05 127.4,45.05 127.23,44.88 127.23,44.64 127.4,44.48 128.07,44.48 128.23,44.31 128.23,44.07 128.07,43.9 127.4,43.9 127.23,43.74 127.23,43.55 126.37,42.7 125.84,42.7 125.19,42.04 124.44,42.04 v1(122.94,40.53)
CPSW_RGMII2_TXC: length 81.8
  TOP w0.191: v1(91.66,89.14) 90.25,87.73 R228.2 ; v1(116.05,37.57) 116.04,37.58 J19.3
  BOTTOM w0.191: v1(116.05,37.57) 116.76,36.85 120.31,36.85 121.22,37.76 121.22,38.88 121.87,39.54 121.87,40.99 124.76,43.88 124.76,51 109.58,66.18 109.58,78.25 103.81,84.02 100.89,84.02 95.36,89.55 92.07,89.55 v1(91.66,89.14)
CPSW_RGMII2_TXC_R: length 5.6
  TOP w0.191: U47.AB19 85.09,87.12 86.79,87.12 87.39,87.73 R228.1
CPSW_RGMII_INTN: length 49.5
  TOP w0.191: v1(83.99,41.42) 84.35,41.42 84.81,41.88 J18.10 ; R346.1 117.23,46.49 R344.2 116.28,45.95 v1(116.25,45.93) ; R346.1 R346.2 ; R346.1 117.24,46.23 117.88,45.59 117.88,43.54 117.24,42.9 J19.10
  BOTTOM w0.191: v1(116.25,45.93) 115.04,45.93 114.01,44.9 110.67,44.9 107.16,48.41 95.12,48.41 93.54,46.82 92.74,46.82 91.4,45.49 91.4,43.78 90.89,43.27 89.37,43.27 88.65,42.55 86.96,42.55 86.15,41.74 84.75,41.74 84.43,41.42 v1(83.99,41.42) 83.19,41.42 82.99,41.23 82.99,40.7 83.53,40.17 R621.2 82.73,40.07 R620.1
CPSW_RGMII_TXC_R: length 5.2
  TOP w0.191: U47.AB17 85.57,86 R239.1
CS_LM5141: length 24.1
  L03_SIG01 w0.203: v1(34.78,20.95) 31.92,20.95 27.81,16.84 17.79,16.84 v1(17,17.63)
  BOTTOM w0.203: R667.1 34.79,20.96 v1(34.78,20.95)
  BOTTOM w0.254: U128.18 18.41,19.65 18.19,19.43 18,19.43 17.48,18.92 C634.1 17.48,18.12 v1(17,17.63)
DAC_LAT_CTRL: length 9.1
  TOP w0.191: v1(81.85,142.01) 81.82,142.04 81.69,142.04 81.49,142.24 R101.2 ; v1(86.69,142.71) 86.69,144.64 86.36,144.98 U18.2
  BOTTOM w0.191: v1(81.85,142.01) 81.89,141.97 83.06,141.97 84,142.92 86.49,142.92 v1(86.69,142.71)
DEBOUNCE_GPIO_INT_MCU_SOC: length 16.3
  TOP w0.191: v1(28.59,75.39) 28.75,75.54 SW5.2 SW5.3
  BOTTOM w0.191: U98.3 30.9,81.05 31.71,80.24 31.71,80.03 31.54,79.86 31.54,79.48 31.71,79.31 31.71,78.51 31.47,78.27 Q7.2 28.8,78.27 C489.2 R559.2 D11.2 28.75,75.54 v1(28.59,75.39)
DEBOUNCE_MCU_RESETZ: length 112.1
  TOP w0.191: v1(34.93,54.84) 34.93,55.65 32.01,58.57 v1(30.94,58.57) ; SW6.2 67.09,44.47 66.35,45.22 65.03,45.22 64.12,44.31 61.96,44.31 61.59,43.95 SW6.3 ; SW6.3 61.56,42.5 57.91,42.5 54.32,38.91 52,38.91 48.8,42.11 41.98,42.11 v1(41.52,42.58) ; SW6.3 61.59,41.53 61.89,41.24 v1(62.44,41.24)
  L03_SIG01 w0.076: v1(30.39,79.46) 30.39,74.43 30.94,73.88 v1(30.94,58.57)
  BOTTOM w0.191: v1(34.93,54.84) 35.45,54.32 35.45,51.58 36.26,50.76 36.26,48.3 37.28,47.28 40.34,47.28 41.52,46.11 v1(41.52,42.58) 41.56,42.58 42.23,41.91 43.94,41.91 44.13,41.72 44.13,40.37 45.02,39.49 45.62,39.49 47.62,37.5 48.82,37.5 50.53,35.79 54.16,35.79 54.9,36.53 60.23,36.53 63.15,39.45 D12.2 ; D12.2 62.73,40.65 62.44,40.94 v1(62.44,41.24) ; D12.2 63.15,41.29 63.28,41.42 C609.2 R615.2 ; U98.1 30.83,80.05 31,79.87 31,79.6 30.86,79.46 v1(30.39,79.46)
DEBOUNCE_SOC_PORZ: length 84.4
  TOP w0.191: U50.1 27.49,72.77 v1(27.25,73.01) ; v1(62.91,27.9) R375.2 63.54,28.33 63.55,28.33 SW8.3 SW8.2
  L03_SIG01 w0.076: v1(62.91,27.9) 55.4,35.41 55.4,40.38 53.65,42.13 51.1,42.13 43.58,49.65 43.58,57.34 42.56,58.35 41.55,58.35 40.24,59.66 40.24,65.04 40.66,65.46 40.66,73.08 v1(40.47,73.27)
  BOTTOM w0.191: v1(27.25,73.01) 27.5,73.27 31.2,73.27 32.37,74.44 35.7,74.44 36.87,75.62 38.87,75.62 40.47,74.02 v1(40.47,73.27) ; D14.2 61.87,28.5 C622.2 61.87,28.05 62.07,27.86 62.87,27.86 v1(62.91,27.9)
DEBOUNCE_SOC_WARMRESETN: length 25.5
  TOP w0.191: U50.3 27.35,71.77 26.52,72.59 26.52,73.5 25.43,74.59 25.43,79.04 27.67,81.28 28.11,81.28 v1(28.96,82.13) 28.75,82.34 SW4.2 SW4.3
  BOTTOM w0.191: Q6.2 C425.2 R532.2 D10.2 28.75,82.34 v1(28.96,82.13)
DIR: length 19.5
  TOP w0.191: v1(110.53,110.14) 109.52,111.15 109.52,114.23 109.08,114.67 103.58,114.67 103.32,114.92 103.32,115.78 v1(102.87,116.23)
  BOTTOM w0.191: v1(102.87,116.23) 102.29,115.66 R461.1 102.11,114.49 101.34,114.49 100.83,113.98 U83.2 ; U81.2 v1(110.53,110.14)
DIX4192_MCASP0_ACLKR: length 0.8
  BOTTOM w0.191: R481.2 66.29,104.11 U85.28
DIX4192_MCASP0_ACLKX: length 75.6
  TOP w0.191: v1(51.04,113.35) 51.67,113.35 52.36,112.67 52.36,110.53 53.26,109.63 57.22,109.63 57.93,108.92 57.93,108.36 58.81,107.47 U31.4 ; R14.2 v1(48.29,173.29)
  L03_SIG01 w0.076: v1(48.29,173.29) 48.37,173.21 48.37,129.45 49.02,128.8 49.02,115.37 v1(51.04,113.35)
DIX4192_MCASP0_AFSR: length 86.4
  TOP w0.191: v1(41.92,173.43) 41.92,173.43 R11.2
  L03_SIG01 w0.076: v1(62.79,104.14) 63.59,104.94 63.59,127.86 62.8,128.65 62.8,136.57 63.54,137.31 63.54,160.27 49.57,174.24 42.73,174.24 v1(41.92,173.43)
  BOTTOM w0.191: v1(62.79,104.14) 62.79,104.27 62.79,104.28 U85.35
DIX4192_MCASP0_AFSX: length 82.2
  TOP w0.191: v1(47.3,174.71) 47.31,174.7 R15.2
  L03_SIG01 w0.076: v1(63.79,104.15) 63.79,115.07 63.79,115.07 63.79,128.24 63.19,128.83 63.19,136.16 63.8,136.77 63.8,160.35 49.44,174.71 v1(47.3,174.71)
  BOTTOM w0.191: U85.33 v1(63.79,104.15)
DIX4192_MCASP0_AXR0: length 89.2
  TOP w0.191: R16.2 43.02,173.98 44.23,175.19 48.01,175.19 v1(50.34,172.85)
  L03_SIG01 w0.076: v1(50.34,172.85) 63.2,160 63.2,137.62 62.38,136.8 62.38,128.46 62.93,127.91 62.93,110.73 62.37,110.18 62.37,104.01 62.6,103.78 64.67,103.78 64.69,103.8 v1(64.69,103.8)
  BOTTOM w0.191: U85.31 64.79,103.9 v1(64.69,103.8)
DIX4192_MCASP0_AXR1: length 70.2
  TOP w0.191: v1(48.72,108.26) 49.51,108.26 50.7,107.07 U30.4 ; R13.2 v1(46.33,173.26)
  L03_SIG01 w0.076: v1(48.72,108.26) 47.58,109.4 47.58,164.64 47.04,165.18 47.04,172.55 v1(46.33,173.26)
DIX_3V3_SYS: length 51
  TOP w0.254: 51.95,167.08 C36.1 ; 51.95,167.08 C39.1 50.68,167.07 U3.33 ; 51.95,167.08 52.73,167.08 v1(52.93,167.28) ; U1.5 20.53,173.35 R12.1 ; U1.5 21.28,173.36 22.23,174.31 C9.1 24.28,174.31 24.76,173.83 24.76,172.78 25.14,172.39 L1.1 28.77,172.39 v1(29.13,172.04) ; U1.5 20.53,174.3 v1(20.77,174.54) ; U3.9 39.41,164.57 39.28,164.43 C58.1 v1(38.34,164.43) C59.1 37.66,164.42 FL3.2
  L03_SIG01 w0.254: v1(29.13,172.04) 36.38,164.78 37.99,164.78 v1(38.34,164.43)
  BOTTOM w0.254: v1(38.34,164.43) 41.19,167.28 v1(52.93,167.28)
  BOTTOM w0.508: C339.1 v1(20.77,174.54)
DIX_ADDR0: length 2.2
  TOP w0.191: R50.2 R49.1 44.87,158.04 45.17,158.34 R40.2
DIX_ADDR1: length 2.3
  TOP w0.145: R48.1 R47.2
  TOP w0.191: R43.2 48.12,158.6 48.73,157.99 R47.2
DIX_BLS: length 1.5
  TOP w0.191: U3.35 v1(47.87,168.07)
  BOTTOM w0.191: R417.2 47.86,168.06 v1(47.87,168.07)
DIX_INT: length 74.5
  TOP w0.191: U21.8 108.38,149.23 107.61,150 v1(107.61,153.91) ; v1(58.42,160.68) 58.42,160.56 60.05,158.94 v1(60.05,151.13)
  BOTTOM w0.191: v1(58.42,160.68) 57.57,161.54 56.72,161.54 56.5,161.32 U78.8 ; v1(107.61,153.91) 94.75,153.91 93.79,152.95 91.03,152.95 88.4,150.31 79.82,150.31 79.04,151.1 75.36,151.1 75.35,151.1 60.08,151.1 v1(60.05,151.13)
DIX_INT_1V8: length 8
  TOP w0.191: v1(47.05,162.71) 47.01,162.67 U3.23
  BOTTOM w0.191: U78.4 51.91,161.32 50.46,162.77 47.11,162.77 v1(47.05,162.71) 47.01,162.74 R424.1
DIX_MCLK: length 74.6
  TOP w0.191: v1(55.38,111.59) 57.57,111.59 59.19,109.98 59.73,109.98 60.5,110.74 67.52,110.74 67.97,110.3 68.21,110.3 72.22,110.3 v1(72.29,110.22) ; U3.25 49.79,163.07 52.27,160.59 52.27,159.46 52.65,159.08 v1(54.43,159.08)
  L03_SIG01 w0.076: v1(54.43,159.08) 54.31,158.96 54.31,117.65 54.31,117.65 54.31,115.78 54.31,115.34 55.38,114.26 v1(55.38,111.59)
  BOTTOM w0.191: R463.2 72.4,110.33 v1(72.29,110.22)
DIX_OP_IN_N: length 26.8
  TOP w0.191: U3.8 39.5,165.07 39.4,165.16 27.49,165.16 21.77,170.88 18.93,170.88 17.83,171.98 17.83,172.58 C4.1
DIX_OP_IN_P: length 26.7
  TOP w0.191: U3.7 39.5,165.57 39.4,165.47 27.62,165.47 21.9,171.19 19.06,171.19 18.14,172.11 18.14,172.87 U1.4
DIX_RESETN: length 12.3
  TOP w0.191: U3.24 47.51,160.82 47.7,160.63 51.07,160.63 51.88,159.82 51.88,158.98 53.68,157.18 R59.1 53.61,155.21 U13.4
DIX_RVD_CLK: length 101.8
  TOP w0.191: v1(84.42,107.4) 83.94,107.4 83.15,106.61 78.88,106.61 77.01,104.75 76.68,104.75 74.95,104.75 73.89,103.68 69.62,103.68 69.32,103.97 66.94,103.97 66.18,104.74 66.18,107.77 65.97,107.98 62.69,107.98 61.66,109.01 58.98,109.01 57.35,110.63 53.84,110.63 v1(53.61,110.86) ; v1(41.96,163.38) 41.65,163.07 U3.12
  L03_SIG01 w0.076: v1(41.96,163.38) 41.96,158.5 42.65,157.82 42.65,154.81 45.92,151.54 v1(45.92,114.05)
  BOTTOM w0.191: v1(53.61,110.86) 51.58,110.86 48.98,113.46 46.51,113.46 v1(45.92,114.05) ; U84.9 83.76,108.54 84.42,107.88 v1(84.42,107.4)
DIX_RX1: length 6
  TOP w0.191: C8.2 36.93,174.9 R1.1 36.93,179.67 J5.2
DIX_RX1_N: length 8
  TOP w0.191: C7.1 36.09,172.27 36.09,170.18 38.11,168.16 39.4,168.16 39.5,168.07 U3.2
DIX_RX1_P: length 7.6
  TOP w0.191: C8.1 36.4,172.17 36.4,170.31 38.24,168.47 39.4,168.47 39.5,168.57 U3.1
DIX_RX2_N: length 2.1
  TOP w0.191: U3.4 39.5,167.07 39.4,167.16 38.8,167.16 C40.1
DIX_RX2_P: length 2.1
  TOP w0.191: U3.3 39.5,167.57 39.4,167.47 38.8,167.47 C34.1
DIX_RX3_N: length 3.5
  TOP w0.191: U3.6 39.5,166.07 39.4,166.16 37.37,166.16 C44.1
DIX_RX3_P: length 3.5
  TOP w0.191: C41.1 37.37,166.47 39.4,166.47 39.5,166.57 U3.5
DIX_TX: length 6
  TOP w0.191: C5.2 R2.1 52.9,179.65 J6.2
DIX_TX_N: length 11
  TOP w0.191: U3.31 50.16,166.07 50.23,166.14 52.89,166.14 53.71,166.97 53.71,172.25 C6.1
DIX_TX_P: length 10.6
  TOP w0.191: U3.32 50.12,166.57 50.23,166.45 52.76,166.45 53.4,167.09 53.4,172.2 C5.1
DRAIN1: length 3.2
  BOTTOM w0.203: v1(39.54,18) 39.85,17.69 U129.8 ; U129.15 37.4,17.78 v1(37.61,18) ; v1(37.61,19.01) 37.25,19.38 U129.19
  vias: v1(38.58,19.01) v1(38.58,18) v1(39.54,19.01)
DRAIN2: length 3.2
  BOTTOM w0.203: v1(42.47,19.01) 42.84,19.38 U129.52 ; U129.7 40.25,17.71 v1(40.54,18) ; v1(42.47,18) 42.69,17.78 U129.56
  vias: v1(40.54,19.01) v1(41.5,19.01) v1(41.5,18)
EEPROM_A0: length 1.3
  TOP w0.191: U70.1 46.48,29.51 46.94,29.98 R370.1
EEPROM_A1: length 1.1
  TOP w0.145: U70.2 R369.1
EEPROM_A2: length 1.2
  TOP w0.191: R368.2 45.21,29.84 45.48,29.58 U70.3
EEPROM_WP: length 25.6
  TOP w0.191: v1(45.57,25.05) 45.98,25.45 U70.7
  L03_SIG01 w0.076: v1(50.22,38.08) 50.22,37.61 47.79,35.18 47.79,26.97 45.87,25.05 v1(45.57,25.05)
  BOTTOM w0.191: v1(50.22,38.08) 50.82,38.68 53.95,38.68 55.93,40.65 56.32,40.65 R617.1 56.85,40.67 56.86,40.65 J20.1
EMMC_RSTN: length 200.1
  TOP w0.191: v1(101.6,74.22) 101.6,74.47 U49.K5 ; v1(61.43,151.61) 62.2,150.83 62.2,137.77 66.23,133.74 66.23,128.44 67.56,127.11 67.56,124.96 67.2,124.6 R117.2 U26.4 ; v1(121.37,117.36) 120.76,117.36 120.49,117.09 116.1,117.09 110.53,122.65 103.51,122.65 99.78,126.39 v1(99.78,154.46)
  L03_SIG01 w0.076: v1(121.99,99.8) 119.56,99.8 116.15,96.38 112.81,96.38 111.04,94.61 111.04,88.69 113.85,85.88 113.85,83.2 113.18,82.53 113.18,81.54 106.4,74.75 v1(106.4,72.16)
  BOTTOM w0.191: v1(99.78,154.46) 94.55,154.46 93.45,153.36 90.81,153.36 88.27,150.82 79.93,150.82 79.26,151.48 75.51,151.48 75.5,151.5 61.54,151.5 v1(61.43,151.61) ; v1(121.99,99.8) 121.99,99.82 124.8,102.62 124.8,113.31 125.4,113.91 126.94,113.91 127.46,114.43 127.46,115.59 127.11,115.95 126.41,115.95 124.71,117.64 121.65,117.64 v1(121.37,117.36) ; v1(106.4,72.16) 104.09,72.16 103.86,72.39 103.86,73.87 102.79,74.95 101.89,74.95 101.6,74.66 v1(101.6,74.22)
EN_LM5141_ON: length 3.5
  BOTTOM w0.191: U128.23 17.27,22.7 16.45,23.52 15.33,23.52 15.07,23.79 R661.1
EXP1_CLK_IN: length 97.2
  TOP w0.191: J12.33 21.41,113.96 v1(21.27,113.82)
  L03_SIG01 w0.076: v1(39.52,131.91) 39.37,131.91 v1(21.27,113.82) ; v1(83.28,131.96) 83.28,131.19 83.14,131.05 83.14,127.47 85.8,124.82 85.8,114.22 v1(83.52,111.94)
  BOTTOM w0.191: v1(39.52,131.91) 40.1,132.5 42.64,132.5 43.78,133.64 61.15,133.64 62.98,131.81 76.98,131.81 77.5,131.29 80.41,131.29 81.11,132 83.24,132 v1(83.28,131.96) ; U84.3 82.84,111.54 83.24,111.94 v1(83.52,111.94)
EXP1_CLK_OUT: length 96.2
  TOP w0.191: J12.47 v1(24.8,123.56)
  L03_SIG01 w0.076: v1(84.24,135.33) 84.24,134.38 82.23,132.37 82.23,127.9 85.59,124.54 85.59,114.78 84.57,113.76 84.56,113.76 84.55,113.75 83.86,113.75 82.68,112.56 v1(82.68,112.04) ; v1(24.8,123.56) 38.69,137.45 v1(39.71,137.45)
  BOTTOM w0.191: U84.2 v1(82.68,112.04) ; v1(39.71,137.45) 41.62,137.45 41.88,137.71 63.06,137.71 65.24,135.53 74.74,135.53 75.31,134.96 77.3,134.96 77.61,135.26 84.17,135.26 v1(84.24,135.33)
EXP1_GPIO0_1: length 138.4
  TOP w0.14: v1(74.15,90.5) 74.36,90.29 U47.K22
  TOP w0.191: v1(91.15,103.41) 91.15,102.93 91.09,102.87 91.09,99.1 87.81,95.83 v1(87.81,95.3) ; J12.24 v1(19.07,109.96)
  L03_SIG01 w0.076: v1(19.07,109.96) 19.07,111.01 39.25,131.19 v1(40,131.19) ; v1(74.15,90.5) 74.63,90.5 79.43,95.3 v1(87.81,95.3) ; v1(86.85,131.01) 86.78,130.94 86.78,129.81 88.63,127.94 88.63,110.74 90.24,109.13 90.24,108.85 90.99,108.1 90.99,104.79 91.15,104.63 v1(91.15,103.41)
  BOTTOM w0.191: v1(40,131.19) 40.76,131.96 42.86,131.96 43.94,133.03 60.89,133.03 62.49,131.43 73.85,131.43 74.96,130.32 81.05,130.32 82.29,131.57 84.19,131.57 84.69,131.07 86.79,131.07 v1(86.85,131.01)
EXP1_GPIO0_13: length 145.8
  TOP w0.132: U47.K20 v1(73.96,87.19)
  TOP w0.191: J12.32 v1(15.79,113.16) ; v1(90.31,95.58) 93.16,98.43 93.16,101.68 92.8,102.04 92.8,104.17 92.79,104.17 92.79,104.28 v1(92.49,104.58)
  L03_SIG01 w0.076: v1(73.96,87.19) 73.96,87.74 80.73,94.51 88.92,94.51 89.99,95.58 v1(90.31,95.58) ; v1(92.49,104.58) 92.75,104.84 92.75,107.33 90.77,109.31 90.77,109.35 89.18,110.94 89.18,128.61 87.93,129.86 v1(87.93,132.43) ; v1(38.86,133.09) 36.32,130.55 36.32,129.59 25.33,118.6 24.69,118.6 19.13,113.03 15.92,113.03 v1(15.79,113.16)
  BOTTOM w0.191: v1(38.86,133.09) 41.19,133.09 42.68,134.58 61.59,134.58 63.6,132.57 77.84,132.57 78.34,132.07 80.01,132.07 80.71,132.77 87.59,132.77 v1(87.93,132.43)
EXP1_GPIO0_14: length 107.7
  TOP w0.191: U47.G20 v1(71.56,87.19) ; J12.34 v1(19.07,113.96)
  L03_SIG01 w0.076: v1(63.66,133.28) 64.33,132.61 64.33,118.98 65.5,117.81 65.5,116.29 64.9,115.69 64.9,105.64 64.99,105.55 67.17,103.37 67.17,102.57 67.51,102.22 67.51,100.55 68.68,99.38 68.68,94.2 71.94,90.94 71.94,87.57 v1(71.56,87.19) ; v1(19.07,113.96) 19.07,114.69 23.48,119.11 25.48,119.11 35.47,129.1 35.47,130.34 38.88,133.74 v1(40.12,133.74)
  BOTTOM w0.191: v1(40.12,133.74) 41.22,133.74 42.48,135 61.94,135 v1(63.66,133.28)
EXP1_GPIO0_31: length 137.9
  TOP w0.14: U47.N22 76.76,91.23 v1(76.67,91.32)
  TOP w0.191: v1(91.53,104.22) 91.55,104.22 91.8,103.97 91.8,102.66 91.47,102.33 91.47,98.93 88.5,95.96 v1(88.5,95.63) ; J12.38 v1(19.07,115.56)
  L03_SIG01 w0.076: v1(91.53,104.22) 91.84,104.54 91.84,105.45 91.66,105.63 91.66,106.3 91.95,106.59 91.95,107.46 90.42,108.99 90.42,109.21 88.81,110.81 88.81,128.28 87.24,129.85 87.24,132.84 v1(86.75,133.32) ; v1(40.29,134.53) 39.14,134.53 34.8,130.19 34.8,129.04 25.51,119.76 23.26,119.76 v1(19.07,115.56) ; v1(76.67,91.32) 76.71,91.32 80.29,94.9 88.02,94.9 88.5,95.37 v1(88.5,95.63)
  BOTTOM w0.191: v1(86.75,133.32) 86.61,133.18 78.68,133.18 78.46,132.95 64.63,132.95 62.2,135.38 42.22,135.38 41.37,134.53 v1(40.29,134.53)
EXP1_GPIO0_32: length 145.5
  TOP w0.132: U47.L18 v1(74.76,85.59)
  TOP w0.191: v1(93.43,104.59) 93.43,103.9 93.92,103.41 93.92,97.33 91.2,94.61 v1(91.18,94.61) ; J12.40 v1(19.07,116.36)
  L03_SIG01 w0.076: v1(91.18,94.61) 90.52,93.94 80.95,93.94 75.38,88.37 75.38,86.77 75.25,86.64 75.25,86.09 v1(74.76,85.59) ; v1(93.43,104.59) 93.77,104.94 93.77,107.01 89.54,111.24 89.54,128.92 88.76,129.7 v1(88.76,132.89) ; v1(39.54,135.33) 34.33,130.12 34.33,129.05 25.41,120.13 22.84,120.13 v1(19.07,116.36)
  BOTTOM w0.191: v1(39.54,135.33) 41.49,135.33 41.92,135.76 62.4,135.76 64.83,133.33 78.28,133.33 78.54,133.59 86.35,133.59 86.52,133.73 86.57,133.78 87.87,133.78 v1(88.76,132.89)
EXP1_GPIO0_33: length 145.2
  TOP w0.132: U47.L17 v1(74.76,84.79)
  TOP w0.191: v1(92.06,94.83) 94.32,97.09 94.32,103.52 93.9,103.94 93.9,104.24 v1(94.35,104.7) ; J12.42 v1(19.07,121.16)
  L03_SIG01 w0.076: v1(92.06,94.83) 92.06,94.65 90.98,93.57 81.11,93.57 75.76,88.23 75.76,86.65 75.61,86.5 75.61,85.64 v1(74.76,84.79) ; v1(41.04,135.97) 39.35,135.97 24.54,121.16 v1(19.07,121.16) ; v1(94.35,104.7) 94.06,104.99 94.06,107.09 89.72,111.43 89.72,129.14 89.15,129.71 89.15,133.44 v1(88.64,133.95)
  BOTTOM w0.191: v1(41.04,135.97) 41.21,136.14 62.64,136.14 65.07,133.72 77.87,133.72 78.21,134.06 86.3,134.06 86.37,134.12 86.41,134.16 88.43,134.16 v1(88.64,133.95)
EXP1_GPIO0_34: length 141.9
  TOP w0.132: U47.K19 v1(73.96,86.39)
  TOP w0.191: v1(88.83,94.99) 88.83,95.2 89.09,95.47 89.09,95.8 91.85,98.55 91.85,102.16 92.22,102.53 v1(92.22,103.85) ; J12.44 v1(19.07,121.96)
  L03_SIG01 w0.076: v1(40.37,136.58) 39.42,136.58 25.04,122.2 19.31,122.2 v1(19.07,121.96) ; v1(92.22,103.85) 92.02,104.05 92.02,105.1 92.54,105.62 92.54,107.24 90.59,109.19 90.59,109.28 89,110.87 89,128.45 87.45,129.99 87.45,134.71 v1(87.66,134.92) ; v1(88.83,94.99) 88.54,94.71 80.67,94.71 73.58,87.63 73.58,87.01 73.96,86.63 v1(73.96,86.39)
  BOTTOM w0.191: v1(40.37,136.58) 62.78,136.58 65.26,134.1 77.67,134.1 78.05,134.47 85.33,134.47 85.41,134.48 86.19,134.48 86.63,134.92 v1(87.66,134.92)
EXP1_GPIO0_35: length 145.1
  TOP w0.132: U47.L19 v1(74.76,86.39)
  TOP w0.191: v1(90.03,94.37) 93.54,97.88 93.54,103.06 v1(93.23,103.37) ; J12.52 v1(19.07,125.16)
  L03_SIG01 w0.076: v1(74.76,86.39) 74.76,86.64 75.14,87.02 75.14,88.41 80.88,94.15 89.81,94.15 v1(90.03,94.37) ; v1(19.07,125.16) 23.71,125.16 38.29,139.74 v1(40.68,139.74) ; v1(88.31,137.09) 88.09,136.87 88.09,132.99 88.37,132.71 88.37,129.77 89.36,128.78 89.36,111.05 92.93,107.48 92.93,103.67 v1(93.23,103.37)
  BOTTOM w0.191: v1(40.68,139.74) 64.63,139.74 67,137.37 75.21,137.37 75.58,137.74 87.66,137.74 v1(88.31,137.09)
EXP1_GPIO0_37: length 115.8
  TOP w0.191: v1(90.36,105.78) 90.08,105.5 90.08,99.38 86.44,95.74 R201.2 ; J12.51 24.62,125.16 v1(24.93,124.85)
  L03_SIG01 w0.076: v1(86.47,135.84) 86.12,135.5 86.12,132.81 86.43,132.5 86.43,131.51 86.09,131.17 86.09,128.9 88.07,126.92 88.07,110.4 89.65,108.82 89.65,108.4 89.9,108.14 89.9,106.24 v1(90.36,105.78) ; v1(24.93,124.85) 38.16,138.08 v1(40.82,138.08)
  BOTTOM w0.191: v1(86.47,135.84) 77.38,135.84 76.88,135.34 76.03,135.34 75.32,136.05 66.14,136.05 63.77,138.42 42.05,138.42 41.71,138.08 v1(40.82,138.08)
EXP1_GPIO0_37_R: length 16.9
  TOP w0.132: U47.R18 v1(78.76,85.59)
  TOP w0.191: R201.1 86.44,92.41 87.11,91.74 v1(88.01,91.74)
  L03_SIG01 w0.076: v1(78.76,85.59) 79.18,86.01 79.18,88.08 83.23,92.14 87.61,92.14 v1(88.01,91.74)
EXP1_GPIO0_38: length 141.4
  TOP w0.132: U47.R17 v1(78.76,84.79)
  TOP w0.191: J12.53 24.73,125.96 v1(25.04,125.65)
  L03_SIG01 w0.076: v1(96.36,104.81) 95.32,104.81 94.56,105.58 94.56,107.5 91.45,110.6 91.45,112.58 90.74,113.29 90.74,133.75 v1(88.84,135.65) ; v1(78.76,84.79) 78.34,85.21 78.34,88.16 82.69,92.51 92.64,92.51 v1(94.68,94.55) ; v1(25.04,125.65) 38.26,138.87 v1(40.26,138.87)
  BOTTOM w0.191: v1(94.68,94.55) 94.68,101.49 95.73,102.55 95.73,104.18 v1(96.36,104.81) ; v1(40.26,138.87) 41.07,138.87 41.13,138.81 64.17,138.81 66.37,136.6 76.46,136.6 76.76,136.3 87.31,136.3 87.64,135.97 88.52,135.97 v1(88.84,135.65)
EXP1_I2C2_SCL: length 137.5
  TOP w0.14: v1(75.91,93.02) 75.91,92.89 75.99,92.81 75.99,91.98 75.89,91.89 75.89,88.46 U47.M22
  TOP w0.191: v1(90.73,104.39) 90.73,103.97 90.64,103.87 90.64,99.25 v1(87.12,95.73) ; v1(18.83,107.56) J12.18
  L03_SIG01 w0.076: v1(90.73,104.39) 90.73,107.96 90.04,108.66 90.04,108.77 90.04,109.08 88.45,110.67 88.45,127.42 v1(86.71,129.16) ; v1(41.53,130.7) 41.53,130.01 40.79,129.27 38.25,129.27 19.7,110.72 19.7,108.41 18.84,107.56 v1(18.83,107.56) ; v1(75.91,93.02) 76.62,93.02 79.33,95.73 v1(87.12,95.73)
  BOTTOM w0.191: v1(18.83,107.56) 17.72,108.66 R465.2 ; v1(86.71,129.16) 74.14,129.16 73.1,130.19 60.77,130.19 59.35,131.61 54.86,131.61 54.24,130.98 42.48,130.98 42.2,130.7 v1(41.53,130.7)
EXP1_I2C2_SDA: length 147.2
  TOP w0.132: U47.M20 v1(76.36,87.19)
  TOP w0.191: J12.20 18.7,108.36 v1(18.81,108.46) ; v1(94.46,103.97) 94.7,103.74 94.7,96.62 v1(92.97,94.89)
  L03_SIG01 w0.076: v1(94.46,103.97) 94.72,104.23 94.72,104.96 94.35,105.33 94.35,107.13 89.93,111.55 89.93,130.22 v1(89.82,130.33) ; v1(76.36,87.19) 76.36,87.95 81.61,93.2 91.28,93.2 v1(92.97,94.89) ; v1(40.34,129.83) 38.35,129.83 19.48,110.96 19.48,109.11 18.83,108.46 v1(18.81,108.46)
  BOTTOM w0.191: R464.2 18.54,109.45 18.81,109.18 v1(18.81,108.46) ; v1(40.34,129.83) 40.34,130.32 41.47,131.45 42.92,131.45 44.04,132.57 60.59,132.57 62.15,131.02 73.66,131.02 74.74,129.94 81.25,129.94 82.49,131.18 84.02,131.18 84.87,130.33 v1(89.82,130.33)
EXP1_MCASP0_ACLKX: length 62.6
  TOP w0.191: J12.77 21.63,135.56 21.1,135.03 v1(21.1,133.44) ; U31.2 57.87,102.37 57.7,102.2 57.68,102.2 57.31,101.82 v1(56.74,101.82) R172.2
  BOTTOM w0.191: v1(56.74,101.82) 56.06,102.51 54.46,102.51 53.67,103.3 52.28,103.3 46.61,108.97 36.57,108.97 26.31,119.23 26.31,125.2 21.1,130.41 v1(21.1,133.44)
EXP1_MCASP0_AXR1: length 64.8
  TOP w0.191: v1(25.01,132.6) 24.77,132.36 J12.69 ; R186.2 56.01,102.85 56.15,103 v1(56.15,103.42) 56.15,103.85 56.27,103.96 56.27,105.98 55.79,106.46 55.26,106.46 54.92,106.12 U30.2
  BOTTOM w0.191: v1(25.01,132.6) 25.5,133.09 26.14,133.09 26.55,132.68 26.55,129.04 28.27,127.31 28.27,118.55 36.98,109.84 42.23,109.84 42.64,110.26 47.82,110.26 48.08,110.26 54.92,103.42 v1(56.15,103.42)
EXP1_MCASP0_AXR2: length 60.2
  TOP w0.191: R187.2 57.53,101.21 v1(58.05,101.73) ; v1(25.99,132.54) 25.99,132.57 25.4,133.16 J12.71
  BOTTOM w0.191: v1(58.05,101.73) 56.83,102.94 54.56,102.94 53.91,103.59 52.55,103.59 46.79,109.35 36.9,109.35 27.58,118.66 27.58,127.04 25.99,128.63 v1(25.99,132.54)
EXP1_MCASP0_AXR3: length 60.2
  TOP w0.191: v1(28.86,134.04) 28.77,133.96 J12.73 ; R171.2 55.22,104.49 55.55,104.82 55.55,105.74 v1(55.56,105.75)
  BOTTOM w0.191: v1(28.86,134.04) 31.68,131.22 31.68,118.42 38.01,112.1 40.58,112.1 40.84,112.35 49.39,112.35 51.46,110.29 53.26,110.29 55.55,108 55.55,105.76 v1(55.56,105.75)
EXP1_MCASP1_ACLKR: length 66.7
  TOP w0.191: J12.43 21.59,121.96 v1(21.23,121.6) ; v1(70.71,98.93) 70.71,98.1 70.38,97.76 R185.2
  BOTTOM w0.191: v1(70.71,98.93) 70.5,99.14 68.99,99.14 67.52,100.6 64.94,100.6 63.71,99.37 55.81,99.37 54.71,100.47 49.77,100.47 48.53,101.72 47.02,101.72 43.63,105.11 32.67,105.11 23.15,114.63 23.15,119.68 v1(21.23,121.6)
EXP1_MCASP1_ACLKX: length 57
  TOP w0.191: v1(25.44,114.63) 24.51,115.56 J12.37 ; R184.2 67.99,101.08 v1(68.13,101.23)
  BOTTOM w0.191: v1(25.44,114.63) 25.48,114.59 25.48,113.26 33.01,105.73 43.85,105.73 47.35,102.23 48.75,102.23 50.13,100.85 54.93,100.85 56,99.79 63.41,99.79 64.6,100.99 67.89,100.99 v1(68.13,101.23)
EXP1_MCASP1_AXR0: length 58.6
  TOP w0.191: v1(21.32,110.54) 21.32,111.37 21.51,111.56 J12.27
  BOTTOM w0.191: v1(21.32,110.54) 21.32,102.99 23.48,100.83 36.08,100.83 37.37,99.53 45.77,99.53 47.37,97.93 48.18,97.93 48.28,98.04 49.79,98.04 50.53,98.04 50.84,97.73 51.39,97.73 51.39,97.73 51.42,97.73 51.97,97.18 53.33,97.18 53.85,96.66 61.86,96.66 62.33,97.12 66.37,97.12 R496.2
EXP1_MCASP1_AXR1: length 53.8
  TOP w0.191: v1(66.39,101.51) 66.46,101.44 R183.2 ; J12.29 25.63,112.36 v1(26.46,113.18)
  BOTTOM w0.191: v1(26.46,113.18) 27.34,113.18 34.24,106.28 43.98,106.28 47.42,102.84 48.79,102.84 49.7,101.93 50.54,101.93 51.23,101.24 55.23,101.24 56.27,100.2 63,100.2 64.32,101.51 v1(66.39,101.51)
EXP1_MCASP1_AXR2: length 56.1
  TOP w0.191: v1(65.65,100) R167.2 ; v1(19.49,112.83) 19.49,112.04 19.01,111.56 J12.28
  BOTTOM w0.191: v1(65.65,100) 65.05,100 64.04,98.99 55.66,98.99 54.56,100.09 49.39,100.09 48.24,101.24 46.76,101.24 43.43,104.57 32.54,104.57 24.28,112.83 v1(19.49,112.83)
EXP1_MCASP1_AXR3: length 63
  TOP w0.191: J12.30 v1(18.9,112.36) ; R168.2 v1(67.18,100)
  BOTTOM w0.191: v1(67.18,100) 67.18,99.5 65.61,97.94 62.06,97.94 61.73,97.6 55.29,97.6 54.23,98.66 53.04,98.66 52.75,98.37 51.86,98.37 51.74,98.49 51.61,98.49 51.28,98.81 48.71,98.81 47.94,99.58 46.39,99.58 45.97,100.01 37.53,100.01 36.26,101.29 23.79,101.29 22.36,102.72 22.36,111.02 21.74,111.64 19.62,111.64 v1(18.9,112.36)
EXP1_TIMESTAMP0_IN: length 49.1
  TOP w0.191: J12.9 v1(24.8,104.36)
  L03_SIG01 w0.076: v1(24.8,104.36) 33.43,112.99 v1(38.83,112.99)
  BOTTOM w0.191: v1(38.83,112.99) 39.8,112.99 39.81,113 40.14,113 42.66,115.53 49.77,115.53 50.25,115.04 59.93,115.04 60.92,116.03 61.95,116.03 63.25,114.73 63.25,113.51 63.79,112.97 U85.4
EXP1_TIMESTAMP1_IN: length 49.8
  TOP w0.191: J12.11 v1(24.8,105.16)
  L03_SIG01 w0.076: v1(37.59,113.77) 33.41,113.77 v1(24.8,105.16)
  BOTTOM w0.191: v1(37.59,113.77) 40.08,113.77 42.26,115.95 50.3,115.95 50.8,115.45 59.64,115.45 60.62,116.42 62.46,116.42 63.63,115.25 63.63,113.67 64.29,113.01 U85.5
EXP2_CLK_IN: length 60.7
  TOP w0.191: v1(125.88,123.55) J13.33
  L03_SIG01 w0.076: v1(86.22,123.67) 86.22,123.21 86.07,123.06 86.07,111.76 v1(83.35,109.04)
  BOTTOM w0.191: v1(86.22,123.67) 86.29,123.67 86.62,123.34 96.07,123.34 98.29,125.55 120.15,125.55 120.82,124.88 124.55,124.88 v1(125.88,123.55) ; U84.8 v1(83.35,109.04)
EXP2_CLK_OUT: length 68.1
  TOP w0.191: J13.47 125.34,113.95 125.49,114.1 125.49,120.96 125.9,121.37 v1(125.9,122.49)
  L03_SIG01 w0.076: v1(86.54,121.48) 86.29,121.23 86.29,110.32 84.55,108.58 v1(84.44,108.58)
  BOTTOM w0.191: U84.7 83.55,109.54 84.44,108.65 v1(84.44,108.58) ; v1(86.54,121.48) 87.6,122.54 96.96,122.54 98.38,123.97 120.11,123.97 121.85,122.22 125.63,122.22 v1(125.9,122.49)
EXP2_EHRPWM0_A: length 124.9
  TOP w0.132: U47.D16 v1(69.16,83.99)
  TOP w0.191: J13.3 v1(122.2,135.55)
  L03_SIG01 w0.076: v1(61.05,85.27) 61.05,85.44 58.16,88.33 58.16,98.43 55.19,101.4 55.19,106.68 55.78,107.27 55.78,114.12 54.54,115.36 54.54,121.34 v1(55,121.8)
  BOTTOM w0.14: v1(69.16,83.99) 68.76,84.39 68.18,84.39 67.96,84.61 67.96,84.96 67.72,85.19 67.55,85.19 66.93,85.82
  BOTTOM w0.191: v1(55,121.8) 57.72,121.8 58.03,122.1 63.59,122.1 65.69,124.2 70.71,124.2 73.65,127.14 92.1,127.14 92.64,126.6 94.93,126.6 100.22,131.89 118.54,131.89 v1(122.2,135.55) ; v1(61.05,85.27) 61.6,85.82 66.93,85.82
EXP2_EHRPWM1_A: length 123.3
  TOP w0.14: U47.A17 66.89,84.66 66.57,84.66 66.1,85.13
  TOP w0.191: v1(55.44,92.22) 55.89,91.77 56.8,91.77 63.44,85.13 66.1,85.13 ; v1(119.05,134.75) 119.05,134.75 J13.5
  L03_SIG01 w0.076: v1(55.44,92.22) 55.91,92.7 55.91,98.76 53.97,100.7 53.97,102.93 52.99,103.91 52.99,113.48 52.78,113.69 52.78,122.42 v1(53.63,123.27)
  BOTTOM w0.191: v1(53.63,123.27) 61.8,123.27 64.29,125.76 70.57,125.76 72.72,127.9 92.72,127.9 93.16,127.47 94.32,127.47 99.52,132.67 105.74,132.67 107.82,134.75 v1(119.05,134.75)
EXP2_GPIO0_45: length 82.1
  TOP w0.191: v1(87.05,106.4) 87.18,106.27 87.18,103.37 87.67,102.89 87.67,100.45 85.87,98.66 84.36,98.66 82.55,96.85 82.55,93.13 79.96,90.53 U47.U22 ; J13.42 128.37,116.35 128.22,116.5 128.22,117.95 129.35,119.08 v1(129.35,120.07)
  L03_SIG01 w0.076: v1(129.35,120.07) 128.94,120.49 119.9,120.49 115.36,115.95 106.49,115.95 104.75,114.22 104.75,109.82 102.73,107.79 102.73,107.33 99.72,104.32 96.71,104.32 95.2,102.81 90.64,102.81 v1(87.05,106.4)
EXP2_GPIO0_46: length 85.6
  TOP w0.132: U47.U21 80.36,87.99 80.36,88.65
  TOP w0.191: v1(87.56,107.29) 87.67,107.18 87.67,103.42 88.05,103.04 88.05,100.22 86.09,98.27 84.51,98.27 82.96,96.71 82.96,92.99 80.36,90.39 80.36,88.65 ; J13.44 128.23,115.55 127.82,115.96 127.82,118.44 128.48,119.1 v1(128.48,119.79)
  L03_SIG01 w0.076: v1(128.48,119.79) 119.51,119.79 115.4,115.69 106.48,115.69 104.93,114.14 104.93,109.56 102.93,107.56 102.93,107.18 99.87,104.12 96.85,104.12 95.34,102.6 90.19,102.6 86.58,106.22 86.58,106.84 87.02,107.29 v1(87.56,107.29)
EXP2_GPIO0_47: length 75.7
  TOP w0.132: U47.U20 v1(80.36,87.19)
  TOP w0.191: v1(121.05,98.39) 121.05,97.97 120.91,97.83 120.91,97.53 121.58,96.86 123.7,96.86 125.79,98.95 125.79,111.87 125.31,112.35 J13.51
  BOTTOM w0.102: 80.36,88.03 v1(80.36,87.19)
  BOTTOM w0.191: 80.36,88.03 80.36,89.96 84.73,94.34 89.14,94.34 89.63,94.83 90.22,94.83 90.93,94.12 91.97,94.12 92.39,93.7 98.33,93.7 100.39,95.76 104.46,95.76 107.76,92.47 112.25,92.47 112.59,92.81 117.69,92.81 122.2,97.31 122.2,97.95 121.75,98.39 v1(121.05,98.39)
EXP2_GPIO0_48: length 71.6
  TOP w0.132: U47.U19 v1(80.36,86.39)
  TOP w0.191: v1(121.5,97.67) 123.12,97.67 125.4,99.94 125.4,100.96 125.4,100.97 125.4,111.31 125.16,111.55 J13.53
  BOTTOM w0.102: v1(80.36,86.39) 79.95,86.8 79.95,88.25
  BOTTOM w0.191: 79.95,88.25 79.95,90.1 86.4,96.55 91.96,96.55 94.42,94.09 98,94.09 100.06,96.15 104.65,96.15 107.96,92.85 111.94,92.85 112.3,93.2 117.03,93.2 v1(121.5,97.67)
EXP2_GPIO0_55: length 52
  TOP w0.191: J13.77 122.11,101.95 121.01,100.85 119.52,100.85 v1(119.07,100.4) ; U47.W22 81.56,89.82 84.56,92.82 v1(84.56,96.23)
  L03_SIG01 w0.076: v1(119.07,100.4) 119.07,99.68 118.01,98.62 113.23,98.62 113.13,98.52 109.86,98.52 109.64,98.74 106.84,98.74 106.22,99.36 100.12,99.36 96.98,96.21 84.58,96.21 v1(84.56,96.23)
EXP2_GPIO0_56: length 52.2
  TOP w0.132: 81.96,88.65 81.96,87.99 U47.W21
  TOP w0.191: J13.79 121.87,101.15 120.96,100.24 119.72,100.24 119.37,99.88 v1(118.56,99.88) ; v1(85.2,96.66) 85.2,96.22 84.95,95.97 84.95,95 84.95,92.66 81.98,89.69 81.96,89.67 81.96,88.65
  L03_SIG01 w0.076: v1(118.56,99.88) 117.54,98.87 113.22,98.87 113.05,98.69 109.93,98.69 109.7,98.93 108.72,98.93 107.94,99.71 100.22,99.71 96.95,96.44 85.43,96.44 v1(85.2,96.66)
EXP2_GPIO0_57: length 59.4
  TOP w0.132: U47.W20 v1(81.96,87.19)
  TOP w0.191: J13.78 v1(127.93,101.95)
  BOTTOM w0.102: 81.96,88.27 v1(81.96,87.19)
  BOTTOM w0.191: 81.96,88.27 81.96,89.89 84.99,92.93 91.46,92.93 91.88,92.51 104.24,92.51 105.43,91.32 112.95,91.32 113.26,91.63 121.18,91.63 127.36,97.8 127.36,101.37 v1(127.93,101.95)
EXP2_GPIO0_58: length 59.2
  TOP w0.132: U47.W19 v1(81.96,86.39)
  TOP w0.191: J13.80 128.3,101.15 v1(127.93,100.78)
  BOTTOM w0.102: 82.37,87.98 82.37,86.8 v1(81.96,86.39)
  BOTTOM w0.191: 82.37,87.98 82.37,89.67 85.25,92.55 91.26,92.55 91.69,92.12 104.08,92.12 105.26,90.94 113.25,90.94 113.55,91.24 121.34,91.24 127.93,97.84 v1(127.93,100.78)
EXP2_MCASP2_AXR5: length 87.3
  TOP w0.191: v1(133.64,110.39) 133.38,110.64 133.38,120.3 132.94,120.75 132.94,123.38 131.97,124.35 J13.32
  L03_SIG01 w0.076: v1(80.81,100.38) 81.34,100.38 81.72,100 82.41,100 83.37,100.96 86,100.96 86.82,100.14 94.11,100.14 95.13,101.16 96.18,101.16 97.64,102.63 113.11,102.63 113.44,102.96 113.44,103.54 115.41,105.51 120.27,105.51 122.29,107.53 v1(122.35,107.53) 130.78,107.53 v1(133.64,110.39)
  BOTTOM w0.191: R499.2 80.5,100.07 v1(80.81,100.38) ; RA5.7 120.29,113.5 121.33,112.46 121.33,108.55 v1(122.35,107.53)
EXP2_MCASP2_AXR5_R: length 9.8
  TOP w0.132: U47.N20 v1(77.16,87.19)
  BOTTOM w0.191: R499.1 80.5,93.92 77.96,91.37 77.96,88.53 77.16,87.73 v1(77.16,87.19)
EXP2_MCASP2_AXR6: length 96.8
  TOP w0.191: J13.34 131.69,123.55 132.36,122.87 132.36,120.3 132.78,119.89 v1(132.78,104.68)
  L03_SIG01 w0.076: v1(132.78,104.68) 128.05,104.68 127.87,104.86 123.14,104.86 122.19,103.92 118.91,103.92 v1(118.81,104.02) 118.5,104.33 117.42,104.33 117.05,103.97 117.05,103.62 116.84,103.41 115.93,103.41 114.32,101.8 98.13,101.8 96.69,100.37 95.7,100.37 94.07,98.73 80.98,98.73 v1(79.26,100.45)
  BOTTOM w0.191: v1(79.26,100.45) 79.26,99.75 79.76,99.25 R493.2 ; RA5.6 120.5,113.9 121.78,112.62 121.78,109.5 122.87,108.41 122.87,104.93 121.94,104 119.1,104 119.08,104.02 v1(118.81,104.02)
EXP2_MCASP2_AXR6_R: length 12.5
  TOP w0.132: U47.N19 v1(77.16,86.39)
  BOTTOM w0.102: v1(77.16,86.39) 76.78,86.77 76.78,87.94
  BOTTOM w0.191: 76.78,87.94 77.53,88.69 77.53,91.65 79.76,93.89 R493.1
EXP2_MCASP2_AXR7: length 86.5
  TOP w0.191: v1(132.2,119.36) 131.84,119.72 131.84,121.58 131.47,121.95 J13.38
  L03_SIG01 w0.076: v1(121.51,102.54) 121.22,102.82 116.15,102.82 114.52,101.2 98.55,101.2 97.11,99.76 96.07,99.76 94.5,98.2 80.24,98.2 78.44,100 v1(78.21,100)
  BOTTOM w0.191: v1(121.51,102.54) 121.51,102.66 123.26,104.41 123.26,112.69 121.65,114.3 RA5.5 119.53,116.16 121.4,118.02 124.55,118.03 124.87,118.03 126.36,116.53 131.63,116.53 132.2,117.11 v1(132.2,119.36) ; R494.2 78.19,99.99 v1(78.21,100)
EXP2_MCASP2_AXR7_R: length 14.2
  TOP w0.132: U47.N18 v1(77.16,85.59)
  BOTTOM w0.102: v1(77.16,85.59) 76.75,86 75.82,86 75.76,86.06
  BOTTOM w0.191: R494.1 78.19,93.94 76.4,92.15 76.4,91.85 75.64,91.09 75.64,86.18 75.76,86.06
EXP2_MCASP2_AXR8: length 89.6
  TOP w0.191: v1(121.03,101.63) 120.64,101.23 120.02,101.23 119.53,101.72 119.53,105.49 v1(120.89,106.85) ; J13.40 131.26,121.15 131.45,120.96 131.45,118.75 132.27,117.93 132.27,104.07 132.47,103.88 v1(132.47,102.35)
  L03_SIG01 w0.076: v1(132.47,102.35) 127.22,102.35 126.5,101.63 v1(121.03,101.63) 120.19,102.47 116.37,102.47 114.63,100.73 99.02,100.73 97.64,99.35 96.23,99.35 94.72,97.84 80.05,97.84 78.78,99.11 77.22,99.11 v1(76.96,98.85)
  BOTTOM w0.191: v1(76.96,98.85) 76.69,98.58 R495.2 ; v1(120.89,106.85) 120.89,106.14 120.47,105.72 RA6.5
EXP2_MCASP2_AXR8_R: length 16.7
  TOP w0.132: U47.N17 v1(77.16,84.79)
  BOTTOM w0.102: v1(77.16,84.79) 76.77,85.18 74.62,85.18 74.34,85.46 74.34,87.64
  BOTTOM w0.191: R495.1 76.69,94.61 76.05,93.97 75.12,93.97 74.7,93.55 74.7,88.63 74.34,88.26 74.34,87.64
EXP2_MCASP2_AXR9: length 48.5
  TOP w0.191: v1(121.06,105.64) 121.37,105.95 J13.67
  L03_SIG01 w0.076: v1(82.44,99.58) 82.44,99.66 83.54,100.75 85.79,100.75 86.68,99.86 94.15,99.86 95.25,100.96 96.25,100.96 97.72,102.43 113.3,102.43 113.75,102.88 113.75,103.47 115.56,105.28 120.7,105.28 v1(121.06,105.64)
  BOTTOM w0.191: v1(121.06,105.64) 120.73,105.32 RA6.6 ; R492.2 81.34,98.72 82.2,99.58 v1(82.44,99.58)
EXP2_MCASP2_AXR9_R: length 13.7
  TOP w0.132: U47.P18 v1(77.96,85.59)
  BOTTOM w0.102: 77.57,87.55 77.57,85.98 v1(77.96,85.59)
  BOTTOM w0.191: R492.1 81.34,94.22 78.34,91.21 78.34,88.31 77.57,87.55
EXP2_MCASP2_AXR10: length 47.6
  TOP w0.191: v1(122.14,105.16) 122.15,105.15 J13.69
  L03_SIG01 w0.076: v1(122.14,105.16) 121.02,105.16 120.7,104.84 115.63,104.84 115.1,104.31 115.1,103.42 113.91,102.23 97.86,102.23 96.38,100.75 95.39,100.75 93.94,99.3 85.92,99.3 v1(84.91,100.31)
  BOTTOM w0.191: RA6.7 120.89,104.92 121.13,105.16 v1(122.14,105.16) ; v1(84.91,100.31) 84.86,100.31 82.91,98.36 R491.2
EXP2_MCASP2_AXR10_R: length 14.4
  TOP w0.132: U47.P19 v1(77.96,86.39)
  BOTTOM w0.102: v1(77.96,86.39) 77.98,86.39 78.39,85.98 79.02,85.98 79.16,86.12 79.16,87.79 79.15,87.81
  BOTTOM w0.191: R491.1 82.91,94.66 79.15,90.89 79.15,87.81
EXP2_MCASP2_AXR11: length 51.6
  TOP w0.191: v1(120.25,101.82) 120.25,103.64 v1(121.12,104.52) 121.29,104.35 J13.71 ; R177.2 78.74,98.59 v1(78.66,98.68)
  L03_SIG01 w0.076: v1(78.66,98.68) 79.67,97.66 94.85,97.66 96.33,99.15 97.9,99.15 99.28,100.53 114.82,100.53 116.58,102.29 119.77,102.29 v1(120.25,101.82)
  BOTTOM w0.191: RA6.8 v1(121.12,104.52)
EXP2_MCASP2_AXR11_R: length 10
  TOP w0.14: R177.1 78.76,97.11 78.76,94.03 77.96,93.23 77.96,87.99 U47.P21
EXP2_MCASP2_AXR12: length 56
  TOP w0.191: J13.73 121.7,103.55 v1(121.63,103.48)
  L03_SIG01 w0.076: v1(121.63,103.48) 117.8,103.48 117.53,103.21 116,103.21 114.39,101.6 98.25,101.6 96.82,100.16 95.81,100.16 94.2,98.55 80.55,98.55 77.83,101.28 v1(76.74,101.28)
  BOTTOM w0.191: R501.2 77.45,100.56 v1(76.74,101.28)
EXP2_MCASP2_AXR12_R: length 11.8
  TOP w0.132: U47.M18 v1(76.36,85.59)
  BOTTOM w0.191: v1(76.36,85.59) 75.55,85.59 75.24,85.9 75.24,91.23 76.02,92.01 76.02,92.32 77.45,93.75 R501.1
EXP2_MCASP2_AXR13: length 62.6
  TOP w0.191: J13.68 127.84,105.95 127.62,105.73 v1(127.62,104.44)
  L03_SIG01 w0.076: v1(127.62,104.44) 123.44,104.44 122.01,103.01 116.08,103.01 114.45,101.39 98.4,101.39 96.97,99.96 95.94,99.96 94.35,98.38 80.46,98.38 78.43,100.41 v1(76.59,100.41)
  BOTTOM w0.191: R502.2 75.93,96.42 76.1,96.59 76.1,99.92 v1(76.59,100.41)
EXP2_MCASP2_AXR13_R: length 11.6
  TOP w0.132: U47.K18 v1(73.96,85.59)
  BOTTOM w0.102: v1(73.96,85.59) 73.96,85.81 73.56,86.21 73.56,87.66
  BOTTOM w0.191: 73.56,87.66 73.56,90.97 74.28,91.69 74.28,93.68 74.96,94.37 75.77,94.37 75.93,94.53 R502.1
EXP2_MCU_SPI1_CS2: length 165.9
  TOP w0.191: U37.8 24.39,93.69 24.13,93.42 24.13,90.32 20.23,86.42 20.23,81.61 15.01,76.4 15.01,45.12 v1(19.29,40.84)
  L03_SIG01 w0.076: v1(60.62,72.65) 60.26,72.29 60.26,71.47 60.68,71.06 60.68,56.97 62.48,55.16 62.48,46.35 62.3,46.17 62.3,43.36 65.23,40.43 v1(65.23,38.23) ; v1(49.16,30.93) 49.1,30.99 49.1,32.8 v1(49.86,33.57) ; v1(36.05,33.2) 35.71,32.86 30.9,32.86 29.96,31.92 28.91,31.92 27.17,30.17 24.26,30.17 21.12,33.31 21.12,39.01 v1(19.29,40.84)
  BOTTOM w0.14: R563.1 65.17,75.71 64,74.54 63.06,74.54 62.88,74.72 62.88,75.04 62.26,75.66 61.02,75.66 60.75,75.39 60.75,74.14 60.48,73.87 60.48,72.79 60.62,72.65 v1(60.62,72.65)
  BOTTOM w0.191: v1(36.05,33.2) 36.98,33.2 37.3,32.88 39.13,32.88 41.81,30.21 48.43,30.21 v1(49.16,30.93) ; v1(65.23,38.23) 60.8,33.8 52.46,33.8 51.93,33.27 50.16,33.27 v1(49.86,33.57)
EXP2_MCU_SPI1_CS2_1V8: length 139.6
  TOP w0.191: v1(32.36,119.7) 24.12,119.7 20.7,116.28 20.7,100.87 24.39,97.17 U37.4 ; J13.24 128.35,127.55 128.08,127.28 v1(128.08,124.77)
  BOTTOM w0.191: v1(32.36,119.7) 32.77,119.29 41.26,119.29 41.83,119.86 59.74,119.86 60.47,120.59 70.11,120.59 74.67,125.15 88.98,125.15 90.28,123.85 95.75,123.85 97.88,125.98 120.51,125.98 120.99,125.5 126.92,125.5 127.65,124.77 v1(128.08,124.77)
EXP2_TIMESTAMP0_IN: length 74.4
  TOP w0.191: J13.9 v1(122.2,133.15)
  L03_SIG01 w0.076: v1(66.29,112.66) 66.29,113.91 65.86,114.34 65.86,115.15 66.37,115.65 v1(66.37,123.17)
  BOTTOM w0.191: v1(122.2,133.15) 120.82,133.15 119.17,131.5 100.68,131.5 94.76,125.58 91.2,125.58 90.05,126.73 73.86,126.73 70.83,123.7 66.89,123.7 v1(66.37,123.17) ; U85.9 v1(66.29,112.66)
EXP2_TIMESTAMP1_IN: length 72.9
  TOP w0.191: J13.11 v1(122.2,132.35)
  L03_SIG01 w0.076: v1(66.98,113.63) 66.98,120.71 67.41,121.14 v1(67.41,123.19)
  BOTTOM w0.191: v1(67.41,123.19) 70.89,123.19 74.02,126.31 89.82,126.31 91.03,125.1 94.96,125.1 100.93,131.07 119.3,131.07 120.59,132.35 v1(122.2,132.35) ; v1(66.98,113.63) 66.79,113.45 U85.10
EXT_CLKOUT0: length 93
  TOP w0.191: v1(47.47,99.09) 47.57,98.99 R170.1 ; v1(74.27,47.51) 74.9,48.14 76.22,48.14 76.54,47.82 R337.1
  L03_SIG01 w0.076: v1(51.16,73.92) 51.16,73.25 50.5,72.59 50.5,70.64 52.13,69.02 53.24,69.02 58.2,64.06 58.2,60.94 58.2,60.75 58.21,60.74 58.21,60.71 59.29,59.63 59.29,55.08 61.71,52.66 62.02,52.35 62.02,46.63 61.85,46.45 61.85,40.51 64.75,37.61 70.19,37.61 72.46,39.88 72.46,44.72 74.27,46.53 v1(74.27,47.51) ; v1(47.47,99.09) 47.47,96 50.02,93.45 50.02,81.21 49.6,80.79 v1(49.6,76.62)
  BOTTOM w0.191: v1(51.16,73.92) 51.16,73.99 49.6,75.55 v1(49.6,76.62)
EXT_CLKOUT0_R: length 27.2
  TOP w0.132: 67.01,83.99 67.56,83.99 U47.B16
  TOP w0.14: 66.21,84.32 66.66,84.32 66.99,83.99 67.01,83.99
  TOP w0.191: 66.21,84.32 65.93,84.6 63.26,84.6 61.37,86.5 60.32,86.5 58.05,88.77 58.05,89.88 56.63,91.3 55.64,91.3 54.47,92.47 54.47,93.59 51.68,96.38 51.68,97.63 51.43,97.88 49.37,97.88 49.11,98.15 R175.2
EXT_REFCLK1: length 42
  TOP w0.191: R175.1 v1(48.04,98.43)
  L03_SIG01 w0.076: v1(73.15,96.96) 73.48,97.29 75.21,97.29 75.54,97.62 75.54,97.97 75.16,98.35 75.16,98.69 74.9,98.95 74.9,99.31 73.67,100.55 73.67,104.61 74.33,105.28 74.33,108.23 v1(74.2,108.36)
  BOTTOM w0.191: U84.28 74.37,108.54 v1(74.2,108.36) ; v1(48.04,98.43) 50.67,98.43 51,98.11 51.54,98.11 51.55,98.11 51.58,98.11 52.12,97.56 54.12,97.56 54.27,97.71 54.64,97.71 55.13,97.22 61.89,97.22 62.22,97.56 70.35,97.56 70.72,97.19 72.92,97.19 v1(73.15,96.96)
EXT_VMON2_1: length 3.8
  TOP w0.191: TP95.1 81.89,43.99 83.21,42.67 J18.2
EXT_VMON2_2: length 6.9
  TOP w0.191: J19.2 115.64,42.78 113.67,44.74 111.44,44.74 111.05,45.13 TP94.1
FT4232_CPLD_UART0_RX_3V3: length 5.3
  TOP w0.191: v1(31.97,35.14) 33.04,36.21 U64.26
  BOTTOM w0.191: v1(31.97,35.14) 31.03,35.14 30.46,34.56 U126.13
FT4232_CPLD_UART0_TX_3V3: length 6.7
  TOP w0.191: v1(32.22,34.27) 33.54,35.59 U64.27
  BOTTOM w0.191: U126.15 30.38,33.76 30.61,33.53 31.36,33.53 32.1,34.27 v1(32.22,34.27)
FT4232_DO: length 2.5
  TOP w0.191: U61.4 R321.1 R323.2
FT4232_EECLK: length 5.2
  TOP w0.191: U61.2 R328.1 28.16,51.31 28.43,51.03 28.88,51.03 29.43,50.48 29.43,49.6 29.54,49.49 U64.62
FT4232_EECS: length 4.2
  TOP w0.191: U61.1 28.03,50.89 28.41,50.5 R333.1 28.79,50.07 29.04,49.82 U64.63
FT4232_EEDATA: length 6.8
  TOP w0.191: U61.3 28.71,52.19 28.8,52.28 R323.1 29.41,52.28 30.01,51.68 30.01,51.31 29.82,51.12 29.82,49.9 30.04,49.67 U64.61
FT4232_MCU_UART0_RX_3V3: length 15.5
  TOP w0.191: v1(31.21,54.87) 31.21,53.74 31.53,53.42 36.09,53.42 36.65,52.85 36.65,47.21 37.11,46.75 U64.48
  BOTTOM w0.191: U117.13 31.56,55.87 31.21,55.51 v1(31.21,54.87)
FT4232_MCU_UART0_TX_3V3: length 10.3
  TOP w0.191: U64.52 34.54,50.06 34.49,50.12 34.49,50.14 34.24,50.39 34.24,51.24 34.02,51.47 v1(34.02,52.82)
  L03_SIG01 w0.076: v1(30.95,56.67) 32.53,55.09 32.53,54.31 v1(34.02,52.82)
  BOTTOM w0.191: U117.15 v1(30.95,56.67)
FT4232_REF: length 1.9
  TOP w0.14: U64.6 v1(27.73,44.25)
  BOTTOM w0.14: v1(27.73,44.25) 27.5,44.48 R609.2
FT4232_RESET: length 6.3
  TOP w0.14: R357.1 22.76,40.81 24.21,39.37 C282.2 24.92,39.37 25.8,40.25 U64.14
FT4232_SOC_UART4_RX_3V3: length 5.9
  TOP w0.191: v1(27.71,38.94) 27.4,39.25 U64.16
  BOTTOM w0.191: U125.13 30.84,39.02 30.13,38.31 28.34,38.31 v1(27.71,38.94)
FT4232_SOC_UART4_TX_3V3: length 3.9
  TOP w0.191: v1(29.82,38.93) 28.94,38.93 28.51,38.5 28.51,38.28 28.54,38.25 U64.17
  BOTTOM w0.191: v1(29.82,38.93) 30.04,39.14 U125.15
FT4232_USB_DM: length 24.5
  TOP w0.119: U64.7 25.64,43.75 25.5,43.61 22.36,43.61 21.98,43.23 21.98,40.36 23.22,39.13 23.22,32.86 21.9,31.54 18.48,31.54 18.37,31.65 ; 18.37,31.65 18.26,31.54 16.71,31.54 16.5,31.76 J22.2 ; 18.37,31.65 U67.5
FT4232_USB_DP: length 24.5
  TOP w0.119: U67.3 19.37,31.24 ; 19.37,31.24 19.46,31.32 21.99,31.32 23.44,32.77 23.44,39.22 22.2,40.46 22.2,43.13 22.46,43.39 25.5,43.39 25.64,43.25 U64.8 ; 19.37,31.24 19.29,31.32 16.71,31.32 16.5,31.11 J22.3
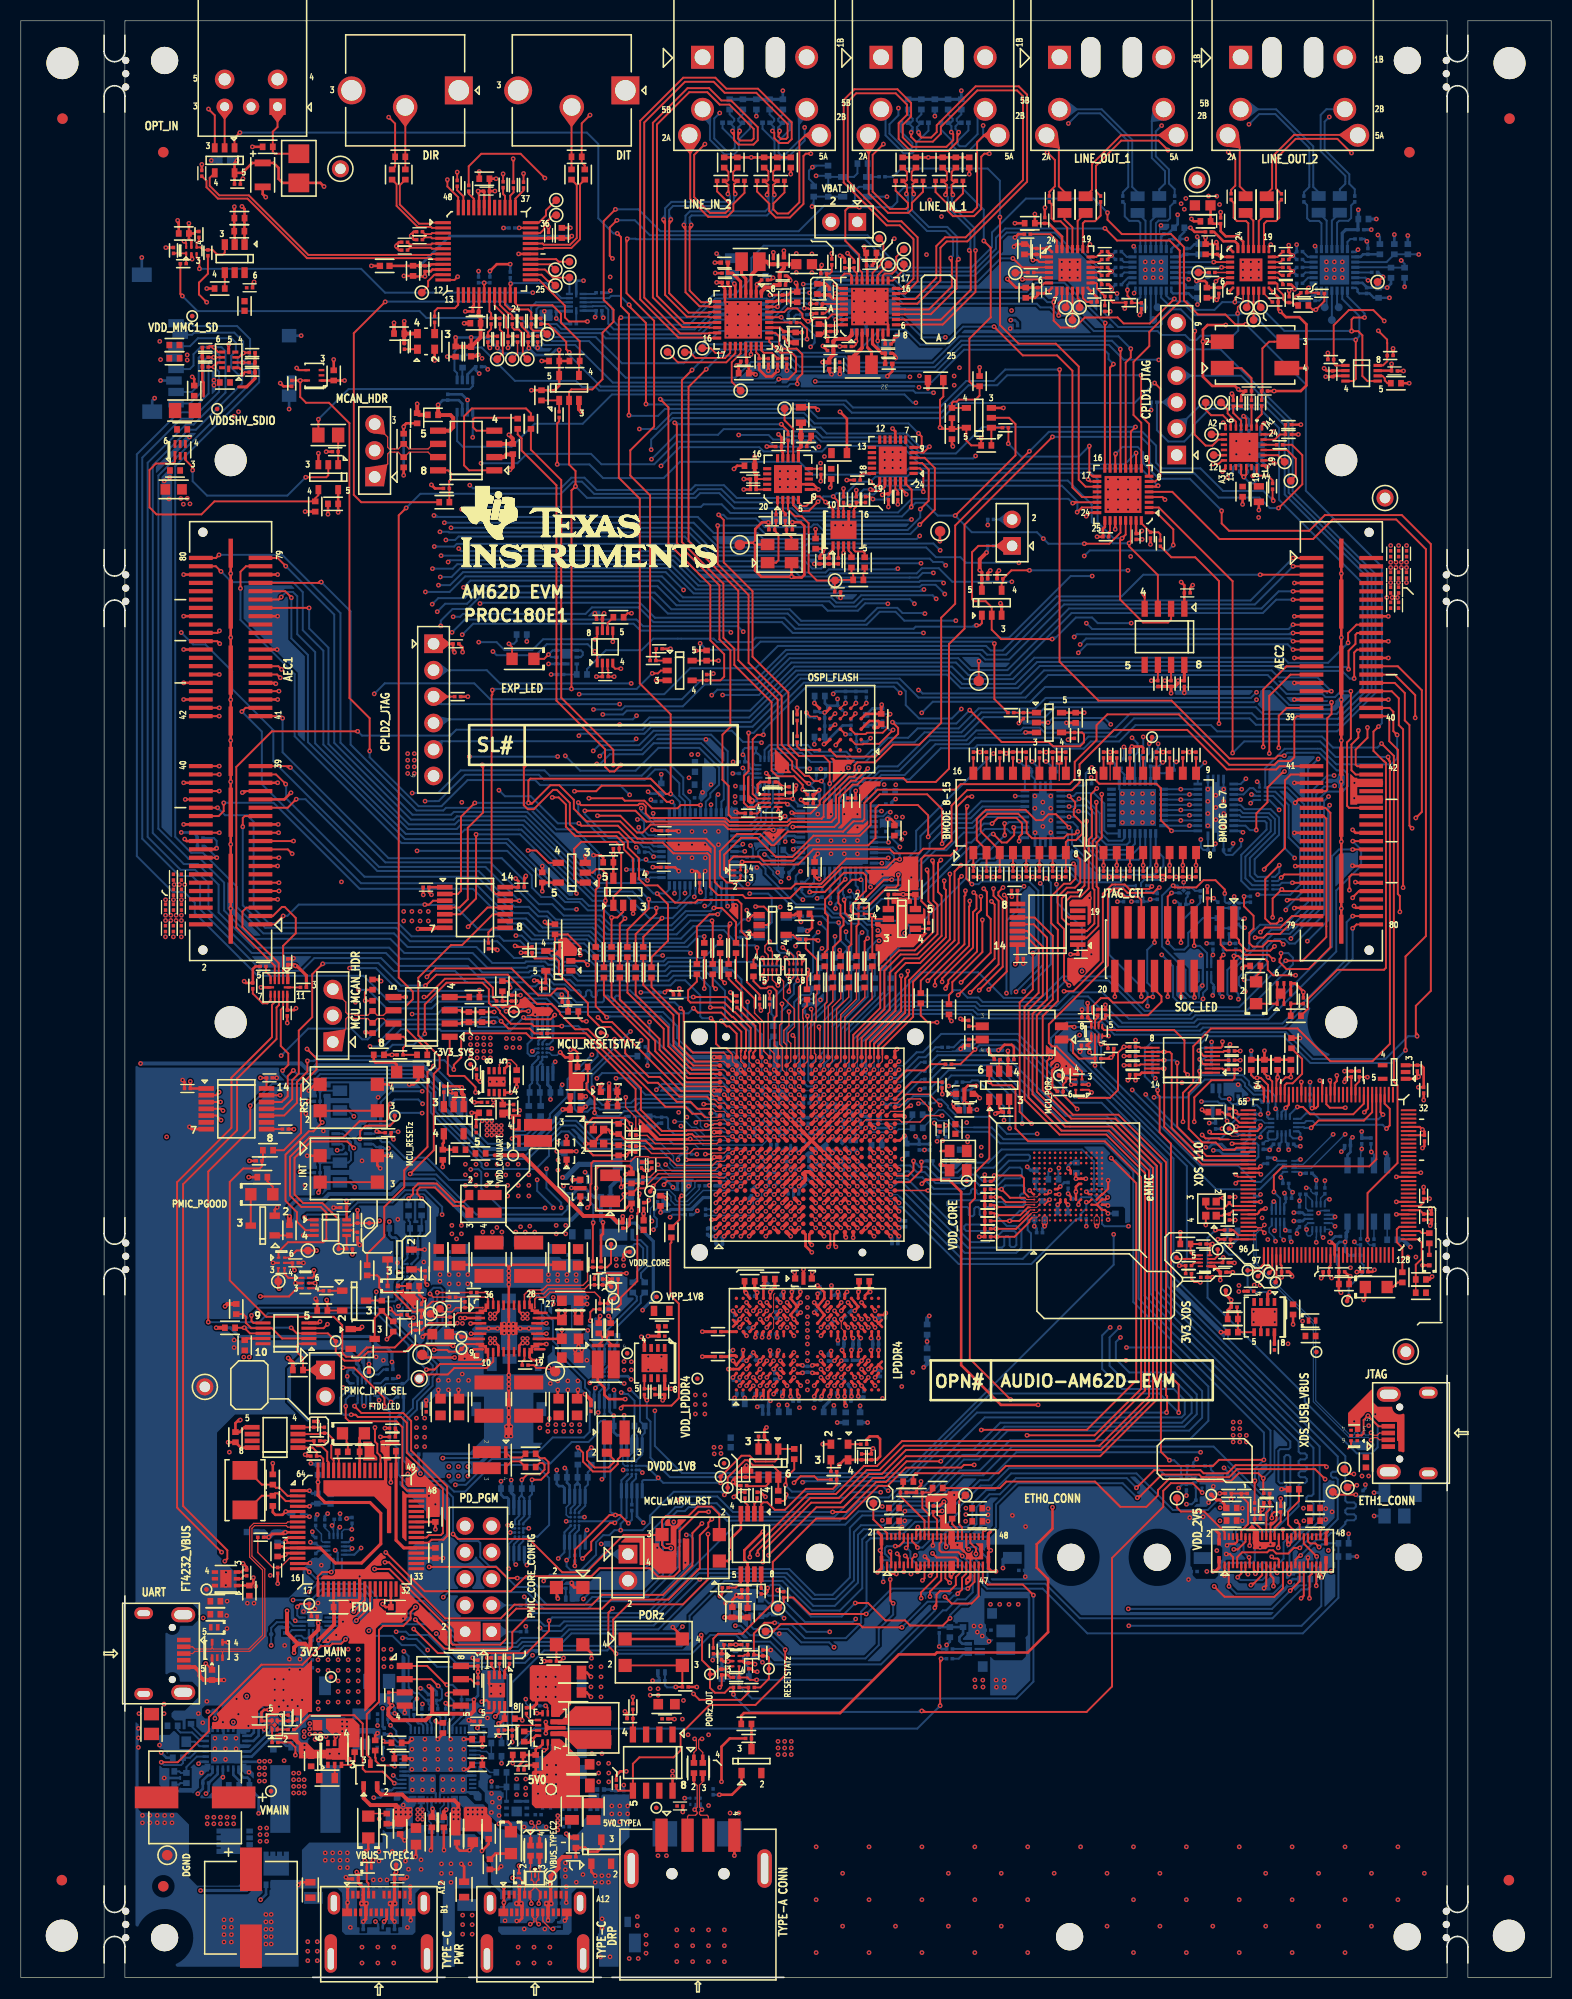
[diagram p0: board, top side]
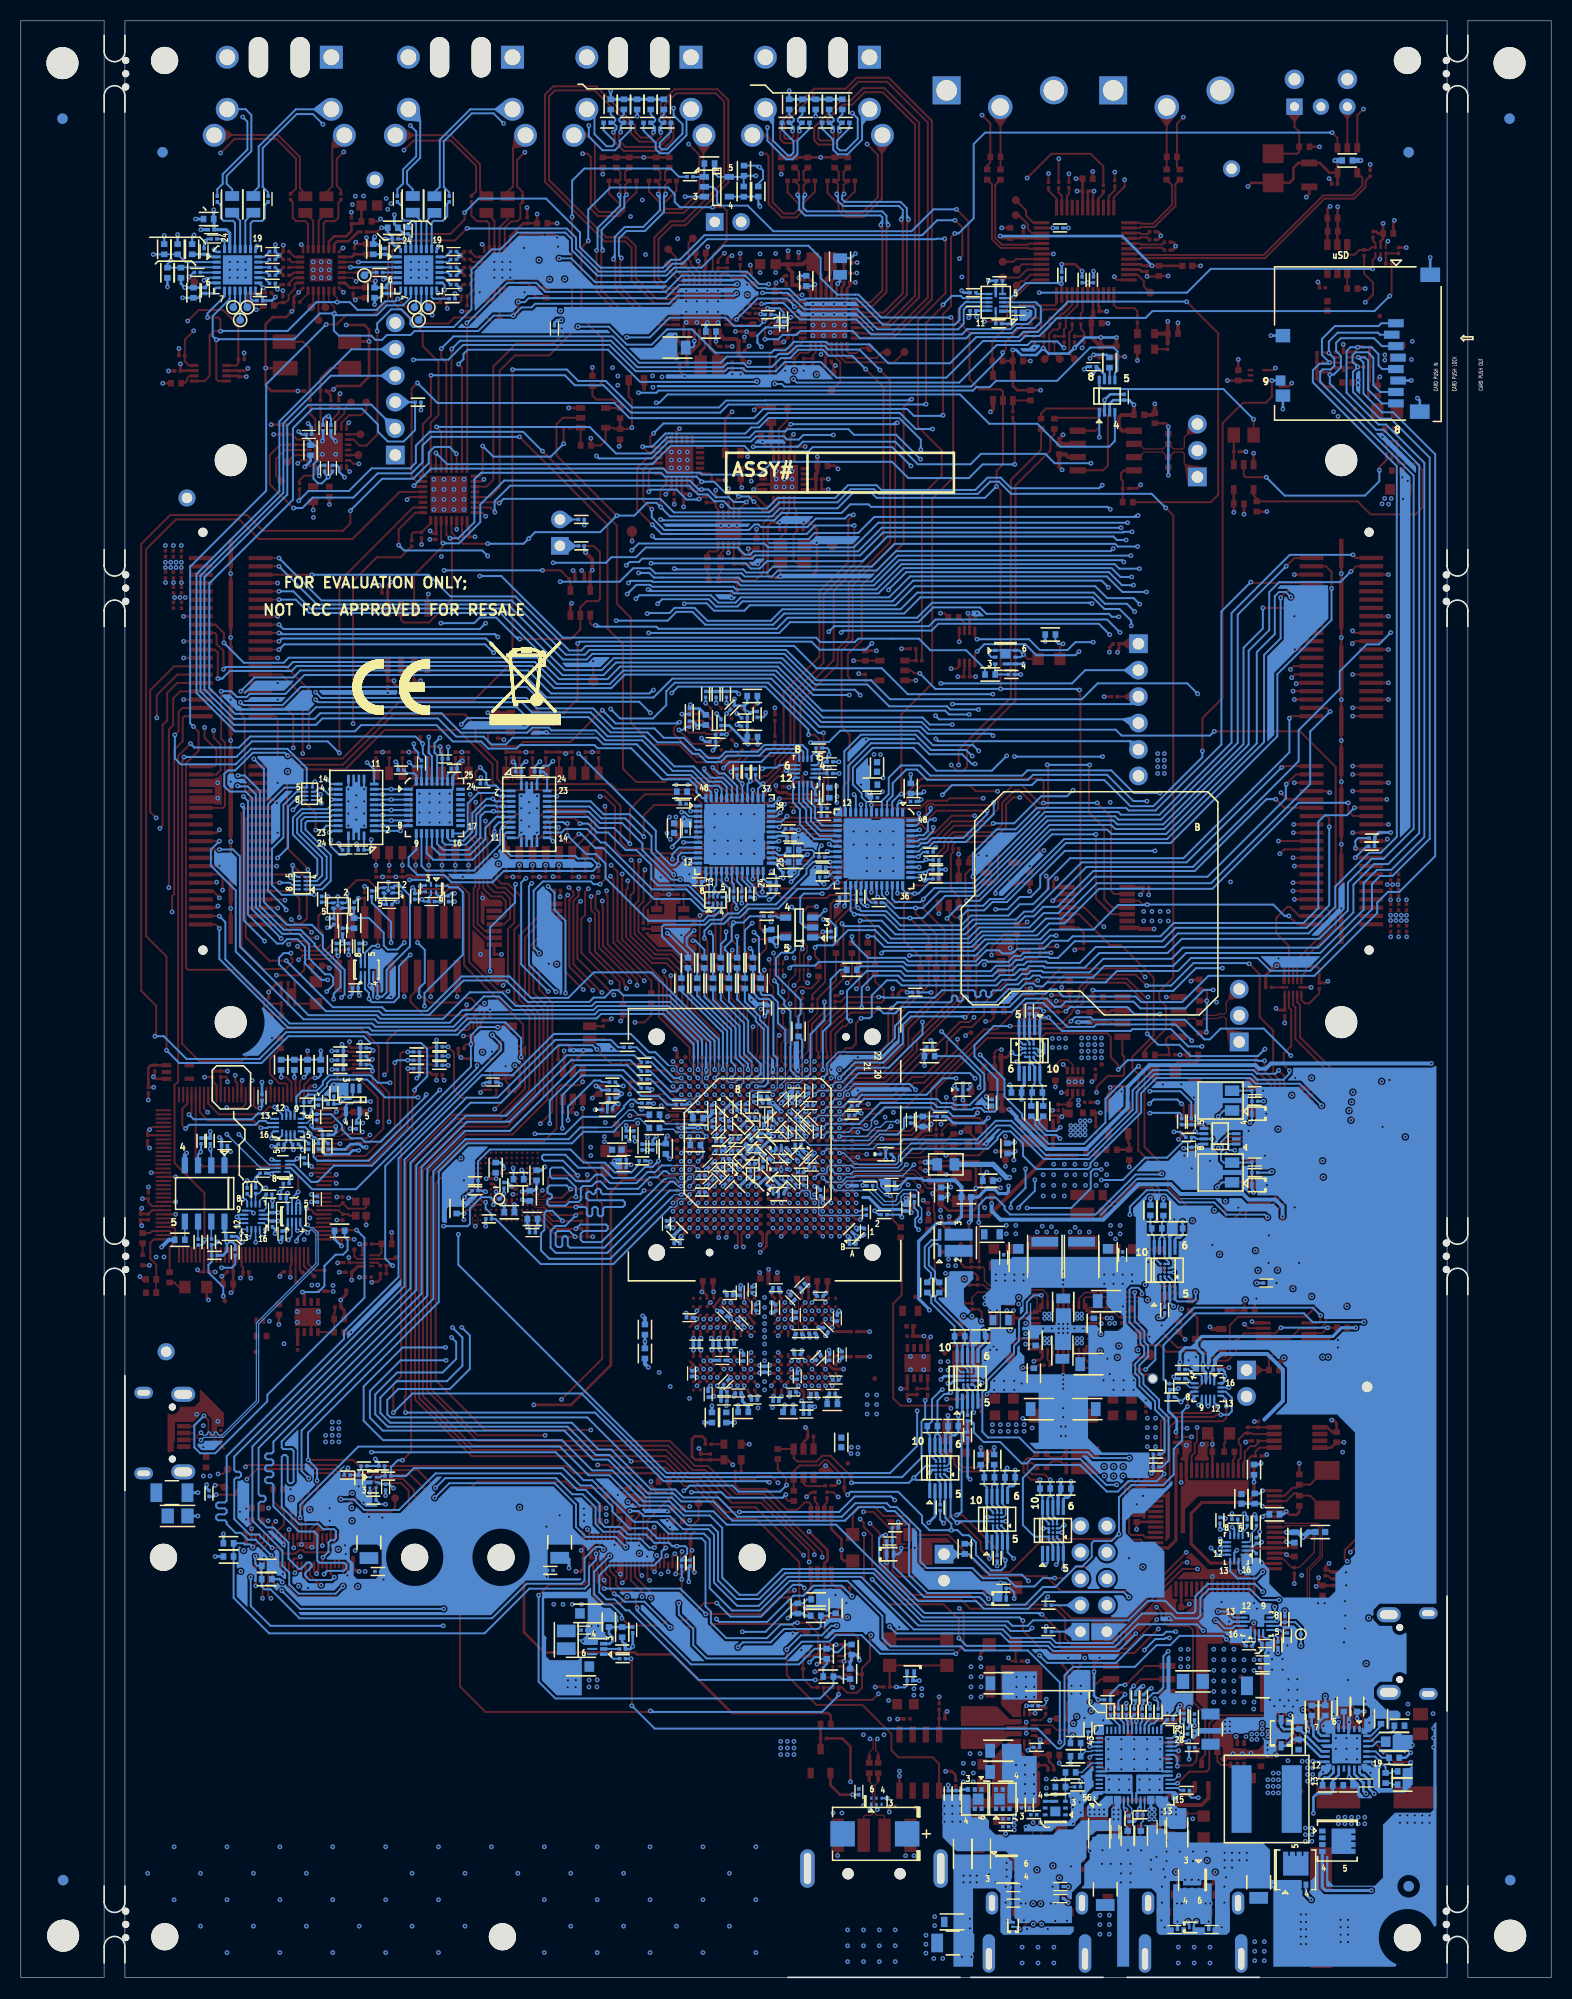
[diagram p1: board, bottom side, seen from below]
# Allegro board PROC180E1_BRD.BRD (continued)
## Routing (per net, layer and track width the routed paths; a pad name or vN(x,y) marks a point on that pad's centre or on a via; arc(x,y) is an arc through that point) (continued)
FT4232_USB_VBUS: length 6.5
  TOP w0.191: C295.1 v1(17.76,30.15)
  TOP w0.254: U67.1 C295.1
  L04_PWR1 w0.381: v1(17.52,34.52) 17.76,34.28 v1(17.76,30.15)
FT4232_WKUP_UART0_RX_3V3: length 22.7
  TOP w0.191: v1(32.05,54.88) 32.71,54.22 36.73,54.22 37.49,53.46 37.49,50.61 40.96,47.14 40.96,42.41 40.59,42.04 39.46,42.04 39.17,41.75 U64.38
  BOTTOM w0.191: U117.12 32.36,55.19 v1(32.05,54.88)
FT4232_WKUP_UART0_TX_3V3: length 24.2
  TOP w0.191: U64.39 38.96,42.25 39.2,42.49 40.35,42.49 40.54,42.68 40.54,46.94 37.08,50.41 37.08,53.27 36.52,53.83 32.38,53.83 32.16,54.05 v1(31.73,54.05)
  BOTTOM w0.191: U117.14 31.26,56.27 30.68,55.68 30.68,54.37 31,54.05 v1(31.73,54.05)
FT_PWREN#: length 1.8
  TOP w0.191: R330.1 30.43,49.86 30.54,49.74 U64.60
GPIO1_23_INTN: length 209.3
  TOP w0.191: R108.1 110.51,136.43 112.8,136.43 115.09,134.14 v1(115.09,120.44)
  L03_SIG01 w0.076: v1(38.56,85.12) 37.17,86.51 37.17,93.39 37.52,93.74 37.52,97.96 42.75,103.19 42.75,113.48 42.28,113.95 42.28,124.26 43.44,125.42 43.44,130.86 42.53,131.77 v1(42.53,133.53) 42.98,133.98 42.98,142.08 43.75,142.85 43.75,143.99 43.41,144.33 v1(43.41,147.95) ; v1(115.09,120.44) 107.43,120.44 105.56,118.56 105.56,115.48 104.58,114.5 104.58,110.07 102.53,108.01 102.53,107.49 99.56,104.53 96.64,104.53 95.12,103.02 93.38,103.02 93.38,103.01 93.09,103.01 93.08,103.02 90.77,103.02 89.25,104.53 89.25,105.34 88.66,105.94 88.66,106.59 89.1,107.03 89.1,107.47 87.84,108.72 87.84,109.77 87.7,109.91 87.7,126.66 85.69,128.66 85.69,131.27 85.84,131.42 v1(85.84,131.95)
  BOTTOM w0.191: v1(38.56,85.12) 35.61,85.12 34.57,84.08 R547.2 ; U79.1 v1(43.41,147.95) ; v1(42.53,133.53) 43.18,134.18 61.29,134.18 63.28,132.19 77.67,132.19 78.17,131.69 80.21,131.69 80.91,132.39 85.4,132.39 v1(85.84,131.95)
GPIO1_23_INTN_1V8: length 118.1
  TOP w0.191: U47.Y22 82.36,89.47 85.33,92.44 85.33,95.8 89.24,99.71 v1(89.24,106)
  L03_SIG01 w0.076: v1(89.24,106) 89.24,106.75 89.43,106.94 89.43,108.79 87.89,110.32 87.89,126.77 85.87,128.79 85.87,131.2 86.26,131.58 86.26,132.43 85.94,132.74 85.94,136.78 87.29,138.13 87.29,145.12 86.71,145.7 86.71,148.62 85.97,149.36 85.97,151.26 v1(85.97,151.27)
  BOTTOM w0.191: U79.4 41.91,147.59 42.45,147.04 47.14,147.04 49.35,149.25 53.97,149.25 56.78,152.06 84.88,152.06 85.67,151.27 v1(85.97,151.27)
GPIO2_BUF_EN: length 2.8
  TOP w0.191: U51.5 112.59,69.36 112.36,69.59 112.36,70.45 ; 112.36,70.45 R278.2 ; 112.36,70.45 R277.1
GPIO_CPSW1_RST: length 186.8
  TOP w0.191: v1(92.25,52.58) 92.27,52.6 102.39,52.6 107.14,57.35 107.14,76.29 v1(104.73,78.71) ; R364.1 66.52,32.54 66.98,33 69.3,33 72.23,35.93 72.23,39.9 76.4,44.08 79.25,44.08 82.38,47.21 83.26,47.21 85.02,48.97 90.33,48.97 90.59,49.23 v1(91.58,49.23) ; v1(116.4,117.61) 116.4,134.12 109.31,141.21 U21.2 ; v1(131.33,117.23) 131.43,117.14 131.43,116.9 131.51,116.82 131.51,89.68 129.84,88.01 125.79,88.01 122.64,91.16 114.33,91.16 112.62,89.44 112.62,85.96 111.63,84.97 v1(111.63,82.19)
  L03_SIG01 w0.076: v1(111.63,82.19) 108.15,78.71 v1(104.73,78.71) ; v1(92.25,52.58) 92.25,50.89 91.58,50.22 v1(91.58,49.23)
  BOTTOM w0.191: v1(116.4,117.61) 117.52,118.73 124.8,118.73 126.3,117.23 v1(131.33,117.23)
GPIO_CPSW2_RST: length 113.2
  TOP w0.191: v1(110.7,137.59) 110.7,139.1 109.1,140.71 U21.1 ; v1(100.68,95.3) 100.21,95.77 100.21,100.71 99.6,101.32 99.6,103.81 100.47,104.68 101.25,104.68 101.76,105.19 101.76,107.39 v1(101.36,107.79)
  L03_SIG01 w0.076: v1(101.36,107.79) 104.22,110.66 104.22,114.85 104.1,114.98 104.1,128.9 102.15,130.85 v1(102.15,136.55) ; v1(115.57,48.94) 113.46,51.06 112.61,51.06 104,59.67 104,77.67 102.17,79.5 102.17,81.45 99.99,83.63 99.99,93.88 100.68,94.57 v1(100.68,95.3)
  BOTTOM w0.191: v1(102.15,136.55) 102.68,137.08 110.19,137.08 v1(110.7,137.59) ; R604.1 115.92,48.26 115.92,48.59 v1(115.57,48.94)
GPIO_DIX_RST: length 65.8
  TOP w0.191: R79.1 51.71,149.48 51.52,149.29 v1(51.52,145.35) ; U21.6 109.16,143.21 v1(109.25,143.29)
  BOTTOM w0.191: v1(51.52,145.35) 54.61,145.35 55.92,144.03 61.76,144.03 63.32,145.6 74.79,145.6 76.02,144.36 81.57,144.36 81.76,144.55 84.88,144.55 85.27,144.95 107.59,144.95 v1(109.25,143.29)
GPIO_EMMC_RSTN: length 124.1
  TOP w0.191: R116.1 60.44,142.37 58.54,144.28 58.54,146.7 60.83,148.99 60.83,159.15 58.18,161.8 58.18,166.96 v1(58.25,167.03) ; v1(104.13,168.02) 105.3,166.86 110.35,166.86 111.32,165.88 111.32,161 108.4,158.07 108.4,156.71 106.88,155.19 106.88,150.09 107.63,149.34 U21.9
  BOTTOM w0.191: v1(58.25,167.03) 59.05,167.03 59.1,166.98 81.09,166.98 83.44,164.63 84.39,164.63 85.15,163.87 89.33,163.87 89.65,163.87 91.47,163.87 93.67,166.06 93.67,167.12 94.56,168.01 103.97,168.01 103.98,168.02 v1(104.13,168.02)
GPIO_MCU_SOC: length 2.5
  BOTTOM w0.191: U98.5 33.34,81.79 33.48,81.93 R547.1 R546.1
GPIO_MCU_SOC_INTN: length 130.8
  TOP w0.14: U47.B9 v1(67.56,77.59)
  TOP w0.191: v1(56.9,32.59) 56.9,34.38 58.35,35.83 63.61,35.83 66.01,38.23 v1(66.01,42.58)
  L03_SIG01 w0.076: v1(38.55,83.02) 38.94,82.64 38.94,73.48 36.85,71.39 36.85,62.21 37.45,61.61 37.45,59.98 37.45,59.89 37.45,59.5 37.45,57.38 37.7,57.13 37.7,54.58 38.4,53.88 38.4,49.17 37.99,48.77 37.99,41.36 39.9,39.45 v1(39.9,33.02) ; v1(66.01,42.58) 65.95,42.64 65.7,42.64 65.02,43.32 65.02,45.9 63.97,46.95 63.97,61.39 63.18,62.18 63.18,72.99 64.58,74.39 64.58,74.92 65.74,76.08 v1(66.15,76.08) 66.15,76.09 66.63,76.58 66.63,76.59 66.68,76.63 66.68,77.13 67.14,77.59 v1(67.56,77.59)
  BOTTOM w0.191: v1(66.15,76.08) 66.12,76.08 66.08,76.04 R563.2 ; v1(56.9,32.59) 56.15,31.84 54.51,31.84 49.71,31.84 48.35,31.84 47.86,31.36 41.57,31.36 v1(39.9,33.02) ; R546.2 35.5,82.86 35.7,83.05 38.53,83.05 v1(38.55,83.02)
GPIO_OSPI_RSTN: length 81.9
  TOP w0.132: U47.G19 v1(71.56,86.39)
  TOP w0.191: R121.1 93.52,122.8 v1(93.52,128.14)
  L03_SIG01 w0.076: v1(69.81,93.71) 69.16,94.36 69.16,100.97 67.5,102.63 67.5,103.42 65.35,105.57 65.35,110.44 65.69,110.78 65.69,112.83 65.1,113.42 65.1,115.32 65.76,115.99 65.76,118.25 65.25,118.77 v1(65.25,128.15)
  BOTTOM w0.14: 71.16,88.34 71.16,86.79 v1(71.56,86.39)
  BOTTOM w0.191: 71.16,88.34 71.16,90.59 69.81,91.95 v1(69.81,93.71) ; v1(65.25,128.15) 65.86,127.54 70.28,127.54 71.05,128.31 93.34,128.31 v1(93.52,128.14)
GPIO_PCM1_RST: length 13.7
  TOP w0.191: R84.1 94.86,147.35 v1(94.85,147.34) ; v1(102.64,147.11) 102.64,144.49 102.92,144.21 U21.17
  BOTTOM w0.191: v1(94.85,147.34) 96.09,146.09 101.62,146.09 v1(102.64,147.11)
GPIO_PCM2_RST: length 47.9
  TOP w0.191: v1(94.04,169.11) 94.06,169.09 94.06,158.72 95.84,156.95 99.42,156.95 101.62,154.75 101.62,143.86 102.27,143.21 U21.19
  BOTTOM w0.191: R414.1 83.78,172.98 84.57,173.77 92.88,173.77 94.04,172.6 v1(94.04,169.11)
HB_LM5141: length 5.3
  BOTTOM w0.254: U128.11 22.18,21.2 23.82,22.85 C629.2 24.87,22.85 25.48,22.24 D15.1
HO_LM5141: length 2.3
  BOTTOM w0.254: U128.13 20.91,19.67 21.4,19.18 21.77,19.18 21.96,18.99 R671.1
HOL_LM5141: length 24.1
  L03_SIG01 w0.254: v1(22.84,15.75) 17.27,10.18 v1(17.27,8.34)
  BOTTOM w0.254: v1(22.84,15.75) 22.84,17.3 22.46,17.68 21.17,17.68 20.98,17.87 R671.2 20.98,18.88 20.41,19.45 U128.14
  BOTTOM w0.305: v1(17.27,8.34) 21.67,8.34 21.98,8.65 U131.4
HW/SW_CTRL_SEL: length 3.3
  TOP w0.191: U15.23 120.46,147.73 120.95,148.22 R85.1 121.48,148.22 R83.2
I2C0_SCL_R: length 42.9
  TOP w0.132: U47.D17 v1(69.16,84.79)
  TOP w0.191: v1(47.55,93.79) R200.2 R204.1 46.26,93.79 R195.1
  L03_SIG01 w0.076: v1(61.65,98.16) 61.45,97.96 61.45,90.44 65.38,86.51 67.53,86.51 68.07,85.98 68.54,85.98 68.78,85.74 68.78,85.17 v1(69.16,84.79) ; v1(47.55,100.07) 46.89,99.41 46.89,96.23 47.72,95.4 47.72,94.69 47.55,94.53 v1(47.55,93.79)
  BOTTOM w0.191: v1(47.55,100.07) 48.12,100.07 48.86,99.33 50.67,99.33 50.99,99.33 54.1,99.33 55.27,98.16 v1(61.65,98.16)
I2C_ADDR0_A0: length 47.3
  TOP w0.191: J18.47 92.41,38.18 92.86,37.73 96.25,37.73 v1(97.27,36.71)
  BOTTOM w0.191: v1(97.27,36.71) 97.27,28.41 95.64,26.79 70.23,26.79 68.95,28.07 R642.2 68.35,28.89 68.11,28.65 R641.1
I2C_ADDR0_A2: length 29.8
  TOP w0.191: v1(87.79,35.5) 87.95,35.66 87.95,36.76 88.28,37.1 89.22,37.1 89.82,37.69 89.82,38.45 90.41,39.05 J18.37
  BOTTOM w0.191: v1(87.79,35.5) 87.79,35.22 82.63,30.06 72.25,30.06 70.75,31.57 R639.2 69.13,31.57 68.8,31.23 68.49,31.23 67.76,31.97 R638.1
I2C_ADDR1_A0: length 66.6
  TOP w0.191: v1(124.92,38.43) 124.84,38.52 J19.47
  L03_SIG01 w0.076: v1(78.12,31.71) 79.1,32.7 82.01,32.7 85.45,29.26 101.92,29.26 v1(106.42,33.77)
  BOTTOM w0.191: v1(78.12,31.71) 77.65,32.18 74.97,32.18 73.69,33.46 70.38,33.46 70.15,33.69 R630.1 69.51,34.73 69.27,34.98 R628.2 ; v1(106.42,33.77) 123.02,33.77 124.92,35.67 v1(124.92,38.43)
I2C_ADDR1_A2: length 59.2
  TOP w0.191: J19.37 122.84,38.05 v1(121.93,37.14)
  L03_SIG01 w0.076: v1(106.38,35.4) 101.03,30.05 85.66,30.05 82.53,33.19 v1(77.7,33.19)
  BOTTOM w0.191: v1(77.7,33.19) 75.47,33.19 72.73,35.93 R629.1 71.85,35.93 71.46,36.31 R626.2 ; v1(106.38,35.4) 120.19,35.4 v1(121.93,37.14)
INA_ALERT: length 102.3
  TOP w0.191: v1(48.76,92.81) 48.07,92.81 48.01,92.76 TP46.1 46.67,92.76 v1(46.62,92.81) ; R305.2 37.37,63.38 v1(37.7,63.38) ; v1(58.36,43.62) 57.57,44.41 v1(57.11,44.41) 56.54,44.41 53.22,41.08 v1(53.22,39.52)
  L03_SIG01 w0.076: v1(41.74,47.31) 40.33,47.31 38.96,48.68 38.96,49.97 39.44,50.45 39.44,58.59 38.16,59.87 38.16,62.87 37.91,63.12 37.91,63.16 v1(37.7,63.38) 37.46,63.62 37.46,70.87 39.42,72.83 39.42,85.06 37.58,86.9 v1(37.58,92.54)
  BOTTOM w0.191: R608.2 58.69,43.95 v1(58.36,43.62) ; R505.2 49.07,93.12 v1(48.76,92.81) ; R619.2 v1(53.22,39.52) ; R586.2 37.13,63.51 37.32,63.32 37.64,63.32 v1(37.7,63.38) ; v1(37.58,92.54) 40.03,92.54 40.71,93.21 46.21,93.21 v1(46.62,92.81) ; v1(41.74,47.31) 42.74,47.31 45.23,49.8 49.97,49.8 50.39,49.37 50.86,49.37 52.92,51.43 54.53,51.43 55.46,52.36 55.46,53.2 55.71,53.45 R596.2 R597.1 56.34,52.38 56.63,52.09 56.63,44.71 56.93,44.41 v1(57.11,44.41)
IO_EXP0_INTN: length 3.1
  TOP w0.191: U21.32 107.63,139.71 R106.1 109.27,138.83 109.46,138.63 R108.2
IO_EXP1_INTN: length 1.3
  TOP w0.191: U18.22 84,142.99 84.24,142.75 R98.1
IO_EXP_ADDR: length 1.4
  BOTTOM w0.191: R456.1 105.66,115.9 106.01,115.55 U82.26
IO_EXP_OPT_EN: length 132.5
  TOP w0.191: v1(21.04,177.22) 20.53,176.71 U1.1 ; v1(58.41,150.06) 58.41,159.79 57.65,160.55 57.65,167.18 v1(57.29,167.54) ; U21.7 108.97,143.71 109.46,144.2 109.46,152.61 v1(108.91,153.17) ; v1(21.34,172.8) 21.09,172.55 R12.2
  L03_SIG01 w0.076: v1(21.34,172.8) 21.6,173.07 21.6,175.53 21.04,176.09 v1(21.04,177.22)
  BOTTOM w0.191: v1(58.41,150.06) 58.47,150.01 61.21,150.01 61.88,150.67 75.68,150.67 76.56,149.79 88.53,149.79 89.98,151.24 106.98,151.24 v1(108.91,153.17) ; v1(57.29,167.54) 56.92,167.54 55.47,168.99 55.47,176.12 54.37,177.22 v1(21.04,177.22)
IO_EXP_TEST_LED: length 60.2
  TOP w0.191: U21.24 102.68,140.71 v1(102.34,140.36)
  L03_SIG01 w0.076: v1(102.34,140.36) 102.34,139.14 102.87,138.62 102.87,134.67 v1(102.91,134.62)
  BOTTOM w0.191: v1(102.91,134.62) 100.85,134.62 94.93,128.7 70.61,128.7 70.19,128.28 66.88,128.28 66.56,128.61 63.42,128.61 63.1,128.61 60.73,128.61 59.62,127.49 56.2,127.49 54.38,125.68 R441.1
IO_MCAN0_STB: length 116
  TOP w0.191: U21.21 101.93,142.21 101.01,143.13 101.01,154.34 99.53,155.82 96.24,155.82 v1(93.48,158.58) ; v1(35,160.97) 31.98,157.95 31.98,142.42 32.69,141.72 R102.2
  BOTTOM w0.191: v1(35,160.97) 35.02,160.98 46.41,160.98 49.33,158.06 49.46,158.06 49.77,158.06 50.69,158.06 51.18,157.58 51.95,157.58 55.22,157.58 57.74,155.06 63.67,155.06 65.49,156.88 69.39,156.88 69.63,157.12 72.74,157.12 73.54,156.32 74.65,156.32 74.9,156.08 80.29,156.08 82.54,158.32 84.92,158.32 86.39,156.85 88.78,156.85 90.51,158.58 v1(93.48,158.58)
IO_MCAN1_STB: length 124.3
  TOP w0.191: v1(101.04,141.62) 101.12,141.71 U21.22 ; R223.2 39.04,89.08 37,91.12 37,93.3 37.65,93.96 37.65,94.69 36.3,96.05 36.3,140.45 v1(37.02,141.17)
  BOTTOM w0.191: v1(101.04,141.62) 100.62,142.04 85.57,142.04 84.27,140.73 75.11,140.73 74.14,141.7 68.56,141.7 67.29,142.96 65.04,142.96 64.59,142.51 55.07,142.51 53.9,143.69 53.05,143.69 51.88,142.52 38.37,142.52 v1(37.02,141.17)
JTAG_CTI_RTCK: length 7.1
  TOP w0.191: J14.9 v1(111.44,99.39)
  BOTTOM w0.191: v1(111.44,99.39) 111.44,101.39 113.29,103.24 R476.1
JTAG_CTI_TCK: length 14.9
  TOP w0.191: v1(110.17,99.39) J14.11 110.17,103.82 v1(110.53,104.18)
  BOTTOM w0.191: v1(110.17,99.39) 110.83,98.73 111.75,98.73 112.14,99.12 112.14,100.35 113.55,101.77 R487.1 R485.1 U88.1 ; v1(110.53,104.18) U87.1
JTAG_DIR: length 3.1
  BOTTOM w0.14: U110.4 123.67,73.66 123.43,73.89 R569.2 124.05,74.61 U110.5
JTAG_EMU0: length 16.7
  TOP w0.191: U39.7 103.18,91.95 103.45,92.22 R211.2 103.1,92.43 102.91,92.62 102.91,93.23 103.74,94.07 104.47,94.07 104.89,93.65 107.73,93.65 108.27,94.19 v1(108.74,94.19) ; J14.13 v1(108.9,99.41)
  BOTTOM w0.191: v1(108.74,94.19) 108.74,95.02 108.2,95.56 108.2,98.71 v1(108.9,99.41)
JTAG_EMU1: length 10.2
  TOP w0.191: J14.14 108.9,94.91 109.57,94.24 109.57,93.71 108.28,92.43 R212.2 104.21,92.13 104.12,92.04 103.86,92.04 103.53,91.71 U39.6
JTAG_EMU_RSTN: length 6.9
  TOP w0.191: v1(105.32,104.13) 105.75,104.13 106.08,103.8 107.34,103.8 107.63,103.51 J14.15
  BOTTOM w0.191: v1(105.32,104.13) 105.7,104.13 R482.2 106.94,103.9 107.1,104.06 U86.6
JTAG_TCK: length 43.5
  TOP w0.191: v1(121.27,99.24) 120.94,99.57 119.82,99.57 119.27,99.02 118.34,99.02 118.01,99.35 118.01,100.35 118.41,100.75 118.41,101.97 117.5,102.89 v1(117.5,103.84)
  L03_SIG01 w0.076: v1(121.27,99.24) 121.89,98.62 121.89,96.66 121.34,96.11 121.34,86.22 122.29,85.28 123.22,85.28 125.06,83.45 125.06,78.74 127.2,76.6 127.2,72.02 126.25,71.07 v1(125.1,71.07)
  BOTTOM w0.14: U110.14 124.85,71.31 v1(125.1,71.07)
  BOTTOM w0.191: R483.1 v1(117.5,103.84)
JTAG_TDI: length 37.3
  TOP w0.191: J14.3 115.25,99.22 115.81,98.66 117.15,98.66 117.58,98.22 119.85,98.22 v1(120.32,97.76)
  L03_SIG01 w0.076: v1(120.32,97.76) 120.32,86.14 121.79,84.66 122.13,84.66 124.59,82.2 124.59,78.53 126.63,76.49 126.63,72.54 v1(126.24,72.14)
  BOTTOM w0.14: U110.12 125.93,72.46 v1(126.24,72.14)
JTAG_TDIS: length 2.7
  TOP w0.191: v1(115.51,98.23) 115.25,97.96 J14.4
  BOTTOM w0.14: R490.2 v1(115.51,98.23)
JTAG_TDO: length 4.8
  TOP w0.191: J14.7 v1(112.71,99.09)
  BOTTOM w0.191: U90.7 113.95,98.4 113.25,99.09 v1(112.71,99.09)
JTAG_TMS: length 38.4
  TOP w0.191: v1(120.43,99.05) 120.01,98.63 117.76,98.63 117.01,99.38 117.01,99.65 116.52,100.14 J14.1
  L03_SIG01 w0.076: v1(125.83,71.48) 126.2,71.48 126.94,72.22 126.94,76.55 124.84,78.66 124.84,83.24 123.05,85.03 122.23,85.03 121.12,86.15 121.12,86.63 121.08,86.67 121.08,97.68 120.43,98.33 v1(120.43,99.05)
  BOTTOM w0.14: U110.13 125.69,71.86 125.83,71.72 v1(125.83,71.48)
JTAG_TRST#: length 42.8
  TOP w0.191: J14.2 v1(116.52,98.13) 116.94,98.13 117.24,97.83 119.52,97.83 119.77,97.58 119.77,96.78 120.29,96.27 v1(122.45,96.27)
  L03_SIG01 w0.076: v1(124.44,70.6) 124.79,70.25 125.87,70.25 127.55,71.92 127.55,76.63 125.32,78.85 125.32,83.58 123.33,85.57 122.33,85.57 121.6,86.3 121.6,95.42 v1(122.45,96.27)
  BOTTOM w0.14: R489.2 116.71,98.32 v1(116.52,98.13) ; U110.15 124.45,71.12 124.44,71.11 v1(124.44,70.6)
LDO_1V8: length 1.6
  TOP w0.254: v1(39.85,24.61) 40.02,24.44 C303.1
  BOTTOM w0.191: U129.35 v1(39.85,24.61)
LDO_3V3: length 32.6
  TOP w0.191: R374.1 v1(43.91,29.35)
  TOP w0.254: U71.5 C300.2 23.12,25.45 23.37,25.7 v1(23.82,25.7) ; R378.1 35.34,26.37 35.6,26.12 v1(35.66,26.12) ; v1(43.91,29.35) C292.1 U69.8
  TOP w0.381: v1(39.55,16.18) 39.55,15.46 C319.2 ; v1(35.66,26.12) 35.31,25.76 35.31,25.18 35.78,24.7 38.88,24.7 39.52,25.34 ; v1(43.52,26.67) 43.52,25.59 43.25,25.32 39.54,25.32 39.52,25.34 ; 39.52,25.34 39.52,27.65 v1(39.2,27.97)
  BOTTOM w0.203: v1(39.55,16.18) 39.45,16.28 U129.9
  BOTTOM w0.254: v1(39.55,16.18) 39.77,15.97 R678.1 39.77,15.24 40.05,14.96 R679.1 ; v1(43.91,29.35) 43.91,27.06 v1(43.52,26.67) R646.1 ; R658.1 v1(35.91,25.36) ; v1(35.91,25.36) 35.91,25.87 v1(35.66,26.12) ; v1(35.91,25.36) 36.06,25.36 36.31,25.1 R660.1 ; v1(39.2,27.97) 39.41,27.97 39.92,27.46 R644.1 ; R664.1 34.76,24.08 v1(34.76,25.84)
LO_LM5141: length 3.5
  BOTTOM w0.254: U128.8 22.33,22.7 22.84,23.21 22.84,24.09 23,24.25 R650.1
LOL_LM5141: length 2.9
  BOTTOM w0.254: R649.1 22.38,24.47 22.38,23.51 22.08,23.2 U128.7
LPDDR4_CA0: length 33.7
  TOP w0.33: U58.R2 v1(77.51,56.83) ; U58.H2 v1(73.61,56.83)
  TOP w0.391: U47.J5 v1(73.16,74.39)
  L03_SIG01 w0.076: v1(77.51,56.83) 77.51,56.37 77.41,56.27 77.12,56.27 77.04,56.36 77.04,56.48 76.95,56.56 76.65,56.56 76.44,56.35 76.04,56.35 75.96,56.43 v1(75.56,56.43) 75.15,56.43 75.07,56.35 74.68,56.35 74.47,56.56 74.16,56.56 74.08,56.48 74.08,56.36 74,56.27 73.71,56.27 73.61,56.37 v1(73.61,56.83)
  L07_GND02 w0.152: v1(73.16,74.39) 73.16,74.16 72.76,73.76 72.76,73.39 72.57,73.19 72.19,73.19 71.96,72.96 71.96,72.63 71.72,72.39 71.39,72.39 71.16,72.16 71.16,71.79 67.51,68.14 67.51,62.54 69.39,60.66 72.95,60.66 73.21,60.39 73.21,59.6 73.59,59.22 73.59,57.57 74.74,56.41 75.54,56.41 v1(75.56,56.43)
LPDDR4_CA1: length 33.7
  TOP w0.33: U58.P2 v1(76.86,57.63) ; U58.J2 v1(74.26,57.63)
  TOP w0.391: U47.J2 v1(73.16,71.99)
  L03_SIG01 w0.076: v1(74.26,57.63) 74.02,57.39 74.02,57.24 74.11,57.15 74.61,57.15 74.72,57.26 74.72,57.56 74.8,57.64 75.06,57.64 75.13,57.56 75.13,57.32 75.22,57.23 v1(75.56,57.23) 75.9,57.23 75.98,57.32 75.98,57.56 76.06,57.64 76.32,57.64 76.4,57.56 76.4,57.26 76.5,57.15 77.01,57.15 77.1,57.24 77.1,57.39 v1(76.86,57.63)
  L07_GND02 w0.152: v1(73.16,71.99) 72.72,71.55 72.33,71.55 72.08,71.3 72.08,71.07 71.79,70.78 70.81,70.78 67.97,67.94 67.97,62.76 69.65,61.08 72.92,61.08 73.1,61.26 73.1,61.83 73.25,61.98 73.59,61.98 73.75,61.81 73.75,61.38 73.92,61.21 74.51,61.21 74.66,61.06 74.66,60.71 74.51,60.56 73.99,60.56 73.8,60.37 73.8,59.82 73.99,59.63 74.49,59.63 74.67,59.45 74.67,57.82 74.91,57.58 75.21,57.58 v1(75.56,57.23)
LPDDR4_CA2: length 33.7
  TOP w0.33: U58.H9 v1(72.96,62.43) ; U58.R9 v1(78.16,62.43)
  TOP w0.391: U47.J4 v1(73.96,74.39)
  L03_SIG01 w0.076: v1(72.96,62.43) 73.33,62.8 v1(75.56,62.8) 77.79,62.8 v1(78.16,62.43)
  L07_GND02 w0.152: v1(73.96,74.39) U47.J4 73.56,71.74 72.11,70.29 70.97,70.29 68.45,67.78 68.45,65.86 68.59,65.73 69.12,65.73 69.26,65.59 69.26,65.27 69.13,65.13 68.59,65.13 68.46,65 68.46,64.69 68.62,64.53 69.36,64.53 69.46,64.43 71.85,64.43 72.07,64.21 72.07,63.83 71.87,63.63 70.33,63.63 70.18,63.48 70.18,63.05 70.32,62.9 70.61,62.9 70.82,62.7 71.13,62.7 71.27,62.83 71.94,62.83 72.1,62.67 72.41,62.67 72.56,62.83 74.46,62.83 74.83,62.46 75.22,62.46 v1(75.56,62.8)
LPDDR4_CA3: length 33.7
  TOP w0.33: U58.R10 v1(77.51,63.23) ; U58.H10 v1(73.61,63.23)
  TOP w0.391: U47.L4 v1(74.76,73.59)
  L03_SIG01 w0.076: v1(77.51,63.23) 77.51,63.52 77.43,63.6 76.54,63.6 76.44,63.5 76.44,63.27 76.35,63.18 76.1,63.18 76.02,63.26 76.02,63.38 75.94,63.46 v1(75.56,63.46) 75.18,63.46 75.1,63.38 75.1,63.26 75.01,63.18 74.77,63.18 74.68,63.27 74.68,63.5 74.57,63.6 73.68,63.6 73.61,63.52 v1(73.61,63.23)
  L07_GND02 w0.152: v1(75.56,63.46) 75.56,63.78 75.95,64.18 75.96,64.18 75.96,64.51 75.81,64.66 75.81,65 76.05,65.24 76.05,67.13 76.45,67.53 76.45,67.9 75.85,68.5 74.12,68.5 73.96,68.66 73.96,68.92 74.11,69.07 75.29,69.07 75.47,69.25 75.47,71.25 75.22,71.51 75.22,72.62 75.37,72.77 75.65,72.77 75.82,72.61 75.82,71.83 76.1,71.54 76.46,71.54 76.73,71.27 76.73,70.88 76.88,70.73 77.43,70.73 77.6,70.91 77.6,71.38 77.75,71.54 78.02,71.54 78.17,71.38 78.17,70.86 78.3,70.74 78.58,70.74 78.71,70.87 78.71,71.32 79.16,71.78 79.16,72.21 78.97,72.39 76.93,72.39 76.76,72.57 76.76,72.98 76.55,73.19 76.08,73.19 75.84,73.44 75.84,73.64 75.6,73.88 75.05,73.88 v1(74.76,73.59)
LPDDR4_CA4: length 33.7
  TOP w0.33: U58.H11 v1(73.61,64.03) ; U58.R11 v1(77.51,64.03)
  TOP w0.391: U47.J1 v1(73.96,71.19)
  L03_SIG01 w0.076: v1(73.61,64.03) 73.61,64.32 73.68,64.4 74.01,64.4 74.1,64.3 74.1,64.11 74.19,64.03 74.41,64.03 74.51,64.12 74.51,64.27 74.59,64.35 v1(75.56,64.35) 76.53,64.35 76.61,64.27 76.61,64.12 76.7,64.03 76.93,64.03 77.01,64.11 77.01,64.3 77.11,64.4 77.43,64.4 77.51,64.32 v1(77.51,64.03)
  L07_GND02 w0.152: v1(75.56,64.35) 75.32,64.59 75.32,64.99 74.91,65.39 74.19,65.39 74.04,65.24 74.04,64.63 73.83,64.43 72.57,64.43 72.06,64.94 72.06,65.18 71.82,65.42 71.39,65.42 71.21,65.6 71.21,65.96 70.94,66.23 70.45,66.23 70.22,66.45 70.22,67.59 71.47,68.84 72.87,68.84 72.97,68.95 72.97,69.19 72.84,69.32 71.3,69.32 69.73,67.75 69.73,66.35 69.57,66.2 69.36,66.2 69.23,66.32 69.23,67.91 71.13,69.81 72.87,69.81 73.06,70 73.06,70.59 73.45,70.97 73.74,70.97 v1(73.96,71.19)
LPDDR4_CA5: length 33.7
  TOP w0.33: U58.P11 v1(77.51,64.83) ; U58.J11 v1(73.61,64.83)
  TOP w0.391: U47.K5 v1(74.76,74.39)
  L03_SIG01 w0.076: v1(77.51,64.83) 77.25,65.09 77.09,65.09 77.01,65.01 77.01,64.79 76.93,64.71 76.71,64.71 76.63,64.79 76.63,65.07 76.38,65.31 v1(75.56,65.31) 74.74,65.31 74.49,65.07 74.49,64.79 74.41,64.71 74.18,64.71 74.11,64.79 74.11,65.01 74.03,65.09 73.87,65.09 v1(73.61,64.83)
  L07_GND02 w0.152: v1(75.56,65.31) 75.56,65.75 75.35,65.95 75.35,66.42 75.53,66.59 75.53,67.42 75.38,67.57 75.13,67.57 74.99,67.43 74.99,66.87 74.84,66.71 74.3,66.71 74.17,66.84 73.74,66.84 73.6,66.7 73.6,66.45 73.45,66.3 72.91,66.3 72.81,66.41 72.81,66.64 72.68,66.77 72.35,66.77 72.22,66.89 72.22,67.16 72.38,67.32 73.78,67.32 73.9,67.43 73.9,67.72 73.78,67.84 72.03,67.84 71.11,66.92 70.88,66.92 70.72,67.08 70.72,67.4 71.7,68.38 73.32,68.38 73.47,68.54 73.47,69.38 73.65,69.56 74.8,69.56 74.95,69.71 74.95,69.9 74.8,70.04 73.78,70.04 73.65,70.17 73.65,70.37 73.8,70.52 74.79,70.52 74.95,70.67 74.95,71 74.81,71.13 74.6,71.13 74.46,71.27 74.46,71.61 74.36,71.72 74.36,73.99 v1(74.76,74.39)
LPDDR4_CAL0: length 9.4
  TOP w0.132: U47.H6 v1(72.36,75.19)
  BOTTOM w0.127: 70.36,74.41 70.36,73.35 70.2,73.19 68.62,73.19
  BOTTOM w0.14: v1(72.36,75.19) 71.96,75.59 71.3,75.59 71.16,75.45 71.16,74.93 71.02,74.79 70.54,74.79 70.36,74.61 70.36,74.41 ; 68.62,73.19 65.92,73.19 65.89,73.23 R573.1
LPDDR4_CK_N: length 30.6
  TOP w0.262: U58.P9 v1(76.86,62.43) ; U58.J9 v1(74.26,62.43) ; U47.L1 75.38,71.37 75.38,70.26 v1(75.98,69.65)
  L03_SIG01 w0.076: v1(74.26,62.43) 74.26,62.32 74.38,62.2 74.81,62.2 75.04,61.97 75.04,61.58 74.94,61.48 74.94,61.2 75.06,61.08 75.27,61.08 75.35,61.16 75.35,61.29 v1(75.56,61.5) 75.77,61.29 75.77,61.16 75.84,61.08 76.06,61.08 76.18,61.2 76.18,61.48 76.08,61.58 76.08,61.97 76.31,62.2 76.74,62.2 76.86,62.33 v1(76.86,62.43)
  L07_GND02 w0.133: v1(75.98,69.65) 76.12,69.8 76.73,69.8 77.15,69.38 78.44,69.38 78.84,68.98 78.84,67.85 79.44,67.25 81.09,67.25 81.23,67.11 81.23,66.68 81.1,66.54 79.13,66.54 78.19,67.48 78.19,68.45 77.85,68.79 77.3,68.79 77.01,68.5 77.01,67.11 77.2,66.92 77.2,65.42 76.85,65.08 76.85,63.37 76.17,62.69 76.17,61.48 75.97,61.28 75.78,61.28 v1(75.56,61.5)
LPDDR4_CK_P: length 30.6
  TOP w0.262: U58.P8 v1(76.86,61.63) ; U58.J8 v1(74.26,61.63) ; U47.M1 75.74,71.37 75.74,70.6 v1(75.98,70.36)
  L03_SIG01 w0.076: v1(74.26,61.63) 74.18,61.71 74.18,61.89 74.24,61.96 74.71,61.96 74.8,61.87 74.8,61.68 74.7,61.58 74.7,61.1 74.96,60.84 v1(75.56,60.84) 76.16,60.84 76.42,61.1 76.42,61.58 76.32,61.68 76.32,61.87 76.41,61.96 76.87,61.96 76.94,61.89 76.94,61.71 v1(76.86,61.63)
  L07_GND02 w0.133: v1(75.56,60.84) 75.76,61.04 76.07,61.04 76.41,61.39 76.41,62.59 77.09,63.27 77.09,64.98 77.43,65.33 77.43,67.02 77.24,67.21 77.24,68.4 77.4,68.56 77.75,68.56 77.96,68.35 77.96,67.38 79.03,66.31 81.19,66.31 81.46,66.58 81.46,67.2 81.18,67.49 79.54,67.49 79.07,67.95 79.07,69.08 78.54,69.62 77.24,69.62 76.83,70.03 76.31,70.03 v1(75.98,70.36)
LPDDR4_CKE0: length 33.7
  TOP w0.33: U58.J4 v1(74.26,59.23) ; U58.P4 v1(76.86,59.23)
  TOP w0.391: U47.P3 v1(77.16,72.79)
  L03_SIG01 w0.076: v1(76.86,59.23) 77.23,59.23 77.32,59.32 77.32,59.53 77.22,59.62 76.44,59.62 76.33,59.52 76.33,59.35 76.23,59.24 v1(75.56,59.24) 74.89,59.24 74.78,59.35 74.78,59.52 74.67,59.62 73.9,59.62 73.8,59.53 73.8,59.32 73.89,59.23 v1(74.26,59.23)
  L07_GND02 w0.152: v1(75.56,59.24) 75.55,59.24 75.14,59.65 75.14,60.2 75.34,60.41 75.94,60.41 76.64,61.1 77.12,61.1 77.38,61.35 77.38,61.73 77.67,62.01 78.32,62.01 78.68,62.37 78.68,62.49 79.01,62.83 83.34,62.83 83.55,63.04 83.55,66.26 81.23,68.57 80.19,68.57 79.77,68.99 79.77,70.11 80.39,70.73 80.39,71.25 79.96,71.68 79.96,72.96 79.73,73.19 U47.P3 v1(77.16,72.79)
LPDDR4_CKE1: length 33.7
  TOP w0.33: U58.J5 v1(74.26,60.03) ; U58.P5 v1(76.86,60.03)
  TOP w0.391: U47.P5 v1(77.16,74.39)
  L03_SIG01 w0.076: v1(76.86,60.03) 77.19,60.36 77.19,60.55 77.09,60.65 76.57,60.65 76.24,60.32 76.24,60.07 76.14,59.97 v1(75.56,59.97) 74.98,59.97 74.88,60.07 74.88,60.32 74.55,60.65 74.03,60.65 73.93,60.55 73.93,60.36 v1(74.26,60.03)
  L07_GND02 w0.152: v1(77.16,74.39) 77.56,73.99 79.75,73.99 79.96,73.79 79.96,73.38 80.14,73.19 80.55,73.19 80.76,72.99 80.76,71.68 81.83,70.61 81.83,70.12 82.08,69.87 82.08,68.58 84,66.66 84,62.2 83.71,61.9 83.28,61.9 83.1,62.08 82.52,62.08 82.35,61.9 78.92,61.9 78.62,61.6 78.31,61.6 77.99,61.28 77.99,60.96 77.5,60.47 76.67,60.47 76.33,60.14 76.33,59.87 76.18,59.72 75.81,59.72 v1(75.56,59.97)
LPDDR4_CS0_A: length 29.7
  TOP w0.33: U58.H4 v1(72.96,59.23)
  TOP w0.391: U47.J6 v1(73.16,75.19)
  L07_GND02 w0.152: v1(73.16,75.19) 73.16,74.96 72.76,74.56 72.76,74.23 72.52,73.99 72.18,73.99 71.96,73.77 71.96,73.43 71.72,73.19 71.39,73.19 71.16,72.96 71.16,72.6 70.95,72.39 70.58,72.39 70.36,72.17 70.36,71.8 70.15,71.59 69.78,71.59 69.56,71.37 69.56,70.84 67.05,68.33 67.05,60.45 67.18,60.33 67.44,60.33 67.55,60.44 67.55,61.27 67.7,61.42 67.92,61.42 68.09,61.25 68.09,60.94 68.22,60.82 68.58,60.82 68.86,60.55 68.86,58.86 69.01,58.71 69.39,58.71 69.51,58.83 69.87,58.83 69.88,58.83 70.02,58.83 70.13,58.72 70.13,58.56 70.25,58.44 70.48,58.44 70.59,58.56 70.59,58.69 70.73,58.83 71.34,58.83 71.43,58.74 71.43,58.56 71.54,58.44 71.78,58.44 71.89,58.56 71.89,58.73 71.99,58.83 72.79,58.83 72.96,59 v1(72.96,59.23)
LPDDR4_CS0_B: length 31.6
  TOP w0.33: U58.R4 v1(77.51,58.43)
  TOP w0.391: U47.M6 v1(76.36,75.19)
  L07_GND02 w0.152: v1(77.51,58.43) 78.11,58.43 78.51,58.83 79.13,58.83 79.35,59.05 79.35,59.63 79.5,59.78 82.83,59.78 84.46,61.41 84.46,68.22 84.25,68.44 84.06,68.44 83.7,68.08 83.51,68.08 83.38,68.22 83.38,68.4 83.73,68.76 83.73,68.95 83.6,69.08 83.41,69.08 83.05,68.73 82.87,68.73 82.73,68.86 82.73,69.05 83.09,69.41 83.09,69.6 82.49,70.19 82.49,71.61 82.36,71.75 82.36,72.18 82.14,72.39 81.79,72.39 81.56,72.63 81.56,72.96 81.32,73.19 80.99,73.19 80.76,73.43 80.76,73.76 80.52,73.99 80.17,73.99 79.96,74.21 79.96,74.62 79.79,74.79 76.76,74.79 v1(76.36,75.19)
LPDDR4_CS1_A: length 32.5
  TOP w0.33: U58.H3 v1(72.96,58.43)
  TOP w0.391: U47.N4 v1(77.16,73.59)
  L07_GND02 w0.152: v1(77.16,73.59) U47.N4 76.16,73.99 74.56,75.59 72.99,75.59 72.76,75.36 72.76,75.02 72.53,74.79 72.19,74.79 71.96,74.56 71.96,74.22 71.73,73.99 71.39,73.99 71.16,73.76 71.16,73.42 70.93,73.19 70.59,73.19 70.36,72.96 70.36,72.63 70.12,72.39 69.77,72.39 69.56,72.18 69.56,71.82 69.33,71.59 68.99,71.59 68.76,71.36 68.76,70.69 66.59,68.52 66.59,60.25 67.96,58.89 68.12,58.89 68.97,58.03 72.56,58.03 v1(72.96,58.43)
LPDDR4_CS1_B: length 32.5
  TOP w0.33: U58.R3 v1(77.51,57.63)
  TOP w0.391: U47.M5 v1(76.36,74.39)
  L07_GND02 w0.152: v1(77.51,57.63) 77.51,57.63 77.9,58.03 79.65,58.03 80.45,58.83 81.84,58.83 82.1,59.09 82.85,59.09 84.92,61.16 84.92,68.41 83.06,70.27 83.06,71.35 83.16,71.45 83.16,72.16 82.92,72.39 82.59,72.39 82.36,72.63 82.36,72.96 82.12,73.19 81.79,73.19 81.56,73.43 81.56,73.76 81.32,73.99 80.94,73.99 80.76,74.17 80.76,74.23 80.76,74.23 80.76,74.59 80.56,74.79 80.18,74.79 79.96,75.01 79.96,75.4 79.76,75.59 76.17,75.59 75.96,75.37 75.96,74.76 76.33,74.39 v1(76.36,74.39)
LPDDR4_DMI0: length 26.4
  TOP w0.287: U58.C3 v1(69.71,57.63) ; U47.C2 v1(68.36,71.99)
  L05_SIG02 w0.17: v1(69.71,57.63) 69.28,58.06 68.23,58.06 68.08,57.91 65.83,57.91 63.05,60.69 63.05,61.68 63.34,61.97 63.34,62.69 63.05,62.98 63.05,70.26 66.06,73.28 66.47,73.28 66.55,73.19 67.75,73.19 67.96,72.99 67.96,72.39 v1(68.36,71.99)
LPDDR4_DMI1: length 17.1
  TOP w0.287: U58.C10 v1(69.71,64.03) ; U47.F3 v1(70.76,72.79)
  L03_SIG01 w0.122: v1(69.71,64.03) 69.29,64.45 69.15,64.45 69.01,64.59 69.01,65.13 68.9,65.24 68.73,65.24 68.62,65.13 68.62,64.6 68.49,64.48 68.32,64.48 68.2,64.6 68.2,65.46 68.51,65.76 68.51,65.98 68.38,66.11 67.47,66.11 67.36,66.22 67.36,66.42 67.47,66.53 68.38,66.53 68.51,66.66 68.51,66.83 68.38,66.96 67.79,66.96 67.66,67.08 67.66,67.26 67.79,67.39 68.38,67.39 68.51,67.51 68.51,69.61 69.56,70.66 69.56,71.36 69.79,71.59 70.2,71.59 70.36,71.75 70.36,72.63 70.52,72.79 v1(70.76,72.79)
LPDDR4_DMI2: length 26.7
  TOP w0.287: U58.Y3 v1(80.76,58.43) ; U47.U1 v1(79.96,71.06)
  L05_SIG02 w0.17: v1(80.76,58.43) 80.76,58.71 80.88,58.83 81.75,58.83 81.84,58.93 81.84,59.24 81.96,59.35 82.13,59.35 82.25,59.23 82.25,59.02 82.35,58.92 82.57,58.92 82.9,59.25 82.9,59.44 83.08,59.62 83.27,59.62 83.46,59.81 83.46,60 83.64,60.18 83.83,60.18 84.04,60.39 84.04,62.17 83.72,62.49 83.72,62.87 84.04,63.19 84.04,64.83 83.86,65 83.63,65 83.46,65.17 83.46,65.42 83.63,65.59 83.83,65.59 83.99,65.74 83.99,65.97 83.83,66.13 83.39,66.13 83.22,65.97 82.68,65.97 82.53,66.12 82.53,66.45 82.73,66.65 83.26,66.65 83.41,66.8 83.41,67.02 83.25,67.18 80.51,67.18 80.34,67.35 80.34,67.93 80.16,68.11 79.9,68.11 79.77,67.98 79.57,67.98 79.24,68.31 79.24,70.5 78.64,71.1 78.64,71.36 78.86,71.59 79.23,71.59 79.36,71.47 79.66,71.47 79.78,71.59 80.02,71.59 80.12,71.49 80.12,71.22 v1(79.96,71.06)
LPDDR4_DMI3: length 19.3
  TOP w0.287: U58.Y10 v1(81.41,63.23) ; U47.W3 v1(81.96,72.79)
  L03_SIG01 w0.122: v1(81.41,63.23) 81.15,63.49 81.15,63.76 81.27,63.89 81.47,63.89 81.63,64.04 81.63,64.24 82.6,65.21 82.6,66.39 81.98,67.01 81.8,67.01 80.53,68.27 80.53,68.44 80.65,68.56 80.81,68.56 81.87,67.5 82.42,67.5 82.54,67.61 82.54,67.85 82.42,67.97 81.94,67.97 81.41,68.5 81.41,68.72 81.89,69.19 81.89,70.07 81.27,70.68 81.27,70.83 81.39,70.96 81.59,70.96 81.82,70.73 82.19,70.73 82.45,70.99 82.45,71.48 82.36,71.58 82.36,72.27 82.24,72.39 81.7,72.39 81.57,72.51 81.57,72.67 81.7,72.79 v1(81.96,72.79)
LPDDR4_DQ0: length 26.7
  TOP w0.287: U58.B2 v1(69.06,56.83) ; U47.A5 v1(66.76,74.39)
  L05_SIG02 w0.17: v1(69.06,56.83) 68.86,56.63 65.67,56.63 62.03,60.27 62.03,70.89 64.57,73.44 64.57,73.81 65.15,74.39 v1(66.76,74.39)
LPDDR4_DQ1: length 26.4
  TOP w0.287: U47.B4 v1(67.56,73.59) ; U58.C2 v1(69.71,56.83)
  L05_SIG02 w0.17: v1(67.56,73.59) 67.16,73.99 66.53,73.99 66.4,73.86 65.89,73.86 62.54,70.52 62.54,60.48 65.79,57.23 69.31,57.23 v1(69.71,56.83)
LPDDR4_DQ2: length 26.5
  TOP w0.287: U47.B6 v1(67.56,75.19) ; U58.E2 v1(71.01,56.83)
  L05_SIG02 w0.17: v1(71.01,56.83) 71.41,57.23 72.17,57.23 72.42,57.49 72.42,57.81 72.64,58.03 73.18,58.03 73.37,58.22 73.37,59.41 73.11,59.66 72.73,59.66 72.37,60.02 72.37,60.73 72.26,60.84 72.26,61.71 72.06,61.91 71.33,61.91 71.14,62.1 71.14,62.66 71.31,62.83 71.9,62.83 72.07,63.01 72.07,65.12 70.94,66.26 70.94,66.71 71.16,66.93 71.16,72.16 70.92,72.39 70.59,72.39 70.36,72.63 70.36,72.96 70.12,73.19 69.79,73.19 69.56,73.43 69.56,73.78 69.35,73.99 68.99,73.99 68.76,74.23 68.76,74.58 68.55,74.79 67.96,74.79 v1(67.56,75.19)
LPDDR4_DQ3: length 26.5
  TOP w0.287: U47.D5 v1(69.16,74.39) ; U58.F2 v1(71.66,56.83)
  L05_SIG02 w0.17: v1(69.16,74.39) 69.38,74.39 69.78,73.99 70.18,73.99 70.36,73.82 70.36,73.43 70.59,73.19 70.97,73.19 71.16,73 71.16,72.96 71.16,72.96 71.16,72.63 71.39,72.39 71.74,72.39 71.96,72.18 71.96,70.92 71.68,70.64 71.68,67.83 71.82,67.69 72.25,67.69 72.39,67.54 72.39,67.34 72.25,67.2 71.87,67.2 71.72,67.05 71.72,66.78 71.86,66.64 72.36,66.64 72.53,66.47 72.53,62.71 72.39,62.57 72.39,62.33 72.79,61.94 73.2,61.94 73.41,61.73 73.41,60.94 73.17,60.7 73.17,60.06 73.42,59.81 73.58,59.81 73.76,59.63 73.76,57.72 73.01,56.97 73.01,56.68 72.76,56.43 72.07,56.43 71.81,56.17 71.56,56.17 71.4,56.33 71.4,56.57 v1(71.66,56.83)
LPDDR4_DQ4: length 26.5
  TOP w0.287: U47.C5 v1(68.36,74.39) ; U58.F4 v1(72.31,59.23)
  L05_SIG02 w0.17: v1(68.36,74.39) 68.36,74.11 68.5,73.97 68.61,73.97 68.76,73.82 68.76,73.37 68.93,73.19 69.32,73.19 69.56,72.96 69.56,72.63 69.79,72.39 70.12,72.39 70.36,72.16 70.36,71.62 70.65,71.33 70.65,67.92 70.32,67.59 70.32,67.4 70.51,67.21 70.51,67.01 70.37,66.88 70.18,66.88 70.04,67.01 69.85,67.01 69.71,66.87 69.71,66.68 69.84,66.54 69.84,66.35 69.71,66.21 69.51,66.21 69.38,66.35 69.13,66.35 68.83,66.05 68.83,65.81 69.3,65.33 69.3,65.09 69.13,64.92 68.92,64.92 68.45,65.4 68.21,65.4 67.99,65.18 67.99,63.33 68.15,63.18 68.52,63.18 68.67,63.02 68.67,62.81 68.52,62.65 68.15,62.65 67.99,62.5 67.99,62.13 68.16,61.96 69.24,61.96 69.47,62.19 69.91,62.19 70.13,61.97 70.13,61.18 70.33,60.99 71.29,60.99 71.49,60.78 71.49,60.11 71.83,59.77 72.02,59.77 72.31,59.48 v1(72.31,59.23)
LPDDR4_DQ5: length 26.5
  TOP w0.287: U47.C3 v1(68.36,72.79) ; U58.E4 v1(71.66,59.23)
  L05_SIG02 w0.17: v1(68.36,72.79) 68.76,72.39 69.32,72.39 69.56,72.16 69.56,70.85 69.7,70.71 70,70.71 70.14,70.57 70.14,68.22 70.02,68.1 69.78,68.1 69.63,68.25 69.63,70.01 69.48,70.16 69.27,70.16 69.12,70.01 69.12,69.64 68.9,69.42 68.9,69.04 69.12,68.83 69.12,68.48 68.9,68.26 68.9,67.93 69.12,67.71 69.12,67.09 68.64,66.61 68.41,66.61 68.25,66.77 68.02,66.77 67.86,66.61 67.86,66.38 68.02,66.22 68.02,65.99 67.48,65.45 67.48,61.44 68.22,60.71 68.53,60.71 68.67,60.85 68.67,61.24 68.81,61.38 69.01,61.38 69.15,61.24 69.15,60.85 69.29,60.71 69.75,60.71 69.97,60.49 70.63,60.49 70.82,60.3 70.82,60.06 71.65,59.23 v1(71.66,59.23)
LPDDR4_DQ6: length 26.5
  TOP w0.287: U58.C4 v1(69.71,58.43) ; U47.B2 v1(67.56,71.99)
  L05_SIG02 w0.17: v1(67.56,71.99) 67.16,71.59 67.16,70.92 67.37,70.71 67.37,68.04 66.46,67.13 65.49,67.13 65.17,66.82 65.17,62.71 65.32,62.56 65.53,62.56 65.68,62.71 65.68,66.07 65.82,66.21 66.06,66.21 66.19,66.07 66.19,60.81 68.2,58.8 69.34,58.8 v1(69.71,58.43)
LPDDR4_DQ7: length 26.5
  TOP w0.267: 68.98,58.43 68.45,58.43
  TOP w0.287: v1(66.35,72.79) 66.76,72.79 U47.A3 ; 68.45,58.43 v1(67.97,58.43) ; U58.B4 68.98,58.43
  L05_SIG02 w0.17: v1(67.97,58.43) 67.6,58.43 64.65,61.37 64.65,65.56 64.5,65.71 64.29,65.71 64.14,65.56 64.14,63.5 64.01,63.36 63.78,63.36 63.63,63.51 63.63,66.79 64.56,67.71 66.06,67.71 66.85,68.5 66.85,70.41 66.12,71.14 66.12,72.03 66.35,72.26 v1(66.35,72.79)
LPDDR4_DQ8: length 17.1
  TOP w0.287: U58.B11 v1(69.06,64.03) ; U47.E2 v1(69.96,71.99)
  L03_SIG01 w0.122: v1(69.06,64.03) 68.49,63.46 67.85,63.46 67.71,63.6 67.71,65.35 67.57,65.49 67.37,65.49 67.25,65.37 67.25,63.8 67.12,63.68 66.83,63.68 66.71,63.8 66.71,67 68,68.29 68,70.27 68.76,71.03 68.76,71.36 68.99,71.59 69.32,71.59 69.72,71.99 v1(69.96,71.99)
LPDDR4_DQ9: length 17.1
  TOP w0.287: U58.C11 v1(69.71,64.83) ; U47.F5 v1(70.76,74.39)
  L03_SIG01 w0.122: v1(70.76,74.39) 70.36,73.99 70.36,73.41 70.57,73.19 70.93,73.19 71.16,72.96 71.16,71.8 70.56,71.2 70.56,70.06 70.16,69.66 69.26,69.66 69.14,69.54 69.14,69.35 69.25,69.25 69.57,69.25 69.67,69.14 69.67,68.97 69.55,68.84 69.07,68.84 68.95,68.72 68.95,68.55 69.08,68.42 69.55,68.42 69.67,68.29 69.67,68.13 69.55,68.01 69.07,68.01 68.95,67.88 68.95,67.71 69.08,67.58 69.55,67.58 69.67,67.45 69.67,67.28 69.55,67.15 69.07,67.15 68.95,67.03 68.95,66.85 69.07,66.73 69.55,66.73 69.67,66.6 69.67,66.38 69.55,66.26 69.33,66.26 69.23,66.16 69.23,65.55 69.45,65.33 69.45,65.09 v1(69.71,64.83)
LPDDR4_DQ10: length 17.1
  TOP w0.287: U58.E11 v1(71.01,64.83) ; U47.E6 v1(70.76,75.19)
  L03_SIG01 w0.122: v1(71.01,64.83) 70.77,65.07 70.77,65.24 70.89,65.36 71.05,65.36 71.16,65.47 71.16,65.93 70.88,66.21 70.88,68.61 71.27,68.99 71.44,68.99 71.69,68.75 71.86,68.75 71.99,68.87 71.99,69.05 71.74,69.29 71.74,69.47 71.89,69.61 72.06,69.61 72.27,69.41 72.43,69.41 72.56,69.53 72.56,69.7 72.3,69.96 72.3,70.69 72.51,70.91 72.51,71.26 71.96,71.81 71.96,73.81 71.77,73.99 71.35,73.99 71.16,74.18 71.16,75.43 71,75.59 U47.E6 70.25,75.49 70.25,75.31 70.38,75.19 v1(70.76,75.19)
LPDDR4_DQ11: length 17.1
  TOP w0.287: U58.F11 v1(71.66,64.83) ; U47.G2 v1(72.36,72.79)
  L03_SIG01 w0.122: v1(71.66,64.83) 71.66,65.11 71.79,65.24 71.79,65.44 71.51,65.72 71.51,65.98 72,66.47 72,66.7 71.86,66.84 71.46,66.84 71.3,67.01 71.3,68.27 71.4,68.37 71.58,68.37 71.69,68.26 71.69,67.32 71.79,67.23 72.01,67.23 72.12,67.34 72.12,67.72 72.2,67.8 72.4,67.8 72.5,67.7 72.5,67.06 72.38,66.95 72.38,66.57 72.51,66.44 72.68,66.44 72.78,66.55 72.78,66.69 72.9,66.8 72.9,67.95 72.58,68.26 72.58,68.68 73.02,69.11 73.02,69.95 72.73,70.24 72.73,70.51 73.01,70.79 73.01,71.5 72.76,71.75 72.76,72.65 72.62,72.79 v1(72.36,72.79)
LPDDR4_DQ12: length 17.1
  TOP w0.287: U58.F9 v1(71.66,62.43) ; U47.G6 v1(71.56,75.19)
  L03_SIG01 w0.122: v1(71.66,62.43) 72.46,63.23 72.46,64.91 72.92,65.38 73.35,65.38 73.66,65.68 73.66,66.17 73.75,66.25 73.75,68.52 73.87,68.65 73.87,70.5 74.36,70.99 74.36,72.96 74.13,73.19 73.79,73.19 73.56,73.43 73.56,73.43 73.56,73.79 73.35,73.99 72.99,73.99 72.76,74.23 72.76,74.58 72.55,74.79 71.96,74.79 v1(71.56,75.19)
LPDDR4_DQ13: length 17.1
  TOP w0.287: U58.E9 v1(71.01,63.23) ; U47.G4 v1(72.36,74.39)
  L03_SIG01 w0.122: v1(71.01,63.23) 71.26,62.98 71.26,62.78 71.12,62.63 70.79,62.63 70.28,63.15 70.28,63.47 70.45,63.63 71.98,63.63 72.15,63.81 72.15,65.13 72.82,65.8 72.82,65.98 73.32,66.48 73.32,68.73 73.44,68.85 73.44,71.71 73.56,71.83 73.56,72.98 73.35,73.19 72.96,73.19 72.76,73.39 72.76,73.78 72.36,74.18 v1(72.36,74.39)
LPDDR4_DQ14: length 17.1
  TOP w0.287: U58.C9 v1(69.71,63.23) ; U47.E4 v1(69.96,73.59)
  L03_SIG01 w0.122: v1(69.96,73.59) 69.56,73.19 69.56,72.63 69.32,72.39 68.99,72.39 68.76,72.16 68.76,71.82 68.53,71.59 68.19,71.59 67.96,71.36 67.96,70.91 67.58,70.53 67.58,68.46 66.26,67.14 66.26,63.56 66.99,62.83 67.83,62.83 68.03,63.03 68.59,63.03 68.79,62.83 69.31,62.83 v1(69.71,63.23)
LPDDR4_DQ15: length 17.1
  TOP w0.287: U58.B9 v1(69.06,62.43) ; U47.D3 v1(69.16,72.79)
  L03_SIG01 w0.122: v1(69.06,62.43) 69.04,62.41 66.8,62.41 65.84,63.37 65.84,67.32 67.16,68.63 67.16,72.98 67.37,73.19 68.76,73.19 v1(69.16,72.79)
LPDDR4_DQ16: length 26.7
  TOP w0.287: U58.AA2 v1(82.06,56.83) ; U47.T6 v1(79.56,75.19)
  L05_SIG02 w0.17: v1(79.56,75.19) 79.96,74.79 79.96,74.27 79.96,74.23 80.19,73.99 80.53,73.99 80.76,73.77 80.76,73.43 80.99,73.19 81.32,73.19 81.56,72.96 81.56,72.63 81.79,72.39 82.13,72.39 82.36,72.16 82.36,71.78 82.56,71.57 82.92,71.57 83.13,71.36 83.13,71.11 82.98,70.96 82.76,70.96 82.66,70.86 82.66,70.63 82.8,70.49 83.76,70.49 83.9,70.36 83.9,70.14 83.77,70.02 83.34,70.02 83.21,69.89 83.21,69.67 83.35,69.54 83.76,69.54 83.9,69.4 83.9,68.74 85.57,67.07 85.57,59.75 82.64,56.83 v1(82.06,56.83)
LPDDR4_DQ17: length 26.7
  TOP w0.287: U58.Y2 v1(81.41,57.63) ; U47.T4 v1(79.56,73.59)
  L05_SIG02 w0.17: v1(81.41,57.63) 81.08,57.3 81.08,57.11 81.3,56.89 81.53,56.89 81.87,57.23 82.32,57.23 85.06,59.97 85.06,66.86 83.12,68.8 82.06,68.8 81.89,68.97 81.89,69.45 82.01,69.57 82.56,69.57 82.7,69.71 82.7,69.89 82.54,70.04 82.08,70.04 81.9,70.21 81.9,70.57 82.36,71.03 82.36,71.36 82.36,71.36 82.36,71.38 82.14,71.59 81.79,71.59 81.56,71.83 81.56,72.16 81.32,72.39 81.28,72.39 80.99,72.39 80.76,72.63 80.76,72.66 80.76,72.96 80.52,73.19 80.5,73.19 80.13,73.19 79.96,73.36 79.96,73.8 79.83,73.93 79.64,73.93 79.56,73.85 v1(79.56,73.59)
LPDDR4_DQ18: length 26.7
  TOP w0.287: U47.U5 v1(80.36,74.39) ; U58.V2 v1(80.11,56.83)
  L05_SIG02 w0.17: v1(80.36,74.39) 80.59,74.39 80.99,73.99 81.34,73.99 81.56,73.78 81.56,73.43 81.79,73.19 82.14,73.19 82.36,72.97 82.36,72.63 82.59,72.39 82.92,72.39 83.16,72.16 83.16,71.83 83.39,71.59 83.63,71.59 83.72,71.59 83.96,71.36 83.96,71.03 84.41,70.57 84.41,68.95 86.08,67.28 86.08,59.54 82.94,56.41 80.53,56.41 v1(80.11,56.83)
LPDDR4_DQ19: length 26.7
  TOP w0.287: U58.U2 v1(78.81,56.83) ; U47.R5 v1(77.96,74.39)
  L05_SIG02 w0.17: v1(77.96,74.39) 77.56,73.99 75.75,73.99 74.95,73.19 74.57,73.19 74.36,72.98 74.36,72.6 74.16,72.39 73.77,72.39 73.56,72.18 73.56,71.62 73.34,71.41 73.34,67.85 74.49,66.71 74.49,63.7 75.14,63.05 75.14,60.64 75.37,60.41 75.73,60.41 75.98,60.16 75.98,59.45 76.45,58.98 76.45,57.92 76.32,57.8 76.32,57.34 76.66,57 76.66,56.55 76.9,56.32 78.64,56.32 78.81,56.49 v1(78.81,56.83)
LPDDR4_DQ20: length 26.7
  TOP w0.287: U47.P2 v1(77.96,71.99) ; U58.U4 v1(78.81,58.43)
  L05_SIG02 w0.17: v1(77.96,71.99) U47.P2 76,72.39 75.75,72.14 75.75,71.92 74.84,71.01 74.84,70.29 74.68,70.13 74.68,68.86 74.96,68.58 75.25,68.58 75.6,68.23 75.6,67.76 75.41,67.57 75.41,67.25 75.76,66.89 76.77,66.89 76.97,66.69 76.97,65.48 77.11,65.34 77.35,65.34 77.49,65.48 77.49,65.82 77.61,65.94 77.83,65.94 77.99,65.78 77.99,64.72 78.28,64.43 79.5,64.43 79.64,64.29 79.64,64.05 79.46,63.87 79.46,63.52 79.67,63.31 79.67,63.07 79.55,62.94 79.26,62.94 79.06,62.74 78.79,62.74 78.62,62.57 78.62,62.1 78.79,61.93 79.37,61.93 79.55,61.76 79.55,60.94 79.38,60.77 78.48,60.77 78.31,60.6 78.31,59.91 78.48,59.74 79.21,59.74 79.38,59.57 79.38,59 v1(78.81,58.43)
LPDDR4_DQ21: length 26.7
  TOP w0.287: U58.V4 v1(79.46,58.43) ; U47.R3 v1(77.96,72.79)
  L05_SIG02 w0.17: v1(79.46,58.43) 79.06,58.03 78.32,58.03 78,58.35 78,58.65 77.42,59.23 77.42,60.99 77.24,61.17 76.83,61.17 76.67,61.02 76.67,60.73 76.53,60.59 76.19,60.59 76.02,60.75 76.02,61.22 76.21,61.41 76.21,61.68 76.02,61.87 76.02,62.18 76.24,62.39 76.24,62.66 76.02,62.87 76.02,63.15 76.17,63.3 76.94,63.3 77.11,63.47 77.11,63.85 76.94,64.02 76.79,64.02 76.63,64.18 76.63,64.99 76.02,65.61 76.02,65.9 74.79,67.13 74.79,67.86 74.44,68.21 74.02,68.21 73.85,68.37 73.85,69.24 74.07,69.46 74.07,69.8 73.85,70.02 73.85,70.57 74.01,70.73 74.18,70.73 74.36,70.91 74.36,72.16 74.59,72.39 75.02,72.39 75.82,73.19 77.56,73.19 v1(77.96,72.79)
LPDDR4_DQ22: length 26.7
  TOP w0.287: U58.Y4 v1(81.41,59.23) ; U47.T2 v1(79.56,71.99)
  L05_SIG02 w0.17: v1(81.41,59.23) 81.41,59.5 81.67,59.76 82.49,59.76 83.53,60.79 83.53,61.92 83.17,62.27 83.17,63.1 83.53,63.45 83.53,64.16 82.96,64.73 82.96,65.01 82.71,65.26 82.18,65.26 82.01,65.43 82.01,66.39 81.74,66.66 81.4,66.66 81.17,66.43 80.72,66.43 80.49,66.66 80.17,66.66 79.82,67 79.82,67.26 79.65,67.43 79.39,67.43 78.72,68.1 78.72,70.34 78.13,70.94 77.76,70.94 77.6,71.09 77.6,71.35 77.77,71.52 78.19,71.52 78.36,71.69 78.36,74.64 78.51,74.79 78.99,74.79 79.16,74.62 U47.T2 v1(79.56,71.99)
LPDDR4_DQ23: length 26.7
  TOP w0.287: U47.U3 v1(79.56,72.79) ; U58.AA4 v1(81.41,58.43)
  L05_SIG02 w0.17: v1(79.56,72.79) 79.96,72.39 80.55,72.39 80.76,72.19 80.76,71.78 80.96,71.58 81.33,71.58 81.51,71.4 81.51,70.86 81.34,70.69 81.1,70.69 80.98,70.81 80.98,71 80.85,71.14 80.62,71.14 80.49,71.01 80.49,70.78 80.22,70.51 79.97,70.51 79.75,70.28 79.75,69.16 80.3,68.61 80.62,68.61 80.92,68.31 80.92,67.85 81.07,67.7 81.27,67.7 81.42,67.85 81.42,68.22 81.54,68.34 81.81,68.34 81.95,68.2 81.95,67.84 82.1,67.7 82.31,67.7 82.45,67.84 82.45,68.11 82.6,68.26 82.93,68.26 84.55,66.64 84.55,60.18 82.4,58.03 81.51,58.03 81.41,58.13 v1(81.41,58.43)
LPDDR4_DQ24: length 19.3
  TOP w0.287: U47.Y2 v1(82.76,71.99) ; U58.AA11 v1(82.06,64.03)
  L03_SIG01 w0.122: v1(82.06,64.03) 82.65,64.63 83.39,64.63 83.72,64.96 83.72,67.46 83.62,67.56 83.45,67.56 83.35,67.46 83.35,65.11 83.25,65.01 83.07,65.01 82.97,65.11 82.97,66.62 82.75,66.84 82.75,67.15 82.97,67.37 82.97,68.28 82.86,68.39 82.09,68.39 81.98,68.5 81.98,68.66 82.09,68.77 82.86,68.77 82.97,68.88 82.97,68.99 82.83,69.13 82.4,69.13 82.28,69.25 82.28,69.56 82.37,69.65 82.64,69.65 82.76,69.77 82.76,69.91 82.64,70.03 82.39,70.03 82.28,70.14 82.28,70.3 82.39,70.4 82.64,70.4 82.76,70.53 v1(82.76,71.99)
LPDDR4_DQ25: length 19.3
  TOP w0.287: U47.V2 v1(80.36,72.79) ; U58.Y11 v1(80.76,64.83)
  L03_SIG01 w0.122: v1(80.36,72.79) 80.66,72.79 80.75,72.7 80.75,72.52 80.63,72.39 77.78,72.39 77.56,72.17 77.56,71.01 77.18,70.63 77.18,69.26 77.31,69.14 77.45,69.14 77.56,69.24 77.56,69.68 77.66,69.77 77.84,69.77 77.94,69.67 77.94,68.51 78.04,68.41 78.21,68.41 78.32,68.52 78.32,69.58 78.41,69.68 78.57,69.68 78.69,69.55 78.69,67.69 80.12,66.26 80.66,66.26 80.89,66.04 80.89,65.64 80.69,65.44 80.47,65.44 80.35,65.32 80.35,64.95 80.47,64.83 v1(80.76,64.83)
LPDDR4_DQ26: length 19.3
  TOP w0.287: U58.V11 v1(79.46,64.83) ; U47.V4 v1(81.16,73.59)
  L03_SIG01 w0.122: v1(79.46,64.83) 78.92,65.37 78.92,66.31 77.99,67.24 77.82,67.24 77.55,66.96 77.38,66.96 77.26,67.08 77.26,67.25 77.54,67.52 77.54,67.69 77.42,67.81 77.26,67.81 76.83,67.38 76.66,67.38 76.54,67.5 76.54,67.66 76.97,68.09 76.97,68.26 76.72,68.51 76.29,68.51 76.11,68.68 76.11,69.1 76.38,69.37 76.38,70.55 75.95,70.99 75.95,72.18 76.16,72.39 76.52,72.39 76.76,72.63 76.76,72.97 76.98,73.19 77.32,73.19 77.56,73.43 77.56,73.76 77.79,73.99 U47.V4 v1(81.16,73.59)
LPDDR4_DQ27: length 19.3
  TOP w0.287: U47.W5 v1(81.96,74.39) ; U58.U11 v1(78.81,64.03)
  L03_SIG01 w0.122: v1(81.96,74.39) U47.W5 77.79,74.79 77.56,74.56 77.56,74.55 77.56,74.22 77.33,73.99 76.99,73.99 76.76,73.76 76.76,73.43 76.52,73.19 76.16,73.19 75.56,72.59 75.56,68.45 75.66,68.35 75.66,67.96 75.55,67.85 75.55,67.5 76.17,66.89 76.74,66.89 78.26,65.36 78.26,64.58 v1(78.81,64.03)
LPDDR4_DQ28: length 19.3
  TOP w0.287: U58.U9 v1(79.46,62.43) ; U47.Y4 v1(82.76,73.59)
  L03_SIG01 w0.122: v1(79.46,62.43) 79.68,62.65 79.68,64.4 79.89,64.61 79.89,65.93 76.78,69.03 76.78,70.86 76.55,71.09 76.55,71.59 76.76,71.8 76.76,72.16 76.99,72.39 77.34,72.39 77.56,72.61 77.56,72.97 77.78,73.19 82.36,73.19 v1(82.76,73.59)
LPDDR4_DQ29: length 19.3
  TOP w0.287: U47.AA3 v1(83.56,72.79) ; U58.V9 v1(80.11,62.43)
  L03_SIG01 w0.122: v1(80.11,62.43) 80.53,62.01 82.45,62.01 85.39,64.95 85.39,67.99 84.44,68.94 84.44,70.69 84.79,71.03 84.79,73.75 84.54,73.99 84.17,73.99 83.96,73.78 83.96,73.43 83.56,73.03 v1(83.56,72.79)
LPDDR4_DQ30: length 19.3
  TOP w0.287: U58.Y9 v1(81.41,62.43) ; U47.AA5 v1(83.56,74.39)
  L03_SIG01 w0.122: v1(83.56,74.39) 83.56,74.39 83.79,74.39 84.08,74.69 84.08,74.82 83.99,74.92 83.85,74.92 83.73,74.79 82.48,74.79 82.36,74.67 82.36,74.12 82.48,73.99 83.04,73.99 83.16,73.87 83.16,69.34 83.35,69.15 83.35,68.08 83.49,67.94 83.91,67.94 84.1,67.75 84.1,64.8 83.52,64.22 82.79,64.22 82.55,63.98 82.55,63.08 82.3,62.83 81.53,62.83 81.41,62.71 v1(81.41,62.43)
LPDDR4_DQ31: length 19.3
  TOP w0.287: U47.AB4 v1(84.36,73.59) ; U58.AA9 v1(82.06,62.43)
  L03_SIG01 w0.122: v1(82.06,62.43) 82.3,62.43 84.48,64.61 84.48,64.99 84.59,65.1 84.9,65.1 85.01,65.21 85.01,65.36 84.9,65.47 84.59,65.47 84.48,65.58 84.48,65.74 84.59,65.85 84.9,65.85 85.01,65.96 85.01,66.11 84.9,66.22 84.59,66.22 84.48,66.33 84.48,66.49 84.59,66.6 84.9,66.6 85.01,66.71 85.01,66.87 84.9,66.98 84.59,66.98 84.48,67.09 84.48,67.24 84.59,67.35 84.9,67.35 85.01,67.46 85.01,67.66 84.89,67.78 84.57,67.78 84.45,67.9 84.45,68.17 84.31,68.32 83.85,68.32 83.73,68.44 83.73,68.87 83.83,68.97 83.95,68.97 84.07,69.09 84.07,69.29 83.96,69.4 83.65,69.4 83.54,69.51 83.54,69.67 83.65,69.78 83.96,69.78 84.07,69.89 84.07,70.04 83.96,70.15 83.64,70.15 83.53,70.26 83.53,70.42 83.64,70.53 83.96,70.53 84.07,70.64 84.07,70.85 83.96,70.96 83.96,72.99 84.36,73.39 v1(84.36,73.59)
LPDDR4_DQS0_N: length 18.3
  TOP w0.203: U47.C1 v1(68.36,71.19) ; v1(71.01,57.63) U58.E3
  L05_SIG02 w0.127: v1(71.01,57.63) 70.65,57.99 70.49,57.99 70.19,58.29 70.19,59.29 69.86,59.62 68.13,59.62 66.72,61.03 66.72,66.64 67.96,67.87 67.96,70.09 68.53,70.67 68.53,71.02 v1(68.36,71.19)
LPDDR4_DQS0_P: length 18.3
  TOP w0.203: U47.D1 v1(69.16,71.19) ; v1(71.01,58.43) U58.D3
  L05_SIG02 w0.127: v1(69.16,71.19) 69.01,71.34 68.86,71.34 68.78,71.25 68.78,70.56 68.21,69.99 68.21,67.77 66.97,66.53 66.97,61.13 68.23,59.86 69.96,59.86 70.43,59.39 70.43,58.39 70.59,58.24 70.81,58.24 v1(71.01,58.43)
LPDDR4_DQS1_N: length 10.7
  TOP w0.203: U58.E10 v1(71.66,64.03) ; U47.F1 v1(71.56,71.99)
  L03_SIG01 w0.102: v1(71.66,64.03) 71.65,64.03 71.24,64.44 70.79,64.44 70.35,64.88 70.35,68.75 71.86,70.26 71.86,70.82 71.95,70.91 71.95,71.37 71.56,71.76 v1(71.56,71.99)
LPDDR4_DQS1_P: length 10.7
  TOP w0.203: U58.D10 v1(71.01,64.03) ; v1(71.56,71.19) U47.G1
  L03_SIG01 w0.102: v1(71.01,64.03) 70.8,64.23 70.71,64.23 70.15,64.79 70.15,68.84 71.66,70.35 71.66,70.61 71.56,70.71 71.06,70.71 70.95,70.82 70.95,71.17 71.21,71.43 71.37,71.43 71.56,71.24 v1(71.56,71.19)
LPDDR4_DQS2_N: length 19.6
  TOP w0.203: v1(77.58,70.17) 77.76,70.35 77.76,71.39 U47.P1 ; U58.V3 v1(80.11,57.63)
  L05_SIG02 w0.127: v1(80.11,57.63) 80.31,57.83 80.31,57.96 80.09,58.18 80.09,59.48 80.48,59.87 80.79,59.87 81.01,60.09 81.01,60.51 81.47,60.97 82.51,60.97 82.78,61.24 82.78,61.65 82.45,61.98 82.45,64.2 82.2,64.45 81.74,64.45 80.98,65.21 80.18,65.21 79.8,65.59 79.8,65.97 77.81,67.96 77.81,69.95 77.6,70.17 v1(77.58,70.17)
LPDDR4_DQS2_P: length 19.6
  TOP w0.203: U47.R1 78.13,71.36 78.13,70.34 v1(78.29,70.17) ; U58.W3 v1(80.76,57.63)
  L05_SIG02 w0.127: v1(80.76,57.63) 80.56,57.83 80.56,58.06 80.34,58.28 80.34,59.38 80.58,59.62 80.89,59.62 81.26,59.99 81.26,60.41 81.57,60.72 82.61,60.72 83.02,61.14 83.02,61.76 82.7,62.08 82.7,64.3 82.3,64.7 81.84,64.7 81.08,65.46 80.28,65.46 80.04,65.69 80.04,66.07 78.06,68.06 78.06,69.94 v1(78.29,70.17)
LPDDR4_DQS3_N: length 13
  TOP w0.203: U47.Y1 v1(81.96,71.99) ; v1(80.11,63.23) U58.V10
  L03_SIG01 w0.102: v1(81.96,71.99) 81.96,71.89 81.84,71.78 81.55,71.78 81.38,71.6 81.08,71.6 79.63,70.15 79.63,68.24 81.54,66.33 81.71,66.33 81.98,66.06 81.98,65.67 81.19,64.88 81.19,64.71 80.5,64.02 80.5,63.79 80.41,63.69 80.41,63.53 v1(80.11,63.23)
LPDDR4_DQS3_P: length 13
  TOP w0.203: v1(80.76,63.23) U58.W10 ; U47.W1 v1(81.96,71.19)
  L03_SIG01 w0.102: v1(80.76,63.23) 80.61,63.38 80.61,63.61 80.71,63.7 80.71,63.94 81.39,64.63 81.39,64.8 82.18,65.59 82.18,66.14 81.79,66.53 81.62,66.53 79.83,68.33 79.83,70.06 81.16,71.4 81.46,71.4 81.64,71.57 82.05,71.57 82.12,71.5 82.12,71.36 v1(81.96,71.19)
LPDDR4_ODT_CA_A: length 3.2
  TOP w0.287: U58.G2 v1(72.31,56.83)
  L03_SIG01 w0.122: v1(72.31,56.83) 72.73,56.41 72.73,55.06 v1(72.8,54.99)
  BOTTOM w0.287: R595.1 v1(72.8,54.99)
LPDDR4_ODT_CA_B: length 3.1
  TOP w0.287: U58.T2 v1(78.16,56.83)
  L03_SIG01 w0.122: v1(78.16,56.83) 78.16,56.04 78.09,55.97 78.09,54.95 v1(78.1,54.95)
  BOTTOM w0.287: R594.1 v1(78.1,54.95)
LPDDR4_RESET_N: length 39.9
  TOP w0.287: U47.P6 v1(77.16,75.19) ; U58.T11 v1(78.81,64.83)
  L03_SIG01 w0.122: v1(77.16,75.19) U47.P6 84.59,75.59 87.78,72.4 87.78,61.81 v1(87.05,61.08) 86.73,60.76 78.24,60.76 78.01,60.98 78.01,61.63 79.26,62.88 79.26,64.38 v1(78.81,64.83)
  BOTTOM w0.287: R588.2 v1(87.05,61.08) R589.1
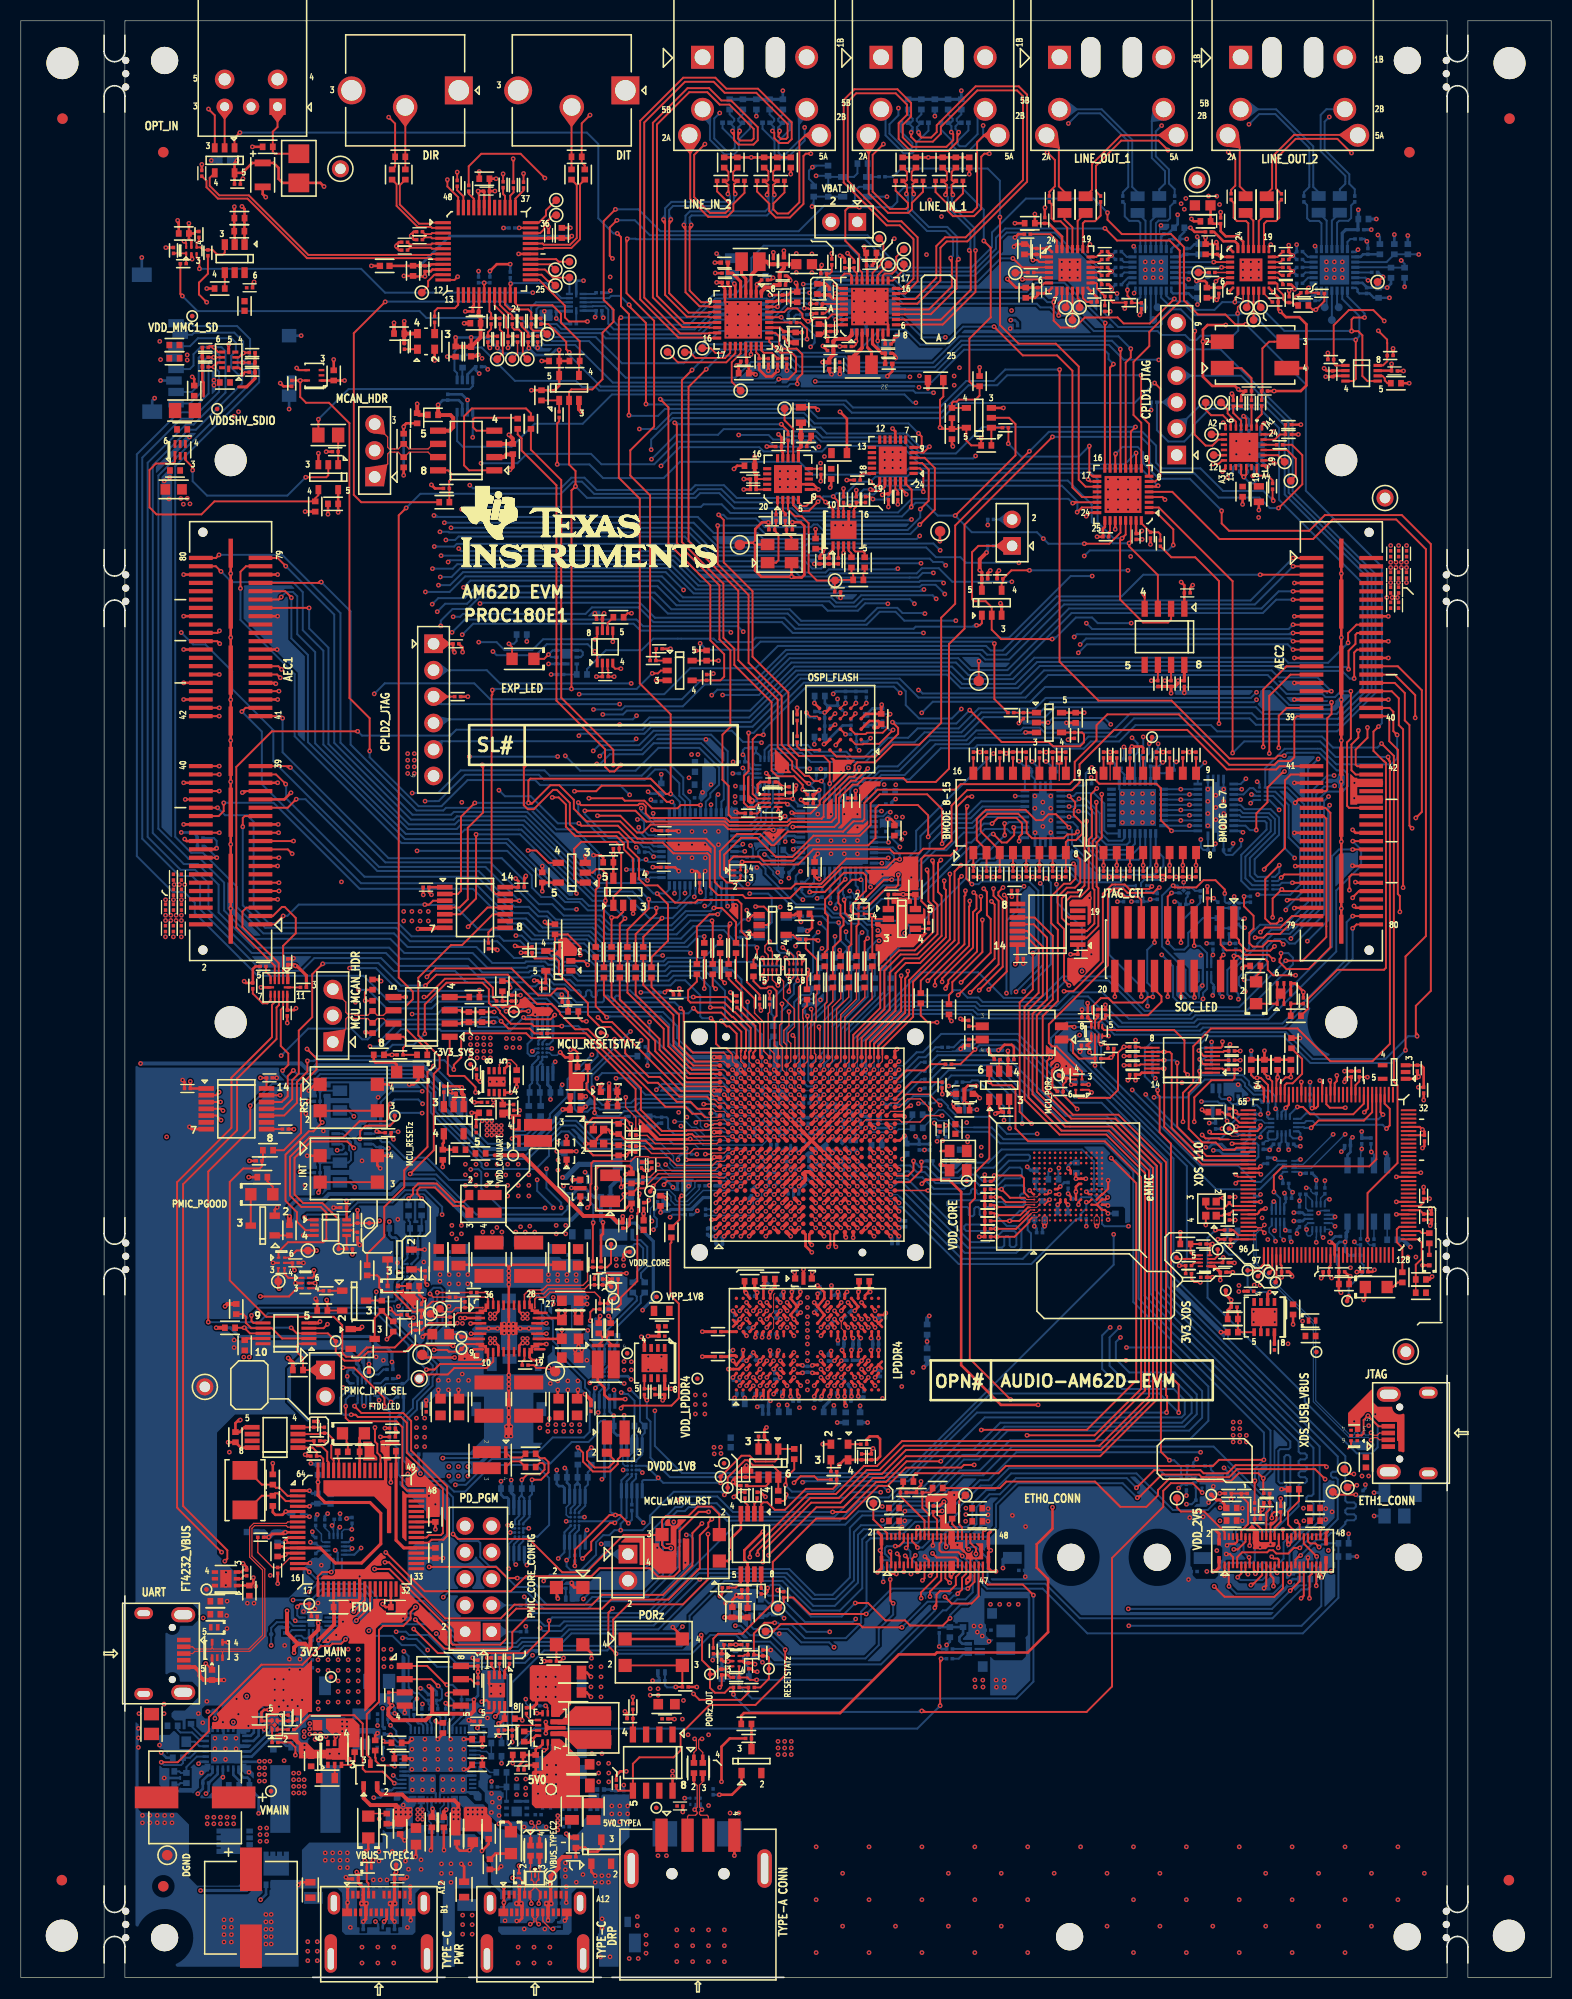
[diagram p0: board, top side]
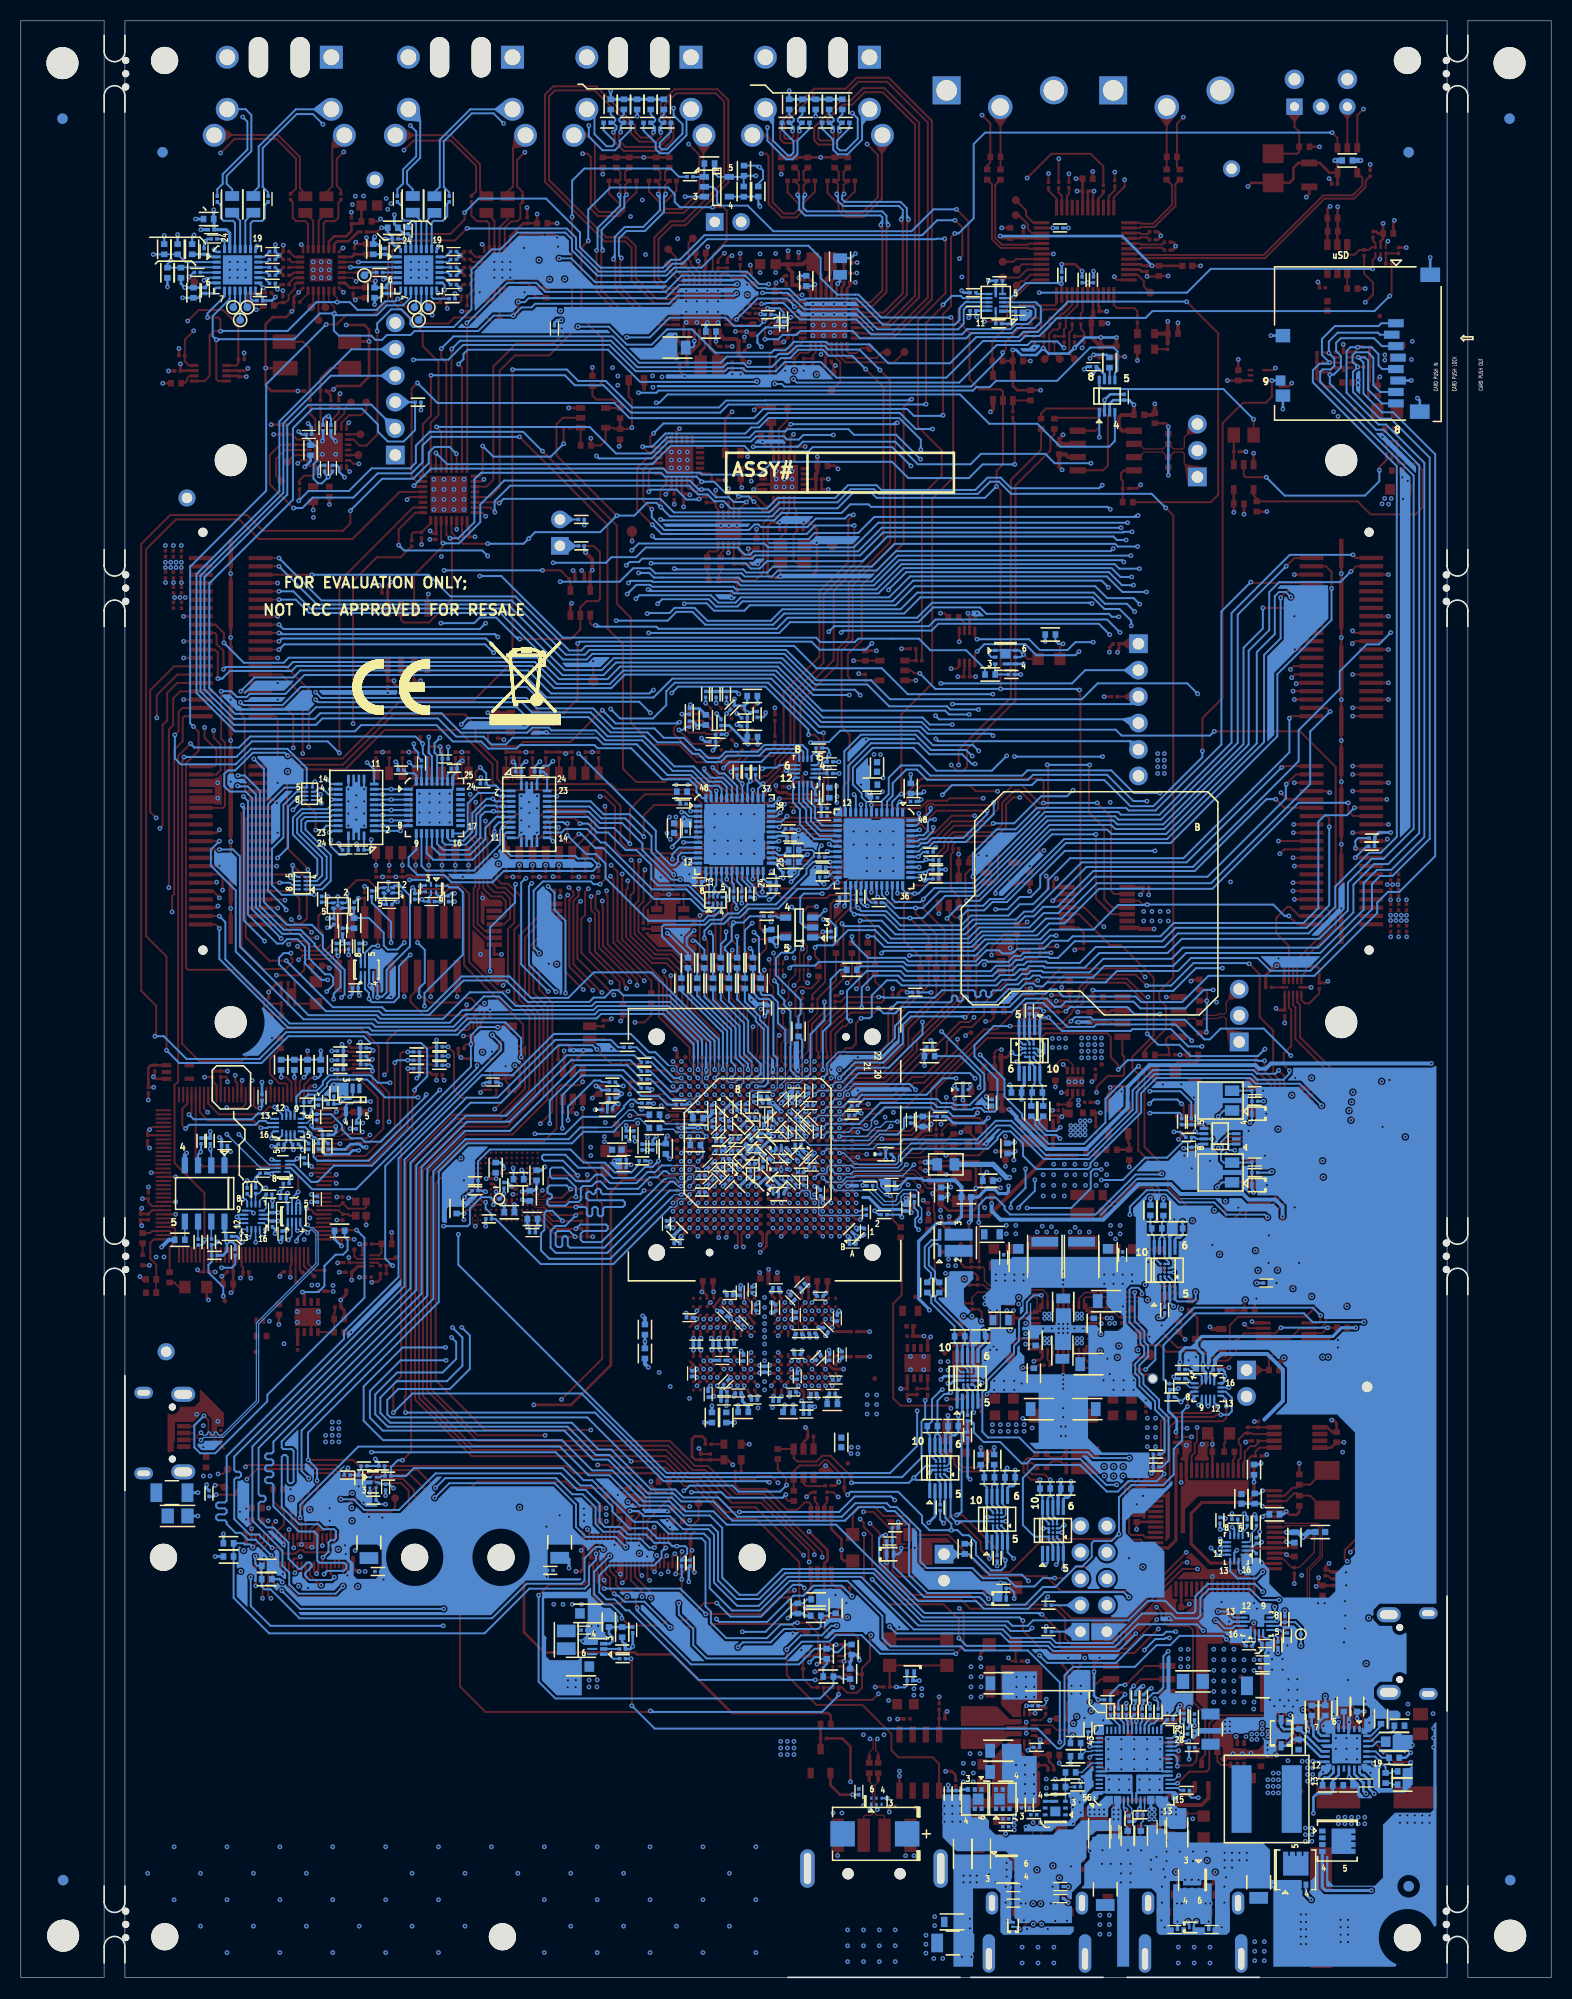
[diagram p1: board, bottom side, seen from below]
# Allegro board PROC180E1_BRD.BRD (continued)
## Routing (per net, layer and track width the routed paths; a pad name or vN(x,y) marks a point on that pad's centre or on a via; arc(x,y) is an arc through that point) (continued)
LPDDR4_ZQ0: length 1.6
  TOP w0.287: U58.A5 68.62,59.74 68.08,59.74 67.97,59.63 R315.2
LPDDR4_ZQ1: length 1.5
  TOP w0.287: R312.2 U58.A8
MCAN0_CAN_H: length 8.2
  TOP w0.127: U17.7 39.6,146.04 39.12,146.53 37.32,146.53 36.83,146.04 R93.1 36.73,146.04 36.24,146.53 35.88,146.52 35.42,146.52 35.24,146.35 35.24,145.39 J9.1
MCAN0_CAN_L: length 8.3
  TOP w0.127: J9.3 35.24,147.97 35.24,147 35.41,146.83 35.88,146.83 35.88,146.83 36.26,146.83 36.74,147.31 R88.2 36.81,147.31 37.29,146.83 39.12,146.83 39.61,147.31 U17.6
MCAN0_RX: length 75.5
  TOP w0.132: U47.C18 v1(68.36,85.59)
  TOP w0.191: v1(57.63,116.46) 57.01,115.84 56.57,115.84 56.12,116.29 56.12,117.98 51.45,122.65 51.45,143.34 48.11,146.68 48.11,147.84 47.73,148.22 R81.1
  L03_SIG01 w0.076: v1(57.63,116.46) 57.5,116.33 57.5,109.03 57.97,108.56 57.97,107.3 57.79,107.12 57.79,102.6 61.22,99.17 61.22,90.3 65.22,86.3 66.88,86.3 67.59,85.59 v1(68.36,85.59)
MCAN0_RX_R: length 7.3
  TOP w0.191: U17.4 43.76,148.58 43.45,148.9 43.45,149.68 43.59,149.82 47.64,149.82 R81.2
MCAN0_STB: length 4.2
  TOP w0.191: U17.8 41.03,144.77 41.31,144.5 41.31,143.91 41.15,143.74 41.15,143.05 R96.2 41.16,141.72 R102.1
MCAN0_T: length 7.6
  TOP w0.254: C107.1 37.03,149.29 36.77,149.04 v1(36.77,148.95) R88.1 ; R93.2 v1(36.77,144.3)
  BOTTOM w0.254: v1(36.77,144.3) 36.77,148.95 v1(36.77,148.95)
MCAN0_TX: length 73.4
  TOP w0.132: U47.B17 v1(67.56,84.79)
  TOP w0.191: v1(56.92,116.46) 56.92,117.92 51.91,122.93 51.91,143.84 49,146.75 R82.2
  L03_SIG01 w0.076: v1(56.92,116.46) 57.28,116.09 57.28,108.81 57.66,108.43 57.66,107.43 57.44,107.21 57.44,101.1 60.99,97.54 60.99,90.09 65.09,85.99 66.75,85.99 67.56,85.18 v1(67.56,84.79)
MCAN0_TX_R: length 15.2
  TOP w0.191: U17.1 43.06,144.77 42.58,145.25 42.58,149.96 43.33,150.72 48.52,150.72 49,150.25 R82.1
MCAN1_CAN_H: length 8
  TOP w0.127: J15.1 31.22,91.11 31.22,92.07 31.39,92.24 31.84,92.24 31.97,92.11 33.33,92.11 33.74,91.69 R215.1 33.83,91.69 34.25,92.11 34.83,92.11 35.31,91.63 U38.7
MCAN1_CAN_L: length 8
  TOP w0.127: J15.3 31.22,93.69 31.22,92.72 31.39,92.55 31.97,92.55 32.1,92.42 33.33,92.42 33.75,92.84 R208.2 33.82,92.84 34.24,92.42 34.83,92.42 35.32,92.9 U38.6
MCAN1_RX_R: length 1.9
  TOP w0.191: R199.2 U38.4
MCAN1_STB: length 4.3
  TOP w0.191: U38.8 36.76,90.36 36.98,90.14 36.98,89.55 36.71,89.28 R222.2 R223.1
MCAN1_T: length 6.1
  TOP w0.191: R215.2 33.2,90.71 v1(33.12,90.79) ; C180.1 33.31,94.88 33.05,94.62 33.05,93.84 v1(33.08,93.82) R208.1
  BOTTOM w0.191: v1(33.08,93.82) 33.08,90.84 v1(33.12,90.79)
MCAN1_TX_R: length 76.6
  TOP w0.191: U38.1 41.19,88.65 41.01,88.46 41.01,86.78 41.2,86.59 42.61,86.59 43.67,85.53 v1(43.67,85.01) ; R273.1 62.49,70.6 62.39,70.5 62.39,65.54 63.21,64.72 63.21,55.64 62.49,54.92 57.84,54.92 57.65,54.73 v1(57.65,54.67)
  L03_SIG01 w0.076: v1(43.67,85.01) 41.95,83.29 41.95,74.71 43.5,73.16 43.5,65.96 40.77,63.24 40.77,59.88 41.5,59.15 41.83,59.15 42.06,59.38 42.06,59.42 42.47,59.83 43.02,59.83 44.06,58.79 49.99,58.79 50.17,58.97 52.53,58.97 53.82,57.68 54.76,57.68 57.65,54.79 v1(57.65,54.67)
MCASP0_ACLKR_R: length 93
  TOP w0.191: v1(40.98,172.7) 40.98,172.04 42.01,171.01 U3.48
  L03_SIG01 w0.076: v1(65.68,102.92) 65.64,102.96 62.16,102.96 61.91,103.21 61.91,114.59 62.36,115.03 62.36,126.36 61.91,126.81 61.91,137.36 62.12,137.57 62.12,160.39 48.54,173.97 43.37,173.97 42.1,172.7 v1(40.98,172.7)
  BOTTOM w0.191: v1(65.68,102.92) 66.01,102.92 66.31,103.22 R481.1
MCASP0_ACLKX_R: length 2.2
  TOP w0.191: U3.37 47.51,170.88 48.29,171.66 R14.1
MCASP0_AFSR_R: length 2.3
  TOP w0.191: R11.1 41.92,171.69 42.51,171.09 U3.47
MCASP0_AFSX_R: length 2
  TOP w0.191: R15.1 47.34,171.88 47.34,171.49 47.01,171.16 U3.38
MCASP0_AXR0_R: length 1.8
  TOP w0.191: R16.1 43.02,171.36 43.51,170.87 U3.45
MCASP0_AXR1_R: length 2
  TOP w0.191: R13.1 46.33,171.32 46.51,171.14 U3.39
MCASP2_ACLKR_R: length 10.6
  TOP w0.14: R179.2 81.76,97.1 81.76,94 79.56,91.8 79.56,87.99 U47.T21
MCASP2_ACLKX_R: length 10.3
  TOP w0.14: U47.R21 78.76,87.99 78.76,92.48 80.27,93.99 R178.2
MCASP2_AFSX_R: length 7.5
  TOP w0.14: R193.1 81.08,95.07 81.08,94.15 79.16,92.24 U47.T22
MCASP2_AXR0_R: length 6.9
  TOP w0.14: R191.1 78,93.76 77.56,93.31 U47.P22
MCASP2_AXR1_R: length 10.9
  TOP w0.132: U47.R19 v1(78.76,86.39)
  BOTTOM w0.102: v1(78.76,86.39) 78.76,86.39 78.37,86.78 78.37,87.56
  BOTTOM w0.191: R498.1 82.03,94.31 78.77,91.05 78.77,87.96 78.37,87.56
MCASP2_AXR3_R: length 7.2
  TOP w0.14: U47.R22 78.36,93 79.53,94.17 R192.1
MCASP2_AXR4_R: length 9.9
  TOP w0.14: U47.N21 77.16,87.99 77.16,89.32 77.22,89.38 77.22,93.47 77.43,93.68 77.43,96.92 R176.1
MCASP2_AXR14_R: length 10.6
  TOP w0.132: U47.M19 v1(76.36,86.39)
  BOTTOM w0.191: R500.1 78.98,93.76 77.13,91.91 77.13,88.96 75.93,87.76 75.93,86.82 v1(76.36,86.39)
MCASP2_AXR15_R: length 7.8
  TOP w0.14: U47.M21 76.36,87.99 76.36,88.65 76.24,88.77 76.24,91.72 76.38,91.87 76.38,94.41 76.48,94.5 R190.1
MCU_I2C0_SCL: length 116.2
  TOP w0.14: v1(39.3,65.66) 39.62,65.34 R296.1
  TOP w0.191: R234.1 53.47,87.98 53.51,88.02 C188.1 53.47,88.86 53.22,89.11 v1(52.8,89.12)
  L03_SIG01 w0.076: v1(39.3,65.66) 39.54,65.9 39.54,67.73 39.87,68.05 39.87,86.34 38.25,87.97 38.25,97.75 43.11,102.61 43.11,117.25 v1(43.09,117.27) ; v1(52.8,89.12) 52.59,89.33 52.59,99.32 52.09,99.82 52.09,104.94 52.59,105.44 52.59,113.26 51.54,114.31 51.54,117.25 v1(51.57,117.28)
  BOTTOM w0.191: v1(39.3,65.66) 39.3,65.89 39.65,66.25 40.31,66.25 40.51,66.05 40.51,62.92 39.46,61.88 39.46,60.89 39.1,60.53 39.1,59.79 39.95,58.94 39.95,58.03 39.55,57.62 39.55,56.83 38.05,55.33 38.05,54.54 37.14,53.63 37.14,50.55 37.43,50.26 R598.2 ; v1(43.09,117.27) 51.35,117.27 51.36,117.28 v1(51.57,117.28)
MCU_I2C0_SDA: length 70.8
  TOP w0.14: v1(40,65.79) R294.1
  TOP w0.191: R210.1 C182.1 52.57,94.65 52.24,94.99 51.5,94.99 50.85,94.33 49.72,94.33 47.12,96.93 39.83,96.93 v1(39.01,96.11)
  L03_SIG01 w0.076: v1(39.01,96.11) 40.07,95.04 40.07,68 39.86,67.79 39.86,65.93 v1(40,65.79)
  BOTTOM w0.191: v1(40,65.79) 40,63.03 39.07,62.1 39.07,61.05 38.71,60.69 38.71,59.63 39.57,58.78 39.57,58.19 39.17,57.78 39.17,56.99 37.67,55.49 37.67,54.7 36.76,53.79 36.76,49.65 37.38,49.02 R603.2
MCU_INTN: length 39.7
  TOP w0.132: 66.85,78.39 67.56,78.39 U47.B10
  TOP w0.14: 66.85,78.39 66.43,77.98 63,77.98 62.23,78.75 60.38,78.75 60.28,78.84 59.04,78.84 58.61,78.41 56.78,78.41
  TOP w0.191: v1(54.42,73.93) 54.72,74.23 54.72,76.15 54.8,76.24 54.8,78.21 55.01,78.41 56.78,78.41 ; R299.1 54.98,64.18 54.7,63.9 v1(54.7,63.07)
  L03_SIG01 w0.076: v1(54.42,73.93) 54.4,73.92 52.98,73.92 52.42,74.48 50.28,74.48 49.89,74.08 49.89,69.84 51.51,68.22 53.38,68.22 54.99,66.6 54.99,63.31 54.76,63.07 v1(54.7,63.07)
MCU_MCAN0_RX: length 86.7
  TOP w0.132: U47.E8 v1(69.96,76.79)
  TOP w0.191: R199.1 44.05,94.84 v1(44.04,94.84)
  L03_SIG01 w0.076: v1(38.06,108.22) 31.58,101.73 v1(31.58,96.95) ; v1(53.38,102.6) 53.23,102.45 53.23,100.35 55.04,98.54 55.04,94.64 53.74,93.34 53.74,91.37 54.06,91.05 54.06,88.28 54.68,87.67 56.77,87.67 58.83,85.61 58.83,83.66 61.21,81.27 v1(61.21,78.07)
  BOTTOM w0.14: v1(69.96,76.79) 69.56,76.39 68.17,76.39 67.68,76.88 66.96,76.88 66.84,77 62.28,77 v1(61.21,78.07)
  BOTTOM w0.191: v1(38.06,108.22) 46.72,108.22 49.09,105.85 49.09,104.7 49.99,103.79 51.05,103.79 52.24,102.6 v1(53.38,102.6) ; v1(31.58,96.95) 34.12,96.95 36.3,94.76 43.96,94.76 v1(44.04,94.84)
MCU_MCAN0_TX: length 10
  TOP w0.132: U47.C7 v1(68.36,75.99)
  TOP w0.191: v1(63.48,75.09) 63.26,74.87 63.26,72.79 62.53,72.06 R273.2
  BOTTOM w0.14: v1(63.48,75.09) 63.93,75.09 64.75,75.9 64.75,76.36 64.95,76.57 66.33,76.57 66.39,76.51 67.65,76.51 68.16,75.99 v1(68.36,75.99)
MCU_OSC0_XI: length 8.5
  TOP w0.14: R249.2 60.15,80.88 60.94,80.09 66.85,80.09 U47.A12
MCU_OSC0_XO: length 8.6
  TOP w0.14: U47.A11 64.67,79.59 64.22,79.15 60.59,79.15 59.89,79.84 R254.2
MCU_PORZ: length 133.6
  TOP w0.14: U47.A7 67.04,76.51 62.1,76.51 61.77,76.17 v1(61.77,76.14)
  TOP w0.191: v1(88.37,49.57) 85.09,49.57 83.1,47.59 82.17,47.59 79.28,44.7 v1(77.97,44.7) ; R238.1 100.69,86.37 100.8,86.26 U43.4 ; R238.1 100.41,86.35 100.41,86.07 100.12,85.79 R242.2 100.12,84.76 v1(101.47,83.41) ; R238.1 100,86.37 TP49.1
  L03_SIG01 w0.076: v1(63.05,45.84) 62.88,46.02 62.88,55.45 62,56.33 62,60.68 61.3,61.38 61.3,72.53 60.89,72.94 60.89,73.55 61.58,74.24 61.58,75.95 v1(61.77,76.14) ; v1(101.47,83.41) 102.69,82.2 102.69,79.45 104.96,77.18 104.96,72.34 104.36,71.74 104.36,62.72 v1(104.64,62.44)
  BOTTOM w0.191: v1(77.97,44.7) 68.4,44.7 66.9,46.2 63.4,46.2 v1(63.05,45.84) ; v1(88.37,49.57) 92.59,53.79 111.5,53.79 111.8,54.09 111.8,55.46 110.74,56.52 105.79,56.52 103.87,58.44 103.87,61.66 v1(104.64,62.44)
MCU_RESETSTATZ: length 18.9
  TOP w0.132: U47.D14 v1(69.16,82.39)
  TOP w0.191: v1(56.25,90.46) 55.96,90.75 TP47.1
  L03_SIG01 w0.076: v1(56.25,90.46) 56.25,89.09 59.68,85.66 59.68,85.03 61.61,83.1 v1(63.19,83.1)
  L05_SIG02 w0.102: v1(63.19,83.1) 65.76,83.1 66.08,83.42 66.85,83.42 67.5,82.77 68.57,82.77 68.81,82.53 68.95,82.39 v1(69.16,82.39)
MCU_RESETZ: length 52.7
  TOP w0.132: U47.C12 v1(68.36,80.79)
  TOP w0.191: v1(32.59,80.55) 32.59,81.28 33.11,81.81 35.45,81.81 35.92,82.27 TP50.1
  L03_SIG01 w0.076: v1(62.79,82.21) 62.77,82.21 62.35,81.79 62.35,77.91 62.13,77.7 61.91,77.48 60.75,77.48 59.94,76.67 59.94,75.26 59.42,74.74 59.03,74.74 58.58,75.18 58.58,75.93 57.8,76.71 55.35,76.71 54.09,75.45 51.57,75.45 51.33,75.68 43.45,75.68 43.31,75.82 43.31,76.51 43.22,76.6 v1(43.21,76.6)
  BOTTOM w0.14: v1(62.79,82.21) 63.89,82.21 64.45,81.65 64.89,81.65 65.75,80.79 v1(68.36,80.79)
  BOTTOM w0.191: v1(32.59,80.55) U98.7 34.07,80.55 34.22,80.7 R550.2 34.54,80.39 34.7,80.23 35.4,80.23 36.89,78.74 39,78.74 41.14,76.6 v1(43.21,76.6)
MCU_SAFETY_ERRORZ_1V8: length 66.8
  TOP w0.132: U47.B8 67.56,76.79 67.09,76.79 67.09,76.8 66.99,76.8 66.93,76.86 61.59,76.86 v1(60.74,76.01)
  TOP w0.191: v1(43.73,109.81) 43.73,103.64 42.21,102.13 U32.5 ; TP54.1 60.74,75.79 v1(60.74,76.01)
  L03_SIG01 w0.076: v1(53.38,104.12) 54.28,103.22 54.28,101.06 56.7,98.63 56.7,90.36 56.63,90.29 56.63,88.97 59.96,85.64 59.96,85.14 61.27,83.84 64.06,83.84 64.5,83.4 64.5,82.34 64.44,82.28 64.44,82.2 63.37,81.13 63.37,80.35 62.74,79.71 62.74,77.8 61.94,77 61.09,77 60.78,76.69 60.78,76.05 v1(60.74,76.01)
  BOTTOM w0.191: v1(43.73,109.81) 47.96,109.81 53.38,104.38 v1(53.38,104.12)
MCU_SAFETY_ERRORZ_3V3: length 57.5
  TOP w0.191: U32.10 45.35,102.13 42.39,99.17 41.32,99.17 38.18,96.03 38.18,90.49 40.23,88.44 40.23,87.35 39.67,86.79 39.67,79.46 v1(37.39,77.18) ; R281.1 54.94,72.47 v1(54.98,72.51)
  BOTTOM w0.191: v1(54.98,72.51) 54.98,74.19 54.27,74.91 53.35,74.91 52.5,74.06 52.5,73.8 51.98,73.28 43.75,73.28 39.91,77.13 37.44,77.13 v1(37.39,77.18)
MCU_SPI0_CLK: length 33.9
  TOP w0.191: v1(46.13,91.86) 46.84,91.15 48.87,91.15 49.34,90.69 R216.2 ; U45.13 v1(24.91,84.74)
  L03_SIG01 w0.076: v1(25,88.54) 25.67,87.87 25.67,85.23 25.18,84.74 v1(24.91,84.74)
  BOTTOM w0.191: v1(46.13,91.86) 45.75,92.24 44.24,92.24 44.01,92 35.2,92 33.3,90.11 32.79,90.11 31.75,91.14 27.6,91.14 v1(25,88.54)
MCU_SPI0_CLK_1V8: length 29
  TOP w0.191: v1(19.05,85.04) 18.75,84.74 U45.2 ; J12.17 v1(24.8,107.56)
  L03_SIG01 w0.076: v1(19.05,85.04) 24.22,90.21 24.22,95.71 23.08,96.85 23.08,105.85 v1(24.8,107.56)
MCU_SPI0_CS0: length 56.7
  TOP w0.132: U47.E11 v1(69.96,79.19)
  TOP w0.191: v1(26.18,87.13) 25.64,86.59 25.64,84.66 25.07,84.09 U45.12
  BOTTOM w0.14: 63.69,80.04 64.73,80.04 65.16,79.6 69.55,79.6 v1(69.96,79.19)
  BOTTOM w0.191: v1(26.18,87.13) 26.51,86.8 28.25,86.8 28.6,87.15 38.26,87.15 40.21,85.2 40.21,83.34 44.55,79 48.55,79 51.84,82.29 53.36,82.29 55.15,80.49 62.22,80.49 62.68,80.04 63.69,80.04
MCU_SPI0_CS0_1V8: length 32.8
  TOP w0.191: J12.23 v1(24.77,109.96) ; U45.3 v1(19.18,84.09)
  L03_SIG01 w0.076: v1(24.77,109.96) 22.72,107.91 22.72,96.72 23.84,95.59 23.84,90.59 18.52,85.27 18.52,84.75 v1(19.18,84.09)
MCU_SPI0_D0: length 62.4
  TOP w0.102: U47.A15 66.99,82.62 65.94,82.62
  TOP w0.14: 65.71,82.62 65.94,82.62
  TOP w0.191: v1(38.86,95.27) 39.91,96.32 46.77,96.32 49.59,93.5 50.97,93.5 51.78,92.69 51.78,92.54 53.25,91.08 54.47,91.08 61.92,83.63 63.84,83.63 64.51,82.96 65.37,82.96 65.71,82.62 ; U45.11 25.15,83.44 26.07,84.36 26.07,86.2 26.7,86.83 26.7,90.95 27.99,92.24 27.99,96.36 v1(29,97.37)
  BOTTOM w0.191: v1(38.86,95.27) 36.51,95.27 34.35,97.44 29.13,97.44 29.06,97.37 v1(29,97.37)
MCU_SPI0_D0_1V8: length 33.2
  TOP w0.191: v1(19.42,83.26) 19.24,83.44 U45.4 ; J12.19 25.65,108.36 v1(26.07,107.94)
  L03_SIG01 w0.076: v1(26.07,107.94) 26.07,107.6 23.45,104.98 23.45,97.13 24.46,96.12 24.46,89.82 21.75,87.11 21.75,85.59 v1(19.42,83.26)
MCU_SPI0_D1: length 57.1
  TOP w0.132: 66.42,80.77 66.78,80.77 66.8,80.79 67.56,80.79 U47.B12
  TOP w0.191: U45.10 25.29,82.79 26.52,84.02 26.52,86 27.53,87.01 v1(27.53,88.05) ; v1(41.59,87.2) 41.59,87.66 42.3,88.37 42.3,90.34 42.66,90.69 48.54,90.69 49,90.23 54.16,90.23 59.05,85.34 59.05,83.3 61.43,80.92 64.03,80.92 64.04,80.94 64.06,80.94 64.11,80.99 64.48,80.99 64.71,80.77 66.42,80.77
  BOTTOM w0.191: v1(27.53,88.05) 27.53,88.04 28.14,88.04 28.2,88.1 40.69,88.1 v1(41.59,87.2)
MCU_SPI0_D1_1V8: length 35.6
  TOP w0.191: v1(19.23,82.34) 18.79,82.79 U45.5 ; J12.21 v1(26.2,109.16)
  L03_SIG01 w0.076: v1(19.23,82.34) 22.46,85.57 22.46,87.08 24.82,89.43 24.82,96.31 23.83,97.3 23.83,105.01 26.51,107.68 26.51,108.85 v1(26.2,109.16)
MCU_SPI1_CLK: length 137.1
  TOP w0.191: U34.13 96.69,99.86 97.77,98.78 97.77,94.59 96.41,93.23 96.41,84.32 99.77,80.97 104.27,80.97 107.99,77.25 107.99,56.38 103.12,51.52 84.64,51.52 82.25,49.13 80.99,49.13 78.3,46.43 75.59,46.43 70.02,40.87 v1(70.02,40.36)
  L03_SIG01 w0.076: v1(70.02,40.36) 68.66,41.72 65.55,41.72 64.14,43.13 64.14,45.67 63.32,46.49 63.32,60.66 62.2,61.77 62.2,72.86 v1(62.36,73.02)
  BOTTOM w0.191: R574.2 62.61,73.27 v1(62.36,73.02)
MCU_SPI1_CLK_1V8: length 54.5
  TOP w0.191: J13.17 v1(122.2,129.95) ; U34.2 102.36,99.86 103.5,101.01 103.5,104.63 103.34,104.8 103.34,108.09 103.34,108.1 103.34,109 103.83,109.48 v1(103.83,113.66)
  L03_SIG01 w0.076: v1(102.35,130.09) 103.83,128.61 v1(103.83,113.66)
  BOTTOM w0.191: v1(122.2,129.95) 121.78,129.53 102.91,129.53 v1(102.35,130.09)
MCU_SPI1_CS0: length 145.3
  TOP w0.132: U47.C10 v1(68.36,78.39)
  TOP w0.191: v1(70.77,40.6) 70.77,41 75.82,46.04 78.56,46.04 81.26,48.73 82.48,48.73 84.82,51.07 103.61,51.07 108.37,55.83 108.37,77.51 104.53,81.35 99.95,81.35 96.8,84.5 96.8,92.95 98.17,94.32 98.17,99.01 96.67,100.51 U34.12
  L03_SIG01 w0.076: v1(68.36,78.39) 67.3,78.39 64,75.09 64,74.56 62.76,73.33 62.76,61.77 63.52,61.01 63.52,46.61 64.37,45.76 64.37,43.22 65.55,42.03 69.34,42.03 v1(70.77,40.6)
MCU_SPI1_CS0_1V8: length 52.1
  TOP w0.191: U34.3 102.4,100.51 103.12,101.24 103.12,104.47 102.96,104.64 102.96,108.25 102.96,108.26 102.96,109.16 103.31,109.5 v1(103.31,112.89) ; J13.23 v1(122.2,127.55)
  L03_SIG01 w0.076: v1(103.31,112.89) 103.31,113.54 102.31,114.54 102.31,117.56 102.63,117.88 102.63,126.19 v1(101.58,127.24)
  BOTTOM w0.191: v1(122.2,127.55) 121.69,128.06 102.41,128.06 101.59,127.24 v1(101.58,127.24)
MCU_SPI1_D0: length 150.4
  TOP w0.132: v1(65.75,79.08) 66.32,79.08 66.44,79.19 67.56,79.19 U47.B11
  TOP w0.191: v1(71.28,39.89) 71.33,39.94 71.33,41.01 75.92,45.6 78.72,45.6 81.48,48.35 82.7,48.35 85.02,50.66 103.74,50.66 108.75,55.67 108.75,77.76 104.78,81.73 100.77,81.73 100.29,81.73 97.18,84.84 97.18,92.55 98.57,93.94 98.57,99.88 97.29,101.16 U34.11
  L03_SIG01 w0.076: v1(65.75,79.08) 63.12,76.45 62.59,76.45 62.24,76.1 62.24,75.64 62.41,75.48 62.41,73.63 61.71,72.94 61.71,61.64 63.11,60.25 63.11,46.44 63.89,45.66 63.89,43.09 65.56,41.42 68.35,41.42 69.88,39.89 v1(71.28,39.89)
MCU_SPI1_D0_1V8: length 53.8
  TOP w0.191: U34.4 100.58,101.16 100,101.74 100,103.66 100.56,104.23 101.51,104.23 102.17,104.89 102.17,109.45 102.37,109.64 v1(102.37,111.08) ; J13.19 v1(122.2,129.15)
  L03_SIG01 w0.076: v1(102.37,111.08) 102.37,114.08 101.52,114.92 101.52,126.5 101.18,126.85 v1(101.18,128.76)
  BOTTOM w0.191: v1(122.2,129.15) 122.08,129.03 101.44,129.03 v1(101.18,128.76)
MCU_SPI1_D1: length 148.4
  TOP w0.132: U47.D10 v1(69.16,78.39)
  TOP w0.191: v1(71.81,40.55) 76.42,45.16 79.02,45.16 81.84,47.97 82.86,47.97 82.92,47.97 85.02,50.06 103.68,50.06 109.13,55.51 109.13,77.95 104.97,82.11 100.56,82.11 97.6,85.08 97.6,92.4 99.13,93.93 99.13,100.06 97.37,101.81 U34.10
  L03_SIG01 w0.076: v1(69.16,78.39) 68.77,78 67.16,78 64.36,75.2 64.36,74.58 63,73.22 63,61.99 63.71,61.29 63.71,46.76 64.67,45.8 64.67,43.32 65.76,42.23 70.3,42.23 71.81,40.72 v1(71.81,40.55)
MCU_SPI1_D1_1V8: length 52.3
  TOP w0.191: v1(103.35,114.21) 102.79,113.65 102.79,112.27 102.88,112.18 102.88,109.62 102.58,109.32 102.58,108.41 102.58,108.41 102.58,104.6 101.81,103.84 100.85,103.84 100.42,103.41 100.42,102.03 100.64,101.81 U34.5 ; J13.21 v1(122.2,128.35)
  L03_SIG01 w0.076: v1(103.35,114.21) 103.35,114.26 103.41,114.32 103.41,126.38 v1(101.75,128.04)
  BOTTOM w0.191: v1(122.2,128.35) 121.94,128.62 102.32,128.62 v1(101.75,128.04)
MCU_TIMER_IO1: length 60.6
  TOP w0.132: U47.C11 v1(68.36,79.19)
  TOP w0.191: U37.10 25.19,93.17 24.97,92.95 24.97,89.47 25.69,88.75 25.69,87.66 v1(25.14,87.11)
  BOTTOM w0.14: 61.48,80.11 62.69,78.9 62.69,78.34 62.92,78.12 66.87,78.12 67.95,79.19 v1(68.36,79.19)
  BOTTOM w0.191: v1(25.14,87.11) 25.14,86.81 25.72,86.23 28.21,86.23 28.76,86.77 38.09,86.77 39.83,85.03 39.83,83.18 44.39,78.61 48.73,78.61 51.95,81.83 53.27,81.83 54.99,80.11 61.48,80.11
MCU_TIMER_IO1_1V8: length 10.7
  TOP w0.191: J12.3 24.21,101.96 25.08,102.83 25.35,102.83 26.41,101.77 26.41,100.31 25.19,99.09 U37.2
MCU_TIMER_IO2: length 157.8
  TOP w0.191: v1(19.59,39.97) 19.83,40.21 19.83,41.02 15.59,45.27 15.59,76.2 20.77,81.39 20.77,86.35 24.57,90.14 24.57,93.18 24.79,93.41 U37.9
  L03_SIG01 w0.076: v1(39.08,31.44) 40.58,32.94 v1(40.58,36.52) ; v1(36.66,32.6) 32.03,32.6 31.34,31.92 30.25,31.92 29.97,31.64 28.94,31.64 27.24,29.95 24.24,29.95 20.86,33.32 20.86,38.7 v1(19.59,39.97) ; v1(63.93,42.5) 63.54,42.89 63.54,43.58 62.62,44.5 62.62,46.1 62.66,46.14 62.66,55.33 60.92,57.06 60.92,71.77 60.87,71.81 v1(60.77,71.81)
  BOTTOM w0.191: v1(60.77,71.81) 61.09,72.14 61.09,72.86 60.83,73.12 60.83,73.58 61.17,73.91 R570.1 ; v1(36.66,32.6) 37.04,32.6 37.14,32.5 37.46,32.5 37.46,32.5 38.01,32.5 v1(39.08,31.44) ; v1(63.93,42.5) 64.24,42.5 64.57,42.18 64.57,39.92 60.78,36.14 55.22,36.14 54.49,35.41 50.24,35.41 48.64,37.01 41.06,37.01 v1(40.58,36.52)
MCU_TIMER_IO2_1V8: length 10
  TOP w0.191: U37.3 24.79,96.3 24.78,96.31 24.78,97.42 21.29,100.91 21.29,102.38 21.67,102.76 J12.5
MCU_UART0_RX_3V3: length 102.6
  TOP w0.132: U47.D8 v1(69.16,76.79)
  TOP w0.191: v1(33.97,39.23) 35.41,39.23 41.3,33.34 41.3,32.14 41.49,31.95 46.07,31.95 46.68,32.57 46.68,34.5 47.59,35.42 55.83,35.42 56.7,36.29 62.21,36.29 65.22,39.29 65.22,42.46 66.04,43.28 66.04,43.68 v1(66.38,44.02) ; v1(34.54,51.92) 34.54,51.92 R326.2
  L03_SIG01 w0.076: v1(69.16,76.79) 69.55,76.4 69.55,74.2 69.36,74.01 66.53,74.01 63.72,71.19 63.72,62.92 64.82,61.82 64.82,57.12 65.25,56.69 65.25,47.23 66.52,45.96 66.52,44.16 v1(66.38,44.02) ; v1(34.42,55.44) 34.13,55.73 33.71,55.73 33.45,55.47 33.45,53.99 34.54,52.9 v1(34.54,51.92) 34.22,51.6 34.22,39.48 v1(33.97,39.23)
  BOTTOM w0.191: U117.8 34.42,55.61 v1(34.42,55.44)
MCU_UART0_TX_3V3: length 110.1
  TOP w0.132: U47.F8 v1(70.76,76.79)
  TOP w0.191: v1(18,62.94) 18,77.42 22.04,81.45 v1(22.04,83.74)
  BOTTOM w0.14: 61.96,79 62.36,78.6 62.36,78.18 62.77,77.78 67,77.78 67.21,77.99 69.32,77.99 69.56,77.76 69.56,77.39 69.76,77.19 70.36,77.19 v1(70.76,76.79) ; U117.6 34.72,56.67 35.08,57.03 R592.2
  BOTTOM w0.191: v1(18,62.94) 22.9,62.94 23.75,63.79 34.19,63.79 37.24,60.74 37.24,57.45 36.82,57.03 R592.2 ; v1(22.04,83.74) 24.15,85.85 28.37,85.85 28.91,86.39 37.93,86.39 39.39,84.93 39.39,83.08 44.26,78.21 44.26,77.88 44.49,77.65 49.46,77.65 50.73,78.92 50.73,80.07 51.92,81.26 52.64,81.26 53.18,80.72 53.18,80.52 54.1,79.6 61.36,79.6 61.96,79
MIC1_BIAS: length 14.5
  TOP w0.254: U7.6 v1(82.31,157.21) ; C3.1 R10.1 R9.1 v1(87.17,174.84) R8.1 R7.1
  BOTTOM w0.191: v1(82.31,157.21) 82.31,156.76 82.5,156.57 C379.1
  BOTTOM w0.254: v1(90.34,181.25) R405.1
  BOTTOM w0.305: R405.1 R406.1 C329.1 R407.1 R408.1
MIC2_BIAS: length 14.3
  TOP w0.254: C2.1 R6.1 R5.1 v1(70.16,174.84) R4.1 R3.1 ; U8.6 68.64,162.61 v1(68.54,162.71)
  BOTTOM w0.254: v1(73.2,181.25) R409.1 ; v1(68.54,162.71) 68.31,162.94 C363.1
  BOTTOM w0.305: R412.1 R411.1 C330.1 R410.1 R409.1
MMC0_CLK: length 21.7
  TOP w0.191: v1(102.35,75.47) 102.6,75.22 U49.M6
  BOTTOM w0.191: R558.1 87.61,78.1 88.36,77.32 89.95,77.32 90.89,78.27 92.94,78.27 94.2,79.53 101.94,79.53 103.08,78.39 R561.1 R565.2 102.73,75.57 102.45,75.57 v1(102.35,75.47)
MMC1_CLK: length 124.9
  TOP w0.191: R207.1 68.23,93.73 67.79,94.17 v1(64.59,94.17) ; U10.6 18.96,156.13 18.58,156.52 v1(18.58,156.6) 18.49,156.7 18.11,156.7 R54.1
  BOTTOM w0.191: v1(64.59,94.17) 64.17,94.17 64.11,94.12 59.22,94.12 58.51,94.82 55.48,94.82 55.33,94.67 55.33,94.34 55.18,94.18 54.96,94.18 54.81,94.34 54.81,94.67 54.66,94.82 54.44,94.82 54.29,94.67 54.29,94.34 54.14,94.18 53.92,94.18 53.77,94.34 53.77,94.67 53.62,94.82 52.85,94.82 52.28,95.38 51.22,95.38 50.68,95.93 50.1,95.93 49.79,96.24 49.12,96.24 48.94,96.06 44.02,96.06 42.92,97.16 36.31,97.16 35.07,98.4 22.18,98.4 18.02,102.56 18.02,105.11 16.74,106.39 15.35,106.39 12.18,109.56 12.18,145.5 15.86,149.17 16.59,149.17 19.66,152.24 19.66,156.23 19.28,156.6 v1(18.58,156.6) 17.26,156.6 16.59,155.93 16.59,154.86 16.24,154.5 J26.5
MMC1_CLK_R: length 5.6
  TOP w0.191: R207.2 70.36,91.6 70.36,91.6 70.56,91.4 70.56,89.03 70.36,88.83 U47.E22
MMC1_CMD: length 130.2
  TOP w0.132: U47.C21 68.36,87.99 68.36,88.65
  TOP w0.14: 68.21,88.8 68.36,88.65
  TOP w0.191: U10.1 20.96,154.63 21.04,154.55 21.07,154.55 21.26,154.36 v1(21.26,153.97) 21.5,154.2 R66.1 ; 68.21,88.8 67.74,89.27 67.2,89.27 66.78,89.68 66.78,91.65 v1(66.29,92.14)
  BOTTOM w0.191: v1(66.29,92.14) 65.45,92.14 65.26,92.33 65.26,94.33 63.82,95.78 62.89,95.78 62.41,95.29 53.27,95.29 52.74,95.83 51.41,95.83 50.86,96.38 50.83,96.38 50.83,96.38 50.6,96.38 50.28,96.38 49.97,96.69 48.93,96.69 48.79,96.54 44.32,96.54 43.02,97.85 36.45,97.85 35.39,98.92 22.38,98.92 19,102.3 19,104.96 17.01,106.95 15.66,106.95 12.67,109.93 12.67,145.25 16.1,148.67 16.82,148.67 21.26,153.12 v1(21.26,153.97) 20.88,153.97 20.2,154.65 20.2,155.77 20.65,156.23 20.65,157.04 20.22,157.47 17.02,157.47 16.25,156.7 J26.3
MMC1_D0: length 130.6
  TOP w0.14: U47.B22 67.51,88.84
  TOP w0.191: U10.8 18.87,155.13 18.59,154.85 v1(18.59,154.7) R65.1 ; 67.51,88.84 64.56,88.84 63.68,89.72 63.68,92.8 v1(63.38,93.09)
  BOTTOM w0.191: J26.7 16.42,152.3 17.09,152.97 17.09,155.6 17.6,156.12 18.79,156.12 19.08,155.83 19.08,155.2 v1(18.59,154.7) 19.04,154.25 19.04,152.32 16.46,149.74 15.41,149.74 11.67,145.99 11.67,109.39 15.25,105.81 16.44,105.81 17.22,105.02 17.22,102.61 23.13,96.7 26.97,96.7 28.2,97.92 34.6,97.92 35.84,96.68 41.72,96.68 42.8,95.59 48.43,95.59 48.81,95.2 49.44,95.2 49.71,95.47 50.5,95.47 51.03,94.93 52.1,94.93 53.36,93.67 55.86,93.67 56.01,93.82 56.01,94.16 56.16,94.31 56.38,94.31 56.53,94.16 56.53,93.91 56.68,93.76 56.9,93.76 57.05,93.91 57.05,94.16 57.2,94.31 57.42,94.31 57.57,94.16 57.57,93.82 57.72,93.67 62.81,93.67 v1(63.38,93.09)
MMC1_D1: length 130.5
  TOP w0.132: U47.D21 69.16,87.99
  TOP w0.14: 69.16,87.99 69.16,88.23 69.16,88.89
  TOP w0.191: U10.7 v1(18.54,155.63) 18.01,155.63 R57.1 ; 69.16,88.89 69.16,88.98 69.21,89.03 69.21,90.84 68.22,91.82 68.13,91.82 67.28,92.68 65.04,92.68 v1(64.61,93.1)
  BOTTOM w0.191: J26.8 16.27,151.2 17.58,152.52 17.58,155.32 17.9,155.63 v1(18.54,155.63) 18.03,155.13 18.03,152.15 16.24,150.35 15.18,150.35 11.14,146.31 11.14,107.71 14.59,104.27 15.68,104.27 16.71,103.24 16.71,102.25 22.75,96.22 32.92,96.22 35.44,93.69 39.37,93.69 39.91,94.23 46.87,94.23 47.54,94.9 48.15,94.9 48.55,94.51 50.37,94.51 50.75,94.51 52.04,93.22 62.38,93.22 62.99,92.61 64.12,92.61 v1(64.61,93.1)
MMC1_D2: length 129.7
  TOP w0.191: v1(67.28,91.88) 67.8,91.36 68.05,91.36 68.76,90.65 U47.C22 ; U10.2 v1(21.28,155.13) R64.1
  BOTTOM w0.191: J26.1 16.31,158.9 16.58,158.64 20.77,158.64 22.02,157.39 22.02,155.87 v1(21.28,155.13) 21.4,155.01 22.26,155.01 22.89,154.38 22.89,153.24 14.83,145.18 14.83,109.56 16.37,108.03 17.49,108.03 20.74,104.78 20.74,102.84 23.29,100.29 35.85,100.29 37.16,98.98 43.76,98.98 45.29,97.45 48.39,97.45 48.53,97.59 49.97,97.59 50.35,97.59 50.65,97.28 50.71,97.28 50.97,97.28 51.2,97.28 51.2,97.28 51.23,97.28 51.78,96.73 53.14,96.73 53.66,96.21 58.45,96.21 58.82,96.21 59.37,96.21 62.05,96.21 62.52,96.67 65.74,96.67 67.64,94.78 67.64,92.09 67.42,91.88 v1(67.28,91.88)
MMC1_D3: length 130.1
  TOP w0.191: U47.D22 69.56,88.93 69.66,89.03 69.66,91.02 68.41,92.27 68.32,92.27 67.42,93.17 v1(66.22,93.17) ; U10.3 20.94,155.63 v1(21.36,156.05) 21.39,156.08 R55.1
  BOTTOM w0.191: J26.2 16.45,157.8 16.65,158 20.51,158 21.36,157.15 v1(21.36,156.05) 20.83,155.52 20.83,154.81 21.16,154.48 21.95,154.48 22.19,154.24 22.19,153.26 13.21,144.28 13.21,110.35 16.1,107.46 17.23,107.46 19.53,105.16 19.53,102.49 22.25,99.77 35.49,99.77 36.85,98.41 43.4,98.41 44.81,97 48.61,97 48.75,97.14 50.16,97.14 50.47,96.83 50.71,96.83 50.78,96.83 51.01,96.83 51.02,96.83 51.05,96.83 51.59,96.28 52.95,96.28 53.48,95.75 59.18,95.75 62.23,95.75 62.7,96.23 65.1,96.23 66.22,95.1 v1(66.22,93.17)
MMC1_SD_EN: length 119
  TOP w0.191: v1(109.91,141.96) 109.66,142.21 U21.4 ; v1(15.52,161.52) 15.32,161.72 R21.1
  L03_SIG01 w0.076: v1(109.91,141.96) 109.91,141.97 110.69,142.76 110.69,144.35 109.76,145.28 109.76,154.93 v1(109.31,155.38)
  BOTTOM w0.191: v1(15.52,161.52) 16.97,160.07 38.3,160.07 38.96,159.42 47.44,159.42 49.17,157.68 49.3,157.68 49.61,157.68 49.93,157.68 49.93,157.68 50.53,157.68 51.02,157.2 51.47,157.2 51.79,157.2 52.1,157.2 54.58,157.2 58.1,153.68 68.65,153.68 70.14,155.18 73.62,155.18 74.51,154.29 77.34,154.29 77.64,154.59 79.08,154.59 79.37,154.3 87.93,154.3 90.45,156.82 104.52,156.82 105.94,155.4 109.29,155.4 v1(109.31,155.38)
MMC1_SD_LS_EN: length 4.9
  TOP w0.191: U4.3 19.59,165.69 19.4,165.5 18.87,165.5 18.42,165.95 R19.2 17.5,165.95 17.26,166.19 U2.4 16.88,166.62 17.11,166.85 R17.1
MMC1_SDCD: length 106.8
  TOP w0.132: U47.E18 v1(69.96,85.59)
  TOP w0.191: v1(33.51,117.81) 33.51,120.96 31.56,122.9 31.56,149.3 29.6,151.27 27.4,151.27 26.84,151.83 v1(26.84,153.4) ; v1(26.84,153.4) R70.1 ; v1(26.84,153.4) U12.5
  L03_SIG01 w0.076: v1(69.96,85.59) 69.96,85.77 69.54,86.2 69.54,87.35 67.94,88.94 64.41,88.94 63.7,89.66 63.7,91.77 64,92.07 64,97.9 63.56,98.35 63.56,99.17 59.57,103.15 59.57,108.74 58.48,109.83 v1(58.48,113.6)
  BOTTOM w0.191: v1(58.48,113.6) 57.54,114.53 49.88,114.53 49.4,115.02 42.92,115.02 40.41,112.51 38.21,112.51 33.51,117.22 v1(33.51,117.81) ; J26.9 v1(26.84,153.4)
MODE_SELECT: length 2.3
  TOP w0.191: U3.18 v1(44.51,162.8)
  BOTTOM w0.191: R425.1 v1(44.51,162.8) R426.1
Net_27: length 0.6
  TOP w0.132: 71.16,78.79 v1(70.76,78.39)
Net_676: length 0.6
  TOP w0.089: 81.56,80.39 v1(81.96,80.79)
Net_678: length 0.6
  TOP w0.132: 80.76,84.39 v1(81.16,84.79)
Net_680: length 0.6
  TOP w0.132: 79.16,85.19 v1(79.56,85.59)
Net_681: length 0.6
  TOP w0.132: 79.96,84.39 v1(80.36,84.79)
Net_682: length 0.6
  TOP w0.089: 83.16,80.39 v1(83.56,80.79)
Net_1333: length 0.6
  TOP w0.132: 76.76,72.39 v1(77.16,71.99)
Net_1336: length 0.6
  TOP w0.132: 78.36,76.39 v1(78.76,75.99)
Net_1337: length 0.6
  TOP w0.132: 77.56,73.99 v1(77.96,73.59)
Net_1347: length 0.6
  TOP w0.132: 74.36,73.19 v1(73.96,72.79)
Net_1348: length 0.6
  TOP w0.132: 75.96,72.39 v1(76.36,71.99)
Net_1349: length 0.6
  TOP w0.132: 75.96,73.19 v1(76.36,72.79)
OPT_RX: length 4
  TOP w0.191: U1.2 MOD1.3
OSC0: length 5
  TOP w0.191: Y5.3 113.83,73.99 113.97,73.85 115.56,73.85 116.08,74.36 C217.2 116.39,74.1 U48.88
OSC1: length 3.3
  TOP w0.191: Y5.1 115.42,73.17 115.56,73.31 C223.2 116.46,73.7 U48.89
OSPI0_CSN0: length 6.3
  TOP w0.132: U47.H21 72.36,87.99 72.36,88.74
  TOP w0.14: R206.2 71.93,92.73 71.79,92.59 71.79,89.31 72.36,88.74
OSPI_CLK: length 45.2
  TOP w0.178: U28.B2 80.18,118.45 80.89,118.45 80.94,118.5 82.45,118.5 v1(83.79,119.84)
  TOP w0.191: v1(75.59,96.78) 75.59,96.72 75.66,96.64 75.66,96.23 75.51,96.08 R197.1
  L03_SIG01 w0.076: v1(83.79,119.84) 83.79,118.96 82.63,117.8 82.46,117.8 82.35,117.91 82.35,118.07 83.4,119.12 83.4,119.27 83.28,119.39 83.13,119.39 82.14,118.4 80.46,118.4 79.14,117.09 75.57,117.09 75.1,116.62 75.1,115.85 75.52,115.43 75.57,115.43 76.52,114.49 76.87,114.49 77.11,114.24 77.11,113.59 75.91,112.39 75.91,106.35 74.07,104.52 74.07,100.74 75.33,99.49 75.33,99.16 75.57,98.92 75.57,98.92 75.57,98.52 75.81,98.27 75.95,98.13 75.95,97.34 75.54,96.93 75.54,96.82 v1(75.59,96.78)
  BOTTOM w0.178: R451.1 83.16,120.11 83.43,119.84 v1(83.79,119.84)
OSPI_CS: length 44.4
  TOP w0.178: v1(83.51,121.36) 83.23,121.08 83.23,120.01 82.79,119.56 81.27,119.56 81.14,119.44 80.15,119.44 79.72,119.87 U28.C2
  TOP w0.191: R206.1 v1(71.93,94.66)
  L03_SIG01 w0.076: v1(83.51,121.36) 83.17,121.02 83.17,120.61 82.1,119.54 81.25,119.54 79.04,117.32 75.45,117.32 74.84,116.72 74.84,114.93 76.18,113.59 76.18,113.12 75.57,112.51 75.57,106.26 73.84,104.54 73.84,100.63 75.08,99.39 75.08,99.08 75.34,98.83 75.34,98.42 75.72,98.04 75.72,97.55 75.2,97.03 73.78,97.03 71.93,95.18 v1(71.93,94.66)
  BOTTOM w0.178: v1(83.51,121.36) 83.5,121.35 82.8,121.35 R447.1
OSPI_DQ0: length 39.9
  TOP w0.14: v1(72.73,97.93) 72.59,97.79 RA3.1 ; U28.D3 v1(79.22,121.41)
  L03_SIG01 w0.076: v1(72.73,97.93) 72.73,99.51 72.01,100.24 72.01,105.73 72.18,105.9 72.18,106.36 72.35,106.54 72.35,109.04 72.75,109.44 72.75,110.6 71.84,111.5 71.84,114.84 72.27,115.27 72.27,116.17 72.09,116.35 71.82,116.35 71.68,116.49 71.68,117.41 74.55,120.28 77.67,120.28 78.03,119.93 78.39,119.93 78.98,120.52 79.88,120.52 80.64,121.28 80.64,121.64 80.4,121.88 79.13,121.88 78.64,122.37 77.58,122.37 77.48,122.27 77.48,122 77.57,121.9 78.73,121.9 v1(79.22,121.41)
  BOTTOM w0.14: R446.1 78.85,121.78 v1(79.22,121.41)
OSPI_DQ1: length 37.1
  TOP w0.14: RA3.2 72.19,98.52 v1(71.92,98.8)
  TOP w0.191: v1(80.17,121.42) 80.17,121.36 U28.D2
  L03_SIG01 w0.076: v1(71.92,98.8) 71.47,99.25 71.47,105.86 71.82,106.21 71.82,107.13 72,107.31 72,109.01 71.68,109.32 71.68,110.08 71.17,110.59 71.17,117.62 72.08,118.53 72.08,119.99 72.57,120.48 72.71,120.48 73.06,120.13 73.19,120.13 73.29,120.22 73.29,120.36 72.94,120.71 72.94,120.85 73.04,120.94 73.18,120.94 73.53,120.59 73.66,120.59 73.76,120.69 73.76,120.83 73.41,121.18 73.41,121.31 73.63,121.54 74.53,121.54 74.7,121.37 74.7,121.02 74.94,120.77 79.52,120.77 v1(80.17,121.42)
  BOTTOM w0.191: R450.1 79.75,120.94 80.17,121.36 v1(80.17,121.42)
OSPI_DQ2: length 34.7
  TOP w0.14: v1(78.22,120.35) 78.15,120.35 U28.C4 ; v1(71.91,99.52) 71.47,99.08 71.47,98.51 71.79,98.19 RA3.3
  L03_SIG01 w0.076: v1(71.91,99.52) 71.75,99.68 71.75,105.77 72,106.02 72,106.44 72.18,106.61 72.18,109.08 71.86,109.39 71.86,110.14 71.86,110.15 71.86,110.25 71.59,110.53 71.59,114.93 72.03,115.37 72.03,115.94 71.87,116.1 71.54,116.1 71.44,116.21 71.44,117.54 72.48,118.59 72.48,118.72 72.33,118.88 72.33,119.01 72.43,119.11 72.56,119.11 72.72,118.96 72.85,118.96 72.97,119.07 72.97,119.21 72.38,119.81 72.38,119.94 72.47,120.04 72.61,120.04 73.21,119.45 73.34,119.45 73.56,119.66 73.56,119.8 73.45,119.9 73.45,120.04 73.55,120.13 73.69,120.13 73.79,120.03 73.93,120.03 74.03,120.13 74.03,120.94 74.11,121.02 74.32,121.02 74.8,120.54 78.02,120.54 v1(78.22,120.35)
  BOTTOM w0.14: R452.1 78.08,120.21 v1(78.22,120.35)
OSPI_DQ3: length 35.6
  TOP w0.14: v1(71.25,97.93) 71.39,97.79 RA3.4 ; U28.D4 v1(78.22,121.41)
  L03_SIG01 w0.076: v1(78.22,121.41) 77.86,121.05 75.18,121.05 74.99,121.24 74.99,121.92 75.12,122.05 75.66,122.05 75.79,122.18 75.79,122.53 75.65,122.67 74.41,122.67 71.79,120.06 71.79,118.66 70.94,117.81 70.94,110.45 71.51,109.88 71.51,109.25 71.82,108.93 71.82,107.52 71.64,107.34 71.64,106.38 71.23,105.98 71.23,97.95 v1(71.25,97.93)
  BOTTOM w0.191: R449.1 77.79,120.98 v1(78.22,121.41)
OSPI_DQ4: length 41.1
  TOP w0.14: v1(75.12,97.79) 75.01,97.68 RA4.1 ; v1(75.46,121.51) 75.83,121.14 76.49,121.14 U28.D5
  L03_SIG01 w0.076: v1(75.12,97.79) 74.96,97.63 74.85,97.63 74.73,97.51 70.82,97.51 70.3,98.04 70.3,99.87 70.99,100.57 70.99,106.09 71.28,106.38 71.28,107.46 71.04,107.7 71.04,108.01 71.04,109.61 69.83,110.82 69.83,113.23 70.34,113.73 70.34,119.04 74.34,123.04 76.52,123.04 76.72,122.85 76.72,121.82 76.41,121.51 v1(75.46,121.51)
  BOTTOM w0.191: v1(75.46,121.51) 75.46,121.26 75.67,121.05 R448.1
OSPI_DQ5: length 36.7
  TOP w0.14: RA4.2 74.61,98.31 v1(74.71,98.4) ; U28.E3 v1(79.22,122.41)
  L03_SIG01 w0.076: v1(74.71,98.4) 74.69,98.42 74.45,98.42 73.98,98.89 73.98,99.39 73.37,100 73.37,104.61 74.16,105.4 74.16,107.02 73.81,107.37 73.81,109.75 73.54,110.02 73.54,110.81 72.97,111.38 72.97,111.68 73.13,111.83 73.13,113.55 73.63,114.05 73.63,115.35 73.95,115.67 73.95,117.17 75.69,118.91 79.36,118.91 81.64,121.19 81.64,122.71 81.41,122.95 79.75,122.95 v1(79.22,122.41)
  BOTTOM w0.14: R445.1 v1(79.22,122.41)
OSPI_DQ6: length 39.1
  TOP w0.14: RA4.3 74.21,98.12 73.82,98.51 73.65,98.51 73.22,98.94 v1(73.19,98.94) ; U28.E2 v1(80.22,122.41)
  L03_SIG01 w0.076: v1(73.19,98.94) 73.19,99.38 72.26,100.31 72.26,100.71 72.26,105.72 72.35,105.81 72.35,106.29 72.53,106.47 72.53,108.96 72.93,109.36 72.93,110.74 72.11,111.56 72.11,114.62 72.5,115.02 72.5,116.34 72.24,116.6 72.02,116.6 71.91,116.71 71.91,117.26 72.1,117.45 72.24,117.45 72.78,116.91 72.92,116.91 73.02,117 73.02,117.14 72.47,117.68 72.47,117.82 72.57,117.92 72.71,117.92 73.25,117.37 73.39,117.37 73.48,117.47 73.48,117.61 72.94,118.15 72.94,118.29 74.71,120.05 77.43,120.05 77.85,119.64 78.48,119.64 79.08,120.25 79.97,120.25 80.87,121.15 80.87,121.78 80.5,122.15 80.48,122.15 v1(80.22,122.41)
  BOTTOM w0.14: R444.1 v1(80.22,122.41)
OSPI_DQ7: length 38.3
  TOP w0.14: U28.E1 v1(81.22,122.41) ; v1(73.46,97.94) 73.81,97.59 RA4.4
  L03_SIG01 w0.076: v1(81.22,122.41) 81.22,121.17 79.88,119.83 79.04,119.83 78.6,119.39 75.85,119.39 75.35,118.89 75.21,118.89 74.69,119.42 74.55,119.42 74.46,119.32 74.46,119.18 74.98,118.66 74.98,118.52 74.88,118.43 74.75,118.43 74.22,118.95 74.09,118.95 73.99,118.85 73.99,118.72 74.51,118.19 74.51,118.06 74.42,117.96 74.28,117.96 73.75,118.48 73.62,118.48 73.52,118.39 73.52,118.25 73.95,117.82 73.95,117.49 72.75,116.29 72.75,114.93 72.6,114.78 72.37,114.55 72.37,111.62 73.26,110.74 73.26,109.44 73.07,109.25 73.07,106.66 73.07,105.8 72.53,105.26 72.53,100.39 73.67,99.25 73.67,98.15 v1(73.46,97.94)
  BOTTOM w0.14: R443.1 v1(81.22,122.41)
OSPI_DQS: length 1.2
  TOP w0.191: U28.C3 v1(79.22,119.41)
  BOTTOM w0.191: R453.1 v1(79.22,119.41)
OSPI_DQS_SOC: length 47.3
  TOP w0.135: U47.L21 75.56,87.99 75.56,88.65
  TOP w0.14: v1(75.56,92.36) 75.56,88.65
  L03_SIG01 w0.076: v1(75.56,92.36) 75.48,92.43 75.48,93.28 76.15,93.95 76.15,97.21 76.18,97.24 76.18,98.23 76.04,98.36 75.91,98.5 75.8,98.61 75.8,99.02 75.6,99.21 75.6,99.58 74.3,100.88 74.3,104.49 76.15,106.34 76.15,112.1 77.42,113.38 77.42,114.26 77.3,114.38 77.3,115.41 77.04,115.67 75.63,115.67 75.34,115.96 75.34,116.45 75.71,116.82 82.14,116.82 82.29,116.96 82.29,117.13 82.18,117.24 82.12,117.24 82.03,117.32 82.03,117.82 81.94,117.91 81.81,117.91 81.72,117.82 81.72,117.32 81.63,117.24 81.51,117.24 81.42,117.32 81.42,117.82 81.33,117.91 81.2,117.91 81.11,117.82 81.11,117.32 81.02,117.24 80.63,117.24 80.53,117.34 v1(80.53,117.87)
  BOTTOM w0.191: R504.1 75.28,92.64 v1(75.56,92.36) ; R453.2 80.26,118.71 R454.1 80.26,118.15 v1(80.53,117.87)
OSPI_INTN: length 1.5
  TOP w0.191: R125.1 R123.1
OSPI_RSTN: length 32.7
  TOP w0.191: U27.4 101.2,119.59 R124.1 101.94,119.59 102.12,119.41 102.12,118.64 101.75,118.27 99.14,118.27 98.73,118.68 94.21,118.68 v1(91.15,121.74) ; v1(83.72,120.58) 84.27,120.03 84.27,119.46 82.09,117.28 78.35,117.28 U28.A4
  BOTTOM w0.191: v1(83.72,120.58) 83.85,120.46 89.86,120.46 v1(91.15,121.74)
P2_PP_EXT_ENABLE: length 2.6
  BOTTOM w0.14: R669.1 45.06,19.69 44.17,20.58 U129.49
PCM1_ADDR_0: length 4.7
  TOP w0.191: R20.2 77.9,163.87 77.71,163.68 R26.1 77.4,163.44 77.59,163.25 78.71,163.25 79.13,163.67 79.62,163.67 79.81,163.48 U7.24
PCM1_ADDR_1: length 2.2
  TOP w0.183: U7.23 80.31,163.7 80.03,163.98 R23.2 R22.1
PCM1_AREG: length 2.6
  TOP w0.191: U7.2 80.31,157.27 v1(80.23,157.18) 80.23,156.86 80.03,156.67 C89.1
  BOTTOM w0.191: C378.1 v1(80.23,157.18)
PCM1_BSTOUT: length 3.7
  TOP w0.305: C96.1 C92.2 82.71,156.02 81.81,156.93 U7.5
PCM1_DREG: length 2.5
  TOP w0.254: C82.1 77.04,158.83 77.19,158.68 C81.1 78.37,158.68 78.45,158.76 U7.32
PCM1_GPIO1: length 6.2
  TOP w0.183: R34.2 77.01,160.76 U7.28
  TOP w0.191: v1(75.27,160.35) 75.28,160.33 75.65,160.33 75.71,160.27 75.99,160.27 76.05,160.33 76.73,160.33 77,160.6 R34.2
  BOTTOM w0.191: R432.1 73.73,159.95 74.12,160.35 v1(75.27,160.35)
PCM1_IN1N: length 22
  TOP w0.191: U7.10 84.91,159.26 84.94,159.24 88.37,159.24 91.25,162.11 91.25,165.76 v1(91.1,165.9) ; R9.2 88.95,173.45 88.95,172.68 88.85,172.59 C17.2 88.95,172.18 88.95,171.38 v1(88.82,171.24)
  BOTTOM w0.191: v1(91.1,165.9) 91.21,166.01 91.21,167.88 89.04,170.06 89.04,171.03 v1(88.82,171.24)
PCM1_IN1P: length 22.6
  TOP w0.191: v1(91.7,165.9) 91.7,161.92 88.56,158.78 84.94,158.78 84.92,158.76 U7.9 ; v1(89.53,171.24) 89.41,171.36 89.41,172.18 C18.2 89.51,172.59 89.41,172.69 89.41,173.45 R10.2
  BOTTOM w0.191: v1(89.53,171.24) 89.43,171.14 89.43,170.22 91.6,168.05 91.6,166 v1(91.7,165.9)
PCM1_IN2N: length 21.5
  TOP w0.191: v1(85.06,171.32) 85.11,171.38 85.11,172.18 C15.2 85.01,172.59 85.11,172.69 85.11,173.45 R7.2 ; v1(89.31,165.17) 89.43,165.05 89.43,162.44 87.23,160.24 84.94,160.24 84.91,160.26 U7.12
  BOTTOM w0.191: v1(85.06,171.32) 85.22,171.16 85.22,169.59 87.05,167.76 88.83,167.76 89.55,167.04 89.55,165.41 v1(89.31,165.17)
PCM1_IN2P: length 22.2
  TOP w0.191: R8.2 85.57,173.45 85.57,172.68 85.67,172.59 C16.2 85.64,172.26 85.64,171.45 v1(85.77,171.32) ; v1(90.07,165.05) 89.89,164.87 89.89,162.25 87.42,159.78 84.94,159.78 84.92,159.76 U7.11
  BOTTOM w0.191: v1(90.07,165.05) 89.94,165.18 89.94,167.21 88.99,168.16 87.21,168.16 85.61,169.76 85.61,171.16 v1(85.77,171.32)
PCM1_IN3N: length 43.8
  TOP w0.191: U7.14 84.08,161.24 85.92,161.24 87.94,163.26 87.94,166.32 88.78,167.16 90.75,167.16 96.26,172.67 96.26,180.71 95.7,181.27 91.88,181.27 88.37,177.77 88.37,177.12 87.61,176.35 85.98,176.35 85.52,176.81 v1(85.52,177.24)
  BOTTOM w0.191: v1(85.52,177.24) 85.68,177.39 85.68,177.72 85.24,178.16 ; 85.24,178.16 85.48,178.16 85.67,178.35 85.67,178.54 85.23,178.98 R408.2 ; 85.24,178.16 C334.2
PCM1_IN3P: length 44.1
  TOP w0.191: v1(86.23,177.24) 86.23,177.01 86.5,176.75 87.45,176.75 87.98,177.28 87.98,177.93 91.71,181.67 95.86,181.67 96.66,180.87 96.66,172.51 90.92,166.77 88.94,166.77 88.33,166.15 88.33,163 86.11,160.78 84.08,160.78 U7.13
  BOTTOM w0.191: v1(86.23,177.24) 86.07,177.4 86.07,177.74 C333.2 86.25,178.17 86.06,178.35 86.06,178.54 86.5,178.98 R407.2
PCM1_IN4N: length 43
  TOP w0.191: U7.16 84.1,162.21 84.77,162.21 85.75,163.19 85.75,166.99 85.68,167.05 84.42,168.31 83.16,168.31 79.04,172.43 79.04,180.36 80.07,181.39 84.2,181.39 85.51,180.07 85.51,178.76 84.72,177.97 84.72,176.77 85.63,175.85 88.91,175.85 89.56,176.5 89.56,177.08 v1(89.38,177.26)
  BOTTOM w0.191: 89.08,178.16 89.39,177.85 89.39,177.28 v1(89.38,177.26) ; 89.08,178.16 C332.2 ; 89.08,178.16 89.32,178.16 89.51,178.35 89.51,178.54 89.07,178.98 R406.2
PCM1_IN4P: length 43.9
  TOP w0.191: v1(90.09,177.26) 89.96,177.13 89.96,176.34 89.07,175.46 85.47,175.46 84.32,176.61 84.32,178.13 85.12,178.93 85.12,179.91 84.04,180.99 80.23,180.99 79.44,180.19 79.44,172.59 83.33,168.7 84.59,168.7 86.14,167.15 86.14,162.94 84.96,161.76 U7.15
  BOTTOM w0.191: C331.2 90.12,178.17 ; 90.12,178.17 89.78,177.83 89.78,177.57 v1(90.09,177.26) ; 90.12,178.17 90.08,178.17 89.9,178.35 89.9,178.54 90.34,178.98 R405.2
PCM1_INT: length 74.7
  TOP w0.191: v1(104.96,154.98) 104.63,154.65 U21.15
  L03_SIG01 w0.076: v1(75.76,161.82) 76.42,161.17 76.42,153.43 v1(76.31,153.32)
  BOTTOM w0.191: U78.10 54.93,160.52 54.96,160.55 56.11,160.55 56.27,160.39 56.27,160.38 56.43,160.22 56.43,158.85 56.96,158.32 64.73,158.32 66.65,160.25 71.77,160.25 73.34,161.82 v1(75.76,161.82) ; v1(76.31,153.32) 76.35,153.27 87.51,153.27 90.6,156.36 104.07,156.36 104.48,155.95 104.48,155.45 v1(104.96,154.98)
PCM1_INT_1V8: length 32.9
  TOP w0.191: R34.1 v1(75.85,160.77)
  BOTTOM w0.191: v1(75.85,160.77) 75.48,160.77 75.4,160.85 73.74,160.85 72.15,159.26 66.73,159.26 65.3,157.84 56.59,157.84 56.08,158.34 51.95,158.34 51.46,158.83 50.26,158.83 49.53,159.56 49.53,160.27 49.78,160.52 U78.2
PCM1_MCASP2_AXR14: length 2.2
  TOP w0.183: R38.2 77.24,159.86 77.64,160.26 U7.29
PCM1_RESETN: length 47.5
  TOP w0.191: v1(92.5,166.82) 93.16,166.15 93.16,159.47 91.12,157.42 91.12,153.3 91.57,152.85 R68.2 92.1,151.96 91.71,151.57 90.11,151.57 89.91,151.37 89.56,151.37 89.44,151.25 R78.1 U14.4 ; U7.22 80.81,163.77 80.53,164.05 80.53,165.49 79.2,166.82 79.2,169.74 79.51,170.05 v1(80.55,170.05)
  BOTTOM w0.191: v1(92.5,166.82) 92.5,169.82 90.37,171.94 84.82,171.94 84.19,171.31 84.19,170.57 83.68,170.05 v1(80.55,170.05)
PCM1_VREF: length 1.2
  TOP w0.254: C87.1 83.03,157.23 82.81,157.45 U7.7
PCM2_ADDR_0: length 3.2
  TOP w0.183: R63.1 R62.2 72.69,155.53 72.16,156.06 71.36,156.06 71.14,156.29 U8.24
PCM2_ADDR_1: length 2.2
  TOP w0.183: U8.23 70.64,156.1 70.91,155.83 R60.2 R61.1
PCM2_AREG: length 2.5
  TOP w0.254: U8.2 70.64,162.57 v1(70.72,162.65) 70.75,162.65 C64.1
  BOTTOM w0.254: v1(70.72,162.65) 70.88,162.49 C368.1
PCM2_BSTOUT: length 3.8
  TOP w0.305: C54.1 C60.2 68.34,163.72 69.14,162.92 U8.5
PCM2_IN1N: length 24.1
  TOP w0.191: v1(71.67,171.24) 71.81,171.38 71.81,172.18 C13.2 71.71,172.59 71.81,172.68 71.81,173.5 71.45,173.86 R5.2 ; v1(63.69,168.34) 63.85,168.18 63.85,161.89 65.2,160.54 66.09,160.54 66.14,160.48 U8.10
  BOTTOM w0.191: v1(71.67,171.24) 71.84,171.08 71.84,169.98 71.51,169.66 64.27,169.66 63.85,169.23 63.85,168.5 v1(63.69,168.34)
PCM2_IN1P: length 23.4
  TOP w0.191: v1(72.39,171.24) 72.26,171.36 72.26,172.18 C14.2 72.36,172.59 72.26,172.69 72.26,173.48 72.64,173.86 R6.2 ; U8.9 66.14,160.98 66.09,160.93 65.36,160.93 64.24,162.05 64.24,168.18 v1(64.4,168.34)
  BOTTOM w0.191: v1(72.39,171.24) 72.23,171.09 72.23,169.82 71.67,169.26 64.43,169.26 64.24,169.07 64.24,168.5 v1(64.4,168.34)
PCM2_IN2N: length 24.8
  TOP w0.191: U8.12 66.14,159.48 66.09,159.53 63.98,159.53 61.89,161.63 61.89,168.71 v1(61.73,168.87) ; v1(67.92,171.32) 67.97,171.38 67.97,172.18 C11.2 67.87,172.59 67.97,172.69 67.97,173.45 R3.2
  BOTTOM w0.191: v1(67.92,171.32) 68.11,171.13 68.11,170.82 67.85,170.57 62.5,170.57 61.89,169.96 61.89,169.03 v1(61.73,168.87)
PCM2_IN2P: length 24.1
  TOP w0.191: v1(68.63,171.32) 68.5,171.45 68.5,172.26 C12.2 68.52,172.59 68.43,172.68 68.43,173.45 R4.2 ; v1(62.44,168.87) 62.28,168.71 62.28,161.79 64.14,159.93 66.09,159.93 66.14,159.98 U8.11
  BOTTOM w0.191: v1(68.63,171.32) 68.5,171.2 68.5,170.66 68.01,170.17 62.66,170.17 62.28,169.79 62.28,169.03 v1(62.44,168.87)
PCM2_IN3N: length 44.8
  TOP w0.191: U8.14 66.14,158.48 66.09,158.54 63.56,158.54 60.71,161.38 60.71,178.16 64.04,181.5 66.1,181.5 67.29,180.3 68.23,180.3 70.79,177.74 70.79,176.49 70.37,176.07 68.94,176.07 68.51,176.49 68.51,176.65 68.51,177.22 v1(68.36,177.37)
  BOTTOM w0.191: C338.2 68.09,178.16 ; 68.09,178.16 68.33,178.16 68.53,178.35 68.53,178.54 68.09,178.98 R412.2 ; 68.09,178.16 68.51,177.75 68.51,177.53 v1(68.36,177.37)
PCM2_IN3P: length 41.6
  TOP w0.191: v1(69.05,177.38) 68.91,177.24 68.91,176.65 69.1,176.46 70.21,176.46 70.4,176.65 70.4,177.58 68.06,179.91 67.13,179.91 65.94,181.1 64.21,181.1 61.11,178 61.11,161.55 63.72,158.93 66.09,158.93 66.14,158.98 U8.13
  BOTTOM w0.191: v1(69.05,177.38) 68.91,177.52 68.91,177.72 C337.2 69.1,178.17 68.92,178.35 68.92,178.54 69.36,178.98 R411.2
PCM2_IN4N: length 51.3
  TOP w0.191: v1(72.19,177.37) 72.38,177.19 72.38,176.69 72.84,176.22 73.68,176.22 74.05,176.59 74.05,178.2 70.81,181.44 67.77,181.44 66.71,182.5 63.63,182.5 59.49,178.36 59.49,161.2 63.16,157.53 66.09,157.53 66.14,157.48 U8.16
  BOTTOM w0.191: 71.93,178.16 C336.2 ; 71.93,178.16 72.17,178.16 72.36,178.35 72.36,178.54 71.93,178.98 R410.2 ; 71.93,178.16 72.35,177.75 72.35,177.53 v1(72.19,177.37)
PCM2_IN4P: length 48.1
  TOP w0.191: v1(72.88,177.38) 72.77,177.27 72.77,176.85 73.01,176.62 73.52,176.62 73.65,176.75 73.65,178.04 70.65,181.05 67.61,181.05 66.55,182.1 63.79,182.1 59.88,178.19 59.88,161.37 63.32,157.93 66.09,157.93 66.14,157.98 U8.15
  BOTTOM w0.191: R409.2 73.2,178.98 72.76,178.54 72.76,178.35 72.94,178.17 C335.2 72.74,177.72 72.74,177.52 v1(72.88,177.38)
PCM2_INT: length 70.4
  TOP w0.191: v1(104.17,158.94) 104.13,158.9 U21.16
  BOTTOM w0.191: U78.9 54.79,160.92 54.81,160.93 56.26,160.93 56.65,160.55 56.65,160.54 56.81,160.37 56.81,160.32 56.83,160.3 56.83,159.22 57.29,158.77 64.19,158.77 66.7,161.27 71.67,161.27 71.77,161.17 72.15,161.17 73.19,162.21 75.34,162.21 75.41,162.28 76.21,162.28 77.41,163.48 83.52,163.48 85.08,161.92 96.61,161.92 97.48,162.79 100.25,162.79 104.1,158.94 v1(104.17,158.94)
PCM2_INT_1V8: length 35.3
  TOP w0.191: v1(75.52,157.37) 75.52,158.34 74.9,158.97 R46.1
  BOTTOM w0.191: v1(75.52,157.37) 74.24,157.37 73.83,157.79 72.49,157.79 72.11,158.16 67.1,158.16 66.39,157.45 56.19,157.45 55.69,157.96 51.79,157.96 51.3,158.45 49.61,158.45 49.02,159.04 49.02,160.45 49.49,160.92 U78.3
PCM2_MCASP2_AXR14: length 1.2
  BOTTOM w0.191: R433.1 74.29,159.56 74.46,159.73 R431.2
PCM2_RESETN: length 22.5
  TOP w0.183: U8.22 v1(70.14,155.91)
  L03_SIG01 w0.076: v1(76,170.12) 74.45,168.57 72.67,168.57 70.24,166.13 70.24,161.62 70.46,161.4 70.46,156.23 v1(70.14,155.91)
  BOTTOM w0.191: v1(76,170.12) 76.16,170.28 R415.2 77.55,171.07 R416.1 77.56,171.07 U75.4
PCM2_VREF: length 1.2
  TOP w0.254: C65.1 67.92,162.58 68.14,162.36 U8.7
PCM6240_BUF_EN: length 127.1
  TOP w0.191: v1(69.89,101.63) 70.3,102.04 U35.1
  L03_SIG01 w0.076: v1(69.89,101.63) 69.2,102.32 69.2,103.13 66.46,105.87 66.46,110.39 66.69,110.62 66.69,112.93 66.55,113.06 66.55,113.97 66.69,114.11 66.69,121.05 66.84,121.21 66.84,123.49 67.77,124.41 67.77,138.93 68.95,140.11 v1(68.95,148.17) ; v1(91.71,146.16) 93.56,144.31 93.56,136.92 94.49,135.99 94.49,127.22 93.42,126.14 v1(93.42,117.56)
  BOTTOM w0.191: U89.1 R488.1 68.8,99.9 68.65,100.06 68.65,100.89 69.39,101.63 v1(69.89,101.63) ; v1(93.42,117.56) 86,110.15 86,108.31 84.53,106.83 84.21,106.83 83.87,107.18 83.87,107.71 83.54,108.04 U84.10 ; v1(68.95,148.17) 71.83,148.17 72.26,147.74 73.4,147.74 73.71,148.05 76.36,148.05 76.86,147.55 84.76,147.55 86.4,145.92 91.47,145.92 v1(91.71,146.16)
PCM6240_MCASP2_ACLKR: length 84.5
  TOP w0.183: 73.1,159.98 U8.30
  TOP w0.191: 73.1,159.98 73.33,159.98 73.67,160.32 74.56,160.32 75.08,159.8 75.08,159.46 75.42,159.12 75.58,159.12 v1(75.61,159.09) 75.68,159.15 76,159.15 76.22,159.38 77.54,159.38 77.92,159.76 U7.30 ; v1(91.36,113.43) 90.9,113.43 89.92,112.46 89.92,108.37 89.32,107.77 86.83,107.77 86.5,107.44 86.5,103.39 87.2,102.69 R163.2
  L03_SIG01 w0.076: v1(91.36,113.43) 91.23,113.56 91.23,119.26 91.63,119.65 91.63,128.71 91.24,129.1 91.24,144.65 90.72,145.17 90.72,155.63 v1(88.8,157.55)
  BOTTOM w0.191: v1(75.61,159.09) 76.05,158.65 78.51,158.65 79.3,159.44 84.68,159.44 86.58,157.55 v1(88.8,157.55)
PCM6240_MCASP2_AFSR: length 65.5
  TOP w0.145: U7.31 v1(78.26,159.26)
  TOP w0.191: U8.31 v1(72.69,160.48)
  L03_SIG01 w0.076: v1(70.09,108.73) 70.07,108.75 70.07,109.03 67.9,111.2 67.9,115.03 67.71,115.22 67.71,119.69 72.29,124.27 72.29,141.21 71.01,142.49 71.01,154.11 71.42,154.52 71.42,159.21 v1(72.69,160.48)
  BOTTOM w0.191: v1(78.26,159.26) 76.23,161.28 73.4,161.28 72.76,160.64 72.76,160.55 v1(72.69,160.48) ; v1(70.09,108.73) 70.09,108.69 70.32,108.45 R468.2
PCM6240_MCASP2_AXR14: length 66.7
  TOP w0.191: R38.1 76,159.86 v1(75.94,159.79)
  L03_SIG01 w0.076: v1(75.94,159.79) 76.12,159.61 76.12,158.54 75.04,157.46 75.04,125.33 69.41,119.69 69.41,118.03 69.75,117.68 69.75,114.01 69.43,113.68 69.43,110.54 70.67,109.31 70.67,107.13 70.33,106.79 70.33,104.43 v1(70.01,104.11)
  BOTTOM w0.191: R431.1 75.88,159.73 v1(75.94,159.79) ; U89.2 71.64,100.85 72.13,101.34 72.13,103.77 71.79,104.11 v1(70.01,104.11)
PCM6240_MCASP2_AXR15: length 65.2
  TOP w0.191: v1(70.57,102.86) 71.38,102.86 71.91,102.34 71.91,101.31 71.69,101.09 U35.2
  L03_SIG01 w0.076: v1(70.57,102.86) 70.57,105.96 71.1,106.49 71.1,107.39 70.84,107.65 70.84,109.38 70.77,109.46 69.61,110.62 69.61,113.43 70.04,113.86 70.04,119.09 75.4,124.45 75.4,146.16 76.15,146.92 76.15,152.92 75.86,153.21 v1(75.86,156.63)
  BOTTOM w0.191: R435.1 75.47,158.51 76.25,157.73 76.25,157.1 76.23,157.08 76.23,157.01 v1(75.86,156.63)
PD_GPIO0: length 1.5
  BOTTOM w0.191: R674.2 35.61,17.96 35.84,18.18 U129.16
PD_HRESET: length 3.5
  TOP w0.191: v1(43.86,23.96) 43.86,24.04 44.13,24.31 C301.1
  BOTTOM w0.191: v1(43.86,23.96) 43.97,23.84 43.97,23.7 44.07,23.6 R662.1 44.5,23.04 44.04,22.58 U129.44
PD_I2C_IRQ: length 194.3
  TOP w0.191: v1(101.46,140.75) 101.91,141.21 U21.23
  L03_SIG01 w0.076: v1(43.12,143.35) 42.82,143.04 42.82,142.17 42.8,142.15 42.8,142 42.8,142 42.8,134.76 42.13,134.09 42.13,131.73 43.24,130.62 43.24,125.77 41.96,124.49 41.96,103.71 36.5,98.25 36.5,94.01 36.98,93.53 36.98,91.07 36.51,90.6 33.99,90.6 32.93,89.54 32.93,88.97 33.32,88.58 33.32,59.63 36.64,56.31 36.64,51.91 36.39,51.66 36.39,36.43 38.28,34.53 38.28,32.82 v1(36.79,31.32)
  BOTTOM w0.191: v1(101.46,140.75) 101.49,140.78 101.49,141.81 100,143.3 82.78,143.3 81.95,142.47 81.05,142.47 80.39,141.81 79.48,141.81 78.79,141.11 75.33,141.11 74.32,142.12 68.77,142.12 67.54,143.34 64.79,143.34 64.34,142.89 55.31,142.89 54.14,144.07 52.88,144.07 51.87,143.05 43.43,143.05 v1(43.12,143.35) ; R655.1 39.29,26.13 39.16,26.26 R645.2 38.93,26.6 38.23,27.3 37.8,27.3 37.25,27.85 37.25,30.86 v1(36.79,31.32)
PD_MS_I2C1_IRQ: length 1.3
  BOTTOM w0.203: U129.29 37.45,24.19 R660.2
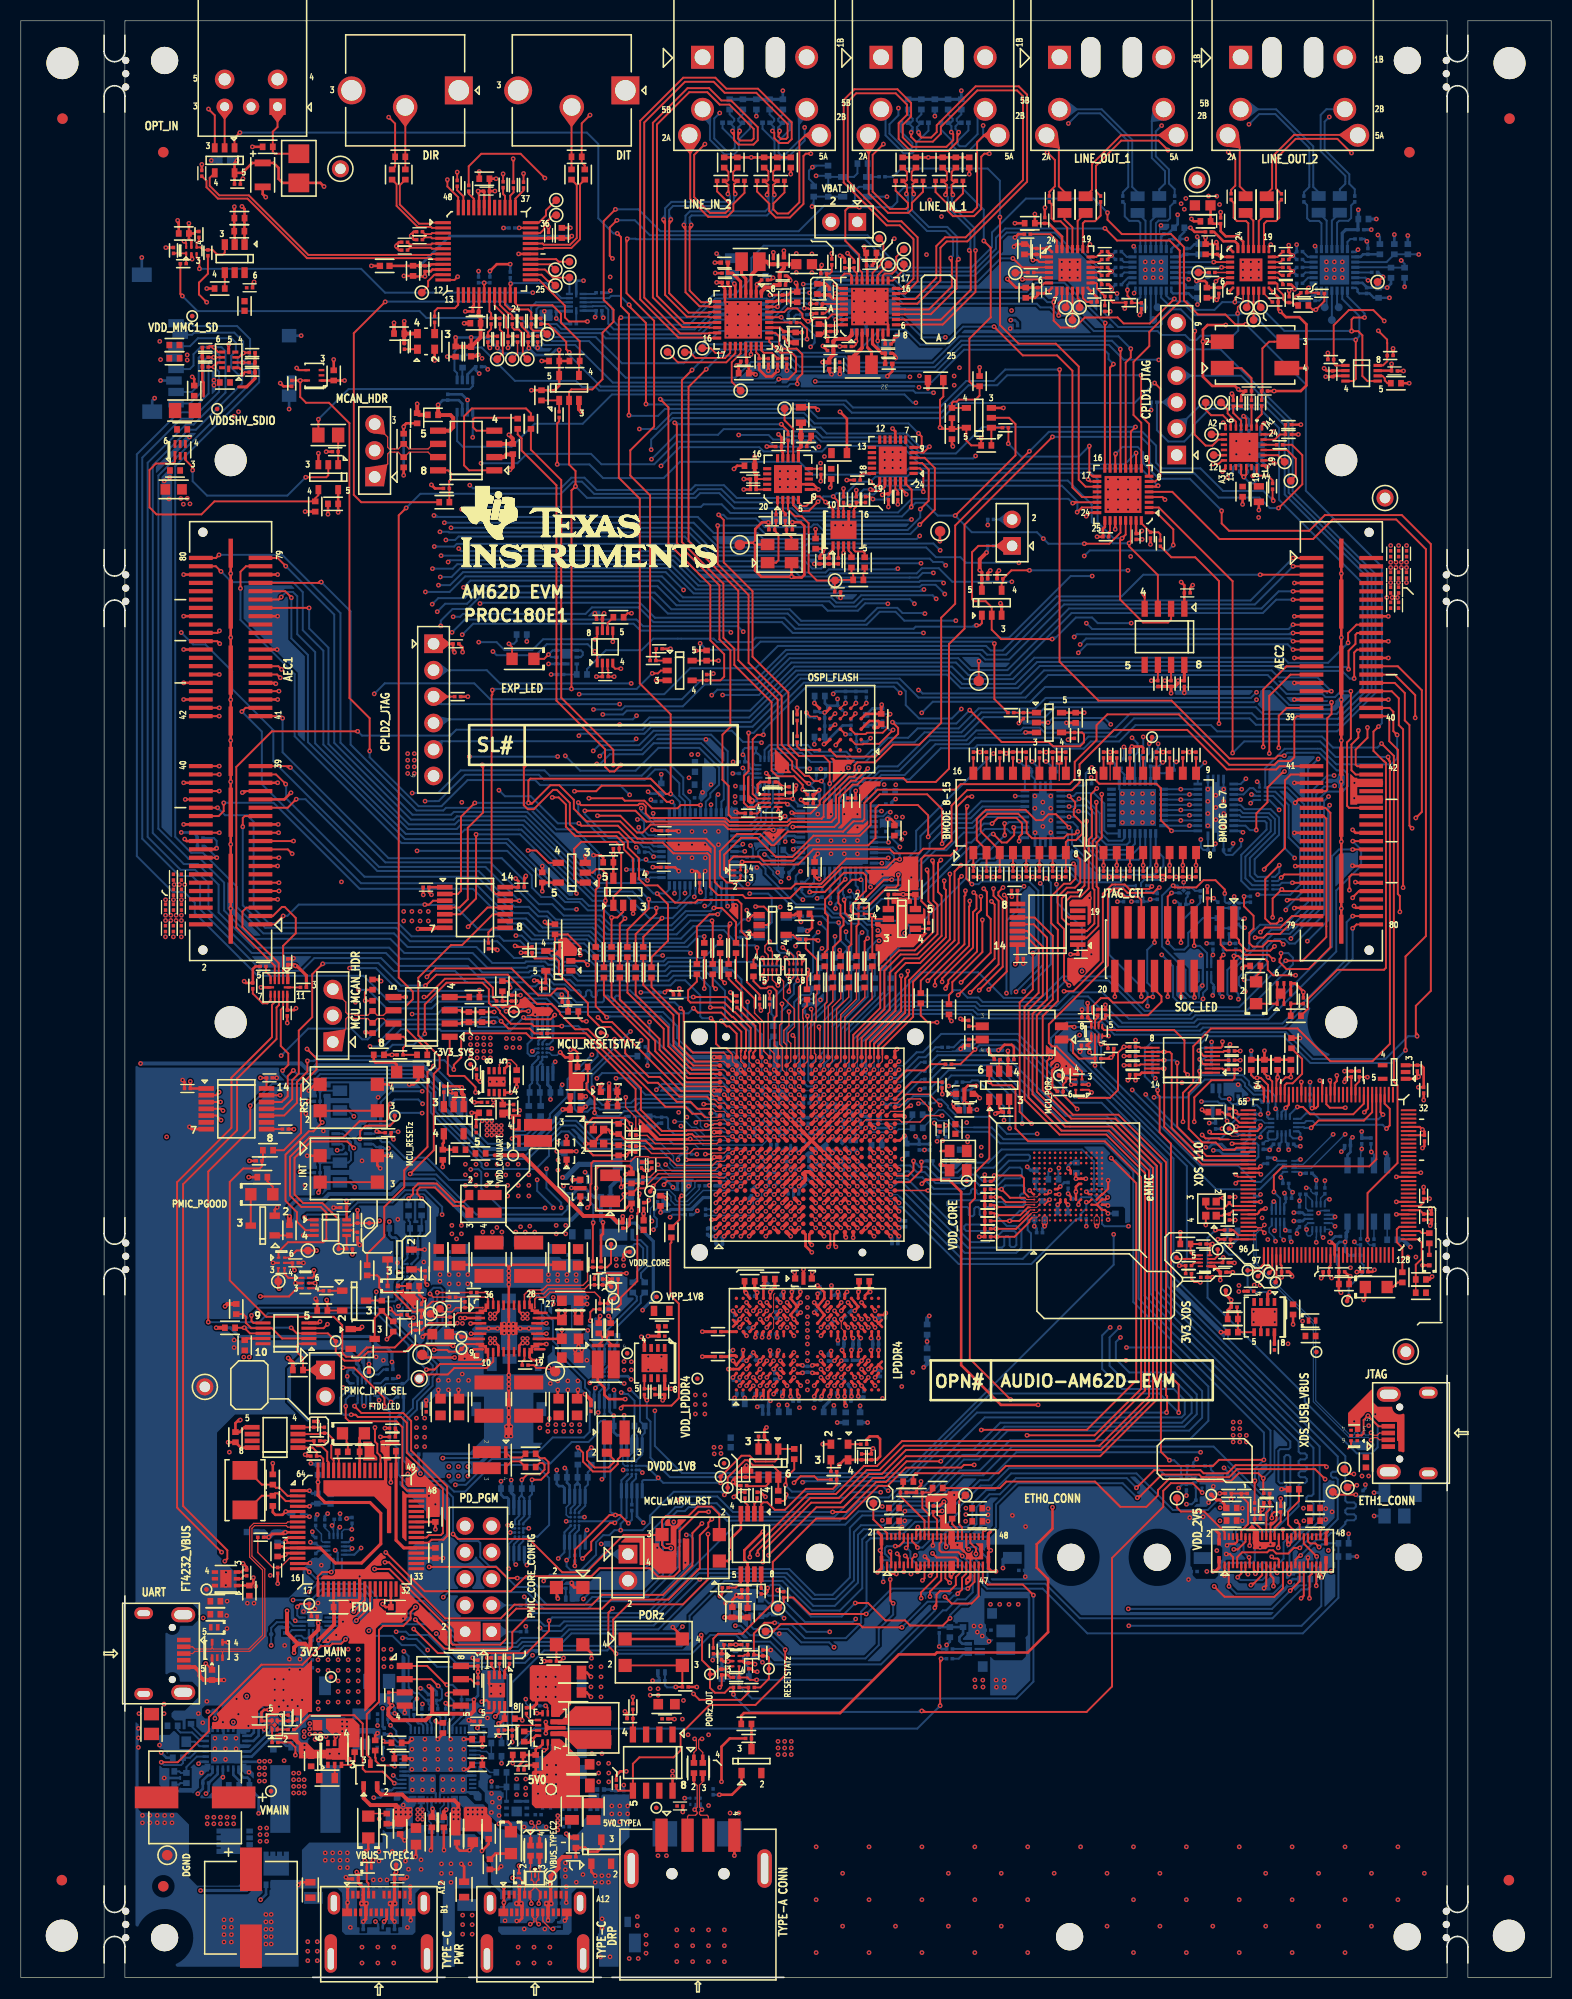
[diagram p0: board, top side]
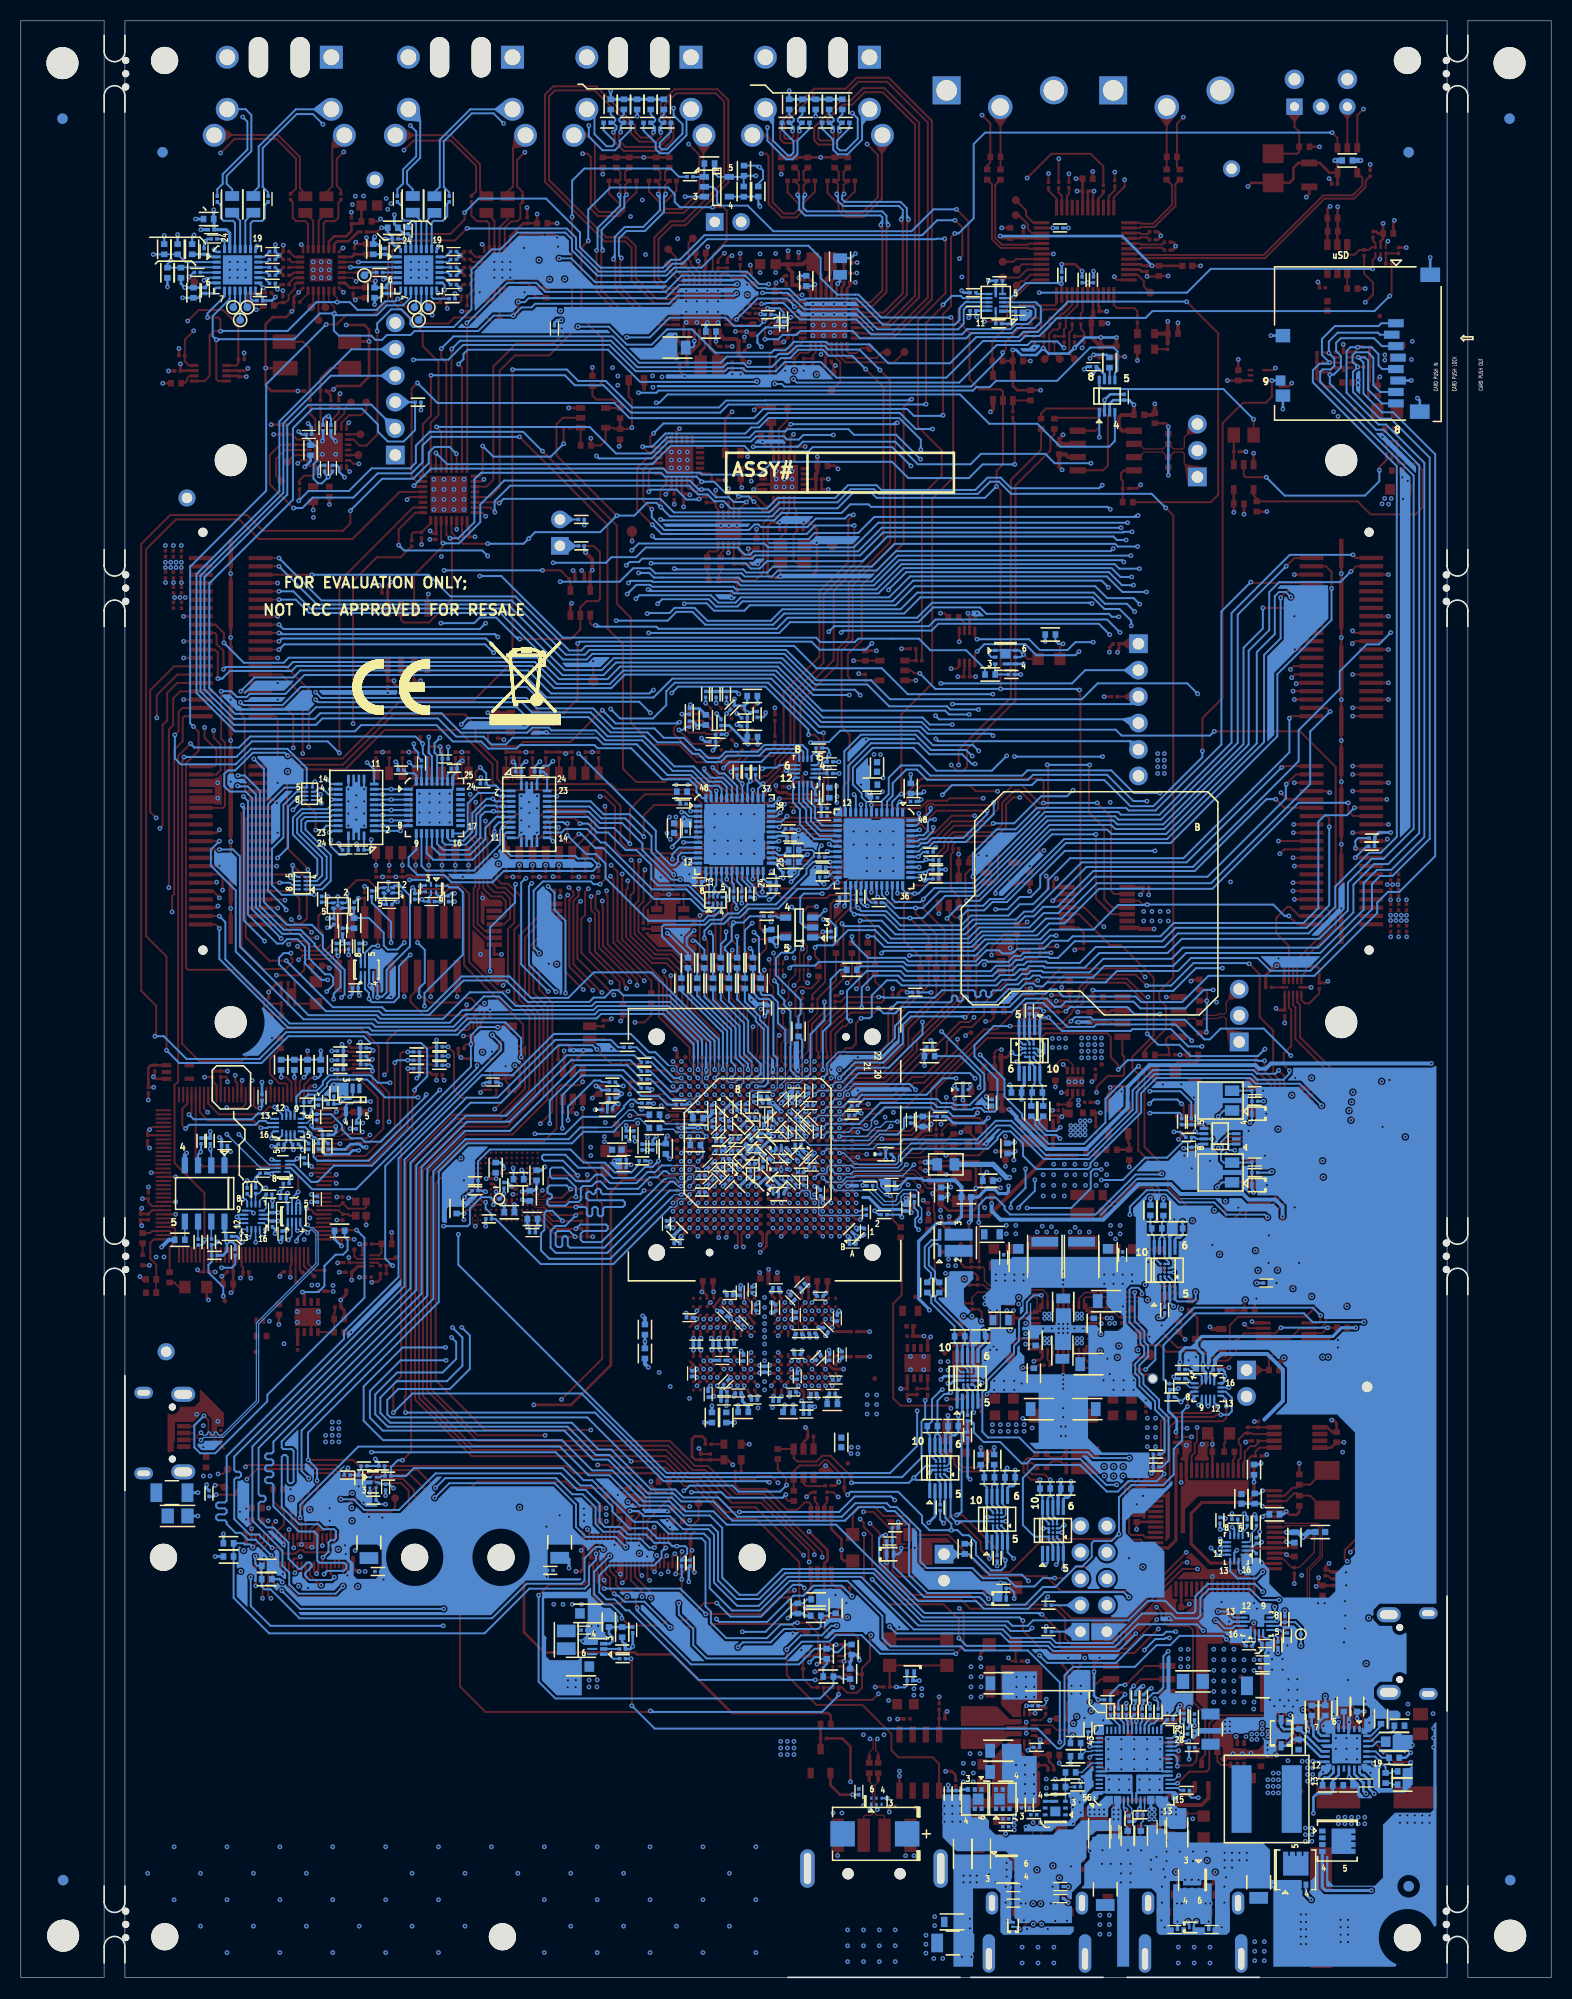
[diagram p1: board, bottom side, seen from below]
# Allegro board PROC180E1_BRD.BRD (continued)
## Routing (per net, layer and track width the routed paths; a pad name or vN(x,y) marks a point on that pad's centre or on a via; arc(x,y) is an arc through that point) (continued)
PD_MS_I2C1_SCL: length 24.4
  L03_SIG01 w0.076: v1(35.51,23.29) 35.89,23.67 43.33,23.67 43.57,23.44 45.51,23.44 48.05,25.98 48.05,33.26 v1(48.51,33.72)
  BOTTOM w0.145: v1(35.51,23.29) 35.43,23.38 R664.2
  BOTTOM w0.191: U129.27 36.22,22.58 v1(35.51,23.29) ; R633.1 48.57,33.65 v1(48.51,33.72)
PD_MS_I2C1_SDA: length 26.8
  L03_SIG01 w0.076: v1(35.51,24.21) 35.8,23.92 43.15,23.92 45.26,26.03 46.51,26.03 47.52,27.05 47.52,35.72 v1(48.36,36.55)
  BOTTOM w0.191: v1(48.36,36.55) 48.57,36.34 R627.1 ; U129.28 36.39,22.98 36.07,23.3 36.07,23.65 v1(35.51,24.21) 35.26,24.45 R658.2
PD_S_I2C2_IRQ: length 1.6
  BOTTOM w0.191: U129.34 39.45,24.4 39.29,24.56 R655.2
PD_S_I2C2_SCL: length 2
  BOTTOM w0.191: U129.32 38.65,24.17 38.44,24.38 38.16,24.38 37.76,24.78 R657.2
PD_S_I2C2_SDA: length 1.7
  BOTTOM w0.191: R656.2 38.52,24.84 38.9,24.46 38.9,24.41 39.03,24.28 39.03,24.27 39.05,24.25 U129.33
PD_SPI_CLK: length 19
  TOP w0.191: U69.6 41.07,27.37 40.93,27.23 v1(40.93,27.18)
  L03_SIG01 w0.076: J21.7 44.15,39.75 44.15,32.63 42.33,30.81 42.33,27.85 41.65,27.18 v1(40.93,27.18)
  BOTTOM w0.191: R652.2 41.57,26.54 v1(40.93,27.18)
PD_SPI_MISO: length 29.2
  TOP w0.191: v1(40.09,27.99) 39.44,28.64 U69.2
  L03_SIG01 w0.076: J21.5 45.97,39.03 45.97,39.86 46.44,40.33 46.44,41.04 46.24,41.24 46.24,41.25 45.47,42.01 42.01,42.01 41.44,41.44 41.44,32.87 40.09,31.52 v1(40.09,27.99)
  BOTTOM w0.191: R654.2 40.05,26.15 39.92,26.28 R644.2 40.26,26.6 40.45,26.79 40.45,27.64 v1(40.09,27.99)
PD_SPI_MOSI: length 19
  TOP w0.191: v1(40.81,26.34) 41.05,26.1 U69.5
  L03_SIG01 w0.076: J21.8 43.76,39.75 43.76,32.81 41.83,30.89 41.83,27.98 41.46,27.61 40.79,27.61 40.45,27.27 40.45,26.69 40.81,26.34 v1(40.81,26.34)
  BOTTOM w0.191: R653.2 v1(40.81,26.34)
PD_SPI_SS: length 28.8
  TOP w0.14: 40.85,28.09 v1(40.93,28.09)
  TOP w0.191: U69.1 39.03,29.91 40.85,28.09
  L03_SIG01 w0.076: v1(40.93,28.09) 40.42,27.58 39.87,27.58 39.6,27.85 39.6,31.46 41.07,32.93 41.07,41.37 41.99,42.29 44.15,42.29 J21.9
  BOTTOM w0.191: R651.2 R646.2 42.33,27.23 41.47,28.09 v1(40.93,28.09)
PD_VIN_3V3: length 1.8
  TOP w0.381: v1(40.86,16.11) 40.63,15.88 C320.2
  BOTTOM w0.203: v1(40.86,16.11) 41.05,16.3 U129.5
PMIC_ADC_IN: length 8.7
  TOP w0.191: TP84.1 38.68,57.92 41.03,57.92 41.64,58.53 44.74,58.53 45.37,59.16 U56.11
PMIC_EN: length 1.3
  TOP w0.191: U56.17 48.37,59.35 48.16,59.14 R317.2
PMIC_ENABLE: length 8.8
  TOP w0.191: v1(28.15,67.91) 28.15,67.35 28,67.2 U54.6 ; v1(29.46,62.74) 29.08,62.36 U57.4
  L03_SIG01 w0.076: v1(28.15,67.91) 28.88,67.18 28.88,64.03 29.46,63.46 v1(29.46,62.74)
PMIC_I2C_SCL: length 4.4
  TOP w0.14: TP72.1 40.56,63.93 41.41,63.93 41.81,64.33 R297.2
  TOP w0.15: U56.1 R297.2
PMIC_I2C_SDA: length 5.1
  TOP w0.14: U56.2 41.95,63.83 41.54,63.42 R307.2 39.66,63.42 TP73.1
PMIC_INT_B: length 11.9
  TOP w0.14: 49.54,65.33 50.33,65.33 50.35,65.35 50.36,65.35 50.82,65.81 55.12,65.81 55.63,65.31 R299.2
  TOP w0.15: U56.27 49.37,65.16 49.54,65.33
  TOP w0.191: R288.2 57.37,65.61 TP70.1 56.6,65.19 56.41,65 R300.2 R299.2
PMIC_INTN: length 40.8
  TOP w0.191: v1(54.45,97.26) 54.07,97.65 U36.2 ; v1(59.41,75.3) 59.42,75.29 59.42,75.02 59.3,74.9 59.3,73.49 59.22,73.4 59.22,66.88 57.63,65.3 57.63,64.68 57.13,64.18 R300.1
  L03_SIG01 w0.076: v1(54.45,97.26) 54.23,97.04 54.23,94.9 53.37,94.04 53.37,90.84 53.76,90.46 53.76,88.1 54.61,87.24 56.85,87.24 58.58,85.52 58.58,82.76 59.03,82.3 59.03,75.69 59.41,75.31 v1(59.41,75.3)
PMIC_INTN_1V8: length 47.7
  TOP w0.132: U47.F17 v1(70.76,84.79)
  TOP w0.191: R205.2 70.96,93.01 v1(71.09,92.88) ; U36.4 51.07,98.6 51.31,98.84 R164.1 52.54,100.19 53.75,98.98 v1(53.75,98.21)
  L03_SIG01 w0.076: v1(71.09,92.88) 72.19,91.78 72.19,87.56 71.98,87.35 71.98,85.48 71.71,85.21 71.18,85.21 v1(70.76,84.79) ; v1(55.33,86.36) 55.05,86.08 53.76,86.08 53.19,86.64 53.19,89.63 52.87,89.95 52.87,97.33 v1(53.75,98.21)
  BOTTOM w0.14: v1(70.76,84.79) 70.36,85.19 68.18,85.19 67.82,85.56
  BOTTOM w0.191: v1(55.33,86.36) 55.84,86.87 66.51,86.87 67.82,85.56
PMIC_LPM_EN0: length 72.2
  TOP w0.132: U47.D12 v1(69.16,80.79)
  TOP w0.191: v1(41.52,60.66) 41.46,60.73 37.57,60.73 36.95,60.1 33.36,60.1 32.5,59.24 32.18,59.24 31.08,59.24 30.25,60.07 TP75.1 29.5,61.86 U57.3 ; U57.8 22.01,61.86 v1(21.46,62.41) 21.45,62.4 R309.1 ; 27.67,61.86 26.51,61.86 25.97,62.4 v1(25.97,62.4)
  TOP w0.203: 27.67,61.86 U57.3
  L03_SIG01 w0.076: v1(41.52,60.66) 41.52,63.23 44.04,65.74 44.04,70.7 44.77,71.44 44.77,73.63 46.6,75.46 50.84,75.46 51.03,75.27 55.03,75.27 55.74,74.56 59.53,74.56 60.14,75.17 60.14,76.3 61.02,77.18 61.86,77.18 62.53,77.84 62.53,80.9 v1(63.41,81.78)
  BOTTOM w0.14: v1(63.41,81.78) 63.47,81.78 63.93,81.32 64.63,81.32 65.57,80.39 68.89,80.39 69.16,80.65 v1(69.16,80.79)
  BOTTOM w0.191: v1(25.97,62.4) 25.96,62.41 v1(21.46,62.41)
PMIC_LPM_SEL: length 6
  TOP w0.191: U57.1 26.69,60.86 26.52,60.69 26.52,60.08 27.11,59.49 R318.1 J16.1
PMIC_NSLEEP: length 29
  TOP w0.191: v1(38.95,58.39) 39.73,58.39 40.26,58.92 44.3,58.92 44.87,59.49 U56.10 ; U57.6 22.35,62.86 22.16,63.05 v1(22.16,63.59)
  BOTTOM w0.191: v1(38.95,58.39) 38.02,59.32 38.02,60.62 34.31,64.33 22.9,64.33 v1(22.16,63.59)
PMIC_POWERGOOD: length 122.3
  TOP w0.191: R290.1 55.09,67.37 55.36,67.64 v1(58.18,67.64)
  L03_SIG01 w0.076: v1(60.9,54.43) 60.9,55.43 59.58,56.75 59.58,60.1 58.77,60.91 58.77,67.04 v1(58.18,67.64) ; v1(104.97,71.38) 105.38,71.78 105.38,77.5 104.34,78.54 104.34,79.32 109.71,84.69 109.71,85.26 109.24,85.74 106.12,85.74 105.49,86.37 105.49,90.56 v1(108.23,93.3)
  BOTTOM w0.191: v1(60.9,54.43) 60.9,51.05 63.51,48.44 84.95,48.44 104.97,68.46 v1(104.97,71.38) ; U86.1 106,104.87 105.86,104.73 105,104.73 104.54,104.27 104.54,98.24 108.23,94.55 v1(108.23,93.3)
PMIC_RSTOUT: length 58.9
  TOP w0.14: R290.2 54.54,66.52 54.16,66.14 50.68,66.14 50.23,65.68 49.36,65.68
  TOP w0.15: 49.36,65.68 49.19,65.51 v1(48.98,65.51) 48.98,65.3 48.87,65.2 U56.28
  TOP w0.191: R290.2 R291.2 56.53,66.52 TP67.1 ; R286.1 38.84,66.72 v1(39.03,66.53)
  L03_SIG01 w0.076: v1(39.03,66.53) 38.39,65.89 38.39,64.93 39.24,64.07 39.24,59.91 40.5,58.65 40.5,49.91 v1(40.53,49.88)
  BOTTOM w0.191: v1(48.98,65.51) 49.72,65.51 50.37,64.86 50.37,63.86 51.11,63.12 51.11,61.14 51.6,60.66 51.6,59.95 54.2,57.35 54.2,56.66 54.64,56.21 54.64,52.4 54.1,51.86 51.09,51.86 49.67,50.44 44.52,50.44 43.96,49.88 v1(40.53,49.88)
PORT1_15W: length 1.1
  TOP w0.191: U71.2 24.67,23.8 R386.1
PORT2_15W: length 1.3
  TOP w0.191: U71.1 R390.1
PORZ_OUT: length 258.1
  TOP w0.191: v1(113.48,46.56) 112.57,47.47 110.47,47.47 109.74,46.74 109.74,45.21 104.82,40.29 104.82,27.94 102.37,25.49 86.63,25.49 v1(86.54,25.59) ; TP101.1 66.2,29.7 65.44,30.47 65.44,32.79 v1(65.36,32.87) ; TP101.1 66.52,29.11 67.01,29.61 R372.1 67.84,29.61 68.11,29.88 U68.3 ; TP101.1 66.2,27.81 66.68,27.34 67.61,27.34 68.12,27.84 R376.2 v1(68.45,27.18) ; U32.12 47.88,103.43 v1(47.88,103.42) ; v1(15.68,166.79) 15.88,166.59 U2.6
  L03_SIG01 w0.076: v1(65.36,32.87) 65.36,35.7 61.62,39.44 61.62,46.55 61.8,46.73 61.8,52.25 59.05,55 59.05,59.37 57.91,60.5 57.91,64.02 53.14,68.79 51.88,68.79 50.2,70.48 50.2,73.76 v1(50.35,73.91) ; v1(15.68,166.79) 20.52,161.95 20.52,156.34 19.91,155.74 19.91,152.45 23.89,148.47 23.89,143.68 14.95,134.74 14.95,129.65 v1(15.41,129.19) ; v1(43.21,77.61) 43.21,77.61 43.29,77.69 43.29,78.77 44.12,79.6 47.54,79.6 48.48,80.55 48.48,91.34 47.03,92.79 47.03,94.43 47.44,94.83 47.44,95.26 46.52,96.18 46.52,101.55 47.88,102.91 v1(47.88,103.42)
  BOTTOM w0.191: U120.3 113.47,46.65 113.48,46.63 v1(113.48,46.56) ; v1(47.88,103.42) 44.63,106.68 34.41,106.68 24.26,116.83 24.26,119.81 20.31,123.76 20.31,125.47 17.72,128.05 16.55,128.05 v1(15.41,129.19) ; v1(86.54,25.59) 86.44,25.49 70.03,25.49 68.45,27.08 v1(68.45,27.18) ; v1(43.21,77.61) 43.21,77.61 43.23,77.64 43.97,77.64 44.23,77.37 44.23,75.78 46.1,73.91 v1(50.35,73.91)
PORZ_OUT_1V8: length 185.5
  TOP w0.132: U47.F18 v1(70.76,85.59)
  TOP w0.191: v1(38.8,103.06) 39.22,103.06 39.59,103.43 U32.3 ; J13.1 v1(122.2,136.35) ; J12.1 24.39,101.16 v1(25.2,101.97)
  L03_SIG01 w0.076: v1(70.76,85.59) 70.78,85.59 71.14,85.95 71.14,87.4 70.9,87.62 70.6,87.62 70.34,87.88 70.34,90.5 66.15,94.69 66.15,96.57 v1(64.33,98.39) ; v1(25.2,101.97) 24.25,102.92 24.25,105.17 26.98,107.9 26.98,116.34 v1(33.94,123.3)
  BOTTOM w0.191: v1(64.33,98.39) 64.1,98.61 55.48,98.61 54.38,99.71 49.08,99.71 48.14,100.65 43.97,100.65 41.61,103.02 38.84,103.02 v1(38.8,103.06) 26.69,103.06 25.61,101.97 v1(25.2,101.97) ; v1(33.94,123.3) 34.96,124.31 43.56,124.31 45.08,122.78 63.51,122.78 65.33,124.61 70.58,124.61 73.5,127.52 92.36,127.52 92.82,127.06 94.65,127.06 99.85,132.27 118.12,132.27 v1(122.2,136.35)
PP1_CABLE: length 1.7
  TOP w0.191: v1(35.77,21.77) 35.77,21.69 35.88,21.58 C309.1
  BOTTOM w0.191: v1(35.77,21.77) 35.79,21.78 U129.25
PP2_CABLE: length 3.3
  BOTTOM w0.14: R665.2 C631.1 44.73,21.7 44.19,21.7 44.11,21.78 U129.46
PRI/SEC_REF_SEL: length 3.1
  TOP w0.191: U15.4 117.22,149.53 116.46,150.29 R75.2 R76.1
RES_LM5141: length 2
  BOTTOM w0.191: U128.24 17.31,23.2 16.35,24.17 C626.1
RESETSTATZ: length 417.8
  TOP w0.191: v1(102.15,137.73) 104.57,137.73 105.63,138.79 U21.28 ; v1(72.41,34.06) 71.44,34.06 70.41,33.03 R366.1 70.81,30.98 70.91,30.88 R365.1 71.7,30.88 71.86,30.72 TP100.1 71.86,28.68 71.02,27.84 R377.2 ; U2.3 16.88,165.23 17.15,164.96 v1(17.15,164.13) ; U14.2 94.93,149.82 95.54,149.21 95.54,146.22 v1(89.75,140.42) ; U26.2 61.48,125.55 61.21,125.27 v1(60.65,125.27) ; v1(57.12,169.85) 55.99,168.72 55.99,161.15 56.93,160.2 56.93,159.06 55.87,158 55.87,153.53 54.9,152.55 52.88,152.55 52.66,152.33 U13.2 52.66,145.33 53.28,144.71 v1(53.28,143.24) 52.89,142.85 v1(52.89,123.77) ; U27.2 v1(98.67,120.54) ; v1(110.33,49.67) 109.51,50.49 109.51,53.24 109.51,53.25 109.51,53.62 109.51,53.63 109.51,78.12 105.14,82.49 100.9,82.49 98.15,85.23 98.15,92.34 99.61,93.79 99.61,100.63 98.98,101.27 98.98,103.84 100.2,105.06 100.82,105.06 101.31,105.54 101.31,106.78 v1(101.12,106.97) ; U18.24 85,143.47 85.57,142.91 85.57,141.27 v1(85.53,141.24) ; v1(45.3,123.67) 45.3,123.25 45.22,123.17 45.22,104.47 45.61,104.08 U32.13
  L03_SIG01 w0.076: v1(98.67,120.54) 98.67,137.76 v1(98.22,138.21) ; v1(53.28,143.24) 53.28,160.34 51.78,161.84 v1(49.18,161.84) ; v1(104.7,120.37) 105.14,119.93 105.14,115.56 104.4,114.82 104.4,110.21 101.16,106.97 v1(101.12,106.97)
  BOTTOM w0.191: v1(17.15,164.13) 32.7,164.13 34.99,161.84 39.57,161.84 v1(49.18,161.84) ; v1(72.41,34.06) 72.74,34.06 72.91,33.89 74.02,33.89 75.33,32.58 79.23,32.58 80.71,34.06 80.71,35.12 81.23,35.65 81.23,41.8 81.6,42.17 85.85,42.17 86.82,43.14 88.56,43.14 90.18,44.76 90.18,45.22 92.2,47.24 93.25,47.24 94.92,48.92 109.25,48.92 110.01,48.15 R605.1 111.45,49.01 110.79,49.67 v1(110.33,49.67) ; v1(98.67,120.54) 99.11,120.98 104.08,120.98 v1(104.7,120.37) ; U75.2 80.51,172.02 80.12,171.62 80.12,170.5 79.82,170.2 77.18,170.2 74.72,167.75 61.43,167.75 59.33,169.85 v1(57.12,169.85) ; v1(102.15,137.73) 98.71,137.73 v1(98.22,138.21) 97.6,138.83 91.34,138.83 v1(89.75,140.42) 88.07,140.42 86.84,141.66 85.95,141.66 v1(85.53,141.24) 84.64,140.35 74.86,140.35 74.09,141.13 68.55,141.13 67.1,142.58 65.25,142.58 64.8,142.13 54.39,142.13 v1(53.28,143.24) ; v1(60.65,125.27) 59.15,123.77 v1(52.89,123.77) 45.4,123.77 v1(45.3,123.67)
RESETSTATZ_1V8: length 246.6
  TOP w0.132: U47.F19 v1(70.76,86.39)
  TOP w0.191: v1(112.77,158.15) 112.75,158.14 112.75,148.21 113.81,147.15 114.45,147.15 115.03,147.73 U15.8 ; v1(57.64,159.46) 57.44,159.26 57.44,144.06 59.46,142.05 59.46,124.3 62.42,121.33 v1(62.42,113.69) 61.97,113.69 60.5,115.15 48.95,115.15 48.76,114.96 48.76,112.83 v1(48.77,112.82) 48.83,112.76 49.1,112.76 50.86,114.52 51.72,114.52 53.12,113.12 53.12,112.27 54.34,111.05 57.57,111.05 59.23,109.39 65.83,109.39 66.66,108.56 66.66,105.21 67.27,104.6 73.98,104.6 74.43,105.06 76.89,105.06 79.29,107.46 83.25,107.46 v1(83.33,107.54) ; U32.2 41.98,104.08 42.28,104.38 42.28,111.5 v1(43.61,112.83)
  L03_SIG01 w0.076: v1(70.76,86.39) 70.34,86.81 70.34,87.35 69.54,88.15 69.54,90.51 64.2,95.85 64.2,97.96 63.94,98.22 63.94,100.11 66.16,102.34 66.16,103.17 66.01,103.32 62.79,103.32 62.13,103.98 62.13,113.4 v1(62.42,113.69)
  BOTTOM w0.191: v1(57.64,159.46) 57.65,159.45 64.34,159.45 66.54,161.65 66.86,161.65 68.58,161.65 70.17,163.25 70.17,165.18 71.35,166.35 79.51,166.35 81.62,164.25 84.23,164.25 84.99,163.48 85.31,163.48 89.17,163.48 89.49,163.48 89.81,163.48 91.63,163.48 94.05,165.91 94.05,166.96 94.7,167.62 99.32,167.62 100.93,166 101.76,166 103.71,164.05 103.71,160.25 105.42,158.54 109.3,158.54 109.59,158.83 109.59,159.4 110.43,160.24 111.42,160.24 112.77,158.89 v1(112.77,158.15) ; v1(62.42,113.69) 62.54,113.69 63.29,112.93 U85.3 ; v1(48.77,112.82) 48.34,112.82 48.33,112.83 v1(43.61,112.83) ; U84.11 v1(83.33,107.54)
RGMII1_INH: length 112.5
  TOP w0.191: v1(88.5,44.8) 88.42,44.72 R353.2 87.64,44.35 88.01,43.98 J18.26 ; v1(24.81,66.16) 24.73,66.24 TP65.1 U52.3
  L03_SIG01 w0.076: v1(26.15,36.24) 26.15,37.46 24.81,38.8 v1(24.81,66.16)
  BOTTOM w0.191: v1(88.5,44.8) 87.65,44.8 87.16,44.31 84.65,44.31 83.4,43.05 80.96,43.05 80.42,42.51 80.42,37.92 78.18,35.68 76.13,35.68 73.34,38.47 66.28,38.47 61.23,33.42 52.68,33.42 51.86,32.6 48.03,32.6 47.55,32.12 42.13,32.12 39.3,34.95 36.52,34.95 36.06,34.49 33.97,34.49 33.7,34.76 33.7,36.46 32.85,37.31 28.94,37.31 27.87,36.24 v1(26.15,36.24)
RGMII1_RX_ER: length 23.3
  TOP w0.191: v1(84.63,33.62) 80.86,33.62 80.54,33.95 73,33.95 72.29,33.23 TP99.1 ; v1(90,36.85) 90.41,37.26 90.41,38.38 90.81,38.79 J18.39
  BOTTOM w0.191: v1(90,36.85) 89.82,36.67 89.61,36.67 89.03,36.09 87.1,36.09 v1(84.63,33.62)
RGMII1_RX_LINK: length 23.1
  TOP w0.191: J18.43 91.61,37.99 v1(90.96,37.35) ; v1(81.21,34.9) 75.78,34.9 74.2,36.48 R360.2 73.28,36.02 TP98.1
  BOTTOM w0.191: v1(81.21,34.9) 83.65,37.35 v1(90.96,37.35)
RGMII2_INH: length 152.8
  TOP w0.191: J19.26 120.44,43.2 121.02,43.78 R354.2 120.39,44.71 120.16,44.48 v1(120.16,44.12) ; U52.6 25.8,69.14 26.48,69.82 TP59.1 v1(28.4,69.82)
  L03_SIG01 w0.076: v1(28.4,69.82) 28.4,68.88 26.91,67.38 26.91,38.49 27.72,37.68 v1(27.72,37.03)
  BOTTOM w0.191: v1(27.72,37.03) 27.72,37.05 28.47,37.8 32.99,37.8 34.17,36.61 34.17,35.18 34.36,34.99 35.88,34.99 37.07,36.17 38.73,36.17 40.61,34.29 49.78,34.29 50.3,33.77 51.76,33.77 52.19,34.19 60.49,34.19 65.13,38.83 73.57,38.83 76.05,36.35 78.24,36.35 80.03,38.13 80.03,42.77 80.69,43.43 82.93,43.43 84.81,45.31 87.54,45.31 90.45,48.23 92.45,48.23 95.21,50.98 114.58,50.98 120.16,45.4 v1(120.16,44.12)
RGMII2_RX_ER: length 18.4
  TOP w0.191: v1(128.33,47.27) 127.63,47.27 TP89.1 ; v1(122.98,36.41) 123.24,36.67 J19.39
  L03_SIG01 w0.076: v1(122.98,36.41) 123.38,36.81 125.19,36.81 126.96,38.58 126.96,45.89 v1(128.33,47.27)
RGMII2_RX_LINK: length 20.3
  TOP w0.191: J19.43 124.04,38.78 123.78,38.53 v1(123.78,36.4) ; TP91.1 126.31,46.37 v1(128.24,46.37)
  L03_SIG01 w0.076: v1(128.24,46.37) 128.87,45.73 128.87,38.86 126.41,36.4 v1(123.78,36.4)
  BOTTOM w0.191: R347.2 128.41,46.2 v1(128.24,46.37)
RT_LM5141: length 1.7
  BOTTOM w0.191: R648.1 19.91,23.86 U128.4
RXCKI: length 4
  TOP w0.191: U3.13 42.01,160.67 41.69,160.36 40.03,160.36 39.75,160.07 R39.2
RXCKI_OSC: length 1.1
  TOP w0.191: R39.1 39.75,158.99 U9.3
SEC_REF_N: length 2.1
  TOP w0.191: U15.2 R74.1
SEC_REF_P: length 2.3
  TOP w0.191: R73.1 119.19,150.17 118.72,149.69 U15.1
SEL_XDS: length 52.7
  TOP w0.191: v1(112.08,86.71) 111.77,87.02 111.77,90.02 110.78,91.01 104.07,91.01 103.88,91.2 U39.5
  L03_SIG01 w0.076: v1(115.86,82.27) 115.86,82.05 118.11,79.81 118.11,71.45 119.07,70.48 120.29,70.48 v1(120.53,70.71) 121.03,71.22 122.16,71.22 122.32,71.06 123.34,71.06 125.22,72.94 125.22,74.35 124.1,75.47 124.1,76.36 123.67,76.79 123.67,79.83 v1(122.91,80.6) ; v1(112.08,86.71) 113.4,85.39 v1(113.4,84.14)
  BOTTOM w0.14: v1(120.53,70.71) 120.37,70.87 120.37,71.13 119.91,71.58 119.91,71.97 120.16,72.22 U109.4
  BOTTOM w0.191: U97.1 121.9,80.89 122.19,80.6 v1(122.91,80.6) 122.91,81.09 122.73,81.27 U97.16 ; v1(113.4,84.14) 114.98,84.14 115.15,83.96 115.58,83.96 115.77,83.76 U93.4 115.77,82.36 v1(115.86,82.27)
SEL_XDS110_INV: length 69.1
  TOP w0.191: v1(115.64,104.12) 115.64,104.51 114.75,105.4 113.6,105.4 112.91,104.71 110.86,104.71 v1(110.69,104.88) ; J14.8 112.71,94.16 v1(112.74,94.13)
  L03_SIG01 w0.076: v1(112.74,94.13) 112.74,90.95 116.08,87.61 v1(116.08,84.37) 118.37,82.08 118.37,74.51 120.1,72.77 121.41,72.77 122.34,71.84 v1(123.51,71.84) 123.87,71.84 125.04,73.01 125.04,74.16 123.92,75.28 123.92,76.28 123.32,76.88 123.32,78.17 v1(122.93,78.57)
  BOTTOM w0.14: U110.1 123.64,72.46 123.38,72.2 123.38,71.97 v1(123.51,71.84) 123.51,71.37 123.65,71.23 123.87,71.23 124.05,71.42 U110.16 ; v1(122.93,78.57) 122.79,78.44 U102.5
  BOTTOM w0.191: U90.4 113.15,95.69 112.74,95.29 v1(112.74,94.13) 112.66,94.2 112.29,94.2 111.87,94.62 111.87,96.78 109.63,99.03 109.63,103.92 110.58,104.88 v1(110.69,104.88) 111.12,104.88 111.31,104.69 U87.2 ; U93.2 115.12,84.59 115.34,84.37 v1(116.08,84.37) 116.08,84.14 116.33,83.89 R536.1 R531.2 ; v1(115.64,104.12) 115.64,103.36 115.79,103.21 U88.2
SIL5351B_VC: length 15.2
  TOP w0.191: TP43.1 78.18,134.16 C139.1 ; TP43.1 78.27,134.25 R113.2 79.96,134.79 79.78,134.97 R110.2 ; TP43.1 76.46,134.19 75.67,134.98 75.67,139.69 75,140.36 74.36,140.36 73.69,141.03 U20.3
SOC_CLKIN: length 81.5
  TOP w0.14: v1(58.11,84.55) 58.09,84.53 58.09,83.58 59.07,82.6 R249.1
  TOP w0.191: R349.2 68.95,46.6 v1(68.49,46.14)
  L03_SIG01 w0.076: v1(51.91,73.93) 51.96,73.93 54.53,71.36 59.36,71.36 60.22,70.5 60.22,63.93 59.05,62.76 59.05,61.23 59.85,60.43 59.85,57.29 61.15,55.99 61.15,55.12 62.25,54.02 62.25,46.5 62.08,46.32 62.08,43.13 64.3,40.9 64.3,38.65 65.14,37.82 69.96,37.82 72.2,40.06 72.2,41.16 68.49,44.88 v1(68.49,46.14) ; v1(50.49,77.68) 50.49,79 51.27,79.78 52.55,79.78 53.87,81.1 54.66,81.1 v1(58.11,84.55)
  BOTTOM w0.191: v1(51.91,73.93) 51.91,74.42 50.49,75.83 v1(50.49,77.68)
SOC_DVDD1V8: length 78.8
  TOP w0.254: U56.24 v1(50.49,62.83)
  TOP w0.305: v1(57.32,85.63) 57.27,85.58 57.27,85.11 C196.3 57.31,84.43 v1(57.3,84.42) 57.3,83.71 C200.1 ; v1(55.79,85.77) 55.63,85.61 55.63,85.15 C196.1
  TOP w0.356: U47.N15 v1(77.16,83.19) ; U47.H13 v1(72.36,81.59) ; U47.U8 v1(80.36,76.79) ; U47.L15 v1(74.76,83.19) ; U47.H17 v1(72.36,84.79) ; U47.H16 v1(72.36,83.99) ; U47.F12 v1(70.76,80.79) ; U47.M15 v1(76.36,83.19) ; U47.K15 v1(73.96,83.19) ; U47.G14 v1(71.56,82.39) ; U47.T8 v1(79.56,76.79) ; U47.L16 v1(74.76,83.99)
  L03_SIG01 w0.102: v1(76.36,83.19) 76.32,83.19 75.61,82.48 75.61,82.38 75.16,81.92 75.16,81.44 74.9,81.18 74.6,81.18 74.35,80.94 74.35,80.64 73.55,79.83 64.83,79.83 64.33,79.33 64.33,78.37 63.1,77.15 62.36,77.15 62.23,77.02 62.02,76.81 61.46,76.81 61.15,76.49 61.15,74.69 60.6,74.15 55.88,74.15 55.09,74.94 49.98,74.94 46.62,71.59 46.62,69.1 44.87,67.34 44.87,65.65 43.96,64.73 43.96,62.97 43.31,62.32 43.16,62.32 42.84,62 42.84,61.66 43.08,61.43 44.01,61.43 44.36,61.77 45.82,61.77 46.1,61.49 47.63,61.49 47.93,61.79 49.45,61.79 v1(50.49,62.83)
  L05_SIG02 w0.152: 69.63,82.07 69.57,82 69.57,81.4 69.76,81.2 70.35,81.2 70.37,81.21 70.37,82.02 70.29,82.09
  L05_SIG02 w0.279: v1(70.76,80.79) 70.35,81.2
  L05_SIG02 w0.305: v1(71.56,82.39) v1(72.36,81.59) 72.78,82.02
  BOTTOM w0.254: C422.3 55.79,85.49 v1(55.79,85.77) ; C429.1 75.17,84.49 C437.1 ; C422.1 57.27,85.54 57.27,85.58 v1(57.32,85.63)
  BOTTOM w0.305: C506.1 v1(80.36,76.79) ; C426.1 72.38,84.81 v1(72.36,84.79) ; C440.1 77.29,83.19 v1(77.16,83.19) ; v1(79.56,76.79) 79.7,76.93 C502.1 ; v1(74.76,83.19) 74.8,83.15 C444.1 ; C453.1 v1(71.56,82.39) ; C457.1 70.65,80.79 v1(70.76,80.79) ; C437.1 74.76,83.99 v1(74.76,83.99) ; C433.1 v1(72.36,83.99) ; C461.1 v1(72.36,81.59)
  BOTTOM w0.381: v1(74.76,83.99) v1(73.96,83.19)
  vias: v1(41.11,49.06) v1(41.11,48.15) v1(42.03,49.06) v1(42.03,48.15) v1(42.94,49.06) v1(42.94,48.15) v1(66.58,50.92) v1(66.6,50.29) v1(67.21,50.93) v1(67.26,50.32)
SOC_DVDD1V8_N: length 11.7
  TOP w0.191: R335.1 49.46,49.02 49.85,49.41 50.12,49.41 50.31,49.22 50.31,48.78 49.85,48.32 48.65,48.32 v1(48.12,47.79)
  BOTTOM w0.191: 48.09,46.29 48.12,46.32 C603.2 v1(48.12,47.79) ; 48.09,46.29 47.86,46.06 U124.8 47.86,44.35 47.46,43.95 U123.D1 ; 48.09,46.29 48.36,46.02 U124.9 48.36,44.31 47.86,43.81 U123.D2
SOC_DVDD1V8_P: length 9
  TOP w0.191: v1(49.1,47.8) 49.97,47.8 50.69,48.52 50.69,49.5 50.32,49.87 49.88,49.87 R331.1
  BOTTOM w0.191: U123.D3 48.26,43.62 48.86,44.22 U124.10 48.86,46.17 49.1,46.41 C603.1 v1(49.1,47.8)
SOC_DVDD3V3: length 10.2
  TOP w0.254: C210.3 v1(52.42,80.8) ; C210.1 v1(52.42,77.91)
  TOP w0.356: U47.T13 v1(79.56,81.59) ; U47.H10 v1(72.36,78.39) ; U47.U13 v1(80.36,81.59) ; U47.G11 v1(71.56,79.19) ; U47.R13 v1(78.76,81.59) ; U47.U10 v1(80.36,78.39) ; U47.F9 v1(70.76,77.59)
  L05_SIG02 w0.254: 70.39,77.96 v1(70.76,77.59) 71.13,77.96
  BOTTOM w0.254: C450.1 75.63,81.66 v1(75.56,81.59) ; C476.1 51.66,80.13 51.57,80.22 v1(51.53,80.22)
  BOTTOM w0.305: C452.1 78.88,81.71 v1(78.76,81.59) ; C458.1 v1(79.56,81.59) ; v1(70.76,77.59) 70.76,77.83 C496.1 ; C471.1 72.04,79.59 C482.1 71.66,79.3 v1(71.56,79.19) ; C482.3 72.46,78.5 v1(72.36,78.39) ; C492.1 80.55,78.2 v1(80.36,78.39) ; v1(80.36,81.59) 80.48,81.71 C451.1
  vias: v1(51.61,78.51) v1(51.6,77.55)
SOC_DVDD3V3_N: length 6.6
  BOTTOM w0.191: U92.D1 U92.D2 50.09,88.41 50.09,88.1 49.91,87.92 ; 49.91,87.92 50.11,87.72 U91.8 ; 49.91,87.92 49.91,87.8 49.61,87.5 U91.9 49.61,85.87 49.85,85.63 C428.2 49.93,84.92 R539.1
SOC_DVDD3V3_P: length 5.1
  BOTTOM w0.191: U92.D3 49.71,88.26 49.11,87.66 U91.10 49.11,85.92 48.87,85.68 C428.1 48.79,84.92 R540.1
SOC_EMU0: length 87.3
  TOP w0.132: U47.C13 v1(68.36,81.59)
  TOP w0.191: R225.2 v1(103.18,87.59) ; R225.2 103.18,88.26 U39.2 ; R225.2 101.63,88.26 101.08,88.81 101.08,89.79 100.77,90.1 SW3.1
  L03_SIG01 w0.076: v1(68.36,81.59) 68.74,81.21 70.11,81.21 70.34,81.44 70.34,81.88 70.43,81.98 70.84,81.98 70.88,82.02 70.91,82.02 71.18,82.28 71.18,82.55 71.19,82.55 71.19,82.73 71.26,82.8 71.46,82.8 71.48,82.82 71.71,82.82 71.94,83.04 71.94,83.32 72.03,83.41 72.05,83.41 72.24,83.61 73.33,83.61 73.55,83.82 73.55,84.19 73.76,84.4 74.95,84.4 75.6,85.05 75.6,85.06 75.63,85.08 75.63,85.1 75.79,85.26 75.79,86.42 75.97,86.61 75.97,88.13 81.23,93.39 90.87,93.39 91.2,93.39 92.45,94.64 92.45,94.98 93.1,95.63 97.62,95.63 99.73,97.74 102.64,97.74 103.78,96.6 103.78,90.57 104.29,90.07 104.29,88.7 v1(103.18,87.59)
  BOTTOM w0.191: v1(103.18,87.59) 103.18,87.34 114.81,75.71 119.01,75.71 121.04,77.74 U102.2
SOC_EMU1: length 78.6
  TOP w0.132: U47.E10 v1(69.96,78.39)
  TOP w0.191: U39.3 103.53,89.88 v1(103.77,89.64) 104.23,89.64 104.42,89.45 R220.2 ; v1(101.18,91.29) 101.1,91.37 SW3.2
  L03_SIG01 w0.076: v1(69.96,78.39) 69.96,78.4 70.35,78.8 72.49,78.8 72.51,78.82 72.51,78.82 72.78,79.08 72.78,79.48 72.87,79.57 74.12,79.57 75.95,81.4 75.95,82.55 76.17,82.77 80.55,82.77 80.74,82.96 80.74,84.12 81.01,84.39 81.37,84.39 81.58,84.6 81.58,85.86 81.74,86.01 82.12,86.01 82.37,86.26 82.37,87.71 83.42,88.77 84.51,88.77 84.69,88.59 86.74,88.59 88.83,90.69 94.62,90.69 99.74,95.81 100.9,95.81 101.18,95.52 v1(101.18,91.29)
  BOTTOM w0.191: U102.3 120.78,78.09 119.1,76.41 118.49,76.41 116.93,77.97 113.28,77.97 103.77,87.48 v1(103.77,89.64) 103.77,90.48 102.96,91.29 v1(101.18,91.29)
SOC_GPIO1_49: length 246.6
  TOP w0.132: U47.D18 v1(69.16,85.59)
  TOP w0.191: v1(117.67,158.8) 116.66,158.8 115.7,159.75 113.07,159.75 111.73,161.1 111.73,166.22 110.47,167.47 105.76,167.47 104.38,168.85 v1(104.38,169.53) ; R213.1 123.63,93.05 123.63,93.96 126.46,96.79 130.94,96.79 131.13,96.98 131.13,116.67 130.97,116.83 130.93,116.83 129.93,117.82 129.93,119.67 v1(130.41,120.16) ; v1(57.26,168.8) 56.57,168.11 56.57,165.39 v1(56.84,165.12)
  L03_SIG01 w0.076: v1(60.38,91.78) 60.24,91.93 60.24,97.67 56.35,101.56 56.35,102.26 56.8,102.71 56.8,107.04 57.45,107.69 57.45,108.13 56.8,108.78 56.8,116.02 56.52,116.3 56.52,121.44 55.61,122.35 55.61,157.26 57.11,158.76 57.11,164.84 v1(56.84,165.12)
  BOTTOM w0.14: 67.83,86.27 68.11,85.99 68.76,85.99 v1(69.16,85.59)
  BOTTOM w0.191: v1(104.38,169.53) 103.03,170.88 96.54,170.88 93.29,167.63 93.29,166.22 91.31,164.25 85.31,164.25 84.55,165.01 83.69,165.01 81.34,167.36 60.42,167.36 58.98,168.8 v1(57.26,168.8) ; v1(130.41,120.16) 130.74,120.48 130.74,135.51 123.43,142.82 123.43,153.04 v1(117.67,158.8) ; v1(60.38,91.78) 60.38,90.61 63.62,87.38 66.72,87.38 67.83,86.27
SOC_I2C0_SCL: length 340.2
  TOP w0.191: U18.19 82.5,143.47 82.3,143.26 82.03,143.26 v1(81.61,143.68) ; U44.1 v1(93.03,83.46) 93.03,78.66 91.65,77.29 91.65,74.83 91.16,74.34 91.16,59.43 v1(95.07,55.51) ; J18.40 90.81,41.34 v1(91.04,41.11) ; J19.40 123.24,41.67 v1(124.48,40.43) ; R332.1 74.29,48.79 73.51,48.01 73.51,47.35 v1(73.44,47.28) ; U22.9 78.52,141.78 v1(78.04,142.26) ; U11.8 130.85,154.85 131.25,155.26 R56.2 131.25,157 131.24,157.01 131.24,157.34 v1(130.39,158.18) ; U21.29 106.13,138.6 v1(105.79,138.26) 105.59,138.06 105.59,132.36 107.8,130.15 110.2,130.15 110.49,130.45 U25.2 ; v1(81.36,116.13) 80.19,114.97 79.75,114.97 78.3,113.52 78.3,111.43 77.86,110.99 74.02,110.99 73.68,110.65 68.03,110.65 67.64,111.03 60.08,111.03 59.04,112.07 v1(54.17,112.07) ; v1(76.58,141.76) 75.69,140.88 74.75,140.88 74.19,141.43 U20.4
  L03_SIG01 w0.076: v1(81.36,116.13) 82.77,116.13 84.4,117.77 84.4,122.33 78.34,128.4 78.34,138.25 77.72,138.87 77.72,141.94 v1(78.04,142.26) ; v1(95.07,55.51) 94.3,54.74 94.3,43.43 92.87,41.99 91.92,41.99 v1(91.04,41.11) 91.04,40.16 90.85,39.98 83.41,39.98 83.07,40.32 83.07,42.17 83.8,42.91 83.8,46.26 v1(83.32,46.75) ; v1(105.79,138.26) 105.87,138.26 107.39,139.78 121.46,139.78 123.1,141.42 123.1,147.59 129.96,154.44 129.96,157.15 130.39,157.59 v1(130.39,158.18)
  L05_SIG02 w0.102: v1(81.36,116.13) 81.38,116.16 84.88,116.16 92.83,108.21 92.83,107.36 90.29,104.82 90.29,102.35 92.51,100.13 92.51,85.33 93.03,84.81 v1(93.03,83.46)
  BOTTOM w0.191: U85.43 60.78,108.65 60.49,108.95 60.21,108.95 60.2,108.95 59.95,108.95 59.45,109.45 56.47,109.45 54.17,111.75 v1(54.17,112.07) ; v1(105.79,138.26) 104.97,138.26 103.43,139.79 103.43,143.91 102.81,144.54 85.5,144.54 85.14,144.17 82.1,144.17 v1(81.61,143.68) 80.41,143.68 79.29,142.57 78.35,142.57 v1(78.04,142.26) 77.08,142.26 v1(76.58,141.76) ; v1(81.36,116.13) 81.35,115.89 80.71,115.24 79.54,115.24 78.7,114.39 U84.43 ; v1(91.04,41.11) 91.26,41.34 91.76,41.34 92.86,40.24 92.86,38.11 93.15,37.81 98.4,37.81 101.73,34.49 120.22,34.49 123,37.27 123.6,37.27 123.87,37.54 R625.1 R622.2 124.27,39.53 124.48,39.74 v1(124.48,40.43) ; v1(83.32,46.75) 83.23,46.75 82.74,47.24 78.64,47.24 78.06,46.66 74.06,46.66 v1(73.44,47.28)
SOC_I2C0_SCL_1V8: length 209.4
  TOP w0.145: R51.2 v1(46.8,156.54) ; v1(116.61,160.93) 116.61,161.34 116.91,161.64 U6.7
  TOP w0.191: v1(114.53,145.4) 115.05,145.4 115.39,145.73 U15.12 ; R195.2 46.74,95.71 47.01,95.43 v1(47.01,95.09) ; U5.7 99.51,161.64 99.21,161.34 v1(99.21,160.93) 99.21,159.16 99.88,158.5 101.24,158.5 102.21,159.46 105.36,159.46 105.93,158.89 108.44,158.89 v1(110.81,161.25) ; U11.5 129.35,153.35 128.86,153.84 128.86,157.74 128.46,158.15 v1(127.82,158.15) 127.82,159.26 128.02,159.45 v1(129.07,159.45) ; v1(78.2,162.67) 78.61,162.26 U7.25 ; U8.25 71.89,157.13 72.93,156.09 73.07,156.09 73.07,156.08 74.02,156.08 74.46,155.64 74.46,154.26 73.73,153.53 v1(72.8,153.53)
  L03_SIG01 w0.076: v1(47.01,95.09) 47.01,95.09 46.34,95.76 46.34,156.08 v1(46.8,156.54) ; v1(116.61,160.93) 114.53,158.85 v1(114.53,145.4) ; v1(78.2,162.67) 77.32,163.54 77.32,165.46 76.78,166 74.28,166 73.51,165.22 73.51,160.69 72.22,159.41 72.22,154.11 v1(72.8,153.53)
  BOTTOM w0.191: U76.7 127.43,161.49 129.07,159.85 v1(129.07,159.45) ; v1(78.2,162.67) 78.26,162.6 83.77,162.6 85.05,161.32 98.21,161.32 98.6,160.93 v1(99.21,160.93) ; U77.7 110.03,161.54 110.32,161.25 v1(110.81,161.25) 111.05,161.01 112.01,161.01 112.83,160.19 114.66,160.19 115.4,160.93 v1(116.61,160.93) 118.61,160.93 121.37,158.17 127.8,158.17 v1(127.82,158.15) ; v1(46.8,156.54) 46.82,156.54 47.44,157.16 49.94,157.16 50.28,156.81 51.63,156.81 52.26,156.81 53.25,156.81 56.86,153.21 72.47,153.21 v1(72.8,153.53)
SOC_I2C0_SCL_R1: length 201.9
  TOP w0.191: v1(53.96,40.22) 54.79,41.06 54.79,41.83 56.61,43.66 v1(57.06,43.66) ; v1(67.22,47.5) TP88.1 69.23,50.11 70.01,50.11 70.56,49.56 71.55,49.56 72.43,49.56 72.76,49.89 U63.1 72.78,50.76 R332.2 ; v1(51.29,92.45) 50.88,92.04 48.46,92.04 v1(48.29,92.21) ; U70.6 45.48,25.63 45.25,25.41 44.38,25.41 v1(44.18,25.6)
  L03_SIG01 w0.076: v1(61.22,47.99) 61.22,47.67 57.21,43.66 v1(57.06,43.66) 56.26,44.46 56.26,55.54 v1(55.19,56.61) ; v1(33.54,89.43) 33.54,66.46 v1(34.15,65.86) 34.15,63.23 36.67,60.71 36.67,56.84 36.99,56.52 36.99,51.63 36.78,51.42 36.78,39.92 38.66,38.03 38.66,32.45 37.71,31.49 37.71,27.12 v1(38.06,26.77) 38.04,26.75 38.04,26.12 38.69,25.47 44.04,25.47 v1(44.18,25.6) 45.07,26.49 46.53,26.49 47.24,27.2 47.24,38.87 v1(46.86,39.25) 47.93,39.25 48.28,38.9 53.3,38.9 53.96,39.56 v1(53.96,40.22) 53.36,40.82 52.21,40.82 v1(51.62,40.23)
  BOTTOM w0.191: 49.63,88.83 49.59,88.83 49.58,88.82 49.58,88.78 ; 49.63,88.83 U92.C3 ; 49.63,88.83 49.58,88.78 ; 55.06,55.78 55.06,56.15 ; 55.06,55.78 U116.5 ; 55.06,55.78 55.09,55.81 55.09,56.12 55.06,56.15 ; 55.06,56.15 55.06,56.49 v1(55.19,56.61) 55.52,56.95 U115.A1 ; R657.1 37.76,26.47 v1(38.06,26.77) ; v1(53.96,40.22) 53.72,40.47 U122.2 ; v1(61.22,47.99) 61.71,47.5 v1(67.22,47.5) ; v1(61.22,47.99) 61.02,47.78 59.81,47.78 59.69,47.66 U118.1 ; v1(61.22,47.99) 60.07,49.14 U119.C3 ; U113.A1 36.13,66.73 U114.5 36.13,65.13 35.94,64.93 34.36,64.93 34.15,65.15 v1(34.15,65.86) ; U123.A1 47.46,42.22 46.86,41.62 U124.5 v1(46.86,39.25) ; v1(51.29,92.45) 51.11,92.27 U91.5 51.11,90 50.74,89.63 U92.A1 ; 49.58,88.78 49.31,88.51 48.94,88.51 48.68,88.78 48.68,89.68 49.11,90.11 U91.1 49.11,92.02 48.92,92.21 v1(48.29,92.21) 46.99,90.92 40.39,90.92 40.22,91.09 36.52,91.09 34.86,89.43 v1(33.54,89.43) ; v1(51.62,40.23) 52.22,40.83 U122.5 52.22,42.76 52.82,43.36 U121.A1 ; U121.B3 56.91,43.81 v1(57.06,43.66) 57.69,44.28 U118.5 57.69,47.75 58.28,48.34 U119.A1
SOC_I2C0_SDA: length 366.9
  TOP w0.191: v1(96.64,52.07) 103.14,52.07 107.61,56.54 107.61,76.85 104.14,80.32 96.76,80.32 95.54,81.54 95.54,85.31 95.16,85.7 93.36,85.7 v1(93.03,86.03) U44.6 ; U18.20 83,143.18 82.81,142.99 82.64,142.99 82.43,142.78 81.77,142.78 v1(81.61,142.94) ; J19.42 123.64,41.88 123.83,41.69 124.35,41.69 v1(124.71,41.33) ; v1(80.54,116.23) 80.54,115.85 80.05,115.36 80.04,115.36 80.03,115.35 79.59,115.35 77.12,112.88 77.12,111.5 76.93,111.31 73.93,111.31 73.61,110.99 68.1,110.99 67.76,111.32 67.61,111.32 67.56,111.37 60.47,111.37 60.02,111.82 60.02,112.5 59.77,112.75 59.42,112.75 59.29,112.61 53.79,112.61 v1(53.55,112.86) ; U21.30 106.63,137.95 v1(106.46,137.78) 106.46,137.47 109.22,134.71 U25.3 ; U20.5 74.69,141.68 75.03,141.34 75.46,141.34 76.39,142.27 76.76,142.27 v1(77.3,141.73) 78.02,141.01 U22.10 ; v1(130.97,159.12) 129.91,160.17 127.57,160.17 126.11,158.72 R58.2 126.11,155.02 126.27,154.85 U11.1 ; R350.1 73.28,45.76 73.51,46 v1(73.51,46.38) ; J18.42 91.21,41.74 91.74,41.2 v1(91.74,40.68)
  L03_SIG01 w0.076: v1(96.64,52.07) 96.64,44.87 93.4,41.63 92.69,41.63 v1(91.74,40.68) 91.74,39.97 91.46,39.68 82.83,39.68 82.13,40.38 82.13,42.04 83.41,43.31 83.41,45.79 v1(82.59,46.6) ; v1(106.46,137.78) 106.46,138.49 107.37,139.4 121.72,139.4 123.49,141.16 123.49,147.48 130.23,154.22 130.23,157.12 130.97,157.86 v1(130.97,159.12) ; v1(80.54,116.23) 80.89,116.58 82.43,116.58 84.21,118.35 84.21,122.1 77.98,128.33 77.98,137.9 77.3,138.58 v1(77.3,141.73)
  L05_SIG02 w0.102: v1(93.03,86.03) 93.44,86.44 93.44,96.07 93.23,96.27 93.23,101.63 92.38,102.48 92.38,103.19 92.94,103.75 92.94,105.22 92.81,105.34 92.81,105.78 93.54,106.51 93.54,108.27 85.23,116.58 80.95,116.58 80.61,116.23 v1(80.54,116.23)
  BOTTOM w0.191: U84.42 78.2,114.43 79.4,115.64 79.95,115.64 v1(80.54,116.23) ; v1(73.51,46.38) 73.82,46.08 79.18,46.08 79.7,46.6 v1(82.59,46.6) ; v1(91.74,40.68) 91.74,40.1 92.42,39.43 92.42,37.74 92.82,37.34 98.15,37.34 102.45,33.04 123.14,33.04 126.56,36.46 R618.2 R616.1 125.6,41.7 125.5,41.59 124.97,41.59 v1(124.71,41.33) ; v1(106.46,137.78) 106.44,137.76 104.9,137.76 102.87,139.8 102.87,141.49 100.57,143.79 82.74,143.79 81.88,142.94 v1(81.61,142.94) 80.96,142.94 80.21,142.19 78.98,142.19 78.52,141.73 v1(77.3,141.73) ; U85.42 60.75,108.15 60.33,108.57 60.05,108.57 60.04,108.57 59.79,108.57 59.29,109.07 56.23,109.07 53.55,111.75 v1(53.55,112.86)
SOC_I2C0_SDA_1V8: length 226.1
  TOP w0.145: U6.8 117.41,160.99 116.88,160.46 v1(116.88,159.84)
  TOP w0.183: U7.26 v1(78.26,161.76)
  TOP w0.191: v1(74.59,153.07) 74.59,153.59 75.06,154.06 75.06,155.92 74.52,156.46 73.23,156.46 72.85,156.85 72.85,157.62 72.48,157.98 U8.26 ; U11.4 128.02,153.35 128.23,153.56 128.23,157.31 v1(128.22,157.32) ; v1(120.4,145.44) 120.11,145.73 U15.19 ; U5.8 100.01,161.16 99.69,160.84 99.69,159.7 99.69,159.69 v1(99.69,159.65) ; R45.2 50.67,158.83 52.39,157.1 52.39,156.4 v1(52.68,156.11)
  L03_SIG01 w0.076: v1(120.4,145.44) 121.39,146.43 121.39,149.79 116.88,154.3 v1(116.88,159.84) ; v1(74.59,153.07) 74.59,158.92 75.09,159.42 75.09,159.97 74.87,160.18 74.87,161.63 75.46,162.22 77.51,162.22 77.97,161.76 v1(78.26,161.76) ; v1(54.96,85.46) 53.66,85.46 52.36,86.75 52.36,99.17 51.85,99.68 51.85,105.08 52.36,105.59 52.36,113.03 51.14,114.25 51.14,122.3 51.78,122.94 51.78,143.53 52.72,144.47 52.72,156.07 v1(52.68,156.11)
  BOTTOM w0.191: v1(54.96,85.46) 54.83,85.58 54.83,86.6 56.73,88.5 R514.2 ; v1(78.26,161.76) 78.47,161.55 83.97,161.55 84.74,160.78 97.6,160.78 97.95,160.43 98.91,160.43 v1(99.69,159.65) 101.57,159.65 103.06,158.15 109.19,158.15 109.56,157.78 111.83,157.78 112.3,157.31 112.93,157.31 113.33,157.71 116.44,157.71 116.94,158.2 116.94,159.79 v1(116.88,159.84) ; v1(116.88,159.84) 116.72,159.68 112.8,159.68 111.85,160.63 110.28,160.63 109.53,161.38 U77.8 ; v1(116.88,159.84) 118.27,159.84 120.74,157.37 128.16,157.37 v1(128.22,157.32) 128.57,157.66 128.57,159.59 126.93,161.23 U76.8 ; v1(74.59,153.07) 73.92,153.07 73.67,152.82 55.7,152.82 52.68,155.84 v1(52.68,156.11)
SOC_I2C0_SDA_R1: length 180.4
  TOP w0.191: v1(44.28,26.48) 44.43,26.64 44.74,26.64 44.98,26.4 U70.5 ; R350.2 72.76,46.75 U63.6 72.76,48.61 72.2,49.18 70.33,49.18 69.83,49.68 69.56,49.68 67.9,48.02 TP90.1 67.9,46.66 v1(67.58,46.35)
  L03_SIG01 w0.076: v1(34.52,89.98) 34.52,89.3 33.8,88.57 33.8,66.94 v1(36.27,64.47) 36.27,61.85 37.06,61.06 37.06,57.11 37.35,56.82 37.35,50.05 37.56,49.83 37.56,40.02 39.41,38.17 39.41,32.64 37.93,31.16 37.93,27.55 38.58,26.9 v1(38.58,26.25) 39.02,25.81 43.61,25.81 v1(44.28,26.48) 44.62,26.82 46.39,26.82 46.89,27.33 46.89,38.3 46.29,38.9 46.29,39.54 46.4,39.65 v1(47.55,39.65) 47.74,39.65 48.22,40.13 50.07,40.13 50.77,39.43 51.78,39.43 v1(52.43,40.08) ; v1(55.46,54.26) 55.41,54.21 55.41,44.48 56.94,42.95 v1(57.62,42.95)
  BOTTOM w0.191: U119.A2 58.69,48.14 58.19,47.64 U118.4 58.19,44.14 57.62,43.57 v1(57.62,42.95) ; v1(57.62,42.95) 57.02,42.95 56.54,42.47 55.94,42.47 55.26,41.79 55.26,40.59 53.77,39.1 52.82,39.1 52.43,39.49 v1(52.43,40.08) 52.72,40.37 U122.4 52.72,42.67 53.22,43.17 U121.A2 ; v1(57.62,42.95) 59.72,42.95 60.43,43.66 60.43,44.35 62.72,46.64 67.29,46.64 v1(67.58,46.35) ; v1(34.52,89.98) 36.09,91.54 43.7,91.54 43.93,91.31 46.49,91.31 48.78,93.61 50.37,93.61 50.61,93.37 U91.4 50.61,90.32 50.11,89.82 U92.A2 ; v1(38.58,26.25) 38.52,26.2 R656.1 ; v1(47.55,39.65) 47.36,39.84 U124.4 47.36,41.58 47.86,42.08 U123.A2 ; v1(55.46,54.26) 55.56,54.36 U116.4 55.56,56.24 56.06,56.74 U115.A2 ; v1(36.27,64.47) 36.63,64.83 U114.4 36.63,66.69 37.13,67.19 U113.A2
SOC_I2C1_SCL: length 126
  TOP w0.132: U47.C17 v1(68.36,84.79)
  TOP w0.191: J13.18 128.3,129.95 127.49,129.14 v1(127.49,128.2)
  L03_SIG01 w0.076: v1(68.36,84.79) 67.97,84.4 67.38,84.4 67.03,84.75 67.03,85.35 66.71,85.67 64.83,85.67 59.47,91.04 59.47,94.25 59.55,94.33 v1(59.55,94.62) 59.55,98.11 56.17,101.49 56.17,102.51 56.62,102.96 56.62,107.11 57.27,107.76 57.27,108.06 56.62,108.71 56.62,115.95 56.12,116.45 56.12,121.1 v1(55.9,121.32)
  BOTTOM w0.191: v1(127.49,128.2) 125.58,126.29 121.75,126.29 121.26,126.78 97.35,126.78 95.29,124.72 90.64,124.72 89.44,125.92 74.29,125.92 70.06,121.69 58.21,121.69 57.84,121.32 v1(55.9,121.32) ; R503.2 60.79,94.62 v1(59.55,94.62)
SOC_I2C1_SDA: length 123.7
  TOP w0.132: U47.E17 v1(69.96,84.79)
  TOP w0.191: R198.2 63.25,94.99 v1(63.25,94.99) ; v1(127.54,125.66) 127.54,127.44 128.2,128.1 128.2,128.98 128.37,129.15 J13.20
  L03_SIG01 w0.076: v1(69.96,84.79) 69.58,85.17 69.58,85.72 69.33,85.98 68.9,85.98 68.76,86.12 68.76,86.56 68.54,86.77 65.5,86.77 62.62,89.65 62.62,94.36 v1(63.25,94.99) 63.25,97.2 62.67,97.79 62.67,98.92 58.88,102.71 58.88,106.69 58.22,107.35 58.22,108.69 57.73,109.17 57.73,114 58.02,114.28 58.02,116.62 57.52,117.12 v1(57.52,120.35)
  BOTTOM w0.191: v1(127.54,125.66) 127.31,125.89 121.32,125.89 120.85,126.36 105.14,126.36 97.62,126.36 95.52,124.26 90.41,124.26 89.14,125.53 74.46,125.53 69.95,121.03 60.37,121.03 59.69,120.35 v1(57.52,120.35)
SOC_MMC0_CLK: length 4.4
  TOP w0.191: v1(86.51,78.34) 86.51,77.53 85.37,76.39 U47.AB7
  BOTTOM w0.191: R558.2 86.61,78.44 v1(86.51,78.34)
SOC_MMC0_CMD: length 26.8
  TOP w0.132: U47.Y6 v1(82.76,75.19)
  TOP w0.191: U49.M5 102.6,74.47 v1(102.35,74.47)
  BOTTOM w0.102: v1(82.76,75.19) 83.16,74.79 83.76,74.79 83.96,74.59 83.96,74.19 84.16,73.99 84.5,73.99
  BOTTOM w0.191: 84.5,73.99 84.62,73.99 90.08,68.52 97.06,68.52 101.4,72.86 R575.2 101.77,73.3 102.35,73.87 v1(102.35,74.47)
SOC_MMC0_DAT0: length 27.5
  TOP w0.102: 96.82,73.57 96.96,73.72 U49.A3
  TOP w0.132: U47.AA6 v1(83.56,75.19)
  TOP w0.191: R269.2 v1(94.97,72.67) 95.91,72.67 96.82,73.57
  BOTTOM w0.102: v1(83.56,75.19) 84.21,75.19 84.41,75
  BOTTOM w0.191: 84.41,75 90.37,69.03 96.24,69.03 97.03,69.82 97.03,71.47 96.71,71.79 96.71,73.44 96.52,73.64 95.95,73.64 v1(94.97,72.67)
SOC_MMC0_DAT1: length 26.3
  TOP w0.102: U49.A4 96.52,74.22 96.3,74
  TOP w0.14: v1(87.14,75.59) U47.AB6
  TOP w0.191: R266.2 93.49,74.19 v1(93.68,74) 96.3,74
  BOTTOM w0.191: v1(87.14,75.59) 87.17,75.57 87.17,75.55 87.48,75.24 91.11,75.24 91.27,75.39 91.27,75.6 91.42,75.75 91.64,75.75 91.79,75.6 91.79,75.39 91.94,75.24 92.08,75.24 92.31,75.47 92.53,75.47 92.69,75.31 92.69,74.87 92.47,74.65 89.17,74.65 88.98,74.46 88.98,74.19 89.17,74 90.91,74 91.06,73.85 91.06,73.27 91.22,73.12 91.43,73.12 91.58,73.27 91.58,73.85 91.74,74 91.95,74 92.1,73.85 92.1,73.27 92.26,73.12 92.47,73.12 92.63,73.27 92.63,73.85 92.78,74 v1(93.68,74)
SOC_MMC0_DAT2: length 27.8
  TOP w0.102: U49.A5 96.6,74.72 96.43,74.89
  TOP w0.14: U47.Y7 v1(82.76,75.99)
  TOP w0.191: R263.2 v1(94.2,75.72) 95.02,74.89 96.43,74.89
  BOTTOM w0.102: v1(82.76,75.99) U47.Y7 82.36,77.04 82.51,77.19 84.74,77.19
  BOTTOM w0.191: v1(94.2,75.72) 94.56,76.08 96.19,76.08 96.42,75.85 96.42,75.44 96.27,75.28 96.14,75.28 95.99,75.13 95.99,74.92 96.14,74.76 96.27,74.76 96.42,74.61 96.42,74.32 96.24,74.14 94.66,74.14 94.31,74.49 93.42,74.49 93.21,74.7 93.21,75.82 93.02,76.01 92.14,76.01 91.7,76.45 91.31,76.45 90.62,75.76 87.7,75.76 86.6,76.85 85.87,76.85 85.29,77.43 84.98,77.43 84.74,77.19
SOC_MMC0_DAT3: length 26.3
  TOP w0.081: U49.B2 97.6,72.97 97.12,72.97
  TOP w0.132: U47.AA7 v1(83.56,75.99)
  TOP w0.191: R275.2 v1(93.75,71.14) 95.46,71.14 96.87,72.56 96.87,72.73 97.12,72.97
  BOTTOM w0.102: 84.03,76.16 83.86,75.99 v1(83.56,75.99)
  BOTTOM w0.191: 84.03,76.16 84.33,76.46 84.6,76.46 90.95,70.1 94.26,70.1 94.47,70.31 94.47,71.04 94.62,71.19 94.83,71.19 94.99,71.04 94.99,70.31 95.14,70.16 95.44,70.16 95.63,70.35 95.63,71.51 95.44,71.7 94.31,71.7 v1(93.75,71.14)
SOC_MMC0_DAT4: length 26.4
  TOP w0.081: U49.B3 97.6,73.47 97.16,73.47 97,73.31
  TOP w0.132: U47.Y8 v1(82.76,76.79)
  TOP w0.191: R270.2 v1(93.68,71.91) 95.59,71.91 97,73.31
  BOTTOM w0.102: 85.03,76.68 84.93,76.78 84.14,76.78 83.75,76.39 83.16,76.39 v1(82.76,76.79)
  BOTTOM w0.191: 85.03,76.68 85.19,76.68 91.23,70.63 93,70.63 93.22,70.85 93.22,71.44 92.95,71.7 90.81,71.7 90.62,71.89 90.62,72.16 90.78,72.32 93.27,72.32 v1(93.68,71.91)
SOC_MMC0_DAT5: length 27.4
  TOP w0.081: U49.B4 97.6,73.97 96.92,73.97
  TOP w0.132: U47.W7 v1(81.96,75.99)
  TOP w0.191: R267.2 93.46,73.43 v1(93.68,73.21) 93.7,73.22 95.99,73.22 96.74,73.97 96.92,73.97
  BOTTOM w0.102: v1(81.96,75.99) 82.36,75.59 83.72,75.59
  BOTTOM w0.191: 83.72,75.59 84.67,75.59 90.67,69.6 95.61,69.6 96.11,70.09 96.11,71.7 95.63,72.19 94.7,72.19 v1(93.68,73.21)
SOC_MMC0_DAT6: length 26.4
  TOP w0.081: U49.B5 97.6,74.47 96.49,74.47
  TOP w0.132: U47.W9 v1(81.96,77.59)
  TOP w0.191: 96.49,74.47 94.61,74.47 94.13,74.95 93.7,74.95 v1(93.68,74.97) 93.67,74.95 R264.2
  BOTTOM w0.102: 84.5,77.99 82.36,77.99 v1(81.96,77.59)
  BOTTOM w0.191: v1(93.68,74.97) 93.68,75.9 94.54,76.76 95.98,76.76 96.17,76.95 96.17,77.6 95.98,77.79 94.96,77.79 93.66,76.49 92.4,76.49 91.77,77.12 91.22,77.12 90.41,76.3 87.86,76.3 86.81,77.36 86.06,77.36 85.43,77.99 84.5,77.99
SOC_MMC0_DAT7: length 27.1
  TOP w0.081: 96.8,74.97 97.6,74.97 U49.B6
  TOP w0.191: v1(85.75,78.43) 85.75,77.52 85.23,77 84.15,77 U47.AB8 ; R262.2 93.3,76.48 93.49,76.67 v1(93.49,77.03) 96.08,77.03 96.36,76.76 96.36,75.42 96.8,74.97
  BOTTOM w0.191: v1(93.49,77.03) 94.92,78.45 96.74,78.45 96.93,78.64 96.93,78.89 96.8,79.02 94.7,79.02 93.45,77.78 91.12,77.78 90.14,76.8 88.09,76.8 87.02,77.86 86.35,77.86 86.35,77.86 86.31,77.86 86.03,78.14 86.03,78.14 v1(85.75,78.43)
SOC_OSPI_CLK: length 5.7
  TOP w0.14: U47.L22 75.16,92.12 75.11,92.17 75.11,92.95 75.34,93.18
  TOP w0.191: R197.2 75.51,93.36 75.34,93.18
SOC_OSPI_DQ0: length 10.4
  TOP w0.132: 73.17,95.77 73.26,95.67 73.26,94.07 74.31,93.02 74.31,91.32 73.7,90.71 73.7,89.99 73.96,89.73 73.96,87.99 U47.J21
  TOP w0.14: RA3.8 72.59,96.34 73.17,95.77
SOC_OSPI_DQ1: length 12.8
  TOP w0.132: U47.J18 v1(73.16,85.59)
  TOP w0.14: v1(72.73,95.29) 72.19,95.83 RA3.7
  L03_SIG01 w0.076: v1(72.73,95.29) 72.41,94.96 72.41,93.22 73.34,92.29 73.34,86.87 73.57,86.64 73.57,86 v1(73.16,85.59)
SOC_OSPI_DQ2: length 15.2
  TOP w0.132: U47.J19 v1(73.16,86.39)
  TOP w0.14: v1(71.42,95.53) 71.49,95.53 71.79,95.83 RA3.6
  L03_SIG01 w0.076: v1(73.16,86.39) 73.16,86.78 73.06,86.88 73.06,92.16 70.75,94.47 70.75,94.63 71.09,94.98 71.09,95.08 70.91,95.26 70.81,95.26 70.46,94.92 70.3,94.92 70.15,95.07 70.15,95.74 70.28,95.88 71.08,95.88 v1(71.42,95.53)
SOC_OSPI_DQ3: length 14.4
  TOP w0.132: U47.H18 v1(72.36,85.59)
  TOP w0.14: v1(71.29,96.26) 71.29,96.44 71.39,96.54 RA3.5
  L03_SIG01 w0.076: v1(71.29,96.26) 70.27,96.26 69.9,95.9 69.9,94.71 72.76,91.85 72.76,85.95 72.4,85.59 v1(72.36,85.59)
SOC_OSPI_DQ4: length 9.6
  TOP w0.132: 74.76,88.77 74.76,87.99 U47.K21
  TOP w0.14: RA4.8 75.01,96.14 75.09,96.06 75.09,95.52 74.71,95.13 74.71,92 74.76,91.96 74.76,88.77
SOC_OSPI_DQ5: length 11.9
  TOP w0.132: U47.H19 v1(72.36,86.39)
  TOP w0.14: v1(74.63,95.74) 74.61,95.75 RA4.7
  BOTTOM w0.191: v1(74.63,95.74) 74.25,95.37 74.25,94.48 73.67,93.89 73.67,93.4 73.06,92.79 73.06,87.14 72.36,86.44 v1(72.36,86.39)
SOC_OSPI_DQ6: length 10.8
  TOP w0.132: U47.J20 73.16,87.19 73.16,88.82
  TOP w0.14: v1(73.11,93.53) 73.12,93.52 73.12,91.7 72.89,91.47 72.89,89.64 73.16,89.38 73.16,88.82 ; RA4.6 74.21,96.09 73.85,95.72 73.85,94.77 73.78,94.7 v1(73.78,94.69)
  L03_SIG01 w0.076: v1(73.11,93.53) 73.11,94.03 v1(73.78,94.69)
SOC_OSPI_DQ7: length 11.6
  TOP w0.14: v1(73.67,96.2) 73.71,96.24 73.71,96.38 73.81,96.49 RA4.5 ; v1(73.78,92.78) 73.78,91.46 73.3,90.97 73.3,89.83 73.56,89.57 U47.J22
  L03_SIG01 w0.076: v1(73.78,92.78) 74.58,92.78 75.12,93.32 75.12,96.3 74.87,96.55 74.02,96.55 v1(73.67,96.2)
SOC_PORZ: length 29.1
  TOP w0.191: v1(109.36,104.69) 109.24,104.57 109.17,104.57 108.78,104.18 106.31,104.18 105.89,104.6 104.98,104.6 104.42,104.04 104.42,97.22 98.75,91.55 98.75,89.76 99.08,89.43 99.51,89.43 101.93,87.01 U43.3
  BOTTOM w0.191: v1(109.36,104.69) 109.36,104.69 109.17,104.5 R480.2 108.76,104.12 108.59,104.29 U86.4
SOC_PORZ_PB: length 162.2
  TOP w0.191: U50.7 31.79,72.27 31.97,72.45 32.34,72.45 R268.2 33.47,72.45 TP55.1 34.22,72.45 v1(34.46,72.68) ; U43.1 102.59,85.26 v1(102.85,85) ; v1(47.69,38.35) 46.74,38.35 45.67,39.42 v1(39.22,39.42)
  L03_SIG01 w0.076: v1(39.22,39.42) 37.74,40.9 37.74,50.08 37.53,50.3 37.53,56.93 37.24,57.21 37.24,61.34 36.66,61.91 36.66,70.48 v1(34.46,72.68) ; v1(102.85,85) 103.18,84.67 103.18,79.32 105.18,77.33 105.18,72.19 104.56,71.57 104.56,63.4 v1(105.53,62.42)
  BOTTOM w0.191: v1(47.69,38.35) 48.83,38.35 49.64,37.55 51.46,37.55 52.25,38.33 54.6,38.33 55.58,39.32 59.98,39.32 60.6,39.94 60.6,42.9 62.87,45.17 63.45,45.17 63.83,45.55 66.84,45.55 68.13,44.25 78.16,44.25 80.01,46.1 83.37,46.1 84.14,46.87 86.46,46.87 90.29,50.7 91.5,50.7 94.08,53.28 111.53,53.28 112.46,54.21 112.46,55.7 110.89,57.27 106.07,57.27 104.58,58.75 104.58,61.47 v1(105.53,62.42)
SOC_RGMII_MDC: length 95
  TOP w0.191: v1(119.41,49.71) 115.09,49.71 114.51,49.13 94.61,49.13 93.91,48.43 85.93,48.43 85.74,48.24 R338.1 ; v1(118.54,47.71) 118.51,47.68 R352.1
  BOTTOM w0.14: 89.76,81.54 89,82.3 88.13,82.3 87.93,82.5 87.53,82.5 R548.2
  BOTTOM w0.191: v1(118.54,47.71) 118.54,48.84 v1(119.41,49.71) 119.41,52.33 106.86,64.88 106.86,77.38 104.12,80.12 94.06,80.12 92.95,81.23 90.08,81.23 89.76,81.54
SOC_RGMII_MDIO: length 94
  TOP w0.191: R345.1 119.35,46.54 v1(119.35,47.95) 118.86,48.43 116.99,48.43 116.22,47.66 114.6,47.66 114.6,47.66 113.1,47.66 112.84,47.91 110.32,47.91 109.23,46.82 109.23,46.31 108.12,45.2 105.61,45.2 103.19,47.63 94.66,47.63 94.04,47 R340.1
  BOTTOM w0.14: R541.2 87.72,82.88 88.16,83.32 88.59,83.32 90.27,81.65 91.56,81.65
  BOTTOM w0.191: v1(119.35,47.95) 120.03,48.64 120.03,52.53 107.37,65.19 107.37,77.44 104.3,80.52 94.38,80.52 93.25,81.65 91.56,81.65
SOC_TCK: length 94.2
  TOP w0.14: v1(65.83,81.85) 65.98,81.85 66.01,81.89 66.51,81.89 66.61,81.99 U47.A14
  L03_SIG01 w0.076: v1(119.08,82.89) 119.08,83.26 119.88,84.06 121.56,84.06 122.09,83.52 122.09,82.58 124.36,80.31 124.36,78.05 125.26,77.15 v1(125.26,76.54) ; v1(108.05,84.82) 105.07,84.82 102.56,87.34 102.56,88.11 103.14,88.69 103.14,96.49 102.36,97.27 99.96,97.27 97.86,95.17 94.4,95.17 92,92.77 82.35,92.77 77.56,87.97 77.56,85.46 77.3,85.2 76.23,85.2 75.98,84.95 75.98,84.74 75.52,84.28 75.52,83.42 74.87,82.77 73.8,82.77 73.54,82.5 73.54,82.24 73.31,82.02 72.25,82.02 71.94,81.7 71.94,81.44 71.7,81.2 71.43,81.2 71.14,80.9 71.14,80.64 70.74,80.24 67.02,80.24 65.83,81.43 v1(65.83,81.85)
  BOTTOM w0.14: v1(125.26,76.54) R566.1
  BOTTOM w0.191: R534.1 118.73,83.79 119.1,83.41 119.1,82.91 v1(119.08,82.89) 119.05,82.92 R544.1 117.2,82.92 116.16,81.88 116.16,81.46 115.31,80.61 114.28,80.61 113.96,80.28 112.43,80.28 108.05,84.66 v1(108.05,84.82)
SOC_TDI: length 95.3
  TOP w0.14: v1(65.59,83.89) 66.65,83.89 66.95,83.59 U47.A16
  L03_SIG01 w0.076: v1(65.59,83.89) 65.59,83.03 68.2,80.42 70.11,80.42 70.34,80.64 70.34,80.9 70.65,81.21 70.91,81.21 71.14,81.44 71.14,81.7 71.45,82.01 71.71,82.01 71.95,82.25 71.95,82.52 72.23,82.8 73.3,82.8 73.54,83.04 73.54,83.3 73.84,83.61 74.91,83.61 75.14,83.84 75.14,84.2 75.8,84.86 75.8,85.02 75.97,85.19 75.97,85.74 76.21,85.98 76.48,85.98 76.74,86.24 76.74,87.78 81.96,93 91.64,93 94.03,95.4 97.64,95.4 99.73,97.5 102.52,97.5 103.37,96.65 103.37,88.34 102.79,87.76 102.79,87.43 104.96,85.25 v1(106.76,85.25) ; v1(124.65,73.41) 124.65,73.77 119.08,79.34 v1(119.08,80.71)
  BOTTOM w0.14: v1(124.65,73.41) 124.89,73.66 U110.9
  BOTTOM w0.191: U97.6 119.68,81.67 119.08,81.08 v1(119.08,80.71) 118.73,80.71 118.42,80.39 R554.1 118.43,80.12 118.7,80.12 118.88,79.94 118.88,78.82 118.5,78.44 113.56,78.44 v1(106.76,85.25)
SOC_TDO: length 97.1
  L03_SIG01 w0.076: v1(121.3,70.83) 120.76,70.29 119.01,70.29 117.93,71.37 117.93,79.65 115.34,82.23 115.34,88 112.35,91 112.35,94.29 112.58,94.52 113.04,94.52 v1(113.56,94) ; v1(66.27,83.01) 67.31,81.97 70.07,81.97 70.11,82.02 70.11,82.02 70.34,82.24 70.34,82.24 70.38,82.28 70.38,84.15 70.65,84.42 71.71,84.42 71.98,84.68 71.98,84.95 72.25,85.21 73.31,85.21 73.56,85.46 73.56,85.73 73.8,85.97 74.07,85.97 74.38,86.28 74.38,87.91 80.8,94.33 89.2,94.33 89.99,95.12 90.46,95.12 91.37,96.04 97.15,96.04 100.19,99.08 105.23,99.08 106.07,98.23 v1(109.59,98.23)
  BOTTOM w0.14: U109.2 120.96,71.17 v1(121.3,70.83)
  BOTTOM w0.191: U90.2 113.95,94.96 113.56,94.57 v1(113.56,94) 113.56,93.96 113.28,93.68 111.18,93.68 110.68,94.18 110.68,97.14 v1(109.59,98.23) ; v1(66.27,83.01) 66.72,83.01 R542.1
SOC_TMS: length 98.8
  TOP w0.102: U47.B14 67.58,82.37 67,82.37 66.91,82.29 65,82.29 v1(64.84,82.12)
  L03_SIG01 w0.076: v1(108.85,84.54) 108.54,84.23 105.34,84.23 102.22,87.35 102.22,89.81 102.87,90.47 102.87,96.39 102.23,97.04 100.41,97.04 94.25,90.88 88.54,90.88 86.55,88.89 85.07,88.89 84.4,89.56 82.87,89.56 81.54,88.22 81.54,86.17 81.36,85.99 80.93,85.99 80.76,85.81 80.76,84.6 80.56,84.41 76.25,84.41 75.74,83.91 75.74,83.1 75.28,82.64 75.28,82.38 74.87,81.97 73.8,81.97 73.54,81.7 73.54,81.44 73.31,81.21 72.24,81.21 71.97,80.93 71.97,80.67 71.36,80.06 66.53,80.06 64.84,81.75 v1(64.84,82.12) ; v1(119.81,83) 119.81,83.37 120.28,83.83 120.69,83.83 120.95,83.56 120.95,83.18 124.02,80.11 124.02,77.83 124.84,77.01 124.84,75.61 v1(125.7,74.74)
  BOTTOM w0.14: v1(125.7,74.74) 125.39,74.74 125.25,74.6 U110.8
  BOTTOM w0.191: U97.8 119.89,82.47 119.73,82.62 119.73,82.92 v1(119.81,83) R533.1 119.81,84.38 119.4,84.8 118.41,84.8 117.58,85.63 117.58,85.88 117.21,86.25 113.73,86.25 112.02,84.54 v1(108.85,84.54)
SOC_TRST#: length 82.6
  TOP w0.132: U47.F15 v1(70.76,83.19)
  L03_SIG01 w0.076: v1(123.47,75.84) 122.35,76.96 122.35,80.68 120.53,82.51 v1(120.53,83.44) ; v1(70.76,83.19) 71.14,83.57 71.67,83.57 71.94,83.84 71.94,84.1 72.2,84.37 73.27,84.37 73.54,84.64 73.54,84.9 73.8,85.17 74.87,85.17 75.14,85.44 75.14,85.51 75.14,85.51 75.43,85.8 75.43,86.57 75.57,86.71 75.57,88.3 81.04,93.76 90.89,93.76 91.58,94.45 91.58,94.91 92.51,95.84 97.52,95.84 100.38,98.7 104.93,98.7 109.43,94.19 109.43,87.14 110.64,85.94 v1(111.53,85.94)
  BOTTOM w0.14: U110.6 124.45,75.28 R564.1 124.14,75.3 123.93,75.51 123.93,75.67 123.75,75.84 v1(123.47,75.84)
  BOTTOM w0.191: v1(111.53,85.94) 112.7,85.94 113.43,86.66 117.38,86.66 117.99,86.05 117.99,85.77 118.57,85.18 119.95,85.18 120.53,84.6 v1(120.53,83.44) 120.7,83.26 U97.9
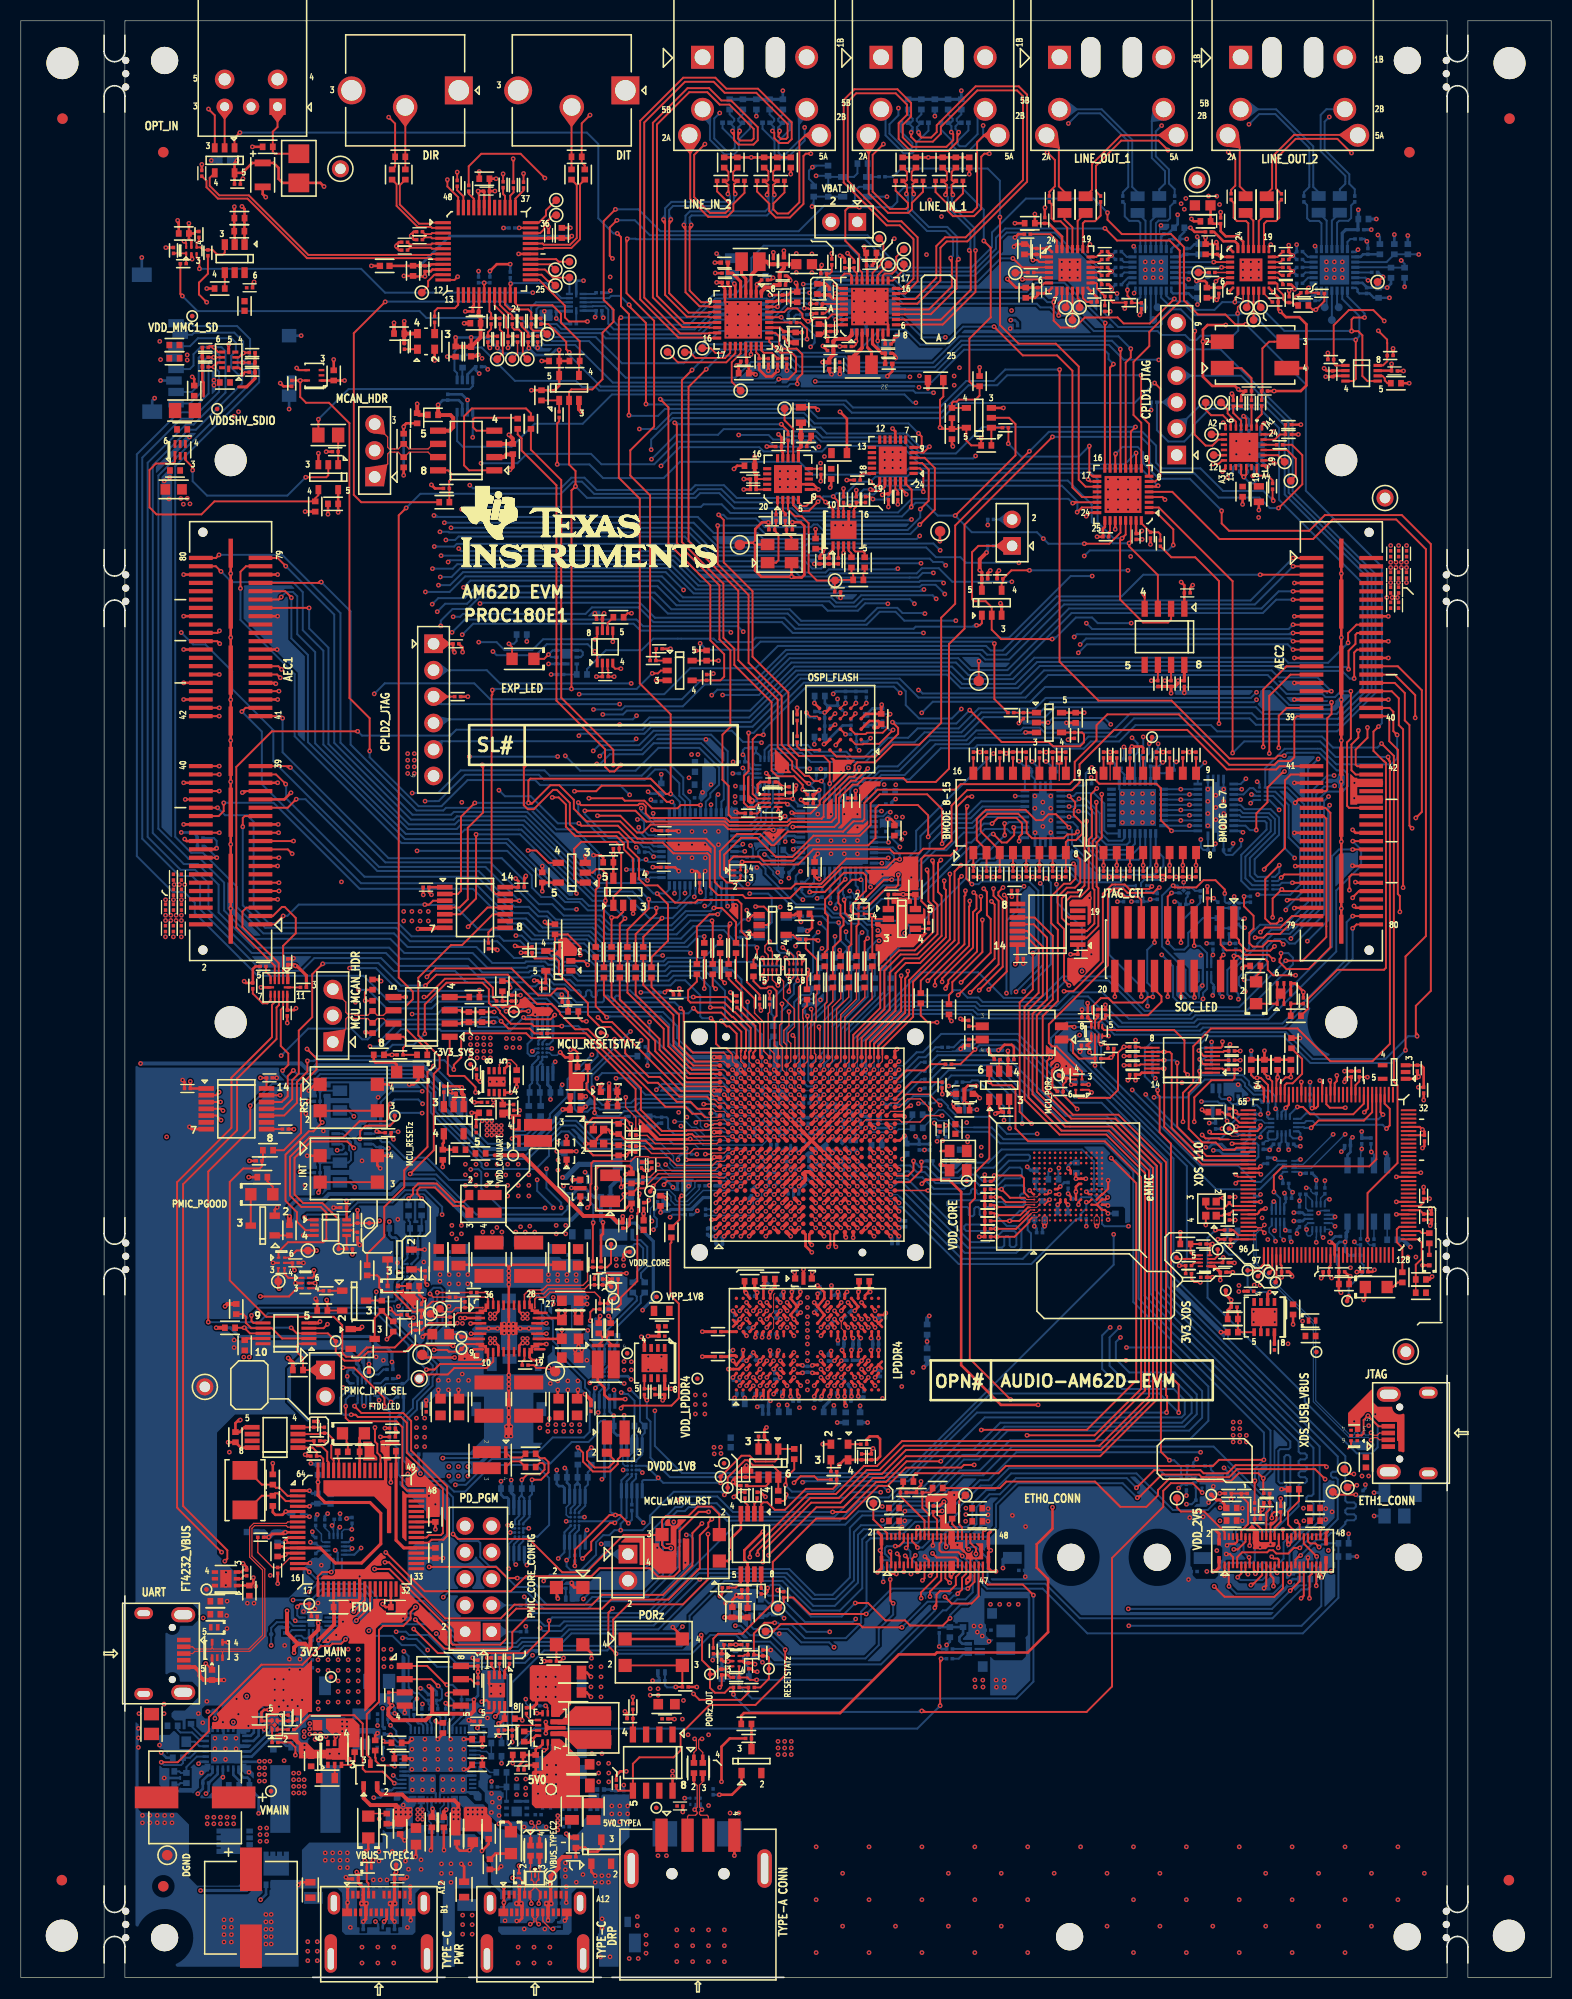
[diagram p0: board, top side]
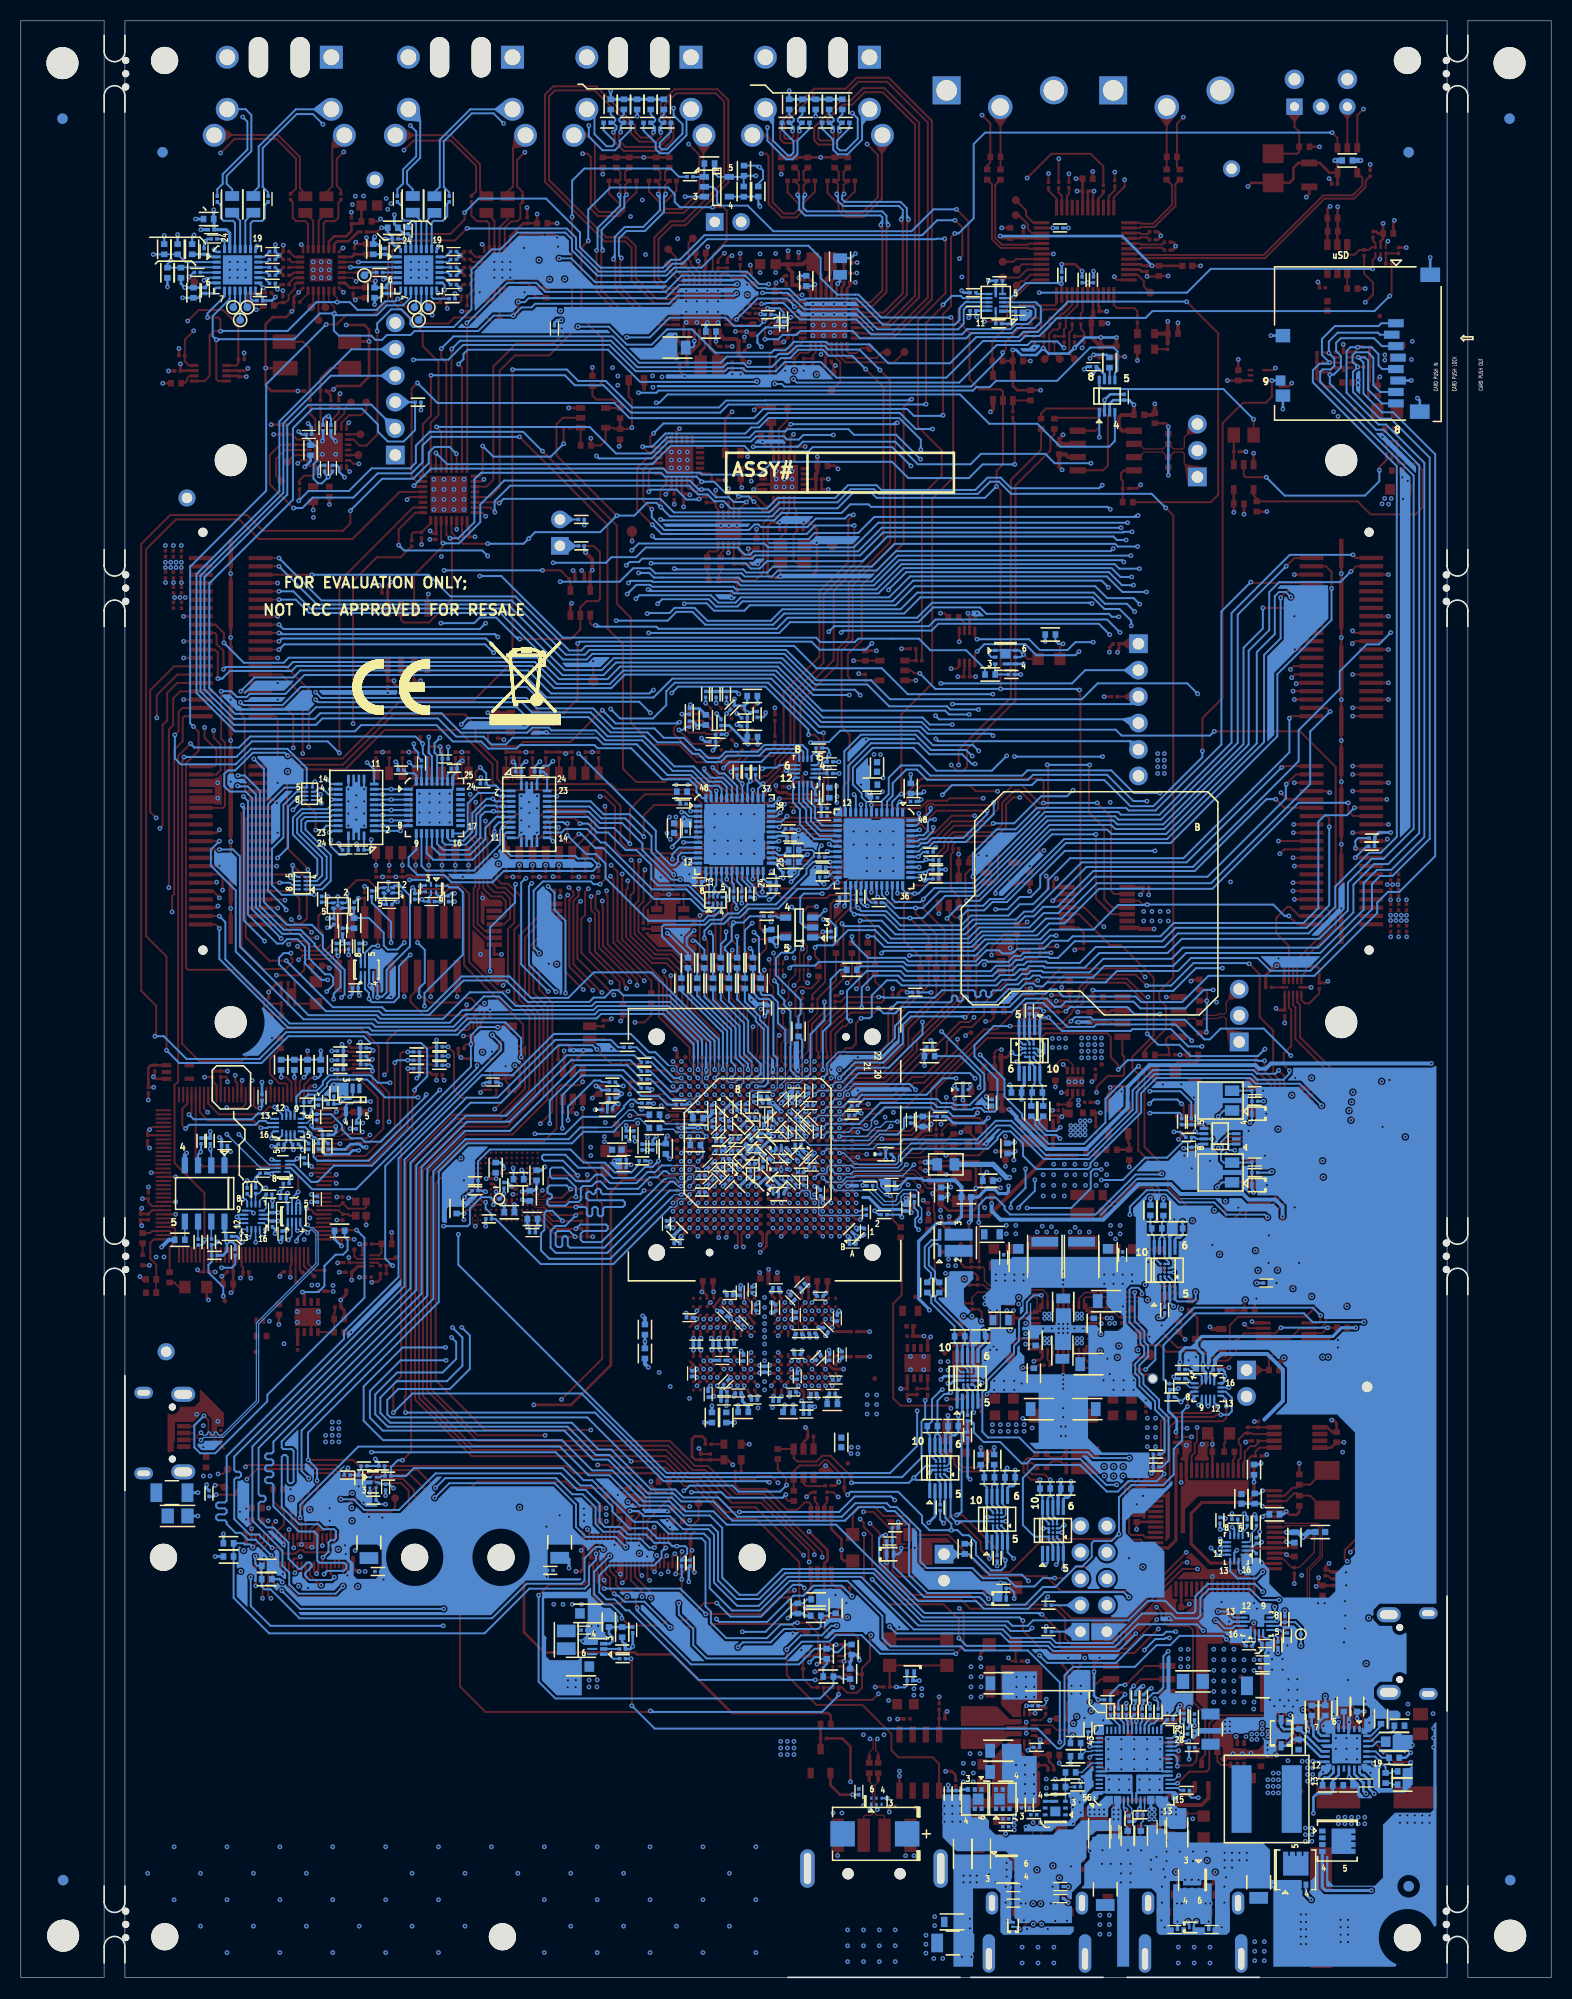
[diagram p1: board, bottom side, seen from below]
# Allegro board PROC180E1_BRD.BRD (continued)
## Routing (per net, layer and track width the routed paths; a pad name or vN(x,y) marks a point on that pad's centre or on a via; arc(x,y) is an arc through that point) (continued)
SOC_USB0_DM: length 94.8
  TOP w0.102: U47.AA10 v1(83.56,78.39)
  TOP w0.119: v1(49.76,14.87) 49.53,14.64 49.53,14.36 49.53,14.36 49.82,14.07 L10.4 R400.1
  L03_SIG01 w0.089: v1(49.76,14.87) 49.76,15.74 50.21,16.19 55.16,16.19 57.38,18.41 57.38,20.35 61,23.97 67.85,23.97 69.78,25.91 69.78,32.32 73.93,36.47 73.93,43.8 75.4,45.26 76.41,45.26 80.26,49.12 80.26,50.81 89.14,59.69 89.14,76.44 88.03,77.55 85.8,77.55 85.14,78.21 83.85,78.21 83.84,78.21 83.74,78.21 v1(83.56,78.39)
SOC_USB0_DP: length 94.8
  TOP w0.102: U47.AA9 v1(83.56,77.59)
  TOP w0.119: v1(49.05,14.87) 49.31,14.61 49.31,14.46 48.97,14.12 L10.1 R399.1
  L03_SIG01 w0.089: v1(83.56,77.59) 83.94,77.98 85.04,77.98 85.7,77.31 87.93,77.31 88.91,76.34 88.91,59.79 80.03,50.91 80.03,49.21 76.32,45.5 75.3,45.5 73.7,43.9 73.7,36.57 69.55,32.42 69.55,26 67.75,24.2 60.9,24.2 57.14,20.44 57.14,18.51 55.06,16.43 50.12,16.43 49.52,15.84 49.52,15.2 49.2,14.87 v1(49.05,14.87)
SOC_USB0_DRVVBUS: length 50.3
  TOP w0.132: U47.C20 v1(68.36,87.19)
  TOP w0.191: U24.5 v1(56.86,128.31)
  L03_SIG01 w0.076: v1(56.86,128.31) 56.49,127.94 56.49,121.94 57.99,120.44 57.99,117.25 58.2,117.05 58.2,114.21 57.91,113.92 57.91,109.28 58.46,108.74 58.46,107.44 59.22,106.67 59.22,102.89 62.93,99.17 62.93,98 63.65,97.28 63.65,94.68 62.95,93.98 62.95,89.73 65.49,87.19 v1(68.36,87.19)
SOC_USB0_DRVVBUS_3V3: length 170.2
  TOP w0.191: U24.8 55.36,128.75 v1(55.16,128.55)
  L03_SIG01 w0.076: v1(45.21,18.82) 43.33,20.71 43.33,22.11 43.98,22.75 46.26,22.75 46.9,23.39 46.9,24.35 49.08,26.54 49.08,29.87 54.76,35.55 54.76,40.27 53.46,41.57 49.48,41.57 43.33,47.72 40.44,47.72 40.06,48.1 40.06,54.92 39.66,55.31 39.66,58.85 39.01,59.5 39.01,63.89 38.15,64.75 38.15,70.88 39.62,72.36 39.62,85.67 37.99,87.31 37.99,97.92 42.93,102.86 42.93,113.77 42.65,114.05 42.65,122.09 44.12,123.56 44.12,128.13 v1(43.98,128.27)
  L04_PWR1 w0.508: v1(33.89,17.26) 32.58,15.94 32.58,14.12 33.29,13.41 35.68,13.41 36.06,13.79 46.35,13.79 47.06,14.5 47.06,17.16 45.39,18.82 v1(45.21,18.82)
  BOTTOM w0.14: R673.1 v1(45.21,18.82)
  BOTTOM w0.191: R674.1 34.75,17.45 34.56,17.26 v1(33.89,17.26) ; v1(43.98,128.27) 45.7,128.27 46.46,127.51 49.13,127.51 50.16,128.55 v1(55.16,128.55)
SOC_USB0_RCALIB: length 2.4
  TOP w0.132: U47.W10 v1(81.96,78.39)
  BOTTOM w0.14: R553.1 81.49,79.72 81.49,78.86 v1(81.96,78.39)
SOC_USB0_VBUS: length 103.3
  TOP w0.356: U47.V8 v1(81.16,76.79)
  TOP w0.381: R398.1 52.75,13.44 v1(52.39,13.8)
  L03_SIG01 w0.14: 84.03,76.39 81.56,76.39 v1(81.16,76.79)
  L03_SIG01 w0.254: 84.03,76.39 84.58,76.39 85.03,76.84 87.14,76.84 88.37,75.61 88.37,60.91 87.17,59.72 85.85,59.72 81.86,55.73 81.86,55.01 79.33,52.48 79.33,49.25 76.62,46.54 75.48,46.54 73.18,44.24 73.18,36.72 69.42,32.96 66.39,32.96 65.82,32.39 65.82,26.92 64.31,25.41 59.26,25.41 58,24.16 55.83,24.16 52.8,21.12 50.3,21.12 49.08,19.9 49.08,17.18 47.67,15.78 47.67,13.65 48.68,12.64 51.24,12.64 v1(52.39,13.8)
  BOTTOM w0.305: R560.1 81.28,76.91 v1(81.16,76.79)
SOC_USB1_DM: length 81.4
  TOP w0.102: U47.Y11 v1(82.76,79.19)
  TOP w0.119: R393.1 L9.1 64.65,21.6 64.89,21.84 64.89,21.9 64.89,21.9 64.89,22.74 v1(64.72,22.91)
  L03_SIG01 w0.089: v1(64.72,22.91) 64.88,22.75 64.88,22.09 65.19,21.78 69.03,21.78 75.79,28.54 75.79,32.88 79.98,37.07 79.98,47.76 90.33,58.11 90.33,77.51 88.82,79.02 86.27,79.02 85.94,79.34 84.06,79.34 83.81,79.6 83.16,79.6 v1(82.76,79.19)
SOC_USB1_DP: length 81.4
  TOP w0.102: U47.Y10 v1(82.76,78.39)
  TOP w0.119: R394.1 L9.4 65.5,21.6 65.11,22 65.11,22.79 65.23,22.91 v1(65.43,22.91)
  L03_SIG01 w0.089: v1(65.43,22.91) 65.22,22.91 65.11,22.8 65.11,22.18 65.29,22.01 65.39,22.01 65.48,22.1 65.48,22.21 65.56,22.29 65.68,22.29 65.77,22.21 65.77,22.1 65.85,22.01 65.98,22.01 66.06,22.1 66.06,22.21 66.15,22.29 66.27,22.29 66.35,22.21 66.35,22.1 66.44,22.01 68.93,22.01 75.56,28.64 75.56,32.98 79.74,37.16 79.74,47.86 90.09,58.21 90.09,77.42 88.73,78.78 86.17,78.78 85.84,79.11 84.06,79.11 84.05,79.1 84.03,79.1 83.72,78.79 83.39,78.79 83.39,78.79 83.16,78.79 82.76,78.39 v1(82.76,78.39)
SOC_USB1_DRVVBUS: length 48.5
  TOP w0.132: U47.D19 v1(69.16,86.39)
  TOP w0.191: v1(57.64,125.72) 57.08,125.72 56.86,125.94 U24.4
  L03_SIG01 w0.076: v1(69.16,86.39) 69.16,86.45 68.76,86.86 68.76,87.33 68.43,87.65 65.45,87.65 63.52,89.58 63.52,91.84 63.83,92.14 63.83,97.47 63.3,98 63.3,99.09 59.39,103 59.39,106.83 58.65,107.57 58.65,108.9 58.09,109.46 58.09,113.85 58.38,114.14 58.38,117.12 58.22,117.27 58.22,120.62 57.13,121.71 57.13,124.14 57.64,124.65 v1(57.64,125.72)
SOC_USB1_DRVVBUS_3V3: length 149.9
  TOP w0.191: U24.1 55.36,127.16 v1(55.14,127.38) ; R379.1 v1(58.79,26.95)
  L03_SIG01 w0.076: v1(58.79,26.95) 59.53,26.21 64.14,26.21 65.34,27.4 65.34,29.64 63.95,31.03 63.95,35.72 60.78,38.89 60.78,46.04 61.62,46.88 61.62,51.4 57.18,55.83 57.01,55.83 56.57,56.27 56.57,60.6 54.57,62.6 51.48,62.6 51.17,62.29 50.39,62.29 49.04,60.95 49.04,60.77 48.81,60.54 44.93,60.54 44.75,60.72 42.14,60.72 41.69,60.26 41.36,60.26 41.13,60.49 41.13,63.09 43.86,65.82 43.86,73.91 42.31,75.45 42.31,78.28 43.97,79.93 47.5,79.93 48.3,80.74 48.3,85.73 45.73,88.3 45.73,90.72 44.9,91.55 44.9,126.93 v1(45.34,127.37)
  BOTTOM w0.191: v1(45.34,127.37) 45.7,127.02 49.46,127.02 50.52,128.07 54.45,128.07 v1(55.14,127.38)
SOC_USB1_RCALIB: length 7
  TOP w0.132: U47.U7 v1(80.36,75.99)
  L05_SIG02 w0.127: v1(84.67,78.61) 84.04,77.98 82.6,77.98 82.37,77.75 82.37,77.45 82.1,77.18 81.8,77.18 81.57,76.95 81.57,76.94 81.55,76.92 81.55,76.63 81.32,76.4 81.03,76.4 81.02,76.39 80.76,76.39 v1(80.36,75.99)
  BOTTOM w0.254: R557.1 85.05,78.99 v1(84.67,78.61)
SOC_USB1_VBUS: length 93.8
  TOP w0.254: v1(97.72,54.99) 94.15,54.99 90.33,58.81 90.33,75.45 89.15,76.63 86.94,76.63 v1(86.55,76.23) ; U47.V6 v1(81.16,75.19) ; v1(99.1,45.16) 99.1,43.11 97.58,41.6 97.58,39.35 98.67,38.26 98.67,33.16 96.72,31.2 87.99,31.2 87.81,31.02 84.33,31.02 78.69,25.38 69.45,25.38 69.2,25.13 R384.1
  L03_SIG01 w0.254: v1(97.72,54.99) 99.1,53.62 v1(99.1,45.16)
  L05_SIG02 w0.152: v1(81.16,75.19) 81.56,75.59 85.91,75.59 v1(86.55,76.23)
  BOTTOM w0.305: v1(81.16,75.19) 81.28,75.31 R567.1
SOC_VDDSHV5_SDIO: length 2.7
  TOP w0.356: U47.H15 v1(72.36,83.19) ; U47.G16 v1(71.56,83.99)
  TOP w0.381: R243.2 v1(54.27,84.63)
  BOTTOM w0.254: v1(54.27,84.63) 54.27,84.57 54.01,84.32 C436.1
  BOTTOM w0.305: C438.1 71.44,83.87 v1(71.56,83.99)
SOC_WARM_RESETZ: length 86.5
  TOP w0.132: U47.E19 v1(69.96,86.39)
  TOP w0.191: U50.5 R279.1 TP57.1 30.53,72.82 29.86,73.49 28.96,74.39 27.11,74.39 26.3,75.2 26.3,78.72 27.88,80.3 31.36,80.3 v1(31.99,79.67)
  L03_SIG01 w0.076: v1(31.99,79.67) 31.99,81.5 32.44,81.96 32.44,89.51 33.81,90.89 36.48,90.89 36.78,91.19 36.78,93.35 35.27,94.86 v1(32.46,94.86)
  BOTTOM w0.14: 63.04,90.22 64.37,88.89 68.46,88.89 69.56,87.8 69.56,86.79 v1(69.96,86.39)
  BOTTOM w0.191: v1(32.46,94.86) 33.37,94.86 35.14,93.08 39.46,93.08 40.11,93.73 46.64,93.73 47.14,93.24 47.69,93.24 48.47,94.02 50.51,94.02 51.8,92.73 61.68,92.73 63.04,91.38 63.04,90.22
SPI_HOLDN: length 1.8
  TOP w0.191: U69.7 43.23,28.64 43.63,28.23 R374.2
SPI_WPN: length 1.5
  TOP w0.14: U69.3 R378.2
SS_LM5141: length 2
  BOTTOM w0.191: C628.1 16.72,22.64 17.15,22.2 U128.22
SW_LM5141: length 1.4
  BOTTOM w0.254: 23,20.7 U128.12
  vias: v1(22.91,20.76) v1(22.91,20.12) v1(22.91,19.49) v1(22.91,18.85) v1(22.98,14.34) v1(22.98,13.7) v1(22.98,13.07) v1(23.42,20.76) v1(23.42,20.12) v1(23.42,19.49) v1(23.42,18.85) v1(23.61,14.34) v1(23.61,13.7) v1(23.61,13.07) v1(23.92,20.76) v1(25.29,20.81) v1(26.2,19.62) v1(26.2,18.98) v1(26.2,18.35) v1(26.2,17.71) v1(26.71,19.62) v1(26.71,18.98) v1(26.71,18.35) v1(26.71,17.71) v1(27.22,18.98) v1(27.22,18.35) v1(27.22,17.71)
SYS_BOOTMODE0: length 16.1
  TOP w0.191: SW2.1 v1(104,106.83) R153.1
  L03_SIG01 w0.076: v1(104,106.83) 104.61,107.44 105.8,107.44 109.57,111.21 109.57,112.29 v1(111.42,114.14)
  BOTTOM w0.191: U81.10 v1(111.42,114.14) U82.1
SYS_BOOTMODE1: length 15.4
  TOP w0.191: R154.1 v1(105.27,106.83) SW2.2
  L03_SIG01 w0.076: v1(112.26,113.64) 111.32,113.64 109.89,112.2 109.89,111.24 105.48,106.83 v1(105.27,106.83)
  BOTTOM w0.191: U82.2 v1(112.26,113.64) U81.9
SYS_BOOTMODE2: length 13.4
  TOP w0.191: R155.1 v1(106.54,106.83) SW2.3
  L03_SIG01 w0.076: v1(111.42,113.14) 110.39,112.11 110.39,111.44 106.54,107.59 v1(106.54,106.83)
  BOTTOM w0.191: U82.3 v1(111.42,113.14) U81.8
SYS_BOOTMODE3: length 12.9
  TOP w0.191: R156.1 v1(107.81,106.83) SW2.4
  L03_SIG01 w0.076: v1(112.26,112.64) 112.26,112.27 111.62,111.64 111.34,111.64 107.81,108.1 v1(107.81,106.83)
  BOTTOM w0.191: U82.4 v1(112.26,112.64) U81.7
SYS_BOOTMODE4: length 14.4
  TOP w0.191: SW2.5 v1(109.08,106.83) R157.1
  L03_SIG01 w0.076: v1(111.42,112.14) 107.17,107.89 107.17,106.76 107.5,106.43 108.68,106.43 v1(109.08,106.83)
  BOTTOM w0.191: U82.5 v1(111.42,112.14) U81.6
SYS_BOOTMODE5: length 12.5
  TOP w0.191: R158.1 v1(110.35,106.83) SW2.6
  L03_SIG01 w0.076: v1(112.26,111.64) 112.26,111.27 111.72,110.73 111.72,110.28 112.17,109.83 112.17,106.74 111.85,106.43 110.75,106.43 v1(110.35,106.83)
  BOTTOM w0.191: U81.5 v1(112.26,111.64) U82.6
SYS_BOOTMODE6: length 9.5
  TOP w0.191: SW2.7 v1(111.62,106.83) R159.1
  L03_SIG01 w0.076: v1(111.42,111.14) 111.42,109.98 111.62,109.78 v1(111.62,106.83)
  BOTTOM w0.191: U82.7 v1(111.42,111.14) U81.4
SYS_BOOTMODE7: length 9.1
  TOP w0.191: SW2.8 v1(112.89,106.83) R160.1
  L03_SIG01 w0.076: v1(112.89,106.83) 112.89,110.01 v1(112.26,110.64)
  BOTTOM w0.191: U81.3 v1(112.26,110.64) U82.8
SYS_BOOTMODE8: length 36.7
  TOP w0.191: SW1.1 v1(91.49,106.83) R145.1
  BOTTOM w0.191: U82.9 109.01,108.33 109.75,107.59 109.75,106.77 108.9,105.91 106.34,105.91 105.63,105.2 101.69,105.2 100.61,106.28 92.04,106.28 v1(91.49,106.83) 92.13,107.48 93.48,107.48 93.74,107.73 99.89,107.73 100.59,108.43 100.59,109.79 100.4,109.98 U83.10
SYS_BOOTMODE9: length 30.2
  TOP w0.191: R146.1 SW1.2 92.76,108.31 91.82,109.25 91.82,109.52 91.82,111.28 92.7,112.16 93.01,112.16 95.97,112.16 96.51,112.16 97.5,111.17 98.14,111.17 98.71,111.74 99.43,111.74 v1(100.69,110.48)
  BOTTOM w0.191: U83.9 v1(100.69,110.48) 100.97,110.21 100.97,108.85 103.49,106.32 108.05,106.32 108.51,106.78 U82.10
SYS_BOOTMODE10: length 29.4
  TOP w0.191: R147.1 SW1.3 94.03,108.26 92.2,110.09 92.2,111.13 92.86,111.78 95.81,111.78 96.62,110.97 96.62,109.94 97.12,109.44 100.17,109.44 100.53,109.8 101.25,109.8 v1(101.51,110.06)
  BOTTOM w0.191: U83.8 100.51,110.98 100.53,110.96 101.06,110.96 101.51,110.51 v1(101.51,110.06) 101.51,109.46 103.6,107.36 107.38,107.36 108.01,108 U82.11
SYS_BOOTMODE11: length 20.7
  TOP w0.191: R148.1 v1(95.3,106.83) SW1.4
  L03_SIG01 w0.076: v1(95.3,106.83) 95.41,106.83 96.38,107.81 97.49,107.81 100.06,110.38 100.06,110.84 v1(100.69,111.48)
  BOTTOM w0.191: U83.7 v1(100.69,111.48) 101.32,111.48 102.38,110.42 102.38,109.32 103.84,107.86 106.75,107.86 107.51,108.63 U82.12
SYS_BOOTMODE12: length 22.1
  TOP w0.191: SW1.5 v1(96.57,106.83) R149.1
  L03_SIG01 w0.076: v1(96.57,106.83) 96.98,106.43 98.12,106.43 101.27,109.59 101.59,109.59 101.91,109.9 101.91,110.64 101.59,110.95 v1(101.59,112.02)
  BOTTOM w0.191: U82.13 107.01,108.9 106.42,108.31 104.02,108.31 102.86,109.47 102.86,111.53 102.41,111.98 101.64,111.98 v1(101.59,112.02) 101.55,111.98 U83.6
SYS_BOOTMODE13: length 19.3
  TOP w0.191: SW1.6 v1(97.84,106.83) R150.1
  L03_SIG01 w0.076: v1(97.84,106.83) 97.84,106.95 101.32,110.43 101.32,111.7 100.69,112.33 v1(100.69,112.48)
  BOTTOM w0.191: U82.14 106.51,109.09 106.24,108.82 104.26,108.82 103.25,109.82 103.25,111.69 102.36,112.57 101.4,112.57 101.31,112.48 v1(100.69,112.48) U83.5
SYS_BOOTMODE14: length 19.4
  TOP w0.191: R151.1 v1(99.11,106.83) SW1.7
  L03_SIG01 w0.076: v1(99.11,106.83) 99.35,106.83 102.2,109.68 102.2,110.69 101.98,110.92 101.98,111.49 102.05,111.56 102.05,112.82 v1(101.65,113.22)
  BOTTOM w0.191: U82.15 106.01,109.43 105.78,109.2 104.47,109.2 103.63,110.03 103.63,111.85 102.26,113.22 v1(101.65,113.22) 101.41,112.98 U83.4
SYS_BOOTMODE15: length 17.8
  TOP w0.191: R152.1 SW1.8 100.38,109.06 100.57,109.25 101.36,109.25 101.96,109.86 101.96,110.85 101.14,111.67 101.14,112.21 101.27,112.34 101.27,112.9 v1(100.69,113.48)
  BOTTOM w0.191: U82.16 104.37,109.89 104.07,110.19 104.07,112.78 103.07,113.78 101.42,113.78 101.12,113.48 v1(100.69,113.48) U83.3
SYSBOOT_BUF_ENZ: length 176
  TOP w0.191: U23.1 92.31,130.08 92.12,129.89 v1(91.8,129.89) ; v1(64.61,27.23) 65.19,26.66 69.2,26.66 69.89,27.35 R377.1 R376.1
  L03_SIG01 w0.076: v1(44.1,131.98) 44.72,131.35 44.72,101.39 42.39,99.06 42.39,86.95 41.78,86.33 41.78,74.52 43.33,72.97 43.33,66.04 40.6,63.31 40.6,59.81 41.43,58.97 42.44,58.97 44.46,56.96 44.46,53.06 52.98,44.53 52.98,43.45 56.04,40.39 56.04,37.81 60.98,32.86 60.98,30.86 v1(64.61,27.23)
  BOTTOM w0.191: v1(91.8,129.89) 91.66,129.76 85.96,129.76 85.76,129.56 74.39,129.56 73.34,130.61 60.91,130.61 59.47,132.05 44.17,132.05 v1(44.1,131.98)
TAD1_ADDR1: length 3
  TOP w0.191: R37.2 R29.2 103.37,162.24 103.37,162.69 103.28,162.78 U5.13
TAD1_DREG_OUT: length 2.5
  TOP w0.254: C42.1 C45.1 97.81,165.53 98.06,165.28 U5.1
TAD1_GPI1: length 1.7
  TOP w0.191: U5.12 102.01,161.32 102.39,160.95 R31.1
TAD1_MICBIAS: length 1.4
  TOP w0.191: C66.1 103.83,162.78 103.33,163.28 U5.14
TAD1_VREF: length 3.6
  TOP w0.191: C38.1 98.9,167.46 99.51,166.84 U5.24
TAD2_ADDR2: length 3.4
  TOP w0.191: R36.2 106.73,160.86 R33.2 106.7,161.14 106.3,161.55 v1(106.3,162.11)
  BOTTOM w0.191: v1(106.3,162.11) 106.3,162.59 106.49,162.78 U77.13
TAD2_DREG_OUT: length 2.5
  BOTTOM w0.254: U77.1 110.79,165.29 111.43,165.29 111.67,165.53 C358.1 C356.1
TAD2_GPI1: length 2.4
  BOTTOM w0.191: U77.12 107.54,162.02 107.54,161.4 107.41,161.26 R429.1
TAD2_MICBIAS: length 1.4
  BOTTOM w0.191: C370.1 105.87,162.78 105.87,162.8 106.35,163.28 U77.14
TAD2_VREF: length 1.5
  BOTTOM w0.191: C354.1 110.31,167 110.03,166.72 U77.24
TAD3_ADDR3: length 4
  TOP w0.191: U6.13 120.6,162.78 120.71,162.67 120.71,162.19 121.27,161.63 121.27,161.19 121.57,160.89 R30.1 122.19,160.89 122.47,160.62 R35.1
TAD3_DREG_OUT: length 2.5
  TOP w0.254: U6.1 115.2,165.28 C46.1 C43.1
TAD3_GPI3: length 1.4
  TOP w0.145: U6.12 119.41,161.75 R32.1
TAD3_MICBIAS: length 1.4
  TOP w0.191: U6.14 120.73,163.28 121.23,162.78 C67.1
TAD3_VREF: length 3.5
  TOP w0.254: U6.24 116.91,166.49 116.62,166.78 115.52,166.78 114.61,167.68 C35.1
TAD4_ADDR4: length 2.4
  TOP w0.191: v1(123.69,162.31) 123.51,162.13 R27.1 124.6,161.84 R28.1
  BOTTOM w0.191: U76.13 124.17,162.78 v1(123.69,162.31)
TAD4_DREG_OUT: length 2.5
  BOTTOM w0.254: C355.1 C357.1 128.94,165.53 128.69,165.28 U76.1
TAD4_GPI4: length 1.4
  BOTTOM w0.191: U76.12 124.93,161.28 124.74,161.09 R430.1
TAD4_MICBIAS: length 1.3
  BOTTOM w0.191: U76.14 123.65,163.28 C369.1
TAD4_VREF: length 1.5
  BOTTOM w0.191: C353.1 127.71,167 127.43,166.72 U76.24
TAD5212_1_DIN: length 77.2
  TOP w0.191: v1(96.2,163.12) 97.83,163.12 97.99,163.28 U5.5
  L03_SIG01 w0.076: v1(78.26,102.68) 78.26,105.33 82.12,109.19 82.12,112.28 83.83,113.99 84.22,113.99 85.38,115.15 85.38,124.31 82.04,127.65 82.04,140.69 83.29,141.94 83.29,143.3 82.49,144.09 82.49,151.94 94.1,163.55 95.77,163.55 v1(96.2,163.12)
  BOTTOM w0.191: R479.1 78.53,103.39 78.26,103.12 v1(78.26,102.68)
TAD5212_1_DIN_R: length 2
  BOTTOM w0.191: R479.2 78.53,104.32 78.53,105.05 78.7,105.21 U84.18
TAD5212_2_DIN: length 91.1
  L03_SIG01 w0.076: v1(77.75,103.19) 77.75,105.27 79.82,107.34 79.82,107.92 81.78,109.88 81.78,112.58 83.32,114.12 83.32,115.2 85.2,117.08 85.2,124.09 81.74,127.54 81.74,141.02 82.38,141.66 82.38,142.17 82.19,142.36 82.19,151.89 94.03,163.73 97.6,163.73 98.67,162.66 111.71,162.66 v1(112.18,163.13)
  BOTTOM w0.191: R478.1 v1(77.75,103.19) ; U77.5 112.02,163.28 v1(112.18,163.13)
TAD5212_2_DIN_R: length 2.2
  BOTTOM w0.191: R478.2 77.75,104.85 78.2,105.29 U84.19
TAD5212_3_DIN: length 95.3
  TOP w0.145: U6.5 115.14,163.28 v1(114.79,162.93)
  L03_SIG01 w0.076: v1(76.48,103.65) 76.48,104.4 78.66,106.58 78.66,111.86 79.74,112.95 80.7,112.95 85,117.25 85,123.89 81.44,127.45 81.44,142.18 81.08,142.54 81.08,151.03 85.61,155.57 85.62,155.57 93.97,163.92 98,163.92 99.07,162.85 110.66,162.85 111.47,163.66 113.72,163.66 114.42,162.96 114.76,162.96 114.79,162.93 v1(114.79,162.93)
  BOTTOM w0.191: R477.1 76.61,103.77 v1(76.48,103.65)
TAD5212_3_DIN_R: length 2.3
  BOTTOM w0.191: U84.20 77.7,106.28 77.7,105.44 76.97,104.71 R477.2
TAD5212_4_DIN: length 114.5
  L03_SIG01 w0.076: v1(129.41,163.03) 129.18,162.8 116.9,162.8 116.63,162.8 115.72,163.71 114.95,163.71 112.98,165.68 107.1,165.68 106.44,165.02 104.03,165.02 103.37,165.68 99.5,165.68 98.3,164.48 92.33,164.48 80.86,153.01 80.86,126.44 84.61,122.69 84.61,117.36 81.75,114.5 80.02,114.5 77.36,111.84 77.36,106.8 74.9,104.33 74.9,103.75 v1(75.12,103.52)
  BOTTOM w0.191: v1(75.12,103.52) 74.96,103.52 74.44,104.05 R475.1 ; v1(129.41,163.03) 129.16,163.28 U76.5
TAD5212_4_DIN_R: length 4.5
  BOTTOM w0.191: U84.21 77.21,106.27 77.21,105.42 76.43,104.64 76.43,104.21 76.06,103.83 75.42,103.83 75,104.26 R475.2
TAD5212_MCASP2_ACLKX: length 135.5
  TOP w0.191: U6.2 v1(114.58,164.78) ; v1(97.22,164.97) 97.64,164.97 97.84,164.78 U5.2
  L03_SIG01 w0.076: v1(134.28,165.51) 133.26,164.49 127.85,164.49 126.92,165.43 124.68,165.43 124.11,164.86 121.84,164.86 121.39,165.31 117.24,165.31 115.81,163.89 115.1,163.89 114.58,164.41 v1(114.58,164.78) 113.5,165.85 99.08,165.85 98.18,164.96 97.23,164.96 v1(97.22,164.97) 96.95,164.7 91.99,164.7 79.74,152.46 79.74,147.6 76.18,144.03 76.18,141.47 76.99,140.66 76.99,138.2 77.69,137.5 77.69,128.26 83.08,122.86 83.08,121.7 78.96,117.58 75.19,117.58 74.65,117.04 74.65,115.6 74.04,114.99 74.04,114.29 74.63,113.69 75.32,113.69 75.63,113.39 75.63,112.94 75.19,112.51 75.19,106.57 74.9,106.28 v1(74.9,106.26)
  BOTTOM w0.191: R474.1 74.44,105.82 74.88,106.26 v1(74.9,106.26) ; v1(134.28,165.51) 134.27,165.53 R418.2 R419.1 131.19,164.78 U76.2 ; U77.2 v1(114.58,164.78)
TAD5212_MCASP2_AFSX: length 140.1
  TOP w0.145: U6.3 v1(115.34,164.28)
  TOP w0.191: v1(95.29,165.14) 96.15,164.28 U5.3
  L03_SIG01 w0.076: v1(132.59,164.94) 132.05,165.47 128.31,165.47 127.86,165.92 117.42,165.92 115.78,164.28 v1(115.34,164.28) 115.34,164.72 113.79,166.26 112.13,166.26 111.43,166.96 98.17,166.96 96.35,165.14 v1(95.29,165.14) ; v1(69.84,105.03) 70.08,105.27 70.08,106.9 70.49,107.31 70.49,109.23 69.19,110.53 69.19,115.48 68.88,115.79 68.88,119.95 73,124.07 73,142.12 72.32,142.79 72.32,151.42 74.32,153.41 74.32,158.9 74.87,159.45 74.87,159.93 74.7,160.11 74.7,162.21 v1(75.15,162.66)
  BOTTOM w0.191: v1(132.59,164.94) 132.92,164.61 R422.2 R423.1 131.58,164.28 U76.3 ; v1(95.29,165.14) 94.12,165.14 91.84,162.85 85.47,162.85 85.08,162.85 84.08,163.86 77.25,163.86 76.05,162.66 v1(75.15,162.66) ; v1(69.84,105.03) 70.01,105.03 70.27,105.29 R472.2 ; U77.3 v1(115.34,164.28)
TCA6424_EXP_INT: length 2
  BOTTOM w0.191: R457.1 109.9,115.68 109.23,115.68 109.01,115.46 U82.32
TEST_GPIO1: length 179.2
  TOP w0.191: v1(117.1,87.21) R235.1 116.58,86.39 116.37,86.18 114.36,86.18 112.72,84.54 v1(112.72,82.18) ; v1(37.89,34.37) 40.68,31.57 47.02,31.57 47.21,31.76 47.21,33.16 v1(48.91,34.86)
  L03_SIG01 w0.076: v1(32.07,75.91) 32.07,74.61 31.46,74 31.46,60.35 36.45,55.36 36.45,51.97 36.17,51.7 36.17,36.09 v1(37.89,34.37) ; v1(112.72,82.18) 112.72,81.67 105.98,74.93 105.98,71 106.68,70.3 106.68,59.8 v1(106.15,59.28)
  BOTTOM w0.191: v1(106.15,59.28) 110.52,59.28 113.47,56.32 113.47,53.76 112.23,52.52 94.8,52.52 92.02,49.74 90.59,49.74 86.95,46.1 84.48,46.1 83.15,44.76 80.47,44.76 79.19,43.49 68.68,43.49 60.18,34.99 49.04,34.99 v1(48.91,34.86) ; Q7.1 31.61,76.37 v1(32.07,75.91) ; v1(117.1,87.21) R235.1
TEST_GPIO2: length 91.8
  TOP w0.191: R285.2 R283.1 v1(111.28,68.37) ; v1(102.52,143.92) 102.73,143.71 U21.18
  L03_SIG01 w0.076: v1(101.7,90.52) 101.7,91.71 101.46,91.95 101.46,94.58 101.93,95.05 v1(101.93,96.65) ; v1(99.48,105.02) 99.48,105.21 98.48,106.22 96.36,106.22 96.08,106.5 96.08,107.19 96.45,107.57 97.59,107.57 100.3,110.28 100.3,110.68 100.66,111.04 100.81,111.04 101.09,111.31 101.09,111.64 100.86,111.87 100.56,111.87 100.24,112.19 100.24,117.16 101.04,117.97 101.04,126.33 100.58,126.8 100.58,141.97 v1(102.52,143.92)
  BOTTOM w0.191: v1(101.93,96.65) 101.93,100.85 99.53,103.25 99.53,104.97 v1(99.48,105.02) ; v1(111.28,68.37) 111.32,68.37 112,69.05 112,77.93 100.86,89.08 100.86,89.68 v1(101.7,90.52)
TEST_GPIO3: length 105.7
  TOP w0.191: v1(99.07,128.56) 94.17,128.56 93.26,129.47 U23.2 93.26,131.62 92.67,132.2 91.57,132.2 91.37,132.4 91.37,136.91 91.98,137.52 J10.1 ; R227.1 v1(117.14,88.1)
  L03_SIG01 w0.076: v1(117.14,88.1) 116.55,88.7 116.55,93.78 v1(116.2,94.13) ; v1(124.62,117.05) 129.81,117.05 131.22,118.46 131.22,120.45 130.34,121.32 110.65,121.32 106.66,125.32 v1(106.66,130.09)
  BOTTOM w0.191: v1(124.62,117.05) 123.65,116.08 123.65,103.31 121.45,101.11 119.04,101.11 118.76,100.84 117.99,100.06 117.99,98.87 115.9,96.78 115.9,94.43 v1(116.2,94.13) ; v1(99.07,128.56) 99.27,128.56 101.34,130.63 102.91,130.63 103.45,130.09 v1(106.66,130.09) ; R227.1 v1(117.14,88.1) ; R439.1 J10.1
TEST_GPIO4: length 76.7
  TOP w0.191: R221.1 v1(117.14,88.99)
  L03_SIG01 w0.076: v1(126.19,114.46) 126.19,113.4 125.81,113.02 124.84,113.02 124.2,113.66 124.2,117.26 124.5,117.56 128.83,117.56 129.55,118.28 130.01,118.74 130.01,120.46 129.42,121.05 117.72,121.05 116.28,119.62 107.27,119.62 v1(106.74,119.08) ; v1(117.14,88.99) 117.62,89.47 v1(117.62,94.71)
  BOTTOM w0.191: v1(117.62,94.71) 117,95.33 117,96.06 117.29,96.35 117.77,96.35 119.31,97.89 119.31,99.28 120.27,100.25 121.89,100.25 124.42,102.78 124.42,113.64 125.2,114.41 126.14,114.41 v1(126.19,114.46) ; R221.1 v1(117.14,88.99) ; v1(106.74,119.08) 107.27,118.55 107.27,117.65 107.01,117.4 U82.28
TEST_PORZN: length 10.5
  TOP w0.191: U43.6 101.33,84.77 101.61,84.49 104.63,84.49 105.39,85.25 105.39,88.83 v1(105.95,89.39) R219.1
  BOTTOM w0.145: R219.1 v1(105.95,89.39)
TEST_POWERDOWN: length 224.7
  TOP w0.191: R233.1 v1(105.95,87.61) ; v1(35.51,83.92) 35.3,83.71 35.3,82.49 35.05,82.25 32.54,82.25 30.99,80.7 27.74,80.7 25.86,78.82 25.86,75.1 26.95,74.01 28.8,74.01 29.21,73.6 29.35,73.46 29.35,70.92 29.05,70.62 25.66,70.62 24.75,69.71 U52.1
  L03_SIG01 w0.076: v1(105.63,61.48) 106.18,62.03 106.18,70.04 105.58,70.64 105.58,75.33 112.02,81.78 112.02,83.2 109.3,85.92 108.74,85.92 107.05,87.61 v1(105.95,87.61) ; v1(38.59,83.92) 39.17,83.34 39.17,73.04 37.03,70.9 37.03,62.39 37.8,61.61 37.8,58.98 38.94,57.84 38.94,56.53 38.54,56.12 38.54,54.54 39.19,53.9 39.19,50.57 38.78,50.17 38.78,48.6 40.63,46.76 44.01,46.76 49.57,41.2 53.49,41.2 54.39,40.29 54.39,36.71 v1(54.03,36.35) 52.84,35.15 50.89,35.15 48.5,32.76 v1(48.5,26.72)
  BOTTOM w0.14: v1(48.5,26.72) 48.5,26.32 48.73,26.09 R647.1
  BOTTOM w0.145: R233.1 v1(105.95,87.61)
  BOTTOM w0.191: v1(38.59,83.92) 38.18,84.33 35.92,84.33 v1(35.51,83.92) ; v1(105.63,61.48) 105.18,61.03 105.18,59.4 106.48,58.11 110.85,58.11 112.95,56 112.95,54.09 111.76,52.9 94.49,52.9 91.77,50.18 90.45,50.18 86.75,46.48 84.32,46.48 83.55,45.72 80.5,45.72 78.65,43.87 67.84,43.87 66.54,45.17 64.15,45.17 63.78,44.79 63.05,44.79 61.69,43.43 61.69,38.68 59.93,36.92 54.61,36.92 v1(54.03,36.35)
TEST_WARMRESETN: length 194.7
  TOP w0.191: v1(50.74,34.26) 50.74,33.29 48.59,31.15 40.05,31.15 v1(37.73,33.47) ; R224.1 v1(105.95,88.5)
  L03_SIG01 w0.076: v1(32,82.71) 30.9,81.61 30.9,74.41 31.28,74.02 31.28,60.12 36,55.4 36,53.81 35.65,53.46 35.65,51.26 35.96,50.95 35.96,35.87 37.42,34.41 37.42,33.78 v1(37.73,33.47) ; v1(106.2,60.51) 106.41,60.72 106.41,70.25 105.8,70.86 105.8,75.17 112.27,81.64 112.27,83.71 107.48,88.5 v1(105.95,88.5)
  BOTTOM w0.145: R224.1 v1(105.95,88.5)
  BOTTOM w0.191: v1(50.74,34.26) 51.05,34.57 60.32,34.57 64.97,39.22 73.81,39.22 76.28,36.75 77.97,36.75 79.63,38.4 79.63,43.18 80.82,44.37 83.32,44.37 84.67,45.72 87.2,45.72 90.18,48.7 92.12,48.7 95.03,51.61 112.21,51.61 114.07,53.46 114.07,56.76 110.32,60.51 v1(106.2,60.51) ; Q6.1 31.43,83.28 v1(32,82.71)
TIMER_IO7: length 139.3
  TOP w0.132: U47.C15 v1(68.36,83.19)
  TOP w0.191: v1(127.76,123.56) 127.76,119 127.39,118.64 127.39,112.54 127.58,112.35 J13.52
  L03_SIG01 w0.076: v1(53.6,119.28) 53.6,115.61 54.92,114.29 54.92,109.39 55.54,108.77 55.54,107.28 55.01,106.76 55.01,101.33 57.98,98.36 57.98,88.25 60.33,85.9 60.33,85.43 61.1,84.66 65.66,84.66 67.13,83.19 v1(68.36,83.19)
  BOTTOM w0.191: v1(53.6,119.28) 53.79,119.47 59.89,119.47 60.56,120.14 70.29,120.14 74.91,124.76 84.42,124.76 86.23,122.95 96.51,122.95 98.67,125.11 119.76,125.11 121.58,123.3 125.02,123.3 125.32,122.99 126.23,122.99 126.8,123.56 v1(127.76,123.56)
TM4C129_TCK: length 2.7
  TOP w0.191: U48.100 120.6,66.85 TP66.1
TM4C129_TDI: length 2.4
  TOP w0.191: U48.98 119.8,68.32 TP64.1
TM4C129_TDO: length 2.7
  TOP w0.191: TP62.1 118.77,67.92 119.4,68.55 U48.97
TM4C129_TMS: length 1.8
  TOP w0.191: TP63.1 120.2,67.97 U48.99
TMP1_ADD0: length 1.2
  TOP w0.191: U44.5 93.98,88.09 R226.1
TMP1_ADD1: length 1.2
  TOP w0.191: U44.3 94.93,83.11 R247.1
TMP2_ADD0: length 2.8
  TOP w0.191: U63.5 71.81,47.43 71.57,47.19 69.77,47.19 R339.2
TMP2_ADD1: length 1.2
  TOP w0.191: R325.1 U63.3
TPS65224_EN: length 110
  TOP w0.191: TP81.1 51.09,58.21 v1(50.73,58.57) 50.71,58.54 49.53,58.54 49.26,58.81 R317.1 ; v1(29.38,65.07) 29.45,65 R303.1 Q4.2
  L03_SIG01 w0.076: v1(29.38,65.07) 30.03,64.43 30.03,62.43 28.12,60.53 28.12,50.32 27.11,49.3 27.11,38.71 28.3,37.52 28.3,36.64 27.8,36.14 27.8,33.97 28.26,33.51 33.22,33.51 v1(33.43,33.3) ; v1(50.73,58.57) 50.39,58.23 50.39,55.86 51.05,55.2 52.84,55.2 54.35,53.7 54.35,44.87 56.44,42.77 56.44,37.66 57.98,36.12 61.12,36.12 v1(63.55,33.69)
  BOTTOM w0.191: v1(63.55,33.69) 62.91,33.04 52.89,33.04 52.07,32.22 48.19,32.22 47.7,31.74 41.9,31.74 39.72,33.92 34.05,33.92 v1(33.43,33.3)
UART4_RXD: length 224.9
  TOP w0.132: U47.T19 v1(79.56,86.39)
  L03_SIG01 w0.076: v1(42.06,137.26) 41.79,136.98 41.79,131.66 43.06,130.39 43.06,126.02 41.67,124.63 41.67,112.94 28.37,99.64 28.37,76.28 28.98,75.66 28.98,70.73 30.51,69.21 30.51,47.91 31.8,46.62 v1(31.8,43.03) ; v1(79.56,86.39) 79.56,86.39 79.98,86.81 79.98,88.42 83.51,91.95 87.05,91.95 87.69,91.31 92.23,91.31 v1(95.59,94.67) ; v1(97.92,105.1) 96.63,105.1 96.52,105.21 96.52,105.21 96.49,105.24 95.66,105.24 94.74,106.17 94.74,108.22 94.07,108.89 94.07,125.86 95.19,126.98 v1(95.19,134.08)
  BOTTOM w0.14: v1(31.8,43.03) 31.05,43.03 30.84,42.81 U125.8
  BOTTOM w0.191: v1(95.19,134.08) 89.47,134.08 88.18,135.37 86.54,135.37 86.05,134.88 77.77,134.88 77.75,134.86 77.46,134.58 74.85,134.58 74.27,135.15 64.8,135.15 62.93,137.01 42.31,137.01 v1(42.06,137.26) ; R612.2 31.82,43.04 v1(31.8,43.03) ; v1(97.92,105.1) 98.19,104.83 98.19,97.28 v1(95.59,94.67)
UART4_TXD: length 231.1
  TOP w0.132: U47.U18 v1(80.36,85.59)
  L03_SIG01 w0.076: v1(29.9,43.4) 29.9,47.49 30.33,47.92 30.33,68.79 28.19,70.94 28.19,99.71 28.2,99.72 28.2,100.22 41.44,113.47 41.44,125.46 42.84,126.86 42.84,130.12 41.49,131.48 41.49,139.09 v1(41.32,139.26) ; v1(96.33,94.71) 92.69,91.07 87.6,91.07 86.9,91.77 83.76,91.77 80.76,88.78 80.76,86.19 80.36,85.79 v1(80.36,85.59) ; v1(95.87,135.9) 95.87,126.4 95.05,125.58 95.05,112.51 95.86,111.7 95.86,109.83 94.93,108.9 94.93,106.59 95.29,106.23 95.95,106.23 96.86,105.32 97.57,105.32 97.83,105.58 v1(98.47,105.58)
  BOTTOM w0.14: U125.6 30.04,43.26 v1(29.9,43.4) 30.1,43.61 R611.2
  BOTTOM w0.191: v1(98.47,105.58) 98.53,105.58 98.94,105.17 98.94,97.32 v1(96.33,94.71) ; v1(95.87,135.9) 90.79,135.9 90.26,136.43 87.9,136.43 86.97,137.36 78.13,137.36 77.44,136.68 76.96,136.68 76.65,136.99 66.57,136.99 64.31,139.26 v1(41.32,139.26)
UART5_RXD: length 132.1
  TOP w0.191: v1(88.38,107.34) 88.1,107.07 88.1,104.27 88.45,103.93 88.45,100.05 86.28,97.88 84.84,97.88 83.46,96.51 83.46,92.94 80.76,90.24 U47.V22 ; v1(19.08,129.36) 18.88,129.16 J12.62
  L03_SIG01 w0.076: v1(42.35,141.03) 37.98,141.03 26.32,129.36 v1(19.08,129.36) ; v1(85.56,140.06) 85.56,139.02 85.59,138.99 85.59,134.71 85.18,134.3 85.18,128.57 87.33,126.42 87.33,110.36 86.68,109.7 86.68,109.03 v1(88.38,107.34)
  BOTTOM w0.191: v1(85.56,140.06) 85.47,139.97 74.64,139.97 73.92,140.68 68.16,140.68 67.33,141.51 65.57,141.51 65.33,141.27 42.59,141.27 v1(42.35,141.03)
UART5_TXD: length 132.6
  TOP w0.132: 81.16,88.15 81.16,88.65
  TOP w0.191: 81.16,88.15 81.16,87.99 U47.V21 ; v1(88.7,105.35) 88.7,104.63 88.86,104.47 88.86,99.92 86.38,97.44 85.01,97.44 84.02,96.46 84.02,92.86 81.16,90 81.16,88.65 ; J12.60 18.86,128.36 v1(19.11,128.12)
  L03_SIG01 w0.076: v1(39.68,140.44) 37.99,140.44 25.67,128.12 v1(19.11,128.12) ; v1(86.34,138.47) 86.34,138.47 86.34,138.25 85.77,137.68 85.77,134.29 85.38,133.91 85.38,128.7 87.51,126.58 87.51,109.8 87.67,109.65 87.67,108.65 88.91,107.41 88.91,107.09 88.58,106.77 88.48,106.66 88.48,105.86 88.7,105.65 v1(88.7,105.35)
  BOTTOM w0.191: v1(86.34,138.47) 86.04,138.17 71.34,138.17 70.75,138.76 66.56,138.76 65.02,140.3 39.82,140.3 v1(39.68,140.44)
UART6_RXD: length 68.3
  TOP w0.132: U47.V19 v1(81.16,86.39)
  TOP w0.191: J13.62 v1(127.93,108.35)
  BOTTOM w0.102: 80.77,87.89 80.77,86.78 v1(81.16,86.39)
  BOTTOM w0.191: 80.77,87.89 80.77,89.84 84.63,93.7 91.78,93.7 92.16,93.32 99.45,93.32 100.76,94.63 103.89,94.63 106.43,92.09 112.47,92.09 112.81,92.43 119.36,92.43 125.96,99.03 125.96,107.7 126.61,108.35 v1(127.93,108.35)
UART6_TXD: length 69.6
  TOP w0.132: U47.V18 v1(81.16,85.59)
  TOP w0.191: J13.60 v1(127.93,109.15)
  BOTTOM w0.102: 81.56,88.58 81.56,85.99 v1(81.16,85.59)
  BOTTOM w0.191: v1(127.93,109.15) 128.74,108.34 128.74,106.8 126.35,104.41 126.35,98.55 119.84,92.04 113.01,92.04 112.68,91.7 105.79,91.7 104.58,92.91 103.83,92.91 102.52,94.23 101.06,94.23 99.77,92.93 92,92.93 91.62,93.31 84.78,93.31 81.56,90.08 81.56,88.58
UART_SHIELD:
  vias: v1(11.35,25.33) v1(13.76,26.25) v1(13.76,25.33)
USB_TYPEA_EARTH:
  vias: v1(58.44,1.8) v1(59.22,5.82) v1(59.22,4.96) v1(59.3,1.8) v1(60.06,4.04) v1(60.06,3.18) v1(60.06,2.32) v1(63.01,4.56) v1(63.01,3.03) v1(63.01,1.51) v1(64.53,4.56) v1(64.53,3.03) v1(64.53,1.51) v1(66.06,4.56) v1(66.06,3.03) v1(66.06,1.51) v1(67.58,4.56) v1(67.58,3.03) v1(67.58,1.51)
USB_TYPEA_OC_INDICATION: length 254.2
  TOP w0.191: v1(134.12,90.41) 134,90.53 134,93.33 135.44,94.77 135.44,137.69 132.65,140.48 125.26,140.48 123.75,138.96 116.06,138.96 115.35,139.67 115.35,140.88 v1(115.34,140.89) ; v1(105.16,146.36) 105.13,146.33 U21.14 ; R396.2 57.2,18.12 57.39,17.93 U74.5 58.79,20.51 59.42,21.14 62.71,21.14 63.37,21.8 63.37,23.37 66.17,26.17 70.57,26.17 73.43,29.02 v1(73.43,31.49) ; v1(98.94,88.4) 98.58,88.04 98.58,85.35 101.06,82.87 105.43,82.87 110,78.29 110,55.93 110.11,55.82 110.11,54.3 v1(110.06,54.25)
  L03_SIG01 w0.076: v1(75.09,47.56) 75.09,46.83 72.81,44.54 72.81,39.79 70.99,37.97 70.99,36.13 v1(68.64,33.78)
  BOTTOM w0.191: v1(105.16,146.36) 105.82,147.03 107.27,147.03 107.81,146.49 107.81,145.47 109.31,143.97 112.29,143.97 115.34,140.92 v1(115.34,140.89) ; v1(134.12,90.41) 133.26,90.41 131.08,88.23 124.07,88.23 121.5,90.8 113.71,90.8 113.47,90.56 105.05,90.56 103.87,91.74 100.46,91.74 98.94,90.22 v1(98.94,88.4) ; v1(73.43,31.49) 73.43,31.5 72.06,32.86 70.06,32.86 69.14,33.78 v1(68.64,33.78) ; v1(110.06,54.25) 91.84,54.25 85.25,47.66 82.86,47.66 82.86,47.66 82.54,47.66 82.54,47.66 75.2,47.66 v1(75.09,47.56)
USB_TYPEACONN_DM: length 7.6
  TOP w0.119: J23.2 64.04,15.45 64.16,15.57 64.81,15.57 64.97,15.73 64.97,15.86 v1(64.72,16.11) 64.97,16.35 64.97,18.43 64.65,18.74 L9.2 R393.2
  BOTTOM w0.119: v1(64.72,16.11) 64.81,16.2 U130.2
USB_TYPEACONN_DP: length 7.6
  TOP w0.119: J23.3 66.04,15.45 65.92,15.57 65.31,15.57 65.19,15.69 65.19,15.86 v1(65.43,16.11) 65.19,16.35 65.19,18.47 65.5,18.79 L9.3 R394.2
  BOTTOM w0.119: v1(65.43,16.11) 65.31,16.23 U130.1
USB_TYPEC1_EARTH:
  vias: v1(27.56,3.42) v1(27.56,2.51) v1(27.56,1.59) v1(28.48,3.42) v1(28.48,2.51) v1(28.48,1.59) v1(32.77,2.9) v1(32.77,1.37) v1(34.29,2.9) v1(34.29,1.37) v1(35.82,2.9) v1(35.82,1.37)
USB_TYPEC2_EARTH:
  vias: v1(42.44,5.97) v1(42.44,5.06) v1(42.44,4.14) v1(43.35,5.97) v1(43.35,5.06) v1(43.35,4.14) v1(47.77,2.9) v1(47.77,1.37) v1(49.29,2.9) v1(49.29,1.37) v1(50.82,2.9) v1(50.82,1.37)
USBC_CONN1_CC1: length 19.4
  TOP w0.191: J24.A5 33.39,9.02 33.23,9.19 D7.1 33.23,11.04 v1(33.05,11.23) ; C307.1 34.04,21.1 34.08,21.06 34.08,20.79 34.51,20.36 35.83,20.36 v1(35.91,20.27)
  L03_SIG01 w0.076: v1(35.91,20.27) 35.91,20.26 36.66,19.52 36.66,18.21 32.68,14.23 32.68,11.6 v1(33.05,11.23)
  BOTTOM w0.191: v1(35.91,20.27) 35.91,21.09 36.21,21.38 U129.24
USBC_CONN1_CC2: length 25.4
  TOP w0.191: v1(34.8,22.69) 34.97,22.53 C306.1
  TOP w0.254: J24.B5 35.14,5.6 v1(34.89,5.35)
  L03_SIG01 w0.076: v1(34.89,5.35) 34.89,6.7 33.18,8.41 33.18,10.27 32.32,11.13 32.32,14.37 36.33,18.38 36.33,19.44 35.95,19.82 35.73,19.82 35.52,20.03 35.52,21.38 34.8,22.1 v1(34.8,22.69)
  BOTTOM w0.191: D17.1 34.76,5.22 v1(34.89,5.35) ; v1(34.8,22.69) 35.55,22.69 36.06,22.18 U129.26
USBC_CONN2_CC1: length 18.3
  TOP w0.14: v1(47.24,9.55) D8.1 48.39,9.01 J25.A5 ; C305.1 v1(44.33,22.18)
  L03_SIG01 w0.076: v1(44.33,22.18) 43.82,21.67 43.82,20.81 46.64,17.99 46.64,10.15 v1(47.24,9.55)
  BOTTOM w0.203: U129.45 v1(44.33,22.18)
USBC_CONN2_CC2: length 24.6
  TOP w0.14: J25.B5 50.14,5.41 50.9,4.65 v1(51.12,4.65) ; C312.1 v1(44.33,21.12)
  L03_SIG01 w0.076: v1(51.12,4.65) 51.48,5.01 51.48,7.42 48.96,9.94 48.04,9.94 47.01,10.97 47.01,18.44 v1(44.33,21.12)
  BOTTOM w0.14: v1(51.12,4.65) 51.32,4.85 D16.1 ; v1(44.33,21.12) 44.07,21.38 U129.47
USBC_CONN2_DM: length 14.8
  TOP w0.119: J25.B7 49.14,5.8 49.28,5.66 49.28,5.35 49.04,5.11 v1(48.94,5.11) ; R400.2 L10.3 49.82,10.58 49.86,10.53 49.86,10.21 49.73,10.08 D9.3 49.51,9.15 49.51,8.59 49.89,8.2 J25.A7 49.89,7.57 49.75,7.43 v1(49.75,7.07)
  L03_SIG01 w0.089: v1(48.94,5.11) 49.12,5.29 49.12,5.95 49.03,6.04 47.33,6.04 46.94,6.43 46.94,7.76 47.37,8.19 49.21,8.19 49.51,7.89 49.51,7.31 v1(49.75,7.07)
USBC_CONN2_DP: length 14.8
  TOP w0.119: J25.B6 49.64,5.81 49.51,5.67 49.51,5.35 49.75,5.11 v1(49.75,5.11) ; v1(49.04,7.07) 49.04,7.38 48.89,7.53 J25.A6 48.89,8.18 49.28,8.57 49.28,9.15 D9.2 49.05,10.1 48.93,10.22 48.93,10.54 48.97,10.58 L10.2 R399.2
  L03_SIG01 w0.089: v1(49.75,5.11) 49.75,4.85 49.66,4.76 49.49,4.76 49.35,4.9 49.35,6.05 49.13,6.28 47.43,6.28 47.18,6.53 47.18,7.66 47.47,7.95 49.12,7.95 49.28,7.79 49.28,7.31 v1(49.04,7.07)
VMAIN: length 1.8
  TOP w0.305: v1(49.66,26.94) 49.54,26.82 49.54,26.28 49.17,25.9 R380.1
  vias: v1(17.91,15.38) v1(17.91,14.74) v1(18.54,15.38) v1(18.54,14.74) v1(19.18,15.38) v1(19.18,14.74) v1(19.81,15.38) v1(19.81,14.74) v1(20.45,15.38) v1(20.45,14.74) v1(49.66,28.87) v1(49.66,27.9) v1(50.45,28.87) v1(50.45,27.9) v1(50.45,26.94) v1(51.36,28.87) v1(51.36,27.9) v1(51.36,26.94)
VMAIN_EN: length 2
  TOP w0.191: R381.1 26.36,24.63 R382.1 25.68,24.64 U71.4
VMAIN_PD: length 2.6
  BOTTOM w0.254: v1(38.12,16.1) 38.45,16.43 ; 38.45,16.43 38.45,16.23 v1(38.58,16.1) ; 38.45,16.43 U129.11
  BOTTOM w0.381: v1(42.95,16.11) 42.45,16.61 U129.1
  vias: v1(27.22,23.61) v1(27.21,23.12) v1(27.75,24.38) v1(27.75,23.87) v1(27.75,23.36) v1(28.26,23.36) v1(28.26,22.85) v1(28.77,23.36) v1(28.77,22.85) v1(29.31,23.13) v1(38.12,15.65) v1(38.12,15.19) v1(38.58,15.65) v1(38.58,15.19) v1(42.95,15.66) v1(43.41,16.11) v1(43.41,15.66) v1(43.87,16.11) v1(43.87,15.66) v1(44.32,16.11) v1(44.32,15.66)
VPHY_3V3_FT4232: length 3.3
  TOP w0.254: U64.4 v1(27.73,45.25)
  BOTTOM w0.254: v1(27.73,45.25) 27.99,45.51 C606.2 FL17.1
VPLL_3V3_FT4232: length 6.6
  TOP w0.254: U64.9 v1(25.41,42.75) 25.26,42.6 24.13,42.6 v1(23.82,42.29) 23.81,42.28 R357.2
  BOTTOM w0.508: v1(25.41,42.75) C607.2 24.28,42.75 v1(23.82,42.29) 23.34,42.78 FL18.1
VPP_1V8: length 7.2
  TOP w0.203: C218.1 v1(61.45,73.48)
  TOP w0.356: U47.F7 v1(70.76,75.99)
  BOTTOM w0.254: C517.1 61.59,73.63 v1(61.45,73.48)
  BOTTOM w0.305: C513.1 70.54,75.99 v1(70.76,75.99) ; 66.13,74.91 65.54,74.91 64.48,73.85 64.48,73.82 64.44,73.78 64.41,73.78 64.4,73.77 62.43,73.77 62.3,73.63 C517.1
VPP_EN: length 204.7
  TOP w0.191: v1(60.13,55.44) 59.89,55.68 R319.1 ; v1(111.22,54.24) 111.22,56.94 110.47,57.69 110.47,80.1 109.39,81.18 109.39,84.63 109.19,84.83 v1(109.19,85.22) ; U21.5 110.61,142.71 115.14,138.18 124.13,138.18 126.01,140.05 132.11,140.05 134.97,137.2 134.97,100.03 133.01,98.07 v1(133.01,89.06)
  BOTTOM w0.191: v1(133.01,89.06) 131.79,87.84 123.87,87.84 121.3,90.41 114.05,90.41 113.41,89.76 108.55,89.76 107.96,89.18 107.96,86.56 109.19,85.33 v1(109.19,85.22) ; v1(60.13,55.44) 60.13,53.74 60.48,53.39 60.48,49.92 62.35,48.05 85.1,48.05 93.14,56.09 109.38,56.09 v1(111.22,54.24)
VSEL_MMC1_SDIO: length 24.9
  TOP w0.191: U19.4 28.58,142.39 28.28,142.09 R103.2 18.59,141.79 17.35,140.54 13.04,140.54 12.36,141.22 12.36,144.81 12.98,145.43 14.62,145.43 14.81,145.62 U16.1
VSEL_SD_SOC: length 18.3
  TOP w0.191: R86.1 v1(28.58,149.68)
  BOTTOM w0.191: U79.8 43.41,152.86 43.12,152.58 31.48,152.58 v1(28.58,149.68)
VSEL_SD_SOC_1V8: length 121.3
  TOP w0.132: U47.Y21 82.76,87.99 82.76,88.65
  TOP w0.191: v1(90.3,106.84) 89.69,106.23 89.69,99.62 85.71,95.64 85.71,92.28 82.76,89.33 82.76,88.65
  L03_SIG01 w0.076: v1(90.3,106.84) 90.3,108.09 89.83,108.55 89.83,108.84 89.83,108.98 88.25,110.57 88.25,127.02 86.31,128.95 86.31,131.14 86.71,131.54 86.71,132.47 86.31,132.88 86.31,134.14 87.73,135.55 87.73,152.18 v1(87.67,152.23)
  BOTTOM w0.191: U79.5 41.91,154.12 41.66,154.37 41.66,156.21 42.03,156.58 44.26,156.58 47.46,153.37 53.33,153.37 53.93,152.77 55.22,152.77 55.54,152.44 85.73,152.44 85.94,152.23 v1(87.67,152.23)
WD_DISABLE: length 13
  TOP w0.14: 49.2,66.04 49.96,66.04 50,66.04 50.02,66.04 50.1,66.04 50.15,66.09 50.18,66.11 50.39,66.32 50.41,66.34 50.42,66.36 50.54,66.48 53.99,66.48 54.44,66.93 54.44,68.07 54.58,68.21 R281.2
  TOP w0.15: 49.2,66.04 48.83,66.04 48.37,65.58 U56.29
  TOP w0.191: TP56.1 56.69,68.59 56.31,68.21 R282.2 R281.2
WKUP_I2C0_SCL: length 12.5
  TOP w0.14: R297.1 42.63,64.92 39.52,64.92 39.49,64.89
  TOP w0.191: R301.2 38.2,64.08 38.06,63.95 37.62,63.95 35.7,65.86 34.84,65.86 34.43,66.27 34.43,67.24 34.23,67.44 R284.1 ; R301.2 38.68,64.08 39.49,64.89 ; R301.2 38.47,63.44 C245.1
WKUP_I2C0_SCL_RC: length 64.4
  TOP w0.132: U47.D13 v1(69.16,81.59)
  TOP w0.191: v1(39.64,87.54) 39.06,86.96 39.06,79.77 36.83,77.54 36.83,75.93 34.91,74 34.91,71.16 33.27,69.52 R284.2
  L03_SIG01 w0.076: v1(54.86,88.63) 56.43,88.63 59.41,85.65 59.41,84.77 61.54,82.64 v1(63.98,82.64)
  L05_SIG02 w0.102: v1(69.16,81.59) 69.09,81.59 68.72,81.96 67.97,81.96 67.34,82.59 64.53,82.59 64.48,82.64 v1(63.98,82.64)
  BOTTOM w0.191: v1(39.64,87.54) 39.68,87.54 42.81,84.4 42.81,82.12 44.86,80.07 48.28,80.07 50.82,82.61 50.82,82.93 52.52,84.63 52.52,86.29 v1(54.86,88.63)
WKUP_I2C0_SDA: length 41.9
  TOP w0.14: R307.1 39.56,62.86
  TOP w0.191: R256.1 23.25,78.53 R259.2 23.16,77.9 22.96,77.7 21.36,77.7 20.07,76.41 20.07,66.96 23.57,63.46 30.06,63.46 30.87,62.65 30.87,59.99 31.24,59.62 32.34,59.62 33.23,60.51 35.92,60.51 37.57,62.16 C248.1 38.5,62.16 39.2,62.86 39.56,62.86
WKUP_I2C0_SDA_RC: length 74.5
  TOP w0.132: U47.E13 v1(69.96,81.59)
  TOP w0.191: v1(38.8,90.64) 38.8,93.46 40.9,95.55 44.33,95.55 44.96,94.92 44.96,93.6 45.25,93.32 45.54,93.32 46.02,92.83 46.02,92.67 47.09,91.6 49.07,91.6 49.29,91.38 v1(51.96,91.38) ; v1(27.49,89.18) 28.41,88.25 28.41,87.23 26.91,85.73 26.91,81.11 25.26,79.46 R256.2
  BOTTOM w0.14: 67.8,81.99 69.59,81.99 69.96,81.63 v1(69.96,81.59)
  BOTTOM w0.191: v1(51.96,91.38) 53.55,91.38 55.4,89.53 55.4,88.48 53.19,86.27 53.19,83.41 53.44,83.16 54.43,83.16 54.78,83.51 55.46,83.51 55.6,83.37 57.4,83.37 57.63,83.6 58.96,83.6 59.35,83.99 64.45,83.99 66.45,81.99 67.8,81.99 ; v1(27.49,89.18) 28.17,88.5 34.63,88.5 35.72,89.59 37.75,89.59 v1(38.8,90.64)
WKUP_LFOSCO_XI: length 12.7
  TOP w0.14: Y4.1 57.56,74.55 57.91,74.9 v1(57.91,75.21) 58.03,75.33 C216.2 ; U47.A8 61.22,77.19 60.16,76.13 60.16,76.04 59.92,75.79 59.79,75.79
  TOP w0.191: 59.79,75.79 59.21,75.79 58.74,75.33 C216.2
  BOTTOM w0.191: v1(57.91,75.21) 58.23,74.9 R568.1
WKUP_LFOSCO_XO: length 5.3
  TOP w0.14: C213.2 58.02,76.27 v1(57.67,75.92) 57.67,76.84 57.46,77.05 Y4.2
  TOP w0.191: R261.2 59.7,76.27 C213.2
  BOTTOM w0.191: R568.2 57.7,75.88 v1(57.67,75.92)
WKUP_UART0_RX_3V3: length 93.4
  TOP w0.132: U47.C9 v1(68.36,77.59)
  TOP w0.191: v1(65.43,43.6) 64.51,42.68 64.51,39.56 61.69,36.74 55.81,36.74 54.87,35.8 47.41,35.8 46.09,34.49 40.76,34.49 35.38,39.87 v1(34.97,39.87) ; R322.2 v1(34.97,52.75)
  L03_SIG01 w0.076: v1(68.36,77.59) 68.16,77.59 67.14,76.57 67.14,76.43 66.5,75.79 66.39,75.79 66.28,75.69 66.26,75.69 65.1,74.53 65.07,74.53 63.36,72.82 63.36,62.38 64.2,61.54 64.2,47.24 65.52,45.93 65.52,43.69 v1(65.43,43.6) ; v1(33.87,54.98) 34.97,53.88 v1(34.97,52.75) 34.97,51.77 34.47,51.27 34.47,40.37 v1(34.97,39.87)
  BOTTOM w0.191: U117.9 33.56,55.17 33.75,54.98 v1(33.87,54.98)
WKUP_UART0_TX_3V3: length 95.2
  TOP w0.132: U47.E9 v1(69.96,77.59)
  TOP w0.191: v1(35.05,40.83) 38.78,37.09 47.07,37.09 48.52,38.54 54.82,38.54 55.59,39.31 60.39,39.31 61.2,38.49 62.72,38.49 63.28,39.06 63.28,42.88 65.11,44.72 v1(66.07,44.72)
  L03_SIG01 w0.076: v1(69.96,77.59) 69.55,77.18 68.12,77.18 67.8,76.85 67.8,76.37 67.97,76.2 67.97,75.73 67.81,75.57 66.51,75.57 65.57,74.63 65.57,74.63 65.26,74.32 65.16,74.22 65.05,74.22 64.83,74.03 63.54,72.75 63.54,62.64 64.4,61.79 64.4,47.47 66.07,45.8 v1(66.07,44.72) ; v1(35.56,55.27) 35.47,55.18 35.47,50.91 34.79,50.22 34.79,40.92 34.88,40.83 v1(35.05,40.83)
  BOTTOM w0.191: U117.7 34.56,56.27 v1(35.56,55.27) 36.04,55.76 R593.2
XDS110_DIR: length 3.1
  BOTTOM w0.191: U97.4 120.7,80.66 120.52,80.49 119.92,80.49 ; R555.2 119.58,80.34 119.78,80.34 119.92,80.49 ; 119.92,80.49 119.77,80.64 119.77,81.13 119.91,81.27 U97.5
XDS110_EMU0: length 15.6
  TOP w0.191: v1(129.35,86.48) 129.34,86.5 R237.2 128.56,86.07 128.2,85.71 U48.42
  L03_SIG01 w0.076: v1(127.21,81) 126.83,81.38 126.83,83.96 v1(129.35,86.48)
  BOTTOM w0.14: U102.7 123.95,77.74 v1(127.21,81)
XDS110_EMU1: length 13.2
  TOP w0.191: U48.43 R236.2 127.29,86.5 127.15,86.35 v1(127.15,86.03)
  L03_SIG01 w0.076: v1(126.06,80.98) 126.06,84.94 v1(127.15,86.03)
  BOTTOM w0.14: v1(126.06,80.98) 123.16,78.08 122.72,78.08 122.72,78.09 U102.6
XDS110_TCK: length 12.7
  TOP w0.191: U48.35 131,83.93 131.49,83.44 131.49,81.84 v1(131.18,81.53)
  BOTTOM w0.191: v1(131.18,81.53) 130.81,81.9 124.45,81.9 124.08,82.27 123.48,82.27 123.29,82.07 U97.14
XDS110_TDI: length 9.6
  TOP w0.191: v1(123.94,81.6) 124.65,82.31 129.01,82.31 129.8,83.11 U48.38
  BOTTOM w0.191: v1(123.94,81.6) 123.31,81.6 123.24,81.67 U97.15
XDS110_TDO: length 20.3
  TOP w0.191: U48.37 130.2,78.58 129.53,77.91 121.22,77.91 120.36,77.04 v1(120.36,75.45)
  BOTTOM w0.191: U109.7 120.96,74.85 v1(120.36,75.45)
XDS110_TMS: length 11
  TOP w0.191: v1(130.84,82.88) 130.6,83.12 U48.36
  BOTTOM w0.191: v1(130.84,82.88) 130.4,82.43 124.78,82.43 124.21,83 123.46,83 122.93,82.47 U97.13
XDS110_TRST#: length 9.2
  TOP w0.191: v1(122.62,83.62) 123.15,83.62 123.86,82.91 127.98,82.91 129,83.93 U48.40
  BOTTOM w0.191: v1(122.62,83.62) 121.9,82.9 U97.12
XDS_GPIO1: length 1.6
  TOP w0.191: U40.2 115.43,87.3 115.51,87.21 R235.2
XDS_GPIO2: length 1
  TOP w0.191: U51.7 112.74,68.66 R283.2
XDS_GPIO3: length 1.6
  TOP w0.191: U40.4 R227.2
XDS_GPIO4: length 1.6
  TOP w0.191: R221.2 115.59,88.99 115.5,88.9 U40.6
XDS_PORZN: length 1.6
  TOP w0.191: R219.2 107.45,89.39 107.54,89.3 U40.8
XDS_POWERDOWN: length 1.6
  TOP w0.191: U40.12 107.54,87.7 107.45,87.61 R233.2
XDS_RSTN: length 6.4
  TOP w0.191: TP51.1 116.18,81.54 116.54,81.18 116.81,81.18 116.92,81.3 U48.70 118.78,81.3 119.08,81.6 v1(119.08,81.83)
  BOTTOM w0.191: v1(119.08,81.83) 119.08,81.71 118.89,81.52 118.13,81.52 118.02,81.41 R549.1 118.02,80.62 R556.1
XDS_USB_DM: length 30.5
  TOP w0.119: v1(119.45,72.28) 119.18,72.01 118.78,72.01 118.69,72.1 U48.93 ; J17.2 130.5,51.64 130.28,51.85 129.94,51.85 v1(129.69,51.61)
  BOTTOM w0.119: v1(129.69,51.61) 129.43,51.87 127.58,51.87 124.16,55.3 124.16,62.76 118.44,68.48 118.44,71.53 118.92,72.01 119.18,72.01 v1(119.45,72.28)
XDS_USB_DP: length 30.5
  TOP w0.119: J17.3 130.5,52.29 130.28,52.07 129.94,52.07 v1(129.69,52.32) ; U48.94 118.69,71.7 118.78,71.79 119.18,71.79 v1(119.45,71.52)
  BOTTOM w0.119: v1(119.45,71.52) 119.18,71.79 119.01,71.79 118.66,71.44 118.66,68.57 124.38,62.85 124.38,55.39 127.67,52.09 128.02,52.09 128.11,52.19 128.11,52.29 128.2,52.38 128.34,52.38 128.43,52.29 128.43,52.19 128.53,52.09 128.66,52.09 128.76,52.19 128.76,52.29 128.85,52.38 128.98,52.38 129.08,52.29 129.08,52.19 129.17,52.09 129.47,52.09 v1(129.69,52.32)
XDS_USB_ID: length 39.2
  TOP w0.191: J17.4 130.42,52.94 v1(129.4,53.96) 128.98,53.54 128.98,52.24 128.79,52.05 U60.2 ; R271.2 v1(114.74,71.79)
  BOTTOM w0.191: v1(129.4,53.96) 130.33,53.02 130.33,50.91 129.76,50.34 128.32,50.34 123.33,55.34 123.33,55.95 113.99,65.28 113.99,71.04 v1(114.74,71.79)
XDS_USB_VBUS: length 11
  TOP w0.191: U60.6 127.78,51.08 127.64,50.94 127.63,50.94 127.48,50.79
  TOP w0.305: U55.2 119.77,65.64 v1(119.96,65.83)
  BOTTOM w0.191: v1(119.96,65.83) 118.42,65.83 117.84,66.41 117.84,68.35 116.76,69.43 116.05,69.43 115.61,69.86 115.61,70.83 115.89,71.1 R576.1
XDS_VREF: length 18.7
  TOP w0.203: U48.9 134.4,74.1 134.75,74.44 C215.2
  TOP w0.254: v1(134.24,85.51) R241.2 134.75,87.37 134.5,87.62 C190.1 U41.3 ; C215.2 v1(135.32,74.8)
  L03_SIG01 w0.254: v1(135.32,74.8) 134.71,74.8 133.68,75.83 133.68,84.95 v1(134.24,85.51)
XDS_WARMRESETN: length 1.6
  TOP w0.191: U40.10 R224.2
ZENER_CLAMP: length 4.5
  TOP w0.191: R308.1 35.69,63.02 R298.1 33.99,63.34 D2.3
N16848941: length 2.2
  TOP w0.191: R115.2 61,127.6 R116.2 61.01,126.5 U26.1
N16856152: length 6
  TOP w0.191: U64.3 25.44,45.75 24.7,46.5 24.43,46.5 C270.1 23.15,46.27 21.79,44.9 Y6.2
N16856224: length 6.1
  TOP w0.191: Y6.1 21.79,48.7 23.15,47.33 C269.1 24.5,47.04 24.84,47.04 25.62,46.25 U64.2
N16857368: length 1.1
  TOP w0.191: U66.2 21.14,38.29 21.44,38.58 C283.2
N16878497: length 1.9
  TOP w0.191: U49.H5 100.85,75.03 v1(100.6,75.28)
  BOTTOM w0.191: R562.1 v1(100.6,75.28) 100.6,75.22 TP116.1
N16880083: length 2.2
  TOP w0.191: R18.1 U2.1 15.88,164.63 R21.2
N16956459: length 2.2
  TOP w0.191: U27.1 96.32,121.49 R122.1 95.38,121.5 R121.2
N16994873: length 1.2
  BOTTOM w0.191: R483.2 117.71,103.28 117.64,103.21 U88.4
N16994875: length 1.3
  BOTTOM w0.191: R476.2 112.79,104.37 112.51,104.66 U87.4
N16995245: length 1.1
  BOTTOM w0.191: R487.2 C417.1
N16997746: length 5.9
  TOP w0.191: R218.1 123.07,88.24 123.07,86.8 122.16,85.89 121.58,85.89 121.4,85.7 U48.59
N17030208: length 1.6
  BOTTOM w0.14: R544.2 119.2,82.36 119.48,82.07 U97.7
N17031262: length 2.2
  TOP w0.254: LD9.2 45.59,11.89 R402.2
N17078974: length 1.8
  BOTTOM w0.191: R438.2 J10.2
N17269599: length 1.9
  TOP w0.191: U68.6 69.43,30.88 69.53,30.98 R366.2 69.85,31.44 69.81,31.48 R363.1
N17269609: length 3
  TOP w0.191: R362.1 67.54,31.61 67.32,31.39 R367.1 ; R364.2 R367.1 ; R367.1 67.72,31.08 67.92,30.88 U68.1
N17378539: length 2
  TOP w0.191: LD7.1 31.29,51.87 31.29,51.4 31.41,51.28 R330.2
N17479799: length 1.1
  TOP w0.305: U55.8 R314.2
N17479805: length 4
  TOP w0.191: U55.5 R313.1 R306.2 116.91,63.8 116.83,63.88 C243.2
N17479881: length 3.3
  TOP w0.191: R246.1 115.42,83.13 115.66,82.89 C203.2 116.07,82.88 116.35,82.59 116.56,82.59 117.06,82.1 U48.68
N17481587: length 1.6
  TOP w0.191: LD5.2 131.82,66.32 132.25,66.75 R287.2
N17481598: length 4.1
  TOP w0.191: v1(116.2,70.26) C225.2 116.2,70.9 U48.96
  BOTTOM w0.254: R576.2 116.87,70.93 v1(116.2,70.26)
N17481613: length 1.9
  TOP w0.191: R271.1 116.46,71.79 116.95,71.3 U48.95
N17481619: length 6.4
  TOP w0.14: R295.2 R289.1
  TOP w0.191: U48.1 134.23,70.9 134.57,70.56 134.57,69.03 133.99,68.46 R289.1
N17481621: length 3.8
  TOP w0.191: U48.60 121,85.99 121.48,86.46 v1(122,86.46) R232.2
  BOTTOM w0.191: R232.2 v1(122,86.46)
N17481627: length 2.1
  TOP w0.191: U48.3 134.37,71.7 134.57,71.5 R276.1
N17481631: length 1.1
  TOP w0.191: R276.2 LD3.2
N17481633: length 4.6
  TOP w0.191: R229.2 118.19,86.68 118.46,86.41 v1(118.75,86.41) 119.11,86.41 119.8,85.72 U48.63
  BOTTOM w0.191: v1(118.75,86.41) 118.43,86.41 118.19,86.65 R229.2
N17481635: length 3.1
  TOP w0.191: R231.2 v1(120.73,86.46) 120.6,86.34 U48.61
  BOTTOM w0.191: R231.2 v1(120.73,86.46)
N17481637: length 5.6
  TOP w0.191: R287.1 132.7,70.09 132.17,70.62 132.17,71.87 132.4,72.1 U48.4
N17481641: length 3.5
  TOP w0.191: R230.2 119.46,86.82 v1(119.81,86.46) 120.2,86.07 U48.62
  BOTTOM w0.191: R230.2 119.46,86.82 v1(119.81,86.46)
N17824845: length 1.6
  BOTTOM w0.191: R654.1 40.3,24.97 40.3,24.43 40.25,24.38 U129.36
N17824852: length 1.6
  BOTTOM w0.191: R653.1 40.81,24.73 40.69,24.61 40.69,24.27 40.67,24.26 40.67,23.75 U129.37
N17824859: length 1.7
  BOTTOM w0.191: U129.38 41.05,24.1 41.07,24.11 41.07,24.45 41.57,24.96 R652.1
N17824866: length 1.9
  BOTTOM w0.191: R651.1 42.33,25.06 41.45,24.18 U129.39
N19741013: length 20.8
  TOP w0.191: R390.2 25.91,22.56 26.37,22.1 v1(26.37,21.34)
  L03_SIG01 w0.076: v1(35.77,19.4) 35.28,19.9 35.28,21.18 34.38,22.07 34.38,22.99 34.73,23.34 34.73,24.6 34.11,25.22 33.88,25.22 30.94,22.28 28.04,22.28 27.61,22.72 26.73,22.72 26.56,22.55 26.56,21.53 v1(26.37,21.34)
  BOTTOM w0.14: v1(35.77,19.4) 36.19,18.98 U129.18
N19806973: length 1.2
  BOTTOM w0.14: U110.7 124.85,74.85 125.26,75.26 R566.2
N20199452: length 2.4
  TOP w0.254: R384.2 R389.1 D4.3
N20506305: length 1.1
  TOP w0.356: 52.66,24.71 52.41,24.46 U72.11
N20506307: length 1.2
  TOP w0.33: U72.9 52.56,23.46 52.72,23.31
N20506359: length 3.4
  TOP w0.14: R387.1 R388.1 47.49,23.75 47.96,24.21 U72.2
N20506388: length 1.7
  TOP w0.14: v1(50.26,21.81) 50.48,21.81 50.62,21.95 U72.6
  BOTTOM w0.132: v1(50.26,21.81) 49.97,22.09 R666.1
N20506392: length 1.5
  TOP w0.14: R380.2 48.56,25.11 48.95,24.71 U72.1
N20506511: length 1.4
  TOP w0.14: C304.1 49,23.62 49.1,23.71 U72.3
N21761024: length 7.9
  TOP w0.14: R261.1 60.44,76.88 61.08,77.52 66.69,77.52 U47.A9
N21784165: length 5.4
  TOP w0.132: U47.V12 v1(81.16,80.79)
  BOTTOM w0.14: v1(81.16,80.79) 81.56,81.19 84.04,81.19 84.32,81.48 85.53,81.48 R548.1
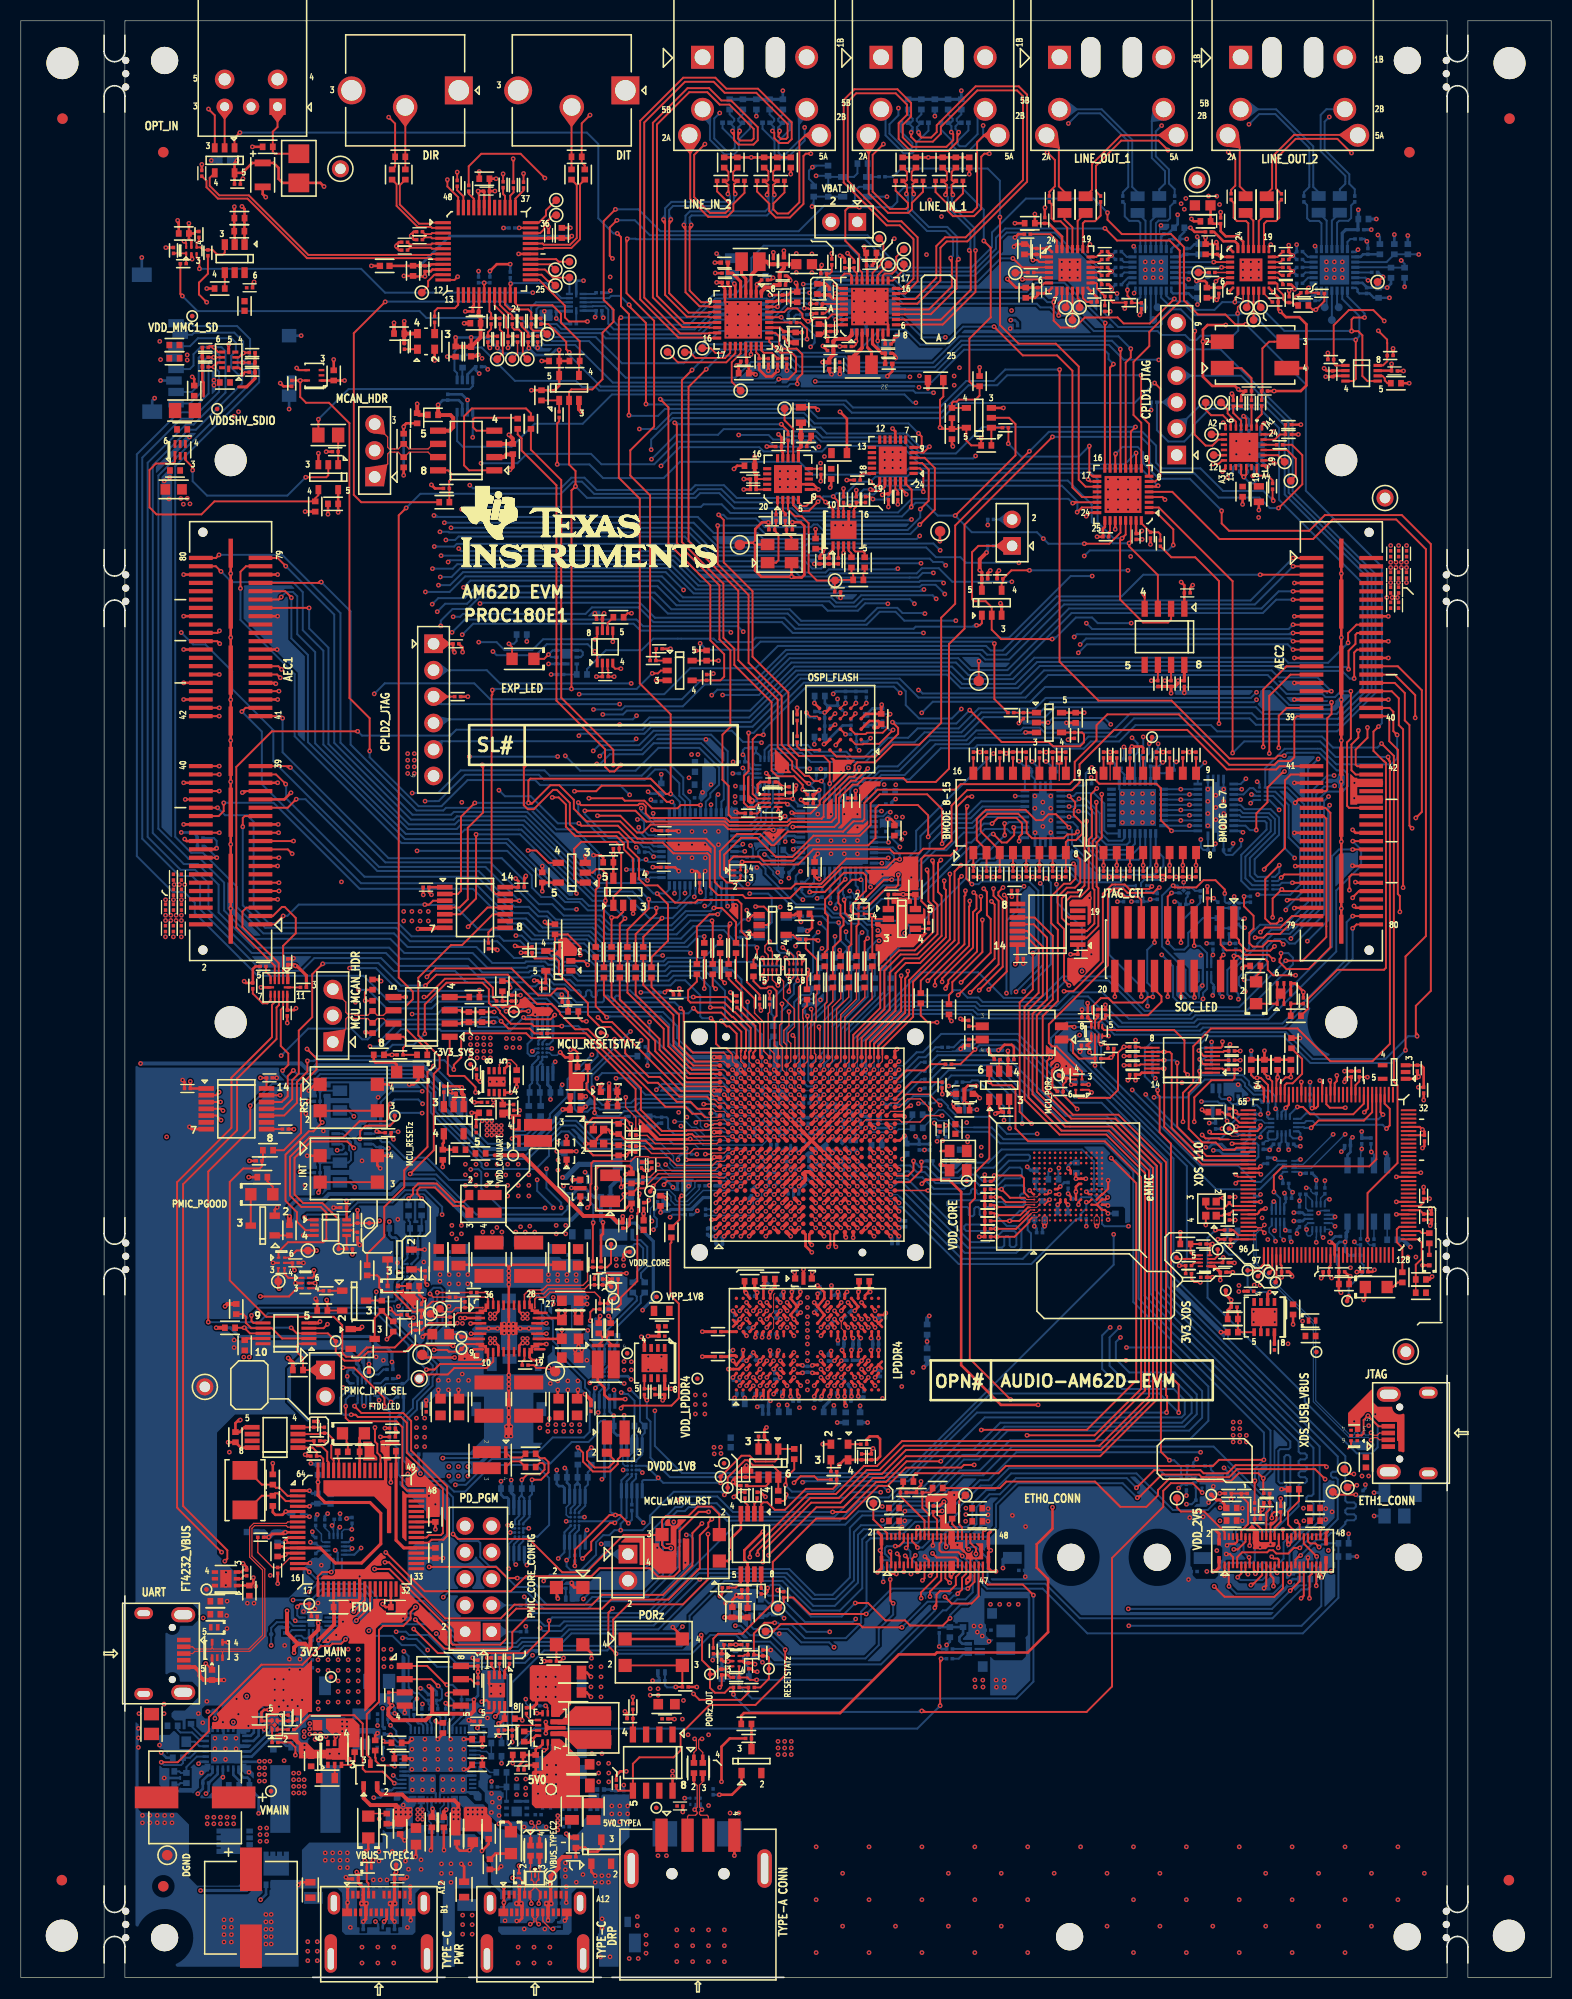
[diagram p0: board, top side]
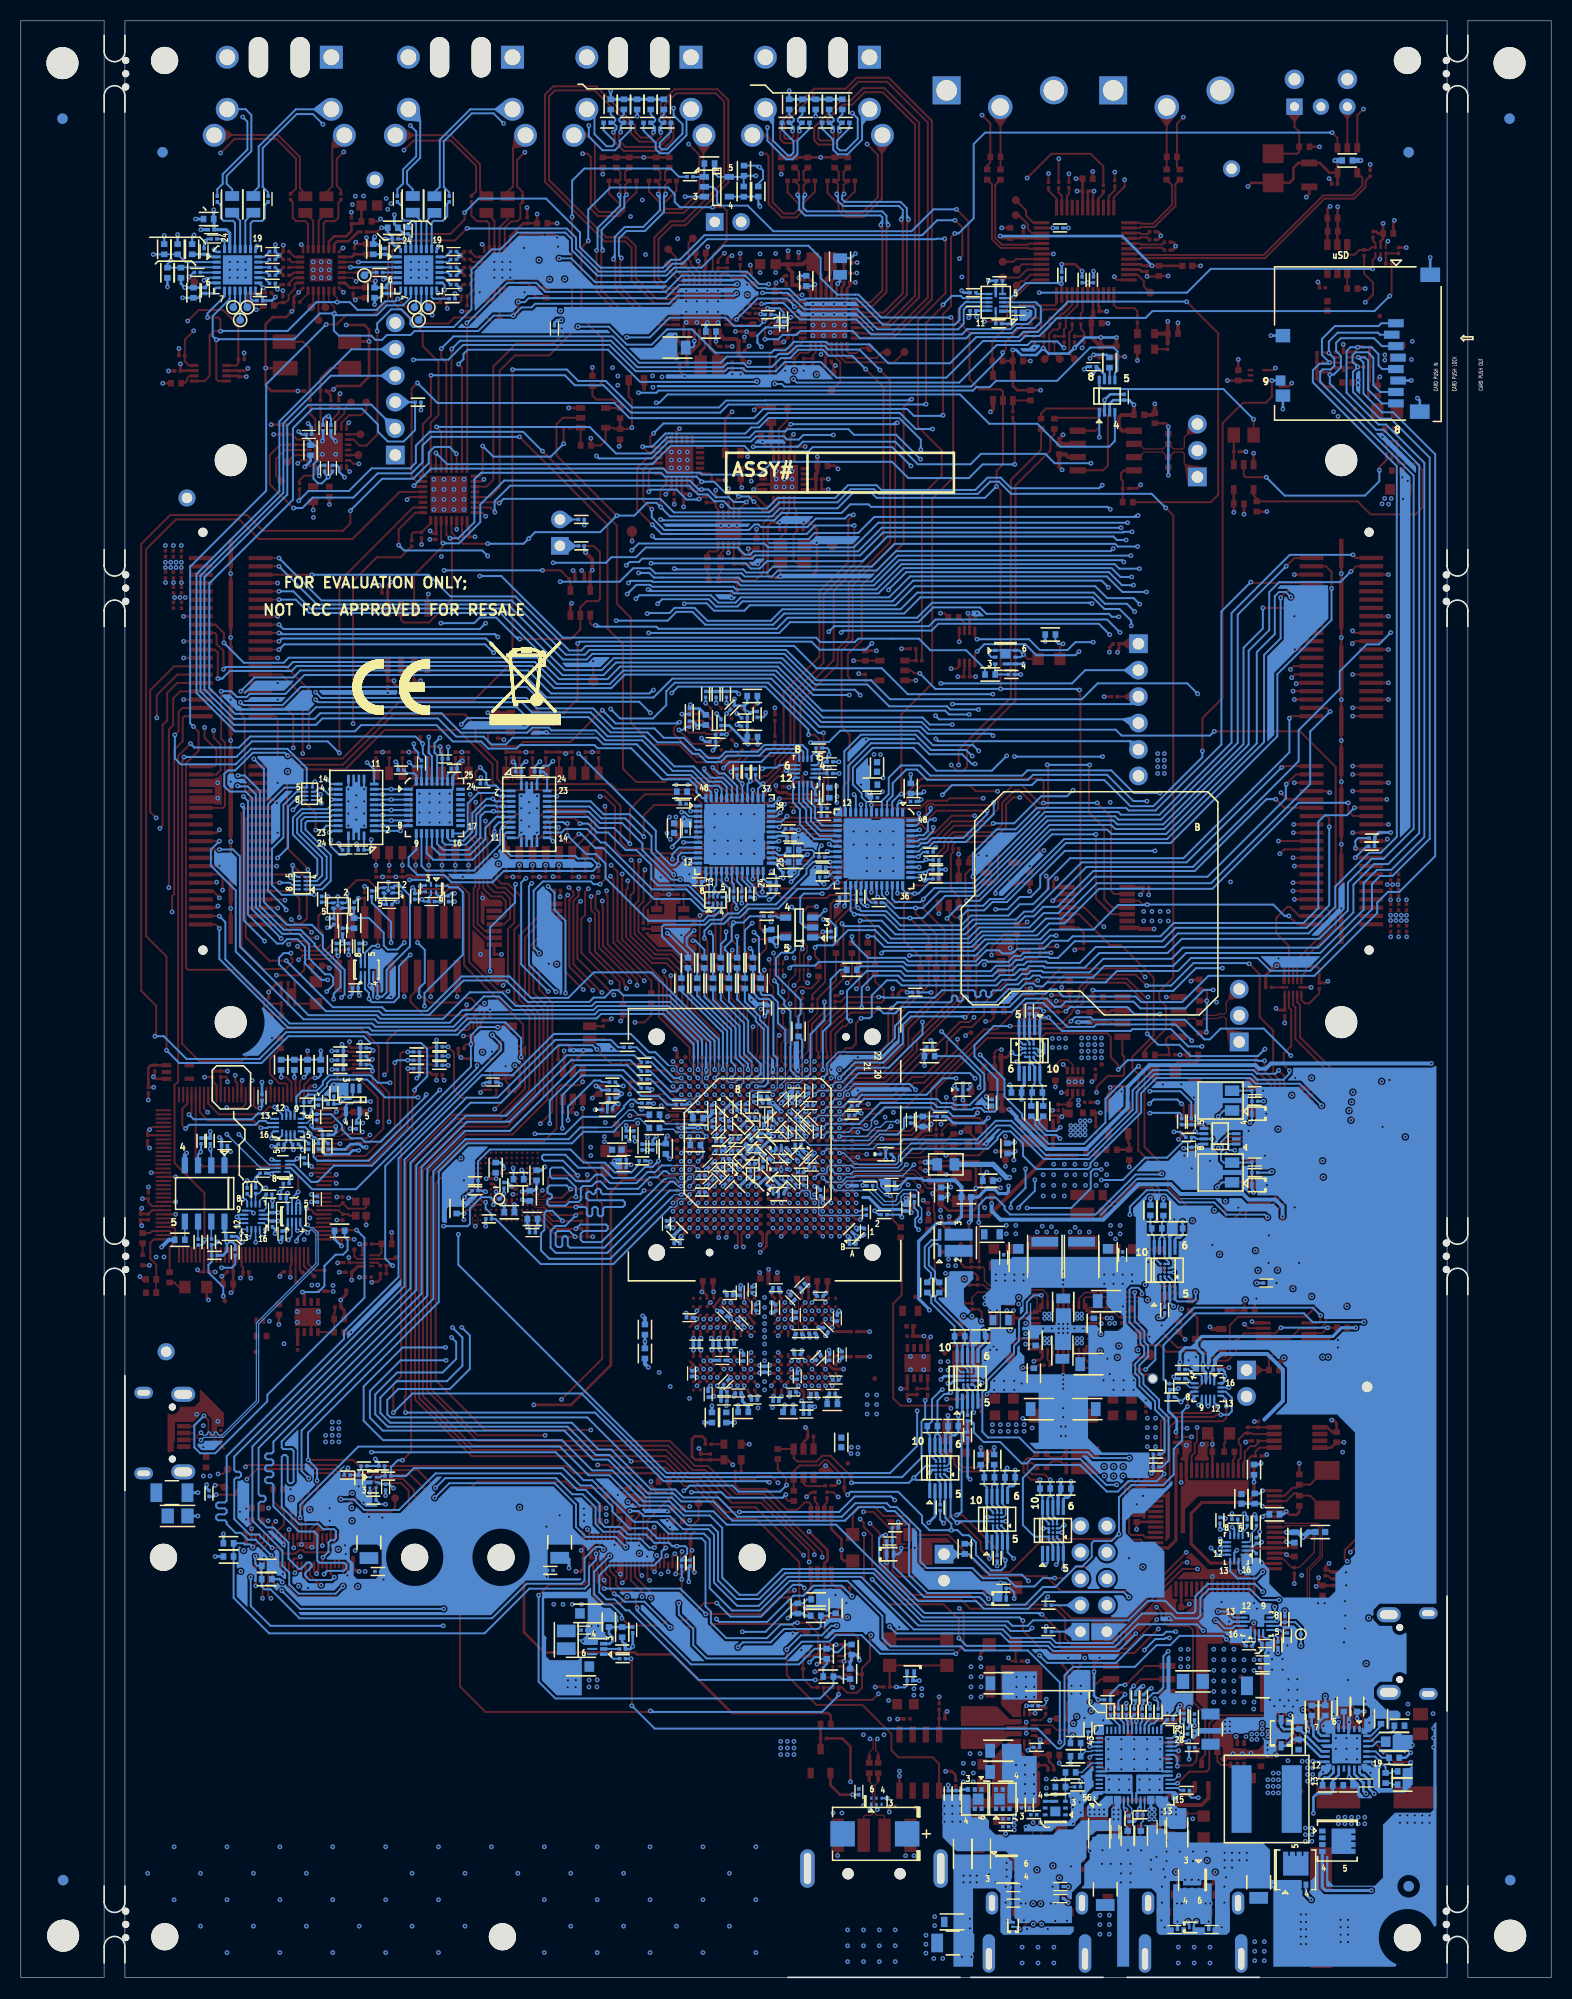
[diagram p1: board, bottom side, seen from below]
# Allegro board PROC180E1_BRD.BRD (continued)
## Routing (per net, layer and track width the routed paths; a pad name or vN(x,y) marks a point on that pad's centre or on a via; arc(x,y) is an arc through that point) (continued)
N21784176: length 5.8
  TOP w0.132: U47.V13 v1(81.16,81.59)
  BOTTOM w0.14: R541.1 85.65,82.57 85.07,81.99 81.56,81.99 v1(81.16,81.59)
N22498870: length 1.9
  BOTTOM w0.191: R602.1 112.06,48.61 112.01,48.56 R605.2 112.37,48.15 112.47,48.05 U120.6
N22498881: length 3
  BOTTOM w0.191: R606.1 114.55,48.54 114.32,48.77 R601.1 ; R606.1 115,48.25 R604.2 ; R606.1 113.97,48.25 113.76,48.05 U120.1
N22682556: length 2.8
  BOTTOM w0.191: R633.2 J21.1
N22682559: length 2.8
  BOTTOM w0.191: J21.3 R627.2
N24305910: length 3.8
  TOP w0.14: R296.2 44.72,65.34 44.87,65.19
  TOP w0.15: 44.87,65.19 U56.36
N24305927: length 2.4
  TOP w0.15: R294.2 44.78,65.79 45.37,65.2 U56.35
N24306091: length 1.5
  TOP w0.191: R293.1 28.57,65.96 28.33,66.2 U54.4
N24306101: length 1.2
  TOP w0.191: Q4.1 R293.2
N24306157: length 46.3
  TOP w0.191: v1(37.91,35.56) 37.44,35.09 37.44,34.46 36.74,33.76 34.79,33.76 34.4,33.37 34.4,26.46 33.23,25.29 33.23,21.39 33.58,21.05 D5.3 ; R308.2 35.77,62.03 35.77,61.91 v1(35.16,61.3)
  L03_SIG01 w0.076: v1(37.91,35.56) 36.6,36.88 36.6,48.46 36.6,48.46 36.6,51.52 36.81,51.73 36.81,56.38 35.23,57.97 35.23,61.23 v1(35.16,61.3)
N24306190: length 1.5
  TOP w0.191: R298.2 Q4.3
N24307593: length 8.3
  TOP w0.191: U57.2 25.1,61.36 24.1,62.36 U57.7 22.13,62.36 21.61,62.88 21.61,63.46 21.36,63.71 R302.1
N24478126: length 1.5
  TOP w0.191: C70.1 U4.4
N24517110: length 1.3
  TOP w0.191: SW3.3 91.06,91.37 R214.2
N24517112: length 1.3
  TOP w0.191: SW3.4 R217.2
N24582539: length 2.4
  TOP w0.191: U74.4 R383.1 R379.2
N24591228: length 1.1
  TOP w0.191: R274.2 32.01,71.59 31.83,71.77 U50.6
N24605604: length 14.4
  TOP w0.191: C18.1 90.5,171.38 89.43,170.31 89.43,169.86 89.7,169.59 91.4,169.59 91.86,170.04 91.86,176.3 92.51,176.96 J2.5A
N24605606: length 13.9
  TOP w0.191: J2.2A 81.44,176.89 81.44,171.37 83.3,169.51 85.26,169.51 85.6,169.85 85.6,170.47 86.66,171.54 C16.1
N24605709: length 2.8
  TOP w0.191: R84.2 94.3,148.87 U14.1 93.22,148.87 R90.1
N24605835: length 4.7
  TOP w0.183: TP5.1 82.86,166.65 82.86,165.04 82.65,164.83 82.65,164.58 81.81,163.74 U7.20
N24605846: length 3.3
  TOP w0.191: 81.34,156.56 81.31,156.59 U7.4
  TOP w0.305: 81.34,156.56 81.71,156.19 L3.2
N24605909: length 9.5
  BOTTOM w0.191: J2.5B 83.06,179.03 83.06,176.96 84.79,175.24 85.62,175.24 86.01,175.63 86.01,176.24 87.18,177.4 C333.1
N24606047: length 2
  TOP w0.183: U7.19 82.31,163.52 82.43,163.65 82.84,164.05 82.84,164.05 TP8.1
N24606049: length 2.4
  TOP w0.183: TP9.1 84.82,164.06 83.77,163.01 U7.17
N24606166: length 7.7
  BOTTOM w0.191: J2.2B 91.9,178.73 91.9,177.08 90.74,175.91 90.19,175.91 90,176.1 90,176.41 91.02,177.43 C331.1
N24612310: length 3.1
  TOP w0.191: U3.19 45.01,160.03 45.17,159.87 R40.1 R41.1
N24612323: length 3.7
  TOP w0.191: R43.1 R42.1 47.2,159.64 47.01,159.83 46.84,159.83 46.01,160.66 U3.21
N24612337: length 4.2
  TOP w0.191: R42.2 47.2,158.5 47.41,158.29 47.84,158.29 48.22,157.91 48.22,155.9 TP30.1
N24612352: length 3.7
  TOP w0.191: TP28.1 46.29,155.99 46.29,158.01 46.01,158.29 R41.2
N24612373: length 5.2
  TOP w0.191: U3.22 46.51,160.7 46.98,160.23 48.75,160.23 49.03,159.95 R44.1 R45.1
N24612400: length 2.2
  TOP w0.191: R44.2 49.03,158.38 49.22,158.19 50.23,158.19 TP24.1
N24612414: length 3.5
  TOP w0.191: U3.34 49.89,167.57 50.27,167.94 50.27,168.41 51.15,169.29 TP4.1
N24612459: length 3.1
  TOP w0.191: TP16.1 39.12,162.45 39.12,162.96 39.73,163.57 U3.11
N24612593: length 1.8
  TOP w0.145: TP29.1 47.71,155.97 R52.2
N24612656: length 4
  TOP w0.191: TP13.1 51.12,163.29 50.35,164.07 U3.27
N24612672: length 2.6
  TOP w0.191: U3.28 50.83,164.57 TP10.1
N24612674: length 3.8
  TOP w0.191: U3.29 51.42,165.07 51.67,164.82 TP7.1
N24612683: length 2.8
  TOP w0.191: TP15.1 50.93,162.94 50.65,162.94 50.02,163.57 U3.26
N24612758: length 5.4
  TOP w0.191: U3.20 45.51,160.61 46.62,159.51 46.62,158.5 46.8,158.33 R51.1 R52.1
N24612803: length 3.6
  TOP w0.191: TP3.1 50.44,169.75 50.44,169.26 49.75,168.57 U3.36
N24614507: length 2.8
  TOP w0.191: R72.1 51.71,151.49 U13.1 51.71,150.42 R79.2
N24847876: length 1.5
  BOTTOM w0.191: R421.1 U77.4
N24847884: length 13.8
  BOTTOM w0.191: C348.1 107.27,171.48 106.75,172 106.75,176.53 103.83,179.46 J3.5B
N24847886: length 9.6
  BOTTOM w0.191: J3.2B 108.64,178.33 108.64,174.79 109.9,173.52 109.9,172.52 109.9,172.33 109.35,171.78 C347.1
N24847888: length 3.8
  BOTTOM w0.191: C347.2 108.53,168.71 U77.21
N24847892: length 5.7
  BOTTOM w0.191: U77.19 107.53,168.55 107.34,168.74 106.48,168.74 106.04,169.18 106.04,170.38 C344.2
N24847894: length 5.8
  BOTTOM w0.191: C343.2 110.39,170.12 110.39,168.99 110.16,168.76 109.29,168.76 109.03,168.5 U77.22
N24847910: length 3.8
  BOTTOM w0.191: U77.20 108.03,168.75 C348.2
N24847912: length 1.7
  BOTTOM w0.191: U77.11 108.03,160.62 TP113.1
N24847957: length 1.2
  BOTTOM w0.191: C367.1 105.99,163.78 U77.15
N24847963: length 1.1
  BOTTOM w0.191: C365.1 105.73,164.28 U77.16
N24847969: length 1.2
  BOTTOM w0.191: U77.17 105.96,164.78 C362.1
N24847975: length 1.3
  BOTTOM w0.191: U77.18 106.23,165.28 C360.1
N24847993: length 1.7
  BOTTOM w0.191: TP112.1 109.03,160.6 U77.9
N24847995: length 2.9
  BOTTOM w0.191: U77.10 108.53,159.47 TP115.1
N24848039: length 1.5
  TOP w0.191: R24.1 U5.4
N24848041: length 12.6
  TOP w0.191: J3.5A 111.01,176.97 105.67,176.97 102.89,174.19 102.89,171.72 C25.1
N24848043: length 6.6
  TOP w0.191: J3.2A 99.71,175.77 99.71,172.06 100.25,171.52 C24.1
N24848045: length 3.8
  TOP w0.191: C24.2 100.25,168.89 101.01,168.12 U5.21
N24848047: length 5.8
  TOP w0.191: U5.19 102.01,168.51 102.22,168.71 103.18,168.71 103.72,169.25 C23.2
N24848049: length 5.6
  TOP w0.191: U5.22 100.51,168.07 99.88,168.7 99.29,168.7 99.01,168.98 99.01,170.35 C22.2
N24848518: length 3.8
  TOP w0.191: U5.20 101.51,168.74 C25.2
N24848523: length 1.7
  TOP w0.191: U5.11 101.51,161.29 101.7,161.1 TP18.1
N24848568: length 1.2
  TOP w0.191: C61.1 103.56,163.78 U5.15
N24848574: length 1.1
  TOP w0.191: U5.16 103.82,164.28 C56.1
N24848580: length 1.2
  TOP w0.191: C50.1 103.58,164.78 U5.17
N24848586: length 1.3
  TOP w0.191: U5.18 103.32,165.28 C47.1
N24848600: length 1.2
  TOP w0.191: TP12.1 95.56,163.78 R24.2
N24848612: length 1.3
  BOTTOM w0.191: R421.2 113.73,163.78 TP109.1
N24848616: length 1.7
  TOP w0.191: U5.9 100.51,160.6 TP17.1
N24848618: length 2.8
  TOP w0.191: U5.10 TP22.1
N24851304: length 1.6
  BOTTOM w0.191: R420.1 129.75,163.78 U76.4
N24851306: length 1.4
  TOP w0.191: TP14.1 130.38,162.87 v1(130.85,163.35)
  BOTTOM w0.191: R420.2 130.41,163.79 v1(130.85,163.35)
N24851312: length 13.4
  BOTTOM w0.191: C346.1 124.67,171.48 124.15,172 124.15,172.19 124.15,175.89 120.58,179.46 J4.5B
N24851314: length 11.5
  BOTTOM w0.191: C345.1 126.7,171.78 127.23,172.3 127.23,172.49 127.23,173.06 124.86,175.43 124.86,178.92 125.41,179.47 127.16,179.47 J4.2B
N24851316: length 3.8
  BOTTOM w0.191: U76.21 125.93,168.76 C345.2
N24851320: length 5.8
  BOTTOM w0.191: C342.2 123.56,170.26 123.56,168.99 123.81,168.73 124.7,168.73 124.93,168.51 U76.19
N24851322: length 5.8
  BOTTOM w0.191: C341.2 127.79,170.22 127.79,169.01 127.52,168.75 126.63,168.75 126.43,168.55 U76.22
N24851338: length 3.8
  BOTTOM w0.191: U76.20 125.43,168.76 C346.2
N24851340: length 1.7
  BOTTOM w0.191: U76.11 125.43,160.62 TP111.1
N24851385: length 1.2
  BOTTOM w0.191: C366.1 123.39,163.78 U76.15
N24851391: length 1.1
  BOTTOM w0.191: U76.16 123.12,164.28 C364.1
N24851397: length 1.2
  BOTTOM w0.191: U76.17 123.36,164.78 C361.1
N24851403: length 1.3
  BOTTOM w0.191: U76.18 123.63,165.28 C359.1
N24851421: length 1.7
  BOTTOM w0.191: TP110.1 126.43,160.6 U76.9
N24851423: length 2.8
  BOTTOM w0.191: U76.10 TP114.1
N24851452: length 1.5
  TOP w0.145: R25.1 U6.4
N24851454: length 1
  TOP w0.191: R25.2 TP11.1
N24851456: length 13.1
  TOP w0.191: C27.1 119.68,171.34 120.19,171.85 120.19,174.89 122.3,177 128.38,177 J4.5A
N24851458: length 6.6
  TOP w0.191: C26.1 117.65,171.49 117.08,172.06 117.08,175.8 J4.2A
N24851460: length 3.8
  TOP w0.191: C26.2 118.39,168.76 118.39,166.05 U6.21
N24851462: length 6
  TOP w0.191: U6.19 119.41,168.46 119.67,168.72 120.56,168.72 120.88,169.04 120.88,170.58 C21.2
N24851464: length 6
  TOP w0.191: U6.22 117.91,166.03 117.91,168.51 117.7,168.72 116.82,168.72 116.5,169.04 116.5,170.48 116.26,170.72 C20.2
N24851486: length 3.8
  TOP w0.191: U6.20 118.91,168.74 C27.2
N24851488: length 1.7
  TOP w0.191: U6.11 118.91,160.62 TP20.1
N24851535: length 1.2
  TOP w0.191: U6.15 120.79,163.78 121.06,163.51 C62.1
N24851541: length 1.1
  TOP w0.191: U6.16 121.22,164.28 C57.1
N24851547: length 1.2
  TOP w0.191: C51.1 120.98,164.78 U6.17
N24851553: length 1.3
  TOP w0.191: U6.18 120.72,165.28 C48.1
N24851571: length 1.7
  TOP w0.191: TP19.1 117.91,160.6 U6.9
N24851573: length 2.8
  TOP w0.191: U6.10 TP23.1
N25026172: length 11.4
  TOP w0.14: U47.G22 71.36,88.99 71.36,91.76 70.48,92.64 70.48,93.22
  TOP w0.191: 70.48,93.22 70.48,94.01 68.7,95.79 R169.1
N25026194: length 9.8
  TOP w0.14: 72.47,89.47 72.76,89.18 U47.H22
  TOP w0.191: R185.1 70.38,95.7 71.05,95.03 71.65,95.03 71.78,95.16 72.19,95.16 72.59,94.75 72.59,92.37 72.39,92.17 72.39,89.54 72.47,89.47
N25124626: length 11.5
  TOP w0.191: U47.E20 v1(69.96,87.19)
  BOTTOM w0.191: R496.1 68.28,96.8 69.22,95.86 69.22,91.61 69.96,90.87 v1(69.96,87.19)
N25124643: length 11.2
  TOP w0.132: U47.F21 v1(70.76,87.99)
  TOP w0.191: R183.1 66.46,95.24 v1(66.74,94.95)
  L03_SIG01 w0.076: v1(70.76,87.99) 71.3,88.54 71.3,90.05 66.74,94.61 v1(66.74,94.95)
N25124756: length 13.8
  TOP w0.132: U47.E21 69.96,87.99
  TOP w0.14: 69.96,87.99 69.96,88.23 69.96,88.81
  TOP w0.191: R182.1 64.94,95.66 64.1,94.82 64.1,93.88 64.33,93.65 67.58,93.65 68.51,92.72 68.6,92.72 70.11,91.21 70.11,89.03 69.96,88.88 69.96,88.81
N25128465: length 13.9
  TOP w0.191: R167.1 v1(65.65,94.98) ; U47.F20 v1(70.76,87.19)
  L03_SIG01 w0.076: v1(70.76,87.19) 69.96,87.99 69.96,90.52 65.63,94.85 65.63,94.96 v1(65.65,94.98)
N25128467: length 13
  TOP w0.132: U47.G21 v1(71.56,87.99)
  TOP w0.191: v1(67.62,95.53) 67.18,95.97 R168.1
  L03_SIG01 w0.076: v1(71.56,87.99) 71.56,90.39 67.41,94.55 67.41,95.31 v1(67.62,95.53)
N25521527: length 4.3
  TOP w0.183: U7.18 82.81,163.49 82.99,163.68 83.7,163.68 84.09,164.07 84.09,165.28 TP6.1
N25809420: length 10.7
  TOP w0.254: J18.SH2 82.67,41.21 82.53,41.07 v1(82.53,41.02) 82.53,40.92 82.67,40.78 J18.SH1
  TOP w0.305: 82.33,42.77 82.67,42.43 J18.SH2 ; 93.14,42.82 92.94,42.62 J18.SH4 92.94,41.24 v1(93.17,41.01) 92.94,40.79 J18.SH3 92.94,39.28 93.23,39 v1(93.67,39) ; J18.SH1 82.67,39.29 v1(82.29,38.91)
  BOTTOM w0.305: C610.1 94.49,40.3 94.34,40.15 v1(94.34,39.32)
N25815350: length 4.9
  TOP w0.305: J19.SH3 125.37,38.99 ; 125.51,42.82 125.37,42.68 J19.SH4 ; J19.SH1 115.1,39.36 114.73,38.99 v1(114.5,38.99) ; 114.77,42.95 115.1,42.62 J19.SH2
  vias: v1(113.92,38.99) v1(114.88,41) v1(125.6,41.01) v1(125.87,39.01)
N25906633: length 1.8
  TOP w0.191: v1(34.19,81.28) 34.33,81.14 R250.2
  BOTTOM w0.191: v1(34.19,81.28) 33.96,81.05 U98.6
N26034689: length 1.7
  BOTTOM w0.191: R640.2 90.09,30.61 90.53,31.05 U127.1
N26038083: length 1.2
  BOTTOM w0.191: C635.1 15.19,18.51 15.33,18.66 R670.2
N26038197: length 33.4
  L03_SIG01 w0.254: v1(21.7,27.01) 21.7,24.85 21.28,24.43 21.28,21.07 20.23,20.02 18.9,20.02 17.69,18.81 16.76,18.81 16.31,18.37 16.31,7.93 16.77,7.47 23.01,7.47 v1(23.03,7.45)
  BOTTOM w0.254: R650.2 21.72,26.12 R649.2 v1(21.7,27.01) ; Q11.4 23.55,7.97 v1(23.03,7.45)
N26038227: length 23.2
  L03_SIG01 w0.203: v1(17.78,17.65) 18.25,17.18 27.65,17.18 32.43,21.97 32.43,22.35 v1(34.27,24.18)
  BOTTOM w0.191: R659.1 v1(34.27,24.18)
  BOTTOM w0.254: U128.17 18.91,19.52 18.06,18.67 C634.2 18.04,17.91 v1(17.78,17.65)
N26228423: length 2.5
  TOP w0.191: U54.1 25.71,67.2 25.33,67.58 U52.4
N26271323: length 16.3
  TOP w0.191: R386.2 26.37,23.8 27.75,25.18 32.03,25.18 32.84,24.37 32.84,20.03 33.11,19.76 34.77,19.76 v1(35.88,18.64)
  BOTTOM w0.191: v1(35.88,18.64) 35.94,18.58 U129.17
N26451841: length 1.3
  BOTTOM w0.191: U85.23 69.02,106.15 69.46,105.71 R472.1
N26451883: length 1.2
  BOTTOM w0.191: R468.1 69.21,107.62 69.18,107.65 U85.20
N26455193: length 3
  BOTTOM w0.191: U80.4 70.53,116.45 70.36,116.62 70.36,117.45 70.61,117.7 ; 70.61,117.7 70.78,117.54 70.82,117.54 71.04,117.32 U80.5 ; 70.61,117.7 R455.1
N26455313: length 3.1
  BOTTOM w0.191: U80.1 70.43,115.25 70.28,115.1 70.28,114.52 70.72,114.07 ; U80.16 71.04,114.39 70.72,114.07 ; 70.72,114.07 70.67,114.02 R462.2
N26461930: length 1.9
  TOP w0.191: U29.4 71.21,112.44 70.96,112.19 70.96,112 70.77,111.81 70.18,111.81 R143.1
N26517285: length 1.5
  BOTTOM w0.191: U84.31 73.85,110.04 R463.1
N26567066: length 1.5
  BOTTOM w0.191: U84.24 75.7,105.6 75.3,105.2 R474.2
N26593111: length 2.9
  TOP w0.191: R86.2 30.49,148.16 R91.1 30.48,146.56 U19.1
N26594023: length 3.1
  TOP w0.14: U42.6 45.97,87.68 46.43,88.14 47.11,88.14 47.63,87.63 C193.1
N26608860: length 9.3
  TOP w0.191: R184.1 67.99,95.92 69.3,94.61 69.3,93.29 70.81,91.78 70.81,91.78 71.01,91.58 71.01,88.54 U47.F22
N26609186: length 7.5
  TOP w0.132: U47.C8 v1(68.36,76.79)
  L03_SIG01 w0.076: v1(68.36,76.79) 68.77,76.38 68.77,75.26 68.29,74.78 66.49,74.78 65.35,73.64 v1(64.99,73.64)
  BOTTOM w0.191: R574.1 64.62,73.27 v1(64.99,73.64)
N27056893: length 2.3
  BOTTOM w0.191: R484.2 65.31,103.24 65.79,103.73 U85.29
N27107689: length 2.3
  TOP w0.191: C308.1 32.06,20.75 31.72,20.41 U73.3
N27107697: length 7.4
  TOP w0.191: R382.2 v1(25.06,25.19) ; U73.5 30.15,23.04 v1(30.26,23.15)
  L03_SIG01 w0.076: v1(30.26,23.15) 28.22,25.19 v1(25.06,25.19)
N27107782: length 1.3
  TOP w0.191: R395.2 U73.2
N27108105: length 1.9
  TOP w0.14: LD8.2 33.63,15.73 R397.2
N27116765: length 2
  TOP w0.191: U59.5 R319.2 R320.1
N27118410: length 1.4
  TOP w0.14: U46.3 R240.2
N27118414: length 2.8
  TOP w0.254: R255.2 R258.1 40.53,80.09 40.63,80.19 U46.4
N27128284: length 1.2
  TOP w0.191: U62.1 80.69,51.21 R329.1
N27128639: length 1.6
  TOP w0.191: R348.1 70.72,45.75 70.46,45.49 U65.2
N27128753: length 1.6
  TOP w0.191: U65.3 69.81,45.37 69.56,45.63 69.56,46.04 R349.1
N27128755: length 2.2
  TOP w0.191: U65.5 69.16,37.92 68.67,37.43 R358.1
N27128757: length 1.4
  TOP w0.191: R359.1 71.11,38.74 U65.8
N27132714: length 1.5
  TOP w0.191: SW2.13 R137.1
N27132716: length 1.5
  TOP w0.191: SW2.14 R136.1
N27132718: length 1.5
  TOP w0.191: SW2.15 R135.1
N27132720: length 1.5
  TOP w0.191: SW2.16 R134.1
N27132816: length 1.5
  TOP w0.191: SW1.11 R131.1
N27132818: length 1.5
  TOP w0.191: SW1.12 R130.1
N27132820: length 1.5
  TOP w0.191: SW1.13 R129.1
N27132822: length 1.5
  TOP w0.191: SW1.14 R128.1
N27132824: length 1.5
  TOP w0.191: SW1.9 R133.1
N27132826: length 1.5
  TOP w0.191: SW1.10 R132.1
N27132828: length 1.5
  TOP w0.191: SW1.15 R127.1
N27132836: length 1.5
  TOP w0.191: SW1.16 R126.1
N27133243: length 1.5
  TOP w0.191: SW2.9 R141.1
N27133247: length 1.5
  TOP w0.191: SW2.10 R140.1
N27133249: length 1.5
  TOP w0.191: SW2.11 R139.1
N27133251: length 1.5
  TOP w0.191: SW2.12 R138.1
N27148451: length 2.7
  TOP w0.191: U28.A5 74.9,117.91 74.57,118.25 R125.2
N27152136: length 7.2
  TOP w0.132: U47.Y17 v1(82.76,84.79)
  L03_SIG01 w0.076: v1(86.35,85.29) 87.02,85.29 87.22,85.09 87.22,84.76 87.05,84.59 85.32,84.59 85.06,84.32 83.23,84.32 v1(82.76,84.79)
  BOTTOM w0.191: v1(86.35,85.29) 86.5,85.43 R530.1
N27152138: length 6.7
  TOP w0.132: U47.V16 v1(81.16,83.99)
  L03_SIG01 w0.076: v1(86.22,83.94) 85.99,84.17 85.36,84.17 85.26,84.07 83.53,84.07 83.05,83.59 81.56,83.59 v1(81.16,83.99)
  BOTTOM w0.191: R535.1 86.34,83.98 86.3,83.94 v1(86.22,83.94)
N27152140: length 1.4
  TOP w0.132: U47.Y16 v1(82.76,83.99)
  BOTTOM w0.191: v1(82.76,83.99) 82.91,83.84 R537.1
N27152142: length 7.6
  TOP w0.132: U47.AA17 v1(83.55,84.79)
  L03_SIG01 w0.076: v1(89.12,85.63) 88.89,85.86 86.11,85.86 85.04,84.79 v1(83.55,84.79)
  BOTTOM w0.191: v1(89.12,85.63) 89.52,85.63 R529.1
N27152150: length 6.7
  TOP w0.132: U47.AA19 v1(83.56,86.39)
  BOTTOM w0.191: v1(83.56,86.39) 84.24,86.39 86.25,88.39 86.9,88.39 87.86,89.35 R509.1
N27152152: length 5.6
  TOP w0.132: U47.Y18 v1(82.76,85.59)
  BOTTOM w0.102: 84.53,86.01 83.17,86.01 v1(82.76,85.59)
  BOTTOM w0.191: 84.53,86.01 86.44,87.92 R518.1
N27152154: length 4.9
  TOP w0.132: U47.AA18 v1(83.56,85.59)
  BOTTOM w0.191: v1(83.56,85.59) 84.04,85.11 84.6,85.11 86.54,87.05 R527.1
N27152156: length 6.4
  TOP w0.132: U47.W17 v1(81.96,84.79)
  BOTTOM w0.102: v1(81.96,84.79) 82.38,84.37 83.65,84.37
  BOTTOM w0.191: 83.65,84.37 84.59,84.37 86.49,86.28 R528.1
N27153825: length 14.8
  TOP w0.132: U47.B20 67.56,87.19 66.79,87.19
  TOP w0.191: R188.1 59.06,94.4 62.2,91.26 62.2,89.45 64.46,87.19 66.79,87.19
N27153827: length 18.1
  TOP w0.132: U47.B18 67.56,85.59 66.33,85.59
  TOP w0.191: 66.33,85.59 63.7,85.59 60.29,89 60.29,90.07 56.01,94.35 R186.1
N27153829: length 16.4
  TOP w0.132: U47.B19 67.56,86.39 66.67,86.39
  TOP w0.191: R187.1 57.53,93.96 61.35,90.14 61.35,89.1 64.06,86.39 66.67,86.39
N27153831: length 22.4
  TOP w0.132: U47.C19 v1(68.36,86.39)
  TOP w0.191: v1(56.28,92.23) 55.22,93.29 R171.1
  BOTTOM w0.191: v1(56.28,92.23) 56.36,92.31 61.48,92.31 62.28,91.51 62.28,89.72 64.12,87.88 66.87,87.88 v1(68.36,86.39)
N27153833: length 13.1
  TOP w0.132: U47.B21 67.56,87.99 66.3,87.99
  TOP w0.191: 66.3,87.99 64.76,87.99 63.23,89.53 63.23,92.48 60.58,95.13 R189.1
N27153850: length 16.6
  TOP w0.191: R173.1 58.27,94.6 61.75,91.12 61.75,89.31 64.27,86.79 U47.A20
N27153866: length 18.2
  TOP w0.191: U47.A19 63.91,85.99 60.94,88.97 60.94,89.96 56.74,94.16 R172.1
N27153868: length 15
  TOP w0.191: R174.1 59.79,95.34 62.69,92.44 62.69,89.5 64.6,87.59 U47.A21
N27154979: length 1.8
  TOP w0.132: U47.C14 v1(68.36,82.39)
  BOTTOM w0.191: R542.2 67.46,82.58 67.65,82.39 v1(68.36,82.39)
N27158706: length 13.9
  TOP w0.132: U47.E16 v1(69.96,83.99)
  L03_SIG01 w0.076: v1(60.2,87.58) 60.75,87.58 63.11,85.22 65.94,85.22 66.98,84.18 68,84.18 68.22,84.4 69.63,84.4 69.96,84.07 v1(69.96,83.99)
  BOTTOM w0.191: v1(60.2,87.58) 60.2,87.87 60.2,87.88 R514.1 60.2,89.17 R508.2
N27158712: length 4.7
  TOP w0.132: U47.F14 v1(70.76,82.39)
  BOTTOM w0.14: 67.68,83.28 68.17,82.79 70.36,82.79 v1(70.76,82.39)
  BOTTOM w0.191: 67.68,83.28 67.22,83.74 R538.1
N27161108: length 4.4
  TOP w0.254: D6.3 55.75,12.43 55.39,12.07 54.59,12.07 54.2,12.46 R398.2 R401.1
N27162183: length 6.1
  L04_PWR1 w0.381: v1(51.57,14.15) v1(51.57,14.61) v1(51.57,15.07) v1(51.57,15.53) 51.57,16.41 52.55,17.38
  BOTTOM w0.254: Q8.3 56.59,18.04 56.7,17.93 C638.2 R675.2 v1(57.92,18.47)
N27162479: length 3.7
  BOTTOM w0.14: R672.1 R669.2 ; R672.1 Q10.3 ; R672.1 R673.2
N27166782: length 2.8
  TOP w0.191: U32.8 45.35,100.83 44.91,100.39 44.91,99.38 R166.2
N27170778: length 3.6
  TOP w0.254: R324.1 33.9,88.07 34.08,87.88 35.89,87.88 36.1,87.68 LD6.2
N27173972: length 2.4
  TOP w0.191: R203.2 123.19,93.53 Q1.3 121.98,92.38 R213.2
N27173989: length 2.3
  BOTTOM w0.191: R442.2 R441.2 Q5.3
N27174010: length 7.2
  TOP w0.191: v1(50.69,127.08) 50.27,126.66 LD10.1
  BOTTOM w0.191: Q5.5 50.93,126.83 v1(50.69,127.08) 51.09,127.48 Q5.6 52.1,127.48 Q5.8 52.75,127.48 Q5.1 53.8,127.48 53.98,127.3 53.98,127.03 53.77,126.83 Q5.2
N27174034: length 6.5
  TOP w0.191: Q1.5 121.33,94.83 Q1.8 ; Q1.8 120.68,94.18 Q1.1 LD1.1 ; Q1.8 120.68,94.83 Q1.6 ; Q1.8 121.33,94.18 Q1.2
N27174097: length 1.7
  TOP w0.191: LD1.2 118.65,96.17 119.07,96.58 R180.1
N27174144: length 3
  TOP w0.191: v1(46.88,128.11) 47.18,127.8 LD10.2
  BOTTOM w0.191: v1(46.88,128.11) 47.35,128.11 47.62,128.38 R440.1
N27175754: length 2.7
  TOP w0.191: R95.2 120.24,143.81 119.79,144.26 118.94,144.26 118.72,144.49 U15.18
N27175817: length 5.3
  TOP w0.191: R74.2 C104.2 118.22,153.63 117.26,154.59 Y1.1
N27175821: length 7.7
  TOP w0.191: Y1.3 120.41,157.13 120.4,157.13 119.9,157.13 119.26,156.49 119.26,152.46 C105.1 119.19,152.39 R73.2
N27175987: length 19.4
  TOP w0.191: v1(117.45,149.98) 117.72,149.72 U15.3 ; v1(120.31,148.5) 120.05,148.23 U15.24 ; U15.15 117.22,144.39 v1(117.47,144.13) 117.72,144.38 U15.16
  L03_SIG01 w0.254: v1(120.31,148.5) 118.54,148.5 117.45,149.59 v1(117.45,149.98)
  BOTTOM w0.191: v1(117.47,144.13) 117.83,144.49 C386.1 ; v1(117.47,144.13) 118.08,143.53 118.44,143.53 118.89,143.97 118.89,145.36 118.52,145.73 118.52,146.95 118.77,147.2 C385.1 119.17,147.53 119.58,147.94 119.58,148.2 C384.1 120.04,148.22 v1(120.31,148.5) ; v1(117.47,144.13) 117.07,144.53 C387.1 ; C382.1 117.97,149.69 117.68,149.98 v1(117.45,149.98) 117.21,149.74 C383.1
N27176057: length 1.2
  TOP w0.191: TP36.1 114.95,148.23 114.95,148.23 U15.7
N27176072: length 1.3
  TOP w0.191: U15.22 R89.2
N27176107: length 5.8
  TOP w0.191: U15.21 121.63,146.73 122.47,145.89 122.47,144.25 TP39.1
N27176638: length 1
  TOP w0.191: TP37.1 114.59,146.23 U15.11
N27176640: length 2.3
  TOP w0.191: U15.20 120.75,146.23 TP38.1
N27177966: length 1.7
  TOP w0.191: U20.13 73.69,146.96 73.69,146.96 R87.2
N27177989: length 5.2
  TOP w0.191: R104.2 72.54,139.5 72.42,139.38 C124.1 72.42,138.98 72.78,138.62 72.78,136.14 72.54,135.9 Y2.1
N27177993: length 2.5
  TOP w0.191: Y2.3 74.03,138.33 73.55,138.81 C125.2 73.55,139.44 73.43,139.56 R105.2
N27178052: length 1.2
  TOP w0.191: U22.2 R109.1
N27178112: length 1.1
  TOP w0.191: U22.8 R99.2
N27178169: length 1.2
  TOP w0.191: U22.4 79.52,137.05 79.78,136.79 R110.1
N27178171: length 2
  TOP w0.191: U22.5 80.02,137.12 80.17,136.98 80.89,136.98 81.05,136.82 R111.1
N27178190: length 1.2
  TOP w0.191: R111.2 81.05,135.02 80.94,134.9 R113.1
N27178282: length 5.1
  TOP w0.191: U20.12 74.19,148.76 73.36,149.59 TP34.1
N27178331: length 2.1
  TOP w0.191: R101.1 R100.1 80.25,141.3 80.02,141.07 U22.6
N27178482: length 3.5
  TOP w0.305: C111.1 74.69,146.82 U20.11
  TOP w0.381: C111.1 C110.1 R80.1
N27201903: length 1.5
  TOP w0.191: U24.6 56.36,130.11 R114.2
N27212070: length 1.5
  TOP w0.191: U45.8 R248.1
N27212579: length 1.3
  TOP w0.191: R161.1 U34.8
N27213236: length 1.3
  TOP w0.191: R196.1 U37.12
N27224404: length 2
  TOP w0.183: v1(73.04,159.48) U8.29
  BOTTOM w0.191: R432.2 73.46,159.07 v1(73.04,159.48)
N27224468: length 9.8
  BOTTOM w0.191: C337.1 70.04,177.61 69.01,176.59 68.97,176.54 68.97,175.58 68.52,175.13 67.59,175.13 66.19,176.53 66.19,178.75 J1.5B
N27224561: length 3.3
  TOP w0.305: U8.4 69.64,161.74 69.64,163.18 69.23,163.58 L2.2
N27224667: length 9.3
  BOTTOM w0.191: J1.2B 74.75,178.72 74.75,176.45 73.33,175.03 73.05,175.03 72.78,175.3 72.78,176.4 73.88,177.5 C335.1
N27224751: length 5.5
  TOP w0.183: TP27.1 64.26,156.11 64.81,155.57 67.65,155.57 68.14,156.05 U8.18
N27224753: length 5
  TOP w0.183: TP31.1 68.29,153.28 68.29,155.15 69.14,156 U8.20
N27224897: length 14.3
  TOP w0.191: J1.5A 75.37,176.96 74.78,176.38 74.78,170.53 73.71,169.45 72.68,169.45 72.29,169.85 72.29,170.4 73.35,171.47 C14.1
N27225024: length 2.8
  TOP w0.254: C77.1 73.94,160.93 73.81,161.06 C78.1 72.57,161.06 72.5,160.98 U8.32
N27225078: length 14.5
  TOP w0.191: J1.2A 64.3,176.89 64.3,170.86 66.03,169.12 67.84,169.12 68.44,169.72 68.44,170.36 69.51,171.43 C12.1
N27225127: length 8
  TOP w0.183: TP26.1 63.11,155.15 67.76,155.15 68.64,156.03 U8.19
N27225129: length 3
  TOP w0.183: TP25.1 66.26,156.51 66.73,156.04 67.45,156.04 67.64,156.22 U8.17
N27225150: length 2.1
  TOP w0.183: U8.28 73.93,158.98 R46.2
N27226002: length 2.4
  BOTTOM w0.191: R414.2 82.43,172.97 U75.1 81.34,172.97 R413.1
N27236897: length 1.3
  TOP w0.191: U33.4 R163.1
N27236901: length 1.6
  BOTTOM w0.191: R486.1 75.06,101.94 74.44,101.94 74.3,101.8 U89.4
N27236905: length 1.5
  TOP w0.191: R165.1 74.59,99.73 74.18,100.14 U35.4
N27237106: length 1.4
  TOP w0.191: U33.1 R162.2
N27239473: length 1.2
  BOTTOM w0.191: U117.5 34.55,57.07 34.99,57.51 R591.2
N27239479: length 2.4
  BOTTOM w0.191: U117.4 33.56,57.75 33.72,57.91 34.36,57.91 34.84,58.4 R590.1
N27239926: length 1.8
  BOTTOM w0.191: R635.2 25.75,33.08 26.03,33.36 26.04,33.36 26.04,33.36 26.71,33.36 26.72,33.36 U126.5
N27239932: length 2.5
  BOTTOM w0.191: U126.4 27.67,32.74 27.47,32.55 27.2,32.55 26.94,32.81 26.44,32.81 26.25,32.62 R636.1
N27240077: length 1.2
  BOTTOM w0.14: U125.5 29.64,42.75 29.2,43.19 R613.2
N27240083: length 2.3
  BOTTOM w0.14: R614.1 28.32,43.13 28.87,42.58 28.87,41.94 29.01,41.8 U125.4
N27243596: length 2.3
  TOP w0.191: U51.6 111.14,69.01 TP61.1
N27243598: length 1.5
  TOP w0.191: U51.3 114.68,69.01 114.97,69.3 TP58.1
N27248134: length 1.7
  BOTTOM w0.14: U107.7 128.71,70.96 R579.2
N27248136: length 1.7
  BOTTOM w0.14: R580.2 U107.6
N27283175: length 22.4
  TOP w0.132: U47.E12 v1(69.96,80.79)
  TOP w0.191: R234.2 54.45,86.95 54.49,86.91 54.49,86.04 54.33,85.88 54.33,85.33 55.11,84.56 v1(55.11,83.05)
  BOTTOM w0.14: v1(69.96,80.79) 69.56,81.19 67.49,81.19 67.08,81.6 66.22,81.6 66.02,81.4 65.65,81.4 65.28,81.76 65.28,82.35
  BOTTOM w0.191: 65.28,82.35 64.08,83.56 59.57,83.56 59.23,83.21 57.95,83.21 57.47,82.73 55.43,82.73 v1(55.11,83.05)
N27283177: length 27.9
  TOP w0.132: U47.D9 v1(69.16,77.59)
  TOP w0.191: v1(54.33,91.84) 53.9,91.84 53.55,92.19 R210.2
  L03_SIG01 w0.076: v1(61.94,78.08) 61.94,81.35 59.13,84.16 59.13,85.63 56.58,88.18 54.59,88.18 54.36,88.41 54.36,91.8 54.33,91.83 v1(54.33,91.84)
  BOTTOM w0.14: v1(69.16,77.59) 68.76,77.19 67.26,77.19 67.01,77.44 62.58,77.44 v1(61.94,78.08)
N27283214: length 4.8
  TOP w0.14: R252.1 58.51,81.38 57.9,81.99 C205.2 57.29,82.12 55.2,82.12 54.99,81.9 Y3.1
N27283220: length 2.6
  TOP w0.14: Y3.3 56.66,80.09 56.8,79.95 C209.2 58.01,79.95 58.11,79.84 R253.1
N27283414: length 10.1
  TOP w0.132: U47.D7 v1(69.16,75.99)
  BOTTOM w0.14: R570.2 61.41,75.06 61.63,75.29 62.16,75.29 62.45,74.99 62.45,74.6 62.84,74.21 64.16,74.21 65.55,75.59 67.72,75.59 67.73,75.59 68.76,75.59 v1(69.16,75.99)
N27283542: length 22.8
  TOP w0.132: 66.1,81.38 66.21,81.48 66.33,81.48 66.44,81.59 67.57,81.59 67.96,81.2 U47.B13
  TOP w0.14: 66.1,81.38 65.57,81.38
  TOP w0.191: 65.57,81.38 63.95,81.38 63.89,81.31 61.58,81.31 59.56,83.33 59.56,85.42 54.3,90.69 R216.1
N27289636: length 1.5
  TOP w0.191: U37.5 23.99,96.17 23.55,96.61 R181.2
N27290261: length 3.3
  TOP w0.191: R194.1 22.28,94.51 23.23,93.57 23.67,93.57 23.99,93.89 U37.7
N27380200: length 1.3
  BOTTOM w0.191: R427.2 52.7,162.98 U78.5
N27380212: length 1.3
  BOTTOM w0.191: U78.7 55.13,161.72 R428.1
N27380351: length 1.3
  BOTTOM w0.191: U78.12 53.35,158.86 R434.1
N27381124: length 1.2
  BOTTOM w0.191: R436.2 42.41,154.62 U79.6
N27417083: length 1.8
  BOTTOM w0.191: U84.26 74.41,107.54 74.03,107.16 R470.2
N27417117: length 2
  BOTTOM w0.191: R466.2 73.74,107.8 74.21,107.8 74.34,107.94 74.37,107.94 74.47,108.04 U84.27
N27566274: length 3
  TOP w0.191: LD2.1 22.08,75.21 Q2.3
N27566278: length 1.9
  TOP w0.191: R260.1 23.69,76.47 24.2,75.96 LD2.2
N27566306: length 1.4
  TOP w0.191: Q2.1 24.39,71.27 R272.2
N27566380: length 1
  TOP w0.191: R292.1 36.25,66.41 LD4.2
N27566388: length 2.5
  TOP w0.191: LD4.1 35.23,68.96 Q3.3
N27566452: length 3.7
  TOP w0.191: SW7.2 51.45,36.52 v1(51.58,36.38)
  BOTTOM w0.191: v1(51.58,36.38) 51.58,36.98 51.99,37.38 C613.2 52.35,37.38 D13.2
N27570222: length 15
  TOP w0.191: U31.1 56.92,103.81 57.67,104.56 57.67,107.88 57.47,108.07 R144.2 57.47,108.49 57.48,108.5 57.48,108.77 57.18,109.08 53.83,109.08 53.15,108.4 53.15,105.56 53.54,105.17 U30.1
N27570724: length 1.7
  TOP w0.191: U11.6 130.78,153.85 131.02,153.62 131.02,153.41 131.28,153.14 R69.2
N27571220: length 1.3
  TOP w0.191: R53.1 U9.1
N271759124: length 3
  TOP w0.191: U15.5 116.72,149.45 115.92,150.24 115.92,150.66 TP32.1
N271759125: length 4.1
  TOP w0.191: U15.6 116.22,149.31 115.46,150.07 114.33,150.07 113.81,150.59 TP33.1
N275664200: length 1.4
  TOP w0.191: R286.2 38.35,67.88 38.22,68.01 Q3.1

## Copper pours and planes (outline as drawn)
AVDD_3V3_DAC on TOP: 113.94,168.25 113.94,169.37 113.8,169.52 113.8,171.31 113.87,171.39 115.16,171.39 115.38,171.17 115.38,170.07 115.32,170.01 115.16,170.01 114.88,169.74 114.88,168.88 115.01,168.75 115.87,168.75 116.09,168.53 116.09,167.09 115.92,166.92 115.31,166.92 114.84,167.39 114.84,167.96 114.57,168.24 113.96,168.24
AVDD_3V3_DAC on L03_SIG01: 97.69,167.76 129.76,167.76 130.66,168.66 130.66,173.29 129.63,174.31 98.04,174.31 96.97,173.23 96.97,168.49
DGND on TOP (solid shape): 44.11,34.19 44.15,34.17 44.17,34.14 44.17,32.3 44.15,32.27 44.11,32.25 41.61,32.25 41.6,32.27 41.59,32.29 41.59,33.44 41.59,33.46 41.58,33.48 40.96,34.1 40.94,34.13 40.94,34.16 40.95,34.17 40.98,34.19
DGND on TOP (solid shape): 65.69,109.09 65.71,109.08 65.72,109.07 66.35,108.45 66.36,108.43 66.36,108.41 66.36,108.03 66.35,108 66.33,107.98 66.32,107.97 66.29,107.98 66.07,108.19 66.06,108.2 66.04,108.21 62.8,108.21 62.78,108.21 62.76,108.22 61.98,109 61.97,109.03 61.97,109.06 61.98,109.07 62,109.09
DGND on TOP (solid shape): 77.91,113.25 77.94,113.26 77.97,113.26 77.98,113.25 78,113.23 78,111.57 77.99,111.55 77.98,111.53 77.75,111.3 77.73,111.29 77.71,111.28 77.45,111.28 77.42,111.29 77.4,111.32 77.39,111.33 77.4,111.36 77.41,111.38 77.42,111.4 77.42,112.73 77.42,112.75 77.43,112.77
DGND on TOP (solid shape): 81.32,111.12 81.35,111.13 81.38,111.13 81.39,111.12 81.41,111.1 81.41,110.82 81.4,110.8 81.39,110.78 80.52,109.91 80.5,109.9 80.48,109.9 79.36,109.9 79.33,109.9 79.31,109.93 79.31,109.94 79.31,109.97 80.08,110.74 80.1,110.75 80.12,110.76 80.94,110.76 80.96,110.76 80.97,110.77
DGND on TOP (solid shape): 72.49,117.97 73.78,116.68 73.79,116.67 73.8,116.65 73.8,116 73.8,115.98 73.81,115.96 74,115.77 74.01,115.75 74.01,115.72 74.01,115.7 73.98,115.68 72.8,115.68 72.78,115.69 72.77,115.7 72.43,116.04 72.42,116.05 72.41,116.07 72.41,117.41 72.41,117.93 72.42,117.95 72.45,117.97 72.46,117.98
DGND on TOP (solid shape): 63.72,42.21 63.73,42.2 63.9,42.15 64.07,42.18 64.08,42.18 64.11,42.18 64.19,42.13 64.2,42.11 64.21,42.08 64.21,39.71 64.21,39.69 64.2,39.67 63.66,39.14 63.64,39.13 63.61,39.13 63.59,39.13 63.58,39.16 63.58,42.12 63.58,42.14 63.6,42.16 63.69,42.21
DGND on TOP (solid shape): 70.19,48.89 70.21,48.88 70.23,48.88 70.32,48.88 70.35,48.86 70.37,48.83 70.37,48.43 70.35,48.39 70.32,48.38 70,48.38 69.97,48.41 69.97,48.42 69.29,48.42 69.26,48.39 69.26,48.38 68.8,48.38 68.77,48.39 68.75,48.41 68.75,48.42 68.75,48.45 69.67,49.37 69.68,49.38 69.7,49.38
DGND on TOP (solid shape): 68.7,103.2 68.72,103.19 68.74,103.18 68.9,103.01 68.91,103 68.92,102.98 68.92,101.69 68.91,101.66 68.89,101.64 68.87,101.64 68.84,101.64 68.05,102.43 68.04,102.45 68.04,102.48 68.05,102.57 68.06,102.59 68.07,102.59 68.24,102.79 68.22,103.05 68.21,103.06 68.21,103.09 68.27,103.17 68.29,103.19 68.31,103.2
DGND on TOP (solid shape): 102.74,104.34 102.76,104.36 102.79,104.36 102.81,104.35 102.83,104.32 102.83,101.38 102.82,101.36 102.81,101.35 102.55,101.09 102.53,101.07 102.5,101.08 102.48,101.08 102.47,101.11 102.47,102.83 102.45,102.87 102.41,102.88 100.77,102.88 100.74,102.9 100.72,102.93 100.72,103.26 100.72,103.28 100.74,103.3 100.96,103.52 100.98,103.54 101,103.54 101.91,103.54 101.93,103.54 101.95,103.55
DGND on TOP (solid shape): 89.7,40.02 89.7,39.15 89.72,39.12 89.75,39.1 89.92,39.1 89.95,39.09 89.97,39.07 89.97,39.06 89.97,39.03 89.53,38.59 89.52,38.58 89.52,38.56 89.52,38.32 89.51,38.3 89.49,38.28 89.41,38.23 89.39,38.22 89.3,38.26 89.12,38.43 89.11,38.45 89.11,38.47 89.11,39.1 89.11,39.1 89.11,39.98 89.13,40.01 89.17,40.03 89.68,40.03
DGND on TOP (solid shape): 73.41,110.35 73.44,110.34 73.46,110.32 73.46,110.3 73.46,110.27 72.24,109.06 72.22,109.06 72.2,109.07 71.29,109.99 71.27,110.01 71.28,110.04 71.28,110.06 71.31,110.07 71.92,110.07 71.95,110.06 72.15,109.91 72.2,109.9 72.5,109.96 72.62,110.24 72.63,110.27 72.69,110.33 72.7,110.34 72.72,110.35
DGND on TOP (solid shape): 36.75,66.11 36.79,66.1 36.8,66.06 36.8,65.95 36.82,65.92 36.86,65.9 37.87,65.9 37.91,65.89 37.92,65.85 37.92,65.5 37.93,65.48 37.94,65.47 38.28,65.13 38.29,65.09 38.28,65.06 38.25,65.02 38.23,65.01 38.21,65.01 38.17,65.01 38.13,64.99 38.12,64.96 38.12,64.41 38.09,64.38 38.07,64.38 37.96,64.26 37.94,64.25 37.92,64.25 37.76,64.25 37.74,64.25 37.73,64.26 36.07,65.92 36.06,65.94 36.06,65.97 36.06,65.99 36.09,66 36.58,66 36.61,66.02 36.64,66.1 36.68,66.11
DGND on TOP (solid shape): 127.77,115.59 128.09,115.27 128.1,115.26 128.12,115.25 128.33,115.25 128.36,115.24 128.38,115.2 128.38,115.19 128.41,115.16 130.78,115.16 130.81,115.14 130.83,115.11 130.83,114.39 130.81,114.36 130.78,114.34 128.43,114.34 128.39,114.33 128.38,114.29 128.38,113.61 128.39,113.57 128.43,113.56 130.78,113.56 130.81,113.54 130.83,113.5 130.83,112.79 130.81,112.76 130.78,112.74 128.43,112.74 128.39,112.73 128.38,112.69 128.38,112.68 128.35,112.65 127.71,112.65 127.7,112.67 127.69,112.69 127.69,115.54 127.7,115.57 127.72,115.59 127.74,115.59
DGND on TOP (solid shape): 52.99,88.8 53.08,88.75 53.09,88.73 53.1,88.71 53.1,88.02 53.09,87.99 53.05,87.97 53.03,87.97 53,87.94 53,87.01 53.02,86.97 53.05,86.96 54.1,86.96 54.14,86.94 54.15,86.91 54.15,86.85 54.16,86.83 54.18,86.79 54.19,86.77 54.19,86.18 54.18,86.17 54.17,86.15 54.05,86.02 54.03,86 54.03,85.98 54.03,85.22 54.04,85.2 54.03,85.17 54.01,85.14 53.98,85.14 52.67,85.14 52.64,85.15 52.62,85.19 52.62,88.67 52.63,88.69 52.64,88.71 52.71,88.76 52.73,88.77 52.74,88.77 52.85,88.77 52.95,88.8 52.97,88.8
DGND on TOP (solid shape): 78.01,117.17 78.03,117.17 78.05,117.16 78.22,116.99 78.23,116.98 78.25,116.98 80.07,116.98 80.1,116.97 80.12,116.95 80.12,116.93 80.12,116.9 79.81,116.59 79.8,116.58 79.79,116.53 79.78,116.5 79.74,116.48 79.71,116.48 79.69,116.49 79.25,116.43 79.21,115.99 79.22,115.97 79.21,115.94 78.09,114.81 78.06,114.8 78.02,114.81 77.99,114.87 77.99,116.84 77.99,116.86 77.98,116.88 77.77,117.09 77.75,117.11 77.76,117.14 77.76,117.16 77.79,117.17
DGND on TOP (solid shape): 59.42,82.51 61.29,80.64 61.3,80.63 61.32,80.62 64.03,80.62 64.08,80.63 64.19,80.65 64.24,80.69 64.25,80.7 64.34,80.7 64.36,80.69 64.38,80.68 64.57,80.48 64.59,80.47 64.61,80.47 66.42,80.47 66.53,80.46 66.54,80.42 66.54,80.41 66.53,80.37 66.49,80.36 61.08,80.36 61.06,80.36 61.04,80.37 60.27,81.14 60.26,81.15 60.24,81.16 59.49,81.16 59.46,81.17 59.44,81.21 59.44,81.29 59.43,81.29 59.43,81.76 59.41,81.8 59.35,81.84 59.35,82.46 59.35,82.49 59.38,82.51 59.39,82.51
DGND on TOP (solid shape): 33.67,51.47 33.7,51.46 33.72,51.42 33.72,51.36 33.72,51.34 33.73,51.33 33.93,51.13 33.94,51.12 33.94,51.1 33.94,50.29 33.95,50.27 33.96,50.25 34.18,50.03 34.19,50.02 34.19,49.99 34.23,49.95 34.24,49.94 34.25,49.92 34.25,49.69 34.23,49.66 34.2,49.64 32.93,49.64 32.89,49.66 32.88,49.69 32.88,49.93 32.89,49.96 32.93,49.98 32.96,49.98 33,49.99 33.01,50.03 33.01,50.94 33,50.98 32.96,51 32.93,51 32.89,51.01 32.88,51.05 32.88,51.08 32.88,51.09 32.9,51.21 32.88,51.34 32.88,51.35 32.88,51.42 32.89,51.46 32.93,51.47
DGND on TOP (solid shape): 52.4,99.89 52.42,99.89 52.43,99.88 53.44,98.88 53.45,98.86 53.45,98.84 53.45,98.42 53.41,98.31 53.4,98.22 53.39,98.19 53.33,98.13 53.31,98.12 53.29,98.12 52.24,98.12 52.21,98.1 52.19,98.07 52.19,96.42 52.18,96.39 52.16,96.37 52.15,96.37 52.12,96.37 52,96.49 51.99,96.51 51.98,96.53 51.98,97.73 51.98,97.75 51.97,97.77 51.57,98.16 51.55,98.18 51.53,98.18 51.11,98.18 51.08,98.19 51.06,98.23 51.06,98.25 51.08,98.28 51.11,98.3 51.17,98.3 51.19,98.3 51.21,98.31 51.6,98.7 51.61,98.72 51.61,98.74 51.61,99.67 51.63,99.71 51.66,99.72 51.77,99.72 51.81,99.74 51.82,99.77 51.82,99.84 51.84,99.88 51.87,99.89
DGND on TOP (solid shape): 46.94,83.55 46.98,83.53 46.99,83.5 46.99,82.97 47.01,82.93 47.04,82.92 47.68,82.92 47.71,82.95 47.71,82.96 47.77,82.96 47.78,82.96 47.86,82.93 47.94,82.93 47.98,82.93 48.04,82.87 48.05,82.85 48.06,82.83 48.06,82.71 48.04,82.68 48.01,82.66 47.53,82.66 47.5,82.65 47.48,82.61 47.48,82.06 47.48,82.04 47.46,82.02 47.37,81.97 47.34,81.97 47.28,82 47.2,82.02 47.18,82.05 47.18,82.37 47.17,82.39 47.16,82.41 46.77,82.8 46.75,82.81 46.73,82.82 46.24,82.82 46.24,82.82 46,82.82 45.97,82.83 45.95,82.87 45.95,83.33 45.97,83.36 46,83.38 46.74,83.38 46.78,83.39 46.79,83.43 46.79,83.5 46.81,83.53 46.84,83.55
DGND on TOP (solid shape): 42.96,60.53 42.99,60.53 43,60.5 43.05,60.41 43.05,60.38 43.04,60.37 43.12,59.85 43.63,59.97 43.65,59.99 43.67,60 44.01,60 44.04,59.99 44.06,59.95 44.06,59.49 44.07,59.46 44.11,59.44 44.28,59.44 44.31,59.43 44.33,59.41 44.33,59.39 44.33,59.37 44.19,59.23 44.18,59.22 44.16,59.22 42.06,59.22 42.04,59.22 42.02,59.24 41.97,59.33 41.97,59.36 41.97,59.37 42.02,59.52 42,59.67 42,59.68 42,59.71 42.05,59.78 42.07,59.8 42.1,59.81 42.17,59.81 42.19,59.81 42.2,59.82 42.32,59.94 42.35,59.95 42.62,60.07 42.75,60.34 42.75,60.37 42.9,60.52 42.92,60.53
DGND on TOP (solid shape): 82.53,114.91 82.55,114.9 82.57,114.88 82.62,114.79 82.62,114.77 82.62,114.76 82.58,114.64 82.58,114.52 82.58,114.51 82.58,114.48 82.52,114.42 82.5,114.4 82.48,114.4 82.19,114.4 82.17,114.39 82.15,114.38 80.74,112.97 80.73,112.95 80.73,112.93 80.73,111.39 80.72,111.37 80.71,111.35 79.87,111.35 79.85,111.35 79.83,111.34 78.88,110.38 78.86,110.37 78.84,110.36 78.54,110.36 78.51,110.37 78.49,110.4 78.48,110.41 78.49,110.44 78.87,110.82 78.88,110.84 78.89,110.86 78.89,113.13 78.89,113.15 78.9,113.16 79.02,113.28 79.05,113.29 79.08,113.29 79.09,113.29 79.11,113.26 79.11,113.01 79.12,112.97 79.16,112.96 79.69,112.96 79.73,112.97 79.74,113.01 79.77,113.03 79.83,113.03 79.86,113.02 79.88,112.98 79.9,112.96 80.46,112.96 80.5,112.97 80.51,113.01 80.51,113.2 80.52,113.25 80.53,113.29 80.53,113.85 80.53,113.86 80.55,114.04 80.48,114.2 80.47,114.22 80.47,114.26 80.47,114.28 80.48,114.3 81.08,114.89 81.09,114.9 81.11,114.91
DGND on TOP (solid shape): outline of 95 points within 100.51,95.25 103.63,100.64
DGND on TOP (solid shape): outline of 81 points within 117.69,41.13 120.72,44.41
DGND on TOP (solid shape): 129.72,56.46 129.75,56.47 129.78,56.47 129.79,56.46 129.81,56.44 129.81,55.37 129.81,55.35 129.82,55.33 130.32,54.83 130.34,54.82 130.36,54.82 131.71,54.82 131.74,54.79 131.74,54.77 132.08,54.18 132.76,54.15 132.78,54.16 132.8,54.15 132.89,54.1 132.9,54.08 132.91,54.06 132.91,50.52 132.9,50.49 132.89,50.48 132.8,50.42 132.78,50.42 132.76,50.43 132.59,50.49 132.41,50.5 132.38,50.51 132.32,50.56 132.31,50.58 132.31,50.6 132.31,51.47 132.29,51.51 132.26,51.52 132.24,51.52 132.2,51.54 132.19,51.57 132.19,53.31 132.17,53.34 132.14,53.36 130.51,53.36 130.48,53.34 130.45,53.34 130.42,53.35 129.75,54.03 129.74,54.04 129.4,54.31 129.05,54.04 129.05,54.03 128.7,53.68 128.68,53.66 128.68,53.64 128.68,52.45 128.67,52.41 128.63,52.4 128.19,52.4 128.16,52.41 128.14,52.45 128.14,52.84 128.13,52.88 128.09,52.9 127.54,52.9 127.5,52.91 127.49,52.95 127.49,54.2 127.49,54.22 127.5,54.24
DGND on TOP (solid shape): 98.53,89.55 98.94,89.15 98.95,89.14 98.97,89.13 99.37,89.13 99.39,89.13 99.4,89.12 101.62,86.9 101.63,86.89 101.63,86.87 101.63,86.6 101.62,86.57 101.58,86.55 101.39,86.55 101.33,86.56 100.94,86.56 100.92,86.56 100.9,86.57 100.83,86.65 100.81,86.66 100.78,86.66 100.78,86.68 100.77,86.72 100.73,86.73 100.15,86.73 100.12,86.75 100.12,86.77 99.97,86.98 99.73,87.07 99.71,87.07 99.69,87.09 99.65,87.19 99.65,87.22 99.66,87.24 99.69,87.26 99.79,87.84 99.22,87.74 99.21,87.73 98.97,87.48 98.94,87.47 98.91,87.47 98.9,87.48 98.88,87.5 98.88,87.89 98.88,87.91 98.89,87.93 99.01,88.05 99.03,88.05 99.19,88.65 98.6,88.49 98.59,88.47 98.54,88.42 98.51,88.41 98.48,88.41 98.47,88.42 98.45,88.44 98.45,89.51 98.46,89.54 98.48,89.55 98.5,89.56
DGND on TOP (solid shape): outline of 85 points within 29.06,42.66 36.35,51.62
DGND on TOP (solid shape): outline of 82 points within 36.63,41.9 40.24,50.04
DGND on TOP (solid shape): 48.42,94.22 48.44,94.22 48.46,94.21 49.45,93.22 49.47,93.21 49.49,93.2 50.83,93.2 50.85,93.2 50.86,93.19 51.14,92.92 51.15,92.9 51.15,92.88 51.14,92.78 51.12,92.76 51.11,92.76 51.01,92.66 50.94,92.54 50.94,92.52 50.77,92.35 50.76,92.34 50.74,92.34 48.64,92.34 48.61,92.35 48.59,92.4 48.6,92.46 48.65,92.47 49.11,92.85 48.57,93.12 48.55,93.11 47.96,93.11 47.94,93.11 47.93,93.1 47.9,93.07 47.88,93.06 47.86,93.05 47.67,93.05 47.65,93.06 47.64,93.07 47.35,93.18 47.07,93.07 47.06,93.06 47.04,93.05 46.9,93.05 46.86,93.07 46.76,93.15 46.7,93.15 46.52,93.15 46.36,93.05 46.34,93.04 46.26,93.04 46.24,93.04 46.22,93.05 45.93,93.35 45.91,93.37 45.92,93.4 45.92,93.42 45.95,93.43 46.58,93.43 46.61,93.45 46.63,93.49 46.74,93.49 46.78,93.47 46.79,93.44 46.81,93.42 47.49,93.42 47.5,93.44 47.82,93.55 47.9,93.87 47.89,93.88 47.9,93.91 47.96,93.99 47.98,94 47.99,94 48.17,94.05 48.3,94.19 48.31,94.2 48.33,94.21
DGND on TOP (solid shape): outline of 81 points within 81.12,104.3 86.25,107.68
DGND on TOP (solid shape): outline of 90 points within 57.66,38.79 63.92,44.01
DGND on TOP (solid shape): outline of 110 points within 24.43,20.71 32.54,24.88
DGND on TOP (solid shape): outline of 143 points within 82.05,97.09 87.08,103.76
DGND on TOP (solid shape): outline of 242 points within 18.37,23.85 27.98,30.47
DGND on TOP (solid shape): outline of 182 points within 86.9,37.68 92.44,46.7
DGND on TOP (solid shape): outline of 436 points within 28.85,25.54 41.07,40.77
DGND on BOTTOM (solid shape): 14.45,145.09 14.47,145.1 14.5,145.1 14.52,145.09 14.53,145.07 14.53,109.57 14.52,109.55 14.5,109.53 14.49,109.52 14.46,109.53 13.53,110.46 13.51,110.47 13.51,110.49 13.51,144.13 13.51,144.15 13.53,144.17
DGND on BOTTOM (solid shape): 16.76,148.38 16.79,148.37 16.81,148.34 16.82,148.33 16.81,148.3 13.06,144.55 13.03,144.53 13,144.54 12.99,144.54 12.97,144.57 12.97,145.11 12.98,145.13 12.99,145.14 16.2,148.36 16.22,148.37 16.24,148.38
DGND on BOTTOM (solid shape): 51.95,94.63 51.97,94.63 51.99,94.62 53,93.6 53.02,93.58 53.02,93.55 53.01,93.53 52.98,93.52 52.19,93.52 52.17,93.52 52.15,93.53 51.13,94.55 51.12,94.57 51.12,94.6 51.13,94.62 51.15,94.63
DGND on BOTTOM (solid shape): 71.84,31.95 71.85,31.94 71.87,31.93 73.35,30.45 73.37,30.42 73.37,30.39 73.36,30.38 73.33,30.36 72.4,30.36 72.38,30.37 72.36,30.38 70.88,31.86 70.86,31.89 70.87,31.92 70.87,31.93 70.9,31.95
DGND on BOTTOM (solid shape): 73.78,140.38 73.8,140.38 73.82,140.36 74.48,139.71 74.49,139.68 74.49,139.65 74.48,139.64 74.46,139.62 71.6,139.62 71.58,139.62 71.56,139.63 70.9,140.29 70.89,140.32 70.89,140.35 70.9,140.36 70.92,140.38
DGND on BOTTOM (solid shape): 74.13,134.85 74.15,134.85 74.17,134.84 74.52,134.48 74.53,134.46 74.53,134.43 74.52,134.41 74.5,134.39 65.4,134.39 65.38,134.4 65.37,134.41 65.01,134.76 65,134.79 65,134.82 65.01,134.83 65.03,134.85
DGND on BOTTOM (solid shape): 85.62,44.01 85.64,44 85.66,43.98 85.67,43.96 85.66,43.93 84.67,42.94 84.65,42.93 84.63,42.92 83.81,42.92 83.79,42.93 83.77,42.95 83.76,42.97 83.77,43 84.76,43.99 84.78,44.01 84.8,44.01
DGND on BOTTOM (solid shape): 86.05,106.62 86.07,106.63 86.1,106.63 86.12,106.62 86.13,106.6 86.13,105.67 86.13,105.65 86.12,105.64 85.7,105.22 85.68,105.21 85.67,105.2 84.76,105.2 84.73,105.21 84.71,105.24 84.7,105.25 84.71,105.28
DGND on BOTTOM (solid shape): 110.52,67.06 115.64,61.94 115.65,61.92 115.66,61.9 115.66,61.42 115.65,61.39 115.63,61.37 115.61,61.36 115.58,61.37 110.46,66.49 110.45,66.51 110.45,66.53 110.45,67.01 110.46,67.04 110.48,67.06 110.49,67.06
DGND on BOTTOM (solid shape): 41.15,85.64 42.5,84.29 42.51,84.28 42.52,84.26 42.52,82.39 42.51,82.36 42.48,82.34 42.47,82.33 42.44,82.34 41.09,83.69 41.08,83.7 41.08,83.72 41.08,84.86 41.08,85.6 41.09,85.62 41.11,85.64 41.12,85.65
DGND on BOTTOM (solid shape): 123.25,42.92 123.27,42.91 123.29,42.88 123.3,42.87 123.29,42.84 121.68,41.23 121.65,41.21 121.63,41.22 121.61,41.22 121.59,41.25 121.59,41.63 121.6,41.65 121.61,41.67 121.7,41.76 121.7,41.76 122.85,42.9 122.87,42.91 122.88,42.92
DGND on BOTTOM (solid shape): 19.9,105.19 20.43,104.67 20.44,104.65 20.44,104.63 20.44,102.73 20.45,102.72 20.46,102.7 23.01,100.15 23.02,100.13 23.02,100.1 23.01,100.08 22.99,100.07 22.4,100.07 22.38,100.07 22.36,100.08 19.84,102.6 19.83,102.62 19.83,102.63 19.83,105.15 19.84,105.18 19.86,105.19 19.87,105.2
DGND on BOTTOM (solid shape): 53.13,81.53 53.15,81.53 53.16,81.51 54.69,79.99 54.71,79.96 54.7,79.93 54.7,79.92 54.67,79.9 54.24,79.9 54.23,79.9 54.21,79.92 53.49,80.63 53.48,80.65 53.48,80.67 53.48,80.82 53.47,80.84 53.46,80.86 52.88,81.44 52.87,81.47 52.87,81.5 52.87,81.51 52.9,81.53
DGND on BOTTOM (solid shape): 66.16,119.08 66.18,119.08 66.2,119.07 67.59,117.68 67.6,117.66 67.6,117.64 67.6,116.84 67.59,116.81 67.57,116.79 67.55,116.79 67.52,116.79 65.48,118.84 65.46,118.85 65.44,118.85 61.07,118.85 61.04,118.86 61.02,118.89 61.01,118.9 61.02,118.93 61.16,119.07 61.17,119.08 61.19,119.08
DGND on BOTTOM (solid shape): 70.61,138.46 70.63,138.46 70.64,138.44 71.2,137.89 71.22,137.88 71.24,137.87 75.16,137.87 75.19,137.86 75.21,137.84 75.22,137.83 75.21,137.8 75.1,137.69 75.08,137.67 75.06,137.67 67.14,137.67 67.12,137.67 67.11,137.69 66.42,138.37 66.4,138.4 66.41,138.43 66.41,138.44 66.44,138.46
DGND on BOTTOM (solid shape): 71.52,160.97 71.54,160.97 71.56,160.96 71.63,160.89 71.65,160.87 71.67,160.87 71.84,160.87 71.87,160.86 71.89,160.84 71.89,160.82 71.89,160.79 71.66,160.57 71.64,160.55 71.62,160.55 66.52,160.55 66.49,160.56 66.48,160.58 66.47,160.6 66.48,160.63 66.81,160.96 66.82,160.97 66.84,160.97
DGND on BOTTOM (solid shape): 91.96,126.84 91.98,126.84 91.99,126.83 92.5,126.32 92.52,126.3 92.54,126.3 94.94,126.3 94.96,126.29 94.98,126.27 94.99,126.26 94.98,126.23 94.65,125.89 94.63,125.88 94.61,125.88 91.35,125.88 91.33,125.88 91.31,125.89 90.45,126.76 90.43,126.78 90.43,126.81 90.44,126.83 90.47,126.84
DGND on BOTTOM (solid shape): 111.05,97.18 111.56,96.67 111.57,96.66 111.58,96.64 111.58,94.51 111.58,94.5 111.59,94.48 112.01,94.06 112.02,94.03 112.02,94.01 112.01,93.99 111.99,93.97 111.32,93.97 111.31,93.98 111.29,93.99 110.99,94.29 110.98,94.3 110.98,94.32 110.98,97.13 110.99,97.16 111.01,97.18 111.02,97.19
DGND on BOTTOM (solid shape): 121.51,114 121.53,114 121.54,113.99 122.94,112.59 122.96,112.57 122.96,112.55 122.96,108.87 122.95,108.84 122.93,108.82 122.91,108.82 122.88,108.82 122.09,109.61 122.08,109.63 122.08,109.65 122.08,112.73 122.08,112.74 122.06,112.76 120.91,113.92 120.9,113.94 120.9,113.97 120.91,113.99 120.93,114
DGND on BOTTOM (solid shape): 44.43,31.06 44.46,31.05 44.48,31.03 44.53,30.94 44.52,30.91 44.51,30.9 44.46,30.77 44.45,30.63 44.45,30.61 44.45,30.59 44.39,30.52 44.37,30.51 44.35,30.51 41.95,30.51 41.93,30.51 41.91,30.52 41.46,30.97 41.45,31 41.45,31.03 41.46,31.04 41.48,31.06
DGND on BOTTOM (solid shape): 118.25,123.67 118.27,123.66 118.29,123.65 118.35,123.57 118.35,123.55 118.34,123.52 118.04,123.22 118.02,123.21 118,123.21 110.95,123.21 110.93,123.21 110.91,123.22 110.85,123.29 110.85,123.32 110.84,123.42 110.81,123.52 110.8,123.53 110.8,123.56 110.86,123.64 110.87,123.66 110.9,123.67
DGND on BOTTOM (solid shape): 49.25,112.05 49.27,112.05 49.28,112.04 51.32,110 51.34,109.99 51.35,109.99 53.12,109.99 53.14,109.98 53.15,109.97 55.23,107.89 55.24,107.88 55.25,107.86 55.25,105.89 55.24,105.86 55.22,105.85 55.19,105.85 55.16,105.86 49.06,111.97 49.04,111.99 49.04,112.02 49.05,112.04 49.08,112.05
DGND on BOTTOM (solid shape): 84.78,158.02 84.8,158.02 84.81,158 86.25,156.56 86.27,156.55 86.29,156.55 88.5,156.55 88.53,156.54 88.55,156.52 88.56,156.5 88.55,156.47 87.5,155.43 87.48,155.41 87.46,155.41 83.77,155.41 83.75,155.42 83.73,155.44 83.72,155.46 83.73,155.49 83.92,155.68 83.93,155.69 83.93,155.71 83.93,157.97 83.95,158 83.98,158.02
DGND on BOTTOM (solid shape): 124.87,123 124.89,123 124.91,122.98 125.18,122.71 125.2,122.7 125.22,122.7 125.52,122.7 125.56,122.68 125.57,122.64 125.55,122.56 125.52,122.54 125.5,122.52 125.48,122.52 122,122.52 121.98,122.52 121.96,122.54 121.58,122.91 121.57,122.94 121.57,122.97 121.58,122.98 121.6,123
DGND on BOTTOM (solid shape): 124.41,124.58 124.43,124.58 124.45,124.57 125.53,123.48 125.55,123.43 125.56,123.39 125.57,123.37 125.56,123.35 125.55,123.32 125.53,123.3 125.5,123.29 125.47,123.29 125.45,123.3 125.43,123.31 125.16,123.58 125.14,123.59 125.12,123.6 121.72,123.6 121.7,123.6 121.69,123.61 120.81,124.49 120.79,124.52 120.79,124.55 120.8,124.56 120.83,124.58
DGND on BOTTOM (solid shape): 49.14,108.17 49.17,108.17 49.19,108.15 53.06,104.27 53.07,104.25 53.07,104.23 53.05,104.13 53.06,104.02 53.07,104.01 53.06,103.99 53.01,103.91 52.99,103.89 52.97,103.89 52.7,103.89 52.68,103.89 52.66,103.9 48.79,107.78 48.77,107.8 48.77,107.82 48.8,107.92 48.81,107.94 48.83,107.94 48.94,108.01 49.02,108.12 49.03,108.13 49.05,108.15
DGND on BOTTOM (solid shape): 64.6,76.73 64.63,76.72 64.65,76.7 64.65,76.68 64.65,76.65 64.49,76.49 64.48,76.48 64.47,76.46 64.47,76.04 64.47,76.02 64.46,76 63.83,75.37 63.82,75.36 63.8,75.36 63.71,75.36 63.69,75.37 63.61,75.42 63.5,75.45 63.46,75.48 63.45,75.49 63.45,75.51 63.45,76.68 63.46,76.71 63.5,76.73
DGND on BOTTOM (solid shape): 72.24,160.3 72.25,160.31 72.28,160.31 72.37,160.3 72.39,160.29 72.44,160.23 72.5,160.18 72.51,160.16 72.52,160.07 72.51,160.05 72.5,160.03 72.04,159.57 72.03,159.56 72.01,159.56 66.63,159.56 66.61,159.55 66.59,159.54 65.2,158.15 65.18,158.14 65.16,158.13 65.08,158.13 65.05,158.14 65.04,158.17 65.03,158.18 65.04,158.21 66.76,159.94 66.78,159.95 66.8,159.95 71.87,159.95 71.89,159.96 71.9,159.97
DGND on BOTTOM (solid shape): 85.07,100.82 85.09,100.82 85.11,100.8 85.11,100.76 85.1,100.73 85.09,100.72 85.02,100.66 84.99,100.65 84.98,100.66 84.75,100.63 84.58,100.46 84.58,100.45 83.42,99.29 83.4,99.28 83.37,99.28 83.35,99.29 83.34,99.31 83.34,99.96 83.33,99.98 83.32,99.99 82.67,100.64 82.65,100.7 82.66,100.72 82.71,100.8 82.73,100.81 82.75,100.82
DGND on BOTTOM (solid shape): 128.38,108.25 128.4,108.25 128.44,108.21 128.45,108.19 128.45,106.95 128.44,106.93 128.43,106.91 126.34,104.82 126.32,104.81 126.29,104.81 126.27,104.82 126.25,104.84 126.25,107.55 126.26,107.57 126.27,107.59 126.72,108.04 126.74,108.05 126.75,108.05 127.72,108.05 127.75,108.04 128.04,108.01 128.26,108.21 128.26,108.22 128.28,108.23
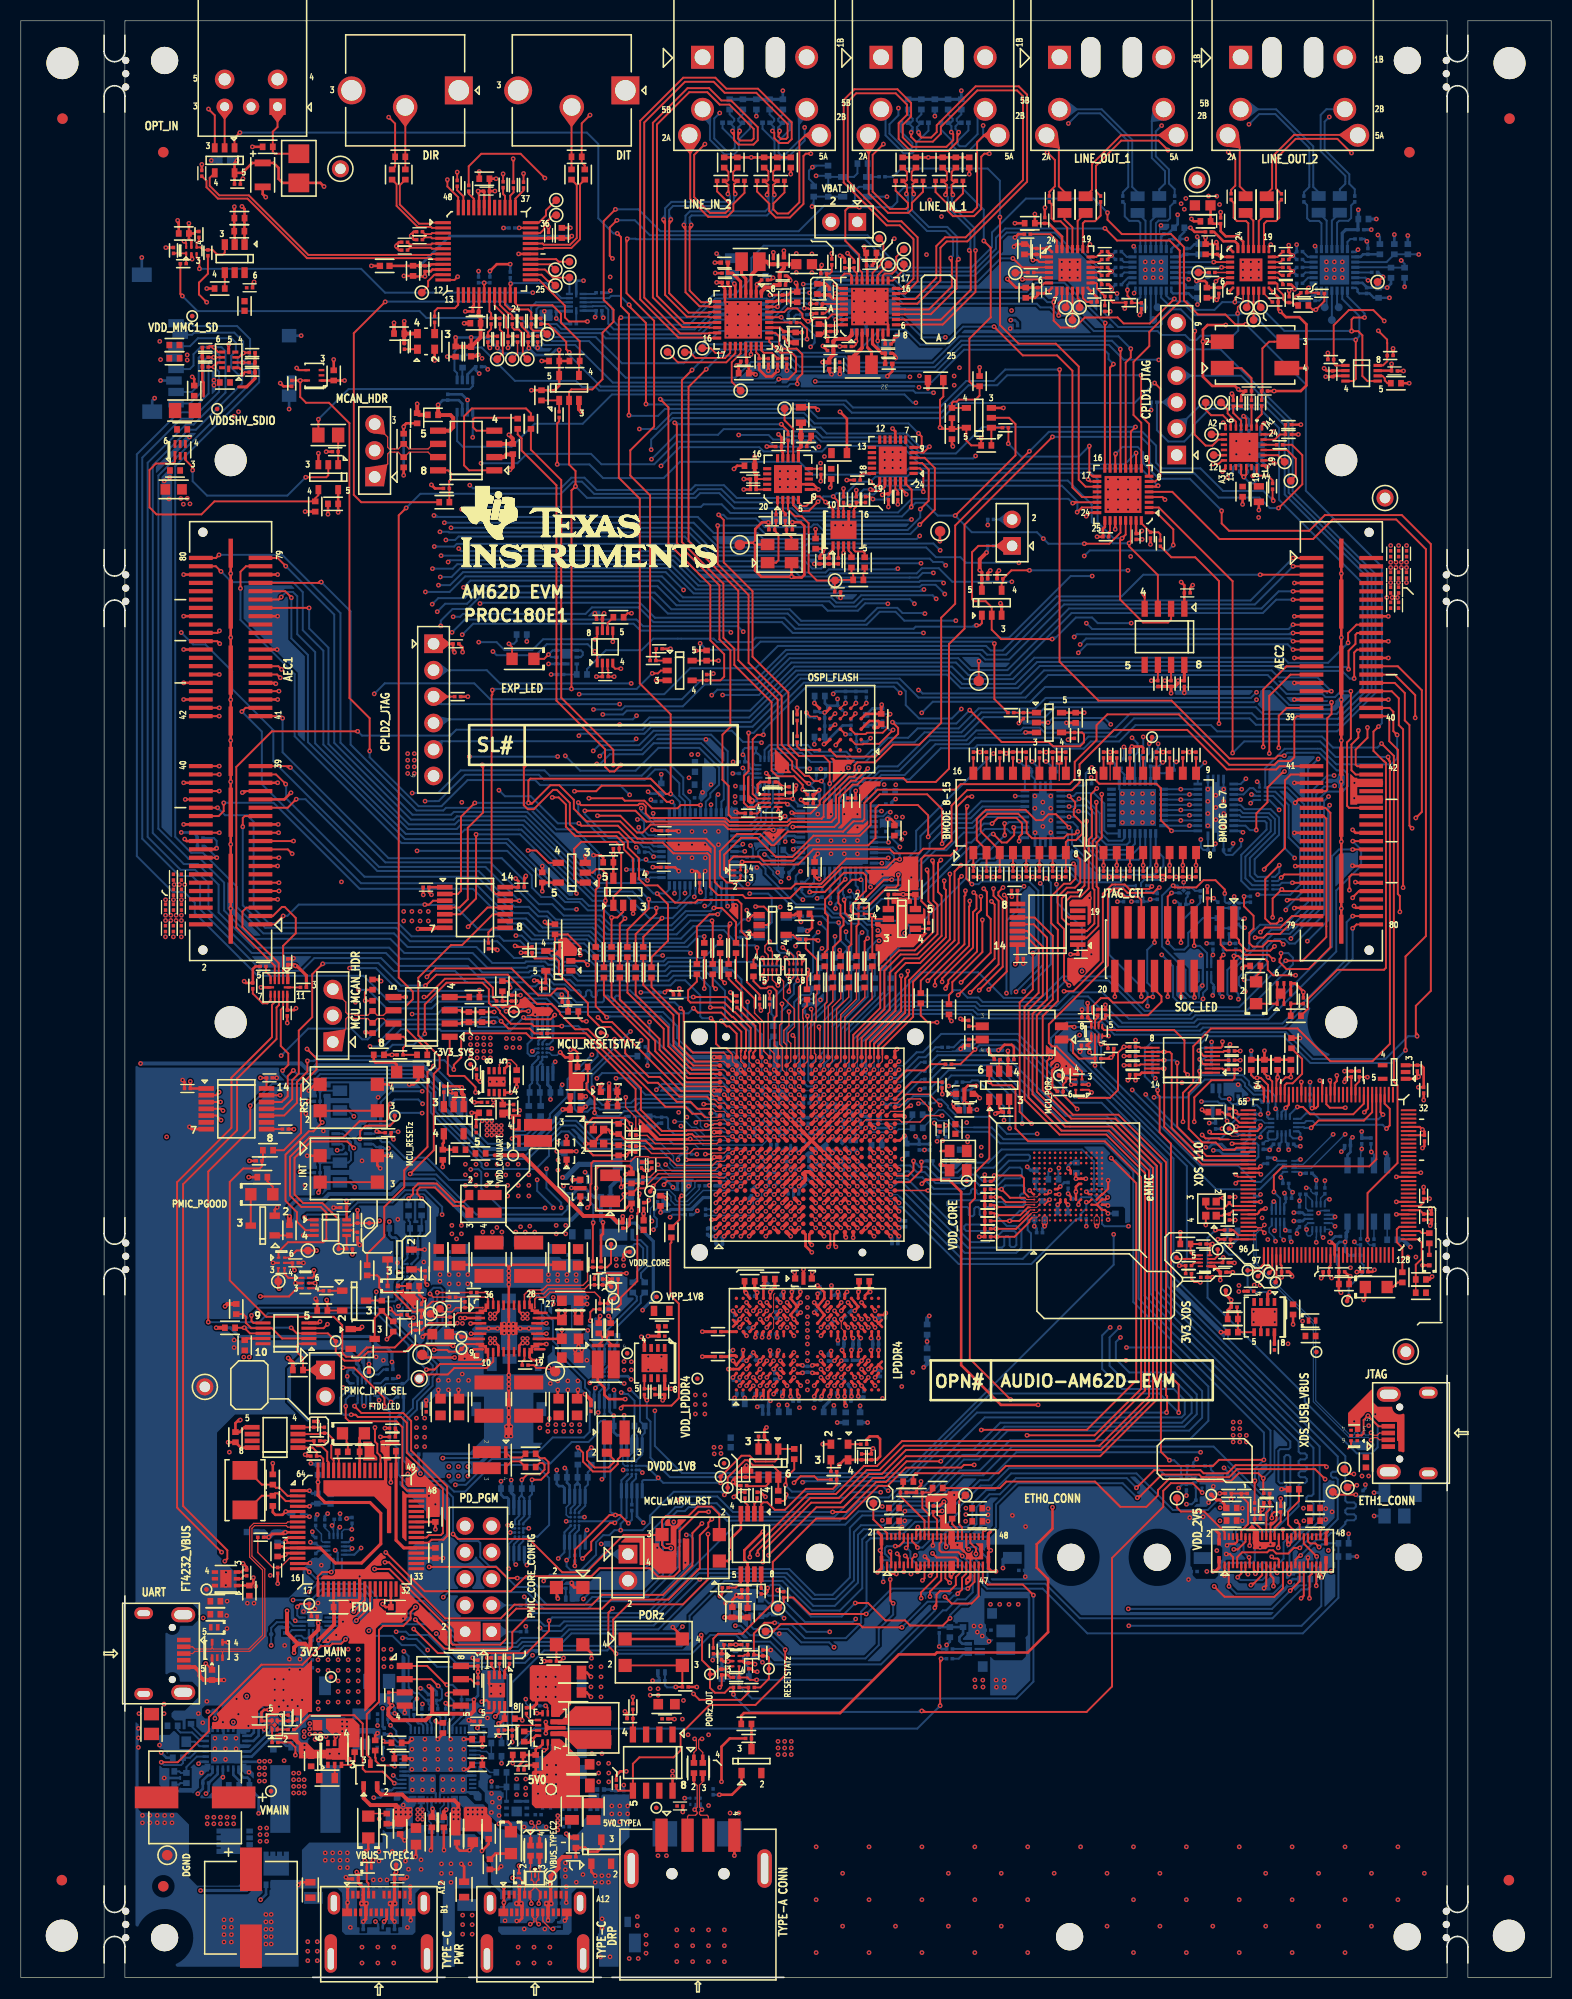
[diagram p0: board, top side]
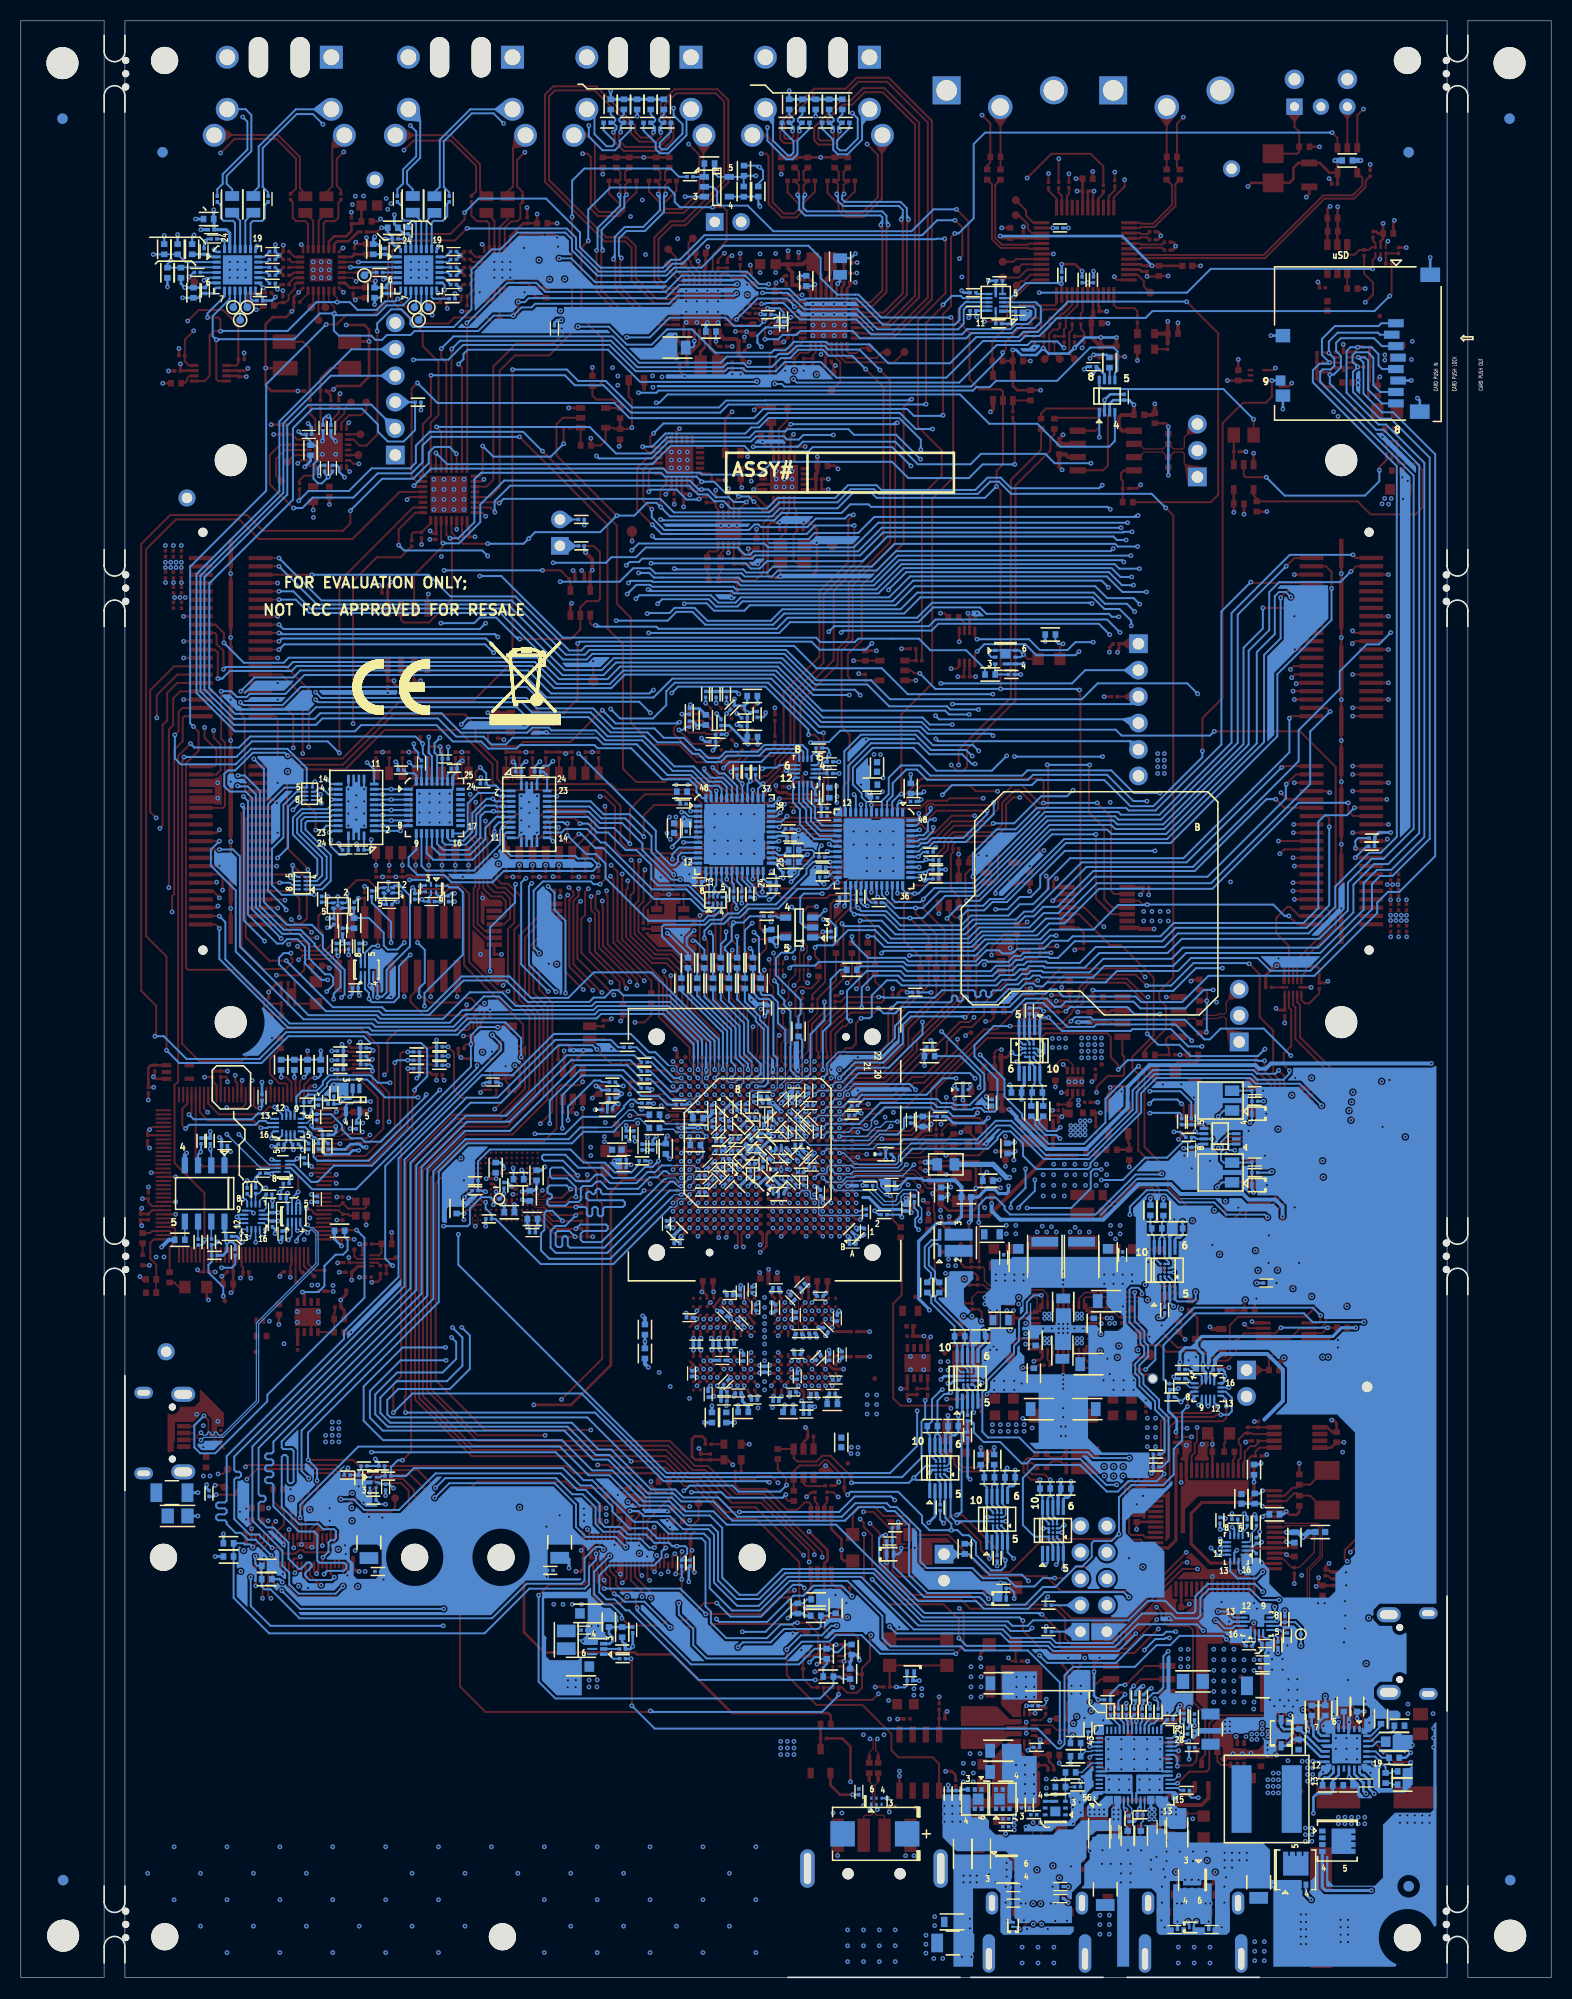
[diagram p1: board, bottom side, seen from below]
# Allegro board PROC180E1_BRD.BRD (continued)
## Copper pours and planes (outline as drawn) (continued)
DGND on BOTTOM (solid shape): 66.82,85.52 66.84,85.51 66.86,85.5 67.28,85.08 67.29,85.06 67.24,84.87 67.23,84.75 67.23,84.74 67.23,84.72 67.17,84.66 67.15,84.64 67.13,84.64 66.8,84.64 66.78,84.64 66.77,84.65 66.35,85.07 66.34,85.08 66.32,85.08 61.43,85.08 61.4,85.1 61.38,85.13 61.4,85.2 61.71,85.5 61.72,85.51 61.74,85.52
DGND on BOTTOM (solid shape): 21.52,20.38 21.56,20.37 22.07,20.37 22.11,20.36 22.12,20.32 22.12,19.92 22.13,19.9 22.14,19.88 22.37,19.65 22.38,19.63 22.39,19.61 22.39,19.15 22.38,19.13 22.36,19.11 22.34,19.1 22.31,19.11 21.92,19.5 21.91,19.51 21.89,19.51 21.56,19.51 21.54,19.51 21.52,19.53 21.26,19.79 21.24,19.81 21.24,19.83 21.24,20.05 21.24,20.1 21.23,20.14 21.23,20.34 21.24,20.37 21.28,20.39 21.47,20.39
DGND on BOTTOM (solid shape): 67.14,38.18 67.17,38.17 67.19,38.14 67.19,38.13 67.19,38.1 63.95,34.86 63.94,34.85 63.94,34.83 63.94,34.05 63.93,34.02 63.91,34 63.81,33.96 63.79,33.96 63.77,33.97 63.44,34.02 63.21,33.78 63.2,33.76 62.8,33.35 62.78,33.34 62.76,33.34 61.69,33.34 61.66,33.35 61.64,33.37 61.64,33.38 61.64,33.41 66.39,38.16 66.41,38.17 66.43,38.18
DGND on BOTTOM (solid shape): 54.62,84.55 54.66,84.57 54.69,84.55 55.36,83.89 55.37,83.86 55.37,83.84 55.36,83.82 55.34,83.8 54.67,83.8 54.65,83.8 54.64,83.79 54.32,83.48 54.31,83.46 54.29,83.46 53.59,83.46 53.57,83.46 53.55,83.48 53.51,83.52 53.49,83.54 53.49,83.56 53.49,83.9 53.51,83.94 53.54,83.95 54.02,83.95 54.05,83.98 54.05,83.99 54.13,83.99 54.15,83.99 54.16,84 54.58,84.42 54.59,84.44 54.6,84.46 54.6,84.5
DGND on BOTTOM (solid shape): 102.08,93.93 102.11,93.92 102.13,93.9 102.18,93.81 102.18,93.79 102.17,93.78 102.28,93.29 102.77,93.39 102.77,93.4 102.79,93.41 102.88,93.42 102.9,93.41 102.92,93.4 103.43,92.9 103.44,92.87 103.44,92.84 103.43,92.83 103.41,92.81 100.19,92.81 100.16,92.82 100.14,92.84 100.14,92.86 100.14,92.89 101.17,93.92 101.19,93.93 101.21,93.93
DGND on BOTTOM (solid shape): 27.84,98.1 27.86,98.1 27.88,98.07 27.89,98.06 27.88,98.03 26.87,97.01 26.85,97 26.8,97 26.78,97.02 26.72,97.08 26.72,97.1 26.72,97.12 26.37,97.53 26.01,97.12 26.02,97.1 26.01,97.08 25.95,97.02 25.94,97 25.91,97 23.27,97 23.25,97 23.24,97.01 22.23,98.02 22.22,98.04 22.22,98.07 22.23,98.09 22.25,98.1
DGND on BOTTOM (solid shape): 65.7,117.16 66.76,116.1 66.77,116.09 66.77,116.07 66.77,114.72 66.77,114.7 66.76,114.68 65.95,113.87 65.93,113.85 65.93,113.83 65.93,113.52 65.93,113.5 65.92,113.48 65.51,113.08 65.5,113.06 65.49,113.02 65.48,113 65.4,112.94 65.38,112.94 65.3,112.96 65.24,113.01 65.23,113.03 65.23,113.05 65.23,113.9 65.23,113.92 65.24,113.93 65.43,114.12 65.44,114.14 65.45,114.16 65.45,116.31 65.45,116.33 65.46,116.34 65.61,116.5 65.63,116.51 65.63,116.53 65.63,117.11 65.64,117.14 65.66,117.16 65.67,117.16
DGND on BOTTOM (solid shape): 123.7,93.19 123.73,93.2 123.77,93.19 123.86,93.13 123.87,93.09 123.87,93.07 123.84,90.51 125.68,88.72 125.7,88.72 125.71,88.69 125.69,88.57 125.67,88.54 125.64,88.53 124.22,88.53 124.2,88.53 124.18,88.54 121.66,91.07 121.64,91.1 121.66,91.14
DGND on BOTTOM (solid shape): 77.11,94.53 77.14,94.52 77.16,94.48 77.16,93.9 77.15,93.88 77.14,93.86 76.41,93.13 76.39,93.12 76.36,93.12 76.27,93.13 76.25,93.15 76.24,93.16 75.94,93.38 75.61,93.21 75.59,93.19 75.57,93.19 75.05,93.19 75.02,93.2 75,93.24 75,93.41 75.01,93.43 75.02,93.44 75.23,93.66 75.25,93.67 75.27,93.67 76.15,93.67 76.17,93.68 76.19,93.69 76.97,94.47 76.99,94.49 76.99,94.51 77.01,94.53
DGND on BOTTOM (solid shape): 91.74,89.76 91.76,89.75 91.78,89.73 91.79,89.71 91.78,89.68 91.59,89.49 91.58,89.49 91.35,89.31 91.33,89.02 91.33,89.01 91.33,88.98 91.27,88.9 91.26,88.89 91.23,88.88 87.94,88.88 87.91,88.89 87.89,88.91 87.88,88.93 87.89,88.96 87.97,89.03 87.98,89.04 88,89.05 88.08,89.05 88.12,89.03 88.13,88.99 89.38,88.99 89.42,89.01 89.43,89.05 89.7,89.05 89.72,89.05 89.74,89.06 90.42,89.74 90.44,89.76 90.46,89.76
DGND on BOTTOM (solid shape): 49.87,31.54 49.9,31.53 49.92,31.51 49.92,31.5 49.92,31.47 49.59,31.14 49.57,31.13 49.55,31.13 49.46,31.13 49.44,31.15 49.08,31.28 48.81,31.02 48.8,31 48.32,30.52 48.3,30.51 48.28,30.51 45.25,30.51 45.23,30.51 45.21,30.52 45.16,30.59 45.15,30.61 45.15,30.63 45.15,30.77 45.09,30.9 45.08,30.91 45.08,30.94 45.13,31.03 45.15,31.05 45.17,31.06 47.96,31.06 47.98,31.06 48,31.07 48.45,31.53 48.47,31.54 48.49,31.54
DGND on BOTTOM (solid shape): 70.74,106.86 70.76,106.85 70.78,106.84 71.22,106.4 71.23,106.38 71.23,106.36 71.23,105.91 71.24,105.89 71.25,105.87 72.17,104.95 72.19,104.92 72.18,104.89 72.18,104.88 72.15,104.86 70.28,104.86 70.25,104.87 70.23,104.89 70.23,104.91 70.23,104.94 70.48,105.18 70.49,105.2 70.49,105.22 70.49,105.34 70.51,105.38 70.58,105.41 70.6,105.44 70.6,105.98 70.58,106.01 70.55,106.03 70.1,106.03 70.08,106.03 70.06,106.05 70,106.13 70,106.15 70.02,106.22 70.02,106.28 70.02,106.8 70.03,106.84 70.07,106.86
DGND on BOTTOM (solid shape): 125.75,47.81 125.77,47.81 125.8,47.79 125.9,47.72 126.01,47.7 126.15,47.7 126.18,47.69 126.2,47.65 126.2,44.17 126.2,44.15 126.18,44.13 125.31,43.26 125.29,43.24 125.27,43.24 125.17,43.26 125.15,43.27 125.15,43.28 125.06,43.38 124.95,43.45 124.94,43.45 124.92,43.47 124.9,43.57 124.9,43.59 124.91,43.61 125.04,43.74 125.05,43.76 125.06,43.78 125.06,47.42 125.06,47.44 125.08,47.46 125.15,47.51 125.18,47.52 125.19,47.51 125.46,47.54 125.63,47.75 125.63,47.76 125.65,47.78
DGND on BOTTOM (solid shape): 93.81,46.11 93.84,46.1 93.86,46.07 93.87,46.06 93.86,46.03 93.39,45.56 93.38,45.54 93.38,45.52 93.38,43.41 93.37,43.39 93.36,43.37 93.08,43.09 93.06,43.08 93.03,43.08 92.94,43.1 92.92,43.12 92.91,43.13 92.4,43.32 92.3,42.78 92.31,42.77 92.32,42.74 92.27,42.64 92.25,42.62 92.23,42.61 91.41,42.61 91.38,42.62 91.36,42.65 91.36,42.66 91.36,42.69 92.08,43.4 92.09,43.42 92.09,43.44 92.09,45.01 92.1,45.03 92.11,45.05 93.15,46.09 93.17,46.1 93.19,46.11
DGND on BOTTOM (solid shape): 19.22,19.37 19.25,19.38 19.28,19.38 19.29,19.37 19.31,19.35 19.31,18.28 19.29,18.25 19.26,18.23 18.7,18.23 18.67,18.22 18.65,18.18 18.65,17.48 18.65,17.46 18.64,17.44 18.4,17.21 18.39,17.2 18.37,17.19 17.31,17.19 17.28,17.2 17.26,17.22 17.22,17.33 17.23,17.36 17.24,17.37 17.29,17.42 17.33,17.49 17.37,17.53 17.4,17.55 17.44,17.53 17.45,17.52 17.77,17.29 18.11,17.5 18.11,17.51 18.36,17.76 18.37,17.78 18.37,17.79 18.37,18.28 18.4,18.31 18.41,18.31 18.41,18.54 18.42,18.56 18.43,18.57
DGND on BOTTOM (solid shape): 91.74,47.93 91.77,47.92 91.79,47.9 91.79,47.88 91.79,47.85 88.94,45 88.92,44.99 88.9,44.99 88.81,45 88.79,45.01 88.78,45.01 88.57,45.15 88.32,45.11 88.29,45.1 87.87,45.1 87.84,45.11 87.82,45.13 87.81,45.14 87.82,45.17 88.19,45.55 88.21,45.56 88.24,45.56 88.33,45.55 88.35,45.53 88.36,45.52 88.92,45.43 88.83,46 88.82,46.01 88.81,46.03 88.79,46.12 88.8,46.14 88.81,46.16 90.56,47.91 90.58,47.93 90.6,47.93
DGND on BOTTOM (solid shape): 72.78,85.72 72.82,85.7 72.83,85.66 72.91,85.38 73.18,85.26 73.21,85.26 73.27,85.2 73.28,85.18 73.29,85.16 73.29,85.13 73.29,85.11 73.3,85.09 73.62,84.77 73.65,84.67 73.69,84.6 73.7,84.59 73.69,84.55 73.42,84.27 73.38,84.27 73.33,84.31 73.25,84.34 73.25,84.35 72.66,84.35 72.63,84.36 72.62,84.38 72.58,84.49 72.58,84.52 72.72,84.65 72.73,84.66 72.73,84.68 72.73,84.74 72.75,84.74 72.75,85.4 72.74,85.42 72.73,85.43 72.69,85.49 72.68,85.51 72.69,85.59 72.7,85.7 72.73,85.72
DGND on BOTTOM (solid shape): 126.96,115.65 126.98,115.65 127,115.63 127.15,115.48 127.16,115.47 127.16,115.45 127.16,114.58 127.16,114.56 127.15,114.54 126.83,114.23 126.81,114.21 126.8,114.21 126.63,114.21 126.6,114.22 126.58,114.23 126.53,114.31 126.53,114.33 126.53,114.35 126.46,114.7 126.11,114.81 126.1,114.81 126.07,114.82 125.95,114.72 125.91,114.71 125.29,114.71 125.26,114.72 125.25,114.74 125.24,114.76 125.25,114.79 125.61,115.15 125.62,115.16 125.64,115.16 125.94,115.16 125.97,115.15 126.36,115.17 126.5,115.53 126.5,115.54 126.5,115.56 126.56,115.63 126.58,115.64 126.6,115.65
DGND on BOTTOM (solid shape): 14.75,23.66 14.77,23.66 14.78,23.64 15.19,23.24 15.21,23.23 15.23,23.22 15.23,21.99 15.25,21.95 15.28,21.94 16.55,21.94 16.58,21.93 16.59,21.9 16.6,21.89 16.59,21.86 16.14,21.41 16.12,21.4 16.06,21.41 16.05,21.44 16.05,21.55 16.03,21.59 16,21.6 14.18,21.6 14.14,21.59 14.13,21.55 14.13,21.54 14.12,21.51 14.1,21.49 14.08,21.48 14.05,21.49 13.81,21.73 13.81,21.74 13.65,21.9 13.42,21.94 13.41,21.93 13.38,21.94 13.31,22 13.3,22.01 13.3,22.04 13.3,23.2 13.3,23.22 13.31,23.24 13.35,23.27 13.37,23.28 13.38,23.29 14.27,23.29 14.29,23.29 14.31,23.3 14.65,23.64 14.66,23.66 14.68,23.66
DGND on BOTTOM (solid shape): 98.23,120.77 98.26,120.76 98.27,120.75 98.33,120.67 98.33,120.65 98.33,120.64 98.58,120.2 99.02,120.46 99.03,120.47 99.22,120.67 99.24,120.68 99.26,120.68 103.94,120.68 103.96,120.68 103.98,120.67 104.34,120.3 104.35,120.28 104.46,120.11 104.64,120.02 104.67,120 104.69,119.97 104.67,119.93 104.63,119.89 104.61,119.88 104.59,119.87 98.49,119.87 98.48,119.88 98.46,119.89 98.01,120.34 97.99,120.35 97.97,120.35 96.32,120.35 96.3,120.36 96.29,120.37 96.23,120.43 96.22,120.46 96.22,120.55 96.2,120.63 96.19,120.64 96.2,120.66 96.25,120.74 96.27,120.76 96.29,120.77
DGND on BOTTOM (solid shape): 61.3,43.18 61.33,43.19 61.36,43.19 61.37,43.19 61.39,43.16 61.39,38.83 61.39,38.81 61.38,38.79 59.82,37.23 59.8,37.22 59.78,37.22 54.5,37.22 54.49,37.22 54.47,37.2 53.96,36.7 53.95,36.69 53.72,36.51 53.7,36.23 53.7,36.21 53.7,36.19 53.64,36.11 53.63,36.1 53.6,36.09 52.77,36.09 52.73,36.1 52.72,36.14 52.72,36.82 52.7,36.86 52.66,36.87 52.65,36.89 52.65,37.03 52.68,37.06 52.68,37.06 52.68,37.65 52.67,37.68 52.63,37.7 52.16,37.7 52.13,37.71 52.11,37.73 52.1,37.74 52.11,37.77 52.36,38.02 52.38,38.03 52.4,38.04 54.7,38.04 54.72,38.04 54.73,38.05 55.69,39.01 55.71,39.02 55.73,39.02 60.08,39.02 60.1,39.02 60.12,39.04 60.89,39.81 60.9,39.82 60.9,39.84 60.9,42.76 60.9,42.78 60.92,42.79
DGND on BOTTOM (solid shape): 119.96,123.67 119.98,123.66 120,123.65 121.71,121.94 121.73,121.93 121.75,121.92 125.73,121.92 125.75,121.93 125.77,121.94 125.97,122.14 125.99,122.15 126.2,122.31 126.25,122.57 126.25,122.58 126.25,122.61 126.31,122.68 126.33,122.69 126.36,122.7 126.91,123.24 126.92,123.26 126.94,123.26 127.55,123.26 127.64,123.22 127.66,123.2 127.68,123.11 127.68,123.08 127.66,123.06 126.29,121.69 126.28,121.68 126.26,121.68 119.43,121.68 119.41,121.68 119.4,121.69 118.83,122.26 118.81,122.28 118.81,122.3 118.83,122.4 118.84,122.42 118.85,122.42 119.05,122.7 118.92,123.02 118.91,123.03 118.9,123.05 118.9,123.15 118.91,123.17 118.92,123.18 119.03,123.34 119.04,123.54 119.04,123.55 119.04,123.57 119.1,123.65 119.12,123.66 119.14,123.67
DGND on BOTTOM (solid shape): 100.1,162.49 100.12,162.49 100.14,162.48 103.88,158.74 103.92,158.69 103.99,158.63 104.29,158.61 104.51,158.82 104.51,158.84 104.53,158.85 104.63,158.88 104.65,158.88 104.68,158.86 105,158.54 105.01,158.51 105.01,158.48 105,158.47 104.98,158.45 103.21,158.45 103.19,158.46 103.17,158.47 101.71,159.93 101.69,159.94 101.67,159.95 99.9,159.95 99.83,159.98 99.76,160 99.32,160.44 99.31,160.46 99.31,160.49 99.33,160.58 99.34,160.6 99.36,160.61 99.53,161.09 99.03,161.24 99.01,161.23 98.74,161.23 98.72,161.23 98.71,161.25 98.35,161.6 98.34,161.61 98.32,161.62 96.85,161.62 96.82,161.62 96.8,161.65 96.8,161.66 96.8,161.69 97.59,162.48 97.61,162.49 97.62,162.49
DGND on BOTTOM (solid shape): 25.98,133.74 26,133.73 26.02,133.72 26.26,133.48 26.28,133.45 26.27,133.42 26.27,133.41 26.24,133.39 25.4,133.39 25.38,133.38 25.36,133.37 24.94,132.95 24.92,132.95 24.76,132.35 25.36,132.51 25.36,132.53 25.46,132.63 25.49,132.64 25.52,132.64 25.62,132.59 25.63,132.57 25.63,132.55 25.64,132.45 25.69,132.33 25.69,128.53 25.69,128.51 25.7,128.49 27.27,126.93 27.28,126.91 27.28,126.89 27.28,118.8 27.27,118.77 27.25,118.75 27.24,118.74 27.21,118.75 26.62,119.34 26.61,119.35 26.6,119.37 26.6,125.3 26.6,125.32 26.59,125.34 21.41,130.52 21.4,130.53 21.4,130.55 21.4,133.23 21.4,133.25 21.45,133.42 21.42,133.59 21.41,133.6 21.41,133.63 21.47,133.71 21.48,133.73 21.51,133.74
DGND on BOTTOM (solid shape): outline of 81 points within 119.83,113.1 124.3,117.34
DGND on BOTTOM (solid shape): 83.12,107.28 83.27,107.21 83.43,107.22 83.45,107.23 83.47,107.22 83.55,107.17 83.56,107.15 83.57,107.13 83.57,107.07 83.57,107.05 83.58,107.04 84.07,106.55 84.09,106.54 84.11,106.54 84.35,106.54 84.37,106.53 84.39,106.5 84.4,106.49 84.39,106.46 84.17,106.24 84.16,106.23 83.99,106.09 83.96,105.86 83.96,105.85 83.95,105.83 83.9,105.76 83.88,105.75 83.86,105.74 83.8,105.74 83.79,105.75 83.44,105.69 83.35,105.34 83.35,105.33 83.35,105.3 83.29,105.23 83.27,105.21 83.25,105.2 82.76,105.2 82.74,105.2 82.72,105.19 82.2,104.66 82.17,104.65 82.14,104.65 82.13,104.66 82.11,104.68 82.11,105.62 82.11,105.64 82.09,105.66 81.64,106.11 81.63,106.12 81.63,106.14 81.63,106.68 81.64,106.72 81.68,106.73 82.58,106.73 82.59,106.73 82.96,106.83 82.99,107.21 82.98,107.24 82.99,107.26 83,107.29 83.02,107.31
DGND on BOTTOM (solid shape): 62.66,91.34 62.73,91.27 62.74,91.25 62.74,91.23 62.74,90.22 62.79,90.06 62.92,89.95 62.93,89.95 64.24,88.64 64.26,88.63 64.28,88.62 68.33,88.62 68.35,88.62 68.37,88.61 69.27,87.7 69.28,87.69 69.29,87.67 69.29,86.82 69.28,86.8 69.27,86.79 69.21,86.73 69.18,86.72 68.91,86.61 68.83,86.33 68.82,86.28 68.78,86.27 68.73,86.27 68.7,86.28 68.68,86.33 68.65,86.55 68.48,86.7 68.47,86.7 68.45,86.72 68.44,86.74 68.44,86.77 68.46,86.86 68.47,86.88 68.49,86.89 68.59,87.43 68.05,87.32 68.05,87.31 68.03,87.29 67.93,87.27 67.91,87.27 67.89,87.29 67.01,88.16 67,88.17 66.98,88.18 64.27,88.18 64.25,88.18 64.23,88.19 62.59,89.83 62.58,89.84 62.58,89.86 62.58,91.29 62.59,91.32 62.61,91.34 62.63,91.34
DGND on BOTTOM (solid shape): 112.42,98.87 112.44,98.85 112.65,98.74 112.89,98.79 112.92,98.79 113.11,98.79 113.13,98.79 113.15,98.78 113.63,98.29 113.64,98.28 113.65,98.26 113.65,97.37 113.65,97.31 113.65,96.33 113.65,96.27 113.65,95.1 113.64,95.08 113.63,95.07 113.28,94.71 113.27,94.69 113.26,94.68 113.26,94.2 113.22,94.11 113.2,94.02 113.17,93.99 113.15,93.98 113.09,94.01 113.09,94.04 113.09,94.18 113.05,94.31 113.04,94.33 113.04,95.14 113.04,95.16 113.05,95.18 113.43,95.55 113.44,95.57 113.44,95.59 113.44,96.27 113.44,96.33 113.44,96.83 113.42,96.86 113.39,96.88 112.9,96.88 112.87,96.86 112.85,96.83 112.85,96.33 112.85,96.27 112.85,95.84 112.84,95.82 112.83,95.8 112.46,95.43 112.45,95.41 112.44,95.39 112.44,94.6 112.43,94.57 112.41,94.55 112.38,94.55 112.36,94.56 112.19,94.73 112.18,94.74 112.17,94.76 112.17,96.89 112.17,96.9 112.16,96.92 110.73,98.35 110.72,98.38 110.72,98.4 110.72,98.42 110.75,98.44 111.85,98.44 111.87,98.44 111.89,98.45 112.3,98.86 112.31,98.87 112.33,98.87
DGND on BOTTOM (solid shape): outline of 82 points within 45.85,1.02 57.42,11.91
DGND on BOTTOM (solid shape): 36.72,30.97 36.94,30.75 36.95,30.73 36.95,30.71 36.95,27.75 36.96,27.73 36.97,27.71 37.67,27.02 37.68,27.01 37.71,27 37.74,26.97 37.72,26.89 37.7,26.84 37.48,26.61 37.47,26.6 37.46,26.58 37.46,26.2 37.45,26.17 37.41,26.15 37.41,24.91 37.42,24.87 37.46,24.85 37.46,24.73 37.45,24.7 37.43,24.68 37.42,24.68 37.39,24.68 37.26,24.81 37.25,24.83 37.24,24.85 37.24,25.07 37.23,25.11 37.19,25.12 36.69,25.12 36.66,25.14 36.64,25.17 36.64,25.22 36.64,25.24 36.63,25.25 36.25,25.63 36.24,25.65 36.24,25.67 36.24,25.99 36.24,26.01 36.22,26.03 35.99,26.26 35.99,26.27 35.48,26.42 35.39,25.89 35.4,25.88 35.4,25.85 35.36,25.76 35.34,25.73 35.31,25.73 35.22,25.73 35.2,25.73 35.18,25.74 35.12,25.8 35.12,25.83 34.9,26.17 34.51,26.09 34.5,26.08 34.45,26.08 34.42,26.12 34.41,26.13 34.4,26.15 34.4,27.24 34.42,27.28 34.45,27.29 36.51,27.29 36.55,27.31 36.56,27.34 36.56,30.88 36.57,30.9 36.58,30.92 36.66,30.98 36.68,30.98
DGND on BOTTOM (solid shape): outline of 127 points within 94.98,94.39 97.9,104.84
DGND on BOTTOM (solid shape): outline of 89 points within 102.14,72.46 106.56,79.82
DGND on BOTTOM (solid shape): outline of 139 points within 118.72,44.22 121.64,52.6
DGND on BOTTOM (solid shape): outline of 105 points within 13.3,17.67 18.09,20.46
DGND on BOTTOM (solid shape): outline of 122 points within 70.37,105.54 73.53,110.06
DGND on BOTTOM (solid shape): outline of 131 points within 89.54,27.09 96.97,37.44
DGND on BOTTOM (solid shape): outline of 115 points within 43.95,14.01 50.65,20.31
DGND on BOTTOM (solid shape): outline of 202 points within 84.94,160.11 103.42,167.32
DGND on BOTTOM (solid shape): outline of 186 points within 98.95,86.97 103.47,91.42
DGND on BOTTOM (solid shape): outline of 210 points within 68.96,152.74 85.94,154.88
DGND on BOTTOM (solid shape): outline of 243 points within 91.94,105.5 105.96,108.44
DGND on BOTTOM (solid shape): outline of 218 points within 57.31,31.38 71.87,37.33
DGND on BOTTOM (solid shape): outline of 275 points within 42.04,23.02 46.45,29.53
DGND on BOTTOM (solid shape): outline of 147 points within 72.25,30.36 89.5,37.05
DGND on BOTTOM (solid shape): outline of 305 points within 36.37,34.59 44.74,47.7
DGND on BOTTOM (solid shape): outline of 158 points within 121.52,35.61 126.26,41.4
DGND on BOTTOM (solid shape): outline of 305 points within 76.1,157.73 102.78,163.18
DGND on BOTTOM (solid shape): outline of 620 points within 11.02,1.02 45.14,24.51
DGND on BOTTOM (solid shape): outline of 1225 points within 86.07,34.79 123.56,49.19
DGND on BOTTOM (solid shape): outline of 4860 points within 11.02,20.55 58.85,87.57
DGND on L03_SIG01 (solid shape): 61.24,61.09 61.74,60.6 61.75,60.58 61.75,60.56 61.75,56.69 61.75,56.67 61.72,56.65 61.71,56.64 61.68,56.65 61.18,57.15 61.17,57.16 61.17,57.18 61.17,61.05 61.17,61.08 61.2,61.09 61.21,61.1
DGND on L03_SIG01 (solid shape): 61.47,55.83 62.22,55.08 62.24,55.06 62.24,55.04 62.24,54.5 62.23,54.47 62.21,54.45 62.19,54.44 62.16,54.45 61.41,55.2 61.4,55.22 61.39,55.24 61.39,55.79 61.4,55.81 61.43,55.83 61.44,55.84
DGND on L03_SIG01 (solid shape): 76.63,112.24 76.65,112.25 76.68,112.25 76.7,112.24 76.71,112.22 76.71,107.02 76.71,107 76.7,106.98 76.48,106.76 76.45,106.74 76.42,106.75 76.41,106.75 76.39,106.78 76.39,111.98 76.39,112 76.4,112.02
DGND on L03_SIG01 (solid shape): 81.79,109.55 81.82,109.56 81.85,109.56 81.86,109.55 81.88,109.53 81.88,109.31 81.88,109.29 81.86,109.27 80.15,107.56 80.13,107.55 80.1,107.55 80.08,107.56 80.07,107.58 80.07,107.8 80.07,107.82 80.08,107.84
DGND on L03_SIG01 (solid shape): 82.84,121.12 82.87,121.13 82.9,121.13 82.91,121.12 82.93,121.1 82.93,120.73 82.92,120.71 82.91,120.7 82.01,119.8 81.99,119.79 81.98,119.78 81.63,119.78 81.6,119.79 81.58,119.81 81.57,119.83 81.58,119.86
DGND on L03_SIG01 (solid shape): 97.03,77.01 97.06,77.03 97.09,77.02 97.1,77.02 97.12,76.99 97.12,74.32 97.12,74.3 97.11,74.29 96.81,73.99 96.78,73.98 96.75,73.98 96.74,73.99 96.72,74.01 96.72,76.68 96.73,76.7 96.74,76.71
DGND on L03_SIG01 (solid shape): 115,105.56 115.03,105.55 115.05,105.53 115.05,105.51 115.05,105.48 113.37,103.81 113.34,103.79 113.31,103.8 113.3,103.8 113.28,103.83 113.28,104.57 113.29,104.59 113.3,104.61 114.23,105.54 114.25,105.55 114.27,105.56
DGND on L03_SIG01 (solid shape): 117.99,100.98 118.02,100.98 118.04,100.95 118.05,100.94 118.04,100.91 117.31,100.18 117.29,100.17 117.27,100.16 115.56,100.16 115.53,100.17 115.52,100.19 115.51,100.21 115.52,100.24 116.25,100.97 116.26,100.98 116.28,100.98
DGND on L03_SIG01 (solid shape): 41,58.56 41.43,58.13 41.45,58.12 41.47,58.11 42.44,58.11 42.46,58.11 42.47,58.1 43.32,57.25 43.33,57.24 43.33,57.22 43.33,50.11 43.33,50.08 43.3,50.06 43.29,50.05 43.26,50.06 40.94,52.38 40.93,52.4 40.92,52.42 40.92,58.51 40.93,58.54 40.95,58.56 40.97,58.57
DGND on L03_SIG01 (solid shape): 85.05,116.59 85.08,116.6 85.11,116.6 85.12,116.6 85.14,116.57 85.14,115.27 85.13,115.25 85.12,115.23 84.14,114.25 84.12,114.24 84.1,114.23 83.75,114.23 83.73,114.23 83.71,114.22 83.65,114.16 83.62,114.14 83.6,114.14 83.58,114.15 83.56,114.18 83.56,115.08 83.57,115.1 83.58,115.12
DGND on L03_SIG01 (solid shape): 104.48,117.38 104.62,117.35 104.76,117.37 104.77,117.38 104.8,117.37 104.87,117.32 104.89,117.3 104.9,117.28 104.9,115.68 104.89,115.66 104.88,115.64 104.42,115.18 104.4,115.17 104.37,115.17 104.35,115.18 104.34,115.2 104.34,117.29 104.34,117.32 104.36,117.33 104.44,117.39 104.47,117.39
DGND on L03_SIG01 (solid shape): 121.19,114.9 123.94,112.14 123.95,112.12 123.95,112.09 123.94,112.07 123.92,112.06 121.33,112.06 121.31,112.06 121.29,112.07 121.24,112.12 121.23,112.15 121.22,112.19 121.2,112.29 121.14,112.38 121.12,112.41 121.11,112.44 121.11,114.85 121.12,114.88 121.14,114.9 121.16,114.9
DGND on L03_SIG01 (solid shape): 92.72,92.27 92.75,92.26 92.77,92.24 92.77,92.22 92.77,92.19 92.15,91.57 92.13,91.56 92.11,91.55 89.8,91.55 89.77,91.56 89.75,91.58 89.7,91.66 89.7,91.69 89.71,91.7 89.75,91.91 89.67,92.1 89.66,92.11 89.65,92.14 89.7,92.24 89.72,92.26 89.74,92.27
DGND on L03_SIG01 (solid shape): 63.25,127.86 63.34,127.77 63.35,127.75 63.35,127.73 63.35,105.06 63.35,105.04 63.34,105.03 62.79,104.48 62.72,104.46 62.7,104.47 62.63,104.52 62.62,104.54 62.62,104.56 62.62,110.05 62.62,110.07 62.63,110.09 63.16,110.62 63.17,110.63 63.17,110.65 63.17,127.81 63.18,127.84 63.2,127.86 63.22,127.86
DGND on L03_SIG01 (solid shape): 43.03,72.92 43.07,72.89 43.08,72.87 43.08,72.85 43.08,66.16 43.08,66.14 43.07,66.12 40.75,63.8 40.72,63.79 40.69,63.79 40.68,63.8 40.66,63.82 40.66,64.26 40.66,64.27 40.68,64.29 42.72,66.33 42.73,66.35 42.73,66.37 42.73,67.96 42.74,67.98 42.75,68 42.94,68.19 42.95,68.21 42.96,68.23 42.96,72.88 42.97,72.9 42.99,72.92 43,72.93
DGND on L03_SIG01 (solid shape): 83.45,106.62 83.48,106.64 83.51,106.64 83.52,106.63 83.54,106.6 83.54,106.49 83.54,106.47 83.53,106.46 82.93,105.86 82.91,105.84 82.91,105.82 82.91,104.83 82.9,104.81 82.88,104.79 82.86,104.78 82.84,104.79 82.19,105.43 82.18,105.45 82.18,105.47 82.18,105.97 82.18,105.99 82.19,106 82.48,106.29 82.5,106.3 82.52,106.3 83.11,106.3 83.13,106.31 83.15,106.32
DGND on L03_SIG01 (solid shape): 60.53,75.72 60.54,75.71 60.65,75.66 60.78,75.66 60.81,75.65 60.88,75.59 60.89,75.58 60.89,75.56 60.89,74.82 60.89,74.8 60.88,74.78 60.51,74.42 60.5,74.41 60.48,74.4 59.84,74.4 59.81,74.41 59.79,74.43 59.78,74.45 59.79,74.48 60.37,75.06 60.38,75.07 60.38,75.09 60.38,75.63 60.39,75.65 60.41,75.67 60.5,75.72
DGND on L03_SIG01 (solid shape): 132.44,76.56 132.46,76.54 132.47,76.51 132.47,73.68 132.46,73.66 132.44,73.64 132.35,73.59 132.32,73.59 132.31,73.6 132.18,73.65 132.04,73.64 132.03,73.64 132.01,73.65 131.93,73.7 131.92,73.72 131.92,73.74 131.92,76.45 131.92,76.47 131.93,76.49 132.01,76.55 132.03,76.55 132.04,76.55 132.18,76.55 132.31,76.6 132.32,76.6 132.35,76.61
DGND on L03_SIG01 (solid shape): 53.31,108.81 54.32,107.8 54.33,107.79 54.33,107.77 54.33,103.63 54.32,103.6 54.3,103.59 54.29,103.58 54.26,103.59 53.72,104.12 53.71,104.16 53.59,104.38 53.34,104.45 53.31,104.46 53.25,104.51 53.24,104.53 53.23,104.55 53.23,108.77 53.24,108.79 53.26,108.81 53.28,108.82
DGND on L03_SIG01 (solid shape): 84.28,89.31 84.3,89.31 84.31,89.3 84.52,89.09 84.53,89.07 84.53,89.04 84.52,89.02 84.5,89.01 83.35,89.01 83.33,89 83.31,88.99 82.14,87.82 82.13,87.8 82.12,87.79 82.12,87.62 82.12,87.6 82.11,87.58 82.04,87.52 82.02,87.52 81.95,87.52 81.89,87.52 81.87,87.52 81.8,87.58 81.79,87.6 81.78,87.62 81.78,88.1 81.79,88.12 81.8,88.14 82.96,89.3 82.98,89.31 83,89.31
DGND on L03_SIG01 (solid shape): 28.61,37.24 28.71,37.14 28.73,37.12 28.73,37.11 28.73,34.68 28.73,34.66 28.71,34.64 28.43,34.35 28.42,34.35 28.27,34.21 28.21,34.02 28.2,33.98 28.16,33.97 28.12,33.98 28.06,34.05 28.05,34.07 28.04,34.09 28.04,36.02 28.05,36.04 28.06,36.06 28.52,36.53 28.53,36.54 28.54,36.56 28.54,37.2 28.55,37.22 28.57,37.24 28.58,37.25
DGND on L03_SIG01 (solid shape): 110.99,114.4 111.01,114.4 111.03,114.38 111.09,114.3 111.09,114.28 111.07,114.22 111.06,114.14 111.04,114.11 109.34,112.4 109.33,112.38 109.32,112.37 109.32,111.33 109.32,111.31 109.31,111.3 105.71,107.7 105.7,107.69 105.68,107.68 104.69,107.68 104.66,107.69 104.64,107.71 104.64,107.73 104.64,107.76 106.6,109.72 106.62,109.74 106.62,109.76 106.62,113.74 106.62,113.76 106.63,113.78 107.24,114.39 107.26,114.4 107.28,114.4
DGND on L03_SIG01 (solid shape): 34.44,23.87 34.48,23.85 34.49,23.82 34.49,23.46 34.49,23.45 34.48,23.43 34.15,23.1 34.14,23.09 34.14,23.07 34.14,22 34.14,21.98 34.15,21.96 34.67,21.44 34.68,21.42 34.68,21.39 34.67,21.3 34.65,21.28 34.59,21.25 32.28,21.25 32.25,21.26 32.23,21.29 32.22,21.3 32.23,21.33 32.72,21.82 32.74,21.84 32.74,21.86 32.74,22.2 32.74,22.22 32.75,22.24 34.35,23.83
DGND on L03_SIG01 (solid shape): 39.54,71.93 39.57,71.95 39.6,71.94 39.61,71.94 39.63,71.91 39.63,68.17 39.62,68.15 39.61,68.14 39.32,67.84 39.3,67.83 39.3,67.81 39.3,66.96 39.29,66.93 39.28,66.92 39.2,66.86 39.17,66.86 39.16,66.86 38.84,66.84 38.67,66.53 38.65,66.5 38.48,66.32 38.45,66.31 38.42,66.31 38.41,66.32 38.39,66.34 38.39,70.76 38.39,70.78 38.4,70.79
DGND on L03_SIG01 (solid shape): 70.89,74.07 71.22,73.74 71.24,73.73 71.26,73.73 71.64,73.73 71.66,73.72 71.69,73.7 71.69,73.68 71.69,72.42 71.69,72.4 71.68,72.39 71.62,72.33 71.5,72.33 71.44,72.39 71.43,72.4 71.42,72.42 71.42,73.05 71.42,73.07 71.41,73.09 71.05,73.44 71.04,73.45 71.02,73.46 70.7,73.46 70.68,73.46 70.67,73.47 70.64,73.5 70.63,73.52 70.62,73.54 70.62,73.86 70.63,73.88 70.64,73.9 70.8,74.06 70.87,74.08
DGND on L03_SIG01 (solid shape): 74.8,102.66 75.72,101.74 75.73,101.72 75.74,101.7 75.74,100.22 75.73,100.2 75.71,100.18 75.69,100.17 75.66,100.18 74.96,100.88 74.95,100.9 74.95,100.93 74.98,101.03 75,101.05 75.01,101.05 75.28,101.48 74.85,101.74 74.84,101.74 74.81,101.75 74.74,101.8 74.73,101.82 74.72,101.84 74.72,102.62 74.73,102.65 74.75,102.66 74.77,102.67
DGND on L03_SIG01 (solid shape): 79.71,113.85 79.73,113.86 79.76,113.86 79.85,113.85 79.87,113.83 79.9,113.78 79.93,113.75 79.94,113.72 79.94,113.7 79.93,113.67 79.91,113.65 79.88,113.64 79.84,113.63 79.82,113.62 78.21,112.01 78.2,111.99 78.19,111.97 78.19,106.86 78.19,106.85 78.18,106.83 77.08,105.73 77.06,105.72 77.04,105.72 76.96,105.72 76.9,105.76 76.86,105.8 76.85,105.81 76.84,105.91 76.84,105.93 76.85,105.95 77.59,106.68 77.6,106.7 77.6,106.72 77.6,111.72 77.61,111.74 77.62,111.75
DGND on L03_SIG01 (solid shape): 82.48,114.39 82.5,114.4 82.52,114.41 82.61,114.4 82.63,114.39 82.64,114.38 82.74,114.28 82.87,114.23 82.88,114.23 82.9,114.21 82.94,114.11 82.94,114.09 82.92,114.06 81.55,112.69 81.54,112.67 81.54,112.66 81.54,110 81.53,109.98 81.52,109.96 79.6,108.04 79.59,108.02 79.58,108 79.58,107.46 79.58,107.44 79.57,107.42 78.98,106.84 78.96,106.83 78.93,106.83 78.91,106.84 78.9,106.86 78.9,111.74 78.9,111.76 78.91,111.78 79.83,112.69 79.84,112.7 79.86,112.71 80.78,112.71 80.8,112.71 80.81,112.72
DGND on L03_SIG01 (solid shape): 111.3,166.72 111.32,166.72 111.34,166.71 111.87,166.18 111.88,166.16 111.88,166.13 111.87,166.11 111.85,166.09 99,166.09 98.98,166.09 98.96,166.08 98.1,165.22 98.08,165.21 98.06,165.2 97.52,165.2 97.49,165.21 97.44,165.25 97.08,165.3 96.86,165.01 96.86,164.96 96.85,164.94 96.61,164.94 96.59,164.95 96.57,164.97 96.56,164.99 96.57,165.02 98.26,166.71 98.27,166.72 98.29,166.72
DGND on L03_SIG01 (solid shape): 122.8,80.26 122.87,80.25 122.91,80.24 122.94,80.23 123.42,79.75 123.43,79.73 123.43,79.71 123.43,78.53 123.42,78.5 123.4,78.48 123.39,78.48 123.36,78.48 123.3,78.54 123.29,78.57 123.28,78.61 123.09,78.89 122.74,78.88 122.73,78.87 122.71,78.87 122.62,78.92 122.6,78.94 122.59,78.96 122.59,80.2 122.6,80.22 122.62,80.24 122.7,80.29 122.73,80.29
DGND on L03_SIG01 (solid shape): 73.63,116.83 73.65,116.84 73.68,116.84 73.7,116.83 73.71,116.81 73.71,115.79 73.71,115.77 73.7,115.75 73.4,115.46 73.39,115.44 73.39,115.42 73.39,114.17 73.38,114.15 73.37,114.13 72.9,113.66 72.89,113.64 72.89,113.62 72.89,111.95 72.88,111.93 72.87,111.92 72.75,111.79 72.74,111.78 72.73,111.76 72.73,111.72 72.72,111.7 72.7,111.68 72.69,111.67 72.66,111.68 72.63,111.71 72.62,111.72 72.61,111.74 72.61,114.43 72.62,114.45 72.63,114.47 72.98,114.82 72.99,114.83 72.99,114.85 72.99,116.17 73,116.19 73.01,116.21
DGND on L03_SIG01 (solid shape): 87.81,82.51 87.82,82.51 87.84,82.5 88.31,82.03 88.32,82.02 88.34,82.01 89.49,82.01 89.51,82.01 89.53,82 90.21,81.31 90.23,81.3 90.25,81.3 90.68,81.3 90.7,81.29 90.72,81.28 90.77,81.23 90.79,81.21 90.79,81.19 90.78,81.1 90.76,81.08 90.75,81.07 90.64,80.96 90.59,80.81 90.59,80.79 90.57,80.77 90.47,80.73 90.44,80.73 90.42,80.75 89.54,81.62 89.53,81.63 89.51,81.63 88.03,81.63 88.01,81.64 88,81.65 87.22,82.42 87.21,82.45 87.21,82.48 87.21,82.49 87.24,82.51
DGND on L03_SIG01 (solid shape): 96.8,98.7 96.82,98.7 96.84,98.68 96.89,98.6 96.9,98.57 96.89,98.56 96.88,98.27 97.09,98.07 97.1,98.06 97.12,98.04 97.14,97.95 97.14,97.92 97.12,97.9 96.42,97.2 96.4,97.18 96.39,97.18 95.98,97.18 95.96,97.19 95.94,97.2 95.88,97.26 95.88,97.29 95.85,97.49 95.72,97.63 95.71,97.64 95.69,97.66 95.68,97.75 95.69,97.77 95.7,97.79 96.6,98.69 96.61,98.7 96.63,98.7
DGND on L03_SIG01 (solid shape): 37.82,70.89 37.84,70.9 37.87,70.9 37.89,70.89 37.91,70.87 37.91,64.67 37.91,64.65 37.92,64.64 38.75,63.81 38.76,63.79 38.77,63.77 38.77,59.73 38.76,59.7 38.74,59.68 38.72,59.67 38.69,59.68 38.42,59.96 38.41,59.97 38.4,59.99 38.4,62.95 38.4,62.97 38.39,62.98 38.17,63.2 38.16,63.22 38.15,63.26 38.14,63.28 38.07,63.35 38.06,63.38 37.97,63.62 37.73,63.73 37.7,63.76 37.7,70.75 37.71,70.77 37.72,70.78
DGND on L03_SIG01 (solid shape): 86.69,43.76 86.71,43.77 86.74,43.77 86.83,43.76 86.85,43.74 86.88,43.7 86.9,43.67 87.02,43.56 87.03,43.52 87.02,43.49 86.9,43.37 86.85,43.29 86.83,43.2 86.83,41.58 86.83,41.56 86.81,41.54 86.64,41.36 86.62,41.35 86.59,41.35 86.49,41.37 86.47,41.39 86.47,41.4 86.27,41.61 85.99,41.61 85.97,41.6 85.95,41.6 85.86,41.66 85.85,41.68 85.84,41.7 85.84,43.65 85.86,43.69 85.89,43.7 86.61,43.7 86.63,43.7 86.65,43.72
DGND on L03_SIG01 (solid shape): 67.93,79.33 67.95,79.32 67.96,79.31 68.02,79.25 68.02,79.14 67.96,79.08 67.95,79.07 67.93,79.07 67.15,79.07 67.13,79.06 67.12,79.05 66.68,78.62 66.66,78.61 66.55,78.58 66.46,78.51 65.23,77.28 65.21,77.27 65.19,77.26 64.4,77.26 64.37,77.27 64.35,77.29 64.34,77.31 64.35,77.34 65.71,78.7 65.74,78.72 65.78,78.72 66.05,78.89 66.08,79.19 66.08,79.2 66.08,79.23 66.14,79.31 66.15,79.32 66.18,79.33
DGND on L03_SIG01 (solid shape): 61.29,46.21 61.32,46.22 61.34,46.22 61.36,46.21 61.38,46.19 61.38,39.36 61.38,39.34 61.39,39.32 65.1,35.61 65.11,35.6 65.11,35.58 65.11,33.16 65.1,33.12 65.08,33.09 65.04,32.7 65.38,32.51 65.41,32.51 65.48,32.45 65.49,32.43 65.49,32.41 65.49,29.95 65.48,29.92 65.46,29.9 65.45,29.9 65.42,29.9 64.2,31.12 64.19,31.13 64.19,31.15 64.19,35.8 64.19,35.82 64.18,35.84 61.04,38.98 61.03,38.99 61.02,39.01 61.02,45.92 61.03,45.94 61.04,45.95
DGND on L03_SIG01 (solid shape): 42.51,128.63 42.58,128.58 42.59,128.56 42.6,128.54 42.6,126.98 42.59,126.96 42.58,126.95 41.55,125.91 41.52,125.89 41.49,125.9 41.48,125.9 41.46,125.93 41.46,126.84 41.47,126.86 41.48,126.88 41.55,126.94 41.57,126.94 41.58,126.94 42.01,127.32 41.53,127.62 41.51,127.62 41.48,127.64 41.46,127.67 41.46,127.7 41.48,127.72 42.37,128.61 42.4,128.62 42.49,128.64
DGND on L03_SIG01 (solid shape): 64.32,42.3 64.34,42.3 64.35,42.29 65.45,41.2 65.46,41.19 65.48,41.18 68.23,41.18 68.25,41.18 68.26,41.17 69.76,39.67 69.78,39.66 69.8,39.65 71.03,39.65 71.12,39.6 71.19,39.57 71.2,39.56 71.23,39.46 71.23,39.43 71.21,39.41 69.88,38.07 69.86,38.06 69.84,38.06 65.65,38.06 65.63,38.06 65.61,38.08 65.56,38.15 65.55,38.17 65.55,38.18 65.55,38.32 65.47,38.48 65.47,40.51 65.47,40.53 65.45,40.55 64,42 63.99,42.02 63.99,42.05 64.01,42.14 64.03,42.16 64.04,42.17 64.13,42.21 64.2,42.28 64.23,42.3
DGND on L03_SIG01 (solid shape): 106.93,87.37 106.95,87.37 106.97,87.36 108.26,86.06 108.28,86.04 108.27,86.01 108.27,85.99 108.24,85.98 107.52,85.98 107.5,85.98 107.48,86 107.42,86.07 107.42,86.09 107.42,86.1 107.07,86.54 106.73,86.1 106.73,86.09 106.72,86.07 106.67,86 106.65,85.98 106.63,85.98 106.24,85.98 106.23,85.98 106.21,85.99 105.75,86.45 105.74,86.47 105.73,86.49 105.73,87.17 105.74,87.2 105.75,87.21 105.83,87.27 105.85,87.27 105.86,87.27 106.03,87.27 106.24,87.37
DGND on L03_SIG01 (solid shape): 58.37,58.12 58.37,58.11 58.52,58.02 58.69,58 58.7,58 58.72,57.99 58.79,57.94 58.8,57.92 58.8,57.9 58.8,56.86 58.8,56.84 58.78,56.82 58.69,56.77 58.66,56.77 58.65,56.78 58.54,56.82 58.42,56.82 58.4,56.82 58.38,56.83 58.3,56.91 58.3,56.94 58.3,56.95 58.19,57.32 57.8,57.37 57.79,57.36 57.77,57.36 57.68,57.42 57.66,57.43 57.66,57.46 57.66,57.91 57.66,57.93 57.68,57.95 57.76,58.01 57.79,58.01 57.8,58 58.03,57.98 58.22,58.11 58.23,58.11 58.25,58.12 58.35,58.13
DGND on L03_SIG01 (solid shape): 64.99,76.55 65.02,76.54 65.04,76.52 65.05,76.51 65.04,76.48 63.89,75.32 63.87,75.31 63.85,75.31 63.77,75.31 63.74,75.33 63.12,75.14 63.65,74.78 63.68,74.78 63.7,74.78 63.73,74.76 63.75,74.74 63.75,74.72 63.75,74.68 63.75,74.66 63.74,74.65 62.73,73.64 62.71,73.63 62.68,73.63 62.66,73.64 62.65,73.66 62.65,75.49 62.66,75.53 62.7,75.54 63.31,75.54 63.33,75.55 63.35,75.56 64.32,76.54 64.34,76.55 64.36,76.55
DGND on L03_SIG01 (solid shape): 81.43,74.53 81.45,74.52 81.46,74.51 81.62,74.35 81.63,74.33 81.78,74.12 82.03,74.07 82.08,74.06 82.09,74.02 82.09,74.01 82.36,73.74 82.37,73.73 82.41,73.73 82.44,73.7 82.43,73.63 82.26,73.47 82.25,73.46 82.23,73.46 81.59,73.46 81.57,73.46 81.55,73.47 81.49,73.54 81.49,73.57 81.42,73.79 81.22,73.92 81.2,73.93 80.88,74.24 80.87,74.25 80.85,74.26 80.79,74.26 80.77,74.26 80.75,74.27 80.69,74.34 80.69,74.45 80.75,74.51 80.77,74.52 80.79,74.53
DGND on L03_SIG01 (solid shape): 85.01,45.47 85.04,45.48 85.06,45.48 85.08,45.47 85.1,45.45 85.1,42.6 85.09,42.58 85.08,42.56 84.32,41.81 84.31,41.79 84.3,41.73 84.28,41.72 84.25,41.7 84.23,41.7 84.2,41.71 84.13,41.75 84.05,41.77 84.04,41.77 84.01,41.79 83.98,41.89 83.98,41.92 83.99,41.94 84.43,42.37 84.44,42.39 84.44,42.41 84.44,43.77 84.46,43.81 84.49,43.82 84.6,43.82 84.61,43.83 84.63,43.84 84.86,44.07 84.87,44.09 84.88,44.11 84.88,44.35 84.86,44.44 84.81,44.52 84.69,44.64 84.61,44.69 84.52,44.71 84.49,44.71 84.46,44.73 84.44,44.76 84.44,45.33 84.46,45.37 84.49,45.38 84.91,45.38 84.93,45.39 84.94,45.4
DGND on L03_SIG01 (solid shape): 53.51,112.53 53.54,112.5 53.54,111.68 53.54,111.66 53.55,111.64 54.27,110.92 54.28,110.9 54.29,110.88 54.29,109.23 54.29,109.21 54.3,109.2 55.11,108.39 55.12,108.38 55.12,108.36 55.12,107.51 55.12,107.49 55.11,107.47 54.9,107.27 54.88,107.25 54.85,107.25 54.83,107.26 54.82,107.29 54.82,107.97 54.81,107.99 54.8,108 53.43,109.37 53.42,109.39 53.42,109.41 53.42,110.44 53.42,110.46 53.44,110.48 53.51,110.54 53.53,110.54 53.54,110.54 53.94,110.86 53.54,111.19 53.53,111.18 53.51,111.19 53.44,111.25 53.42,111.27 53.42,111.29 53.42,112.49 53.43,112.52
DGND on L03_SIG01 (solid shape): 54.85,61.95 54.87,61.95 54.89,61.94 56.31,60.51 56.32,60.5 56.32,60.48 56.32,56.58 56.32,56.55 56.29,56.53 56.28,56.53 56.25,56.53 54.88,57.9 54.86,57.91 54.84,57.92 53.94,57.92 53.92,57.92 53.91,57.93 52.65,59.19 52.63,59.2 52.61,59.21 50.07,59.21 50.05,59.23 50.04,59.25 49.64,59.53 49.34,59.14 49.33,59.11 49.28,59.05 49.26,59.03 49.24,59.03 44.18,59.03 44.16,59.03 44.14,59.04 43.56,59.63 43.55,59.65 43.55,59.68 43.56,59.7 43.58,59.71 51.22,59.71 51.24,59.72 51.26,59.73 53.31,61.78 53.33,61.79 53.34,61.79 54.46,61.79 54.61,61.83 54.74,61.93 54.76,61.95
DGND on L03_SIG01 (solid shape): 76.49,97.92 77.58,96.83 77.6,96.82 77.62,96.82 77.84,96.82 84.75,96.82 84.77,96.81 84.78,96.8 84.84,96.73 84.85,96.64 84.83,96.62 84.74,96.55 84.72,96.55 84.7,96.56 84.32,96.49 84.23,96.11 84.23,96.1 84.23,96.07 84.17,95.99 84.16,95.98 84.13,95.97 79.25,95.97 79.23,95.97 79.21,95.96 76.54,93.28 76.52,93.27 76.5,93.26 76.2,93.26 76.17,93.27 76.11,93.32 76.06,93.35 76.05,93.37 76.03,93.46 76.03,93.48 76.04,93.51 76.37,93.83 76.38,93.85 76.39,93.87 76.39,97.09 76.39,97.11 76.41,97.14 76.42,97.16 76.42,97.87 76.43,97.9 76.45,97.92 76.46,97.92
DGND on L03_SIG01 (solid shape): 130.18,115.22 130.21,115.21 130.23,115.19 130.24,115.17 130.23,115.14 127.56,112.48 127.55,112.46 127.53,112.46 126.17,112.46 126.15,112.46 126.14,112.48 126.08,112.54 126.07,112.57 126.06,112.7 126.01,112.82 126,112.85 126.02,112.88 126.42,113.29 126.43,113.3 126.44,113.32 126.44,114.18 126.45,114.21 126.47,114.24 126.46,114.7 126.01,114.77 126,114.76 125.98,114.76 125.89,114.81 125.87,114.83 125.86,114.86 125.86,115.04 125.87,115.07 125.88,115.09 125.97,115.14 125.99,115.14 126,115.14 126.2,115.11 126.44,115.22
DGND on L03_SIG01 (solid shape): 96.75,57.54 96.78,57.55 96.81,57.55 96.82,57.54 96.84,57.52 96.84,52.52 96.83,52.49 96.82,52.48 96.75,52.42 96.73,52.41 96.72,52.42 96.34,52.25 96.37,51.84 96.39,51.81 96.4,51.78 96.4,44.99 96.4,44.97 96.39,44.96 93.32,41.89 93.3,41.87 93.28,41.87 93.21,41.87 93.18,41.88 93.16,41.9 93.15,41.92 93.16,41.95 94.52,43.31 94.53,43.33 94.54,43.35 94.54,54.62 94.54,54.64 94.55,54.66 95.04,55.14 95.06,55.15 95.11,55.16 95.42,55.45 95.23,55.83 95.22,55.83 95.21,55.85 95.19,55.95 95.19,55.97 95.21,55.99
DGND on L03_SIG01 (solid shape): 93.16,84.55 94.15,83.56 94.17,83.55 94.19,83.54 95.13,83.54 95.15,83.54 95.16,83.53 95.34,83.35 95.35,83.33 95.35,83.3 95.34,83.28 95.32,83.27 94.24,83.27 94.22,83.26 94.2,83.25 93.78,82.83 93.77,82.81 93.77,82.79 93.77,81.77 93.76,81.75 93.73,81.73 93.72,81.72 93.69,81.73 92.79,82.62 92.78,82.64 92.78,82.66 92.78,83.03 92.78,83.05 92.8,83.07 92.88,83.13 92.9,83.13 92.91,83.13 93.38,83.48 92.88,83.79 92.85,83.78 92.83,83.79 92.8,83.8 92.79,83.82 92.78,83.87 92.79,83.89 93.07,84.17 93.08,84.18 93.09,84.2 93.09,84.5 93.09,84.53 93.12,84.55 93.13,84.55
DGND on L03_SIG01 (solid shape): 127.72,46.32 127.75,46.34 127.77,46.34 127.87,46.31 127.89,46.29 127.9,46.28 128.01,46.1 128.2,46.01 128.24,46.01 128.27,45.99 128.62,45.65 128.63,45.63 128.63,45.61 128.63,38.98 128.63,38.96 128.62,38.95 126.33,36.66 126.31,36.65 126.29,36.65 125.48,36.65 125.46,36.65 125.44,36.68 125.43,36.69 125.44,36.72 127.18,38.47 127.19,38.48 127.2,38.5 127.2,42.22 127.2,42.25 127.22,42.26 127.31,42.31 127.34,42.31 127.35,42.31 127.9,42.61 127.35,42.91 127.34,42.9 127.31,42.9 127.22,42.95 127.2,42.97 127.2,42.99 127.2,45.77 127.2,45.79 127.21,45.81
DGND on L03_SIG01 (solid shape): 60.45,73.89 60.48,73.89 60.5,73.86 60.5,73.85 60.5,73.82 60.25,73.57 60.23,73.56 60.21,73.56 60.13,73.56 60.1,73.58 59.56,73.6 59.62,73.07 59.64,73.05 59.64,73.03 59.65,73 59.65,72.98 59.63,72.96 59.6,72.93 59.58,72.92 58.27,72.92 58.25,72.93 58.23,72.94 58.18,73.01 58.17,73.03 58.17,73.04 57.82,73.46 57.47,73.04 57.47,73.03 57.47,73.01 57.41,72.94 57.39,72.93 57.37,72.92 57.2,72.92 57.18,72.93 57.16,72.94 56.29,73.81 56.28,73.83 56.28,73.86 56.29,73.88 56.31,73.89
DGND on L03_SIG01 (solid shape): 64.49,81.9 64.52,81.91 64.59,81.86 64.6,81.83 64.6,81.67 64.6,81.65 64.61,81.64 66.07,80.18 66.09,80.15 66.08,80.12 66.08,80.11 66.05,80.09 64.75,80.09 64.73,80.08 64.71,80.07 64.09,79.45 64.07,79.43 64.07,79.41 64.07,78.5 64.07,78.48 64.06,78.47 63.01,77.42 63,77.41 62.98,77.41 62.81,77.41 62.78,77.41 62.76,77.44 62.76,77.45 62.76,77.48 62.96,77.68 62.97,77.7 62.98,77.72 62.98,78.09 62.98,78.11 62.99,78.13 63.06,78.18 63.09,78.19 63.49,78.54 63.09,78.9 63.06,78.9 62.99,78.96 62.98,78.98 62.98,79 62.98,79.59 62.98,79.61 62.99,79.62 63.6,80.23 63.61,80.25 63.62,80.27 63.62,81.01 63.62,81.03 63.63,81.04
DGND on L03_SIG01 (solid shape): 43.62,155.69 43.64,155.69 43.66,155.67 43.77,155.57 43.91,155.52 43.94,155.51 43.95,155.48 44.35,155.18 44.66,155.58 44.66,155.59 44.66,155.61 44.72,155.68 44.74,155.69 44.76,155.69 46.05,155.69 46.09,155.68 46.1,155.64 46.1,151.83 46.09,151.8 46.07,151.78 46.05,151.77 46.03,151.78 44.2,153.6 44.19,153.62 44.19,153.65 44.2,153.74 44.21,153.76 44.22,153.76 44.29,154.32 43.73,154.25 43.72,154.24 43.7,154.23 43.61,154.22 43.59,154.22 43.57,154.23 42.9,154.9 42.89,154.92 42.89,154.94 42.89,155.64 42.9,155.68 42.94,155.69
DGND on L03_SIG01 (solid shape): 115.66,87.69 115.82,87.53 115.83,87.51 115.84,87.49 115.84,84.66 115.83,84.63 115.8,84.6 115.75,84.24 116.04,84.02 116.08,84.01 116.11,84 118.11,82 118.12,81.98 118.13,81.96 118.13,80.25 118.12,80.22 118.1,80.2 118.08,80.2 118.05,80.2 116.95,81.3 116.94,81.32 116.94,81.34 116.94,81.43 116.96,81.45 116.96,81.45 117,81.99 116.47,81.95 116.46,81.94 116.44,81.93 116.35,81.93 116.33,81.93 116.31,81.94 116.27,81.98 116.26,82.01 116.22,82.31 116.05,82.58 115.73,82.6 115.72,82.59 115.69,82.59 115.61,82.65 115.59,82.67 115.59,82.69 115.59,87.64 115.59,87.67 115.62,87.69 115.63,87.69
DGND on L03_SIG01 (solid shape): 83.09,78.3 83.11,78.31 83.13,78.31 83.23,78.29 83.25,78.28 83.25,78.26 83.33,78.16 83.44,78.08 83.45,78.08 83.5,78.03 83.51,77.99 83.5,77.96 83.45,77.9 83.44,77.9 83.32,77.36 83.87,77.47 83.87,77.48 84.05,77.66 84.07,77.67 84.09,77.68 84.89,77.68 84.91,77.67 84.93,77.66 85.34,77.25 85.35,77.23 85.35,77.2 85.34,77.19 85.32,77.17 84.91,77.17 84.89,77.16 84.88,77.15 84.46,76.74 84.45,76.73 84.43,76.72 84.03,76.72 83.94,76.71 83.83,76.67 83.19,76.67 83.17,76.67 83.15,76.68 83.09,76.74 83.09,76.77 83.07,76.92 82.97,77.07 82.99,77.13 82.99,78.14 83,78.16 83.01,78.17 83.04,78.22 83.07,78.28
DGND on L03_SIG01 (solid shape): 41.85,35.09 41.86,35.08 42.58,34.69 43.35,34.93 43.36,34.94 43.39,34.94 43.49,34.9 43.51,34.88 43.52,34.85 43.52,32.93 43.51,32.91 43.5,32.9 41.61,31 41.59,30.99 41.59,30.97 41.59,28.1 41.59,28.08 41.58,28.07 41.37,27.87 41.36,27.86 41.34,27.85 41.29,27.85 41.25,27.87 41.24,27.9 41.24,27.93 41.03,28.43 40.58,28.13 40.57,28.09 40.56,28.06 40.53,28.03 40.49,28.02 40.45,28.03 40.41,28.14 40.34,28.25 40.33,28.28 40.33,31.4 40.34,31.42 40.35,31.43 41.67,32.75 41.68,32.77 41.68,32.79 41.68,35.01 41.69,35.04 41.72,35.06 41.82,35.1
DGND on L03_SIG01 (solid shape): 58.89,83.25 60.95,81.19 60.97,81.15 60.97,78.35 60.92,78.27 60.89,78.22 60.87,78.17 60.86,78.11 60.85,78.06 60.86,78 60.87,77.95 60.9,77.9 60.92,77.86 60.92,77.83 60.85,77.72 60.64,77.7 59.71,76.78 59.7,76.75 59.7,75.72 59.59,75.62 59.57,75.62 59.53,75.64 59.48,75.65 59.27,75.81 59.27,78.33 59.76,78.33 59.76,78.28 59.77,78.23 59.79,78.18 59.81,78.13 59.84,78.09 59.88,78.05 59.92,78.01 59.96,77.99 60.01,77.97 60.07,77.96 60.12,77.95 60.17,77.96 60.22,77.97 60.27,77.99 60.32,78.01 60.36,78.05 60.4,78.09 60.43,78.13 60.45,78.18 60.47,78.23 60.47,78.28 60.47,78.33 60.47,78.39 60.45,78.44 60.43,78.49 60.4,78.53 60.36,78.57 60.32,78.6 60.27,78.63 60.22,78.65 60.17,78.66 60.12,78.66 60.07,78.66 60.01,78.65 59.96,78.63 59.92,78.6 59.88,78.57 59.84,78.53 59.81,78.49 59.79,78.44 59.77,78.39 59.76,78.33 59.27,78.33 59.27,82.38 59.26,82.42 58.83,82.84 58.82,82.88 58.82,83.2 58.83,83.23 58.86,83.25
DGND on L03_SIG01 (solid shape): 69.93,64.57 69.96,64.55 70.53,63.98 70.54,63.96 70.54,63.93 70.53,63.91 70.51,63.9 70.36,63.9 70.34,63.89 70.32,63.88 70.03,63.59 70.02,63.57 70.01,63.52 69.99,63.5 69.96,63.49 69.93,63.48 69.91,63.49 69.68,63.56 69.46,63.45 69.44,63.44 69.42,63.43 69.35,63.43 69.32,63.44 69.21,63.53 69.08,63.56 69.05,63.58 69.03,63.61 69.05,63.65 69.1,63.7 69.12,63.71 69.22,63.74 69.32,63.83 69.35,63.83 69.42,63.83 69.44,63.83 69.46,63.81 70,63.87 69.77,64.36 69.75,64.36 69.7,64.41 69.68,64.45 69.7,64.49 69.82,64.52 69.9,64.56
DGND on L03_SIG01 (solid shape): 74.39,81.73 74.42,81.71 74.44,81.67 74.43,81.56 74.46,81.45 74.47,81.44 74.46,81.4 74.15,81.09 74.11,81.08 74.1,81.09 73.68,80.97 73.74,80.54 73.76,80.51 73.76,80.43 73.76,80.41 73.73,80.38 73.71,80.38 72.94,80.38 72.92,80.37 72.9,80.36 72.65,80.1 72.63,80.09 72.61,80.09 71.85,80.09 71.82,80.1 71.81,80.12 71.8,80.13 71.81,80.16 72.15,80.51 72.18,80.51 72.2,80.5 72.55,80.52 72.68,80.85 72.68,80.86 72.69,80.88 72.75,80.95 72.76,80.96 72.78,80.97 73.39,80.97 73.41,80.97 73.42,80.98 73.75,81.31 73.78,81.31 73.8,81.3 74.16,81.33 74.28,81.67 74.29,81.71 74.33,81.73
DGND on L03_SIG01 (solid shape): 76.14,141.17 76.73,140.57 76.74,140.56 76.75,140.54 76.75,138.12 76.75,138.1 76.76,138.08 77.08,137.76 77.1,137.74 77.1,137.71 77.07,137.62 77.05,137.6 77.04,137.59 76.8,137.12 77.3,136.93 77.31,136.94 77.33,136.94 77.42,136.89 77.44,136.87 77.44,136.84 77.44,128.18 77.45,128.16 77.46,128.14 82.83,122.78 82.84,122.76 82.84,122.74 82.84,122.72 82.84,122.69 82.82,122.68 82.76,122.62 82.73,122.61 82.33,122.24 82.78,121.92 82.83,121.9 82.84,121.87 82.84,121.82 82.84,121.8 82.83,121.79 82.2,121.16 82.18,121.15 82.15,121.15 82.13,121.16 82.12,121.18 82.12,123.08 82.11,123.1 82.1,123.12 76.08,129.14 76.07,129.16 76.06,129.18 76.06,141.12 76.07,141.15 76.09,141.17 76.11,141.17
DGND on L03_SIG01 (solid shape): 67.93,72.93 67.95,72.92 67.96,72.91 68.02,72.85 68.03,72.82 68.33,72.46 68.69,72.77 68.7,72.8 68.74,72.82 68.78,72.8 68.83,72.75 68.86,72.66 68.85,72.63 68.52,72.3 68.49,72.3 68.48,72.3 68.12,72.23 68.05,71.87 68.06,71.86 68.05,71.83 67.72,71.5 67.69,71.49 67.68,71.5 67.58,71.52 67.44,71.53 67.42,71.56 67.42,71.62 67.44,71.66 67.49,71.67 67.89,71.97 67.53,72.32 67.5,72.33 67.44,72.39 67.43,72.4 67.42,72.42 67.42,72.85 67.43,72.87 67.44,72.88 67.47,72.91 67.49,72.92 67.51,72.93
DGND on L03_SIG01 (solid shape): 70.09,76.47 70.44,76.13 70.45,76.1 70.44,76.09 70.43,76 70.42,75.87 70.39,75.86 70.36,75.86 70.26,75.84 70.17,75.78 70.07,75.67 70.01,75.59 69.99,75.49 69.99,75.23 69.99,75.21 70,75.19 70.25,74.94 70.27,74.93 70.29,74.93 70.54,74.93 70.57,74.92 70.62,74.88 70.67,74.87 70.75,74.86 70.88,74.86 70.89,74.82 70.89,74.76 70.88,74.73 70.83,74.71 70.58,74.67 70.43,74.45 70.43,74.43 70.11,74.12 70.1,74.1 70.09,74.08 70.09,74.02 70.09,74 70.08,73.99 70.02,73.93 69.98,73.92 69.76,73.86 69.63,73.65 69.63,73.63 69.31,73.32 69.3,73.3 69.29,73.28 69.29,73.16 69.28,73.13 69.2,73.13 68.88,73.44 68.87,73.45 68.85,73.46 67.99,73.46 67.97,73.46 67.95,73.47 67.89,73.54 67.89,73.61 67.88,73.66 67.89,73.68 67.94,73.75 67.96,73.77 67.98,73.77 69.44,73.77 69.46,73.78 69.48,73.79 69.78,74.08 69.79,74.1 69.79,74.12 69.79,76.37 69.8,76.39 69.81,76.4 69.88,76.46 69.9,76.47 69.98,76.46 70.05,76.48 70.07,76.48
DGND on L03_SIG01 (solid shape): outline of 132 points within 86.89,85.17 100.36,95.57
DGND on L03_SIG01 (solid shape): outline of 85 points within 100.32,71.49 101.63,81.31
DGND on L03_SIG01 (solid shape): outline of 128 points within 44.26,42.94 53.08,52.84
DGND on L03_SIG01 (solid shape): 58.08,107.07 58.12,107.09 58.15,107.07 58.62,106.6 58.63,106.59 58.63,106.57 58.63,102.63 58.64,102.61 58.65,102.6 62.41,98.84 62.42,98.82 62.42,98.8 62.42,97.71 62.43,97.69 62.44,97.67 63,97.11 63.01,97.1 63.01,97.08 63.01,95.28 63,95.25 62.93,95.13 62.9,95.03 62.89,94.99 62.88,94.96 62.39,94.48 62.38,94.46 62.38,94.44 62.38,89.97 62.37,89.95 62.35,89.93 62.33,89.92 62.3,89.93 61.7,90.53 61.69,90.55 61.69,90.56 61.69,94.18 61.69,94.2 61.71,94.22 61.77,94.28 61.8,94.28 61.81,94.28 62.22,94.63 61.81,94.98 61.8,94.98 61.77,94.99 61.71,95.05 61.69,95.06 61.69,95.08 61.69,97.78 61.71,97.81 61.73,97.81 62,98.23 61.59,98.51 61.57,98.51 61.55,98.52 61.48,98.57 61.47,98.59 61.46,98.61 61.46,99.25 61.46,99.27 61.45,99.28 58.05,102.69 58.04,102.7 58.03,102.72 58.03,105.99 58.04,106.01 58.05,106.03 58.11,106.08 58.14,106.09 58.5,106.42 58.14,106.75 58.11,106.76 58.05,106.81 58.04,106.83 58.03,106.85 58.03,107 58.04,107.02 58.05,107.04
DGND on L03_SIG01 (solid shape): 79.94,86.43 79.98,86.44 80.01,86.43 80.03,86.39 80.07,86.24 80.17,86.12 80.18,86.11 80.19,86.09 80.2,86 80.2,85.98 80.19,85.96 80.13,85.9 80.12,85.89 80.12,85.87 80.12,85.83 80.1,85.8 80.07,85.43 80.4,85.26 80.41,85.27 80.43,85.26 80.5,85.2 80.51,85.18 80.5,85.12 80.46,85.11 80.45,85.11 80.15,85.05 80.03,84.76 80.02,84.73 79.96,84.67 79.95,84.66 79.93,84.65 79.19,84.65 79.17,84.66 79.15,84.67 79.09,84.73 79.09,84.76 79.01,85 78.79,85.12 78.76,85.14 78.72,85.17 78.7,85.21 78.72,85.25 78.75,85.26 78.98,85.34 79.09,85.56 79.1,85.59 79.14,85.63 79.18,85.65 79.21,85.63 79.23,85.6 79.82,85.39 79.48,85.91 79.43,85.93 79.42,85.96 79.42,86.02 79.43,86.06 79.48,86.07 79.75,86.12 79.89,86.36 79.9,86.39
DGND on L03_SIG01 (solid shape): 71.19,78.55 71.23,78.54 71.24,78.5 71.24,78.49 71.53,78.06 71.89,78.44 71.88,78.45 71.89,78.47 71.95,78.54 71.97,78.55 71.99,78.55 72.03,78.54 72.04,78.5 72.04,78.49 72.06,78.26 72.22,78.09 72.23,78.09 72.25,78.06 72.25,77.92 72.23,77.9 72.22,77.89 72.03,77.59 72.22,77.29 72.23,77.29 72.25,77.26 72.25,77.12 72.23,77.1 72.22,77.09 72.1,77 72.04,76.87 72.03,76.85 71.97,76.79 71.94,76.78 71.9,76.79 71.89,76.83 71.51,77.12 71.23,76.73 71.22,76.69 71.18,76.67 71.13,76.67 71.1,76.69 71.08,76.73 70.99,77.03 70.68,77.11 70.63,77.13 70.62,77.16 70.62,77.22 70.63,77.26 70.68,77.27 71.09,77.6 70.66,77.91 70.65,77.9 70.62,77.91 70.28,78.25 70.27,78.28 70.3,78.4 70.34,78.44 70.38,78.46 70.41,78.44 70.43,78.4 70.78,78.06 71.09,78.44 71.08,78.45 71.09,78.47 71.15,78.54 71.17,78.55
DGND on L03_SIG01 (solid shape): outline of 88 points within 75.98,83.01 80.5,84.17
DGND on L03_SIG01 (solid shape): outline of 229 points within 61.86,32.9 72.85,40.09
DGND on L03_SIG01 (solid shape): outline of 234 points within 56.68,34.05 63.71,47.41
DGND on L03_SIG01 (solid shape): outline of 217 points within 31.14,59.12 33.25,88.81
DGND on L03_SIG01 (solid shape): outline of 247 points within 100.24,78.82 108.6,96.53
DGND on L03_SIG01 (solid shape): outline of 266 points within 101.15,85.49 109.19,98.45
DGND on TOP: 30.62,23.42 30.62,22.74 30.58,22.71 30.58,22.06 30.5,21.97 27.97,21.97 27.4,22.55 27.12,22.55 27.01,22.43 27.01,21.13 27.08,21.05 29.26,21.05 29.39,20.92 31.03,20.92 31.08,20.97 31.08,21.61 31.7,22.23 32.43,22.23 32.43,24.26 31.87,24.81 29.71,24.81 29.62,24.72 29.62,23.69 29.77,23.54 30.5,23.54
DGND on TOP: 18.12,153.71 18.12,152.7 19.42,152.7 19.42,153.71
DGND on TOP: 123.94,63.44 123.94,61.11 122.79,61.11 122.79,63.44
DGND on TOP: 53.27,30.43 53.27,26.79 56.46,26.79 56.46,30.43
DGND on TOP: 15.67,146.91 15.67,148.89 15.76,148.98 16.54,148.98 16.66,148.86 16.66,147.07 16.5,146.91
DGND on TOP: 24.03,61.2 22.34,61.2 22.01,60.87 20.86,60.87 20.82,60.83 20.82,60.28 20.72,60.18 20.2,60.18 20.11,60.28 20.11,61.42 20.22,61.53 23.98,61.53 24.03,61.49
DGND on TOP: 20.08,36.48 19.04,36.48 18.86,36.29 18.86,33.08 18.8,32.87 19.14,32.54 19.14,31.88 19.18,31.84 20.07,31.84 20.21,31.97 20.21,36.35
DGND on TOP: 93.16,45.41 92.09,45.41 92.09,43.52 93.16,43.52
